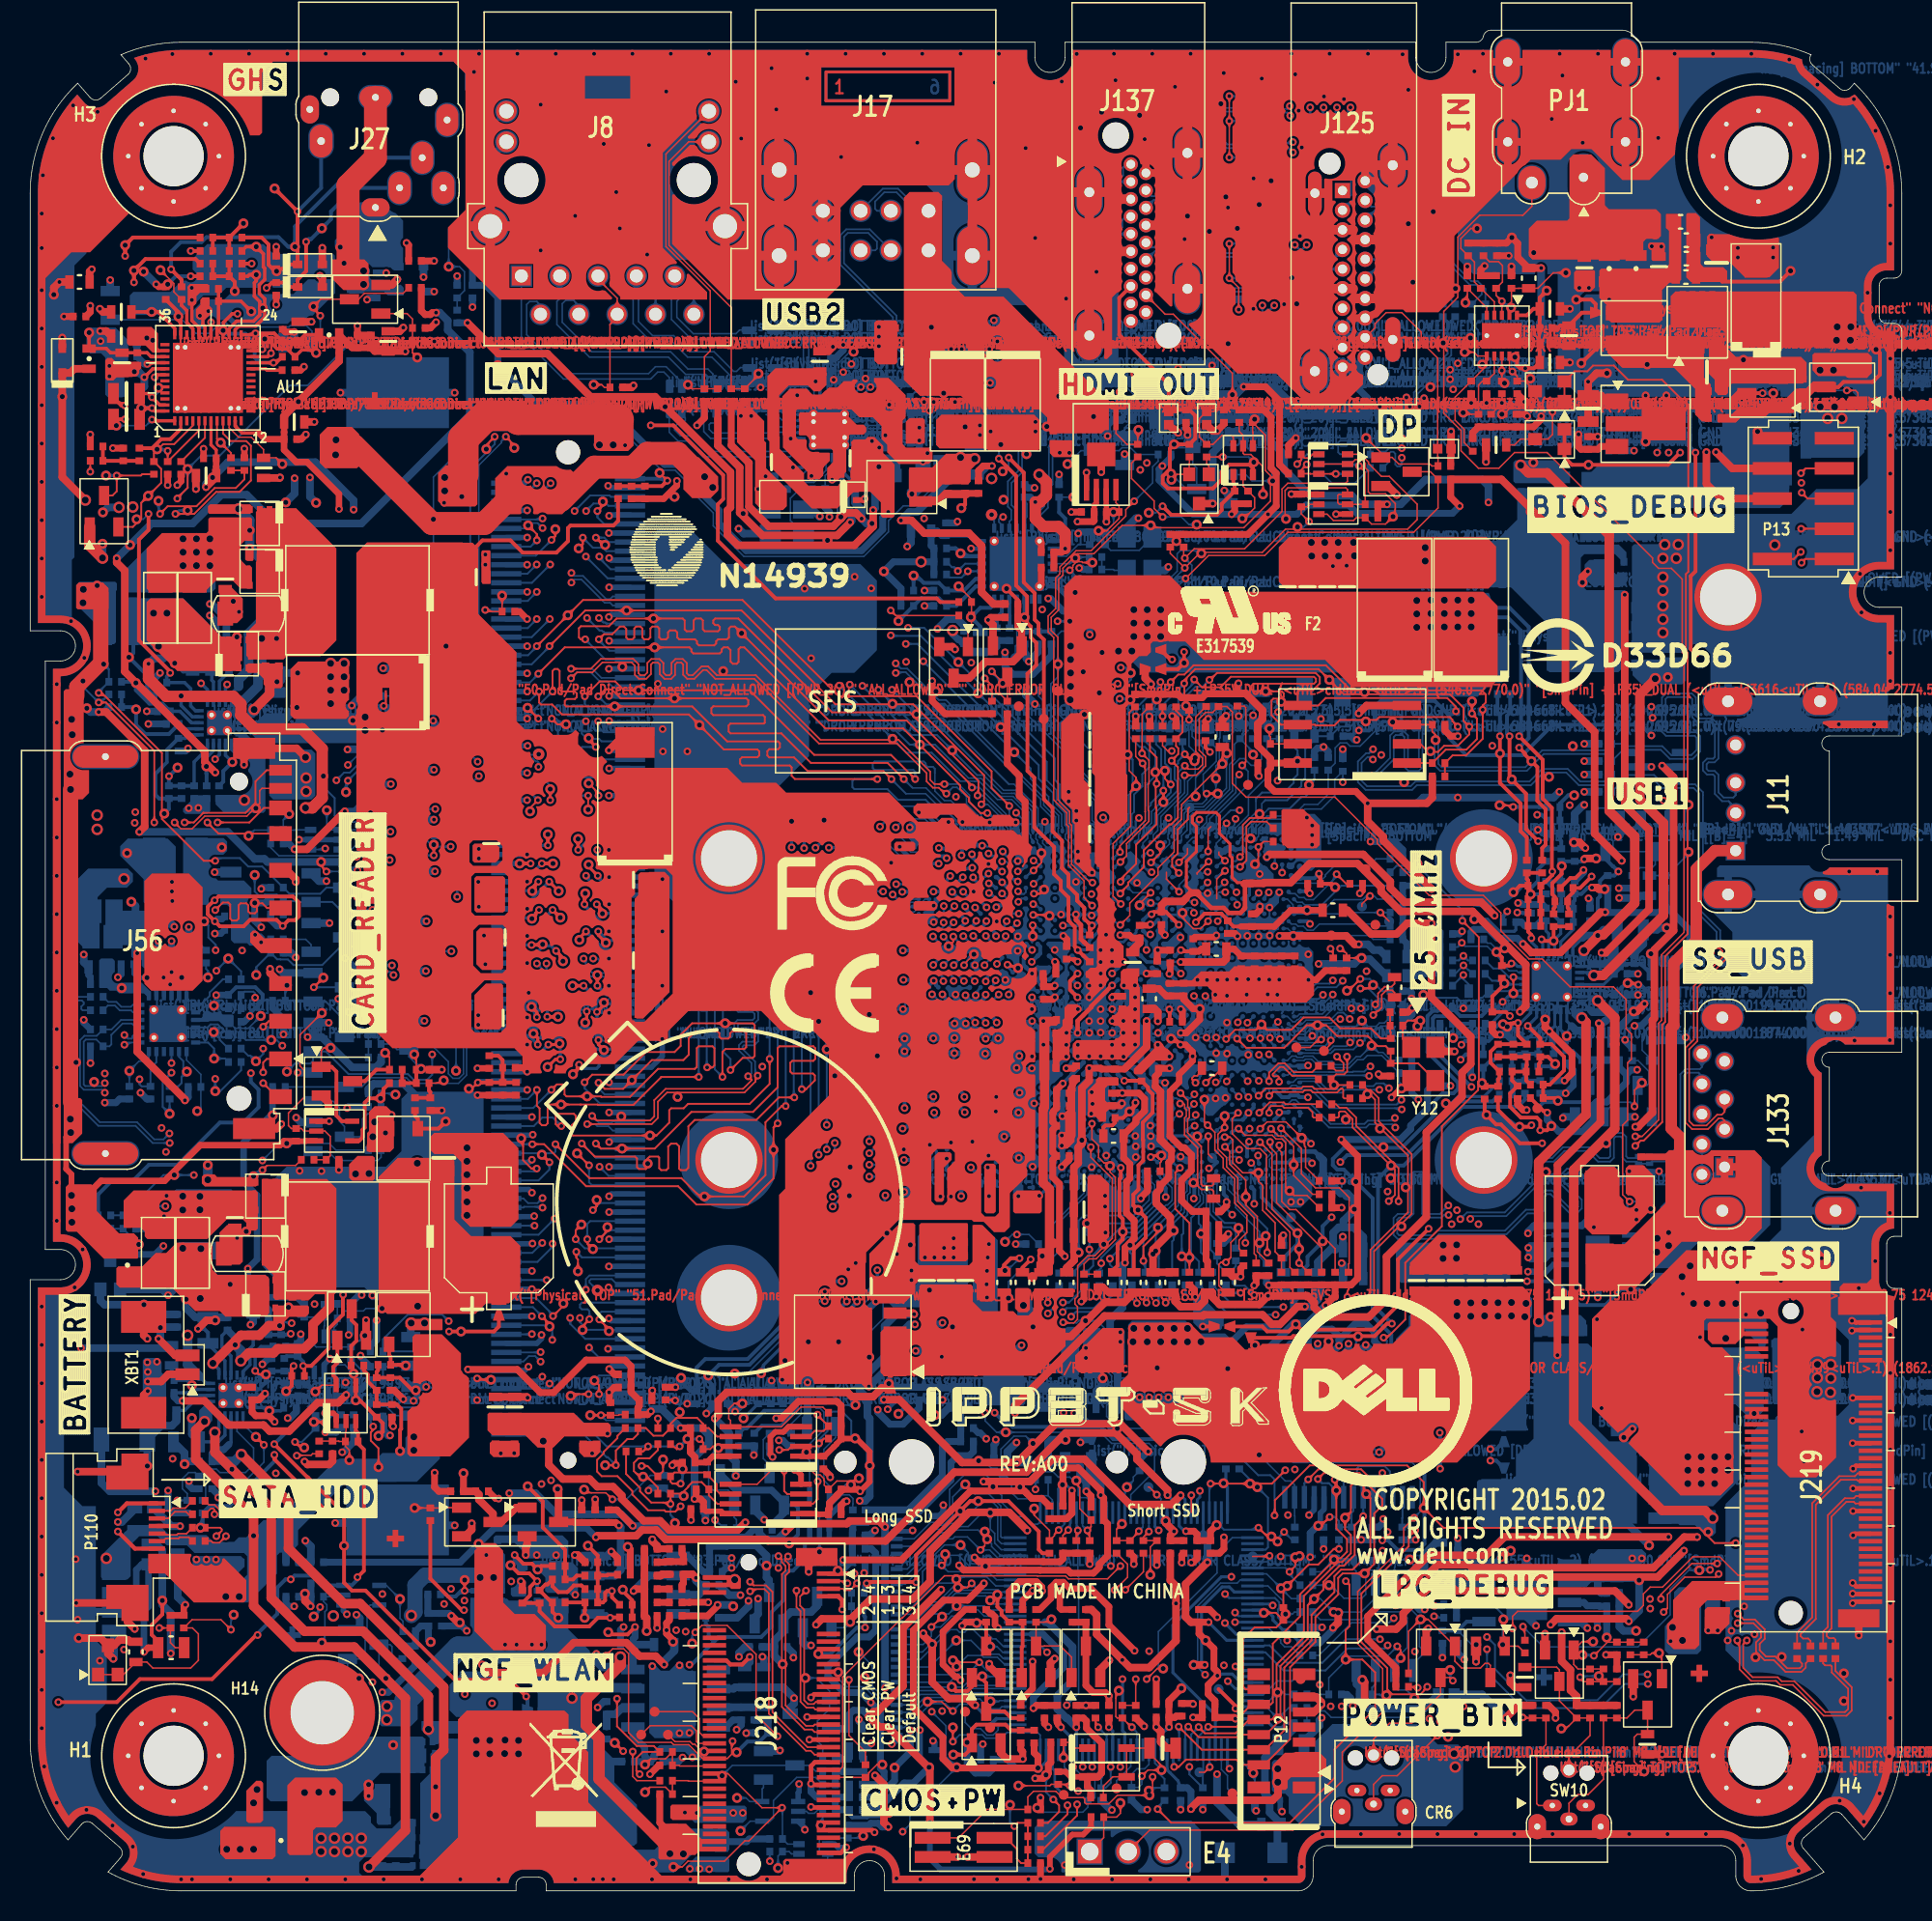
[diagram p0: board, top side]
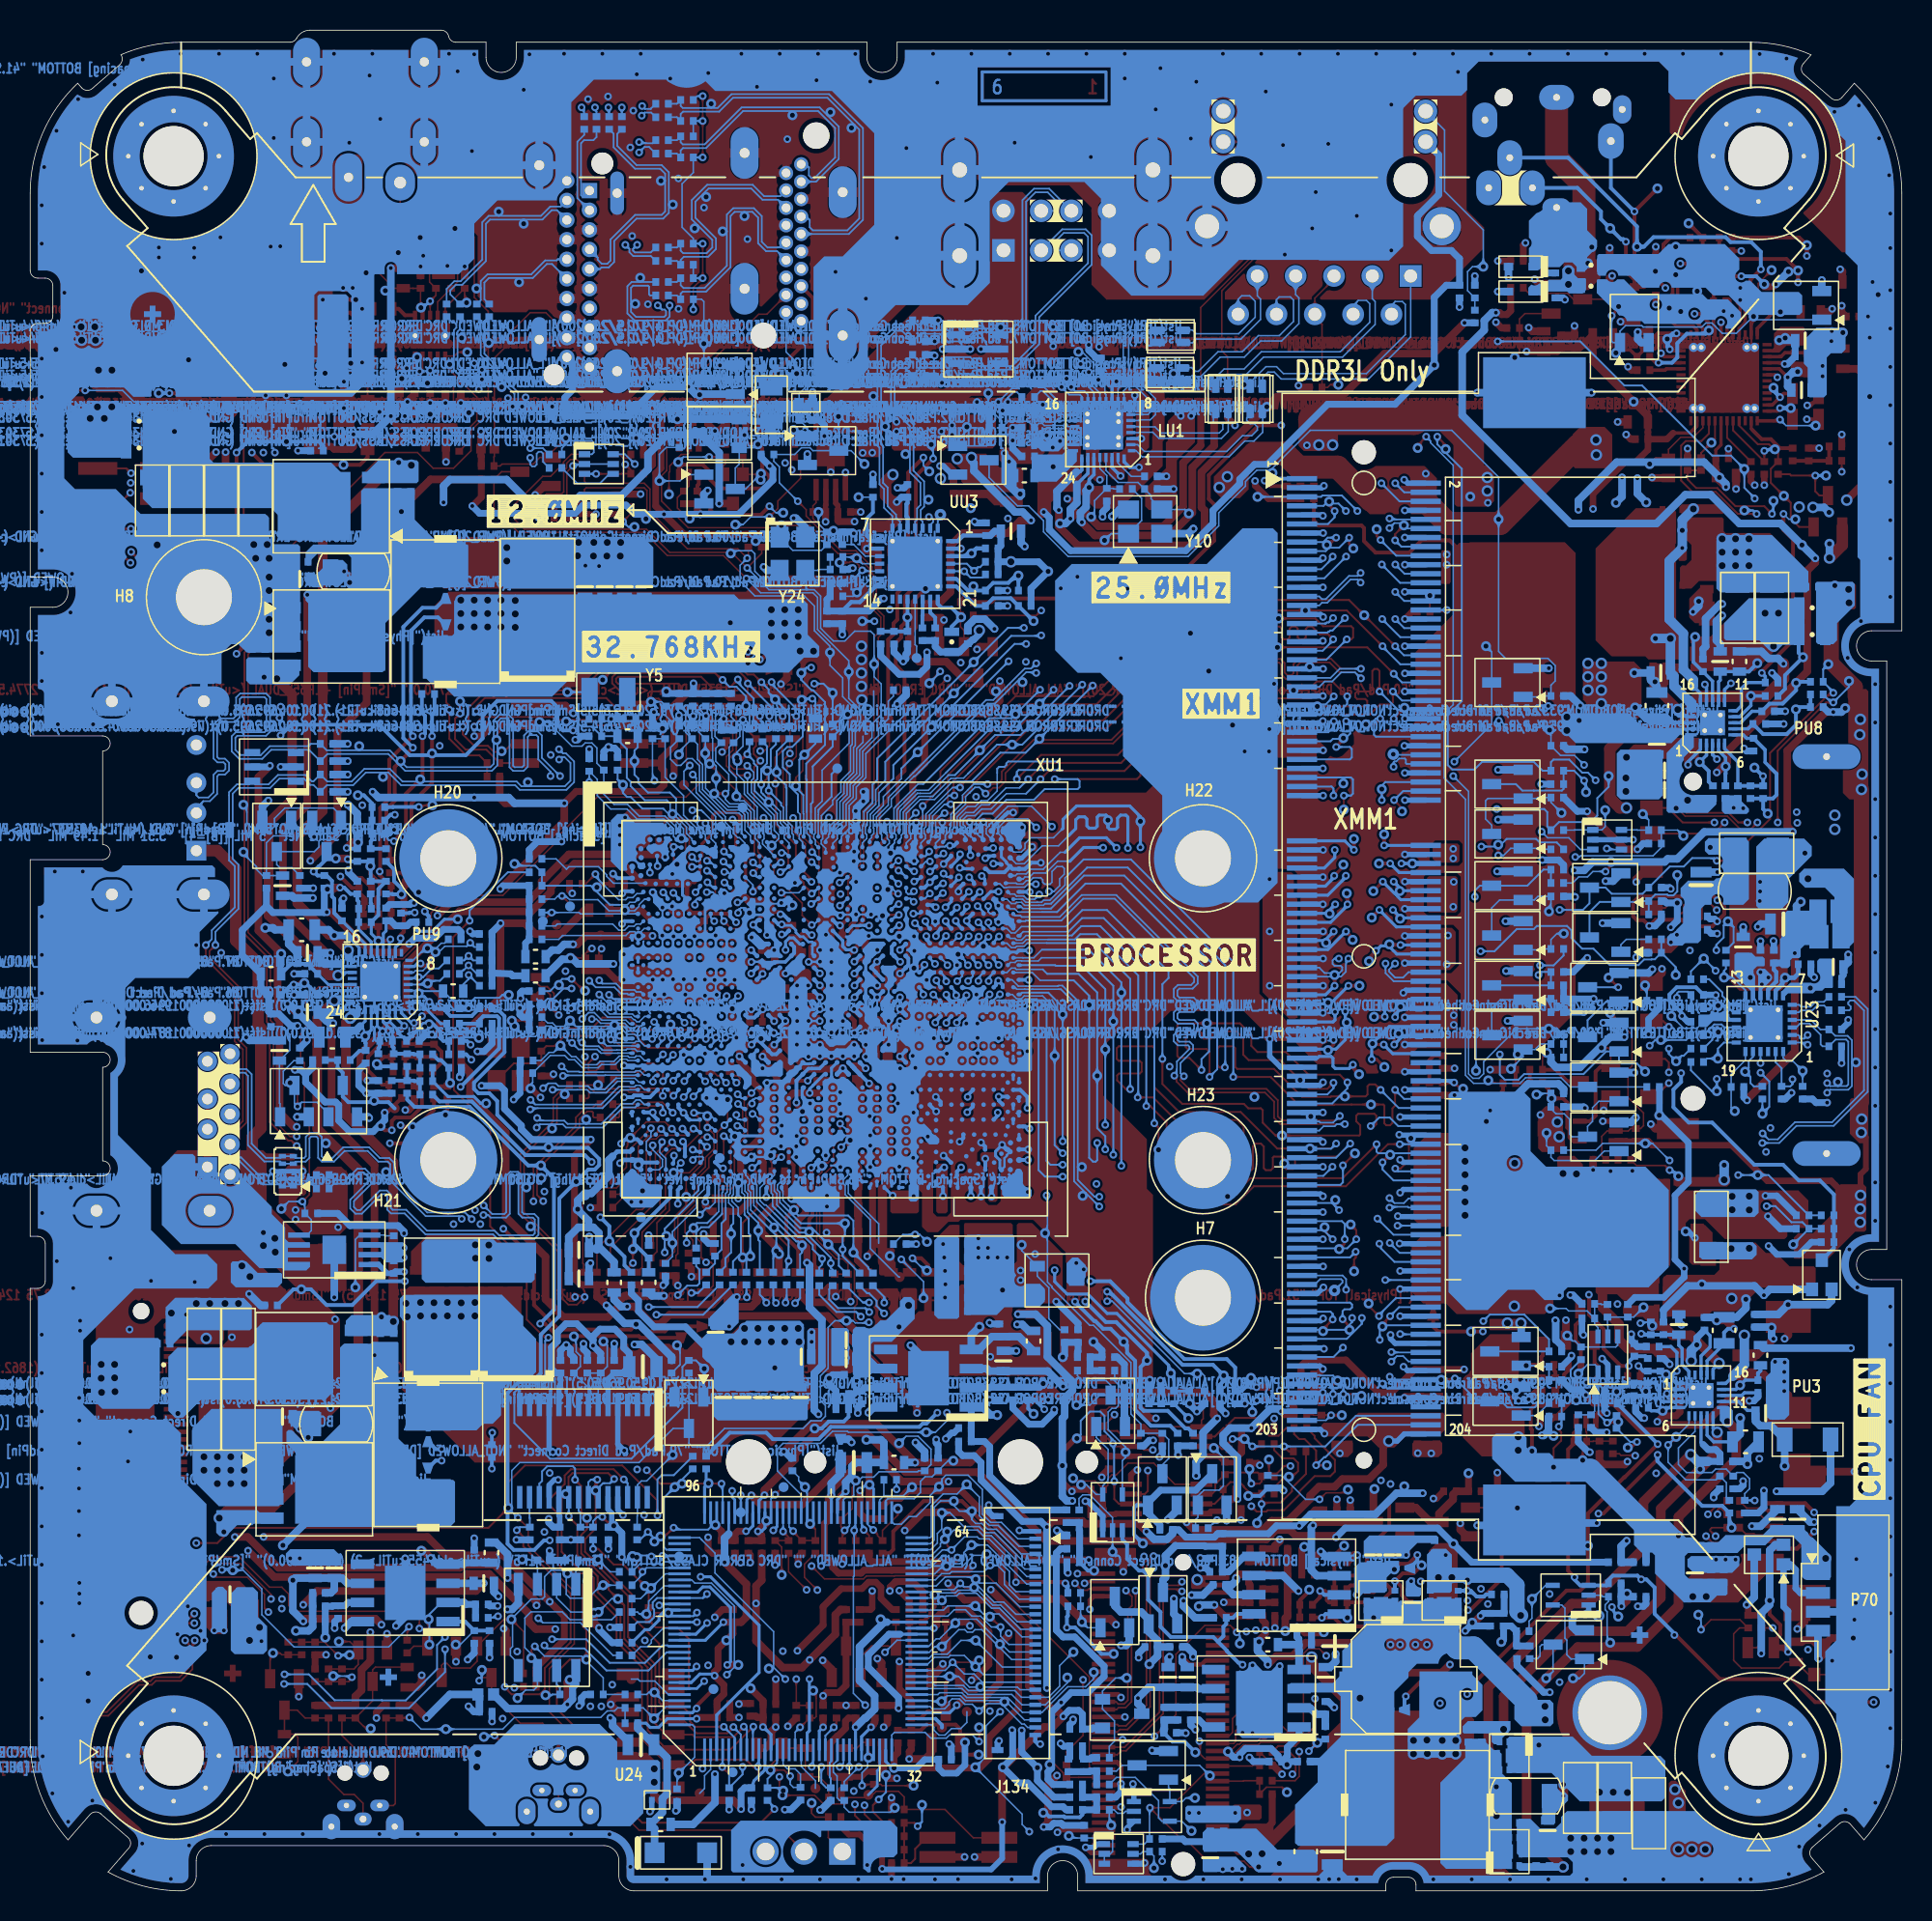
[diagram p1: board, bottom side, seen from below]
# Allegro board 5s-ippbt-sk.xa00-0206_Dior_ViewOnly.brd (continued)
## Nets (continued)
HDMI_POWER: J137.18 MCB1.1 VF1.1
HDMI_RT: MQ36.3 MR6.2 MR7.2 MR8.2 MR9.2 MR10.2 MR11.2 MR12.2 MR13.2
HDMI_TMDS_CLK_N: J137.12 M1C8.2 MR13.1
HDMI_TMDS_CLK_P: J137.10 M1C7.2 MR12.1
HDMI_TMDS_DATA0_N: J137.9 M1C2.2 MR7.1
HDMI_TMDS_DATA0_P: J137.7 M1C1.2 MR6.1
HDMI_TMDS_DATA1_N: J137.6 M1C4.2 MR9.1
HDMI_TMDS_DATA1_P: J137.4 M1C3.2 MR8.1
HDMI_TMDS_DATA2_N: J137.3 M1C6.2 MR11.1
HDMI_TMDS_DATA2_P: J137.1 M1C5.2 MR10.1
HDMI_TXN0: M1C2.1 XU1.AD2
HDMI_TXN1: M1C4.1 XU1.AF2
HDMI_TXN2: M1C6.1 XU1.AG1
HDMI_TXP0: M1C1.1 XU1.AD3
HDMI_TXP1: M1C3.1 XU1.AF3
HDMI_TXP2: M1C5.1 XU1.AG3
HOLD#: F3R3.2 F3U1.7
HPOUT1_JD: AR3.2 J27.4
HPOUT1_L: AU1.26 HR1.1
HPOUT1_R: AU1.27 HR2.1
HUB_RESET: DEC4.1 R18.1 R21.2 UU3.17
ICLK_DRAM_TERMN1: SR7.1 XU1.AF42
ICLK_DRAM_TERMN2: SR8.1 XU1.AH42
ICLK_ICOMP: SR32.2 XU1.AD14
ICLK_OSCIN: SC3.1 SR30.2 SR31.1 XU1.AH12
ICLK_OSCOUT: SC1.1 SR30.1 XU1.AH10 Y12.3
ICLK_RCOMP: SR33.2 XU1.AD13
ICLK_SATA_TERMN: SR79.2 XU1.BC10
ICLK_SATA_TERMP: SR80.2 XU1.BB10
ICLK_USB_TERMN1: SR96.1 XU1.D10
ICLK_USB_TERMN2: SR97.1 XU1.F10
ICLK_V1P35_S3: C62.1 C63.1 SL14.1 XU1.AG18 XU1.AJ19
ILIM: PR17.2 PR22.1 PU2.3
INTRUDER#: C149.1 E69.1 R250.1
INTRUDER#_S: R250.2 SR196.2 XU1.J24
JDREF: AR38.1 AU1.35
KSI0: J134.8 U24.58
KSI1: J134.7 U24.59
KSI2: J134.6 U24.60
KSI3: J134.5 U24.61
KSI4: J134.4 U24.62
KSI5: J134.3 U24.63
KSI6: J134.2 U24.64
KSI7: J134.1 U24.65
KSO0: J134.26 U24.36
KSO1: J134.25 U24.37
KSO2: J134.24 U24.38
KSO3: J134.23 U24.39
KSO4: J134.22 U24.40
KSO5: J134.21 U24.41
KSO6: J134.20 U24.42
KSO7: J134.19 U24.43
KSO8: J134.18 U24.44
KSO9: J134.17 U24.45
KSO10: J134.16 U24.46
KSO11: J134.15 U24.51
KSO12: J134.14 U24.52
KSO13: J134.13 U24.53
KSO14: J134.12 U24.54
KSO15: J134.11 U24.55
KSO16: J134.10 U24.56
KSO17: J134.9 U24.57
LAD0: P12.2 SR100.2 TPU1.26 U24.10
LAD1: P12.4 SR101.2 TPU1.23 U24.9
LAD2: P12.6 SR103.2 TPU1.20 U24.8
LAD3: P12.8 SR102.2 TPU1.17 U24.7
LAN_ACT#_R: J8.11 LANC1.1 LR62.1
LAN_ACTLED3#: LR62.2 LU1.25
LAN_CLKREQ: LU1.12 R93.1
LAN_HSON: C162.1 LU1.18
LAN_HSOP: C161.1 LU1.17
LAN_ISOLATEB: LU1.20 R95.1 R97.2
LAN_LED0_C: J8.13 LANC4.1 LR85.2
LAN_LED1_C: J8.14 LANC3.1 LR87.2
LAN_LINKLED0#: LR85.1 LU1.27
LAN_LINKLED1#: LR87.1 LU1.26
LAN_MDI0_N: LL10.4 LRN11.4 LU1.2
LAN_MDI0_N_C: J8.2 LL10.3 LRN11.3
LAN_MDI0_P: LL10.1 LRN11.2 LU1.1
LAN_MDI0_P_C: J8.1 LL10.2 LRN11.1
LAN_MDI1_N: LL11.4 LRN12.4 LU1.5
LAN_MDI1_N_C: J8.4 LL11.3 LRN12.3
LAN_MDI1_P: LL11.1 LRN12.2 LU1.4
LAN_MDI1_P_C: J8.3 LL11.2 LRN12.1
LAN_MDI2_N: LL12.4 LRN13.4 LU1.7
LAN_MDI2_N_C: J8.8 LL12.3 LRN13.3
LAN_MDI2_P: LL12.1 LRN13.2 LU1.6
LAN_MDI2_P_C: J8.7 LL12.2 LRN13.1
LAN_MDI3_N: LL13.4 LRN14.4 LU1.10
LAN_MDI3_N_C: J8.10 LL13.3 LRN14.3
LAN_MDI3_P: LL13.1 LRN14.2 LU1.9
LAN_MDI3_P_C: J8.9 LL13.2 LRN14.1
LAN_REGOUT: C160.1 LU1.24 R92.2
LAN_REGOUT_R: C155.1 C156.1 C157.1 C158.1 C159.1 LU1.3 LU1.8 LU1.22 LU1.30 R92.1
LAN_RXN3: C162.2 XU1.AP7
LAN_RXP3: C161.2 XU1.AP9
LAN_TXN3: C8.2 LU1.14
LAN_TXP3: C9.2 LU1.13
LANWAKE: LQ3.1 LU1.21 R96.1
LDO-CAP: AC60.1 AC61.1 AU1.40
LFRAME#: P12.10 SR104.2 TPU1.22 U24.6
LPC_AD0_R: SR100.1 XU1.BH16
LPC_AD1_R: SR101.1 XU1.BJ17
LPC_AD2_R: SR103.1 XU1.BJ13
LPC_AD3_R: SR102.1 XU1.BG14
LPC_CLK1: R30.1 SR188.2 TPR3.2
LPC_CLK_EC: SR659.1 U24.13
LPC_CLK_TPM: CB2.1 TPR3.1 TPU1.21
LPC_FRAME#_R: SR104.1 XU1.BG17
LPC_RCOMP: SR105.1 XU1.BF18
LPC_V1P8V3P3_S3: C70.1 SL4.2 XU1.AM27 XU1.AN24
LPCCLK0: SR106.2 SR659.2
LPCCLK0_R: SR106.1 XU1.BG15
LPCCLK1_R: SR188.1 XU1.BH14
M_CHA_BA0: XMM1.109 XU1.K47
M_CHA_BA1: XMM1.108 XU1.K44
M_CHA_BA2: XMM1.79 XU1.D52
M_CHA_CAS#: XMM1.115 XU1.M44
M_CHA_CKE0: XMM1.73 XU1.C47
M_CHA_CKE1: XMM1.74 XU1.F44
M_CHA_CLK0: XMM1.101 XU1.M50
M_CHA_CLK0#: XMM1.103 XU1.M48
M_CHA_CLK1: XMM1.102 XU1.P50
M_CHA_CLK1#: XMM1.104 XU1.P48
M_CHA_CS#0: XMM1.114 XU1.P44
M_CHA_CS#1: XMM1.121 XU1.P45
M_CHA_DM0: XMM1.11 XU1.G36
M_CHA_DM1: XMM1.28 XU1.B36
M_CHA_DM2: XMM1.63 XU1.F38
M_CHA_DM3: XMM1.46 XU1.B42
M_CHA_DM4: XMM1.136 XU1.P51
M_CHA_DM5: XMM1.153 XU1.V42
M_CHA_DM6: XMM1.170 XU1.Y50
M_CHA_DM7: XMM1.187 XU1.Y52
M_CHA_DQ0: XMM1.5 XU1.M36
M_CHA_DQ1: XMM1.7 XU1.J36
M_CHA_DQ2: XMM1.17 XU1.P40
M_CHA_DQ3: XMM1.15 XU1.M40
M_CHA_DQ4: XMM1.4 XU1.P36
M_CHA_DQ5: XMM1.6 XU1.N36
M_CHA_DQ6: XMM1.18 XU1.K40
M_CHA_DQ7: XMM1.16 XU1.K42
M_CHA_DQ8: XMM1.22 XU1.B32
M_CHA_DQ9: XMM1.24 XU1.C32
M_CHA_DQ10: XMM1.35 XU1.C36
M_CHA_DQ11: XMM1.34 XU1.A37
M_CHA_DQ12: XMM1.23 XU1.C33
M_CHA_DQ13: XMM1.21 XU1.A33
M_CHA_DQ14: XMM1.36 XU1.C37
M_CHA_DQ15: XMM1.33 XU1.B38
M_CHA_DQ16: XMM1.56 XU1.F36
M_CHA_DQ17: XMM1.57 XU1.G38
M_CHA_DQ18: XMM1.67 XU1.F42
M_CHA_DQ19: XMM1.70 XU1.J42
M_CHA_DQ20: XMM1.59 XU1.G40
M_CHA_DQ21: XMM1.58 XU1.C38
M_CHA_DQ22: XMM1.68 XU1.G44
M_CHA_DQ23: XMM1.69 XU1.D42
M_CHA_DQ24: XMM1.41 XU1.A41
M_CHA_DQ25: XMM1.42 XU1.C41
M_CHA_DQ26: XMM1.53 XU1.A45
M_CHA_DQ27: XMM1.51 XU1.B46
M_CHA_DQ28: XMM1.39 XU1.C40
M_CHA_DQ29: XMM1.40 XU1.B40
M_CHA_DQ30: XMM1.50 XU1.B48
M_CHA_DQ31: XMM1.52 XU1.B47
M_CHA_DQ32: XMM1.130 XU1.K52
M_CHA_DQ33: XMM1.132 XU1.K51
M_CHA_DQ34: XMM1.143 XU1.T52
M_CHA_DQ35: XMM1.141 XU1.T51
M_CHA_DQ36: XMM1.131 XU1.L51
M_CHA_DQ37: XMM1.129 XU1.L53
M_CHA_DQ38: XMM1.142 XU1.R51
M_CHA_DQ39: XMM1.140 XU1.R53
M_CHA_DQ40: XMM1.147 XU1.T47
M_CHA_DQ41: XMM1.149 XU1.T45
M_CHA_DQ42: XMM1.158 XU1.Y40
M_CHA_DQ43: XMM1.160 XU1.V41
M_CHA_DQ44: XMM1.146 XU1.T48
M_CHA_DQ45: XMM1.148 XU1.T50
M_CHA_DQ46: XMM1.159 XU1.Y42
M_CHA_DQ47: XMM1.157 XU1.AB40
M_CHA_DQ48: XMM1.164 XU1.V45
M_CHA_DQ49: XMM1.166 XU1.V47
M_CHA_DQ50: XMM1.175 XU1.AD48
M_CHA_DQ51: XMM1.177 XU1.AD50
M_CHA_DQ52: XMM1.163 XU1.V48
M_CHA_DQ53: XMM1.165 XU1.V50
M_CHA_DQ54: XMM1.176 XU1.AB44
M_CHA_DQ55: XMM1.174 XU1.Y45
M_CHA_DQ56: XMM1.182 XU1.V52
M_CHA_DQ57: XMM1.181 XU1.W51
M_CHA_DQ58: XMM1.192 XU1.AC53
M_CHA_DQ59: XMM1.194 XU1.AC51
M_CHA_DQ60: XMM1.183 XU1.W53
M_CHA_DQ61: XMM1.180 XU1.Y51
M_CHA_DQ62: XMM1.193 XU1.AD52
M_CHA_DQ63: XMM1.191 XU1.AD51
M_CHA_DQS0: XMM1.12 XU1.J38
M_CHA_DQS0#: XMM1.10 XU1.K38
M_CHA_DQS1: XMM1.29 XU1.C35
M_CHA_DQS1#: XMM1.27 XU1.B34
M_CHA_DQS2: XMM1.64 XU1.D40
M_CHA_DQS2#: XMM1.62 XU1.F40
M_CHA_DQS3: XMM1.47 XU1.B44
M_CHA_DQS3#: XMM1.45 XU1.C43
M_CHA_DQS4: XMM1.137 XU1.N53
M_CHA_DQS4#: XMM1.135 XU1.M52
M_CHA_DQS5: XMM1.154 XU1.T42
M_CHA_DQS5#: XMM1.152 XU1.T44
M_CHA_DQS6: XMM1.171 XU1.Y47
M_CHA_DQS6#: XMM1.169 XU1.Y48
M_CHA_DQS7: XMM1.188 XU1.AB52
M_CHA_DQS7#: XMM1.186 XU1.AA51
M_CHA_MAA0: XMM1.98 XU1.K45
M_CHA_MAA1: XMM1.97 XU1.H47
M_CHA_MAA2: XMM1.96 XU1.L41
M_CHA_MAA3: XMM1.95 XU1.H44
M_CHA_MAA4: XMM1.92 XU1.H50
M_CHA_MAA5: XMM1.91 XU1.G53
M_CHA_MAA6: XMM1.90 XU1.H49
M_CHA_MAA7: XMM1.86 XU1.D50
M_CHA_MAA8: XMM1.89 XU1.G52
M_CHA_MAA9: XMM1.85 XU1.E52
M_CHA_MAA10: XMM1.107 XU1.K48
M_CHA_MAA11: XMM1.84 XU1.E51
M_CHA_MAA12: XMM1.83 XU1.F47
M_CHA_MAA13: XMM1.119 XU1.J51
M_CHA_MAA14: XMM1.80 XU1.B49
M_CHA_MAA15: XMM1.78 XU1.B50
M_CHA_ODT0: XMM1.116 XU1.T41
M_CHA_ODT1: XMM1.120 XU1.P42
M_CHA_RAS#: XMM1.110 XU1.M45
M_CHA_WE#: XMM1.113 XU1.H51
ME_DISABLE#: Q7.1 R7.1 SR49.1
MIC2-L: AC1.1 AU1.47
MIC2-R: AC2.1 AU1.48
MIC2-VREFOL: AU1.1 HR4.2
MIC2-VREFOR: AU1.30 HR3.2
MIC-CAP: AC42.1 AU1.36
MMC1_RCOMP: SR627.1 XU1.AY18
MQ5_B: MQ5.1 SR662.2
MQ5_C: MQ5.3 Q9414.1 SR28.2
MQ7_B: MQ7.1 R60297.2
MQ9_B: MQ9.1 R60298.2
MQ9_G: MQ34.1 MR1.2
MQ10_G: MQ33.1 MQ34.3 MR2.2
MQ23_B: MQ23.1 R60304.2
MQ25_G: MQ25.1 Q9.3 R8.2
MQ31_G: MQ31.1 MQ32.3 SC65.1 SR670.2
MQ32_B: MQ32.1 R60306.2
NGFF_WIFI_RST#_R: J218.52 WC14.1 WR36.1
PCBEEP: AU1.2 C174.2
PCBEEP_C: AC63.2 C174.1 R109.2 SR134.2
PCH_WIFI_RF_KILL#: U24.97 WR35.2
PCIE_CLKREQ0: SR653.2 ST69.1 XU1.BG3
PCIE_CLKREQ2: SR655.2 ST70.1 XU1.BG5
PCIE_CLKREQ3: SR656.2 ST71.1 XU1.BE3
PCIE_RCOMP_N: SR84.2 XU1.AP13
PCIE_RCOMP_P: SR84.1 XU1.AP14
PCIE_RST#: C163.1 C302.2 LU1.19 SR35.2 U23.23
PCIE_TXN1_WLAN: C6.2 XU1.AV4
PCIE_TXN2_CR: SC9.2 XU1.AT6
PCIE_TXN3_LAN: C8.1 XU1.AP4
PCIE_TXP1_WLAN: C7.2 XU1.AV6
PCIE_TXP3_CR: SC10.2 XU1.AT7
PCIE_TXP3_LAN: C9.1 XU1.AP6
PCIE_V1P0_S3: C44.1 C66.1 SL9.1 SL15.2 XU1.AK18 XU1.AM18 XU1.AM21 XU1.AN18 XU1.AN19 XU1.AN21
PCIE_WAKE#: LQ3.3 Q9416.1 R60302.1
PCIE_WAKE#_WLAN: Q3.4 R60309.1 WR84.1
PCU_SMB_ALERT#: SR640.2 XU1.BG11
PCU_SMB_CLK: SR110.2 U3.3 U4.3 XU1.BH10
PCU_SMB_DATA: SR111.2 U3.2 U4.2 XU1.BG12
PDA_TEST1: ST72.1 XU1.BH30
PDA_TEST2: ST73.1 XU1.BG30
PLT_THERMAL_EC: O2R243.1 PRT4.1 U24.70
PLTRST#: CB3.1 Q9414.3 SC24.1 SR29.2 SR35.1 TPU1.16 U24.22 WR36.2
PM_CLKRUN#: SR108.2 U24.93
PM_PWRBTN#: Q2.1 U24.76
PM_PWRBTN#_1P8VSB: C941163.1 Q1.3 SR37.2 XU1.J26
PM_PWRBTN#_G: Q1.1 Q2.3 R4.1
PMC_ACPRESENT: SR641.2 XU1.D20
PMC_BAT_LOW#: SR642.2 XU1.K26
PMC_CORE_PWROK: SC23.1 SR41.1 SR152.2 XU1.B7
PMC_CORE_PWROK_EC: SR152.1 U24.124
PMC_PLTRST#_1P8V: SR662.1 XU1.F20
PMC_RSMRST#: C941162.1 R212.2 SR46.1 XU1.B10
PMC_RSMRST#_EC: R212.1 U24.112
PMC_SUS_STAT#: ST29.1 XU1.G18
PMC_SUSCLK: R2.1 SC27.1 XU1.G24
PMC_WAKE_PCIE#: Q3.3 Q9416.3 SR36.2 XU1.F26
PMU_SLP_S0IX#_1P8V: ST78.1 XU1.F18
PMU_SLP_S3: MQ6.1 MQ7.3 SC7.1 SR65.2
PMU_SLP_S3#_1P8V: R60297.1 SR665.2 XU1.D22
PMU_SLP_S4: MQ8.1 MQ9.3 SC8.1 SR71.2
PMU_SLP_S4#_1P8V: R60298.1 SR664.2 XU1.F22
PQ15_G: PQ17.1 PR91.2
PQ16_2: PQ18.2 PR95.2
PQ16_4: PQ18.4 PR93.1
PQ17_D: PQ19.3 PR94.2
PQ17_G: PQ18.5 PQ19.1
PQ28_G: PQ14.3 PR81.2
PQ31_G: PQ8.1 PR67.2
PQ32_2: PC67.1 PQ11.2 PR76.2 PR80.2
PQ32_4: PQ11.4 PR72.1
PQ33_D: PQ13.3 PR75.2
PQ33_G: PQ11.5 PQ13.1
PQ34_2: PC66.1 PQ10.2 PR74.2 PR77.2
PQ34_4: PQ10.4 PR71.1
PQ35_D: PQ12.3 PR73.2
PQ35_G: PQ10.5 PQ12.1
PQ36_G: PQ20.1 PR100.2
PQ37_2: PQ21.2 PR104.2
PQ37_4: PQ21.4 PR102.1
PQ38_D: PQ22.3 PR103.2
PQ38_G: PQ21.5 PQ22.1
PQ79_G: PQ9.1 PR69.2
PQ710_G: PC136.1 PQ41.1 PR186.2
PQ711_G: PQ32.1 PQ41.3 PR182.2
PQ9546_G: PQ28.1 PR139.2 PR141.2
PQ9550_G: PQ43.1 PQ44.3 PR196.2
PQ9551_G: PC141.1 PQ44.1 PR201.2
PQ9552_D: PQ16.3 PR84.2
PQ9552_G: PQ15.5 PQ16.1
PQ9553_2: PQ15.2 PR86.2
PQ9553_4: PQ15.4 PR83.1
PQ9557_G: PQ25.1 PR131.2
PROCHOT#: PD3.1 PD3.2 R214.2 R60299.1
PROCHOT#_EC: R214.1 U24.99
PROCHOT#_VR: PR192.2 PU9.6 R60226.1
PROCHOT_CPU#: MQ25.3 R9.2 R60226.2 XU1.C24
PROHOT_R#: PC13.1 PD3.3 PR15.2 PU2.9
PU12_ALERT#: PR200.2 PU9.4
PU12_ISEN2: PR233.1 PU9.8
PU12_SCLK: PR198.2 PU9.3
PU12_SDA: PR202.2 PU9.5
PWR_LED: R330.2 R368.2 R370.2 U24.25
PWR_LED#: R332.2 R357.2 R371.2 U24.24
PWR_LED+: CB10.1 Q30.3 R159.2 R160.2 SW10.L1
PWR_LED-: CB12.1 Q31.3 R169.2 R170.2 SW10.L2
PWR_SW#: R216.2 U24.125
PWRBTN#: O2C53.1 O2R132.2 R215.2 R216.1 SW10.1
Q7_E: Q7.2 SR81.2
Q9_B: Q9.1 R60299.2
Q32_B: Q32.1 Q33.3 R182.2
Q32_C: CR6.L2 Q32.3
Q33_B: Q33.1 R184.2
Q39G: Q39.1 R60208.2 R60209.2
Q41_B: Q41.1 SR663.2
Q41_C: Q41.3 Q9415.1 R252.2
R_HPOUT_L: AC3.1 AD1.1 AR6.2 J27.2
R_HPOUT_R: AC4.1 AD2.1 AR7.2 J27.3
REAR_USB_OC#: R244.1 U18.5
REGREF: AC46.1 AU1.10
RESET: PC14.1 PD2.3 PQ3.1 PR16.2 PR21.1
REVISION_ID_0: SR156.1 SR159.1 XU1.C17
REVISION_ID_1: SR157.1 SR158.1 XU1.C16
RING2: AQ2.3 AR36.2 AU1.31 L3.1
RING2_B: AC5.1 AD3.1 J27.6 L3.2
RREF: R200.2 U23.8
RSET: LR2.1 LU1.31
RST_KB#: ST25.1 U24.4
RTC_EXTPAD: SC4.1 XU1.B8
RTCRST#: C240.1 R188.2 SR674.2 XU1.C11
S4_DAUL_PWRGD: R213.1 U24.96
SATA_GP[0]: SR77.2 XU1.BA12
SATA_GP[1]: SR78.2 XU1.AY14
SATA_RCOMP_N: SR76.1 XU1.AT18
SATA_RCOMP_P: SR76.2 XU1.AU18
SATA_RXN0: T1C15.1 XU1.AV16
SATA_RXN0_C: J219.43 SSC22.2
SATA_RXN1: SSC22.1 XU1.BA16
SATA_RXN1_C: P110.5 T1C15.2
SATA_RXP0: T1C14.1 XU1.AU16
SATA_RXP0_C: J219.41 SSC21.2
SATA_RXP1: SSC21.1 XU1.AY16
SATA_RXP1_C: P110.6 T1C14.2
SATA_TXN0: T1C1.1 XU1.BG7
SATA_TXN0_C: J219.47 SSC19.2
SATA_TXN1: SSC19.1 XU1.BF10
SATA_TXN1_C: P110.3 T1C1.2
SATA_TXP0: T1C13.1 XU1.BF6
SATA_TXP0_C: J219.49 SSC20.2
SATA_TXP1: SSC20.1 XU1.BD10
SATA_TXP1_C: P110.2 T1C13.2
SCE#: R221.1 R227.2 U25.1
SCE#_EC: R221.2 U24.101
SCK: R222.1 U25.6
SCK_EC: R222.2 U24.105
SD3_RCOMP: SR626.1 XU1.BF26
SD_CD#: J56.CD U23.21
SDATA_IN_R: AR1.2 AU1.8
SENSE_B: AR3.1 AU1.33
SERIRQ: HC14.1 R60217.2 TPR4.1 U24.5
SERIRQ_A3: R60216.2 U1.3
SERIRQ_B3: R60217.1 U1.4
SERIRQ_PCH: R60216.1 SR107.2
SERIRQ_R: HC13.1 SR107.1 XU1.BG13
SERIRQ_TPM: TPR4.2 TPU1.27
SI: R224.1 U25.5
SI_EC: R224.2 U24.102
SIO_LED1_B: Q30.1 R330.1 R370.1
SIO_LED2_B: Q31.1 R332.1 R371.1
SLEEVE: AQ1.3 AR5.2 AU1.32 L4.1
SLEEVE_B: AC6.1 AD4.1 J27.1 L4.2
SLP_S0IX#: ST79.1 U24.100
SLP_S3#: HC11.1 MQ6.3 PR151.1 SR66.2 U24.107
SLP_S4#: HC12.1 MQ8.3 PR154.1 SR72.2 U24.21
SMB_CLK_M: SR112.2 SR116.1 SR118.1 U3.6 XMM1.202
SMB_CLK_WLAN: SR116.2 SR122.2
SMB_DATA_M: SR114.2 SR115.1 SR117.1 U3.7 XMM1.200
SMB_DATA_WLAN: SR115.2 SR121.2
SML0_CLK_EC: SR118.2 SR120.2 SR122.1 U4.6 U24.110
SML0_CLK_USB: R6.1 U24.115 UU3.25
SML0_DATA_EC: SR117.2 SR119.2 SR121.1 U4.7 U24.111
SML0_DATA_USB: R60310.1 U24.116 UU3.24
SO: R243.1 U25.2
SO_EC: R243.2 U24.103
SOC_RTCX1: SC6.1 SR63.1 SR64.1 XU1.C9
SOC_RTCX2: SC5.1 SR63.2 XU1.A9 Y5.1
SOC_THERMAL: O2R244.1 PRT5.1 U24.72
SP1: J56.P8 R199.1
SP1_L: R199.2 U23.12
SP2: J56.P7 SR151.1
SP2_L: SR151.2 U23.13
SP3: C248.1 J56.P5 SR150.1
SP3_L: SR150.2 U23.14
SP4: J56.P2 SR149.1
SP4_L: SR149.2 U23.16
SP5: J56.P1 SR147.1
SP5_L: SR147.2 U23.17
SP6: J56.P9 SR148.1
SP6_L: SR148.2 U23.18
SP7: J56.WP R197.1
SP7_L: R197.2 U23.20
SPI_CLK: F3U1.6 P13.7 SR54.2
SPI_CLK_R: SR54.1 XU1.C22
SPI_CS#: F3R1.2 P13.1 R153.1 SR48.2
SPI_CS#_HEADER: F3U1.1 P13.2 R153.2
SPI_CS#_R: SR48.1 XU1.C23
SPI_HOLD#: R230.2 U25.7
SPI_MISO: F3U1.2 P13.5 SR50.2
SPI_MISO_R: SR50.1 XU1.B22
SPI_MOSI: F3U1.5 P13.3 SR52.2
SPI_MOSI_R: SR52.1 XU1.A21
SPI_WP#: F3R2.2 F3U1.3
SPKR_C: R109.1 XU1.BH12
SRTCRST#: C1.1 R60214.2 SR673.2 XU1.C12
SUS_PWRGD: PC32.1 PR34.2 PR52.2 PR61.2 PU3.7 R207.2
SUS_PWRGD_EC_C: R207.1 U24.67
SUSB#_PWR: O2R249.2 PR80.1
SUSB_EC#: O2R249.1 R233.1 U24.83
SUSC#_PWR: O2R250.2 PR77.1
SUSC_EC#: O2R250.1 R234.1 U24.82
SUSCLK: J218.50 J219.68 R3.2 SR15.2
SUSPWRDNACK: MQ22.3 SC67.1 SR624.2 U24.95
SUSPWRDNACK_1P8V: R60304.1 SC33.1 SR34.2 XU1.D26
SUSPWRDNACK_MOS: MQ22.1 MQ23.3 SC36.1 SR625.2
SVID_V1P0_S3: C14.1 SL2.1 XU1.V32
U1_OE: SR67.2 SR68.2 U1.5
U1_VCCA: C2.1 R60307.2 U1.1
U1_VCCB: C3.1 R60308.2 SR67.1 U1.6
U2HUB_OVCUR3: R10.1 UU3.20
U2HUB_OVCUR4: R11.1 UU3.19
U2HUB_PSELF: R16.1 R19.2 UU3.22
U2HUB_RREF: R22.1 UU3.8
U3_EN: SR113.2 U3.5
U4_EN: SR109.2 U4.5
U14_EN: U14.4 UR3.2
U18_EN: U18.4 UR7.2
UNCORE_V1P0_S0IX: C37.1 C38.1 C39.1 C40.1 C41.1 SL7.1 XU1.AF21 XU1.AG21 XU1.AN29 XU1.AN30 XU1.V24 XU1.Y22 XU1.Y24
UNCORE_V1P0_S3: C42.1 C43.1 SL8.1 XU1.AF16 XU1.AF18 XU1.G1 XU1.Y18
UNCORE_V1P8_G3: C30.1 SL6.2 XU1.AA18 XU1.U24
USB3_REXT[0]: SR91.1 XU1.M12
USB3_RXN0: J133.5 UU1.5 UU1.6 XU1.E3
USB3_RXP0: J133.6 UU1.4 UU1.7 XU1.D4
USB3_SS_TXN0_C: J133.8 UC2.2 UU1.2 UU1.9
USB3_SS_TXP0_C: J133.9 UC1.2 UU1.1 UU1.10
USB3_TXN0: UC2.1 XU1.K7
USB3_TXP0: UC1.1 XU1.K6
USB_HSIC_RCOMP: SR172.1 XU1.A7
USB_HSIC_V1P2_G3: C941137.1 SL16.2 XU1.V18
USB_OC0#: R244.2 SR95.2 XU1.C20
USB_OC1#: SR94.2 U14.5 UR1.2 XU1.B20
USB_PLL_MON: SR193.1 XU1.M13
USB_RCOMP: SR98.1 XU1.C7 XU1.D6
USB_V1P0_S3: C45.1 C46.1 SL11.1 XU1.M14 XU1.U18 XU1.U19
USBN0: J133.2 UC13.1 UU2.1 XU1.K16
USBN1: J11.2 UC15.1 UU2.3 XU1.G14
USBN3_HUB: UU3.1 XU1.H10
USBN_HUB1: J17.2 U19.3 UC6.1 UU3.3
USBN_HUB2: J17.6 U19.6 UC9.1 UU3.6
USBP0: J133.3 UC12.1 UU2.6 XU1.M16
USBP1: J11.3 UC14.1 UU2.4 XU1.J14
USBP3_HUB: UU3.2 XU1.K10
USBP_HUB1: J17.3 U19.4 UC7.1 UU3.4
USBP_HUB2: J17.7 U19.1 UC8.1 UU3.7
VGA_V1P0_S3: C15.1 SL1.1 XU1.BJ6
VGA_V1P35_S3_F1: C64.1 C65.1 SL13.1 XU1.BD1
VNN_PWRGD: PQ32.3 PR183.2 PR184.1 ST4.1
VNN_PWRGDG: PR184.2 PR190.1 PU9.27
VR_SVID_ALERT#: PR194.2 PR200.1 SR43.2
VR_SVID_ALERT#_R: SR43.1 XU1.B24
VR_SVID_CLK: PR195.2 PR198.1 XU1.C25
VR_SVID_DATA: PR193.2 PR202.1 SR44.2
VR_SVID_DATA_RR: SR44.1 XU1.A25
VREF: AC59.1 AU1.41
VRM_PWRGD: O2R242.2 PQ43.3 PR139.1 PR187.2 PR189.1 PU9.15
VRM_PWRGD_R: O2R242.1 U24.69
VRM_VCCP: PC123.1 PR165.2 PU9.22
VRM_VDD: PC125.1 PR181.2 PU9.21
VRP: AC58.1 AU1.38
VSUS_ON#: PR44.1 U24.19
WIFI_RF_KILL#_R: J218.56 WR34.2 WR35.1
WLAN_PE1_RXN1: J218.43 XU1.AT9
WLAN_PE1_RXP1: J218.41 XU1.AT10
WLAN_PE1_TXN1: C6.1 J218.37
WLAN_PE1_TXP1: C7.1 J218.35
WLAN_WAKE#_R: J218.55 WR84.2
WWAN_WLAN_COEX1_R: J218.48 WT14.1
WWAN_WLAN_COEX2_R: J218.46 WT13.1
WWAN_WLAN_COEX3_R: J218.44 WT12.1
X1: C4.1 R26.1 UU3.10
X1_1: LR1.2 Y10.1
XMM1_SA0: SR123.1 XMM1.197
XMM1_SA1: SR124.1 SR163.1 XMM1.201
XTAL1: LC1.1 LR1.1 LU1.28
XTAL2: LC2.1 LU1.29 Y10.3
Y5_R: SR64.2 Y5.2
Y17_1: SR31.2 Y12.1
N17661737: PC1.2 Q27.1 R90.2 R91.1
N24358231: PC5.2 PQ1.4 PQ2.2 PR11.2 PR14.1
N24358368: PQ2.1 PQ3.3 PR9.2 PR14.2
N27493538: PR70.1 PR71.2 PR73.1 PR78.1
N27848589: R3008.2 U24.79
N31476480: PC6.2 PJP3.2 PR13.2
N31476482: PC6.1 PJP2.2 PR12.2
N31476922: PQ2.3 PR10.2
N31477919: PC17.2 PR23.2 PU2.4
N31477921: PR26.2 PU2.5
N31477928: PC12.2 PR18.2 PU2.2
N31477936: PR19.2 PR24.1 PU2.6
N31477938: PR20.2 PR25.1 PU2.7
N31477967: PR21.2 PU2.8
N31484130: PC78.1 PR110.2 PR247.2 PU6.2
N31491325: FD3.2 FD4.3 FR4.1 P70.4
N31515196: TPR5.1 TPU1.7
N31515268: TPR1.2 TPR2.1 TPU1.6
N31541018: J8.5 J8.6 LC16.1
N31550216: AC56.1 AC57.1 AU1.23 AU1.25 L2.2
N31550234: AC48.1 AC49.1 AU1.39 L1.2
N31550341: AR5.1 AR36.1 AU1.29
N31550370: AU1.4 D1.2 R5.2
N31552500: AR7.1 HR2.2 HR3.1 R15.2
N31552502: AC2.2 R15.1
N31552504: AR6.1 HR1.2 HR4.1 R14.2
N31552506: AC1.2 R14.1
N31552857: AQ1.1 AQ2.1 AQ3.3 AR8.2
N31596067: P12.12 R30.2
N31886144: Q3.1 R2.2
N31886219: Q3.6 R3.1
N31906684: HUBL1.2 UU3.21
N31906694: SM_TP1.1 UU3.18
N31906900: R13.1 UU3.26
N31906916: R17.1 R20.2 UU3.23
N31906975: C5.1 R25.2 Y24.3
N31906994: R26.2 Y24.1
N31907009: R25.1 UU3.11
N31907112: R24.1 UU3.12
N31907116: R23.1 UU3.13
N32036872: OP1R2.2 U23.19
N32037100: OP1R3.2 U23.24
N32037272: O2R251.1 U24.66
N32037461: O2R252.1 U24.73
N32381924: ST85.1 XU1.D14
N32381935: ST86.1 XU1.G12
N32381953: ST87.1 XU1.F14
N32381971: ST88.1 XU1.F12
N32381989: ST89.1 XU1.G16
N32517551: MQ37.5 MR16.2
N32517556: MQ37.2 MR17.2
N33528355: FD5.1 MR18.1
N33528358: FD5.2 MR19.1

Pads without a net: AU1 3 12 13 14 15 16 17 18 19 34 37 43 44 45 46; CR6 1 2; J137 13 14; J218 6 16 17 18 19 20 21 22 23 25 26 27 28 29 30 31 32 34 36 38 40 42 58 59 60 61 62 64 65 66 67 68 70 71 73; J219 5 6 7 8 9 10 11 20 22 23 24 25 26 28 29 30 31 32 34 35 36 37 38 40 42 44 46 48 50 52 53 54 55 56 58 59 60 61 62 63 64 65 66 67 69; NOREF#12 1; NOREF#17 1; NOREF#33 1; NOREF#39 1; NOREF#40 1; NOREF#44 1; P12 5 7 13 14 15 16; P13 9 10; PPID1 1; PU3 19; PU4 5; PU5 5; PU6 5; PU9 9 20; TPU1 1 2 3 8 9 12 13 14 15 28; U23 22; U24 15 29 77 78 81 94 98 117 118 120; UU3 15 16; XMM1 77 122 125 198; XU1 A13 AA22 AB2 AB3 AB7 AB9 AB12 AB13 AB14 AD4 AD6 AD9 AD10 AD12 AD40 AD41 AF4 AF6 AF13 AF14 AF30 AF40 AF41 AF48 AF50 AF51 AF52 AG51 AG53 AH13 AH14 AH40 AH44 AH52 AJ51 AK7 AK9 AK40 AK42 AK45 AK47 AK48 AK50 AK51 AK52 AL51 AL53 AM9 AM10 AM13 AM14 AM41 AM42 AM45 AM47 AM48 AM50 AM52 AP41 AP42 AP44 AP45 AP47 AP48 AP50 AP51 AP52 AR51 AR53 AT13 AT14 AT20 AT22 AT26 AT28 AT32 AT34 AT36 AT40 AT41 AT42 AT44 AT45 AT48 AT50 AT51 AU20 AU22 AU26 AU28 AU32 AU34 AU36 AU53 AV9 AV10 AV20 AV22 AV26 AV28 AV32 AV34 AV36 AV40 AV44 AV45 AV48 AV50 AV52 AW1 AW41 AW51 AW53 AY2 AY3 AY6 AY7 AY20 AY24 AY26 AY28 AY30 AY34 AY38 AY40 AY42 AY44 AY45 AY47 AY48 AY51 AY52 B4 B5 B30 BA1 BA3 BA18 BA20 BA24 BA26 BA28 BA34 BA36 BA38 BA42 BA51 BB3 BB4 BB44 BB47 BB49 BB50 BB51 BC16 BC18 BC24 BC36 BC38 BC40 BC44 BC52 BC53 BD2 BD5 BD12 BD14 BD16 BD18 BD20 BD22 BD26 BD28 BD32 BD34 BD36 BD38 BD40 BD42 BD44 BD47 BE46 BE51 BE52 BF2 BF14 BF22 BF27 BF28 BF32 BF34 BF40 BF42 BF48 BF50 BF52 BG9 BG18 BG21 BG23 BG24 BG25 BG26 BG27 BG28 BG29 BG32 BG33 BG35 BG36 BG37 BG38 BG40 BG41 BG43 BG47 BH4 BH5 BH6 BH7 BH8 BH18 BH22 BH24 BH26 BH28 BH32 BH34 BH36 BH38 BH40 BH42 BH44 BH46 BH47 BH48 BH49 BH50 BJ9 BJ25 BJ29 BJ33 BJ37 BJ41 BJ45 C13 C15 C19 C21 C30 D2 D18 D28 D32 D34 D48 E2 E46 F1 F16 F28 F32 F34 G2 H4 H5 H7 H8 J18 J20 J28 J30 J34 K18 K20 K24 K28 K34 L1 L3 M3 M4 M6 M7 M9 M10 M18 M20 M22 M24 M30 M32 N24 N30 N32 N34 P2 P6 P7 P10 P12 P14 P34 R1 R3 T2 T3 T4 T6 T7 T9 T10 T12 T13 T14 V2 V3 V4 V6 V9 V10 V13 V14 W1 W3 Y2 Y3 Y4 Y6 Y12 Y13

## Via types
v1: diameter 0.508, hole 0.254, TOP to BOTTOM, 2308 vias
v2: diameter 0.66, hole 0.33, TOP to BOTTOM, 761 vias
v3: diameter 0.762, hole 0.457, TOP to BOTTOM, 266 vias
v4: diameter 0.762, hole 0.305, TOP to BOTTOM, 3 vias

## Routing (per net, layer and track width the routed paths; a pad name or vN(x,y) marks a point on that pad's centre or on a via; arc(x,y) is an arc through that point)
3V_EC_GPIO_MOS: length 4.8
  BOTTOM w0.102: ST7.1 61.94,11.16 62.35,10.75 62.96,10.75 63.39,10.32 63.8,10.32 64.13,10.65 64.13,10.84 64.29,11.01 U24.33
5V3V_VIN_C: length 7.3
  BOTTOM w0.222: PU3.12 10.82,32.43 10.23,31.84 9.87,31.84 PC18.1
  BOTTOM w0.508: PC18.1 9.69,31.12 9.39,30.82 8.67,30.82 PR27.2 v2(7.76,28.15)
5V_DUAL_DRI1: length 3.1
  TOP w0.102: v2(27.4,53.7) 27.22,53.53 PR70.2
  TOP w0.254: PR69.1 PC65.1 26.51,52.94 26.42,53.03 PR70.2
5VSB_EN: length 33
  TOP w0.254: v1(20.1,25) 19.78,25 16.2,28.58 16.2,28.89 v1(16.18,28.89)
  IN2 w0.254: v1(17.26,36.92) 17.26,36.85 17.86,36.25 18.17,36.25 19.37,35.06 19.37,33.43 20.72,32.09 20.72,29.72 21.16,29.27 21.16,26.06 v1(20.1,25)
  BOTTOM w0.222: PC40.1 14.78,36.15 14.56,35.94 14.56,34.87 14.1,34.41 PU3.20
  BOTTOM w0.254: v1(16.18,28.89) 16.2,28.89 16.2,28.48 13.23,25.51 11.89,25.51 PR47.1 11.42,24.21 v2(11.28,24.06) ; v1(17.26,36.92) 17.2,36.85 PR44.2 PR41.2 PC40.1
+3V_WLAN: length 32.6
  TOP w0.457: WR34.1 41.71,4.52 42.05,4.17
  TOP w0.762: 43.2,3.23 41.88,3.23 37.69,7.43 37.69,10.14 36.85,10.98 36.85,12.73 39.1,14.99 v3(39.1,15.49)
  IN2 w0.762: v3(39.1,15.49) 39.73,16.13 44.12,16.13 46.31,18.32 46.31,20.25 v3(46.68,20.62)
  BOTTOM w0.457: WR59.1 47.64,3.44 47.46,3.26 46.25,3.26
  vias: v2(41.24,1.81) v3(42.38,2.46) v3(43.27,2.45)
+3VA: length 359.7
  TOP w0.457: AR8.1 25.91,104.71 26.17,104.45 26.51,104.45 26.64,104.58 v1(26.89,104.58) ; v1(15.56,32.95) 15.14,32.53 PC30.1 14.7,31.73 14.95,31.48 15.8,31.48 v1(16.2,31.09) ; R191.1 67.62,8.51 67.45,8.34 67.45,7.78 67.13,7.45 v1(66.58,7.45)
  TOP w0.508: v1(97.76,11.45) 98.6,12.29 O2R132.1 ; v1(56.56,32.55) 57.57,32.55 61.74,28.38 v1(65.37,28.38) 67.94,30.95 72.22,30.95 74.06,29.11 v1(74.07,29.11) ; v1(55.97,7.64) 56.56,7.05 56.56,4.53 v1(56.85,4.23) ; v1(5.73,88.3) 5.73,88.02 6.27,87.49 6.27,80.8 11.57,75.49 11.57,74.79 12.25,74.11 v1(12.26,74.11)
  IN1 w0.508: v1(78.63,7.73) 78.47,7.57 75.56,7.57 74.66,8.47 73.32,8.47 72.84,7.99 72.84,7.96 72.48,7.59 72.45,7.59 72.44,7.59 69.15,7.59 69.14,7.59 68.84,7.59 68.68,7.75 66.89,7.75 66.59,7.45 v1(66.58,7.45) ; v1(55.97,7.64) 53.55,7.64 52.37,6.46 40.05,6.46 35.63,10.88 30.45,10.88 28.8,12.53 v1(28.8,13.04) ; v1(85.44,13.66) 84.37,14.73 84.37,21.62 84.07,21.93 84.07,24.16 v1(83.33,24.9) ; v1(9.14,39.47) 9.14,33.94 8.65,33.46 8.65,28.36 9.19,27.82 11.96,27.82 12.11,27.67 v1(16.27,27.67) 25.82,27.67 26.48,28.33 27.17,28.33 28.16,27.35 33.48,27.35 v1(33.88,26.96)
  IN2 w0.508: v1(16.27,27.67) 16.8,28.2 16.8,30.48 v1(16.2,31.09) ; v1(12.26,74.11) 12.26,73.03 14.11,71.18 14.11,65.61 14.17,65.56 14.17,63.08 15.08,62.16 16.32,62.16 17.44,61.04 17.44,59.29 17.75,58.99 17.75,55.86 18.34,55.27 18.34,50.34 16.07,48.06 16.07,39.4 16.82,38.65 17.98,38.65 18.36,38.26 18.79,38.26 21.2,35.85 21.2,35.24 22.36,34.08 22.36,31.39 22.1,31.14 22.1,30.51 23.45,29.17 23.45,28.13 23.97,27.61 23.97,19.41 23.61,19.06 23.61,17.82 28.4,13.04 v1(28.8,13.04) ; v1(78.63,7.73) 78.77,7.87 78.77,8.46 79.04,8.72 80.17,8.72 81.97,10.53 85.1,13.66 v1(85.44,13.66) 90.78,13.66 91.66,12.79 94.4,12.79 v1(94.96,12.23) ; v1(55.97,7.64) 56.06,7.73 66.3,7.73 v1(66.58,7.45) ; v1(33.88,26.96) 33.88,28.32 35.18,29.63 38.49,29.63 39.73,30.87 39.73,31.27 40.99,32.52 41.46,32.52 42.03,33.09 42.03,33.53 42.99,34.49 55.58,34.49 56.56,33.51 v1(56.56,32.55) ; v1(83.33,24.9) 83.33,25.69 78.54,30.48 75.44,30.48 v1(74.07,29.11)
  BOTTOM w0.222: PU3.3 15.44,32.83 v1(15.56,32.95)
  BOTTOM w0.457: WR62.1 55.56,4.34 55.69,4.47 56.19,4.47 56.43,4.23 v1(56.85,4.23) ; PR41.1 15.79,38.49 ; R3008.1 73.59,28.67 74.03,29.11 v1(74.07,29.11) ; v1(94.96,12.23) 94.61,11.87 C272.1
  BOTTOM w0.508: v1(97.76,11.45) 96.19,13.01 R229.2 94.24,12.91 C272.1 ; v1(26.89,104.58) 27.14,104.58 27.67,104.05 27.67,103.43 29.13,101.96 29.13,97.79 21.95,90.61 16.25,90.61 14.34,92.52 12.67,92.52 10.76,90.61 8.04,90.61 v2(6.62,89.18) v1(5.73,88.3) ; 15.79,38.49 14.19,40.09 9.76,40.09 v1(9.14,39.47) 8.75,39.86 SD1.1 ; R209.1 v1(65.37,28.38) ; R205.1 80.08,4.4 78.63,5.85 v1(78.63,7.73)
+3VA_EC: length 72.4
  TOP w0.381: O2R1.1 68.59,7.9 68.93,7.55 D28.2
  TOP w0.457: v1(79.85,11.4) 79.76,11.49 C262.1 C261.1 78.49,12.59 78.05,13.04 78.05,13.65 v1(78.66,14.26) 78.66,14.51 78.43,14.74 78.43,16.05 v2(77.88,16.6) 77.44,17.04 C263.1 v1(78.07,17.8) ; D28.2 70.04,6.88 70.26,6.66 R192.1 ; v1(69.31,10.84) C264.1 69.78,11.45 69.98,11.25 69.98,10.77 70.51,10.25 70.54,10.25 70.99,9.8 70.99,7.81 70.73,7.55
  TOP w0.508: 70.73,7.55 D28.2 ; C263.1 76.9,17.8 76.55,18.16 76.55,20.33 78,21.78 v1(78,21.76)
  IN1 w0.508: v1(69.31,10.84) 69.58,11.11 70.14,11.11 70.7,11.67 75.45,11.67 76.79,13 77.3,13 78.84,11.46 79.79,11.46 v1(79.85,11.4)
  BOTTOM w0.178: U24.92 77.72,23.65
  BOTTOM w0.203: v1(79.85,11.4) U24.127 81.79,11.4 82.36,10.83 82.92,10.83 83.2,11.11 R215.1 ; v1(78.66,14.26) 78.76,14.37 79.64,14.37 80.2,13.8 U24.121 ; v1(78.07,17.8) 79.27,16.6 U24.114 ; U24.50 67.24,17.8 ; v1(69.31,10.84) 69.32,10.83 U24.26
  BOTTOM w0.508: 77.72,23.65 78,23.38 v1(78,21.76) ; v1(69.31,10.84) 68.7,11.45 68.64,11.45 68.05,12.04 68.05,12.93 69.05,13.93 69.05,16.17 67.42,17.8 67.24,17.8 ; R215.1 83.75,10.77 C260.1 81.81,8.82 81.81,6.44 82.12,6.12 D32.1 82.12,5.19 R205.2 82.63,4.13 D33.2
+3VA_SPI: length 22
  TOP w0.508: v2(88.26,13.98) 88.41,13.83 v1(88.41,12.35)
  IN1 w0.508: v1(89.59,22.54) 89.59,21.15 88.38,19.95 88.38,13.11 88.41,13.08 v1(88.41,12.35)
  BOTTOM w0.457: v1(89.59,22.54) R228.1 R227.1 ; 88.07,12.7 R230.1 88.07,13.47 87.85,13.69 U25.8
  BOTTOM w0.508: R229.1 92.36,12.07 88.69,12.07 v1(88.41,12.35) 88.07,12.7
+3VS_CR: length 16.6
  TOP w0.508: v1(7.09,62.14) 7.09,55.61 10.25,52.44 v1(10.25,52.38)
  BOTTOM w0.279: U23.9 8.86,59.71 8.32,60.25 8.32,60.89 8.48,61.05 C257.1
  BOTTOM w0.457: 7.96,61.49 C257.1 ; v1(10.25,52.38) 10.27,52.38 10.47,52.59 OP1R2.1
  BOTTOM w0.508: PCB1.1 6.98,65.26 v2(6.7,65.54)
+3VSB_VIN:
  vias: v2(24.05,9.66) v3(18.18,6.51) v3(19.12,6.54) v3(20.03,6.54)
+3VSUS: length 54.9
  BOTTOM w0.222: LU1.32 51.53,94.7 51.15,94.32 50.55,94.32 v1(50.54,94.33)
  BOTTOM w0.229: LU1.11 52.33,99.74 v1(52.04,100.02)
  BOTTOM w0.457: v1(56.85,91.37) 56.48,91 56.48,90.21 55.08,88.81 47.44,88.81 45.64,90.61 45.64,91.47 43.87,93.25 43.87,93.54 42.89,94.52 42.03,94.52 38.04,98.51 33.57,98.51 v2(30.98,101.1) 30.98,105.6 30.18,106.4 LC17.1 29.3,108.16 29.84,108.7 31.15,108.7 32.09,109.64 32.09,110.98 32,111.08 32,111.08 30.68,112.4 30.68,115.03 J8.12
  vias: v1(55.77,96.07) v1(56.25,95.64)
+5V: length 374.7
  TOP w0.254: PR216.1 100.26,51.67 100.41,51.67 v1(100.51,51.57)
  TOP w0.432: v1(61.64,13.95) 61.41,14.18 61.29,14.18 60.47,15 60.47,17.17 61.94,18.64 PR169.1
  TOP w0.457: MR24.1 MR25.1 v1(89.9,91.88) ; R176.1 R182.1 90.48,14.78 88.61,16.65 88.61,18.2 v1(89.58,19.16)
  TOP w0.508: v1(98.9,62.75) 99.46,62.19 101.39,62.19 104.05,64.85 v1(104.35,64.85) ; FD5.3 v1(78.35,91.93) ; v1(108.54,23.45) 97.68,23.45 96.46,22.23 92.65,22.23 v1(89.58,19.16) ; O2R246.1 75.53,20.58 75.91,20.2 v1(75.91,19.05) 75.91,16.57 74.13,14.79 72.86,14.79 v1(72.36,15.3) 70.66,17 70.66,18.3 70.31,18.64 PR168.1
  TOP w0.762: D1.1 3.94,89.17 v3(4.79,88.32)
  IN1 w0.508: v1(104.35,64.85) 104.23,64.97 104.23,69.91 105,70.67 105,90.59 103.57,92.01 v1(96.61,92.01) ; v1(55.69,12.48) 57.71,12.48 58.98,13.75 61.42,13.75 61.62,13.95 v1(61.64,13.95) 61.87,13.95 62.22,13.61 65.37,13.61 65.7,13.94 67.7,13.94 67.92,14.16 68.7,14.16 69.03,14.49 71.59,14.49 72.36,15.26 v1(72.36,15.3) ; v1(106.29,57.32) 106.29,57.31 106.47,57.13 v1(106.47,54.41)
  IN2 w0.508: v1(55.69,12.48) 55.16,13.01 53.29,13.01 52.87,13.43 47.76,13.43 46.44,12.11 38.62,12.11 38.22,12.51 38.22,13.09 37.89,13.42 37.37,13.42 37.23,13.56 36.48,14.31 29.53,14.31 26.04,17.8 26.04,28.57 v3(25.42,29.19) ; v1(75.91,19.05) 79.42,19.05 79.91,19.54 82.85,19.54 83.48,18.91 89.33,18.91 v1(89.58,19.16) ; v1(108.54,23.45) 107.92,24.08 107.92,33.82 104.48,37.26 104.48,39.93 102.98,41.42 102.98,48.82 100.51,51.28 v1(100.51,51.57)
  IN2 w0.762: v3(4.79,88.32) 4.79,80.73 6.11,79.41 6.11,77.68 7.66,76.13 7.66,74.66 7.51,74.51 6.42,73.42 5.18,73.42 2.8,71.03 2.8,53.32 6.02,50.1 6.92,50.1 7.65,49.37 7.65,48.35 6.43,47.13 6.43,43.47 6.45,43.45 6.45,39.66 5.05,38.25 v3(5.05,22.03)
  BOTTOM w0.457: v1(106.29,57.32) 106.74,57.32 107.52,58.11 PR186.1 108.21,58.28 PR165.1 108.71,59.87 PR181.1 109.95,62 109.95,63.66 108.35,65.26 ; 108.35,65.26 107.92,64.83 104.51,64.83 104.5,64.85 104.51,64.85 104.51,64.85 ; 108.35,65.26 PR201.1 ; 104.51,64.85 v1(104.35,64.85) ; 104.51,64.85 PR187.1 ; v1(98.9,62.75) 98.52,63.13 97.2,63.13 96.61,63.71 95.64,63.71 95.46,63.53 PR233.2 ; PR183.1 105.29,54.56 105.75,54.09 ; 82.54,95.72 81.77,96.49 MR1.1 80.46,96.49 80.37,96.58 MQ33.3 ; v1(106.47,54.41) 106.46,54.4 106.06,54.4 105.75,54.09 ; 105.75,54.09 105.75,53.57 104.45,52.27 103.76,52.27 103.56,52.07 103.56,51.04 102.83,50.31 101.27,50.31 100.51,51.08 v1(100.51,51.57) ; PR106.1 55.73,22.67 56.01,22.39 56.01,17.27 55.57,16.82 54.79,16.82 52.85,14.88 52.85,14.21 53.92,13.14 55.03,13.14 v1(55.69,12.48) 56.33,11.85 56.33,8.13 56.57,7.89 56.57,7.39 56.22,7.04 PR96.2
  BOTTOM w0.508: v1(96.61,92.01) 96.61,93.1 96.19,93.52 92.44,93.52 90.8,91.88 v1(89.9,91.88) 88.13,91.88 87.56,92.46 84.81,92.46 83.07,94.2 83.07,95.19 82.54,95.72 ; v2(4.79,89.26) v3(4.79,88.32) ; v1(78.35,91.93) 78.35,95.3 MQ33.3 ; PR87.2 16.95,22.63 16.98,22.67
  BOTTOM w1.524: 24.25,27.87 20.64,27.87 16.48,23.71 16.48,23.68
  vias: v3(12.96,19.5) v3(13.85,19.5) v3(25.42,30.08)
+5V_AUX: length 28.2
  TOP w0.457: PR23.1 PR17.1 PC15.1 97.8,109.19 v2(98.16,109.56) 98.56,109.17 98.56,108.25 99.27,107.54 PR18.1 ; PU1.3 104.06,95.71 103.87,95.53 PC9.1 102.75,95.53 102.58,95.69 v1(102.58,96.52) ; v1(100.11,97.72) 100.11,97.52 99.6,97.01 PC16.1 PR15.1 PR16.1 PR20.1 95.57,96.63 PR19.1
  TOP w0.508: v1(100.11,107.54) PR18.1
  BOTTOM w0.508: v1(100.11,107.54) v1(100.11,97.72) 101.31,96.52 v1(102.58,96.52)
+5V_DRI: length 7.5
  TOP w0.254: PR75.1 22.1,34.49 22.37,34.22 22.37,33.75 PR68.1 PR72.2 PR79.1 24.29,32.23 24.58,31.94 24.58,30.62 24.5,30.54 v2(24.5,29.14)
+5V_DRI1: length 3.8
  TOP w0.254: v2(25.54,33.17) 25.33,33.17 24.49,34.01 PC64.1 PR68.2 22.95,34.4 23.04,34.49 PR67.1
+5V_DUAL: length 184.6
  TOP w0.356: UR7.1 71.3,91.84 71.29,91.86 U18.3 ; U18.2 70.63,91.96 70.49,91.81 UC5.1
  TOP w0.457: v1(69.39,90.74) 70.43,90.74 70.49,90.8 UC5.1 ; v1(71.3,90.73) UR7.1
  TOP w0.508: R159.1 R160.1 R169.1 R170.1 102.46,12.89 102.05,13.29 102.05,14.64 101.47,15.22 v1(101.47,17.14)
  TOP w2.032: 38.98,97.49 32.34,97.49 32.09,97.75 30.2,97.75 28.69,96.24 28.69,93.86
  IN1 w0.508: v1(101.47,17.14) 103.27,18.94 103.27,23.07 107.09,26.9 107.09,37.33 103.85,40.57 103.85,41.72
  IN1 w1.27: 71.26,89.44 76.78,89.44 79.65,86.57 85.43,86.57 92.62,79.38 101.01,79.38 103.97,76.42 103.97,71.46 101.85,69.34 101.85,62.92 ; 103.38,55.86 103.83,55.42 103.83,46.03 101.92,44.13 101.92,42.71
  IN1 w2.032: 22.79,52.42 22.79,53.79 22.59,54 22.59,62.79 25.32,65.52 25.32,78.12 28.34,81.14 28.34,91.2
  IN2 w0.508: v1(64.58,82.08) 62.84,83.82 62.84,88.45 v1(62.34,88.95) 63.51,90.13 68.19,90.13 68.8,90.74 v1(69.39,90.74)
  BOTTOM w0.279: v1(62.34,88.95) 62.35,88.95 62.35,88.94 UU3.27
  BOTTOM w0.457: v1(64.58,82.08) 64.58,81.12 65.09,80.62 66.43,80.62 67.66,81.85 R18.2
  vias: v1(23.94,51.42) v1(27.42,91.98) v1(39.41,95.79) v1(99.26,42.6) v1(99.26,41.97) v2(28.59,92.39) v3(22.7,49.97) v3(22.82,50.95) v3(27.46,93.66) v3(27.46,92.77) v3(37.71,95.82) v3(38.63,95.82)
+5V_HDMI: length 7.7
  BOTTOM w0.457: MQ33.2 76.26,97.53 76.12,97.38 VF1.2 74.9,96.64 74.73,96.48 MR2.1
  BOTTOM w0.508: v2(81.12,97.52) 81.11,97.53 MQ33.2
+5V_PWRGD: length 4.1
  TOP w0.457: O2R248.1 O2R246.2 75.53,23.55 75.79,23.81 v1(75.79,23.82)
  TOP w0.508: v2(75.23,24.52) 75.23,24.38 v1(75.79,23.82)
  BOTTOM w0.203: U24.86 75.32,24.05 75.54,23.82 v1(75.79,23.82)
+5VA: length 66.8
  TOP w0.508: v1(20.93,32.86) 20.41,32.34 19.04,32.34 17.16,30.46 15.87,30.46 15.46,30.87 13.15,30.87 11.55,32.47 v1(10.1,32.47)
  IN1 w0.508: v1(25.39,32.47) 25.39,32.78 24.98,33.19 22.61,33.19 22.28,32.86 v1(20.93,32.86)
  IN2 w0.508: v1(25.39,32.47) 25.39,36.34 24.49,37.25 24.49,38.62 25.38,39.51 26.54,39.51 26.69,39.66 26.69,47.08 26.36,47.41 25.4,47.41 24.6,48.2 24.6,54.7 v1(21.07,58.23) 21.07,59.39 17.29,63.17 16.6,63.17 15.92,63.85 v1(15.31,63.85)
  BOTTOM w0.222: PU3.13 10.61,32.83 10.43,33 PC26.1
  BOTTOM w0.432: v1(20.93,32.86) 21.29,33.22 21.91,33.22 SR65.1
  BOTTOM w0.457: v1(10.1,32.47) 9.8,32.47 9.53,32.74 PC26.1 ; SR71.1 15.71,65.59 15.59,65.46 v2(14.88,65.46) 14.88,64.28 v1(15.31,63.85) ; SR625.1 v1(21.07,58.23)
+5VSB: length 437.5
  TOP w0.432: v1(66.41,15.2) 66.41,13.39 65.63,12.61 PR170.1 ; 70.27,20.02 68.89,20.02 68.46,20.46 67.97,20.46 67.63,20.11 67.63,19.39 66.88,18.64 PR172.1
  TOP w0.457: PR126.1 27.07,26.48 26.79,26.76 26.79,27.71 v1(26.8,27.71) ; v1(73.17,15.91) 71.47,17.61 71.47,18.82 70.27,20.02
  TOP w0.508: v1(106.34,50.63) 106.54,50.63 107.48,51.57 107.48,57.69 107.61,57.82 107.61,62.36 108.88,63.64 108.88,73.8 v1(108.12,74.56) ; v1(42,15) 41.45,15.55 40.38,15.55 40.05,15.88 40.05,15.89 39.49,16.44 36.01,16.44 34.03,14.46 30.47,14.46 v1(29.94,15) ; v1(110.44,23.44) 109.58,23.44 107.55,21.41 95.53,21.41 95.33,21.61 93.25,21.61 v1(92.37,20.74) 92.04,20.74 90.45,19.15 v1(90.45,18.92) ; v3(3.65,92.16) 2.13,93.68 v2(2.13,99.02) D4.2 2.65,100.59 2.93,100.86 L1.1
  TOP w0.762: v1(7.84,81.31) 7.84,80.32 9.01,79.16 13.45,79.16 13.96,78.65 13.96,77.92 13.96,77.91 14.88,77 18.03,77 19.35,75.68 19.35,72.42 18.69,71.76 v3(18.24,71.76)
  IN1 w0.508: v1(6.22,15.99) 6.22,17.53 6.73,18.04 11.68,18.04 13.99,15.73 18.5,15.73 19.18,15.05 20.7,15.05 20.7,15.05 29.89,15.05 v1(29.94,15) 31.4,13.53 36.21,13.53 36.86,12.89 37.85,12.89 38.62,12.11 39.3,12.11 39.33,12.14 44.86,12.14 45.04,12.32 48.06,12.32 48.23,12.15 53.57,12.15 55.49,14.07 58.43,14.07 58.73,14.36 61.17,14.36 61.38,14.58 62.16,14.58 62.52,14.22 65.11,14.22 65.45,14.55 65.77,14.55 v1(66.41,15.2) 67.13,15.2 67.56,14.77 68.45,14.77 69.61,15.92 73.17,15.92 v1(73.17,15.91) ; v3(3.65,92.16) 4.59,93.1 4.59,93.52 6.67,95.6 7.82,95.6 8.34,96.12 9.8,96.12 11.24,97.57 16.17,97.57 21.23,102.63 25.28,102.63 25.86,102.05 50.5,102.05 52.71,104.26 58.92,104.26 v1(61.02,102.17)
  IN2 w0.508: v1(66.41,15.2) 66.41,17.7 64.62,19.49 64.62,32.83 60.46,36.99 59.16,36.99 v1(58.62,37.53) ; v1(46.96,15.51) 45.42,13.97 43.03,13.97 v1(42,15) ; v1(110.44,23.44) 110.46,23.44 110.46,23.43 112.11,23.43 114.77,26.09 114.77,29.27 105.88,38.16 105.88,38.16 105.88,40.95 105.07,41.76 105.07,44.54 104.69,44.92 104.69,49.84 105.48,50.63 v1(106.34,50.63) ; v1(3.37,35.96) 3.76,35.57 3.76,20.14 6.22,17.69 v1(6.22,15.99) ; v1(73.17,15.91) 74.38,17.12 80.2,17.12 81.37,18.29 89.6,18.29 90.23,18.92 v1(90.45,18.92) ; v1(29.94,15) 26.65,18.28 26.65,27.56 v1(26.8,27.71) 26.88,27.79 26.88,37.94 26.07,38.74 v3(25.67,38.74)
  IN2 w0.762: v3(25.65,48.22) 25.65,48.48 25.37,48.76 25.37,56.24 19.42,62.18 19.42,63.03 17.98,64.47 17.98,65.41 16.65,66.73 16.65,70.18 v3(18.24,71.76) ; v1(7.84,81.31) 7.1,82.05 7.1,88.68 3.65,92.13 v3(3.65,92.16)
  BOTTOM w0.457: UU2.5 108.2,74.48 v1(108.12,74.56)
  BOTTOM w0.483: v1(61.02,102.17) U19.5
  BOTTOM w0.508: v1(46.96,15.51) 46.96,15.76 47.36,16.16 PR137.1 ; PR35.1 9.16,35.96 v1(3.37,35.96) ; PR60.1 93.14,23.08 92.37,22.31 v1(92.37,20.74) ; PR146.1 9.3,82.14 8.83,81.67 8.2,81.67 v1(7.84,81.31) ; PR111.1 57.84,37.1 58.27,37.53 v1(58.62,37.53) ; PR51.1 42.67,15.89 42,15.22 v1(42,15)
+5VSB_BST_C: length 5.4
  TOP w0.508: v2(12.26,37.8) 11.68,37.8 v1(11.12,37.25)
  BOTTOM w0.222: PU3.17 12.9,35.12 11.78,36.24
  BOTTOM w0.254: 11.78,36.24 PR28.1 11.78,36.99 11.52,37.25 v1(11.12,37.25)
+5VSB_BST_RC_C: length 3.6
  BOTTOM w0.508: PC24.2 12.63,37.99 12.62,38.01 PR28.2 10.94,38.01 10.33,38.62 v2(10.33,39.2)
+5VSB_FB_A: length 5.5
  TOP w0.254: v2(16.96,33.11) 17.33,33.47 PR37.2 17.33,34.66 v1(17.45,34.78)
  BOTTOM w0.222: 15.52,33.6 15.15,33.23 PU3.2
  BOTTOM w0.254: v1(17.45,34.78) 17.11,34.44 PC34.2 16,34.44 PR38.2 15.59,34.03 15.59,33.66 15.52,33.6
+5VSB_FBR_A: length 20.8
  TOP w0.254: v1(27.75,37.07) v2(28.54,37.07) 30.72,37.07 31.05,37.39 PJP4.2 ; PR37.1 18.17,34.7 v1(18.09,34.78) 18.61,34.78 19.75,35.92 19.75,37.22 20.72,38.19 20.72,39.3 20.73,39.31 v1(20.73,39.51)
  IN1 w0.254: v1(20.73,39.51) 21.93,38.31 23.39,38.31 24.69,37 27.69,37 v1(27.75,37.07)
  BOTTOM w0.254: v1(18.09,34.78) 18.09,35.07 PC35.1 16.98,35.43 PC34.1
+5VSB_HG_D: length 6.4
  TOP w0.635: v3(12.11,34.96) 13.96,36.81 15.18,36.81 15.82,37.45 v2(16.53,37.45)
  BOTTOM w0.222: v3(12.11,34.96) 12.5,34.57 PU3.16
+5VSB_LG_D: length 16.3
  IN1 w0.635: v3(11.77,47.12) 12.34,46.55 12.34,41.92 10.43,40.01 v3(10.43,36.81)
  BOTTOM w0.222: 11.19,34.1 11.66,33.63 PU3.15
  BOTTOM w0.635: 11.19,34.1 10.43,34.86 v3(10.43,36.81) ; v2(11.77,48.09) v3(11.77,47.12)
+5VSB_PHASE_D: length 14.9
  TOP w0.635: 19.83,39.86 19.83,38.64 18.74,37.55 18.74,36.51 18.15,35.92 16.4,35.92 16.12,35.65 14.48,35.65 v3(13.95,35.12)
  BOTTOM w0.222: PC24.1 12.7,36.79 12.7,36.04 13.3,35.44 PU3.18
  BOTTOM w0.457: PC24.1 13.58,36.65 v2(13.58,36.18)
  BOTTOM w0.635: v2(13.58,36.18) 13.95,35.81 v3(13.95,35.12)
+5VSB_SN_D: length 0.8
  BOTTOM w0.381: v1(13.71,43.27) 14.14,43.7 v2(14.32,43.7)
+5VSB_VIN: length 21.2
  IN2 w0.508: v3(11.27,39.25) 10.43,39.25 9.14,37.96 9.14,33.89 8.45,33.21 8.45,26.63 v1(8.3,26.48)
  BOTTOM w0.508: PR27.1 4.72,27.03 5.28,26.48 v1(8.3,26.48)
  vias: v2(13.25,40.19) v3(10.11,42.58) v3(11.31,42.55)
+5VSB_VO1_A: length 3.7
  BOTTOM w0.222: PU3.14 10.99,33.23 v2(10.71,33.5) 10.38,33.84 PC33.1
  BOTTOM w0.254: PC33.1 9.53,34.3 9.36,34.46 PR35.2
+19V_DCIN:
  vias: v2(99.61,108.56)
+19VA:
  vias: v2(107.13,101.15)
+19VA_IN: length 4.5
  TOP w0.508: PU1.1 104.46,98.72 104.08,99.09 PC8.1 v1(103.22,100.01) 103.78,100.57 v2(104.46,100.57)
  vias: v1(104.61,105.44)
+19VA_SN_A: length 5.4
  TOP w0.254: v2(116.63,107.35) 115.92,106.64 112.11,106.64 PC7.1
+19VSB: length 652.6
  TOP w0.254: PQ11.3 21.57,30.49 21.72,30.34 PR76.1 21.72,29.64 22.11,29.25 22.11,21.21 v1(21.68,20.79) ; v1(15.07,16.95) 14.97,16.95 12.05,14.03 7.26,14.03 5.74,12.51 v1(1.86,12.51)
  TOP w0.381: v3(2.74,46.08) 2.74,47.48 2.38,47.84 2.38,49.95 v3(2.68,50.25) ; PR74.1 18.23,49.68 18.25,49.7 PQ10.3
  TOP w0.432: 3.85,46.21 4.69,47.05 8.91,47.05 11.27,49.41 16.54,49.41 16.81,49.68 PR74.1
  TOP w1.016: 3.09,79.18 3.09,79.79 4.67,81.37 4.67,85.96 ; 2.67,52.27 v3(2.67,72.98)
  IN1 w0.127: 74.01,1.46 73.78,1.23 69.03,1.23 68.93,1.33
  IN1 w0.254: v1(15.07,16.95) 19.12,16.95 19.79,16.27 29.82,16.27 31.01,17.46 36.95,17.46 37.9,16.51 40.34,16.51 40.96,15.88 42.78,15.88 43.68,14.98 v1(43.68,14.98)
  IN1 w1.397: 118.97,36.51 118.97,39.43 116.55,41.84 111.8,41.84 108.98,44.66 108.98,55.75 108.62,56.12 108.62,57 108.98,57.36 108.98,57.39 109.95,58.35 109.95,79.59 111.09,80.72 116.45,80.72 119.47,83.75 119.47,87.36 121.61,89.5 121.61,95.27 121.06,95.82 ; 13.38,3.31 8.17,3.31 1.87,9.61 1.87,9.94 1.86,10.04 v1(1.86,12.51) 1.86,37.31 4.86,40.31 4.86,42.79 3.19,44.46 ; 15.89,3.31 17.09,3.31 18.53,4.76 22.83,4.76 24.81,2.78 40.28,2.78 41.55,4.05 v1(51.33,4.05) 52.34,4.05 54.22,5.93 56.51,5.93 56.76,6.18 56.76,6.21 56.82,6.27 65.28,6.27 66.92,4.63 66.92,2.93 ; 78.68,2.22 81.98,2.22 85.36,5.6 85.36,6.54 86.02,7.2 86.02,9.45 87.09,10.52 87.1,10.52 87.44,10.85 90.57,10.85 90.91,10.52 90.91,10.52 91.91,9.51 91.91,9.51 91.99,9.43 91.99,7.65 93.08,6.56 93.84,6.56 93.85,6.55 95.89,6.55 95.91,6.56 96.51,6.56 99.87,9.92 106.49,9.92 110.46,13.88 115.69,13.88 118.97,17.15 118.97,31.56 ; 120.7,101.73 121.85,100.58 121.85,97.56
  IN2 w0.127: 73.75,1.46 73.53,1.23 69.03,1.23 68.8,1.46
  IN2 w1.397: 121.61,95.22 121.61,89.49 119.47,87.35 119.47,83.75 116.43,80.7 111.12,80.7 109.95,79.54 109.95,58.35 108.98,57.39 108.98,57.36 108.62,57 108.62,56.12 108.98,55.75 108.98,44.66 111.8,41.84 116.55,41.84 118.97,39.43 118.97,36.51 ; 3.22,44.43 4.86,42.79 4.86,40.31 1.86,37.31 v1(1.86,12.51) 1.86,10.04 1.87,9.94 1.87,9.61 8.17,3.31 13.89,3.31 ; 118.97,31.38 118.97,17.15 115.69,13.88 110.46,13.88 106.47,9.89 99.84,9.89 96.51,6.56 93.08,6.56 91.99,7.65 91.99,9.43 90.57,10.85 87.43,10.85 86.02,9.45 86.02,7.2 85.36,6.54 85.36,5.6 81.98,2.22 77.79,2.22 ; 121.14,101.3 121.85,100.59 121.85,97.56 ; 15.89,3.31 17.09,3.31 18.53,4.76 22.83,4.76 24.81,2.78 40.28,2.78 41.55,4.05 v1(51.33,4.05) 52.34,4.05 54.22,5.93 56.48,5.93 56.82,6.27 65.28,6.27 66.82,4.73 66.82,3.03
  BOTTOM w0.254: 45.31,16.51 44.72,15.92 44.72,15.89 43.94,15.11 43.81,15.11 v1(43.68,14.98) ; 45.31,16.51 44.95,16.88 44.95,17.5 44.76,17.69 PC93.1 44.32,18.09 44.06,18.35 PU7.8 ; 45.31,16.51 45.62,16.82 48.44,16.82 49.12,17.5 49.12,18.47 49.94,19.29 49.94,20.89 50.26,21.22 50.54,21.22 51.33,22.01 51.33,22.97 51.64,23.29 PQ21.3 ; v1(15.07,16.95) 14.97,16.95 16.38,18.36 16.38,20.1 16.92,20.64 v1(17.26,20.64) 17.51,20.89 19.14,20.89 19.44,20.6 PR85.1 19.57,20.24 PQ15.3 21.3,20.24 21.68,20.62 v1(21.68,20.79)
  BOTTOM w0.356: PQ18.3 51.33,4.17 v1(51.33,4.05)
  vias: v1(68.55,1.71) v1(76.8,1.71) v2(4.44,86.5) v3(2.63,74) v3(2.75,77.63) v3(2.66,51.14) v3(2.79,76.62) v3(2.76,45.2) v3(2.76,44.31) v3(3.52,86.24) v3(3.5,85.35) v3(13.02,2.75) v3(13.91,2.75) v3(14.8,2.75) v3(118.41,34.88) v3(118.41,33.99) v3(118.38,33.08) v3(118.6,98.34) v3(119.09,97.57) v3(119.3,34.88) v3(119.3,33.97) v3(119.27,33.03) v3(119.55,98.33) v3(119.72,103.64) v3(119.67,102.75) v3(120.03,97.57) v3(120.62,103.64) v3(120.59,102.75)
+AV12:
  vias: v2(6.06,59.83)
+AVDD: length 61.5
  TOP w0.457: DEC6.1 DEC7.1 68.33,88.71 v1(68.57,88.94)
  TOP w0.762: v1(68.57,88.94) 68.57,89.98 68.14,90.41 67.12,90.41 66.59,90.94 v1(66.59,92.03) 66.9,92.03 67.33,92.47 67.33,93.37 v3(66.85,93.85)
  IN1 w0.762: v3(66.85,93.85) 66.2,93.85 65.94,93.6 v3(63.7,93.6)
  IN2 w0.508: v1(68.57,88.94) 68,88.37 68,86.19 v1(67.45,85.64)
  IN2 w0.762: v3(63.7,93.6) 63.23,93.6 60.55,90.91 60.55,90.13 60.27,89.85 60.27,89.32 v3(59.02,88.07) 58.25,87.3 58.25,85.09 58.94,84.4 60.4,84.4 60.94,83.86 60.94,83.7 v3(61.12,83.52)
  BOTTOM w0.279: UU3.28 62.55,89.44 62.18,89.81 DEC1.1 ; v1(68.57,88.94) UU3.9 ; DEC5.1 65.87,92.34 65.87,91.97 65.95,91.89 65.95,91.08 65.87,91.01 UU3.5 ; UU3.14 67.99,86.44 69.03,85.4 69.6,85.4 DEC8.1
  BOTTOM w0.457: R60310.2 R6.2 ; R6.2 R13.2 59.69,89.14 DEC2.1 60.1,90.1 60.39,89.81 DEC1.1 ; R6.2 v3(59.02,88.07) 57.19,88.07 v2(56.56,87.44) 57.69,86.31 R17.2 R16.2 ; R24.2 R23.2 71.21,85.57 DEC9.1 DEC8.1 68.43,84.81 67.6,85.64 v1(67.45,85.64) ; DEC5.1 66.27,92.35 v1(66.59,92.03) ; R11.2 R10.2 64.04,82.44 63.69,82.09 HUBL1.1 62.44,82.09 DEC3.1 61.78,82.69 61.78,82.7 61.56,82.91 61.48,82.91 61.12,83.28 v3(61.12,83.52)
+VCC_USB3: length 30.3
  TOP w0.457: UC11.1 108.46,48.64 108.48,48.62
  TOP w0.508: 112.26,47.13 J133.1 ; J133.1 112.26,48.81 ; J133.1 113.1,47.97
  TOP w0.762: J11.1 111.61,68.93 110.38,67.7 110.38,62.98 108.89,61.49 108.89,57.35 108.72,57.18 108.72,50.52 109.29,49.95 109.29,47.61
  BOTTOM w0.508: 113.19,47.97 J133.1 112.26,47.04
  vias: v2(108.55,43.62) v3(107.79,43.24) v3(107.76,42.33) v3(108.55,42.76)
+VCC_USB12:
  vias: v2(59.71,103.62)
AGND: length 22.7
  TOP w0.229: AU1.22 15.73,101.66 v1(15.95,101.89) ; v1(8.25,100.3) 8.41,100.46 AU1.42 ; AU1.28 12.78,103.59 12.81,103.61 12.81,103.93 13.38,104.51 v1(13.73,104.51)
  TOP w0.432: v1(8.35,106.46) 8.51,106.3 AR38.2 ; AC3.2 v1(16.3,108.95) ; AC4.2 v1(16.3,105.11)
  TOP w0.457: AC52.2 25.07,109.06 v1(24.94,109.2) ; v1(17.49,103.3) 16.91,103.3 AC57.2 ; v1(18.14,101) 17.91,100.77 AC62.2 ; v1(3.98,105.04) 3.98,104.62 AC50.2
  TOP w0.508: v1(4.08,107.45) 3.94,107.31 AR37.2 ; AQ3.2 23.95,106.42 v1(24.33,106.79) ; v1(4.62,104.83) 4.82,104.63 AC42.2 ; v1(4.64,103.36) 5.04,103.36 AC58.2 ; v1(18.64,103.98) AC56.2
  IN2 w0.508: 27.37,111.5 J27.5 ; J27.5 27.37,114.2 ; J27.5 26.36,112.85
  BOTTOM w0.457: AC6.2 v1(23.59,107.21) ; v1(22.32,105.44) 22.43,105.56 AC5.2
  BOTTOM w0.508: AQ1.2 v1(5.3,106.74) ; v1(17.49,103.3) 17.49,102.83 17.26,102.6 AQ2.2 ; v1(8.35,106.46) v2(7.51,107.3)
  vias: v1(4.67,102.69) v1(5.25,101.05) v1(5.25,100.36)
DV12_S:
  vias: v2(10.04,60.52)
DV33_18: length 2.7
  BOTTOM w0.102: v2(15.27,57.98) 14.46,57.16 13.57,57.16 C254.1
GND: length 1035.6
  TOP w0.254: PJP12.2 v1(77.69,37.4) ; PC173.2 102.04,67.12 102.38,67.12 v1(102.91,67.65) ; v1(16.73,63.94) 16.32,64.35 14.57,64.35 14.14,63.92 12.57,63.92 v1(12.24,64.25) 11.77,64.72 11.77,65.21 12.2,65.64 v1(12.22,65.64) 12.47,65.89 17.41,65.89 17.8,65.5 17.8,64.58 17.54,64.32 17.11,64.32 v1(16.73,63.94)
  TOP w0.279: v1(9.93,24.16) 9.92,24.18 P110.4 ; v1(5.81,23.81) 6.94,22.68 P110.7 ; v1(5.81,25.08) 6.41,25.68 P110.1 ; v1(47.67,15.5) 47.17,15 46.39,15 46.12,15.27 J218.24
  TOP w0.305: J218.75 53.71,2.52 v1(54.07,2.88) ; PR3.2 69.86,62.85 69.83,62.85 69.61,63.07 69.61,64.01 69.29,64.34 v1(69.29,64.71) ; J219.57 120.88,23.66 v1(120.77,23.55) ; J219.39 120.96,28.17 v1(120.77,27.97) ; v1(120.74,20.41) 120.98,20.17 J219.71 ; J218.33 51.94,13.02 v1(51.73,12.81) ; v1(55.94,3.88) 55.95,3.88 55.81,4.02 J218.69 ; v1(120.74,19.69) 120.77,19.66 J219.73 ; J219.1 120.93,37.66 120.82,37.78 v1(120.69,37.78) ; J218.51 51.99,8.52 51.73,8.26 v1(51.73,7.1) 51.81,7.02 J218.57 ; J218.45 v1(51.63,10.02) ; J219.75 120.85,19.17 v1(120.74,19.06) ; J219.27 v1(120.74,31.17) ; v1(53.79,18.65) 53.79,19.26 53.53,19.52 J218.7 ; v1(51.73,5.56) 51.77,5.52 J218.63 ; J219.21 v1(120.75,32.66) ; J218.39 v1(51.47,11.52) ; J218.1 54.22,21.02 54.22,21.02 v1(54.62,21.02) ; J219.51 v1(120.77,25.17) ; J219.3 120.74,37.17 v1(120.69,37.12) ; v1(120.77,26.66) J219.45 ; J219.33 v1(120.74,29.66)
  TOP w0.356: MQ41.4 v1(86.51,91.23) ; PQ11.1 20.27,31.47 20.08,31.66 v1(19.54,31.66) ; v1(19.81,51) PQ10.1 ; U18.1 v1(69.98,93.99)
  TOP w0.381: Y12.2 90.84,53.04 90.67,53.04 90.21,52.59 90.21,52.59 v1(90.19,52.58) ; v1(55.29,92.25) 55.2,92.17 D3.2 ; v1(49.19,28.75) 49.19,28.77 49.04,28.91 49.04,30.08 49.37,30.41 49.9,30.41 50.24,30.75 U3.4 ; U4.4 51.07,27.57 50.75,27.89 v1(50.65,27.89)
  TOP w0.406: MR26.1 84.75,92.55 84.78,92.53 MQ41.1
  TOP w0.432: C28.2 73.02,63.14 72.82,63.34 v1(72.22,63.34) ; C941137.2 77.17,63.2 78.48,63.2 v1(78.59,63.31) ; C89.2 v1(29.63,54.5) ; D3C1.2 32.43,84.77 v1(32.92,84.28) ; v1(31.03,25.99) 30.84,25.99 PC92.2 ; v1(64.13,17.4) 63.92,17.61 63.92,18.17 63.73,18.36 63.62,18.36 PR177.2 ; AC41.2 v1(11.49,95.56) ; v1(9.75,93.15) 10,93.4 AC44.2 ; PR178.2 68.32,18.64 68.22,18.74 v1(68.22,19.87) ; v1(42.85,93.43) 42.84,93.42 42.84,93.13 41.97,92.25 D3R3.2 D3CB2.1 ; PC128.2 65.75,19.24 v1(66.41,19.9) ; v1(29.63,52.73) D3R4.2 D3CB5.2 D3CB1.2 ; v1(88.09,66.1) 88.27,66.28 SR182.2 ; AC43.2 v1(14.19,95.58) ; v1(75.18,63.34) 74.95,63.57 C68.2 ; AC45.2 v1(9.11,93.15) ; v1(84.78,66.1) 84.64,66.24 C43.2
  TOP w0.457: HC12.2 v1(69.94,12.29) C264.2 ; v1(68.34,47.96) 68.84,48.46 C74.2 ; PC64.2 24.12,33.17 v1(24.72,32.57) ; PC88.2 v1(37.43,25.94) ; v1(79.27,45.65) 79.27,45.4 78.88,45.02 C941134.2 ; M1C10.2 76.57,96.92 76.68,96.81 v1(76.68,96.47) ; v1(79.38,43.53) 79.09,43.24 C941135.2 ; v1(74.14,77.83) 74.19,77.79 SC27.2 ; v1(67.89,59.22) 67.75,59.08 C27.2 ; SR83.1 v1(86.91,47.05) ; UU3.33 66.98,89.33 DEC7.2 ; v1(84.69,60.37) 85.19,60.37 85.81,60.98 SR193.2 SR91.2 ; v1(44.18,97.11) 44.67,97.6 LANC4.2 ; SR626.2 71.44,39.65 71.06,40.03 R60221.1 70.71,39.46 v1(70.63,39.38) ; AC7.2 26.51,103.56 v1(26.89,103.95) ; v1(76.93,21.75) 77.03,21.75 77.31,22.03 O2C59.2 ; C46.2 81.21,64.74 81.48,65.01 v1(81.48,65.24) ; v1(73.12,21.65) 73.12,22.12 R234.2 ; C14.2 68.67,63.05 v1(68.45,63.28) ; v1(38.5,22.49) 38.92,22.07 PC91.2 ; v1(63.72,94.42) 63.14,94.42 62.83,94.11 R91.2 ; v1(78.63,96.74) 79.09,97.2 M1C9.2 ; PU3.24 13.85,33.37 PC30.2 ; v1(38.36,34.58) 38.71,34.22 D3CB7.2 ; v1(101.06,11.45) 101.06,11.84 100.61,12.29 O2C53.2 ; C76.2 71.75,59.28 v1(71.68,59.21) ; v1(73.58,45.88) 73.58,45.88 73.58,45.93 74.02,46.38 C66.2 SR90.2 ; SR79.1 SR77.1 81.22,40.24 v1(81.09,40.11) ; v1(79.99,63.26) 79.8,63.45 C45.2 ; PC65.2 v1(27.27,51.71) ; C30.2 74.72,62.33 v1(74.71,62.34) 74.67,62.3 C38.2 ; PC9.2 v1(103.85,96.36) ; v1(77.18,39.35) 77.13,39.4 77.13,39.82 SR105.2 ; D3CB8.2 41.19,33.13 v1(41.22,33.16) ; v1(86.89,45.27) SR80.1 SR82.1 ; PR79.2 23.97,30.86 v1(24.05,30.78) ; v1(89.33,54.12) 89.45,54 SC1.2 ; PC16.2 99.05,97.85 v1(99.18,97.72) ; v1(63.46,84.22) 63.63,84.39 HC9.2 ; v1(74.6,10.85) R226.2 ; v1(73.8,10.91) 73.79,10.91 SC26.2 ; v1(66.94,6.18) 66.93,6.18 C149.2 ; O2R248.2 76.29,22.25 v1(76.29,21.75) ; v1(81.41,73.87) 81.34,73.94 FC1.2 ; v1(83.86,96.28) 83.37,95.79 M1R2.2 ; v1(54.09,25.82) 54.09,25.82 53.99,25.82 53.73,25.55 SC13.2 ; MD5.2 94.14,95.08 94.11,95.06 SR13.2 ; PC103.2 43.68,19.11 43.69,19.12 44.92,19.12 44.92,19.12 v1(44.92,19.12) ; v1(74.6,14.03) C268.2 ; v1(3.98,96.5) SR134.1 ; v1(78.05,77.67) 77.87,77.49 C67.2 ; v1(83.02,43.44) 82.9,43.32 R60219.1 ; v1(74.64,21.59) R233.2 ; PR22.2 PC17.1 96.11,107.43 v1(96.36,107.68) ; PR121.2 32.61,20.42 v1(32.5,20.52) ; PC13.2 98.82,98.9 98.82,98.85 v1(99,98.68) ; v1(77.04,12.38) 77.01,12.42 C269.2 ; SR627.2 79.66,40.7 v1(80.19,40.7) 80.19,41.23 SR78.1 ; PC15.2 v1(97.96,108.35) ; AC52.1 v1(26.76,108.01) ; v1(53,27.4) 53,27.5 SC11.2 ; v1(42.54,28.2) 42.66,28.33 43.16,28.33 SC12.2 ; v1(77.04,11.49) C262.2 C261.2 ; C941136.2 67.95,61.51 v1(67.9,61.57) ; C20.2 C941135.2 ; C941135.2 C21.2 ; PR144.2 v1(41.53,17.42) ; v1(83.56,92.56) 83.83,92.56 83.83,92.55 MR26.1 ; SC3.2 91.28,58.23 91.56,58.51 v1(91.56,58.5) ; AC55.2 AC53.2 v1(21.68,103.7) ; D3CB6.2 38.69,33.36 v1(38.36,33.03) 38.37,33.01 38.37,32.43 SR124.2 ; LANC3.2 47.08,98.45 v1(47.08,97.74) ; PC126.2 65.63,9.36 65.76,9.22 v1(65.76,8.74) ; C150.2 v1(66.93,0.79) ; AC39.2 17.96,96.2 v1(18.26,96.5) ; O2C56.2 68.04,11.16 68.12,11.08 68.12,11.02 v1(68.29,10.84) ; v1(59.76,80.17) 59.76,78.85 60.61,78 HC1.2 ; UU3.31 66.98,86.56 DEC6.2 ; C941163.2 75.91,77.64 75.7,77.85 v1(75.66,77.85) ; v1(99.15,51.74) 98.91,51.74 98.54,52.1 PC150.2 ; v1(76.23,58.43) 76.33,58.32 C42.2 ; WC14.2 41.65,8.31 v1(41.06,7.73) ; SC14.2 43.77,24.58 v1(43.78,24.57) ; SR123.2 v1(42.75,33.37) ; v1(68.98,91.37) UC5.2 ; v1(78.65,18.13) 78.13,18.64 C263.2 ; v1(97.39,56.73) 97.12,56.73 96.87,56.98 PR244.2 ; AC63.1 v1(5.48,95.6) ; PR122.1 v1(36.54,25.89) ; SC33.2 v1(73.25,77.83) ; AC50.1 v1(2.24,104.33)
  TOP w0.508: v1(65.76,8.74) 64.71,8.74 64.29,9.15 PQ36.2 ; 86.94,100.26 J125.19 87.66,100.97 ; v1(108.4,99.09) 108.4,97.85 107.76,97.21 PU1.2 v1(107.03,99.09) ; DCB21.2 DCB1.2 32.9,32.73 v1(32.96,32.68) ; SR62.2 78.99,77.62 v1(79.23,77.86) ; v1(88.02,78.03) 88.54,78.55 F3U1.4 ; PQ35.2 70.89,14.68 v1(71.49,15.27) ; PC8.2 v1(103.22,98.26) ; LC16.2 39.84,99.63 v1(39.97,99.75) ; AD1.2 v1(19.35,108.87) ; E69.4 v1(62.1,2.24) ; PC11.2 v1(102.01,101.28) ; XBT1.4 7.52,36.83 v1(7.76,36.59) ; v1(24.72,103.59) 24.47,103.35 AC54.2 ; v1(19.19,107.02) 19.35,106.86 AD2.2 ; XBT1.3 7.52,32.85 v1(7.79,33.12) ; v1(94.37,55.62) 93.68,55.62 93.41,55.9 Y12.4 ; v1(38.34,75.58) 38.86,76.1 PCE1.2 ; PJ1.2_1 106.78,115.9 ; PJ1.2_1 104.6,115.9 ; PJ1.2_1 105.69,114.11 ; PJ1.2_1 105.69,117.69 ; v1(63.54,15.04) 63.54,15.04 63.54,14.88 PQ33.2 ; v1(98.06,14.28) 98.06,13.8 98.38,13.49 CB12.2 ; v1(111.69,95.34) 112.77,94.26 P13.8 ; PC67.2 20.03,28.48 19.8,28.25 18.37,28.25 v1(18.18,28.44) ; MQ3.2 89.96,93.09 v1(90.54,92.5) ; PC10.2 v1(102.01,104.83) ; PC2.2 75.3,9.46 74.9,9.86 74.9,10.56 v1(74.6,10.85) ; 89.16,104.53 J125.16 87.73,104.22 ; Q30.2 v1(106.21,12.87) ; CB10.2 v1(108.13,9.04) ; D4.1 v1(2.13,102.92) ; v1(67.87,15.39) 67.59,15.11 PQ38.2 ; v1(17.59,66.86) 17.59,67.04 17,67.63 J56.P6 ; v1(19.75,51.72) 19.75,52.23 PQ12.2 ; AC38.2 v1(18.82,97.34) ; v1(74.26,79.97) 73.87,80.36 PJP16.2 ; v1(15.89,61.1) 15.89,60.82 J56.P3 ; v1(53.18,102.32) 52.88,102.03 C153.2 ; 97.89,119.41 PJ1.2_4 ; PJ1.2_4 96.8,121.2 ; PJ1.2_4 98.98,121.2 ; J219.77 v1(121.15,16.92) ; J56.11 16.33,50.51 v1(16.63,50.81) ; C59.2 73.04,62.37 73.5,62.82 C28.2 ; PC12.1 v1(98.14,107.64) ; PR24.2 v1(95.47,98.6) ; U18.9 v1(70.96,94.01) ; AR37.1 v1(1.94,106.61) 1.57,106.24 v2(1.57,105.77) ; Q32.2 92.49,17.25 v1(92.63,17.38) ; AC40.2 10.98,92.9 v1(10.98,92.9) ; PQ24.2 32.92,22.88 32.84,22.79 v1(32.84,22.25) ; J218.76 51.58,21.59 v1(51.58,21.14) ; v1(61.27,82.27) 61.1,82.44 Q39.2 ; 73.92,114.51 J137.2 74.59,113.84 ; v1(94.14,96.71) MD5.2 ; 105.69,119.41 PJ1.2_3 ; PJ1.2_3 106.78,121.2 ; PJ1.2_3 104.6,121.2 ; v1(6.93,17.36) 6.44,17.84 P110.12 v1(3.05,19.08) ; 97.89,114.24 PJ1.2_2 ; PJ1.2_2 96.92,115.9 ; PJ1.2_2 97.89,117.56 ; PJ1.2_2 98.86,115.9 ; E69.3 v1(61.43,2.24) ; v1(36.09,22.25) 36.29,22.25 PR127.2 ; v1(14.17,74.62) 14.17,75.04 J56.12 17.65,75.71 v3(18.24,75.12) ; AC46.2 16.52,93.62 v1(16.55,93.66) ; MD2.2 78.35,96.74 v1(78.63,96.74) ; v1(29.25,24.35) 29.25,23.94 28.81,23.49 PQ25.2 ; v1(95.79,15.19) Q33.2 ; v1(22.25,37.82) PQ13.2 ; P12.9 85.06,11.85 85.54,12.33 v1(85.54,12.35) 85.54,12.51 85.19,12.85 P12.11 ; v1(41.89,67.04) 41.84,66.99 DCB7.2 ; PR25.2 v1(96.49,98.6) ; PC14.2 v1(96.45,94.69) ; PC66.2 v1(20.45,47.77) ; v1(7.79,33.75) 8.68,33.75 9.16,34.23 XBT1.1 ; 89.16,113.32 J125.2 88.44,114.03 ; v1(76.06,96.61) 75.82,96.85 75.73,96.85 MD3.2 ; v1(63.46,84.22) 63.79,83.89 Q38.2 ; Q31.2 v1(100.36,17.04) ; PR78.2 v1(27.27,54.42) ; v1(95.22,107.64) PR26.1 ; P110.11 v1(3.14,27.78)
  TOP w0.635: J17.10 50.9,108.36 ; J17.10 49.62,110.6 ; J17.10 48.34,108.36 ; J17.10 49.62,106.12 ; 89.16,109.42 J125.8 87.73,109.42 ; J17.11 62.42,116.28 ; J17.11 63.7,114.04 ; J17.11 61.14,114.04 ; J17.11 62.42,111.8 ; 87.66,110.07 J125.5 86.23,110.07 ; J137.8 74.59,110.37 ; 62.42,110.6 J17.9 63.7,108.36 ; 85.11,99.12 J125.24 ; J125.24 84.07,100.7 ; J125.24 85.11,102.28 ; J137.24 70.17,114.39 ; J137.24 71.21,112.56 ; J137.24 70.17,110.74 ; J137.24 69.13,112.56 ; 75.63,106.16 J137.23 ; J137.23 76.67,107.99 ; J137.23 77.71,106.16 ; 85.11,110.79 J125.23 ; J125.23 84.38,112.5 ; J125.23 85.85,112.5 ; J8.16 30.48,111.7 ; J8.16 31.86,110.31 ; J8.16 29.1,110.31 ; J8.16 30.48,108.93 ; J137.22 77.71,115.16 ; J137.22 76.67,113.34 ; J137.22 76.67,116.99 ; J137.22 75.63,115.16 ; 86.23,106.17 J125.11 87.66,106.17 ; J125.25 90.27,112.77 ; J125.25 91.32,114.35 ; J125.25 89.23,114.35 ; J125.25 90.27,115.93 ; J8.15 47.41,110.31 ; J8.15 44.65,110.31 ; J8.15 46.03,111.7 ; J8.15 46.03,108.93 ; J17.12 48.34,114.04 ; J17.12 49.62,111.8 ; J17.12 49.62,116.28 ; J17.12 50.9,114.04 ; J17.4 53.38,108.71 ; J17.4 51.66,108.71 ; J17.4 52.52,107.85 ; J17.4 52.52,109.57 ; 51.66,111.33 J17.8 ; J17.8 52.52,112.19 ; J17.8 53.38,111.33 ; J17.8 52.52,110.47 ; J137.25 71.21,103.06 ; J137.25 70.17,104.89 ; J137.25 69.13,103.06 ; 89.16,105.52 J125.14 87.73,105.52 ; 72.25,108.64 J137.11 ; 72.25,112.1 J137.5
  IN2 w0.254: 13.4,65.64 13.68,65.36 13.68,62.67 v1(14.04,62.32) 14.06,62.32 14.78,61.6 15.69,61.6 15.89,61.4 v1(15.89,61.1) 15.89,58.43 15.44,57.97 v1(14.56,57.97) 13.28,57.97 12.84,58.4 12.84,62.49 12.24,63.1 v1(12.24,63.43) v1(12.24,64.25) 11.77,64.72 11.77,65.46 11.94,65.64 v1(12.22,65.64) 13.4,65.64
  BOTTOM w0.102: 67.33,69.16 67.08,69.41 67.08,69.6 67.22,69.73 67.22,69.96 67.41,70.16 XU1.A35
  BOTTOM w0.114: XU1.A43 63.71,70.05 63.71,69.98 63.71,69.73 64.01,69.43 XU1.C42
  BOTTOM w0.127: 60.5,56.14 60.5,55.84 ; v1(63.07,69.26) 63.33,69.26 63.4,69.19 63.75,69.19 63.79,69.16 XU1.C42 ; 69.03,52.87 69,52.89 68.7,52.89 ; 82.11,64.6 v1(82.11,65.16) ; 69.72,50.05 69.97,50.05 ; 78.58,59.75 78.58,60.03 ; 68.75,64.7 68.98,64.7 ; v1(66.51,52.18) 66.54,52.16 67.07,52.16 ; 82.11,62.65 82.11,62.92 ; 77.84,58.1 77.84,57.79 ; 82.09,61.63 82.11,61.65 82.11,62.01 ; v1(81.48,65.24) 81.4,65.16 81.4,64.6 ; 68.72,52.16 69.03,52.16 ; 64.03,55.18 64.03,54.87 ; 79.95,55.15 79.95,54.9 79.98,54.87 ; 74.9,65.41 74.29,65.41 v1(74.24,65.46) ; 61.89,56.12 61.89,55.86 ; 66.08,50.73 65.83,50.73 ; 66.08,50.02 65.83,50.02 ; 67.76,66.1 68.04,66.1 ; 81.4,63.61 81.4,63.89 ; 66.77,52.89 66.79,52.87 67.1,52.87 ; 61.18,55.15 61.18,54.9 ; 80.69,64.53 80.69,64.91 ; 67.05,49.31 66.82,49.31 ; 61.18,56.12 61.18,55.84 ; 60.5,55.18 60.5,54.85 ; 61.89,55.18 61.89,54.87 ; 66.11,49.31 65.83,49.31 ; 68.72,68.23 69.03,68.23 ; 67.07,50.02 66.79,50.02 ; 64.74,57.84 64.74,58.1
  BOTTOM w0.152: v1(73.46,71.1) 73.24,70.88 XU1.A23 ; 75.24,48.63 76.14,48.63
  BOTTOM w0.178: 68.12,52.87 67.69,52.87 ; 67.69,50.75 68.33,50.75 ; U24.91 77.32,25.92 77.5,26.09 v1(77.5,26.51) ; v1(79.34,13.9) 79.84,13.4 U24.122 ; 71.55,51.45 72.12,51.45 ; 78.57,63.04 78.57,62.6 ; 72.5,50.03 72.97,50.03 ; 77.85,62.6 77.85,63.04 ; 70.44,51.45 71.08,51.45 ; 77.85,61.6 77.85,62.07 ; 72.47,50.75 72.97,50.75 ; 78.55,61.22 78.55,60.68 ; 67.67,52.17 68.06,52.17 ; 67.67,51.45 68.1,51.45 ; XU1.AY10 79.66,51.07 80.31,51.07 XU1.AY9 ; 79.27,62.98 79.27,62.59 ; 75.48,65.39 76.09,65.39 ; 79.97,59.3 79.97,58.73 ; 75.48,64.68 76.14,64.68 ; 74.46,52.17 74.93,52.17 ; 79.99,63.05 79.99,62.59 ; 71.51,50.73 72.09,50.73 ; 74.96,51.45 74.46,51.45 ; 79.29,63.62 79.29,65.37 ; 81.41,63.11 81.41,62.6 ; 80.69,63.11 80.69,62.57 ; 80.71,59.73 80.71,60.02 ; 79.97,62.03 79.97,61.6 ; 71.41,52.17 72.02,52.17 ; 70.68,52.86 70.97,52.86 ; 74.58,50.75 74.94,50.75 ; 74.57,52.89 74.85,52.89 ; 79.27,59.03 79.27,58.74 ; 70.4,52.17 71.05,52.17
  BOTTOM w0.203: U24.27 68.92,10.22 v1(68.29,10.84) ; XU1.BJ35 67.41,46.61 66.87,46.07 66.87,46.07 v1(66.86,46.07) ; U24.1 79.32,8.23 v1(79.46,8.1) ; 75.52,49.32 76.78,49.32 ; XU1.A11 79.07,70.56 v1(79.26,70.74) ; 70.9,53.82 70.9,53.95 70.91,53.96 70.91,54.53 XU1.AM29 ; 78.56,58.78 78.56,59.35 ; 80.78,66.88 80.78,66.88 80.78,66 80.62,65.84 ; v1(64.13,17.4) U24.49 ; XU1.AM25 72.14,54.81 72.35,54.81 72.35,54.81 72.63,54.81 72.64,54.81 72.73,54.81 XU1.AM24 ; 75.51,50.03 76.78,50.03 ; U24.113 79.9,17.01 v1(79.16,17.75) ; 77.85,55.16 77.85,54.87
  BOTTOM w0.222: v1(13.05,79.94) 12.94,79.83 PU8.14 ; PU8.1 13.34,75.64 14.17,74.81 v1(14.17,74.62) ; v1(11.32,80.02) 11.74,79.6 PU8.11
  BOTTOM w0.229: PU8.3 12.54,75.29 12.25,75.01 v1(12.25,74.99)
  BOTTOM w0.254: XU1.P24 72.62,63.62 72.34,63.34 v1(72.22,63.34) ; XU1.AJ21 74.33,56.44 v1(74.71,56.07) ; v1(63.52,46.03) 63.52,46.61 XU1.BJ43 ; XU1.AA32 69.28,60.13 69.28,60.1 v1(69.39,59.99) ; XU1.BJ15 77.12,46.61 77.12,45.91 v1(77.09,45.87) ; v1(57.8,50.51) 57.93,50.51 58.07,50.65 58.23,50.65 58.23,50.65 XU1.BA53 ; C248.2 13.64,59.88 14.91,59.88 15.4,59.39 15.4,58.98 14.56,58.15 v1(14.56,57.97) ; v1(63.57,70.8) 63.57,70.28 XU1.A43 ; XU1.AG25 71.93,57.12 71.93,57.1 v1(71.68,56.85) ; v1(57.93,56.48) XU1.AJ53 ; v1(66.38,57.64) 66.75,57.27 XU1.AG36 ; XU1.A15 77.13,70.65 v1(77.47,70.99) ; v1(67.89,59.22) 68.27,58.84 XU1.AD33 ; v1(67.89,59.22) 68.27,59.6 XU1.AC33 ; v1(67.89,59.22) 67.51,59.59 XU1.AC35 ; XU1.A27 71.3,70.25 71.3,70.59 71.3,70.6 71.3,70.92 v1(71.09,71.13) ; v1(71.68,56.85) 71.68,56.84 XU1.AJ25 ; v1(71.68,56.85) 71.68,56.87 ; v1(84.94,56.65) 84.77,56.48 XU1.AJ1 ; v1(57.85,60.37) XU1.AA53 ; v1(60.2,69.11) 60.24,69.07 XU1.C49 ; XU1.AH7 81.05,56.74 v1(80.81,56.5) 80.34,56.97 XU1.AH9 ; XU1.AV7 81.05,51.9 v1(80.71,51.56) 80.52,51.36 80.52,51.29 XU1.AY9 ; v1(57.89,48.43) XU1.BE53 ; XU1.BA40 64.97,50.38 64.57,49.98 v1(64.53,49.98) 64.29,49.98 XU1.BC42 ; XU1.AT47 61.55,53.06 61.89,52.71 v1(61.89,52.61) ; XU1.AE53 v1(57.83,58.43) ; XU1.AW3 83.33,51.58 v1(82.75,51.58) 82.75,51.42 XU1.AY4 ; v1(57.93,51.88) 57.93,52.6 58.41,53.08 XU1.AT52 ; XU1.AU51 59.27,52.63 v1(59.83,52.63) 59.83,52.37 XU1.AV51 ; v1(67.23,70.85) 67.41,70.67 67.41,70.24 XU1.A35 ; XU1.BF12 78.2,47.88 v1(78.1,47.88) ; v1(80.76,49.65) 80.62,49.52 XU1.BE8 ; v1(84.79,64.08) 84.61,64.26 XU1.N1 ; v1(75.41,71.1) 75.19,70.88 XU1.A19 ; v1(71.68,59.21) 71.68,59.22 XU1.AC25 ; XU1.BJ19 75.23,46.57 v1(75.23,45.97) ; v1(59.89,51.57) 59.89,51.38 XU1.AY50 ; XU1.J1 84.64,66.24 v1(84.78,66.1) ; XU1.BG45 62.6,47.66 v1(62.32,47.94) ; XU1.P47 61.95,64.17 v1(61.95,64.28) 61.95,64.35 XU1.M47 ; v1(82.66,57.58) 82.44,57.36 XU1.AH4 82.43,56.99 82.36,56.99 82.33,57.02 81.91,57.02 81.87,56.99 81.77,56.99 XU1.AH6 ; XU1.A49 60.17,70.37 60.17,70.53 59.39,71.31 59.37,71.31 59.23,71.46 v1(58.87,71.46) ; XU1.AB51 59.57,60.03 v1(59.86,60.32) 60.01,60.16 60.01,60.02 XU1.AB50 ; 77.21,49.96 77.21,49.97 XU1.BA14 ; XU1.BJ7 81.09,46.44 v1(81.09,45.53) ; XU1.AJ3 82.83,56.48 v1(82.8,56.45) ; v1(57.78,66.2) XU1.J53 ; v1(61.92,51.6) 61.55,51.97 XU1.AV47 ; v1(84.85,49.51) 84.56,49.81 XU1.BC1 83.78,49.81 XU1.BC2 ; v1(60.72,48.52) XU1.BG49 ; XU1.BG39 XU1.BJ39 v1(65.47,46.03) ; v1(84.65,52.58) 84.64,52.59 XU1.AU1 84,52.71 83.48,52.71 XU1.AU3 82.93,52.59 XU1.AT4 ; XU1.BE2 83.4,48.26 XU1.BF4 ; XU1.BG42 63.82,47.7 63.57,47.94 v1(63.44,47.94) ; XU1.BJ11 79.07,46.17 79.27,45.97 v1(79.27,45.65) ; XU1.C45 62.8,69.26 v1(63.07,69.26) ; XU1.G42 64.05,67.18 v1(64.39,66.83) 64.76,66.47 XU1.J40 ; XU1.Y25 v1(71.68,60.79) ; XU1.V35 v1(67.9,61.57) 68.27,61.2 XU1.Y33 67.96,60.87 67.96,60.84 XU1.AA35 ; XU1.AF25 71.68,58.41 v1(71.68,58.43) 71.68,58.44 71.91,58.67 XU1.AD25 ; XU1.A47 61.68,70.74 v1(61.76,70.83) ; v1(57.82,62.31) XU1.U53
  BOTTOM w0.279: J134.28 57.41,9.93 57.21,9.72 v1(57.08,9.72)
  BOTTOM w0.305: XU1.BJ49 v1(60.31,46.01) ; XU1.BE2 83.57,48.43 XU1.BE1 84.71,48.43 v1(84.92,48.22) ; XU1.AF32 69.17,58.18 69.42,58.42 v1(69.42,58.43) XU1.AD32 ; v1(66.38,57.64) XU1.AG38 ; J134.27 58.41,23.83 v1(58.46,23.89) ; XU1.AM19 v1(75.48,55.29) ; v1(105.94,47.68) UU1.3 UU1.8 v1(107.92,47.68) ; v1(57.61,69.19) 57.61,69.13 58.32,68.42 XU1.E53 ; XU1.BJ47 v1(61.68,46.03)
  BOTTOM w0.356: v1(89.37,29.07) 89.62,29.31 TPU1.11 ; XMM1.134 v1(33.24,51.28) ; XMM1.161 v1(38.36,43.18) ; XMM1.189 38.56,34.78 v1(38.36,34.58) ; XMM1.168 v1(33.24,41.08) ; v1(38.28,35.92) 38.34,35.98 XMM1.185 ; v1(32.97,93.51) 32.74,93.28 XMM1.2 ; XMM1.172 v1(33.24,39.88) ; v1(38.32,39.99) 38.73,39.58 XMM1.173 ; XMM1.150 33.02,46.48 v1(33.24,46.26) ; XMM1.32 v1(32.92,84.28) ; XMM1.25 v1(38.36,86.38) ; TPU1.25 85.07,25.24 v1(84.73,24.9) ; XMM1.13 v1(38.34,89.98) ; v1(33.24,48.45) 33.22,48.45 33.05,48.28 XMM1.144 ; XMM1.60 v1(32.96,75.88) ; U14.1 100.92,41.5 100.34,40.92 CB6.2 ; v1(89.02,27.24) 89.27,27.24 89.62,26.89 TPU1.18 ; XMM1.43 v1(38.34,80.98) ; XMM1.128 v1(32.93,53.08) ; TPU1.4 85.07,29.61 v1(84.64,29.18) ; XMM1.151 38.51,46.18 v1(38.35,46.03) ; XMM1.190 32.76,34.48 v1(33.01,34.73) ; XMM1.8 v1(32.93,91.48) ; XMM1.179 38.49,37.78 v1(38.34,37.93) ; XMM1.72 v1(32.92,72.28) ; XMM1.14 v1(32.93,89.68) ; v1(38.35,53.58) 38.55,53.38 XMM1.127 ; v1(38.36,82.84) 38.41,82.78 XMM1.37 ; v1(50.94,7.08) 50.94,6.56 50.88,6.49 PQ18.1 ; XMM1.49 v1(38.36,79.18) ; v1(38.29,93.11) 38.42,92.98 XMM1.3 ; XMM1.55 38.5,77.38 v1(38.36,77.52) ; XMM1.20 v1(32.92,87.88) ; XMM1.167 v1(38.34,41.38) ; XMM1.38 v1(32.93,82.48) ; XMM1.9 38.46,91.18 38.4,91.12 v1(38.36,91.12) ; XMM1.54 v1(32.92,77.68) ; XMM1.195 38.41,32.98 v1(38.36,33.03) ; v1(54.07,2.88) 53.51,2.88 53.29,3.1 WQ6.1 ; XMM1.61 v1(38.34,75.58) ; v1(38.36,49.62) 38.51,49.78 XMM1.139 ; XMM1.48 v1(32.93,79.48) ; XMM1.155 v1(38.36,44.98) ; v1(19.86,35.26) 19.47,34.88 U1.2 ; v1(20.98,18.33) 20.75,18.56 PQ15.1 ; v1(33.88,36.84) 33.88,36.59 33.57,36.28 XMM1.184 ; XMM1.66 v1(32.93,74.08) ; XMM1.133 v1(38.36,51.58) ; XMM1.44 v1(32.92,80.68) ; XMM1.196 v1(32.96,32.68) ; v1(33.28,42.89) 33.29,42.89 33.29,42.88 XMM1.162 ; XMM1.31 38.5,84.58 v1(38.34,84.41) ; v1(82.94,5.25) 82.82,5.38 D32.2 ; XMM1.145 v1(38.36,47.98) ; v1(33.3,50.11) 33.29,50.1 33.29,50.08 XMM1.138 ; v1(38.36,88.32) 38.5,88.18 XMM1.19 ; XMM1.156 33.36,44.68 v1(33.39,44.71) ; XMM1.178 v1(33.24,38.08) ; XMM1.65 v1(38.36,74.38) ; XMM1.71 v1(38.34,72.58) ; XMM1.26 v1(32.93,86.08)
  BOTTOM w0.381: v1(63.72,94.42) 63.49,94.42 62.92,93.85 LQ3.2 ; v1(54.09,25.82) 53.92,25.82 52.94,24.84 PQ21.1
  BOTTOM w0.406: v1(50.17,1.85) 50.23,1.8 WQ6.4 ; v1(60.5,25.56) 60.5,25.1 60.22,24.83 J134.29 ; J134.30 59.91,9.84 59.81,9.94 v1(59.81,9.94)
  BOTTOM w0.432: v1(21.1,36.84) 21.19,36.93 C3.2 ; v1(20.41,59.11) SC36.2 SC67.2 ; PR190.2 102.24,54.38 102.24,53.36 v1(101.73,52.85) ; C254.2 14.18,57.59 v1(14.56,57.97) ; C253.2 3.99,60.56 3.87,60.69 C252.2 ; v1(8.83,42.73) 8.27,42.17 6.8,42.17 5.99,42.99 SC2.2 ; C249.2 12.63,63.43 v1(12.24,63.43) ; SR24.1 91.55,52.86 v1(91.97,52.43) ; v1(99.23,41.03) 99.8,41.03 CB6.2 ; v1(9.36,62.94) 9.38,62.94 9.36,62.92 C256.2 ; C245.2 12.71,64.4 12.39,64.4 v1(12.24,64.25) ; C251.2 3.55,57.53 3.55,57.72 v1(3.55,57.72) ; v1(21.89,35.47) 21.89,35.38 SC7.2 ; v1(12.32,59.36) 12.34,59.37 C248.2 ; SR32.1 SR26.1 ; PC79.2 62.81,30.35 62.95,30.35 v1(63.34,29.96) ; C257.2 8.48,62.92 v1(8.5,62.95) ; C250.2 v1(3.99,54.85) ; C240.2 8.29,46.06 v1(9.03,46.06) ; v1(46.8,10.68) 47.08,10.96
  BOTTOM w0.457: v1(7.83,77.33) PC112.1 ; DEC5.2 66.1,92.97 v1(66.54,92.97) ; v1(70.2,83.24) DEC8.2 DEC9.2 ; R19.1 v1(59.25,85.15) ; HC11.2 v1(85.59,17.46) ; PC163.2 100.23,70.32 v1(99.89,70.32) ; PC78.2 v1(60.44,32.53) ; v1(15.38,34.89) 15.76,35.27 PR38.1 ; PR133.1 46.11,21.4 v1(46.47,21.4) ; OP1R3.1 5.92,52.47 5.68,52.23 v1(4.95,52.23) ; SR61.2 SR59.2 78.21,77.5 v1(78.05,77.67) ; v1(87.89,76.28) 87.73,76.28 87.5,76.51 SC6.2 ; v1(39.31,17.49) 39.11,17.28 PC53.2 ; SR21.1 91.52,54.75 91.55,54.72 SR24.1 ; v1(12.46,26.06) 12.46,26.24 PC45.2 ; PR160.2 13.17,82.28 ; R21.1 66.77,82.08 v1(66.16,81.47) 65.98,81.64 65.98,81.95 65.88,82.05 DEC4.2 ; v1(82.67,78.11) 82.77,78.02 C941162.2 SR46.2 ; LANC1.2 v1(28.29,107.01) ; v1(94.95,58.48) PC145.2 ; v1(80.07,77.85) 80.03,77.85 80.03,77.83 80.14,77.72 80.14,77.46 80.15,77.45 SR60.2 ; v1(95.02,15.33) 94.58,15.76 PC56.2 ; UC7.2 64.13,101.79 v1(64.08,101.74) ; PC75.2 54.58,37.6 v1(56.02,39.05) ; CB2.2 v1(88.18,23.26) TPC1.2 ; v1(7.31,52.89) 7.31,52.89 7.73,52.47 C302.1 ; v1(94.37,55.62) 93.93,55.62 93.4,56.16 PR224.1 ; PR115.2 69.17,32.04 v1(69.17,31.66) ; SR11.1 SR10.1 47.97,28.91 v1(47.94,28.88) ; v1(63.59,99.93) 64.05,100.39 UC6.2 ; R200.1 6.02,60.75 v1(5.81,60.54) ; v1(94.86,63.59) 94.7,63.42 94.25,63.42 PC137.2 ; v1(55.73,9.77) 55.55,9.58 PC72.2 55.12,8.82 PR97.2 ; SR172.2 86,75.5 v1(85.69,75.8) 85.59,75.8 85.51,75.73 85.29,75.73 85.08,75.52 SC4.2 ; M1C14.2 v1(89.41,98.36) ; SR184.2 90.94,68.98 90.39,69.53 v1(88.8,69.53) ; SR4.2 71.72,97.47 71.38,97.13 v1(71.38,96.4) ; v1(79.38,43.53) 79.38,43.23 79.05,42.9 HC13.2 ; PU4.8 46.09,10.85 46.56,11.32 PR56.2 47.11,10.98 47.08,10.96 ; TPC3.2 85.31,36.25 v1(85.3,36.26) ; PC146.2 95.43,54.12 95.55,54.01 v1(95.55,53.91) ; v1(69.44,89.95) 69.44,89.98 69.51,90.05 C4.2 ; v1(52.95,91.05) 52.95,91.37 52.67,91.65 LC1.2 ; TPC2.2 88.87,35.8 v1(88.49,36.18) 88.49,36.17 88.21,35.9 88.21,35.57 87.98,35.34 TPR5.2 ; HC2.2 47.21,32.27 v1(46.7,31.76) 46.19,32.27 SR7.2 ; PR189.2 103.34,65.67 v1(103.24,65.77) ; C5.2 69.76,87.56 69.66,87.66 v1(69.5,87.66) ; PC125.2 v1(106.52,60.77) ; LR2.2 v1(48.72,93.74) ; v1(91.56,58.5) 91.56,58.07 91.38,57.9 SR26.1 SR22.1 ; LC2.2 v1(48.24,92.9) ; SR33.1 91.41,59.62 91.52,59.51 v1(91.52,59.14) ; SR159.2 79.27,77.56 79.23,77.59 v1(79.23,77.86) ; PC169.2 100.18,65.36 98.84,65.36 98.74,65.46 v1(98.57,65.46) ; PC51.2 38,12.54 37.61,12.15 v1(37.6,12.15) ; v1(49.19,28.75) 49.19,28.77 48.99,28.97 HC10.2 ; SR8.2 45.18,32.01 v1(44.8,31.63) ; v1(97.39,56.73) 97.82,56.73 PC153.2 ; PC114.2 v1(7.73,78.16) ; C272.2 v1(93.4,11.22) ; v1(81.02,77.9) 81.02,77.66 80.99,77.63 SR158.2 ; v1(103.83,17.41) 103.83,17.83 PR65.2 ; v1(8.87,44.7) 8.04,43.87 C1.2 ; C160.2 58.38,95.06 58.91,95.59 v1(58.91,96.11) ; PC69.2 28.61,17.55 v1(28.92,17.23) ; UC8.2 v1(63.85,104.07) ; v1(10.52,27.15) 10.51,27.15 10.51,26.88 10.75,26.64 PC32.2 ; MCB1.2 v1(76.05,100.9) ; PC58.2 v1(94.58,23.36) ; LC17.2 v1(29.3,104.95) ; C267.2 v1(76.22,5.38) ; PC59.2 93.55,18.88 v1(93.03,18.88) ; v1(46.47,22.06) 46.45,22.03 PC94.2 ; PR50.1 PC47.2 19.69,31.81 v1(19.54,31.66) ; v1(91.79,23.26) CB3.2 ; v1(101.73,52.85) PR209.2 PC147.2 ; v1(60.44,37.65) 60.36,37.56 PC81.2 ; TPC4.2 v1(85.69,22.65) ; PRT2.1 v1(106.26,95.44) ; 41.92,8.57 42.96,8.57 v1(43.22,8.84) ; HC14.2 v1(77.69,5.38) ; O2R251.2 63.85,29.55 63.97,29.68 v1(63.97,29.9) ; v1(54.91,11.36) 54.91,11.24 55.12,11.02 PC71.2 ; C2.2 20.27,30.38 v1(19.55,30.38) ; PR39.2 17.63,31.75 17.21,31.33 v1(17.06,31.33) ; TPR2.2 87.09,35.65 87.34,35.9 v1(87.34,36.25) ; v1(85.51,77.66) SC5.2 ; PR88.2 25.49,14.92 23.73,13.16 v1(23.32,13.16) ; C163.2 59.46,97.98 v1(59.58,98.09) ; PR36.2 17.52,36.07 PC35.2 17.92,36.47 v1(17.92,36.89) ; v1(87.63,12.26) 87.48,12.4 87.48,12.77 87.24,13.01 SC23.2 ; v1(51.5,33.69) 51.5,34.9 51.97,35.37 PR105.2 ; DEC1.2 61.35,90.65 v1(61.43,90.74) ; PC73.2 52.09,6.21 51.73,6.56 v1(51.73,7.1) ; PC70.2 16.95,19.02 17.11,18.86 v1(17.49,18.86) ; v1(50.56,15.45) 50.56,15.74 PC99.2 ; v1(102.91,67.65) 102.91,67.48 PR226.2 ; R20.1 v1(59.25,86.17) ; v1(10.46,75.7) 10.29,75.54 PR159.2 ; SR9.1 v1(43.53,32.28) ; SC8.2 15.93,64.36 16.35,63.94 v1(16.73,63.94) ; UC9.2 v1(64.08,102.68) ; R22.2 v1(68.17,93.86) ; SR6.2 49.06,33.76 v1(49.12,33.82) ; v1(74.01,5.38) 73.6,5.38 SC25.2 ; R97.1 v1(58.91,96.96) ; PC123.2 v1(106.52,59.37) ; C15.2 v1(83.02,43.44)
  BOTTOM w0.483: v1(63.55,102.17) U19.2 v1(61.72,102.17) ; v1(107.41,74.48) UU2.2
  BOTTOM w0.508: J133.12 121.34,45.07 ; J133.12 117.88,45.07 ; J133.12 119.61,43.8 ; v1(79.11,92.8) 79.37,92.54 MQ34.2 ; PQ43.2 105.31,69.96 v1(105.19,69.84) ; PJ1.2_1 106.87,115.9 ; PJ1.2_1 105.69,117.78 ; PJ1.2_1 105.69,114.02 ; PJ1.2_1 104.51,115.9 ; v1(37.51,15.7) 37.51,15.2 37.88,14.83 PC52.2 ; 96.84,115.9 PJ1.2_2 ; PJ1.2_2 98.94,115.9 ; PJ1.2_2 97.89,114.15 ; PJ1.2_2 97.89,117.65 ; v1(16.53,61.07) 16.77,60.83 Q1.2 ; MQ8.2 19.13,66.91 v1(19.63,66.91) ; v1(86.89,41.59) 86.98,41.5 C65.2 ; v1(47.59,19.22) 47.59,19.22 47.59,18.86 46.82,18.09 PC93.2 ; MQ22.2 v1(26.22,60.95) ; C64.2 86.98,43.33 86.96,43.34 v1(86.96,43.35) ; SC24.2 71.59,5.36 v1(71.67,5.36) ; PC136.2 109.49,56.36 v1(109.69,56.56) ; 117.88,57.87 J133.13 ; J133.13 121.34,57.87 ; J133.13 119.61,59.14 ; v1(65.35,29.71) 64.74,29.1 O2R252.2 ; 117.06,78.83 J11.6 ; J11.6 120.11,78.83 ; J11.6 118.59,80.1 ; v1(60.11,83.63) 60.76,84.27 61.43,84.27 61.88,83.82 DEC3.2 ; D33.1 79.15,0.91 v1(79.3,0.76) ; v1(11.9,85.28) 12.03,85.28 13,84.31 13,82.46 13.17,82.28 ; MQ6.2 25.22,37.6 v3(25.24,37.63) ; v1(51.73,16.27) 51.39,16.27 51.19,16.47 PQ28.2 ; UC12.2 v1(102.96,73.97) ; PJ1.2_4 99.07,121.2 ; PJ1.2_4 97.89,119.32 ; PJ1.2_4 96.71,121.2 ; PQ32.2 101.62,51.29 v1(101.54,51.22) ; v1(48.63,24.6) 48.04,25.19 Q9415.2 ; 104.51,121.2 PJ1.2_3 ; PJ1.2_3 106.87,121.2 ; PJ1.2_3 105.69,119.32 ; v1(108.22,72.25) 108.61,71.86 PQ44.2 ; v1(58.11,89.09) 58.35,89.33 DEC2.2 ; UC14.2 v1(102.96,76.01) ; v1(69.58,29.72) 69.78,29.92 JP4.1 ; v1(99.76,17.56) 99.15,18.17 PU5.9 v1(99.15,22.03) ; 117.06,66.03 J11.5 ; J11.5 120.11,66.03 ; J11.5 118.59,64.76 ; Y24.2 75.18,87.5 v1(75.4,87.73) ; v1(51.5,33.69) 51.5,31.45 51.47,31.42 PQ22.2 ; v1(85.56,11.46) 85.41,11.31 85.41,10.93 84.4,9.91 C260.2 ; J125.25 90.27,116.09 ; J125.25 90.27,112.61 ; J125.25 89.07,114.35 ; J125.25 91.48,114.35 ; R225.2 81.15,5.38 v1(81.22,5.31) ; PC161.2 102.33,71.38 102.91,71.96 v1(102.96,71.96) ; MQ32.2 17.94,50.92 v1(17.62,51.24) ; v1(28.12,99.28) XMM1.207 v1(20.56,99.28) ; PU7.4 38.16,22.15 v1(38.5,22.49) ; v1(47.67,15.5) 47.67,15.16 PC49.2 ; AD3.2 v1(26.76,105.98) ; MQ7.2 v1(26.23,33.39) ; v1(105.28,65.8) 106.52,65.8 106.66,65.94 PC141.2 ; 112.49,64.76 J11.7 ; J11.7 112.49,67.3 ; J11.7 114.47,66.03 ; PQ27.2 48,18.12 48.23,18.35 v1(48.23,19.36) ; 112.49,80.1 J11.8 114.47,78.83 ; v1(3.55,62.05) 3.55,61.54 C252.2 ; FC2.2 6.08,24.44 v1(5.81,24.44) ; Y24.4 72.65,90.34 73.27,90.96 v1(73.42,90.96) ; PC48.2 48.61,15.42 v1(48.51,15.51) ; v1(55.97,23.89) 55.64,23.55 PC76.2 ; MQ5.2 v1(26.75,70.99) ; v1(4.62,15.25) 3.21,15.25 P70.5 ; MQ1.2 v1(72.51,95.21) ; P70.3 3.66,18.49 v1(3.14,17.97) ; Y10.4 51.82,91.54 52.29,91.07 52.31,91.07 52.31,91.07 52.31,91.08 52.32,91.08 52.32,91.08 v1(52.32,91.08) ; Q9.2 v1(26.26,64.26) ; v1(44.74,24.54) 44.74,24.54 Q41.2 ; MQ36.2 v1(78.3,101.09) ; FC3.2 9.36,24.16 v1(9.93,24.16) ; v1(65.68,36.15) 64.48,34.96 PU6.9 ; C255.2 v1(10.51,63.87) ; PC80.2 v1(58.67,35.78) ; U14.9 v1(103.85,39.33) ; PR138.2 46.31,19.6 v1(47.06,19.6) ; PQ16.2 21.59,17.27 21.83,17.51 21.83,18.07 21.61,18.3 v1(21.61,18.3) ; v1(28.12,24.22) 26.61,24.22 26.25,24.58 XMM1.208 24.14,24.37 v1(20.21,24.37) ; v1(11.9,84.51) 12.29,84.13 12.29,82.86 12.03,82.61 PC104.1 ; v1(103.17,17.41) 102.74,17.84 PU5.8 ; PU6.8 68.09,32.06 v1(68.47,31.69) ; PRT1.2 108.73,38.79 v1(109.49,39.56) ; CB1.2 82.51,35.23 83.48,36.2 v1(83.96,36.2) ; UC13.2 v1(102.96,72.83) ; Q9416.2 v1(23.39,81.02) ; v1(14.6,37.52) 14.78,37.69 PC40.2 ; Y10.2 47.27,89.94 46.94,90.27 46.94,90.26 v1(46.93,90.26) ; MQ25.2 v1(26.81,67.56) ; v1(66.57,78.65) 65.97,79.24 R60290.1 ; PCB1.2 9.36,64.07 v1(9.54,63.89) ; SR41.2 v1(86.96,75.65) ; SC65.2 22.41,53.13 22.75,53.48 24.76,53.48 25.62,52.61 ; AD4.2 v1(26.06,106.94) ; MQ23.2 v1(26.12,57.65) ; Q2.2 v1(19.78,57.52) ; C246.2 v1(12.22,67.51) ; v1(49.67,9.31) 49.63,9.26 PQ19.2 ; PQ41.2 v1(106.32,51.29) ; MQ31.2 v1(17.72,54.22) ; MD1.2 v1(72.17,99.32) ; MQ9.2 v1(19.83,64.13) ; v1(92.39,18.65) 92.07,18.65 91.66,19.06 U25.4 ; UC15.2 v1(102.96,74.86) ; Q9414.2 v1(26.75,74.29) ; PC57.2 93.28,19.81 v1(92.98,19.52)
  BOTTOM w0.635: J17.12 48.25,114.04 ; J17.12 49.62,116.36 ; J17.12 50.99,114.04 ; J17.12 49.62,111.72 ; J17.11 61.05,114.04 ; J17.11 63.79,114.04 ; J17.11 62.42,111.72 ; J17.11 62.42,116.36 ; J8.15 46.03,111.86 ; J8.15 46.03,108.76 ; J8.15 47.58,110.31 ; J8.15 44.48,110.31 ; 48.25,108.36 J17.10 ; J17.10 49.62,110.68 ; J17.10 49.62,106.04 ; J17.10 50.99,108.36 ; 70.17,101.07 J137.25 ; J137.25 71.38,103.06 ; J137.25 70.17,105.06 ; J137.25 68.96,103.06 ; 62.42,106.04 J17.9 ; J17.9 62.42,110.68 ; J17.9 63.79,108.36 ; J17.9 61.05,108.36
  vias: v1(0.84,113.69) v1(0.76,111.15) v1(0.76,108.86) v1(0.76,106.07) v1(0.76,103.53) v1(0.76,100.99) v1(0.76,98.45) v1(0.76,95.91) v1(0.76,93.37) v1(0.76,90.83) v1(0.76,88.29) v1(0.76,85.75) v1(0.76,38.72) v1(0.76,36.18) v1(0.76,33.64) v1(0.76,31.1) v1(0.76,28.56) v1(0.76,26.02) v1(0.76,23.48) v1(0.76,20.94) v1(0.76,18.4) v1(0.76,15.86) v1(0.76,13.32) v1(0.76,10.78) v1(0.93,8.24) v1(1.51,116.14) v1(1.76,79.96) v1(1.76,77.42) v1(1.76,72.34) v1(1.76,69.8) v1(1.76,67.26) v1(1.76,64.72) v1(1.76,62.18) v1(1.76,59.64) v1(1.76,57.1) v1(1.76,54.56) v1(1.76,52.02) v1(1.76,46.94) v1(1.76,44.4) v1(1.75,5.84) v1(2.71,84.14) v1(2.84,118.31) v1(2.95,39.99) v1(3.01,21.98) v1(3.47,42.5) v1(3.59,81.7) v1(3.73,5.37) v1(4.46,117.89) v1(4.95,54.16) v1(5.45,4.33) v1(6.8,2.93) v1(7.48,1.11) v1(7.64,121.42) v1(7.76,35.02) v1(7.79,34.39) v1(8.4,35.06) v1(8.7,50.56) v1(9,48.97) v1(9.42,121.72) v1(10,0.76) v1(10.51,71.74) v1(10.72,0.76) v1(11.02,21.95) v1(11.14,71.77) v1(11.68,21.95) v1(11.96,121.74) v1(12.31,21.95) v1(13.26,0.76) v1(14.5,121.74) v1(15.8,0.76) v1(17.04,121.74) v1(17.85,47.71) v1(18.34,0.76) v1(19.3,47.69) v1(19.58,121.74) v1(20.88,0.76) v1(22.12,121.74) v1(22.67,39.46) v1(23.42,0.76) v1(24.66,121.74) v1(25.96,0.76) v1(26.7,77.54) v1(27.2,121.74) v1(28.5,0.76) v1(29.4,120.54) v1(29.74,121.74) v1(29.72,69.05) v1(29.72,68.41) v1(29.68,66.86) v1(29.72,65.21) v1(29.68,58.02) v1(29.68,57.39) v1(30.07,63.31) v1(30.16,88.55) v1(30.16,87.88) v1(30.16,61.4) v1(31.04,0.76) v1(31.18,28.99) v1(32.07,29) v1(32.28,121.74) v1(33.56,22.25) v1(33.82,118.37) v1(33.82,108.71) v1(34.82,121.74) v1(34.84,22.25) v1(36.11,110.99) v1(36.12,0.76) v1(37.23,28.99) v1(37.3,0.77) v1(37.36,121.74) v1(37.94,0.77) v1(38,115.76) v1(38.66,0.76) v1(38.83,112.57) v1(39.06,110.17) v1(39.9,121.74) v1(40.88,108.43) v1(41,115.69) v1(41.22,14.89) v1(41.2,0.76) v1(41.59,79.99) v1(41.9,76.99) v1(41.92,75.51) v1(41.88,63.58) v1(41.88,59.98) v1(42.14,119.23) v1(42.44,121.74) v1(43.02,14.94) v1(43.02,10.45) v1(43.38,5.19) v1(43.54,75.51) v1(43.68,10.47) v1(43.71,1.46) v1(43.74,0.76) v1(44.16,5.17) v1(44.35,1.46) v1(44.98,121.74) v1(44.99,1.43) v1(46.28,0.76) v1(46.58,5.17) v1(46.74,119.88) v1(47.11,116.12) v1(47.21,5.17) v1(47.77,97.74) v1(48.51,54.62) v1(48.82,0.76) v1(49.12,120.78) v1(49.43,118.05) v1(49.57,21.4) v1(51.31,86.29) v1(51.48,121.74) v1(51.48,120.1) v1(51.74,81.68) v1(53.13,93.51) v1(53.36,46.85) v1(53.73,114.9) v1(54.02,121.74) v1(54.41,101.18) v1(54.62,87.08) v1(55.34,100.21) v1(55.72,86.31) v1(55.9,2.75) v1(56.23,103.64) v1(56.23,102.99) v1(56.23,102.36) v1(56.56,121.74) v1(57.42,42.2) v1(57.4,0.82) v1(57.93,55.64) v1(57.9,46.31) v1(58.03,81.44) v1(58.28,70.47) v1(58.39,41.11) v1(58.39,40.47) v1(58.78,115.84) v1(58.98,0.76) v1(59.1,121.74) v1(59.83,56.5) v1(59.86,65.29) v1(59.86,64.19) v1(61.24,57.48) v1(61.23,56.52) v1(61.23,55.51) v1(61.33,72.5) v1(61.31,59.39) v1(61.64,121.74) v1(61.98,57.48) v1(62.53,0.77) v1(62.59,61.34) v1(62.92,97.11) v1(62.92,96.48) v1(63.27,55.48) v1(63.44,41.97) v1(63.39,41.08) v1(63.37,40.19) v1(63.39,39.32) v1(63.52,42.86) v1(63.63,96.71) v1(63.9,119.83) v1(64.13,56.5) v1(64.06,0.76) v1(64.18,121.74) v1(64.61,60.36) v1(65.29,70.81) v1(65.43,68.24) v1(65.44,63.25) v1(65.42,62.29) v1(65.35,54.54) v1(65.53,55.33) v1(65.55,52.89) v1(65.47,51.57) v1(65.5,48.57) v1(65.95,115.49) v1(66.13,0.77) v1(66.36,54.5) v1(66.41,47.99) v1(66.58,109.53) v1(66.6,97.34) v1(66.6,96.71) v1(68.21,95.3) v1(68.34,119.9) v1(68.29,64.7) v1(68.35,50.06) v1(68.34,49.39) v1(68.38,51.33) v1(68.63,105.51) v1(68.65,56.06) v1(68.65,55.28) v1(68.66,56.86) v1(68.84,95.29) v1(68.8,72.83) v1(68.8,72.2) v1(69.14,0.76) v1(69.33,121.73) v1(69.31,71.56) v1(69.31,70.93) v1(69.28,66.86) v1(69.41,68.87) v1(69.44,68.23) v1(69.94,35.98) v1(69.94,35.32) v1(70.17,56.86) v1(70.32,64.64) v1(70.33,52.92) v1(70.3,51.5) v1(70.32,47.96) v1(70.35,67.47) v1(70.38,52.15) v1(70.64,107.29) v1(71.21,46.06) v1(71.21,45.35) v1(71.24,43.62) v1(71.29,48.73) v1(71.68,0.76) v1(71.8,121.74) v1(71.91,119.98) v1(72.23,37.02) v1(72.23,36.38) v1(72.33,52.18) v1(73.22,50.02) v1(73.25,49.34) v1(73.25,48.62) v1(73.33,66.79) v1(73.5,32.7) v1(73.84,116.08) v1(74.13,32.7) v1(74.21,50.71) v1(74.23,50.01) v1(74.22,0.76) v1(74.34,121.74) v1(74.26,49.34) v1(74.77,32.7) v1(75.19,53.55) v1(75.4,32.7) v1(75.85,119.55) v1(76.04,32.7) v1(76.22,48.65) v1(76.48,109.45) v1(76.76,0.76) v1(76.88,121.74) v1(77.21,56.54) v1(77.33,60.37) v1(78.01,66.11) v1(77.97,60.36) v1(78.52,59.38) v1(78.54,52.51) v1(78.58,55.51) v1(78.66,60.36) v1(79.08,120.46) v1(79.19,52.54) v1(79.3,60.38) v1(79.29,59.32) v1(79.29,57.54) v1(79.29,55.48) v1(79.36,111.54) v1(79.94,60.41) v1(80.64,63.28) v1(80.6,59.39) v1(80.7,60.41) v1(80.7,55.4) v1(81.04,104.83) v1(81.05,113.48) v1(81.38,63.25) v1(81.41,60.41) v1(81.46,67.38) v1(81.59,120.09) v1(81.84,0.76) v1(81.99,59.4) v1(82.12,63.3) v1(82.09,60.38) v1(82.63,59.38) v1(82.75,66.17) v1(82.75,60.38) v1(83.08,105.14) v1(83.53,45.65) v1(83.55,121.74) v1(83.81,120.38) v1(83.79,27.92) v1(84.04,117.97) v1(84.12,109.66) v1(84.24,115.53) v1(84.17,45.65) v1(84.24,1.59) v1(84.59,71.13) v1(84.68,62.06) v1(84.66,54.69) v1(84.94,70.6) v1(84.93,69.96) v1(84.93,69.33) v1(85.62,3.75) v1(85.72,118.91) v1(86.09,121.74) v1(86.31,87.79) v1(87.04,118.73) v1(87.22,87.82) v1(88.16,3.76) v1(88.54,60.94) v1(88.63,121.74) v1(89.51,75.27) v1(89.93,46.34) v1(90.7,3.76) v1(90.92,121.7) v1(90.9,96.25) v1(91.18,98.97) v1(91.3,119.35) v1(92.35,98.92) v1(93.24,3.76) v1(94.18,44.18) v1(94.28,99.5) v1(94.53,45.11) v1(94.58,121.7) v1(94.58,101.23) v1(94.73,115.29) v1(95.68,120.57) v1(95.78,3.76) v1(95.95,44.18) v1(96.25,121.74) v1(98.32,3.76) v1(100.81,117.42) v1(100.86,3.76) v1(101.33,121.74) v1(101.52,120.3) v1(102.63,106.22) v1(102.86,115.84) v1(103.27,106.22) v1(103.6,43.98) v1(103.8,37.87) v1(103.87,121.74) v1(104.11,31.99) v1(105.94,3.76) v1(106.14,22.03) v1(106.42,45.12) v1(106.42,44.48) v1(106.77,22.03) v1(107.33,18.7) v1(107.43,108.98) v1(107.86,120.1) v1(107.86,116.16) v1(108.07,108.96) v1(108.48,3.76) v1(108.95,121.74) v1(110.63,36.69) v1(111.02,3.76) v1(111.17,17.26) v1(111.35,62.16) v1(111.4,109.57) v1(111.49,121.74) v1(111.8,17.26) v1(112.46,16.6) v1(112.72,17.23) v1(113,62.67) v1(113.14,108.87) v1(113.14,108.24) v1(113.1,40.34) v1(113.47,3.01) v1(113.56,18.86) v1(113.67,38.19) v1(114.03,121.74) v1(114.24,17) v1(114.68,0.79) v1(115.47,108.9) v1(115.47,108.24) v1(115.99,40.42) v1(116.55,121.35) v1(116.58,3.13) v1(117.16,1.32) v1(117.35,93.3) v1(117.42,37.19) v1(117.37,30.44) v1(117.52,28.46) v1(118.41,119.69) v1(118.69,41.92) v1(119.83,77.3) v1(119.88,5.98) v1(120.52,67.55) v1(120.82,118.73) v1(120.87,56.35) v1(121.15,39.94) v1(121.23,87.28) v1(121.33,84.71) v1(121.3,46.59) v1(121.48,4.58) v1(121.73,105.9) v1(122.17,77.3) v1(122.24,41.73) v1(122.26,116.63) v1(122.37,67.55) v1(122.53,6.46) v1(123.07,114.23) v1(123.24,111.69) v1(123.24,109.15) v1(123.24,101.53) v1(123.24,98.99) v1(123.24,96.45) v1(123.24,93.91) v1(123.24,91.37) v1(123.24,88.83) v1(123.23,82.04) v1(123.23,80.17) v1(123.23,64.56) v1(123.23,62.02) v1(123.23,59.48) v1(123.21,56.37) v1(123.21,44.92) v1(123.24,36.85) v1(123.24,34.31) v1(123.24,31.77) v1(123.24,29.23) v1(123.24,26.69) v1(123.24,24.15) v1(123.24,21.61) v1(123.24,19.07) v1(123.24,16.53) v1(123.24,13.99) v1(123.24,11.45) v1(123.17,8.91) v3(10.13,89.59) v3(10.13,88.71) v3(10.13,87.82) v3(10.11,46.03) v3(10.11,45.12) v3(11.02,89.59) v3(11.02,88.71) v3(11.02,87.82) v3(11.24,46.02) v3(11.24,45.13) v3(11.9,89.59) v3(11.9,88.71) v3(11.9,87.82) v3(14.8,5.83) v3(15.03,6.71) v3(18.28,73.75) v3(18.28,72.86) v3(19.27,3.49) v3(19.27,2.6) v3(19.91,81.34) v3(19.91,80.45) v3(19.91,79.56) v3(19.91,78.67) v3(20.16,3.49) v3(20.16,2.6) v3(20.79,81.34) v3(20.79,80.45) v3(20.79,79.56) v3(21.05,3.49) v3(21.05,2.6) v3(21.56,47.51) v3(21.94,3.49) v3(21.94,2.6) v3(22.45,47.53) v3(26.13,37.63) v3(28.94,49.23) v3(28.94,48.35) v3(28.94,47.46) v3(28.94,46.57) v3(28.94,45.65) v3(28.94,44.76) v3(29.56,9.97) v3(29.56,9.08) v3(30.45,9.97) v3(30.45,9.08) v3(31.44,9.1) v3(31.46,9.99) v3(32.35,9.97) v3(32.35,9.08) v3(84.88,89.35) v3(84.9,88.45) v3(85.77,89.35) v3(85.79,88.45) v3(86.66,89.35) v3(86.68,88.45) v3(87.67,89.35) v3(87.74,88.47) v3(92.42,89.01) v3(92.42,88.12) v3(93.62,42.79) v3(93.6,41.9) v3(94.51,42.81) v3(94.49,41.92) v3(108.17,88.3) v3(108.17,87.05) v3(108.17,86.17) v3(108.17,85.15) v3(108.17,84.26) v3(108.17,83.37) v3(108.3,89.21) v3(109.06,88.3) v3(109.19,89.21) v3(109.44,40.7) v3(109.82,28.76) v3(109.82,27.87) v3(109.82,26.98) v3(109.97,41.41) v3(110.2,38.92) v3(110.71,28.76) v3(110.71,27.87) v3(110.71,26.98) v3(111.09,38.92) v3(111.6,28.76) v3(111.6,27.87) v3(111.6,26.98) v3(112.11,38.92) v3(112.49,28.76) v3(112.49,27.87) v3(113,38.92) v3(114.65,38.29) v3(115.59,89.19) v3(118.58,100.77) v3(119.47,100.77)
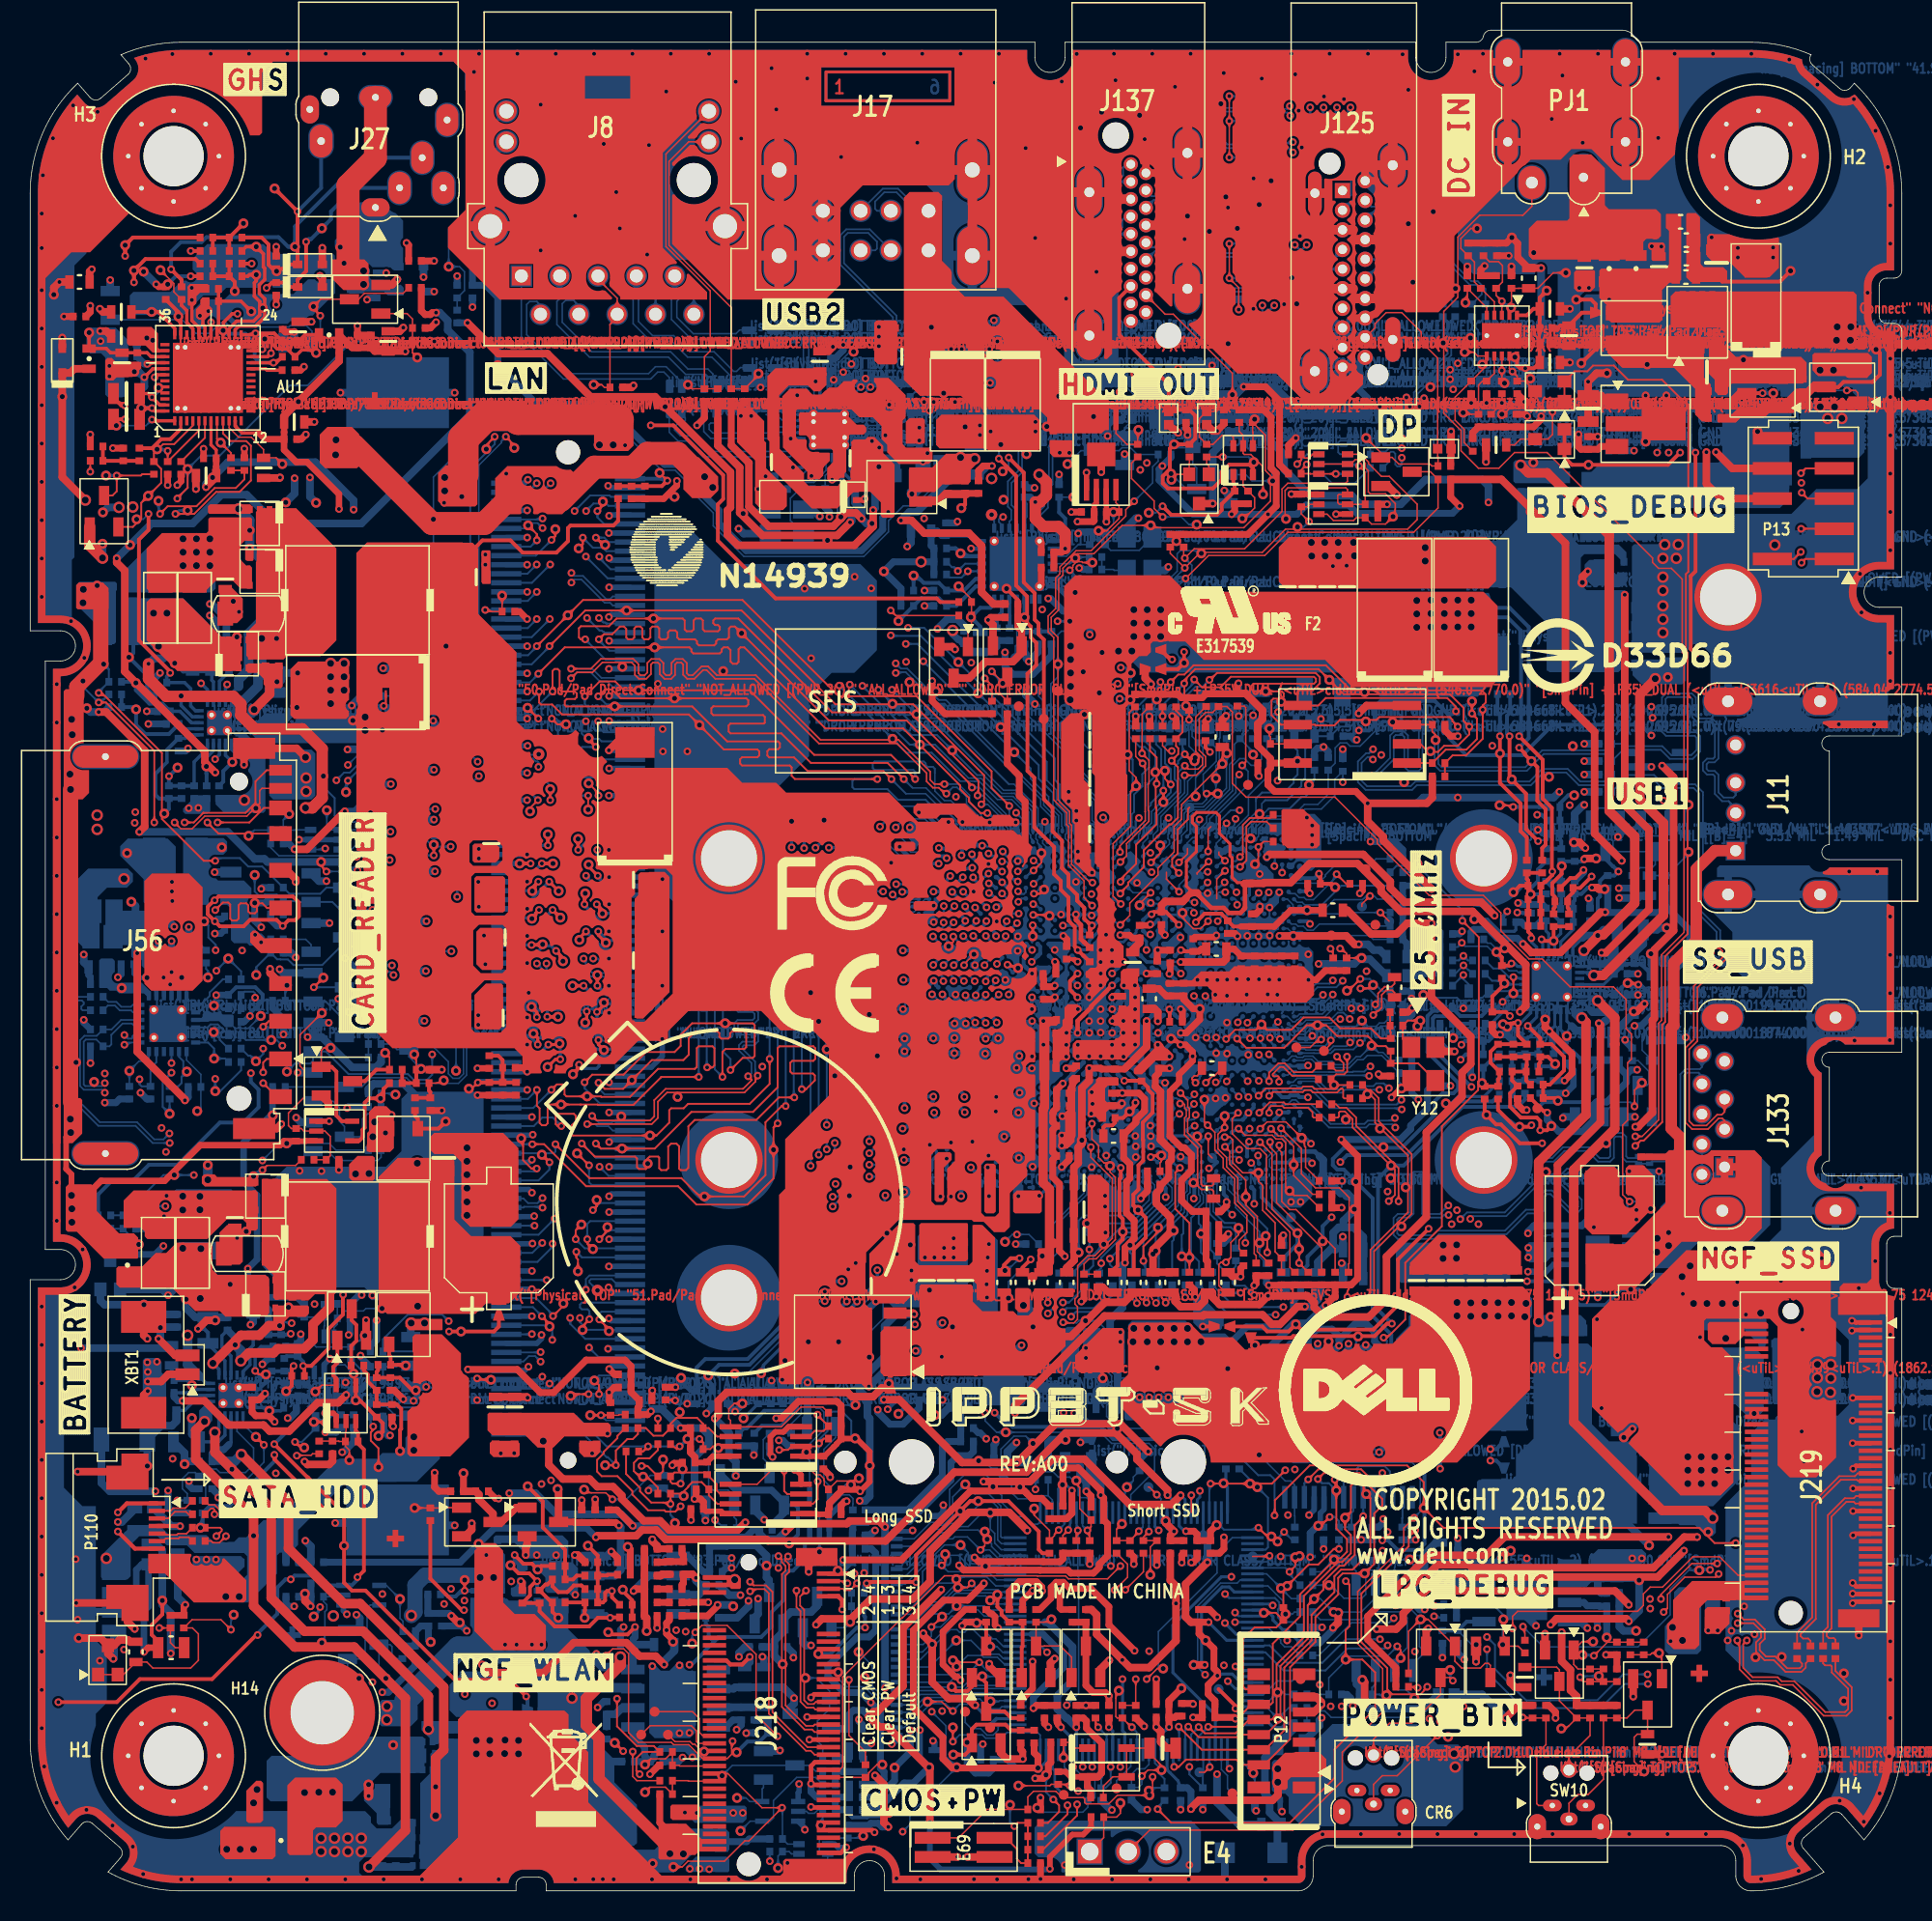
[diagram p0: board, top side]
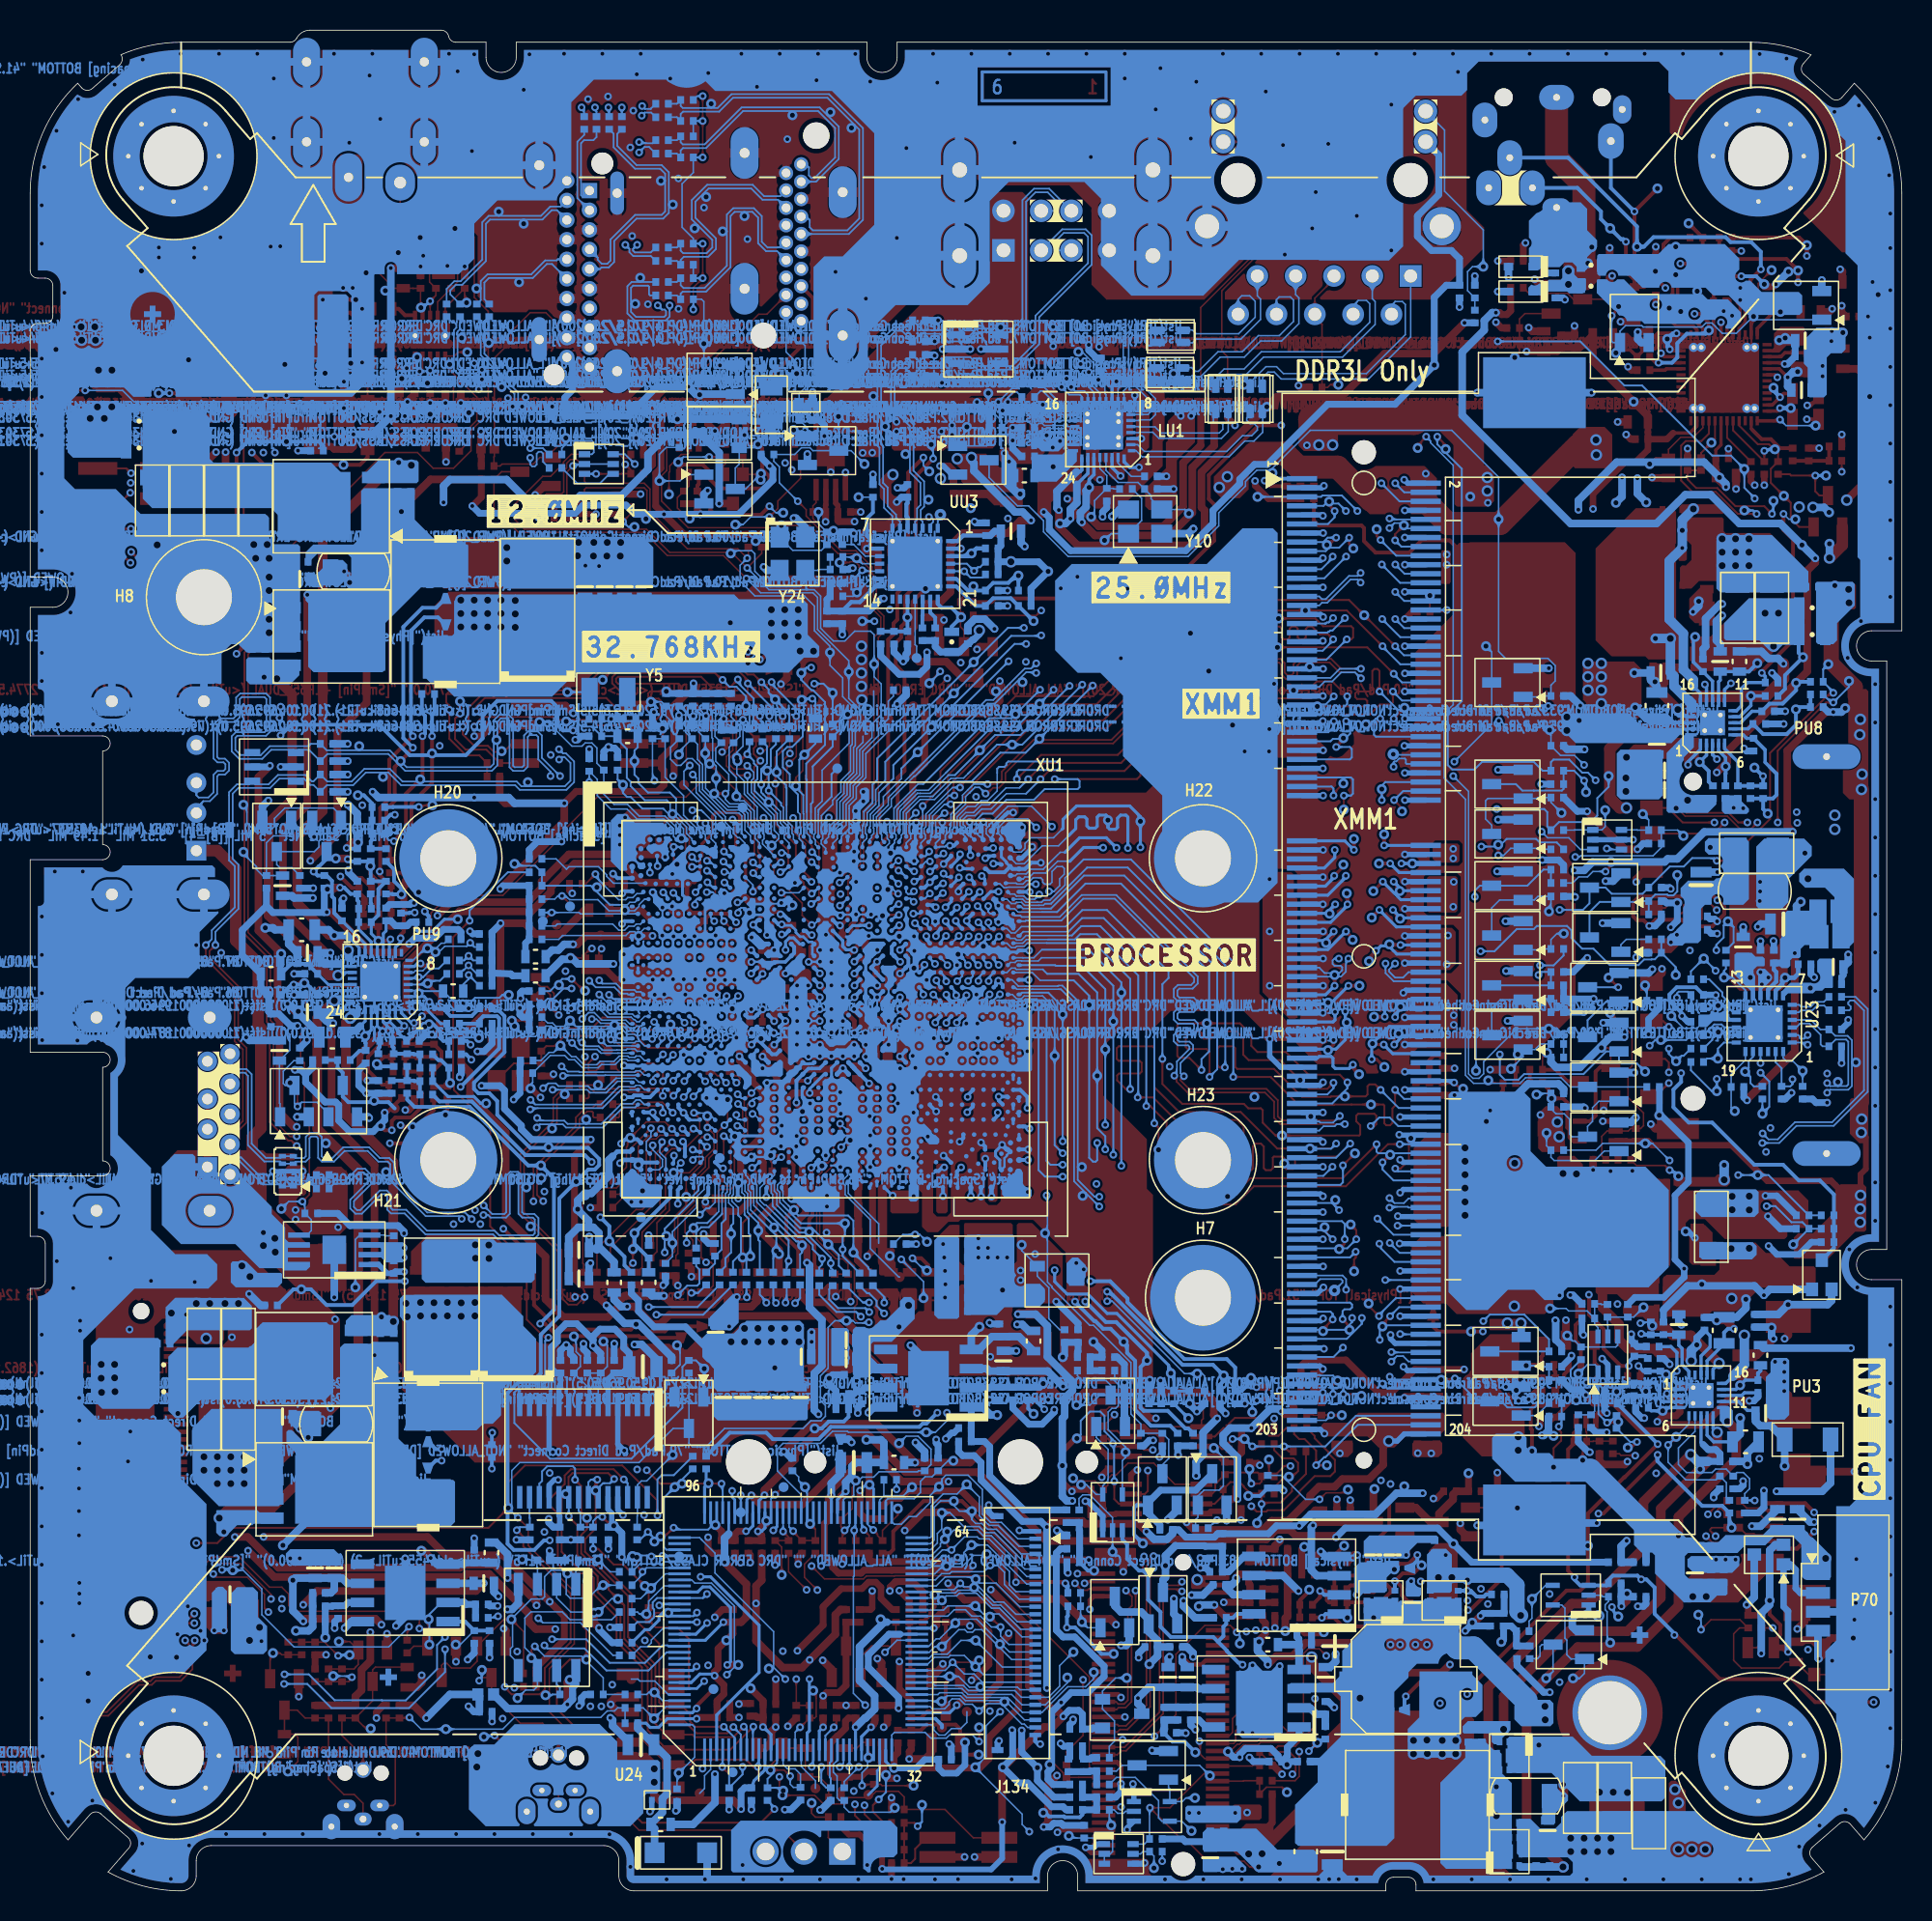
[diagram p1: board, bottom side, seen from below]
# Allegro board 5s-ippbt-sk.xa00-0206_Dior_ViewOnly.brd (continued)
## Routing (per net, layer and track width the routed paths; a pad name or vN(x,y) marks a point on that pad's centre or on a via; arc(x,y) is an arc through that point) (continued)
V1P0SX_PG: length 2.9
  BOTTOM w0.102: U24.17 72.92,8.24 71.98,7.3 ST77.1
VCCGT_SENSE: length 28.7
  IN2 w0.254: v1(86.23,44.64) 86.23,47.06 86.8,47.64 v1(86.8,48.29) 84.06,51.03 81.31,51.03 80.79,50.51 v1(80.79,50.51)
  BOTTOM w0.254: v1(86.23,44.64) 85.63,44.04 v2(85.63,43.05) 85.63,43.02 84.63,42.02 84.63,41.45 PR1.2 ; v1(86.8,48.29) 87.26,48.75 91.18,48.75 94.74,52.31 96.88,52.31 PR215.1 ; XU1.BB8 80.42,50.14 v1(80.79,50.51)
VCCGT_SENSE1: length 32
  TOP w0.254: PJP11.2 83.56,36.65 83.68,36.76 89.07,36.76 89.89,37.59 v1(90.22,37.59)
  BOTTOM w0.254: v1(90.22,37.59) 89.3,38.5 89.3,47.2 v2(90.16,48.07) 91,48.07 94.89,51.95 98.54,51.95 99.03,52.43 PR217.1
VCCSENSE: length 116.4
  TOP w0.254: PR2.2 69.79,61.97 69.77,61.97 v1(69.4,62.34) 69.4,62.37 69.21,62.57 69.21,63.88 68.79,64.3 68.79,65.83 68.28,66.34 68.28,66.93 67.84,67.37 67.84,69.17 66.53,70.48 66.53,73.76 66.07,74.22 66.07,80.65 66.65,81.24 66.65,82.7 66.3,83.06 66.3,83.78 66.05,84.03 66.05,85.78 65.32,86.5 65.32,93.76 v1(64.18,94.9)
  IN1 w0.254: v1(64.18,94.9) 64.18,94.91 64.62,94.47 65.45,94.47 65.91,94.93 67.14,94.93 68.13,95.92 70.11,95.92 70.63,95.4 71.8,95.4 72.11,95.71 74.42,95.71 76.37,93.76 83.26,93.76 84.13,92.89 89.53,92.89 89.78,93.15 91.15,93.15 93.25,95.25 104.42,95.25 105.24,94.43 107.68,94.43 v1(108.55,95.31)
  IN2 w0.254: v1(108.55,95.31) 106.65,93.4 106.65,82.2 99.66,75.21 99.66,71.49 v1(99.84,71.31)
  BOTTOM w0.102: v2(64.31,95.84) 64.18,95.72 v1(64.18,94.9)
  BOTTOM w0.218: v1(69.4,62.34) 69.42,62.36 69.94,62.36 70.17,62.59 70.17,62.96 XU1.P28
  BOTTOM w0.254: PR234.1 100.13,71.31 v1(99.84,71.31)
VCCSENSE1: length 31.5
  TOP w0.102: v1(98.25,71.83) 98.14,71.94 v2(97.35,71.94)
  TOP w0.254: v1(75.66,81.59) 75.54,81.59 PJP15.2
  IN1 w0.254: v1(98.25,71.83) 95.23,74.85 93.41,74.85 85.92,82.34 77.55,82.34 76.8,81.59 v1(75.66,81.59)
  BOTTOM w0.254: v1(98.25,71.83) 99.95,71.83 99.97,71.81 PR235.1
VSS_AH2: length 7.1
  BOTTOM w0.102: XU1.AH2 84.36,56.97 84.36,56.97 84.38,56.97 84.7,57.29 85.59,57.29 85.6,57.29 87.85,57.29 v2(88.23,57.67) 88.61,57.29 89.17,57.29 89.39,57.51 89.71,57.51 SR26.2
VSS_AH3: length 9.8
  BOTTOM w0.102: v2(91.91,57.29) 91.23,56.61 90.52,56.61 SR22.2 89.83,57.31 89.48,57.31 89.26,57.09 85.43,57.09 84.78,57.09 84.46,56.77 84.45,56.77 84.44,56.76 84.41,56.76 83.94,56.76 83.85,56.68 83.61,56.68 83.32,56.97 XU1.AH3
VSS_AM2: length 9.1
  BOTTOM w0.102: XU1.AM2 84.4,55.02 84.49,55.11 84.89,55.11 84.89,55.1 85.24,54.76 86.15,54.76 86.37,54.54 87.4,54.54 87.94,55.08 88.31,55.08 88.59,55.36 89.54,55.36 SR24.2 90.71,53.58 90.85,53.44 v2(90.85,53.17)
VSS_AM3: length 9
  BOTTOM w0.102: SR21.2 90.16,55.03 89.62,55.56 89.32,55.56 v2(88.87,56.02) 88.13,55.28 87.85,55.28 87.32,54.75 86.47,54.75 86.25,54.96 85.32,54.96 85.04,55.25 84.97,55.31 84.4,55.31 84.32,55.23 83.94,55.23 83.86,55.32 83.59,55.32 83.3,55.02 XU1.AM3
VSS_BB5: length 6.7
  TOP w0.102: v1(82.2,50.5) 82.22,50.5 82.69,50.03 83.01,50.03 83.71,49.33 v2(83.71,48.12) 83.71,47.41 84.96,46.16 SR82.2
  BOTTOM w0.102: XU1.BB5 82.2,50.47 v1(82.2,50.5)
VSS_BB7: length 7.2
  TOP w0.102: SR83.2 84.5,47.95 84.5,49.28 84.43,49.34 84.43,49.7 v2(84.24,49.89) 83.19,50.95 81.94,50.95 v1(81.49,50.5)
  BOTTOM w0.102: XU1.BB7 81.13,50.14 v1(81.49,50.5)
VSS_SENSE: length 128.4
  TOP w0.254: PR3.1 70.2,63.82 v1(70.35,63.97) 70.3,63.97 70.13,64.14 70.12,64.14 69.83,64.43 69.83,65.15 69.36,65.62 69.36,66 68.79,66.57 68.79,67.35 68.36,67.78 68.36,69.59 67.73,70.21 67.73,71.76 67.16,72.33 67.16,82.91 66.8,83.27 66.8,83.99 66.55,84.24 66.55,85.99 65.83,86.71 65.83,93.98 v1(64.83,94.98)
  IN1 w0.254: v1(64.83,94.98) 65.24,94.98 65.69,95.44 66.93,95.44 67.92,96.43 70.32,96.43 70.84,95.91 71.59,95.91 71.89,96.21 74.64,96.21 76.58,94.27 83.47,94.27 84.34,93.4 89.31,93.4 89.57,93.66 90.9,93.66 93.01,95.77 104.67,95.77 105.49,94.94 107.42,94.94 v1(107.79,95.31)
  IN2 w0.254: v1(107.79,95.31) 106.14,93.66 106.14,82.41 99.13,75.4 99.13,67.03 97.86,65.75 97.86,65.65 97.86,65.65 97.86,65.24 97.86,65.23 v1(97.86,64.91) 97.86,63.64 96.08,61.86 96.08,57.32 v1(94.82,56.07)
  BOTTOM w0.102: v2(64.43,94.07) 64.83,94.46 v1(64.83,94.98)
  BOTTOM w0.254: PR221.2 95.08,56.32 v1(94.82,56.07) ; PR241.1 97.59,64.59 97.86,64.86 v1(97.86,64.91) ; v1(70.35,63.97) 70.46,63.97 XU1.N28
1P0VSB_PG_EC: length 2.3
  TOP w0.102: ST49.1 v1(76.93,26.22)
  BOTTOM w0.102: U24.90 76.92,26.21 v1(76.93,26.22)
1P05V_ENQ: length 7.6
  TOP w0.254: PR170.2 64.99,11.45 64.55,11.9 PQ36.3 63.34,13.78 62.98,14.13 PQ33.1 62.39,13.54 62.1,13.24 61.33,13.24 v2(61.05,13.52)
1P05V_ENR: length 7.1
  TOP w0.254: v2(61.16,9.03) 61.94,9.03 62.39,9.47 PQ36.1 62.39,10.72 62.69,11.01 64.62,11.01 64.99,10.64 PC126.1 PR173.1
1P8V_ENQ: length 6.7
  TOP w0.102: v2(67.66,17.99) 67.47,17.8 PR172.2 PQ38.3 67.18,16.21 67.19,16.23 68.25,16.23 68.99,15.49 PQ35.1
1P8V_ENR: length 6.7
  TOP w0.254: v2(64.08,19.62) 64.08,18.83 64.36,18.55 64.36,18.31 PR175.1 PC128.1 65.75,16.2 65.69,16.14 PQ38.1
3PVO_EN: length 10.3
  TOP w0.102: v2(14.95,30.08) v1(15.49,29.55)
  BOTTOM w0.102: PU3.6 14.1,30.93 v1(15.49,29.55) 15.49,28.41 14.32,27.24 12.3,27.24 PC45.1 11.63,27.05 11.63,26.08 PR47.2
+1P0V: length 183.4
  TOP w0.457: PR173.2 66.51,9.15 66.77,8.9 v2(66.77,8.14) 61.09,8.14 60.47,8.76 60.47,10.17 58.51,12.12 58.51,17.26 60.51,19.26 62.1,19.26 63.19,20.35 v1(63.19,20.38)
  TOP w0.508: 64.61,36.89 64.61,38.24 64.52,38.33 SL2.2 ; 68.19,36.74 68.95,36.74 71.22,39 72.49,39 73.12,39.63 SL10.2 SL15.1 SL9.2 75.86,39.45 75.85,39.43 75.85,39.07 76.21,38.71 77.42,38.71 77.81,39.1 77.81,39.45 SL3.2 78.8,38.86 81.44,38.86 v1(82.01,39.43) 84.62,39.43 85.07,38.98 85.07,38.66 85.71,38.03 88.68,38.03 89.86,39.2 89.86,42.02 92.5,44.66 92.5,50.27 94.86,52.64 94.86,54.22 95.45,54.8 95.45,56.6 92.84,59.21 v1(92.84,64.12) 91.23,64.12 90.52,63.41 88.84,63.41 87.27,64.98 SL11.2
  IN2 w0.508: v1(23.82,68.31) 23.94,68.31 29.41,62.85 29.41,61.23 31.44,59.19 31.44,52.48 32,51.92 32,32.75 32.7,32.06 37.04,32.06 37.13,32.14 38.44,32.14 42.01,35.71 56.25,35.71 56.8,35.16 58.92,35.16 59.16,35.39 v1(60.39,35.39) 62.07,33.71 62.07,29.89 63.96,27.99 63.96,21.15 v1(63.19,20.38)
  BOTTOM w0.457: SL8.2 92.04,60.64 92.17,60.77 PR194.1 ; PR195.1 PR194.1 ; PR194.1 PR193.1 PR192.1 PC137.1 93.4,63.52 92.84,64.09 v1(92.84,64.12) ; v1(23.82,68.31) 22.74,68.31 22.41,67.98 R9.1
  BOTTOM w0.508: v1(82.01,39.43) 82.81,39.43 SL1.2
+1P0V_EN_EC: length 34.8
  IN1 w0.254: v1(55.31,17.45) 55.59,17.73 57.82,17.73 58.63,18.53 59.49,18.53 59.71,18.75 60.8,18.75 61.22,19.17 73.03,19.17 73.4,19.54 78.28,19.54 78.69,19.13 82.11,19.13 v1(82.32,18.92)
  BOTTOM w0.178: v1(82.32,18.92) 82.15,18.92 82.06,19.01 U24.108
  BOTTOM w0.254: v2(52.21,15.71) 53.03,15.71 54.77,17.45 v1(55.31,17.45) 55.31,18.16 55.25,18.22 PR141.1
+1P0V_FB: length 9.7
  TOP w0.508: PR134.1 PR145.1 PR144.1 40.85,18.07 v2(40.85,17.22) ; PR134.1 PC97.2 PC98.2 PR142.1 ; PR134.1 40.1,20 v1(39.97,19.87)
  BOTTOM w0.508: PU7.6 40.99,20.89 v1(39.97,19.87)
+1P0V_FB_1: length 0.8
  TOP w0.457: PC95.2 PR134.2
+1P0V_FB_2: length 0.9
  TOP w0.508: PC97.1 41.78,20.89 41.86,20.98 PR135.1
+1P0V_FB_3: length 2.6
  TOP w0.457: PC98.1 42.03,21.78 42.07,21.82 PR135.2 PR136.1 43.27,22.26 43.19,22.35 PR140.2
+1P0V_FB_4: length 9.9
  TOP w0.457: PR142.2 PR140.1 ; v2(42.58,16.51) 42.58,16.62 42.16,17.05 v1(42.16,17.27) 42.16,17.74 42.35,17.93 PR143.1
  TOP w0.508: PR142.2 41.53,22.86 41.22,23.17 v1(41.22,23.29)
  IN2 w0.508: v1(42.16,17.27) 42.16,17.73 41.22,18.68 v1(41.22,23.29)
+1P0V_FB_5: length 0.8
  TOP w0.457: PC103.1 PR145.2
+1P0V_FB_6: length 32.8
  TOP w0.457: v1(45.54,18.95) 45.55,18.95 45.56,18.95 45.53,18.93 45.53,18.88 44.88,18.22 PR143.2
  TOP w0.508: v1(45.36,31.3) 45.59,31.53 45.59,32.47 46.14,33.02 54.16,33.02 54.43,32.75 55.85,32.75 56.42,33.32 PJP7.1
  IN2 w0.508: v1(46.75,27.5) 45.99,26.74 45.99,24.31 43.49,21.81 43.49,20.48 44.22,19.74 45.18,19.74 45.55,19.38 45.55,18.95 v1(45.54,18.95)
  BOTTOM w0.508: v1(45.36,31.3) 46.3,30.36 46.3,28.89 46.75,28.43 46.75,27.55 46.71,27.5 v1(46.75,27.5) ; v1(45.54,18.95) 46.48,18.95 v2(46.58,18.86)
+1P0V_GATE: length 35.5
  TOP w0.457: PC95.1 43.19,20.29 43.27,20.38 PR136.2
  TOP w0.508: PQ26.4 58.49,38.29 v1(58.56,38.21) ; PR136.2 43.87,20.98 v1(44.11,20.74)
  IN2 w0.508: v1(44.11,20.74) 44.11,21.45 46.73,24.06 46.73,24.64 47.3,25.22 51.73,25.22 51.75,25.2 54.35,25.2 54.96,25.81 v1(54.96,25.84)
  BOTTOM w0.508: v1(44.11,20.74) 44.11,20.56 44.39,20.28 PR138.1 44.79,20.12 44.29,19.62 PU7.7 ; v1(54.96,25.84) 55.31,25.84 55.62,26.15 v2(55.62,28.18) 55.62,31.3 55.47,31.45 55.47,32.64 54.95,33.16 54.95,33.73 56.61,35.39 56.61,37.43 57.39,38.21 v1(58.56,38.21)
+1P0V_PG: length 4.2
  BOTTOM w0.203: R60212.1 83.27,17.31 82.97,17.31 82.34,17.94 82.34,18.17 81.9,18.6 U24.109
+1P0V_REF: length 10.8
  BOTTOM w0.457: 48.12,22.87 46.2,22.87 46.16,22.83 PR132.1 PC94.1 PR133.2 44.59,21.14 43.57,22.16 PU7.5
  BOTTOM w0.508: PQ27.3 48.95,20.6 48.79,20.76 v2(48.79,21.55) 48.79,22.21 48.12,22.87
+1P0V_REF_GATE: length 7.5
  BOTTOM w0.508: v2(49.85,15.02) 49.31,15.57 PC99.1 ; PQ28.3 52.14,18.88 51.73,18.47 50.39,18.47 49.9,17.99 PQ27.1 49.9,17.18 49.31,16.58 PC99.1 ; PC99.1 PR137.2
+1P0V_SX_EN_EC: length 3
  TOP w0.254: v1(79.85,12.08) 79.85,12.25 ST61.1
  BOTTOM w0.203: v1(79.85,12.08) 80.13,11.8 U24.126
+1P0VSB: length 106.1
  TOP w0.432: SL16.1 79.76,62.42 C26.1 C25.1 C22.1 C23.1 C24.1
  TOP w0.508: v1(76.22,61.55) 79.04,61.55 79.25,61.77 SL16.1 ; v1(97.02,64.63) 96.13,65.52 91.05,65.52 90.11,66.46 90.11,66.89 88.32,68.68 82.1,68.68 v1(81.93,68.51) ; v1(100.73,17.64) 101.12,18.03 105.75,18.03 v1(105.91,17.87)
  IN1 w0.508: v1(97.02,64.63) 97.02,61.47 96.93,61.38 96.93,58.07 98.01,56.99 98.01,55.65 102.16,51.5 102.16,47.6 98.54,43.98 98.54,40.15 98.98,39.71 99.38,39.71 101.81,37.28 101.81,18.72 v1(100.73,17.64)
  IN2 w0.508: v1(81.93,68.51) 81.63,68.51 80.74,67.62 80.74,64.96 79.32,63.53 79.32,63.16 77.71,61.55 v1(76.22,61.55)
  BOTTOM w0.229: XU1.V22 73.97,61.56 74.7,61.56 XU1.Y19
  BOTTOM w0.254: XU1.V22 73.39,62.14 73.39,62.55 XU1.U22
  BOTTOM w0.508: PR63.1 104.08,19.74 103.85,19.97 PC60.1 ; PC60.1 103.34,20.73 102.99,20.38 PU5.6 ; PC60.1 PC61.1 106.45,20.73 v2(106.6,20.58) 106.6,18.56 105.91,17.87 v1(105.91,17.87)
+1P0VSB_EN: length 6.3
  BOTTOM w0.127: v2(97.55,16.32) 97.55,18.32 96.77,19.11 PU5.2
  BOTTOM w0.457: PR61.1 PC59.1 95.14,18.98
  BOTTOM w0.508: PU5.2 95.27,19.11 95.14,18.98
+1P0VSB_FB: length 4.6
  BOTTOM w0.457: PU5.7 102.94,19.11 103.15,18.89 PR65.1 103.94,18.89 103.98,18.86 PR62.2 PC55.2 v2(104.45,16.79)
+1P0VSB_FB_R: length 3.5
  BOTTOM w0.508: PR63.2 PR62.1 PC55.1 105.29,17.5 105.55,17.23 v2(106.39,17.23)
+1P0VSB_PG: length 4.6
  BOTTOM w0.102: v2(95.8,16.32) 95.51,16.32 PC56.1
  BOTTOM w0.254: PR59.2 PC56.1 95.18,17.84 PU5.1
+1P0VSB_VDD: length 5.1
  TOP w0.508: v1(97.47,22.06) 97.95,22.54 v2(98.09,22.54)
  BOTTOM w0.457: 93.96,21.74 PC58.1 95.23,21.74
  BOTTOM w0.508: v1(97.47,22.06) 97.06,21.65 PU5.4 95.32,21.65 95.23,21.74 ; PR60.2 93.96,21.74 93.96,21.74
+1P05V: length 27.4
  TOP w0.457: C941136.1 67.11,60.44 67.15,60.4 C27.1 67.8,59.92 v1(67.88,59.99)
  IN1 w0.762: v3(65.8,38.79) 64.55,40.05 64.55,48.72 63.23,50.04 63.23,54.08 65.62,56.48 65.62,59.52 66.06,59.96 66.5,59.96 66.54,60 66.92,60 66.97,60.05
  BOTTOM w0.203: 68.64,61.47 68.64,60.93
  BOTTOM w0.216: 68.65,59.45 68.65,59.76 ; 68.64,59.07 68.64,58.53
  vias: v1(67.88,62.35) v2(66.44,37.37)
+1P5V: length 176.6
  TOP w0.216: AC41.1 12.32,95.48 11.98,95.82 AU1.7
  TOP w0.432: AC41.1 12.32,94.37 12.32,94.37 AC40.1 12.32,93.69
  TOP w0.457: C75.1 69.13,54.51 v1(68.65,54.51)
  TOP w0.508: 12.32,93.69 v1(11.65,93.02) ; v1(52.06,17.64) 52.45,18.03 54.38,18.03 55.69,19.34 58.46,19.34 59.62,20.5 59.62,22.5 62.21,25.08 64.86,25.08 v1(66.06,23.88)
  IN1 w0.508: v1(36.11,19.62) 36.15,19.62 36.52,19.25 40.23,19.25 40.24,19.26 43.88,19.26 45.31,17.84 49.3,17.84 49.33,17.87 51.83,17.87 v1(52.06,17.64)
  IN2 w0.508: v1(66.06,23.88) 67.23,25.05 67.23,30.11 65.91,31.43 65.91,33.27 64.1,35.08 64.1,42.55 64.3,42.75 64.3,48.87 65.16,49.72 65.16,50.52 64.85,50.82 64.85,53.07 65.29,53.51 67.55,53.51 68.54,54.51 v1(68.65,54.51) ; v1(21.43,91.53) 22.37,90.59 26.21,90.59 27.3,89.49 27.3,80.22 25.24,78.16 25.24,73.02 20.86,68.64 20.86,65.77 22.68,63.94 24.11,63.94 29.01,59.04 29.01,51.77 30.3,50.48 30.3,31.65 32.76,29.19 32.76,26.17 34.18,24.75 34.18,20.86 35.42,19.62 v1(36.11,19.62)
  BOTTOM w0.254: XU1.AM32 69.03,54.88 v1(68.65,54.51)
  BOTTOM w0.508: v1(11.65,93.02) 11.65,93.23 v2(12.08,93.66) 13.1,94.67 18.89,94.67 21.43,92.13 v1(21.43,91.53)
+1P05V_EN: length 33.8
  TOP w0.254: PQ33.3 PR177.1 PR169.2
  TOP w0.432: PR169.2 61.98,17.8 v1(61.74,17.56)
  TOP w0.508: v1(86.31,17.43) 86.66,17.78 v2(86.66,18.42)
  IN2 w0.508: v1(86.31,17.43) 86.31,17.3 85.85,16.84 85.15,16.84 84.6,17.38 81.68,17.38 80.61,16.31 75.53,16.31 73.87,14.65 69.81,14.65 69.73,14.58 66.16,14.58 65.79,14.94 65.79,15.03 64.04,16.78 62.52,16.78 61.77,17.54 61.77,17.56 v1(61.74,17.56)
  BOTTOM w0.457: R60212.2 85.44,16.44 86.31,17.32 v1(86.31,17.43)
+1P5V_EN_EC: length 70.6
  TOP w0.254: v1(28.75,18.6) 28.59,18.6 26.51,20.68 PR131.1
  TOP w0.508: v2(77.09,14.97) v1(77.82,14.97)
  IN1 w0.254: v1(77.82,14.97) 77.77,14.97 77.77,14.97 77.26,14.97 74.72,12.43 70.5,12.43 70.15,12.79 69.74,12.79 69.45,12.5 69.45,12.38 68.87,11.79 67.42,11.79 66.82,11.2 61.68,11.2 61.63,11.25 61.08,11.25 v1(60.42,11.91)
  IN2 w0.254: v1(28.75,18.6) 33.27,18.6 36.12,15.74 36.12,15.74 37.3,14.56 37.69,14.18 40.25,14.18 41.63,12.8 46.42,12.8 47.54,13.92 53.07,13.92 53.49,13.49 55.48,13.49 56.29,12.68 59.65,12.68 v1(60.42,11.91)
  BOTTOM w0.203: U24.106 79.77,19.8 79.44,20.14 78.97,20.14 77.6,18.77 77.6,15.19 v1(77.82,14.97)
+1P05V_EN_EC: length 38.9
  IN2 w0.254: v1(72.37,14.03) 72.17,14.03 72.17,14.04 66.01,14.04 65.31,14.74 65.31,14.83 63.84,16.3 62.3,16.3 61.22,17.38 61.22,20.01 63.45,22.25 63.45,26.03 61.97,27.52 61.97,28.44 58.5,31.91 v1(56.81,31.91)
  BOTTOM w0.203: v1(72.37,14.03) 72.38,14.02 72.38,10.61 72.52,10.46 U24.18
  BOTTOM w0.254: v2(57.52,31.61) 57.88,31.96 PR247.1 57.43,32.53 v1(56.81,31.91)
+1P05V_FB: length 6.7
  BOTTOM w0.254: PC77.2 69.78,31.42 70.1,31.1 71.1,31.1 71.55,30.64 v2(72.03,30.64)
  BOTTOM w0.457: PU6.7 68.71,33.33 PR115.1 69.25,33.12 69.44,32.93 PR112.1 PC77.2
+1P5V_FB: length 9.5
  TOP w0.254: PR124.1 37.89,20.9 38.22,20.9 38.27,20.95 PR129.1 ; PR124.1 PC87.2 PC86.2 37.95,19.11 38.09,19.26 38.09,19.74 38.22,19.87 v1(38.54,19.87) 38.54,19.46 PR117.1 ; PR124.1 PR127.1 37.6,22.22 v2(36.95,22.87)
  BOTTOM w0.254: PU7.2 38.26,19.61 38.54,19.9 v1(38.54,19.87)
+1P5V_FB_1: length 2.1
  TOP w0.254: v2(39.26,19.96) 39.26,19.87 39.88,19.25 PR117.2 PC84.2
+1P5V_FB_2: length 2.3
  TOP w0.254: v2(36.73,18.09) 36.73,18.58 36.76,18.6 PC86.1 PR118.1
+1P5V_FB_3: length 6.6
  TOP w0.254: PC87.1 36.52,20.24 36.02,20.24 35.58,19.8 34.99,19.8 34.6,20.19 PR123.2 34.27,20.3 34.14,20.3 PR119.1 34.55,19.11 PR118.2 34.6,18.49 v2(34.99,18.09)
+1P5V_FB_4: length 8.6
  TOP w0.254: v2(32.96,26.81) 33.96,25.81 33.96,24.08 35.44,22.6 PR125.1 PR123.1 35.96,20.63 36.21,20.89 PR124.2
+1P5V_FB_5: length 1.9
  TOP w0.457: v2(39.59,22.79) 39.76,22.63 PC91.1 PR129.2
+1P5V_FB_6: length 4.1
  TOP w0.254: v1(32.1,22.25) 32.68,21.68 33.24,21.68 v2(33.62,21.29) 33.85,21.52 PR125.2
  BOTTOM w0.254: PJP6.1 32.1,21.89 v1(32.1,22.25)
+1P05V_FB_R: length 3.3
  BOTTOM w0.457: PC77.1 PR112.2 70.62,33.14 71.06,33.59 v2(71.06,33.97) 70.83,34.2 PR113.2
+1P5V_GATE_C: length 13.6
  TOP w0.254: PC84.1 38.45,18.12 v1(38.42,18.09) 37.61,18.09 37.04,17.52 34.75,17.52 33.75,18.53 PR119.2 PR121.1 33.11,19.58 33.11,20.13 33.51,20.52 v1(33.59,20.52) 33.07,21.04 32.35,21.04 v2(31.82,21.57)
  BOTTOM w0.254: PQ23.3 v1(33.59,20.52) ; PU7.1 38.18,18.34 v1(38.42,18.09)
+1P05V_PG: length 13.5
  BOTTOM w0.457: PR107.1 58.17,25.24 60.43,27.5 60.43,29.43 60.77,29.78 PR109.2 PC79.1 61.65,31.33 PU6.1
  BOTTOM w0.508: PU6.1 60.9,32.06 60.37,31.53 v2(59.94,31.53)
+1P05V_PG_1: length 4.7
  BOTTOM w0.254: PR108.2 53.92,21.22 v2(53.51,21.22)
  BOTTOM w0.457: PR107.2 PR104.1 54.5,23.91 54.48,23.89 PC76.1 PR106.2 PR108.2
+1P5V_REF: length 11.3
  TOP w0.457: v1(39.01,24.22) 38.93,24.29 38.91,24.29 38.79,24.41 PR120.1 PC88.1 PR122.2 36.1,24.41 36.06,24.44 PQ24.3
  TOP w0.508: PQ24.3 35.01,26.57 v2(34.94,26.63)
  BOTTOM w0.508: PU7.3 38.75,20.88 39.12,21.26 39.12,24.1 v1(39.01,24.22)
+1P5V_REF_GATE: length 7.2
  TOP w0.457: v2(28.71,27.67) PR126.2
  TOP w0.508: PR126.2 PC92.1 29.73,26.27 29.73,25.92 30.66,24.99 PQ25.3 31.23,24.44 32.18,25.39 PQ24.1
+1P05V_VDD: length 6.6
  BOTTOM w0.508: PR111.2 58.49,36.73 59.17,36.73 59.18,36.72 PC81.1 60.28,36.72 61.13,35.87 PU6.4 61.65,36.83 v2(61.1,37.37)
+1P8V: length 470.5
  TOP w0.381: SC13.1 52.11,24.95 52.07,24.99 U4.1 ; U3.1 52.54,28.8 ; 52.54,28.8 52.62,28.8 53.23,29.41 53.24,29.41 53.42,29.59 53.42,29.61 53.73,29.92 SR111.1 54.75,29.97 55.62,29.1 55.62,27.11 v1(54.98,26.48) ; 52.54,28.8 SC11.1 ; R89.1 70.29,4.25 69.77,3.73 69.05,3.73 67.56,2.24 v1(67.56,1.46)
  TOP w0.457: MR16.1 MR14.1 81.72,98.14 82.21,97.65 82.21,94.28 82.56,93.94 82.56,91.77 v1(82.01,91.22) 80.68,89.89 SR14.1 SR16.1 ; SR111.1 SR110.1 SR113.1 53.73,32.15 53.44,32.44 50.91,32.44 49.78,31.31 v1(49.42,31.31) ; SR653.1 86.45,39.43 v1(85.82,38.79) ; SR653.1 SR656.1 87.51,40.15 87.94,40.58 87.94,48.69 86.86,49.77 v1(86.86,49.79) ; SR653.1 SR655.1 SR654.1 SR74.2 R60218.2 82.87,40.13 v1(82.06,40.13) ; SC13.1 52.89,25.28 52.95,25.35 52.95,25.7 53.46,26.21 53.46,26.22 53.73,26.49 SR109.1 54.86,26.6 v1(54.98,26.48) ; MR17.1 MR15.1 79.8,91.43 v1(79.6,91.22) ; v1(94.71,91.77) 94.71,91.75 94.11,92.35 SR12.1 ; v1(68.42,53.5) 68,53.09 C71.1 C72.1 68,51.87 67.79,51.65 67.79,51.58 67.75,51.54 67.75,50.95 C73.1 67.75,50.44 67.75,48.95 C74.1 67.75,48.45 67.75,47.29 68.19,46.85 68.19,42.4 v1(68.55,42.05) ; R60220.2 69.82,39.23 v1(69.64,39.05)
  TOP w0.508: v1(89.21,17.34) 90.5,17.34 90.96,17.81 90.96,18.38 93.59,21 95.08,21 95.28,20.8 107.83,20.8 v1(109.57,22.54) ; SR12.1 97.48,93.53 101.71,89.3 101.71,78.73 103.65,76.79 103.65,70.06 105.44,68.27 v1(105.44,68.26) ; v1(59.61,4.56) 59.61,8.08 56.83,10.86 56.26,10.86 v1(55.56,11.56) 55.86,11.86 56.12,11.86 57.83,13.57 57.83,17.43 v1(60.36,19.96)
  IN1 w0.254: v1(66.38,62.35) 66.38,62.89 67.2,63.71 67.2,66.9 67.38,67.08 67.38,69.66 66.55,70.48 66.55,74.32 64.2,76.67 64.2,81.02 63.83,81.39 v1(62.35,81.39)
  IN1 w0.508: v1(49.42,31.31) 49.48,31.38 50.28,31.38 54.21,35.31 57.32,35.31 58.41,36.4 58.92,36.4 59.31,36.01 60.65,36.01 61.13,35.53 67.62,35.53 69.64,37.55 v1(69.64,39.05) 68.55,40.14 v1(68.55,42.05) ; v1(34.51,27.2) 34.51,27.21 33.74,27.97 28.4,27.97 27.43,28.94 26.23,28.94 25.73,28.44 21.29,28.44 v1(20.67,29.07)
  IN2 w0.254: v1(62.35,81.39) 60.06,81.39 58.25,83.2 57.96,83.2 57.64,83.52 57.64,87.75 59.66,89.76 59.66,90.1 59.86,90.3 59.86,91.09 63.21,94.44 63.21,95.39 63.62,95.79 73.64,95.79 v1(75.01,94.42)
  IN2 w0.508: v1(14.42,41.23) 14.42,38.88 17.63,35.67 18.08,35.67 18.89,34.86 18.89,33.23 20.22,31.9 20.22,29.51 v1(20.67,29.07) ; v1(34.51,27.2) 38.87,27.2 40.16,25.9 41.22,25.9 41.92,26.6 41.92,28.46 42.28,28.83 43.27,28.83 43.97,28.12 47.01,28.12 49.18,25.95 53.32,25.95 53.89,26.53 54.93,26.53 ; v1(89.21,17.34) 87.51,17.34 86.38,16.21 84.07,16.21 81.13,13.27 77.53,13.27 77.45,13.36 72.16,13.36 71.97,13.55 65.81,13.55 64.83,14.54 64.83,14.63 63.64,15.82 62.1,15.82 60.74,17.18 60.74,19.55 60.36,19.94 ; v1(105.44,68.26) 106.8,66.9 106.8,61.93 104.69,59.83 104.69,55.33 103.89,54.53 ; 103.89,54.53 103.89,44.6 104.28,44.21 104.28,41.2 105.08,40.4 105.08,37.69 108.81,33.97 108.81,26.6 109.57,25.84 v1(109.57,22.54) ; 103.89,54.53 95.28,54.53 v1(94.1,53.35) ; v1(60.36,19.96) 60.36,19.94 ; 60.36,19.94 57.5,22.79 57.5,24.63 55.6,26.53 54.93,26.53 ; 54.93,26.53 v1(54.98,26.48)
  BOTTOM w0.254: v1(68.42,53.5) XU1.AN32 ; v1(66.38,62.35) 66.38,62.36 66.21,62.52 XU1.U38
  BOTTOM w0.305: XU1.AM30 69.53,54.65 69.42,54.53 69.42,54.5 XU1.AN32
  BOTTOM w0.381: v1(59.61,4.56) 59.61,2.14 60.33,1.42 67.52,1.42 v1(67.56,1.46)
  BOTTOM w0.432: SR68.1 17.68,39.33 15.76,39.33 14.43,40.66 14.42,40.66 v1(14.42,41.23) 15.03,41.84 15.03,46.08 14.14,46.97 14.14,49.59 16.07,51.52 v2(16.07,51.39) 16.06,51.38 SR671.1
  BOTTOM w0.457: v1(55.56,11.56) 55.53,11.58 55.53,11.59 55.17,11.96 54.54,11.96 54.28,11.71 PC71.1 53.65,10.73 53.59,10.79 PQ17.2 ; v1(82.06,40.13) 81.91,40.28 SR640.1 ; R60307.1 21.43,29.74 20.76,29.07 v1(20.67,29.07) ; SR3.1 75.57,94.98 v1(75.01,94.42) 74.8,94.21 74.8,93.49 77.06,91.22 v1(79.6,91.22) 79.6,91.22 v1(82.01,91.22) 83.92,91.22 84.53,91.83 87.36,91.83 87.9,91.28 94.23,91.28 v1(94.71,91.77) ; v1(94.1,53.35) 92.88,53.35 92.58,53.04 92.58,51.83 91.46,50.71 91.46,50.47 90.77,49.79 v1(86.86,49.79)
  BOTTOM w0.508: v1(85.82,38.79) 84.63,37.6 83.72,37.6 81.5,35.38 SR81.1
+1P8V_DRI: length 2.8
  BOTTOM w0.457: PR93.2 PR94.1 53.79,7.93 53.83,7.9 PR92.2 PR97.1
+1P8V_DRI1: length 1.8
  BOTTOM w0.457: PC72.1 54.28,8.82 PR92.1 53.76,8.73 53.68,8.82 PR91.1
+1P8V_EN: length 29.4
  TOP w0.457: 71.47,12.9 R60215.2 ; 71.47,12.9 71.23,13.14 70.42,13.14 69.94,13.62 PQ35.3 PR168.2 PR178.1 ; 71.47,12.9 v1(71.47,12.93)
  IN1 w0.508: v1(71.47,12.93) 70.69,12.93 70.35,13.27 69.54,13.27 69.2,12.93 68.42,12.93 68.21,12.72 66.21,12.72 65.17,11.68 62.24,11.68 61.75,12.16 61.75,12.17 61.39,12.53 59.52,12.53 58.31,11.33 v1(58.31,10.63)
  BOTTOM w0.457: v1(58.31,10.63) 58.31,9.2 v2(57.27,8.16) 57.27,7.3 56.17,6.21 PR98.1
+1P8V_EN_2: length 6.7
  BOTTOM w0.254: v2(56.88,5.17) 56.74,5.17 56.5,4.93 55.51,4.93 55.45,4.87 54.46,4.87 54.28,5.05 PR99.2
  BOTTOM w0.457: PR99.2 PR95.1 PC73.1 PR98.2 PR96.1
+1P8V_EN_EC: length 35.7
  IN1 w0.508: v1(79.85,14.87) 80.47,14.25 80.47,11.15 79.54,10.22 63.5,10.22 63.37,10.35 61.56,10.35 61.35,10.56 59.04,10.56 v1(58.95,10.65)
  BOTTOM w0.203: U24.119 80.11,14.61 v1(79.85,14.87)
  BOTTOM w0.457: v1(58.95,10.65) 58.91,10.61 58.91,8.84 v2(59.56,8.19) 58.51,7.15 57.9,7.15 56.33,5.57 55.57,5.57 55.36,5.37 PR99.1
+1P8VSB: length 393.6
  TOP w0.432: C28.1 74.15,63.98 v1(74.21,64.04)
  TOP w0.457: F3R3.1 81.34,75.88 82.17,75.04 FC1.1 ; FC1.1 82.17,74.4 82,74.23 82,74.12 82,73.62 82,73.62 82,73.3 82.44,72.86 87.83,72.86 v1(88.61,72.07) ; FC1.1 F3U1.8 ; SR642.1 SR36.1 SR196.1 SR37.1 76.04,79.3 76.27,79.07 SR641.1 77.65,79.07 SR95.1 SR94.1 79.95,79.32 SR185.2 79.98,79.9 80.05,79.98 v1(80.05,80.02) ; v1(94.58,76.51) 94.11,76.51 93.73,76.89 F3R2.1
  TOP w0.508: v1(92.85,66.39) 89.65,69.59 89.65,69.84 88.61,70.88 v1(88.61,72.07) 92.52,72.07 92.89,72.44 F3R1.1 ; P13.6 112.03,92.26 111.05,93.24 v1(111.05,95.34) ; F3R3.1 81.34,77.34 81.64,77.64 81.64,78.23 80.52,79.35 SR185.2
  IN1 w0.356: v1(17.81,69.66) 18.43,69.04 18.43,62.69 v1(17.6,61.86)
  IN1 w0.381: v1(74.21,64.04) 74.41,64.04 74.52,64.16 74.9,64.53 74.9,66.86 75.53,67.5 75.53,70.04 76.18,70.68 76.18,72.79 77.06,73.67 77.06,76.49 77.49,76.92 77.49,77.9 77.81,78.23 78.41,78.23 80.05,79.87 v1(80.05,80.02)
  IN1 w0.457: 98.86,59.03 98.86,61.74 98.3,62.3 98.3,63.34 99.53,64.57 99.53,65.99 99.24,66.28 99.24,72.03 99.6,72.39
  IN1 w0.508: 98.86,59.03 99.89,58 99.89,56.34 102.77,53.45 102.77,47.11 v1(99.23,43.57) ; v1(94.58,76.51) 94.57,76.53 94.07,76.53 85.02,85.58 76.61,85.58 75.7,86.5 68.98,86.5 67.55,87.93 64.24,87.93 62.59,89.57 60.59,89.57 v1(59.23,90.94) ; v1(17.52,93.61) 15.74,91.83 15.74,84.82 14.46,83.54 14.46,82.57 17.49,79.54 17.49,69.98 v1(17.81,69.66) ; 99.6,72.39 100.04,72.83 v1(101.31,72.83)
  IN2 w0.508: v1(111.05,95.34) 111.05,88.7 109.19,86.84 109.19,83.12 101.31,75.24 v1(101.31,72.83) ; v1(50.61,12.77) 49.56,12.77 48.56,11.77 48.56,10.96 48.05,10.45 v1(47.44,10.45) 47.44,11.06 47,11.5 37.36,11.5 36.97,11.89 36.97,12.75 36.15,13.57 29.28,13.57 27.31,15.54 26.77,15.54 24.4,17.92 24.4,18.91 24.63,19.14 24.63,27.81 24.06,28.38 24.06,29.96 23.84,30.18 v1(23.84,30.18) 23.67,30.18 23.41,30.44 23.41,35.77 19.67,39.51 16.83,39.51 16.68,39.66 16.68,47.76 18.95,50.03 18.95,56 v1(18.38,56.57) 18.38,59.39 18.15,59.62 18.15,59.65 18.13,59.67 18.13,61.33 v1(17.6,61.86) ; v1(17.52,93.61) 18.09,93.04 22.08,93.04 24.17,95.13 32.45,95.13 35.05,97.74 41.37,97.74 43.93,95.17 43.93,93.21 45.34,91.8 46.33,91.8 48.07,90.06 58.35,90.06 v1(59.23,90.94) ; v1(94.58,76.51) v1(94.58,72.45)
  BOTTOM w0.178: v1(74.21,64.04) 74.15,63.98 73.59,63.98 73.27,63.66 73.27,63.51 72.99,63.23 72.79,63.23 72.43,62.88 72.2,62.88 XU1.U25 72.18,62.62 72.18,62.08 XU1.V25
  BOTTOM w0.254: v1(74.21,64.04) 74.42,64.04 XU1.N20
  BOTTOM w0.356: v1(17.81,69.66) Q3.5 Q3.2
  BOTTOM w0.432: v1(92.85,66.39) 92.85,66.43 92.68,66.61 SR47.2 SR167.2 SR170.2 SR171.2 SR183.2 91.19,62.8 SL6.1
  BOTTOM w0.457: SR157.2 SR57.2 SR156.2 ; v1(80.05,80.02) 80.05,79.51 80.1,79.46 SR156.2 ; v1(47.44,10.45) 47.46,10.47 PR54.1 ; SR56.2 SR58.2 SR55.1 SR156.2 ; v1(99.23,43.57) 99.23,43.69 99.62,44.08 102.81,44.08 103.62,44.89 UR1.1
  BOTTOM w0.508: SR665.1 23.41,31.39 23.41,30.49 23.72,30.18 v1(23.84,30.18) ; v1(17.6,61.86) 17.29,62.16 SR664.1 ; PU4.6 46.61,13.39 46.7,13.49 PC49.1 PC48.1 49.89,13.49 v1(50.61,12.77) 50.61,12.4 50.35,12.15 PQ17.3 ; v1(88.61,72.07) 91.91,72.07 92.3,72.45 v1(94.58,72.45) 100.93,72.45 v1(101.31,72.83) ; v1(18.38,56.57) 19.32,56.57 21.33,54.57 22.9,54.57 23.25,54.91 SR34.1 ; v1(17.52,93.61) 17.52,92.59 v2(16.93,92.01)
+1P8VSB_EN: length 2.7
  BOTTOM w0.508: PU4.2 39.21,12.12 38.79,11.71 PC51.1 PR52.1
+1P8VSB_EN_EC: length 3.3
  BOTTOM w0.178: U24.30 67.72,8.12 67.88,7.96 67.88,6.95 ST50.1
+1P8VSB_FB: length 3.3
  BOTTOM w0.508: PC50.2 PR53.2 PR56.1 46.44,12.16 46.4,12.12 PU4.7
+1P8VSB_FB_R: length 4.4
  BOTTOM w0.254: PR54.2 48.32,9.89 47.52,9.89 v2(46.8,9.18)
  BOTTOM w0.508: PR54.2 48.9,10.68 48.86,10.72 PC50.1 PR53.1
+1P8VSB_PG: length 29.3
  IN1 w0.508: v1(63.11,9.72) 62.44,9.05 52.6,9.05 52.02,8.48 48.72,8.48 48.39,8.81 43.91,8.81 v1(43.87,8.85)
  BOTTOM w0.457: 39.93,10.85 39.93,10.28 40.71,9.51 40.71,8.94 PC54.1 ; v1(63.11,9.72) 62.97,9.58 R60291.2 ; PR57.2 PC54.1 ; PC54.1 41.32,8.81 41.32,8.95 41.8,9.43 43.47,9.43 43.87,9.03 v1(43.87,8.85) 44.27,8.85 v2(44.65,9.23)
+1P8VSB_PG_EC: length 8.9
  BOTTOM w0.191: 66.57,8.14 66.59,8.16 66.91,8.16 67.31,8.57 67.31,8.58 67.32,8.59 U24.31
  BOTTOM w0.432: v2(62.07,9.84) 62.07,8.34 62.62,7.79 63.5,7.79 63.81,8.1 R60291.1 64.74,8.7 65.3,8.14 66.57,8.14
+1P8VSB_VDD: length 6.3
  TOP w0.254: v1(40.07,17.48) 39.58,16.99 38.45,16.99 v2(38.3,17.14)
  BOTTOM w0.457: PC53.1 39.95,16.7 40.07,16.82 v1(40.07,17.48)
  BOTTOM w0.508: PU4.4 39.93,15.9 39.95,15.92 PC53.1 PR51.2
+1P35V: length 70.9
  TOP w0.305: v1(71.68,60) 70.31,58.63 70.31,58.56 69.39,57.65 v1(69.39,56.85)
  TOP w0.457: PR175.2 64.86,19.82 65.54,20.49 66.57,20.49 66.59,20.48 66.67,20.48 67.02,20.13 67.02,19.9 v1(67.05,19.87)
  TOP w0.508: v1(84.45,38.72) 83.96,38.72 82.8,37.56 82.26,37.56 81.64,38.17 77.77,38.17 77.69,38.1 71.17,38.1 65.24,32.17 v1(65.24,31.67) ; v1(74.71,57.63) 74.71,58.23 74.5,58.44 SL14.2
  IN1 w0.305: v1(71.68,60) 72.99,61.31 74.17,61.31 74.48,61.01 74.48,60.57 74.47,60.57 74.47,58.17 74.67,57.97 74.67,57.67 v1(74.71,57.63) 74.71,56.88 v1(74.73,56.86)
  IN2 w0.508: 61.18,41.72 61.18,37.14 65.24,33.07 v1(65.24,31.67) 65.24,31.17 65.99,30.43 65.99,26.87 65.23,26.11 65.23,21.99 67.05,20.18 v1(67.05,19.87)
  BOTTOM w0.254: XU1.U36 66.92,62.57 66.92,62.12 ; v1(71.68,60) 72.06,60.38 XU1.AA25 ; 66.92,62.12 XU1.V36 ; 66.92,62.12 v1(66.36,61.56) ; v1(66.37,59.21) 66.75,58.83 XU1.AD36 ; v1(69.39,56.85) 69.39,56.88 XU1.AG32 ; XU1.AG19 74.94,57.09 74.73,56.89 v1(74.73,56.86) ; v1(74.71,57.63) 74.71,57.65 XU1.AF19
  BOTTOM w0.508: v1(84.45,38.72) 84.85,38.72 85.31,39.18 SL13.2
  vias: v1(59.28,41.97) v1(59.91,41.97) v1(60.55,42.6) v1(60.55,41.97) v1(61.18,43.24) v1(61.18,42.6) v1(61.18,41.97) v2(59.58,39.81)
+1P35V_DAUL_PG_G: length 9.9
  TOP w0.254: v2(64.69,86.29) 65.44,85.54 R251.1
  TOP w0.457: R251.1 HC9.1 65.44,83.75 65.64,83.55 65.66,83.55 65.69,83.52 Q38.1
  TOP w0.508: Q38.1 65.69,82.04 65.11,81.45 63.3,81.45 62.21,80.36 Q39.3
+1P35V_DRI: length 3.7
  BOTTOM w0.457: PR102.2 PR103.1 PR101.1 PR105.1 52.99,35.81 v2(53.56,36.38)
+1P35V_DRI1: length 2.9
  BOTTOM w0.457: PR101.2 54.62,35.71 54.58,35.75 PC75.1 PR100.1 55.47,35.49 v2(55.59,35.37)
+1P35V_DUAL: length 83.7
  TOP w0.254: 29.05,88.58 29.96,89.49 31.82,89.49 32.63,88.68 34.87,88.68 35.63,89.44 35.63,90.31 35.8,90.47 38.64,90.47 38.95,90.78 D3R1.1
  TOP w0.457: SR2.1 64.74,74.69 65.53,73.9 65.53,72.56 65.92,72.17 65.92,69.16 65.73,68.97 ; D3R2.1 32.73,54.54
  IN2 w0.508: v1(49.83,33.87) 50.04,33.65 50.04,30.3 v1(49.6,29.85)
  BOTTOM w0.152: XU1.BD52 59.3,48.76 59.3,48.7 59.45,48.55 59.45,47.98 XU1.BG51
  BOTTOM w0.191: XU1.F52 59.32,68.11 59.32,68.18 59.66,68.51 XU1.C51
  BOTTOM w0.203: XU1.BG51 59.76,47.88 59.76,48.42 60.04,48.7 60.04,49.01 v1(59.61,49.44)
  BOTTOM w0.254: v1(61,49.59) 60.73,49.32 XU1.BD49 ; XU1.BF44 63.35,48.62 63.39,48.62 v1(63.49,48.72) ; v1(64,52.61) 63.68,52.29 XU1.AV42 ; v1(63.97,51.65) 64.39,52.06 XU1.AV41 ; XU1.BJ48 61.01,46.01 v1(61,46.01) ; v1(63.49,68.05) 62.99,68.54 XU1.D44 ; XU1.BD53 v1(57.88,49.13) ; XU1.AM38 65.99,54.91 v1(66.38,55.29) 65.99,55.68 XU1.AK38 ; v1(57.04,68.13) 57.67,68.13 58.09,67.72 XU1.F53 58.93,67.72 XU1.F52 59.45,67.5 60.44,67.5 60.67,67.73 XU1.F49 ; XU1.H46 62.51,66.4 v1(62.51,66.22) ; XU1.V38 65.82,61.78 65.82,61.34 ; v1(62.42,49.65) 62.18,49.89 XU1.BB46 ; 65.82,61.34 v1(66.37,60.79) ; 65.82,61.34 XU1.Y38
  BOTTOM w0.305: XU1.BD52 59.23,49.13 59.3,49.13 v1(59.61,49.44) ; XU1.AD38 66.37,58.44 v1(66.37,58.43) 66.37,58.41 XU1.AF38 ; v1(60.84,70.83) 61.01,70.66 XU1.A48
  BOTTOM w0.356: XMM1.118 v1(32.93,56.08) ; XMM1.99 v1(38.34,61.78) ; XMM1.123 41.15,54.58 41.88,55.3 v1(41.88,56.45) ; XMM1.81 v1(38.36,67.18) ; XMM1.112 v1(32.93,57.88) ; XMM1.82 v1(32.92,66.88) ; XMM1.111 v1(38.36,58.18) ; XMM1.100 v1(32.93,61.48) ; v1(38.36,65.37) 38.36,65.38 XMM1.87 ; XMM1.76 v1(32.92,68.68) ; XMM1.106 32.86,59.68 v1(33.03,59.51) ; XMM1.88 v1(32.93,65.08) ; v1(38.36,56.38) 38.36,56.38 XMM1.117 ; XMM1.93 v1(38.34,63.58) ; XMM1.105 v1(38.34,59.98) ; XMM1.75 v1(38.34,68.98) ; XMM1.124 v1(32.93,54.28) ; XMM1.94 v1(32.93,63.28)
  BOTTOM w0.457: v1(49.6,29.85) 49.86,29.85 50.22,29.49 SR1.1
  BOTTOM w0.508: SR5.1 49.88,33.82 v1(49.83,33.87) ; PU6.3 60.62,34.6 60.46,34.44 PC80.1 56.59,34.44 v1(55.57,33.42)
  vias: v1(54.2,41.18) v1(54.69,41.6) v1(64.04,64.24) v2(21.38,77.56) v3(22.19,77.78) v3(22.19,76.89)
+1P35V_DUAL_BOOT_C: length 1.8
  BOTTOM w0.508: v2(17.67,78.42) 16.93,77.68 PR147.1
+1P35V_DUAL_BST_C: length 2.6
  BOTTOM w0.508: PR147.2 16.22,79.82 16.64,80.23 PC110.2 v2(17.72,80.7)
+1P35V_DUAL_CS_A: length 4.9
  BOTTOM w0.222: PU8.13 12.54,80.16 PR160.1
  BOTTOM w0.229: v2(13.7,83.09) 13.81,82.98 13.81,81.43 PR160.1
+1P35V_DUAL_FB1_A: length 8.8
  BOTTOM w0.222: PU8.6 10.51,76.6 10.28,76.37 PR159.1
  BOTTOM w0.229: 8.76,74.48 9.06,74.79 9.06,75.61
  BOTTOM w0.254: PC117.2 8.54,72.39 8.3,72.63 8.3,74.02 8.76,74.48 ; PC117.2 PR158.1 ; PC117.2 9.19,71.69 v2(8.88,71.38) ; 9.06,75.61 PR159.1
+1P35V_DUAL_FB_A: length 24.1
  TOP w0.152: v1(23.42,78.52) 23.56,78.66 PJP8.2
  IN2 w0.254: v1(23.42,78.52) 23.42,77.25 22.31,76.13 11.62,76.13 9.35,73.87 v1(9.2,73.87)
  BOTTOM w0.222: PC118.1 10.86,74.81 11.74,75.69 PU8.5
  BOTTOM w0.254: v2(9.76,74.43) v1(9.2,73.87) 9.19,73.87 PC117.1 PR158.2 PC118.1
+1P35V_DUAL_HG_D: length 2.2
  TOP w0.635: 15.87,80.07 15.87,79.31 v3(14.84,78.28)
  vias: v2(16.35,80.12)
+1P35V_DUAL_LG_D: length 14.3
  BOTTOM w0.222: 13.81,79.82 13.34,79.35 PU8.15
  BOTTOM w0.635: 13.81,79.82 13.81,80.26 14.47,80.92 14.47,83.32 15.41,84.26 15.41,88.12 v1(14.55,88.99) v2(14.55,90.15) 14.55,90.84 v3(13.81,91.58)
+1P35V_DUAL_PG: length 195.9
  TOP w0.254: v1(41.11,97.11) 42.61,97.11 45.92,93.81 45.92,92.24 45.56,91.88 45.56,89.47 49.38,85.65 60.06,85.65 60.3,85.4 R60208.1 ; v1(9.28,80.7) 9.28,80.79 7.21,82.86 7.21,89.54 7.84,90.18 v1(7.84,91.25)
  IN2 w0.254: v1(7.84,91.25) 8.35,91.75 11.65,91.75 12.29,92.39 22.19,92.39 24.35,94.55 28.43,94.55 29.41,93.58 ; 29.41,93.58 29.41,83.14 30.22,82.33 30.22,64.53 31.93,62.82 31.93,52.68 32.48,52.12 32.48,34.56 33.92,33.12 35.95,33.12 36.4,33.58 38.92,33.58 41.62,36.28 60.21,36.28 62.55,33.93 62.55,31.69 63.06,31.19 63.47,31.19 63.9,31.62 v1(63.9,31.68) ; 29.41,93.58 30.38,94.55 32.55,94.55 35.11,97.11 v1(41.11,97.11)
  BOTTOM w0.102: v2(7.05,90.89) 7.49,90.89 v1(7.84,91.25)
  BOTTOM w0.222: PR157.2 10.23,80.07 10.63,79.66 10.63,78.52 10.95,78.2 PU8.10
  BOTTOM w0.229: v1(9.28,80.7) 9.05,80.48 PR157.2
  BOTTOM w0.254: R213.2 77.65,30.36 75.23,30.36 74.8,29.93 71.76,29.93 70.95,30.74 65.09,30.74 64.87,30.96 64.62,30.96 v1(63.9,31.68)
+1P35V_DUAL_PHASE_D: length 5.9
  BOTTOM w0.635: 13.94,78.67 15.09,79.83 15.09,80.5 PC110.1 15.33,80.74 v3(15.33,82.99) v2(16.32,82.99)
+1P35V_DUAL_S3_A: length 7.7
  BOTTOM w0.222: PC112.2 10.18,77 PU8.7
  BOTTOM w0.254: PR151.2 PR149.2 6.86,78.44 v2(7.02,78.29) 7.02,77.26 7.62,76.65 9.19,76.65 PC112.2
+1P35V_DUAL_S5_A: length 6.5
  BOTTOM w0.222: PC114.1 9.92,78.16 10.61,77.48 10.61,77.48 10.69,77.4 PU8.8
  BOTTOM w0.254: PC114.1 8.77,78.67 7.89,78.67 7,79.56 v2(7,80.04) 6.93,80.12 PR154.2
+1P35V_DUAL_SN_C: length 0.9
  BOTTOM w0.508: v2(13.45,85.45) 13.45,85.14 v1(13.84,84.76)
+1P35V_DUAL_TON_A: length 3.1
  BOTTOM w0.222: PU8.9 10.74,77.8 10,78.55 10,79.14
  BOTTOM w0.229: PR148.2 v2(10,79.18) 10,79.14
+1P35V_DUAL_VDD: length 4.8
  BOTTOM w0.222: PU8.12 12.14,80.12 12.03,80.23 PC104.2 PR146.2
  BOTTOM w0.254: PR146.2 10.13,80.8 v2(9.57,81.35)
+1P35V_DUAL_VIN: length 4.9
  BOTTOM w0.254: PR148.1 7.74,79.65 7.74,80.55 v2(6.55,81.75) 6.84,82.04 6.84,83.24
  vias: v3(8.17,84.67) v3(8.5,82.47) v3(9.06,84.67)
+1P35V_EN_EC: length 16.4
  TOP w0.508: v1(62.62,12.3) 62.55,12.3 62.12,12.73 60.85,12.73 59.76,13.83 v2(59.76,16.34) 59.17,16.93 v1(59.17,17.07)
  IN2 w0.508: v1(55.25,21.07) 55.61,21.07 56.04,20.64 56.04,20.21 v1(59.17,17.07)
  BOTTOM w0.203: U24.35 63.08,11.8 62.62,12.26 v1(62.62,12.3)
  BOTTOM w0.457: v1(55.25,21.07) 55.31,21.13 PR108.1
+1P35V_PG: length 2.2
  TOP w0.457: R60215.1 v1(71.47,10.84)
  BOTTOM w0.203: U24.20 71.72,10.59 v1(71.47,10.84)
+3P3V: length 602.8
  TOP w0.229: 15.16,96.61 14.05,96.61 13.64,97.01 13.64,97.02 13.58,97.07 13.58,97.41 AU1.11
  TOP w0.356: SC14.1 44.76,25.16 45.78,25.16 45.94,24.99 U4.8
  TOP w0.381: SC12.1 44.81,28.38 SR120.1 45.23,28.8 U3.8
  TOP w0.432: AC39.1 16.82,95.49 17.63,94.68 18.34,94.68 20.46,92.56 v1(20.46,91.57) ; AC39.1 16.82,96.66 16.82,96.66 AC38.1 ; AC39.1 15.56,96.2 15.16,96.61 ; v1(10.28,18.96) 10.18,18.86 FR5.1 FR1.1
  TOP w0.457: O2R247.1 78.8,22.37 79.09,22.66 v1(79.09,23.43) ; v1(41.12,31.78) 40.9,31.56 SR163.2 40.26,32.03 40.35,32.11 D3CB8.1 39.81,33.05 D3CB6.1 D3CB7.1 39.81,34.77 39.4,35.18 36.84,35.18 34.68,33.02 33.8,33.02 32.26,34.55 v1(29,34.55) ; M1R1.1 82.77,94.51 82.77,98.74 81.84,99.67 v1(80.4,99.67) ; L2.1 21.33,102.26 AC53.1 AC55.1 22.82,102.01 AC54.1 24.86,102.01 v1(24.86,102.01) ; SR119.1 44.12,26.08 v1(44.01,25.97) 44.4,25.97 44.61,25.76 SC14.1 ; SC12.1 44.05,28.74 43.74,29.04 SR114.1 SR112.1 v1(43.1,30.67) ; v1(72.53,41.62) 72.53,42.63 73.14,43.24 73.14,44.41 72.63,44.92 72.63,46.99 72.85,47.21 72.85,48.16 72.44,48.57 SL4.1 72.44,50.11 73.26,50.92 73.26,51.11 73.83,51.69 73.83,52.48 73.44,52.87 v1(72.36,52.87) 72.06,52.87 72.05,52.85 C69.1 ; v1(70.2,21.65) O2R244.2 O2R241.2 O2R243.2 68.42,22.01 68.22,21.8 67.13,21.8 67.12,21.82 62.84,21.82 v1(62.57,22.09)
  TOP w0.508: L2.1 20.47,101.91 20.47,101.36 20.45,101.36 v2(17.77,98.68) 16.82,97.74 AC38.1 ; v1(76.9,5.42) 76.9,5.47 77.43,6 82.31,6 82.67,6.36 82.67,7.18 v3(82.66,7.2) 82.64,7.2
  IN1 w0.508: v1(84.8,22.11) 84.8,23.71 85.48,24.38 85.48,25.42 87.05,26.99 87.05,27.27 87.64,27.86 89.41,27.86 v1(89.58,27.69) ; v1(82.85,22.16) 82.81,22.12 82.81,19.31 82.94,19.17 82.94,18.14 82.02,17.22 82.02,15.03 ; v1(24.86,102.01) 25.64,101.23 50.65,101.23 51,101.57 53.34,101.57 53.87,102.1 v1(53.87,102.45) 54.78,102.45 55.66,101.57 58.37,101.57 v1(61.27,98.66) 79.39,98.66 v1(80.4,99.67) ; v3(20.08,18.22) 19.98,18.12 13.28,18.12 12.44,18.96 v1(10.28,18.96)
  IN1 w0.762: v3(112.34,36.61) 115.66,33.28 115.66,23.05 110.08,17.46
  IN1 w1.016: v3(25.25,18.25) 24.42,17.42 20.49,17.42 20.15,17.76 20.15,18.06 20.08,18.12 v3(20.08,18.22)
  IN1 w1.524: 82.34,9.28 82.02,9.6 82.02,15.03 80.74,16.32 76.67,16.32 75.95,17.04 66.24,17.04 65.47,16.27 61.21,16.27 60.62,15.68 57.01,15.68 56.71,15.39 54.05,15.39 52.97,14.31 45.16,14.31 44.31,13.46 40.31,13.46 39.56,14.21 37.41,14.21 36.62,15 32.15,15 32.1,15.05
  IN1 w1.905: 107.28,16.34 103.75,12.81 97.25,12.81 96.23,11.8 96.23,10.3 95.32,9.38
  IN2 w0.457: v1(70.2,21.65) 70.83,21.65 72.36,23.17 77.69,23.17 77.95,23.43 v1(79.09,23.43)
  IN2 w0.508: v1(70.2,21.65) 70.2,22.82 73.31,25.93 73.31,30.02 71.77,31.56 v1(71.77,31.58) ; v1(62.57,22.09) 62.57,22.1 61.47,23.2 61.47,28.26 58.6,31.12 56.72,31.12 56.19,31.65 56.19,31.82 56.13,31.89 ; v1(86.71,36.13) 86.71,34.85 88.33,33.23 88.33,28.94 v1(89.58,27.69) 89.64,27.63 v1(89.64,24.65) ; v1(43.1,30.67) 47.03,30.67 48.56,29.13 48.56,28.29 49.7,27.16 50.83,27.16 54.47,30.79 55.03,30.79 56.13,31.89 ; v1(21.96,39.48) 21.96,38.92 22.4,38.49 23.15,38.49 23.64,38 23.64,36.92 24.1,36.46 24.1,32.06 24.67,31.49 24.67,28.63 25.25,28.05 v3(25.25,18.25) ; v1(79.09,23.43) 79.65,22.87 82.44,22.87 82.85,22.46 v1(82.85,22.16) 84.76,22.16 v1(84.8,22.11) ; 56.13,31.89 v1(56.15,31.89) ; v1(30.22,22.25) 30.22,27.72 28.99,28.95 28.99,34.54 v1(29,34.55) 29,35.09 29.69,35.77 29.69,50.23 28.4,51.51 28.4,57.74 25.6,60.54 25.6,60.86 23.93,62.53 23.23,62.53 20.25,65.51 20.25,68.89 23.89,72.54 v1(23.89,73.34) 24.48,73.93 24.48,78.29 26.69,80.5 26.69,89.24 25.96,89.98 22.05,89.98 v1(20.46,91.57)
  IN2 w1.016: v3(20.08,18.22) 20.08,23.15 19.06,24.18 19.06,28.81 18.43,29.43 18.43,31.2 16.43,33.21 16.43,35.09 14.88,36.64 14.24,36.64 13.47,37.41 13.47,41.98 12.83,42.62 12.83,47.56 11.94,48.45 11.94,51.93 10.54,53.34 9,53.34 8.48,53.85 8.48,54.51 7.13,55.86 7.13,60.56 6.22,61.48 v3(6.22,67.07)
  BOTTOM w0.203: C267.1 76.04,7.3 75.52,7.82 75.32,8.02 75.32,8.09 75.32,8.09 U24.11 ; v1(72.36,52.87) 72.36,53.15 72.13,53.37 72.13,53.38 71.4,54.11 XU1.AN27
  BOTTOM w0.356: TPU1.24 85.72,25.27 85.48,25.03 85.48,24.32 TPC4.1 ; TPU1.19 88.97,24.87 88.92,24.82 TPC1.1 ; TPC2.1 88.87,33.49 88.97,33.38 TPU1.10 ; v1(41.12,31.78) XMM1.199 ; TPC3.1 85.65,33.97 85.65,33.96 85.72,33.9 TPU1.5
  BOTTOM w0.457: v1(53.87,102.45) 53.87,102.09 53.35,101.57 R93.2 ; TPC2.1 89.18,34.31 89.46,34.59 89.46,36.02 89.07,36.41 89.07,37.02 88.51,37.58 87.78,37.58 86.71,36.51 ; 86.71,36.51 v1(86.71,36.13) 86.2,35.62 TPR1.1 ; 86.71,36.51 86.71,36.76 86.25,37.22 85.26,37.22 84.68,36.64 84.68,35.99 84.31,35.62 CB1.1 84.73,34.31 TPC3.1 ; PR110.1 58.89,31.99 57.83,30.92 56.96,30.92 56.15,31.73 v1(56.15,31.89) ; TPC1.1 89.34,24.1 89.64,24.41 v1(89.64,24.65) ; v1(76.9,5.42) 76.9,6.59 76.66,6.83 C267.1 ; v1(84.8,22.11) 84.8,23.71 85.2,24.1 TPC4.1 ; J125.20 88.07,101.24 88.07,99.46 88.57,98.95 M1C14.1 84.42,97.72 82.47,99.67 v1(80.4,99.67) ; R60308.1 21.2,38.9 21.79,39.48 v1(21.96,39.48) ; SR29.1 23.89,73.34 v1(23.89,73.34) ; R95.2 60.46,97.85 v1(61.27,98.66)
  BOTTOM w0.508: v1(72.53,41.62) 72.37,41.46 72.37,38.66 71.55,37.83 71.55,34.79 72.05,34.29 72.05,33.95 72.05,33.95 72.05,31.86 v1(71.77,31.58) ; v1(10.28,18.96) 9.78,19.46 FD3.3 ; v1(41.12,31.78) 41.28,31.94 41.83,31.94 43.1,30.67 v1(43.1,30.67) 44.5,30.67 44.96,30.2 44.96,29.66 44.01,28.71 v1(44.01,25.97) ; v1(80.4,99.67) 79.92,99.19 MQ36.1
  BOTTOM w1.016: 29.86,20.91 26.15,20.91 25.49,20.25 25.49,18.49 v3(25.25,18.25)
  vias: v1(31.46,16.32) v1(32.22,16.32) v1(33.24,16.32) v1(33.88,16.32) v1(108.68,16.54) v3(29.81,20.76) v3(30.7,20.76) v3(82.66,8.09) v3(94.34,9.09) v3(94.41,8.21) v3(108.81,17.46) v3(109.47,16.6)
+3P3V_DRI: length 3.9
  BOTTOM w0.457: v2(26.54,16.49) 26.38,16.65 PR82.2 25.87,17.55 PR83.2 25.53,16.27 PR88.1 PR84.1
+3P3V_DRI1: length 3.6
  TOP w0.508: v2(28.46,17.77) 28.35,17.77 v1(27.91,18.22)
  BOTTOM w0.457: v1(27.91,18.22) 27.74,18.39 PC69.1 PR82.1 26.34,18.42 PR81.1
+3P3V_EN_1: length 10.2
  TOP w0.508: v1(18.57,18.86) 18.2,19.23 v2(18.2,19.69)
  IN2 w0.508: v1(18.23,23.2) 18.57,22.85 v1(18.57,18.86)
  BOTTOM w0.457: v1(18.57,18.86) 18.6,18.88 PR86.1 ; PR85.2 PR86.1 ; PR86.1 PC70.1
  BOTTOM w0.508: v1(18.23,23.2) 18.6,22.83 PR90.2 PR87.1
+3P3V_EN_EC: length 64
  TOP w0.508: v1(37.48,23.43) 37.58,23.53 40.15,23.53 40.53,23.91 41.47,23.91 42.1,23.29 48.77,23.29 48.87,23.19 56.67,23.19 61.23,27.75 66,27.75 68.6,30.34 71.93,30.34 73.32,28.95 73.32,28.59 75.35,26.56 v1(75.35,26.22)
  BOTTOM w0.203: U24.87 75.72,25.86 v1(75.35,26.22)
  BOTTOM w0.457: v1(37.48,23.43) 36.87,24.04 30.75,24.04 v2(29.71,23) 28.49,21.78 PR90.1
+3P3V_PG: length 4.8
  TOP w0.457: v1(76.57,23.83) 77.11,23.83 77.31,23.63 O2C59.1 O2R247.2 78.2,23.83 v2(78.61,24.24)
  BOTTOM w0.203: v1(76.57,23.83) 76.47,23.83 76.12,24.19 U24.88
+3P3VSB: length 655.5
  TOP w0.203: 80.79,66.81 79.98,66.81 79.63,67.15 79.63,68.45 79.49,68.6 79.49,69.38 78.79,70.08 78.79,71.23 78.56,71.46 77.27,71.46 77,71.19 77,70.8 77.26,70.54 77.26,68.87 76.6,68.21 76.6,66.58 76.95,66.23
  TOP w0.254: C67.1 77.87,75.77 78.15,75.49 78.15,75.47 78.16,75.47 78.16,75.47 v1(78.16,75.47) ; v1(74.29,64.71) 74.45,64.87 C68.1 75.25,64.87 v1(76.1,64.02)
  TOP w0.305: 77.35,66.02 78.24,65.13 79.07,65.13 79.4,64.8 80.18,64.8 80.42,65.05 80.42,65.06 80.43,65.07 80.43,65.08 80.48,65.14 80.48,65.17 80.48,65.17 80.48,66.51
  TOP w0.457: v1(39.92,24.19) 38.87,25.24 PR120.2 ; O2R245.1 67.2,11.1 v1(67.45,10.84) ; C68.1 74.95,65.31 ; v1(104.4,15.64) R368.1 R357.1
  TOP w0.508: v1(17.52,69.02) 18.33,69.02 v1(20.85,71.54) ; v1(105.91,18.96) 105,19.87 94.46,19.87 v1(93.96,20.38) ; v1(50.04,23.81) 50.57,24.33 54.11,24.33 54.29,24.51 56.24,24.51 v1(56.64,24.11) ; 76.57,65.77 76.37,65.57 75.2,65.57 74.95,65.31 ; v1(57.69,90.81) 58.39,90.81 59.23,89.97 62.19,89.97 63.04,89.13 63.04,86.06 63.82,85.28 R251.2 ; v1(98.7,58.25) 99.09,58.65 99.09,61.38 95.56,64.91 90.8,64.91 89.5,66.2 89.5,66.51 87.94,68.07 84.77,68.07 83.51,66.81 81.75,66.81 81.7,66.76 80.84,66.76
  TOP w1.524: 21.43,95.79 26.61,90.61 30.09,90.61 31.82,92.34 ; 44.44,93.71 42.89,95.26 40.89,95.26 39.97,94.34 37.38,94.34 35.18,92.15
  IN1 w0.254: v1(76.1,64.02) 76.1,65.47 76.64,66.01 76.64,66.78 76.96,67.11 76.96,68.5 76.55,68.92 76.55,69.78 76.96,70.2 76.96,72.43 77.83,73.3 77.83,75.14 v1(78.16,75.47)
  IN1 w0.508: v1(104.4,15.64) 104.84,16.09 104.84,17.89 v1(105.91,18.96) 107.52,20.57 108.98,20.57 113.59,25.18 113.59,31.17 108.09,36.66 108.09,38.88 105.24,41.74 105.24,55.96 v1(105.67,56.39) 105.67,59.15 105.9,59.38 105.9,66.05 105.53,66.42 105.28,66.42 v1(105.25,66.44) ; v1(93.96,20.38) 93.96,17.32 93.57,16.93 v1(93.57,15.45) ; v1(29.61,32.52) 28.38,33.75 28.38,34.38 26.93,35.84 24.92,35.84 v1(22.95,37.8) ; v1(56.64,13.45) 55.73,13.45 53.8,11.52 52.55,11.52 51.94,10.9 50.31,10.9 49.94,11.27 49.43,11.27 48.19,11.27 47.76,11.71 45.29,11.71 45.11,11.53 39.58,11.53 39.53,11.48 37.21,11.48 35.92,12.77 v3(35.9,12.77) ; v1(21,51.88) 21,57.29 19.79,58.49 19.79,59.61 20.84,60.66 v1(20.84,61.82) 20.84,65.05 v1(21.65,65.86) 22.31,66.52 22.31,69.87 20.85,71.33 v1(20.85,71.54) 21.67,72.36 21.67,74.99 v1(21.02,75.64) 21.05,75.66 21.05,78.29 v1(21.3,78.55) 22.79,80.03 24.9,80.03 26.87,82 26.87,89.49 26.61,89.75 26.61,93.93 27.2,94.52 30.93,94.52 v1(31.54,93.91) ; v1(16.78,56.75) 16.78,58.91 15.27,60.42 15.27,61.44 16.43,62.59 16.43,63.19 15.93,63.69 15.93,65.78 v1(15.31,66.4) 15.31,67.01 17.32,69.02 v1(17.52,69.02) ; v1(57.69,90.81) 58.41,90.81 60.9,88.32 62.84,88.32 63.85,87.32 67.29,87.32 68.73,85.89 75.45,85.89 76.79,84.54 85.2,84.54 93.85,75.89 95.59,75.89 96.83,77.14 98.9,77.14 102,74.04 v1(102,71.94) ; v1(9.14,26.53) 11.6,26.53 11.82,26.74 31.35,26.74 v1(31.74,26.35)
  IN1 w1.524: 6.95,89.82 6.95,85.61 6.71,85.37 6.71,80.84 8.96,78.6 8.96,75.37 5.1,71.51 5.1,69.99
  IN2 w0.508: v1(93.57,15.45) 93.34,15.22 84.55,15.22 80.47,11.15 79.54,10.22 72.73,10.22 72.1,10.85 72.1,11.09 71.73,11.46 68.04,11.46 67.67,11.1 67.67,11.06 v1(67.45,10.84) 66.82,11.48 65.18,11.48 64.36,12.3 63.75,12.3 62.88,13.17 61.26,13.17 60.97,13.46 56.72,13.46 56.71,13.45 v1(56.64,13.45) ; v1(29.61,32.52) 29.61,29.37 31.74,27.24 v1(31.74,26.35) ; v1(8.6,80.7) 8.6,80.45 10.13,78.93 13.01,78.93 14.79,77.15 19.91,77.15 v1(21.3,78.55) ; v1(102,71.94) 104.56,69.38 104.56,67.13 v1(105.25,66.44) 105.67,66.44 105.9,66.21 105.9,61.9 103.9,59.9 99.5,59.9 98.82,59.23 98.82,58.38 v1(98.7,58.25)
  IN2 w1.524: 61.49,94.29 60.62,93.43 54.78,93.43 ; 20.91,95.37 16.13,95.37 15.04,94.28 8.44,94.28 7.14,92.99 ; 5.06,69.58 4.68,69.2 4.68,56.03 6.09,54.62 6.09,52.51 6.84,51.76 9.26,51.76 10.38,50.64 10.38,48.75 9.41,47.79 9.16,47.79 7.7,46.32 7.7,38.98 6.63,37.91 6.63,25.86 7.13,25.36 7.13,20.44 15.18,12.39 15.18,11.23 17.97,8.44 21.2,8.44 23.59,10.83
  BOTTOM w0.254: v1(74.29,64.71) 74.12,64.71 XU1.N22 ; XU1.P18 75.7,63.62 v1(76.1,64.02) 75.78,64.33 XU1.N18
  BOTTOM w0.432: v1(16.78,56.75) 16.78,57.77 16.06,58.49 R4.2
  BOTTOM w0.457: v1(105.67,56.39) 105.67,56.32 PR182.1 ; 22.93,36.51 22.53,36.12 SR66.1 ; R252.1 48.3,23.94 48.14,23.94 48.13,23.92 47.91,23.92 47.43,23.44 45.55,23.44 45.36,23.63 45.32,23.67 PR132.2 41.95,23.67 41.43,24.19 v1(39.92,24.19) ; 56.64,24.08 57.04,24.48 58.26,24.48 61,27.23 61,28.38 61.46,28.84 62.22,28.84 62.49,29.1 PR109.1 ; v1(105.25,66.44) PR196.1 ; PR34.1 9.5,25.04 9.14,25.41 v1(9.14,26.53) ; PR157.1 8.21,80.31 v1(8.6,80.7) ; R8.1 21.68,65.9 v1(21.65,65.86) ; v1(20.85,71.54) 21.49,71.54 SR28.1 ; PR59.1 v1(93.57,15.45) ; v1(21,51.88) 21.07,51.95 SR670.1 ; v1(17.52,69.02) 17.14,69.4 SR15.1 ; SR624.1 21.77,60.89 v1(20.84,61.82) ; v1(15.31,66.4) 15.39,66.48 SR72.1
  BOTTOM w0.508: PR57.1 38.27,8.57 ; v1(31.74,26.35) 33.48,26.35 34.88,24.95 39.16,24.95 v1(39.92,24.19) ; R60309.2 22.18,75.65 21.03,75.65 v1(21.02,75.64) ; v1(93.96,20.38) PC57.1 PU5.3 ; v3(61.64,94.98) 61.64,94.78 61.47,94.61 61.47,94.09 58.75,91.37 58.25,91.37 v1(57.69,90.81) ; v1(21.3,78.55) 21.94,79.18 R60302.2 ; v1(22.95,37.8) 22.93,37.78 22.93,36.51 ; v2(4.82,91.35) 5.15,91.68 v3(5.89,91.68) ; v1(56.64,24.11) v1(56.64,13.45) ; R252.1 48.32,23.67 48.68,23.3 49.54,23.3 v1(50.04,23.81)
  BOTTOM w1.524: 30.12,16.77 29.44,16.1 28.38,16.1 24.88,12.61
  vias: v3(4.44,71.28) v3(4.44,70.34) v3(6.8,91.7) v3(20.24,95.16) v3(20.26,96.15) v3(23.64,12.22) v3(23.63,11.34) v3(44.68,93.71) v3(45.22,93) v3(62.58,94.9)
+3P3VSB_BST_C: length 4.9
  BOTTOM w0.222: PR40.1 12.46,29.75 12.9,30.2 PU3.9
  BOTTOM w0.508: v2(10.71,31.33) 10.71,30.26 PR40.1
+3P3VSB_BST_RC_C: length 2.8
  BOTTOM w0.508: PC38.1 10.41,28.46 v2(10.23,28.28) 10.23,29.02 PR40.2
+3P3VSB_EN_EC: length 2
  BOTTOM w0.203: 64.02,11.4 U24.34
  BOTTOM w0.254: 64.02,11.4 63.59,10.98 ST52.1
+3P3VSB_FB_A: length 5.4
  BOTTOM w0.222: PU3.4 15.87,32.43 16.1,32.65 16.1,33.46 16.29,33.65 PC46.2
  BOTTOM w0.254: PR50.2 18.33,33.65 PR49.2 PC46.2
+3P3VSB_FBR: length 33.3
  TOP w0.254: v1(32.86,12.89) 31.77,13.98 28.14,13.98 22.22,19.9 21.32,19.9 20.79,20.42 v2(20.79,22.87) 20.79,25.01 18.4,27.4 18.37,27.4 v1(16.17,29.6)
  BOTTOM w0.254: PC46.1 PR49.1 18.33,32.81 PC47.1 16.16,29.6 v1(16.17,29.6) ; PJP5.2 32.95,12.8 v1(32.86,12.89)
+3P3VSB_HG_D: length 29
  TOP w0.635: v3(26.38,10.7) 26.38,12.89 22.06,17.2 18.17,17.2 15.97,19.41 15.97,25.33 v2(13.36,27.94) 12.24,29.07 v3(12.24,30.39)
  BOTTOM w0.222: v3(12.24,30.39) 12.5,30.65 PU3.10
+3P3VSB_LG_D: length 38.8
  TOP w0.635: v3(22.45,1.58) 24.86,4 24.86,12.76 21.46,16.16 17.52,16.16 14.8,18.88 v2(14.8,23.53) 14.8,24.78 10.97,28.61 10.97,30.51 v3(11.55,31.1)
+3P3VSB_PG: length 9.8
  TOP w0.457: O2C56.1 O2R245.2 66.67,12.29 66.48,12.1 v1(66.47,12.1)
  BOTTOM w0.203: U24.48 66.36,17.01
  BOTTOM w0.457: 66.36,17.01 67.1,17.01 68.47,15.64 68.47,14.82 66.47,12.81 v1(66.47,12.1)
+3P3VSB_PHASE_D: length 36.3
  TOP w0.635: v3(26.86,4.97) v2(26.86,6.89) 26.86,8.8 27.4,9.33 27.4,13.5 21.86,19.03 20.77,19.03 17.11,22.69 17.11,25.79 v3(13.99,28.91)
  BOTTOM w0.222: 13.17,29.58 13.3,29.71 PU3.8
  BOTTOM w0.457: 13.17,29.58 12.83,29.24 12.32,29.24 12.04,28.97 PC38.2 12.84,28.46
  BOTTOM w0.635: 12.84,28.46 13.53,28.46 v3(13.99,28.91)
+3P3VSB_SN_D: length 0.8
  TOP w0.635: v2(22.42,7.04) v1(22.42,6.28)
+BATT: length 347.3
  IN1 w0.254: v1(48.39,99.63) 51.68,99.63 51.83,99.48 53.61,99.48 54.86,100.72 55.95,100.72 56.33,100.34 56.33,98.37 57.05,97.65 58.92,97.65 59.61,96.96 61.84,96.96 62.93,98.05 70.55,98.05 71.21,97.39 74.57,97.39 76.27,95.69 88.18,95.69 89.91,97.42 95.75,97.42 96.06,97.11 101.97,97.11 102.35,97.49 107.94,97.49 109.82,95.61 109.82,83.04 108.29,81.51 108.29,77.44 v1(107.41,76.56) 107.41,75.29 106.91,74.8 106.91,73.56 107.48,72.99 107.48,57.74 107.29,57.55 107.29,53.86 105.73,52.31 105.73,48.87 107.14,47.46 107.14,44.3 106.89,44.05 106.89,41.3 108.58,39.61 108.58,36.86 114.52,30.92 114.52,25.33 109.09,19.9 107.88,19.9 v1(107.32,19.34) ; v1(88.03,76.89) 87.55,76.89 87.45,76.99 78.57,76.99 77.48,75.89 77.48,73.5 76.61,72.63 76.61,70.48 76.04,69.91 76.04,68.92 76.61,68.36 76.61,67.25 76.31,66.96 75.58,66.96 75.32,66.69 75.32,64.35 74.82,63.86 74.74,63.78 74.34,63.38 v1(74.21,63.38) ; v1(18.53,93.66) 17.9,93.02 17.78,93.02 16.34,91.58 16.34,81.65 18.04,79.95 18.04,76.49 19,75.52 19,61.08 17.54,59.62 17.54,55.1 17.19,54.75 15.18,54.75 v1(14.62,54.19)
  IN2 w0.254: v1(48.39,99.63) 47,98.23 34.87,98.23 32.25,95.61 23.97,95.61 22.02,93.66 v1(18.53,93.66) ; v1(107.32,19.34) 107.17,19.49 93.9,19.49 93.22,20.17 89.75,20.17 88.97,19.39 83.99,19.39 82.57,20.81 v1(79.58,20.81)
  BOTTOM w0.203: U24.3 78.52,11.65 75.71,14.46 75.71,17.6 78.92,20.81 v1(79.58,20.81)
  BOTTOM w0.254: v1(107.41,76.56) 106.7,77.28 100.88,77.28 98.86,75.26 95.14,75.26 94.02,76.37 94.02,77.89 93.06,78.85 89.48,78.85 89.07,78.44 89.07,77.27 88.7,76.89 v1(88.03,76.89) ; SD1.3 4.5,42.6 SC2.1 R60214.1 R188.1 4.5,46.15 5.43,47.08 6.82,47.08 7.87,48.12 9.77,48.12 12.57,50.91 14.11,50.91 15.13,51.93 15.13,53.1 14.62,53.6 v1(14.62,54.19) ; XU1.P22 73.74,63.62 73.99,63.38 v1(74.21,63.38)
  BOTTOM w0.508: v2(18.94,91.98) 18.53,92.39 v1(18.53,93.66)
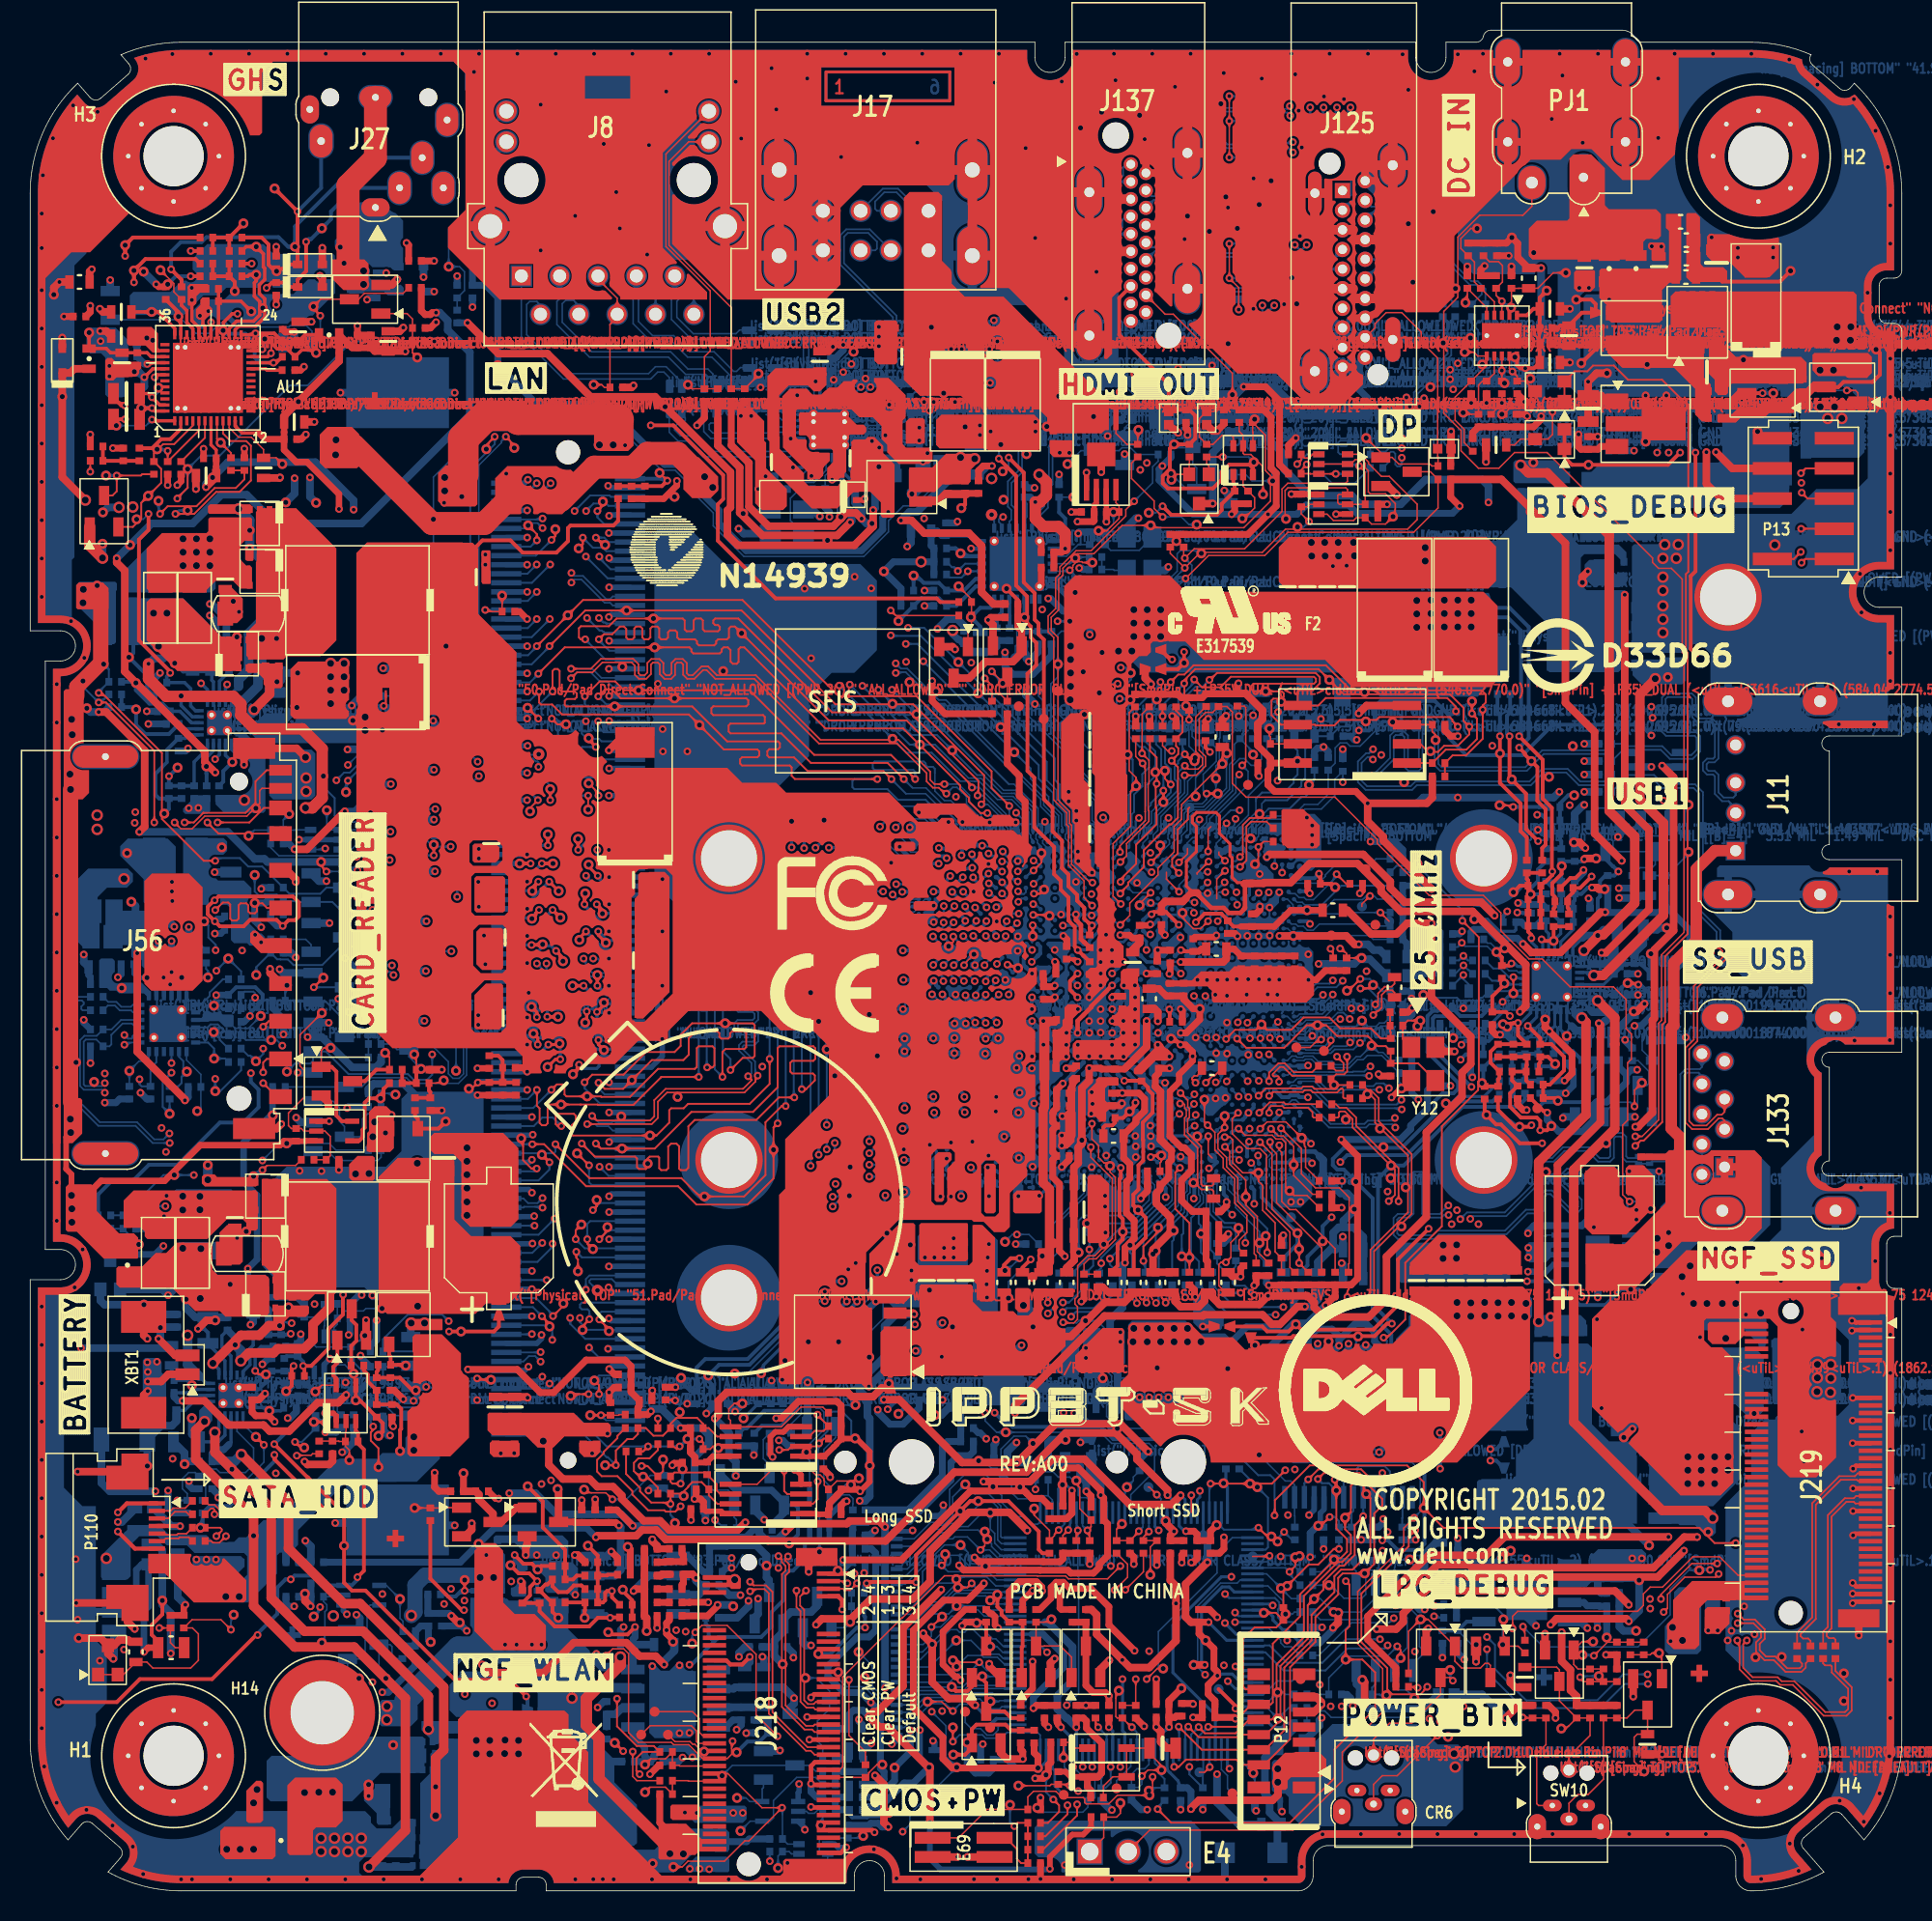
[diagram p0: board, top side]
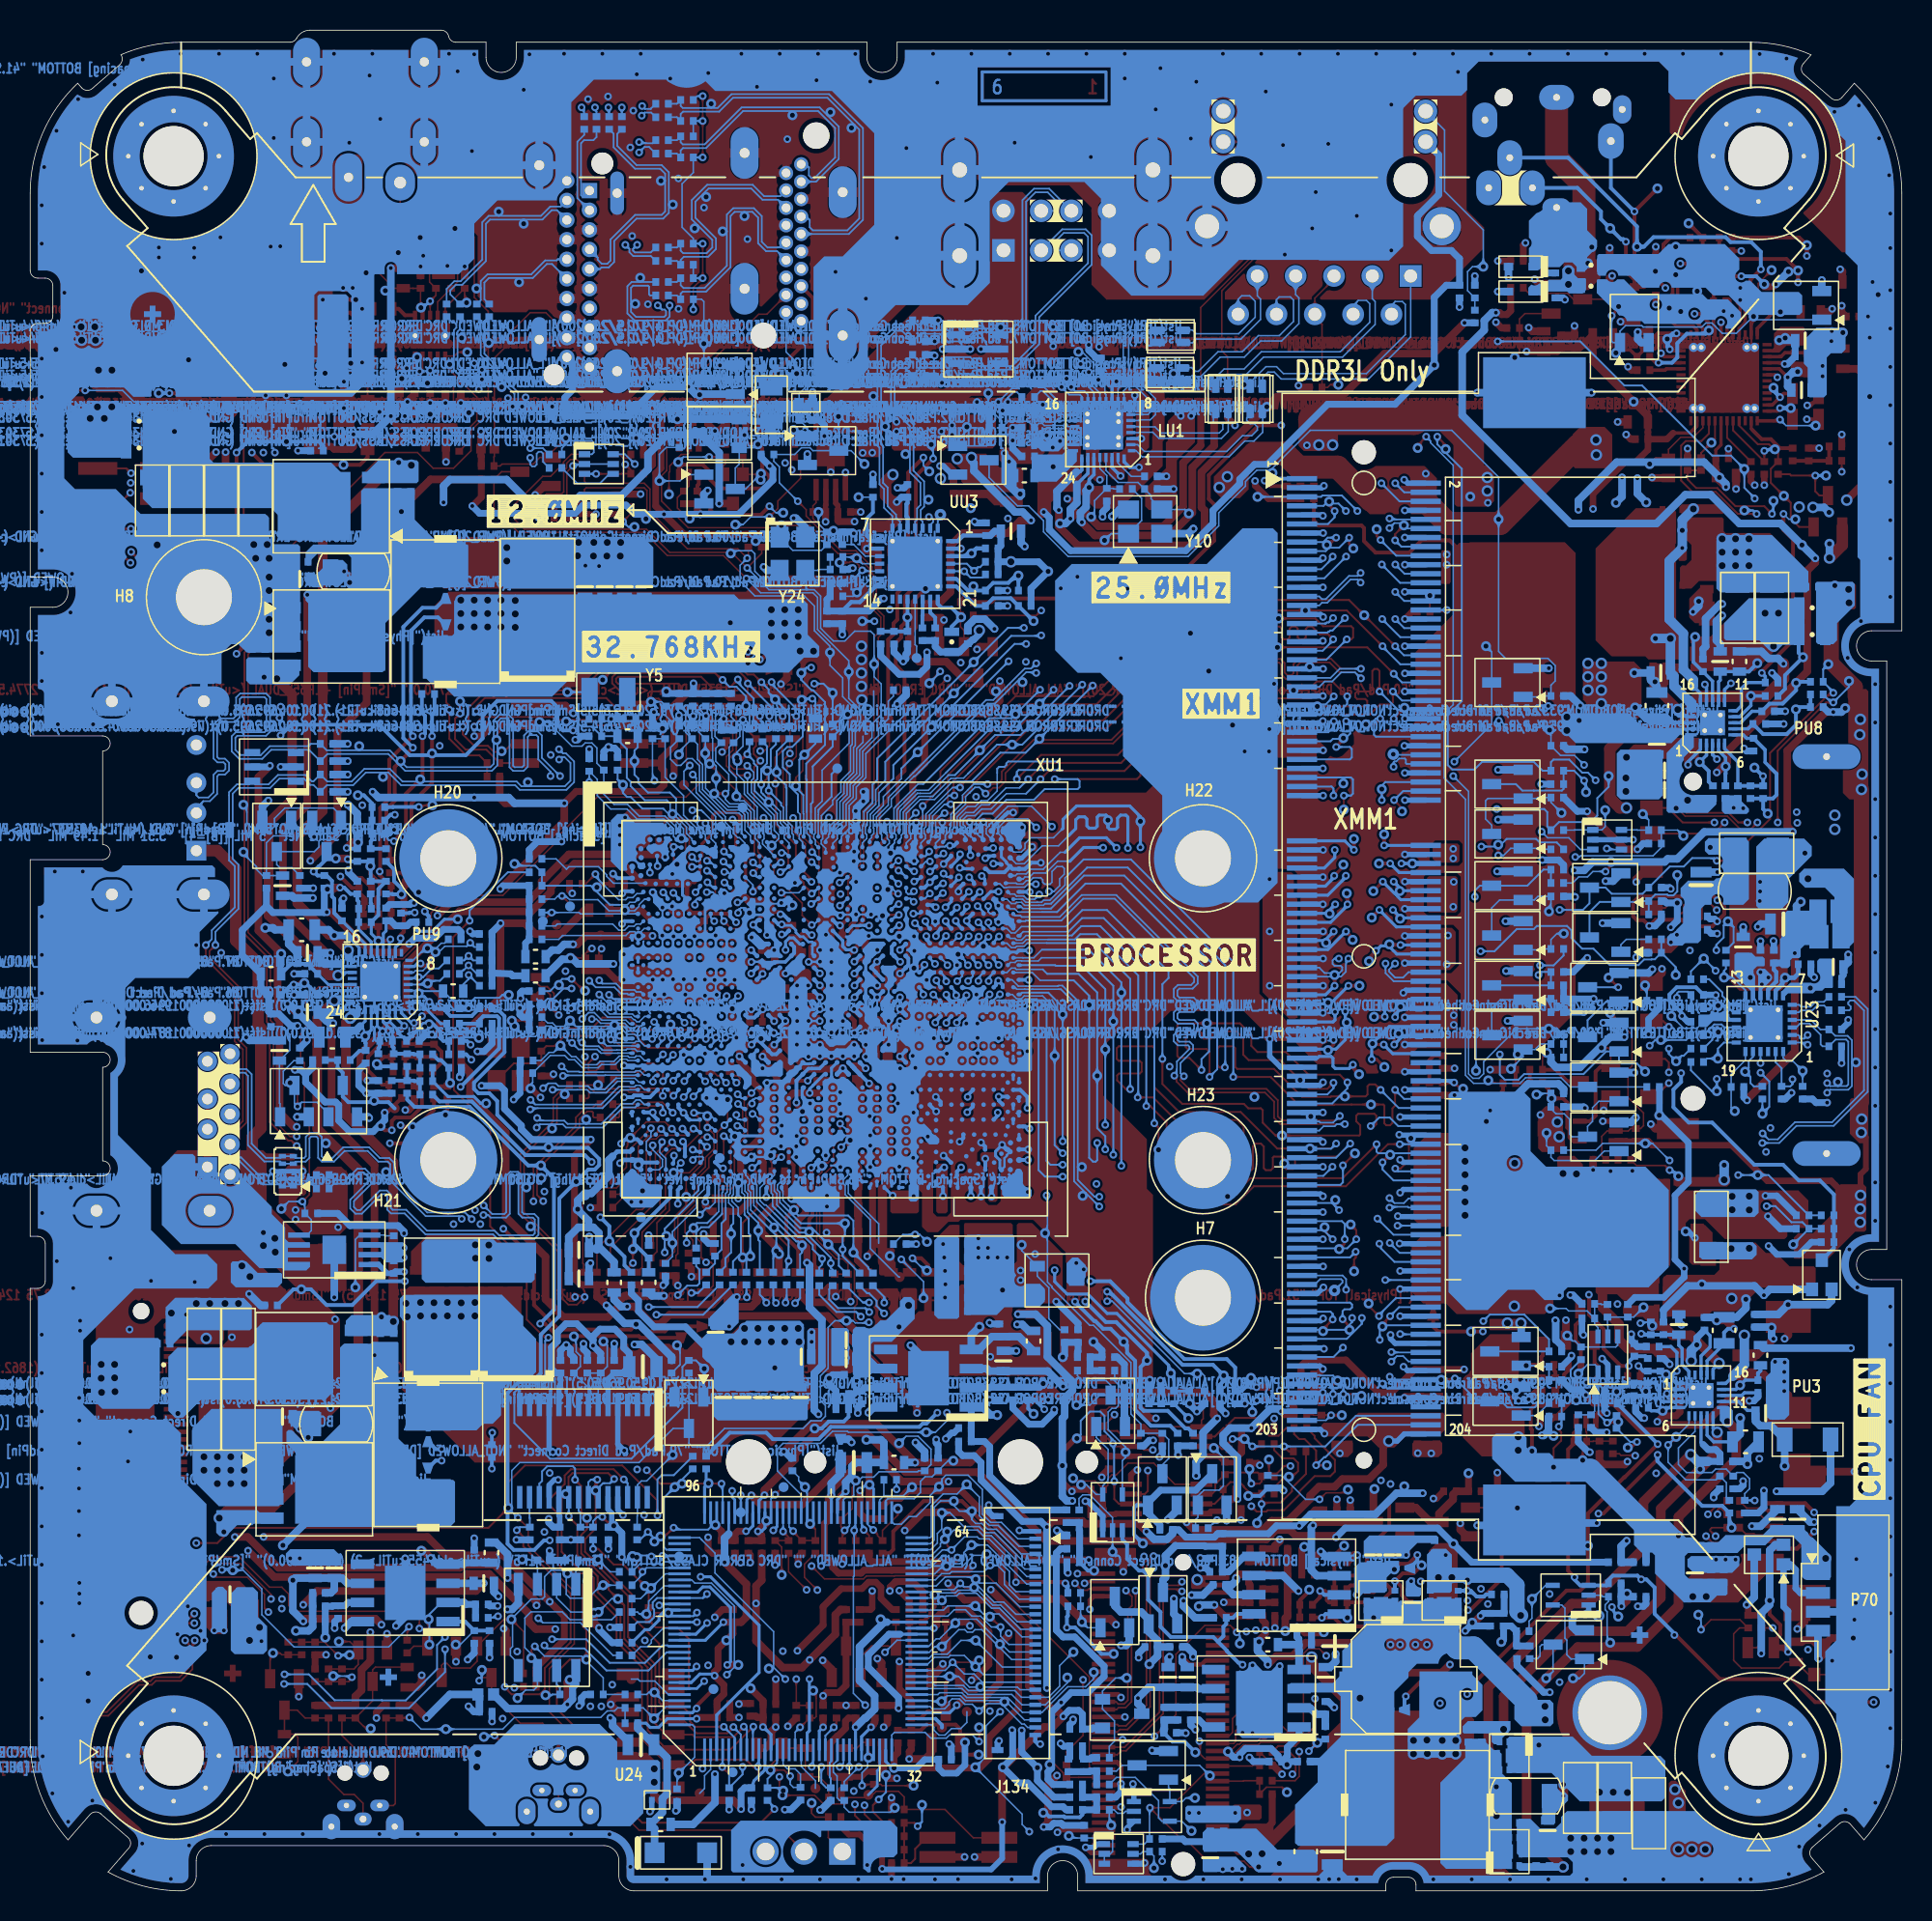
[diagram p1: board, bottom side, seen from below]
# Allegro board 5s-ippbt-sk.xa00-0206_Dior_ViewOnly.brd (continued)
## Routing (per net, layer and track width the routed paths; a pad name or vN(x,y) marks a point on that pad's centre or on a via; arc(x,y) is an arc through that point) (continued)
+RTCBAT: length 4.3
  TOP w0.508: v1(8.5,36.59) 9.6,35.48 XBT1.2
  BOTTOM w0.508: v1(8.5,36.59) 8.63,36.71 v2(8.63,37.32) 8.67,37.36 SR154.1
+RTCBAT_R: length 6.2
  BOTTOM w0.508: SR154.2 8.18,38.2 v2(7.54,38.85) 4.92,38.85 4.65,39.11 SD1.2
+V_AXG_BOOT: length 2.5
  BOTTOM w0.197: PU9.26 101.8,57.63 102.13,57.31
  BOTTOM w0.508: PR166.1 102.68,57.01 102.43,57.01 102.13,57.31
+V_AXG_BOOT1: length 4.1
  TOP w0.508: v1(106.95,58.78) 106.44,58.28 v2(106.24,58.28)
  BOTTOM w0.508: v1(106.95,58.78) 106.77,58.61 106.67,58.61 106.3,58.24 PC124.1 104.84,56.77 PR166.2
+V_AXG_COMP: length 8.9
  TOP w0.457: v1(101.66,53.69) 102.15,54.19 102.15,55.46 v1(100.65,56.96)
  TOP w0.508: v1(100.65,56.96) 100.37,57.24 v2(100.37,57.74)
  BOTTOM w0.197: v1(100.65,56.96) 101,57.31 PU9.28
  BOTTOM w0.254: v1(100.65,56.96) 100.84,56.77 PC149.1 100.84,55.93 100.93,55.84 PC152.1
  BOTTOM w0.457: PR209.1 v1(101.66,53.69)
+V_AXG_COMP1: length 1
  BOTTOM w0.254: PC152.2 PR214.1
+V_AXG_FB: length 5.9
  BOTTOM w0.197: PU9.29 100.61,57.57 100,56.97 PC149.2
  BOTTOM w0.254: PC149.2 100,55.95 99.92,55.86 PR214.2 PR213.2 98.61,55.47 98.57,55.43 PR208.1 PR211.2
+V_AXG_FB1: length 5
  BOTTOM w0.203: PC148.2 96.32,52.64 94.6,52.64 94.15,52.18 v2(93.79,52.18)
  BOTTOM w0.254: PR211.1 PC148.2
+V_AXG_FB2: length 2.5
  BOTTOM w0.254: v2(96.18,53.53) 96.27,53.62 PC146.1 96.78,55.05 96.96,55.05 PR208.2
+V_AXG_FB3: length 3.7
  BOTTOM w0.254: PC147.1 PR217.2 ; PR217.2 98.57,53.69 98.53,53.65 PC148.1 PR215.2 ; PR217.2 PR213.1
+V_AXG_HG_D: length 21.5
  TOP w0.635: v3(102.8,57.84) 103.08,57.57 103.08,51.43 99.94,48.29 v3(99.94,37.73)
  vias: v2(100.73,38.03)
+V_AXG_ISUMN: length 9.4
  TOP w0.254: v1(99.22,57.32) 99.23,57.32 100.04,56.5 PC151.2 100.79,56.11 101.62,55.28 101.62,54.37 100.68,53.43 PR210.2 PR216.2 101.03,52.54 v2(101.21,52.36)
  BOTTOM w0.203: PU9.31 99.8,57.9 v1(99.22,57.32)
+V_AXG_ISUMN1: length 2.2
  TOP w0.254: PR212.2 99.95,54.8 100.04,54.89 PC151.1 100.56,55.27 v2(101.03,54.8)
+V_AXG_ISUMN2: length 66.9
  TOP w0.254: PR212.1 99.12,53.7 PR210.1 ; PR212.1 99.12,54.68 99.15,54.72 PC143.2 PC142.2 PR205.2 ; PR212.1 PC144.2 98.18,53.7 PC150.1 98.05,52.84 98.05,51.95 98.76,51.24 99.81,51.24 100.04,51.01 v1(100.04,50.4) 100.5,50.4 v2(100.78,50.68)
  IN2 w0.254: v1(96.74,29.27) 96.87,29.14 98.9,29.14 101.68,31.92 101.68,47.29 99.67,49.3 99.67,50.08 99.81,50.22 99.87,50.22 v1(100.04,50.4) 100.04,50.86 99.67,51.23 99.26,51.23 98.96,50.94 98.96,48.41 100.56,46.81 100.56,37.47 99.32,36.23 96.23,36.23 96.22,36.23 95.93,36.23 93.54,33.84 93.54,30.52 v1(93.39,30.36)
  BOTTOM w0.254: PR206.2 93.41,30.34 v1(93.39,30.36) ; PJP10.2 97.13,29.27 v1(96.74,29.27)
+V_AXG_ISUMP: length 9.8
  TOP w0.254: v2(97.86,57.26) 97.86,57.27 98.07,57.48 98.24,57.48 98.28,57.52 v1(98.57,57.52) 98.57,56.69 PC143.1 PC142.1 PR205.1 96.75,55.61 96.75,54.87 PC144.1 97.34,53.86 97.25,53.77 PR207.1 PR203.2
  BOTTOM w0.203: PU9.32 99.4,58.17 98.75,57.52 v1(98.57,57.52)
+V_AXG_ISUMP1: length 31.9
  TOP w0.254: PR203.1 96.36,51.55 v2(96.49,51.42) 97.12,50.79 97.44,50.79 98.69,49.54 v1(100.17,49.54)
  IN2 w0.254: v1(96.74,28.51) 96.87,28.63 99.03,28.63 102.04,31.64 102.04,47.67 v1(100.17,49.54)
  BOTTOM w0.254: v1(96.74,28.51) 97.13,28.51 PJP9.2
+V_AXG_LGATE_D: length 41.4
  TOP w0.635: v3(111.47,24.7) 110.96,25.21 108.12,25.21 102.27,31.06 102.27,47.78 104.98,50.5 104.98,56.11 104.98,56.11 104.98,56.68 104.98,56.68 104.98,57.86 v3(103.85,58.99)
  vias: v2(111.17,23.78)
+V_AXG_NTC: length 5.8
  BOTTOM w0.197: PR222.1 96.79,57.46 98.19,58.86 PU9.1
  BOTTOM w0.254: v2(94.27,56.52) 94.66,56.91 96.21,56.91 96.4,57.1 PR222.1
+V_AXG_NTC1: length 34.5
  IN2 w0.254: v1(95.49,53.28) 95.49,52.37 93.69,50.58 93.69,47.54 93.82,47.41 93.82,47.4 95.27,45.95 95.28,45.95 96.54,44.69 96.54,43.04 98.73,40.84 98.73,40.82 99.02,40.53 99.04,40.53 99.17,40.4 v1(99.17,40.4)
  BOTTOM w0.254: PR222.2 PR224.2 94.24,57.71 93.99,57.96 93.07,57.96 92.93,57.82 92.93,55.82 95.48,53.28 v1(95.49,53.28) ; v1(99.17,40.4) 101.08,40.4 102.66,38.82 104.36,38.82 105.4,39.86 v2(106.04,39.86) 106.56,39.86 PRT1.1
+V_AXG_PHASE: length 29.4
  TOP w0.508: v1(103.93,57.49) 104.03,57.39 104.03,50.94 101.19,48.09 v1(101.19,35.49)
  BOTTOM w0.197: PU9.24 102.88,58.86 103.39,58.35
  BOTTOM w0.508: 103.39,58.35 103.51,58.23 PC124.2 104.38,57.64 104.32,57.64 104.17,57.49 v1(103.93,57.49) ; 105.63,24.52 v2(107.26,22.89)
+V_AXG_RTC: length 7.4
  BOTTOM w0.197: PC153.1 99.53,56.79 99.53,56.94 100.21,57.61 PU9.30
  BOTTOM w0.254: PC153.1 97.96,57.43 v2(97.58,57.43) 97.3,57.43 96.82,56.95 96.82,56.51 96.63,56.32 PR221.1 PR219.1
+V_AXG_RTC_R: length 31.7
  TOP w0.254: v1(92.65,43.87) 90.62,41.84 90.62,38.82 88.99,37.19 84.21,37.19 v2(83.85,37.55) 83.38,37.07 81.95,37.07 81.63,37.4 PJP12.1
  IN2 w0.254: v1(92.65,43.87) 92.65,50.71 93.29,51.34 93.29,54.67 93.69,55.08 v1(94.77,55.08)
  BOTTOM w0.254: PR219.2 95.12,55.43 94.77,55.09 v1(94.77,55.08)
+V_AXG_SN: length 0.8
  TOP w0.508: v2(105.58,30.04) v1(106.15,30.62)
+VAXG_ISUMP2: length 32.8
  TOP w0.254: PR207.2 97.25,51.75 98.37,50.63 v2(98.67,50.63) 99.36,50.63 v1(99.46,50.74)
  IN2 w0.254: v1(99.46,50.74) 99.32,50.59 99.32,48.56 100.92,46.96 100.92,37.32 99.47,35.87 96.08,35.87 93.9,33.69 93.9,28.46 v1(93.41,27.97)
  BOTTOM w0.254: PR206.1 v1(93.41,27.97)
+VCORE:
  vias: v1(70.17,59.98) v1(70.16,59.21) v1(70.16,57.64) v1(70.31,66.05) v1(70.92,62.34) v1(70.92,61.55) v1(70.92,60.79) v1(70.92,60) v1(70.92,58.43) v1(70.92,57.64) v1(70.92,56.87) v1(71.28,63.36) v1(71.67,62.34) v1(71.67,61.57) v1(72.42,61.56) v2(77.61,84.03) v3(68.93,82.48) v3(68.93,81.59) v3(68.93,80.7) v3(68.93,79.82) v3(68.9,78.93) v3(72.1,82.15) v3(72.99,82.16) v3(73.12,84.9) v3(73.12,84.01) v3(73.12,83.12) v3(74.01,84.9) v3(74.01,84.01) v3(74.01,83.12) v3(74.9,84.9) v3(74.9,84.01) v3(74.9,83.12) v3(91.86,85.51) v3(91.86,84.62) v3(91.86,83.73) v3(92.8,85.53) v3(92.8,84.64) v3(92.8,83.75) v3(93.69,85.53) v3(93.69,84.64) v3(93.69,83.75) v3(94.58,85.53) v3(94.58,84.64) v3(94.58,83.75) v3(95.47,85.53) v3(95.47,84.64) v3(95.47,83.75)
+VCORE&+V_AXG_VR_ON: length 56.9
  TOP w0.254: v1(109.31,95.31) 108.5,94.5 v2(103.24,94.5) 102.15,94.5 101.65,95 PD2.1 PD2.2
  IN2 w0.254: v1(109.31,95.31) 107.15,93.15 107.15,81.97 100.51,75.33 100.51,68.35 100.25,68.08 100.25,65.13 97.55,62.43 v1(97.55,58.91)
  BOTTOM w0.197: PC145.1 97.12,58.48 v1(97.55,58.91) 97.9,59.26 PU9.2
  BOTTOM w0.254: PR204.2 94.75,57.97 96.16,57.97 96.4,58.21 PC145.1
+VCORE_+19V:
  vias: v2(114.44,96.71)
+VCORE_BOOT: length 3.8
  BOTTOM w0.197: PU9.16 102.21,62.5 102.86,63.15
  BOTTOM w0.508: PR218.1 104.23,63.69 v2(103.85,63.31) 103.01,63.31 102.86,63.15
+VCORE_BOOT1: length 3.4
  BOTTOM w0.508: v2(108.42,63.81) 107.92,63.81 107.79,63.69 PR218.2 106.88,62.74 PC155.1
+VCORE_COMP: length 6.5
  TOP w0.508: v1(103.47,66.48) 103.83,66.48 103.93,66.38 v2(104.31,66.38)
  BOTTOM w0.203: PU9.14 101.4,62.89 102.24,63.73 PC165.1
  BOTTOM w0.254: PC165.1 PC167.1 102.24,65.55 102.33,65.64 PR226.1 102.77,66.06 103.19,66.48 v1(103.47,66.48)
+VCORE_COMP1: length 1
  BOTTOM w0.254: PC167.2 101.4,65.41 101.44,65.45 PR232.1
+VCORE_FB: length 10.1
  TOP w0.508: v2(103.75,68.41) 103.01,68.41 v1(102.96,68.36)
  BOTTOM w0.203: PU9.13 101,63.04 101.4,63.43 PC165.2
  BOTTOM w0.254: PC165.2 100.93,64.66 100.93,66.39 PR229.2 PR232.2 PR231.2 PR225.1 102.82,68.22 v1(102.96,68.36)
+VCORE_FB1: length 3.6
  BOTTOM w0.254: PC164.2 99.89,67.69 99.89,66.92 99.41,66.43 v2(99.41,66.04) 99.97,66.04 99.99,66.06 PR229.1
+VCORE_FB2: length 2.6
  TOP w0.508: v2(102.28,69.48) 102.66,69.48 v1(103.03,69.11)
  BOTTOM w0.254: PC161.1 PR225.2 102.99,69.06 v1(103.03,69.11)
+VCORE_FB3: length 5.2
  BOTTOM w0.254: PC164.1 PR231.1 101.44,69.55 101.35,69.64 PC163.1 PR234.2 PR235.2 101.35,72.06 101.89,72.6 v2(102.29,72.6)
+VCORE_HG_D: length 37.5
  TOP w0.635: v3(102.94,62.32) 103.98,63.36 104.22,63.36 106.3,65.44 106.3,69.87 104.61,71.56 104.61,89.85 100.5,93.96 99.26,93.96 v3(98.75,94.47)
  vias: v2(99.59,94.65)
+VCORE_ISUMN: length 3.8
  TOP w0.254: v1(100.14,63.05) 100.24,62.95 v2(100.93,62.95) PC174.2 PR243.2
  BOTTOM w0.203: PU9.11 100.21,62.98 v1(100.14,63.05)
+VCORE_ISUMN1: length 3.5
  TOP w0.254: v2(101.47,67.9) 101.47,67.4 100.84,66.77 100.84,66.04 101.02,65.86 PR245.2 101.02,65.19 100.93,65.1 PC174.1
+VCORE_ISUMN2: length 43.1
  TOP w0.254: v1(98.65,76.51) 100.21,74.95 100.21,72.37 100.82,71.76 100.82,67.57 v1(100.84,67.55) 100.84,67.31 100.4,66.86 100.34,66.86 PC170.2 PC171.2 PR238.2 PC172.2 ; PR243.1 101.95,65.06 101.86,65.15 PR245.1 101.86,65.81 102.21,66.16 PC173.1 102.69,66.46 v1(103.45,67.22) ; v1(98.01,76.51) 98.01,73.8 v2(98.16,73.65) 99.1,72.7 99.1,70.36 v1(99.9,69.56)
  IN1 w0.254: v1(99.9,69.56) 99.9,68.49 v1(100.84,67.55)
  IN2 w0.254: v1(103.45,67.22) 103.45,67.22 103.38,67.15 102.54,67.15 102.15,67.55 v1(100.84,67.55)
  BOTTOM w0.254: v1(98.65,76.51) 98.77,76.64 98.77,83.5 97.88,84.39 96.98,84.39 PJP14.2 ; v1(98.01,76.51) 97.84,76.68 97.84,77.87 98.05,78.08 PR239.2
+VCORE_ISUMP: length 7.8
  TOP w0.254: v1(99.46,63.13) 99.46,63.34 99.24,63.56 PC172.1 PR238.1 PC171.1 PC170.1 ; PC170.1 99.24,66.98 99.15,67.07 PR240.1 PR236.2 ; PC170.1 98.7,66.61 v2(98.26,66.18)
  BOTTOM w0.203: PU9.10 99.8,62.53 99.46,62.87 v1(99.46,63.13)
+VCORE_ISUMP1: length 20.1
  TOP w0.254: PR236.1 100.17,69.1 100.4,69.33 100.4,71.68 99.85,72.23 99.85,74.47 v2(99.46,74.86) 99.03,75.29 99.03,75.37 v1(98.65,75.75)
  BOTTOM w0.254: PJP13.2 97.11,85.02 98.01,85.02 99.28,83.75 99.28,76.39 v1(98.65,75.75)
+VCORE_ISUMP2: length 11.8
  TOP w0.254: PR240.2 99.15,69.81 98.75,70.21 98.75,72.04 97.38,73.42 v2(97.38,75.37) v1(97.38,76.51)
  BOTTOM w0.254: PR239.1 97.21,78.13 97.38,77.96 v1(97.38,76.51)
+VCORE_LGATE_D: length 23
  TOP w0.635: v3(107.66,80.32) 107.66,80.3 106.65,79.28 106.65,72.32 108.21,70.76 108.21,64.64 104.23,60.66 v3(103.6,60.66)
  vias: v2(108.5,80.43)
+VCORE_NTC: length 2.6
  TOP w0.254: v1(98.14,61.45) 98,61.31 PR242.2 97.5,61.86 v2(97.15,62.21)
  BOTTOM w0.203: v1(98.14,61.45) 98.35,61.45 98.54,61.26 PU9.7
+VCORE_NTC1: length 56.2
  TOP w0.254: PR242.1 97.5,59.9 96.87,59.27 PR244.1 97.77,58.24 v1(98.04,57.97) ; v1(110.33,81.97) 110.01,82.29 110.01,87.12 110.33,87.44 v1(110.33,95.31)
  IN2 w0.254: v1(110.33,81.97) 107.56,79.21 106.95,79.21 103.22,75.47 102.87,75.47 101.86,74.46 101.86,72.59 101.39,72.12 101.39,71.74 104.08,69.05 104.08,65.53 100.87,62.32 100.03,62.32 99.18,61.46 99.18,60.27 98.11,59.2 98.11,58.05 v1(98.04,57.97)
  BOTTOM w0.254: v1(110.33,95.31) 109.61,96.03 v2(107.02,96.03) 104.86,96.03 104.58,95.75 PRT2.2
+VCORE_PHASE: length 29.6
  TOP w0.508: v1(104.11,62.16) 104.37,62.16 107.26,65.05 107.26,70.32 105.64,71.93 v1(105.64,85.89)
  BOTTOM w0.197: PU9.18 103.33,61.26 103.49,61.41
  BOTTOM w0.508: 103.49,61.41 104.5,61.41 104.96,61.87 PC155.2 v1(104.11,62.16)
  vias: v2(99.41,91.4)
+VCORE_RTN: length 8.1
  BOTTOM w0.203: PC169.1 100.42,63.61 100.61,63.43 PU9.12 ; PR241.2 98.43,63.69 98.33,63.59 97.35,63.59 96.55,64.39 v2(95.67,64.39)
  BOTTOM w0.457: PC169.1 100.12,64.28 99.79,63.95 PR237.1 99.03,63.95 98.79,64.19 PR241.2
+VCORE_RTN_R: length 38
  TOP w0.254: PJP16.1 76.04,80.96 v2(76.45,81.37) v1(76.45,82.1)
  IN1 w0.254: v1(98.53,64.83) 98.64,64.83 99.07,65.26 99.07,65.8 98.78,66.1 98.78,72 95.57,75.21 93.56,75.21 86.07,82.7 77.05,82.7 v1(76.45,82.1)
  BOTTOM w0.254: v1(98.53,64.83) 98.85,64.83 98.89,64.79 PR237.2
+VCORE_SN: length 0.9
  TOP w0.508: v2(102.84,86.7) 102.84,87.07 v1(103.2,87.44)
+VNN: length 7.2
  BOTTOM w0.457: PR1.1 84.17,39.58 83.7,39.11 83.7,38.41 82.66,37.37 80.59,37.37 79.34,36.13
  vias: v1(69.41,56.07) v1(69.41,55.3) v1(70.16,55.3) v1(70.92,55.3) v1(71.69,57.64) v1(71.67,56.07) v1(71.68,55.3) v1(72.43,57.65) v1(72.43,56.86) v1(72.43,56.07) v1(72.44,55.28) v1(72.45,59.99) v1(73.19,60) v1(73.2,59.21) v1(73.2,58.43) v1(73.19,57.64) v1(73.18,56.86) v1(73.2,56.08) v2(74.67,34.65) v3(73.12,37.27) v3(73.06,36.38) v3(74.01,37.27) v3(74.01,36.38) v3(74.9,37.27) v3(74.9,36.38) v3(75.79,37.27) v3(75.79,36.38) v3(76.67,37.27) v3(76.67,36.38) v3(77.56,36.38) v3(94.53,38.99) v3(94.53,38.1) v3(95.45,38.96) v3(95.45,38.07) v3(96.36,38.99) v3(96.36,38.1) v3(97.25,38.97) v3(97.25,38.08) v3(98.14,38.99) v3(98.14,38.1) v3(99.03,38.04) v3(99.1,38.93)
+VNN_+19V:
  vias: v2(114.22,31.63)
+VTT_DDR: length 107.9
  TOP w0.457: v1(53.87,21.93) 57.73,21.93 62.3,26.5 65.87,26.5 66.01,26.36 66.01,26.36 66.36,26.01 67.02,26.01 O2R240.1
  TOP w0.508: v3(33.99,29.8) 34.36,29.44 34.36,28.23 35.3,27.29 37.07,27.29 37.57,26.78 38.62,26.78 39.2,26.2 39.2,25.97 40.65,24.52 41.73,24.52 42.33,23.92 46.88,23.92 v1(47.38,24.42)
  IN1 w0.762: v3(14.19,72.27) 14.19,71.46 11.47,68.74 11.47,56.52 10.13,55.18 10.13,53.88 9.5,53.26 9.5,52.07 13.56,48.02 13.56,46.89 14.46,45.99 14.46,42.76 13.51,41.8 13.51,37.55 14.34,36.71 15.28,36.71 16.65,35.34 16.65,34.52 18.47,32.7 19.86,32.7 21.02,31.53 26.51,31.53 28.24,29.8 v3(33.99,29.8)
  IN2 w0.508: v1(53.87,21.93) 52.61,23.19 48.61,23.19 v1(47.38,24.42)
  BOTTOM w0.356: XMM1.204 32.96,30.28 33.44,29.8 v3(33.99,29.8) ; XMM1.203 38.53,30.58 v1(38.25,30.3)
  vias: v2(14.95,71.74)
+VTT_DDR_VTTSNS_A: length 3.4
  BOTTOM w0.222: v2(13.39,74.8) 12.94,75.25 PU8.2
  BOTTOM w0.254: PR164.2 12.79,73.5 12.79,74.2 v2(13.39,74.8)
+VTT_EN_EC: length 121.7
  TOP w0.508: v1(63.16,27.12) 63.16,27.14 63.19,27.14 63.2,27.12 66.24,27.12 67.73,28.61 69.84,28.61 72.85,25.6 75.61,25.6 76.22,26.21 v1(76.22,26.21) ; v1(4.54,78.11) 5.03,78.11 7.59,75.56 7.59,70.53 v1(7.23,70.18)
  IN2 w0.508: v1(63.16,27.12) 63.16,27.93 55.99,35.1 42.27,35.1 38.07,30.9 33,30.9 31.39,32.5 31.39,51.54 30.83,52.1 30.83,58.94 28.8,60.98 28.8,62.6 23.77,67.62 v1(21.68,67.62)
  BOTTOM w0.178: v1(76.22,26.21) 76.22,26.22 76.52,25.92 U24.89
  BOTTOM w0.457: PR149.1 4.88,78.11 v1(4.54,78.11)
  BOTTOM w0.508: v1(4.54,78.11) 4.01,78.11 v2(3.75,78.37) ; v1(7.23,70.18) 13.09,70.18 14.88,68.39 15.51,68.39 15.71,68.18 20.49,68.18 21.05,67.62 v1(21.68,67.62)
+VTT_PG: length 5.9
  TOP w0.457: O2R240.2 O2C54.1 68.66,24.66 69.02,25.02 v1(69.02,26.53)
  BOTTOM w0.178: v1(69.02,26.53) 68.64,26.91 v2(68.39,26.91) 68.12,26.63 U24.68
+VTTREF_A: length 3
  BOTTOM w0.222: PU8.4 12.14,75.56 11.68,75.09 11.68,74.51
  BOTTOM w0.254: PC122.1 11.69,74.02 11.67,74.04 v2(11.67,74.51) 11.68,74.51
AD_CSN: length 4.4
  TOP w0.254: PU2.10 98.5,101.1 98.71,100.9 v1(99.05,100.9) 99.63,100.9 PC11.1 100.01,101.94 100,101.94 PR13.1
  BOTTOM w0.102: v2(99.38,100.21) 99.38,100.57 v1(99.05,100.9)
AD_CSP: length 4.4
  TOP w0.254: PU2.1 99.16,104.41 99.59,104.83 PC10.1 ; v2(100.47,106.04) 100.01,105.57 PC10.1 ; PC10.1 100.01,104.18 100,104.17 PR12.1
ADATPTER_ID: length 172.1
  TOP w0.102: PJ1.3 99.49,111.63 98.89,111.04 96.03,111.04 94.58,109.58 94.58,105.6 93.65,104.67 93.65,97.91 94.8,96.77 94.8,95.42 95.95,94.27 97.3,94.27 98.34,95.31 100.5,95.31 107.49,88.32 107.49,88.03 107.88,87.64 108.73,87.64 109.45,86.92 109.45,82.06 109.57,81.95 109.57,63.51 108.08,62.02 108.08,57.69 107.89,57.49 107.89,51.08 106.8,50 v1(106.34,50) ; v1(108.22,18.47) 108.48,18.73 108.48,19.64 109.62,20.79 111.66,20.79 v1(111.87,21) ; v2(65.47,6.97) 67.56,6.97 67.65,7.06 O2R1.2 68.8,7.06 v1(68.89,6.97)
  IN2 w0.102: v1(111.87,21) 115.28,24.41 115.28,29.7 106.65,38.34 106.65,41 105.71,41.94 105.71,44.89 105.35,45.25 105.35,49.67 105.68,50 v1(106.34,50) ; v1(108.22,18.47) 102.68,12.94 96.88,12.94 95.54,11.6 93.91,11.6 93.34,12.18 91.34,12.18 90.54,12.98 85.28,12.98 82.58,10.27 79.42,7.11 72.8,7.11 72.61,7.3 69.22,7.3 v1(68.89,6.97)
  BOTTOM w0.102: U24.28 68.52,8.2 68.89,7.83 v1(68.89,6.97)
AZ_BITCLK: length 131.3
  TOP w0.127: v1(9.11,95.42) AC45.1 11.18,96.78 AU1.5
  IN1 w0.127: v1(9.11,95.42) 8.63,95.42 8.52,95.31 8.52,94.78 8.9,94.4 10,94.4 10.38,94.01 10.38,92.52 10.63,92.26 10.63,90.93 9.49,89.79 9.49,87.12 11.02,85.59 11.02,84.79 16.79,79.01 16.79,71.37 14.47,69.05 14.47,59.93 14.04,59.5 14.04,54.87 12.31,53.14 12.31,52.23 16.35,48.19 16.35,39.54 16.89,39 17.98,39 19.63,37.35 21.79,37.35 24,35.14 26.64,35.14 27.68,34.1 27.68,34.01 27.68,33.37 29.4,31.64 36.98,31.64 37.54,31.09 39.45,31.09 40.81,32.44 41.75,32.44 42.13,32.83 42.13,33.59 43.07,34.53 48.28,34.53 50.98,37.23 55.82,37.23 57.99,39.4 62.69,39.4 64.15,37.94 66.27,37.94 67.3,38.97 v1(67.42,38.97)
  BOTTOM w0.127: v1(67.42,38.97) 67.42,39.35 SR87.1 ; v2(8.41,95.53) 9.01,95.53 v1(9.11,95.42)
AZ_BITCLK_S: length 10.1
  BOTTOM w0.102: XU1.BJ21 74.21,46.46 74.13,46.37 74.13,45.77 73.75,45.4
  BOTTOM w0.127: 73.75,45.4 73.11,44.75 69.8,44.75 69.46,44.41 v2(69.46,42.3) 68.47,41.31 68.47,41.25 SR87.2
AZ_RST#: length 152.5
  TOP w0.127: v1(9.75,92.26) 9.75,92.29 10.43,92.98 10.43,94.28 AC44.1 11.58,96.29 AU1.6 ; AR10.1 v1(26.78,102.68)
  IN1 w0.127: v1(9.75,92.26) 10.13,91.88 10.13,91.14 8.98,90 8.98,86.91 10.51,85.38 10.51,84.58 16.29,78.8 16.29,71.64 13.53,68.88 13.53,56.02 11.57,54.06 11.57,52.25 14.89,48.93 14.89,47.49 15.84,46.54 15.84,39.3 16.65,38.49 17.77,38.49 19.52,36.74 20.59,36.74 20.92,36.41 22.02,36.41 23.83,34.6 26.36,34.6 27.17,33.79 27.17,33.16 29.19,31.14 36.77,31.14 38.07,29.84 38.92,29.84 39.75,30.67 42.49,30.67 42.92,31.1 43.28,31.1 46.15,33.97 48.66,33.97 51.41,36.72 56.03,36.72 58.21,38.9 62.48,38.9 63.94,37.44 66.59,37.44 67.42,38.26 v1(67.42,38.26)
  BOTTOM w0.127: v1(26.78,102.68) 21.3,102.68 18.38,99.75 17.21,99.75 12.56,95.11 11.32,95.11 v2(10.43,94.22) 10.43,92.98 9.75,92.29 v1(9.75,92.26) ; SR86.1 68.56,39.61 68.43,39.61 67.92,39.1 67.92,38.76 v1(67.42,38.26)
AZ_RST#_S: length 11.2
  BOTTOM w0.102: 74.1,45.4 74.33,45.63 74.33,46.29 74.49,46.45 74.49,46.77 74.33,46.94 74.22,46.94 73.73,47.43 XU1.BG22
  BOTTOM w0.127: SR86.2 70.17,42.06 v1(70.17,42.5) 70.17,43.32 70.02,43.47 v2(70.02,44.23) 72.93,44.23 74.1,45.4
AZ_SDATA_IN0: length 135.5
  TOP w0.127: AR1.1 AC43.1 14.19,93.53 13.62,92.96 12.22,92.96 11.02,91.75 9.11,91.75 v1(8.6,91.25)
  IN1 w0.127: v1(68.97,38.05) 68.97,37.51 68.13,36.67 59.28,36.67 59.11,36.85 57.91,36.85 57.03,35.96 52.77,35.96 51.07,34.27 51.07,33.68 47.3,29.9 45.79,29.9 44.77,28.89 37.94,28.89 36.46,30.37 28.47,30.37 25.02,33.83 22.14,33.83 21.14,34.83 19.22,34.83 18.25,35.8 17.01,35.8 15.03,37.78 15.03,46.23 14.13,47.13 14.13,48.57 10.7,52 10.7,54.71 12.77,56.78 12.77,69.2 15.52,71.95 15.52,78.49 9.75,84.27 9.75,85.02 8.22,86.55 8.22,90.86 v1(8.6,91.25)
  BOTTOM w0.127: v1(8.6,91.25) 8.5,91.35 v2(8.5,92.11) ; v1(68.97,38.05) 69.28,38.36 70.58,38.36 71.72,39.5 SR88.1
AZ_SDATA_IN0_S: length 8.7
  BOTTOM w0.102: 74.69,44.89 75.25,45.45 75.35,45.45 75.65,45.75 75.65,46.59 75.38,46.86 75.38,47.16 XU1.BG19
  BOTTOM w0.127: 74.69,44.89 73.12,43.32 72.68,43.32 72.15,42.79 72.15,42.52 v1(71.53,41.89) 71.53,41.5 71.72,41.31 SR88.2
AZ_SDATA_OUT: length 136.2
  TOP w0.127: R5.1 7.42,93.87 7.33,93.79 v1(5.73,93.79) 5.73,92.74 5.45,92.46 D1.3
  IN1 w0.127: v1(5.73,93.79) 7.66,93.79 9.11,92.34 9.11,91.14 8.48,90.51 8.48,86.65 10,85.13 10,84.37 15.78,78.59 15.78,71.85 13.02,69.09 13.02,56.57 10.99,54.54 10.99,52.07 14.38,48.68 14.38,47.24 15.28,46.33 15.28,37.9 17.06,36.13 20.2,36.13 22.24,34.09 26.15,34.09 26.66,33.57 26.66,32.8 28.83,30.63 36.56,30.63 38.05,29.14 40.02,29.14 40.76,29.88 43.53,29.88 44.19,30.54 47.57,30.54 50.82,33.79 50.82,34.37 52.66,36.21 56.87,36.21 57.76,37.1 59.21,37.1 59.39,36.93 67.06,36.93 68.11,37.98 68.11,38.05 v1(68.41,38.35)
  BOTTOM w0.127: SR89.1 71.06,39.87 71.06,39.2 70.48,38.62 68.67,38.62 v1(68.41,38.35) ; v2(5.02,93.79) v1(5.73,93.79)
AZ_SDATA_OUT_S: length 8.9
  BOTTOM w0.102: XU1.BG20 74.7,47.43 74.99,47.14 74.99,46.88 74.9,46.79 74.9,46.24 74.81,46.15 74.81,45.47
  BOTTOM w0.127: SR89.2 70.83,41.16 70.96,41.28 v1(70.96,41.59) 70.96,41.96 72.62,43.62 73.05,43.62 74.81,45.38 74.81,45.47
AZ_SYNC: length 137.1
  TOP w0.127: AU1.9 12.78,96.57 13.28,96.07 14.32,96.07 14.62,95.77 14.62,93.46 13.87,92.71 12.33,92.71 10.87,91.25 v1(9.62,91.25)
  IN1 w0.127: v1(9.62,91.25) 8.73,90.36 8.73,86.8 10.25,85.28 10.25,84.48 16.03,78.7 16.03,71.74 13.28,68.99 13.28,56.19 11.3,54.21 11.3,52.15 14.64,48.81 14.64,47.39 15.54,46.49 15.54,38.01 17.16,36.38 20.31,36.38 22.35,34.34 26.26,34.34 26.92,33.68 26.92,32.91 28.94,30.88 36.67,30.88 38.15,29.4 39.91,29.4 40.65,30.14 43.4,30.14 44.06,30.79 47.47,30.79 50.56,33.89 50.56,34.48 52.55,36.47 56.14,36.47 58.31,38.64 60.12,38.64 60.68,38.08 62.94,38.08 63.84,37.18 66.96,37.18 67.85,38.08 67.85,38.42 v1(68.42,38.99)
  BOTTOM w0.127: v1(68.42,38.99) 68.83,38.99 SR85.1 ; v2(10.43,91.47) 9.85,91.47 v1(9.62,91.25)
AZ_SYNC_S: length 8.5
  BOTTOM w0.102: XU1.BH20 74.7,46.37 74.53,46.2 74.53,45.46 73.96,44.89
  BOTTOM w0.127: 73.96,44.89 73,43.93 72.21,43.93 v2(71.13,42.84) 70.43,42.14 70.43,41.42 SR85.2
BOARD_ID_0: length 10.2
  BOTTOM w0.102: SR56.1 77.56,77.8 76.98,77.22 76.98,76.5 SR61.1 77.69,75.79 77.69,74.25 77.21,73.77 v2(77.21,72.53) 77.21,72.45 76.99,72.23 76.71,72.23 76.04,71.57 76.04,70.85 75.67,70.48 XU1.B18
BOARD_ID_1: length 12.4
  BOTTOM w0.102: XU1.B16 76.85,70.06 76.85,71.23 77.04,71.42 77.9,71.42 79.46,72.98 79.46,74.64 79.79,74.97 79.79,75.98 SR60.1 ; SR57.1 80.57,78.08 80.57,78.08 80.57,76.77 SR60.1 ; SR60.1 81.02,75.49 v2(81.02,75.29)
BOARD_ID_2: length 12.5
  TOP w0.102: v2(78.68,72.71) v1(77.94,72.71)
  BOTTOM w0.102: SR58.1 78.4,78.04 78.61,77.83 78.61,77.41 78.63,77.38 78.63,76.5 SR59.1 78.58,75.71 78.58,74.86 77.72,73.99 77.72,72.93 v1(77.94,72.71) 77.94,72.32 77.65,72.03 76.79,72.03 76.24,71.48 76.24,70.76 75.88,70.4 75.88,70.08 75.89,70.07 75.96,69.99 75.96,69.73 75.68,69.45 75.68,69.29 75.67,69.28 XU1.C18
BT_ON/OFF#: length 49.4
  IN1 w0.102: v1(77.84,14.32) 77.01,14.32 74.84,12.15 70.61,12.15 69.97,11.52 67.53,11.52 66.93,10.92 61.57,10.92 61.51,10.97 60.63,10.97 v1(59.73,11.87) ; v1(49,1.96) 49.31,2.27 52.87,2.27 53.9,3.3 57.18,3.3 v1(57.8,3.92)
  BOTTOM w0.102: v1(57.8,3.92) 58.28,4.4 58.28,5.08 v2(61.38,8.19) 60.67,8.9 60.67,10.93 v1(59.73,11.87) ; WR64.1 v1(49,1.96) ; v1(77.84,14.32) 77.35,14.82 77.35,18.88 78.86,20.39 79.97,20.39 80.18,20.6 U24.104
BT_ON/OFF#_G: length 5
  BOTTOM w0.102: v2(55.19,3.64) 55.05,3.5 WR62.2 52.42,3.5 52.29,3.37 52.29,2.6 52.44,2.45 WQ6.2 WQ6.3
BT_ON/OFF#_Q: length 17.6
  TOP w0.102: v2(42.61,1.58) 43.2,1.58 43.58,1.96 45.99,1.96 47.34,3.31 47.62,3.31 v1(49.81,5.51) 48.48,5.51 46.22,7.77 J218.54
  BOTTOM w0.102: v1(49.81,5.51) 49.84,5.48 WR59.2 50.18,3.1 WQ6.6
BT_ON/OFF#_R: length 2.4
  BOTTOM w0.102: v2(49.55,1.51) 49.55,2.31 WR64.2 50.28,2.6 50.44,2.45 WQ6.5
BT_USBN2: length 88.8
  TOP w0.114: v1(54.78,20.38) 54.32,19.92 53.94,19.92 53.84,20.02 J218.5
  IN1 w0.114: v1(79.13,66.83) 78.44,66.14 78.44,65.38 80.07,63.75 83.53,63.75 83.94,63.34 86.71,63.34 87.33,62.72 87.33,62.47 87.75,62.05 88.48,62.05 89.65,60.88 89.65,54.42 91.29,52.78 91.29,51.96 91.3,51.96 91.3,51.61 91.29,51.6 91.29,50.78 90.84,50.33 90.84,47.1 91.17,46.77 91.17,41.64 91.51,41.3 91.51,35.04 83.96,27.5 83.76,27.5 78.71,22.45 65.57,22.45 64.52,23.5 62.88,23.5 61.61,22.23 59.89,22.23 59.33,21.68 58.62,21.68 56.9,19.95 55.91,19.95 55.21,19.95 v1(54.78,20.38)
  BOTTOM w0.114: XU1.J12 78.77,66.47 v1(79.13,66.83)
BT_USBP2: length 88.8
  TOP w0.114: v1(54.15,20.38) 54,20.52 J218.3
  IN1 w0.114: v1(54.15,20.38) 54.63,19.9 54.92,19.9 55.11,19.71 55.14,19.71 55.81,19.71 55.81,19.71 57,19.71 58.72,21.43 59.43,21.43 59.99,21.99 61.71,21.99 62.98,23.26 64.42,23.26 65.47,22.21 78.81,22.21 83.86,27.26 84.06,27.26 91.75,34.94 91.75,41.4 91.41,41.74 91.41,46.87 91.08,47.2 91.08,50.22 91.53,50.68 91.53,51.5 91.54,51.51 91.54,52.06 91.53,52.06 91.53,52.88 89.89,54.52 89.89,60.98 88.58,62.29 87.85,62.29 87.57,62.57 87.57,62.82 86.81,63.59 84.04,63.59 83.63,63.99 80.17,63.99 78.68,65.48 78.68,66.04 78.82,66.18 v1(79.18,66.18)
  BOTTOM w0.114: v1(79.18,66.18) 78.79,66.18 78.62,66.01 XU1.K12
CA_DET: length 14.9
  TOP w0.102: v1(88.04,94.43) 88.45,94.02 MR25.2 MQ41.5 86.73,91.88 86.63,91.98 86.63,92.47 86.7,92.53 MQ41.6 87.28,92.86 87.16,92.98 83.32,92.98 83.14,92.8 83.14,90.98 v2(83.2,90.92)
  BOTTOM w0.102: MQ42.5 MQ42.2 87.92,94.55 v1(88.04,94.43)
CAD_PIN13: length 19
  TOP w0.102: v1(84.73,90.74) 84.21,91.26 MR26.2 84.6,91.72 84.76,91.88 MQ41.2
  IN2 w0.102: v1(84.73,90.74) 85.89,91.9 85.89,96.98 87.62,98.71 87.62,104.2 J125.13
  BOTTOM w0.102: v2(83.96,90.38) 84.37,90.38 v1(84.73,90.74)
CARD_3V3:
  vias: v1(8.84,60.52) v1(9.28,60.06) v1(9.39,66.86) v1(9.39,66.23) v1(9.42,65.59) v1(9.36,60.88) v2(6.42,68.77)
CARD_3V3_F:
  vias: v1(14.9,63.36) v1(15.3,62.86) v2(12.69,69.15)
CBN: length 7
  TOP w0.229: AU1.21 v1(16.12,101.26) 16.31,101.26 AC51.2
  BOTTOM w0.254: v1(16.12,101.26) 15.22,101.26 14.88,101.61 14.88,102.55 14.24,103.18 13,103.18 v2(12.78,103.4)
CBP: length 5.2
  TOP w0.229: AU1.24 14.99,102.46 15.31,102.78 15.77,102.78 16.36,102.18 17.02,102.18 AC51.1 18,102.12 18.74,102.12 v2(18.94,101.91)
CK_100M_CR: length 152.2
  IN1 w0.114: v1(81.41,55.4) 81.8,55.01 82.16,55.01 84.14,53.02 85.64,53.02 87.39,51.27 87.39,41.21 86.4,40.22 86.4,38.39 84.4,36.39 84.4,35.98 79.82,31.4 74.87,31.4 74.16,31.4 72.57,29.82 70.99,29.82 70.45,29.28 61.96,29.28 59.23,26.55 56.34,26.55 55.18,25.38 48.4,25.38 48.1,25.09 46.79,25.09 45.67,23.97 40.67,23.97 39.93,23.24 37.94,23.24 37.62,22.92 22.31,22.92 21.1,21.71 15.08,21.71 14.52,21.15 11.04,21.15 4.96,27.24 4.96,36.95 7.32,39.31 7.32,46.54 8.56,47.79 8.56,49.94 6.74,51.77 6.74,52.38 5.81,53.31 5.16,53.31 v1(4.95,53.53)
  BOTTOM w0.114: 4.23,53.33 3.65,53.33 3.55,53.43 3.55,56.27 3.69,56.42 4.38,56.42 C250.1 5.25,55.97 5.38,56.09 5.38,56.73 6.12,57.47 6.74,57.47 7,57.21 U23.3 ; 4.23,53.33 v2(4.23,53.6) ; 4.23,53.33 4.75,53.33 v1(4.95,53.53) ; v1(81.41,55.4) 81.41,55.37 XU1.AM6
CK_100M_CR#: length 152.2
  IN1 w0.114: v1(4.95,52.89) 5.12,53.07 5.71,53.07 6.49,52.28 6.49,51.67 8.32,49.84 8.32,47.89 7.08,46.64 7.08,39.41 4.72,37.05 4.72,27.14 10.94,20.91 14.62,20.91 15.18,21.47 21.2,21.47 22.41,22.68 37.72,22.68 38.04,23 40.03,23 40.77,23.73 45.77,23.73 46.89,24.84 48.2,24.84 48.5,25.14 55.28,25.14 56.44,26.31 59.33,26.31 62.06,29.04 70.55,29.04 71.09,29.57 72.67,29.57 73.89,30.8 74.26,31.16 79.92,31.16 84.64,35.88 84.64,36.29 86.64,38.29 86.64,40.12 87.63,41.11 87.63,51.37 85.74,53.26 84.24,53.26 v1(82.07,55.43)
  BOTTOM w0.114: v1(82.07,55.43) 82.44,55.07 XU1.AM4 ; v2(3.04,54.9) 3.31,54.9 ; 3.31,54.9 3.31,53.33 3.55,53.09 4.75,53.09 v1(4.95,52.89) ; 3.31,54.9 3.31,56.37 3.59,56.66 4.41,56.66 C251.1 5.39,57.08 6.02,57.71 U23.4
CLK_PCIE_LAN: length 69.4
  IN2 w0.114: v1(55.03,99.65) 55.03,98.78 56.41,97.41 61.65,97.41 62.5,98.26 70.88,98.26 71.45,97.69 73.57,97.69 77.45,93.81 77.45,90.62 79.04,89.04 79.04,86.41 81.96,83.48 81.96,74.88 83.37,73.47 83.37,57.69 82.8,57.12 82.38,57.12 82.29,57.03 82.03,57.03 81.5,56.5 v1(81.5,56.5)
  BOTTOM w0.114: XU1.AK6 81.5,56.25 v1(81.5,56.5) ; v1(55.03,99.65) 54.77,99.39 54.16,99.39 53.93,99.15 LU1.15
CLK_PCIE_LAN#: length 69.4
  IN2 w0.114: v1(55.67,99.65) 55.28,99.26 55.28,98.88 56.51,97.65 61.55,97.65 62.4,98.5 70.98,98.5 71.55,97.93 73.67,97.93 77.69,93.91 77.69,90.72 79.28,89.14 79.28,86.51 82.2,83.59 82.2,74.98 83.61,73.57 83.61,57.59 82.9,56.88 82.49,56.88 v1(82.14,56.52)
  BOTTOM w0.114: LU1.16 54.33,99.02 54.45,99.15 55.16,99.15 v1(55.67,99.65) ; v1(82.14,56.52) 82.14,56.29 XU1.AK4
CLK_PCIE_WLAN: length 91.9
  TOP w0.114: v1(47.69,19.85) 47.85,20 48.65,20 48.94,19.71 48.94,11.74 51.4,9.28 51.71,9.28 51.97,9.02 J218.49
  IN1 w0.114: v1(47.69,19.85) 49.17,19.85 51.68,22.35 57.17,22.35 57.98,23.16 58.72,23.16 59.27,23.72 60.99,23.72 62.59,25.32 65.13,25.32 66.08,24.37 73.38,24.37 76.42,24.37 76.72,24.37 77.8,24.37 89.16,35.73 89.16,37.06 89.81,37.7 89.81,40.57 89.45,40.93 89.45,52.4 87.01,54.84 86.06,54.84 83.75,57.15 82.45,57.15 82.28,57.32 80.85,57.32 v1(80.65,57.53)
  BOTTOM w0.114: v1(80.65,57.53) 81.05,57.93 XU1.AF7
CLK_PCIE_WLAN#: length 91.9
  TOP w0.114: v1(47.69,20.48) 47.93,20.24 48.75,20.24 49.18,19.81 49.18,11.84 51.5,9.52 J218.47
  IN1 w0.114: v1(80.01,57.55) 80.47,57.08 82.18,57.08 82.35,56.91 83.65,56.91 85.96,54.59 86.91,54.59 89.21,52.3 89.21,40.83 89.57,40.47 89.57,37.8 88.92,37.16 88.92,35.83 77.7,24.61 76.62,24.61 76.62,24.61 76.52,24.61 76.52,24.61 73.48,24.61 66.18,24.61 65.23,25.56 62.49,25.56 60.89,23.96 59.17,23.96 58.62,23.4 57.88,23.4 57.07,22.6 51.57,22.6 49.07,20.09 48.09,20.09 v1(47.69,20.48)
  BOTTOM w0.114: v1(80.01,57.55) 80.01,57.62 XU1.AF9
CLK_REQ1_WLAN#: length 81.8
  TOP w0.102: J218.53 53.62,8.02 53.83,8.22 53.83,14.16 57.76,18.09 57.79,18.09 60.57,20.88 66.73,20.88 66.75,20.86 68.6,20.86 68.79,20.67 71.38,20.67 v1(72.23,21.52) ; SR654.2 v1(84.07,41.6) v2(84.07,42.53) 84.07,43.39 82.27,45.19 82.27,48.82 v1(81.48,49.62)
  IN2 w0.102: v1(84.07,41.6) 90.39,35.28 90.39,21.24 88.82,19.67 84.16,19.67 82.61,21.23 78.87,21.23 78.81,21.17 72.59,21.17 v1(72.23,21.52)
  BOTTOM w0.102: v1(81.48,49.62) 81.01,49.15 XU1.BD7
CLKRUN#_R: length 7.7
  BOTTOM w0.102: 76.04,44.89 76.26,45.12 76.26,46.28 76.44,46.45 76.44,46.77 76.35,46.86 76.35,47.14 76.45,47.23 76.45,47.28 76.6,47.42 76.6,47.65 XU1.BG16
  BOTTOM w0.127: SR108.1 74.77,42.2 v2(74.57,42.4) 74.57,43.42 76.04,44.89
CLR_CMOS: length 8.5
  TOP w0.127: v1(65.2,4.29) 65.42,4.5 SR672.1 SR673.1 SR674.1 C150.1 65.65,1.84 65.37,2.12 65.37,2.78 64.64,3.51 E69.2
  BOTTOM w0.127: v1(65.2,4.29) 64.91,4.57 v2(64.91,5.7)
CLRCMOS_GPIO: length 102.9
  TOP w0.127: SR672.2 67.43,4.5 68.17,5.24 68.17,5.67 v1(67.78,6.05) ; SR182.1 87.19,66.73 v1(86.55,67.37)
  IN1 w0.127: v1(67.78,6.05) 67.78,5.98 68.52,5.24 70.12,5.24 71.06,6.18 83.09,6.18 83.88,6.96 83.88,12.07 84.76,12.96 85.73,12.96 86.2,13.44 86.2,15.47 85.13,16.53 85.13,20.25 87.24,22.36 87.24,25.59 88.31,26.65 90.93,26.65 91.43,27.16 91.43,33.6 92.25,34.42 92.25,39.9 93.69,41.34 94.71,41.34 96.42,43.06 96.42,45.01 98.71,47.3 98.71,49.44 97.52,50.63 97.52,52.54 95.26,54.81 95.26,56.25 94.95,56.55 94.83,56.55 93.49,57.89 93.49,58.84 92.12,60.22 92.12,61.91 89.88,64.14 89.88,65.42 87.93,67.37 v1(86.55,67.37)
  BOTTOM w0.102: 85.95,66.61 85.02,65.68 84.55,65.68 84.41,65.82 84.07,65.82 83.81,66.08 83.49,66.08 XU1.J3
  BOTTOM w0.127: v1(67.78,6.05) 67.3,6.54 v2(67.3,7.68) ; 85.95,66.61 86.55,67.22 v1(86.55,67.37)
CORE_V1P0_S3: length 28.2
  TOP w0.254: SL12.1 65.74,41.3 v1(66.29,41.84) ; v1(69.39,59.21) 68.89,59.71 68.89,60.28 v1(69.4,60.79)
  IN1 w0.254: v1(69.39,59.21) 68.09,57.91 68.09,55.03 66.69,53.63 65.59,53.63 64.98,53.02 64.98,51.02 65.61,50.38 65.61,49.7 66.91,48.41 66.91,47.72 66.34,47.15 66.34,41.89 v1(66.29,41.84)
  BOTTOM w0.102: v1(66.29,41.84) 64.81,40.37 v2(64.81,39.28)
  BOTTOM w0.254: XU1.AC32 69.39,59.24 v1(69.39,59.21)
  BOTTOM w0.305: XU1.Y32 69.4,60.8 v1(69.4,60.79)
CPU_BKLTEN: length 11.3
  BOTTOM w0.102: ST19.1 68.12,78 69.33,76.78 69.33,75.89 69.45,75.77 69.45,74.11 70.08,73.48 70.08,72.72 70.55,72.25 70.55,71.03 71.02,70.57 71.02,70.08 71.02,70.08 71.11,69.99 71.11,69.83 71.3,69.64 XU1.C27
CPU_PWM_18: length 5
  BOTTOM w0.102: 71.78,71.48 71.78,71.32 71.79,71.31 XU1.B26
  BOTTOM w0.127: 71.78,71.48 71.78,71.63 70.91,72.5 70.91,74 ST3.1
CPU_VDDEN: length 7.5
  BOTTOM w0.102: ST18.1 68.83,76.11 69.25,75.69 69.25,74.03 69.88,73.4 69.88,72.63 70.35,72.16 70.35,70.94 70.81,70.48 70.81,69.86 XU1.B28
CPU_VRON: length 70
  IN2 w0.254: v1(74.77,23.89) 74.85,23.89 75.29,24.33 79.97,24.33 80.79,23.5 82.57,23.5 83.33,22.74 84.87,22.74 85.56,22.05 85.56,21.32 86.93,19.95 87.4,19.95 88.69,21.24 88.69,22.34 89.53,23.17 89.53,23.17 v1(89.58,23.22)
  BOTTOM w0.178: v1(74.77,23.89) 74.52,24.14 U24.84
  BOTTOM w0.254: v1(89.58,23.22) 89.96,23.22 90.59,22.59 91.97,22.59 92.37,23 92.37,32.99 91.61,33.75 90.72,33.75 90.18,34.3 90.18,36.85 88.94,38.09 88.94,45.88 v2(87.83,47) 87.03,47.8 86.59,47.8 86.3,48.09 86.3,48.5 87.04,49.23 90.86,49.23 93.06,51.43 93.06,52.33 93.58,52.85 94.3,52.85 94.59,53.14 94.59,53.55 92.58,55.57 92.58,57.97 92.92,58.31 93.24,58.31 PR204.1
CPUFAN_PWM: length 68.4
  TOP w0.102: v1(8.55,17.42) 8.55,17.42 8.55,17.42 FR1.2 9.29,16.44 9.62,16.11 FR3.1 ; v2(61.13,10.83) v1(61.13,9.89)
  IN1 w0.102: v1(61.13,9.89) 60.76,9.52 58.02,9.52 57.35,10.19 53.1,10.19 51.8,8.89 48.89,8.89 48.51,9.27 43.06,9.27 42.6,8.81 39.08,8.81 35.42,12.47 31.52,12.47 29.35,14.64 20.53,14.64 20.53,14.65 19.01,14.65 18.33,15.33 13.66,15.33 11.56,17.42 v1(8.55,17.42)
  BOTTOM w0.102: v1(61.13,9.89) 61.57,10.33 63.09,10.33 63.3,10.12 64.33,10.12 64.71,10.5 66.74,10.5 66.92,10.32 U24.32
CPUFAN_TACH: length 75.1
  TOP w0.102: v1(13.3,17.31) 12.64,17.97 10.72,17.97 FR5.2 10.75,17.42 11.14,17.03 11.14,15.27 10.63,14.77 8.12,14.77 7.72,15.16 FR4.2 6.17,14.33 FD4.2 FD4.1
  IN1 w0.102: v1(13.3,17.31) 13.48,17.31 14.16,16.63 14.16,16.61 14.63,16.14 18.92,16.14 19.46,15.59 30.03,15.59 31.64,13.98 36.34,13.98 36.38,13.94 37.03,13.29 39.18,13.29 39.93,12.54 44.69,12.54 45.54,13.39 54.24,13.39 55.32,14.47 58.27,14.47 58.56,14.77 61,14.77 61.21,14.98 62.33,14.98 62.69,14.62 64.95,14.62 65.68,15.36 65.98,15.36 66.43,15.81 v1(67.37,15.81)
  BOTTOM w0.102: v2(13.48,18.3) 13.3,18.12 v1(13.3,17.31) ; v1(67.37,15.81) 66.57,16.6 U24.47
CPVEE: length 2.1
  TOP w0.229: AC62.1 15.69,100.77 15.6,100.86 AU1.20
CR6_R: length 12.4
  TOP w0.102: v1(91.93,13.46) 91.86,13.52 R176.2 ; v1(93.24,10.3) 90.57,7.63 89.58,7.63 89,7.05 CR6.L1
  IN1 w0.102: v1(93.24,10.3) 93.82,10.88 93.82,11.4 91.93,13.29 v1(91.93,13.46)
  BOTTOM w0.102: v2(93.94,10.2) 93.85,10.3 v1(93.24,10.3)
CR_PE1_RXN2: length 152.2
  IN1 w0.102: v1(79.28,53.64) 78.99,53.35 78.99,53.14 78.79,52.94 78.36,52.94 78.12,52.7 78.12,52.34 78.36,52.09 79.35,52.09 79.44,52.18 81.27,52.18 81.3,52.2 83.37,52.2 84.04,51.53
  IN1 w0.114: 84.04,51.53 85.78,49.79 85.78,39.95 85.2,39.36 85.2,38.08 79.14,32.03 73.9,32.03 72.68,30.81 58.03,30.81 55.74,28.52 55.74,28.13 53.86,26.25 47.67,26.25 47.23,25.81 45.71,25.81 44.99,25.09 43.65,25.09 43.23,24.67 38.68,24.67 38.07,24.06 37.08,24.06 36.56,23.54 21.7,23.54 20.55,22.4 14.5,22.4 14.27,22.63 10.53,22.63 5.58,27.58 5.58,36.69 8.02,39.13 8.02,46.07 9.93,47.98 9.93,49.38 9.75,49.56 v1(9.25,49.56)
  BOTTOM w0.114: v1(9.25,49.56) 8.12,49.56 6.98,50.7 4.51,50.7 2.26,52.95 2.26,58.44 3.07,59.24 SC22.2 ; XU1.AP10 79.63,53.99 v1(79.28,53.64)
CR_PE1_RXN2_C: length 2.8
  BOTTOM w0.114: U23.6 6.8,58.71 6.68,58.58 6.03,58.58 5.71,58.91 5.17,58.91 SC22.1
CR_PE1_RXP2: length 152.1
  IN1 w0.102: v1(78.55,53.58) 78.78,53.35 78.78,53.22 78.71,53.15 78.28,53.15 77.91,52.78 77.91,52.25 78.28,51.89 79.43,51.89 79.52,51.98 81.36,51.98 81.38,52 83.23,52 84.04,51.19
  IN1 w0.114: 84.04,51.19 85.54,49.69 85.54,40.05 84.96,39.46 84.96,38.18 79.04,32.27 73.8,32.27 72.58,31.05 57.93,31.05 55.5,28.62 55.5,28.23 53.76,26.49 47.57,26.49 47.13,26.05 45.61,26.05 44.89,25.33 43.55,25.33 43.13,24.91 38.58,24.91 37.97,24.3 36.98,24.3 36.46,23.78 21.6,23.78 20.45,22.64 14.6,22.64 14.37,22.87 10.63,22.87 5.82,27.68 5.82,36.59 8.26,39.03 8.26,45.97 10.17,47.88 10.17,49.48 9.85,49.8 9.62,49.8 v1(9.23,50.19)
  BOTTOM w0.114: v1(78.55,53.58) 78.76,53.58 78.85,53.67 78.85,53.82 78.92,53.88 XU1.AP12 ; SC21.2 3.47,58.35 3.39,58.44 3.39,58.6 3.55,58.76 3.55,58.87 3.42,59 3.17,59 2.5,58.34 2.5,53.05 4.61,50.94 7.08,50.94 8.22,49.8 8.83,49.8 v1(9.23,50.19)
CR_PE1_RXP2_C: length 2.7
  BOTTOM w0.114: U23.5 6.82,58.21 6.69,58.34 5.93,58.34 5.61,58.66 5.14,58.66 SC21.1
CR_PE1_TXN2: length 152.1
  TOP w0.114: v1(87.9,39.35) 87.9,39.19 88.01,39.09 88.24,39.09 88.8,39.64 88.8,42.48 91.28,44.97 91.28,48.73 89.1,50.9 89.1,52.43 88.7,52.83 88.59,52.83 SC9.1
  IN1 w0.114: v1(6.24,56.71) 6.03,56.5 5.15,56.5 4.68,56.03 4.68,54.92 4.07,54.31 4.07,51.9 4.91,51.06 5.87,51.06 7.45,49.49 7.45,48.27 6.2,47.02 6.2,39.84 3.83,37.46 3.83,24.71 5.91,22.63 8,22.63 10.54,20.09 10.63,20.05 11.3,20.05 15.89,20.05 16.37,19.57 22.29,19.57 24.29,21.58 42.12,21.58 43.27,22.73 48.02,22.73 49.57,24.28 55.63,24.28 56.8,25.45 58.97,25.45 59.68,25.45 61.83,27.59 69.97,27.59 70.73,26.83 72.76,26.83 73.37,27.44 73.37,29.06 74.62,30.3 80.28,30.3 86.73,36.75 86.73,37.16 87.51,37.93 87.51,38.44 87.72,38.66 87.72,39.18 v1(87.9,39.35)
  BOTTOM w0.114: U23.2 6.86,56.71 6.77,56.63 6.77,56.52 6.72,56.47 6.48,56.47 v1(6.24,56.71)
CR_PE1_TXP2: length 152.2
  TOP w0.114: v1(87.27,39.35) 87.77,38.85 88.34,38.85 89.04,39.54 89.04,42.38 91.52,44.87 91.52,48.83 89.34,51 89.34,52.53 88.8,53.07 88.6,53.07 SC10.1
  IN1 w0.114: v1(87.27,39.35) 87.48,39.14 87.48,38.76 87.27,38.54 87.27,38.03 86.49,37.26 86.49,36.85 80.18,30.54 74.52,30.54 73.13,29.16 73.13,27.54 72.66,27.07 70.83,27.07 70.07,27.83 61.73,27.83 59.58,25.69 59.07,25.69 56.7,25.69 55.53,24.52 49.47,24.52 47.92,22.97 43.17,22.97 42.02,21.82 24.19,21.82 22.19,19.81 16.47,19.81 15.99,20.29 11.2,20.29 11.2,20.29 10.68,20.29 10.68,20.29 8.1,22.87 6.01,22.87 4.07,24.81 4.07,37.36 6.44,39.74 6.44,46.92 7.69,48.17 7.69,49.39 7.69,49.59 5.97,51.3 5.01,51.3 4.31,52 4.31,54.21 4.92,54.82 4.92,55.93 5.25,56.26 6.05,56.26 v1(6.24,56.07)
  BOTTOM w0.114: U23.1 6.39,56.21 v1(6.24,56.07)
DDI0_RCOMP_N: length 16.1
  TOP w0.114: SR18.1 90.39,60.11 90.19,59.92 89.74,59.92 89.6,59.77 89.6,59.77 89.3,59.47 89.3,58.92 v1(89.11,58.74)
  IN1 w0.114: v1(77.94,56.53) 78.33,56.93 78.33,57.58 79.02,58.26 79.68,58.26 79.7,58.29 80.31,58.29 80.34,58.26 80.34,58.27 80.95,58.27 80.96,58.26 86.16,58.26 87.04,59.15 88.44,59.15 88.85,58.74 v1(89.11,58.74)
  BOTTOM w0.114: XU1.AK13 78.21,56.26 v1(77.94,56.53)
DDI0_RCOMP_P: length 16.1
  TOP w0.114: SR18.2 90.39,59.52 90.24,59.67 89.84,59.67 89.84,59.67 89.54,59.37 89.54,58.91 89.54,58.52 89.33,58.31 89.26,58.31 v1(88.98,58.03)
  IN1 w0.114: v1(88.98,58.03) 88.98,58.04 88.69,58.33 88.69,58.56 88.34,58.9 87.14,58.9 86.26,58.02 80.86,58.02 80.85,58.02 80.44,58.02 80.44,58.02 80.24,58.02 80.21,58.05 79.8,58.05 79.78,58.02 79.12,58.02 78.58,57.48 v1(78.58,56.55)
  BOTTOM w0.114: XU1.AK12 78.58,56.33 v1(78.58,56.55)
DDI1_AUXN: length 3.5
  TOP w0.102: v1(86.17,56.36) 86.17,56.11 ST2.1
  BOTTOM w0.102: XU1.AK2 85.8,56 v1(86.17,56.36)
DDI1_AUXP: length 4.6
  TOP w0.102: ST1.1 84.8,55.89 85.33,56.42 v1(85.53,56.42)
  BOTTOM w0.102: XU1.AK3 83.3,56 83.59,56.29 83.87,56.29 83.95,56.2 85.32,56.2 v1(85.53,56.42)
DDI_V1P0_S0IX: length 22.4
  TOP w0.254: v2(75.58,56.47) 75.81,56.47 v1(76.21,56.07)
  TOP w0.419: 75.51,52.34 75.51,52.98 76.12,53.59 76.12,54.1 77.01,55 v1(77.01,55.3) 77.01,55.6 76.54,56.07 v1(76.21,56.07)
  TOP w0.457: 75.51,52.34 75.51,50.02 76.28,49.25 76.47,49.25 76.93,48.78 76.93,47.74 76.28,47.09 76.28,45.74 77.01,45.02 C941134.1 C20.1 C941135.1 C21.1 77.91,41.8 78.01,41.7 SL3.1
  BOTTOM w0.254: XU1.AM16 77.01,55.3 v1(77.01,55.3) ; XU1.AK21 74.57,55.44 74.85,55.44 XU1.AK19 75.09,55.71 XU1.AJ18 75.85,56.43 v1(76.21,56.07)
DDR3_DRAMRST0#: length 74.9
  TOP w0.102: HC1.1 63.72,79.87 v1(63.24,80.35) ; v1(30.14,84.88) 30.25,84.77 D3C1.1 v2(31.27,85.84)
  IN1 w0.102: v1(64.69,64.26) 64.96,63.99 64.96,63.95 65.21,63.71 65.56,63.71 65.98,64.13 65.98,66.83 66.33,67.18 66.63,67.18 66.89,67.44 66.89,69.15 66.05,69.99 66.05,74.15 63.47,76.73 63.47,80.13 v1(63.24,80.35)
  IN2 w0.102: v1(63.24,80.35) 62.82,80.77 59.29,80.77 58.69,81.37 58.69,81.37 58.17,81.9 54.21,81.9 43.32,92.79 43.32,93.55 40.39,96.48 35.16,96.48 30.68,91.99 30.68,85.41 v1(30.14,84.88)
  BOTTOM w0.102: XMM1.30 v1(30.14,84.88) ; v1(64.69,64.26) 64.69,64.06 XU1.P41
DDR_THERMAL_EC: length 64.7
  TOP w0.102: v2(36.7,26.59) 36.91,26.37 38.14,26.37 v1(38.57,25.94) ; O2R241.1 69.31,23.78 v1(69.41,23.89)
  IN2 w0.102: v1(68.67,12.3) 68.27,12.71 63.91,12.71 61.95,14.68 47.23,14.68 46.11,13.56 41.95,13.56 40.57,14.94 38.87,14.94 38.55,15.26 38.55,17.63 40.39,19.47 40.39,24.31 38.76,25.94 v1(38.57,25.94)
  BOTTOM w0.102: v1(38.57,25.94) 39.5,25.94 41.09,27.53 PRT3.1 ; v1(68.67,12.3) 69.46,13.09 69.46,20.81 69.41,20.86 v1(69.41,23.89) 69.32,23.98 U24.71
DDRTEMP_HOT_EC_R: length 3.6
  BOTTOM w0.102: U24.123 81.72,13.01 82.62,13.9 83.61,13.9 83.74,14.03 ST82.1
DEPOP#: length 4.9
  TOP w0.102: v2(25.65,101.61) 25.33,101.93 AR10.2 AC7.1 25.33,104.16 24.97,104.52 AQ3.1
DIMM_CA_VREF_A: length 7.7
  TOP w0.102: v2(29.07,53.15) 29.13,53.22 29.32,53.22 v1(29.66,53.57)
  TOP w0.254: D3CB5.1 31.3,54.54 D3R2.2 31.3,55.05 31.01,55.34 C89.1 ; D3CB5.1 D3CB1.1 ; D3CB5.1 D3R4.1 v1(29.66,53.57)
  BOTTOM w0.254: XMM1.126 29.77,53.68 v1(29.66,53.57)
DIMM_VREF_A: length 6.7
  TOP w0.102: v2(41.7,93.96) 41.7,93.96 v1(42.21,93.45)
  TOP w0.254: v1(42.21,93.45) 42.21,93.45 41.85,93.09 D3R3.1 D3CB2.2 D3R1.2
  BOTTOM w0.254: v1(42.21,93.45) 42.08,93.58 XMM1.1
DP_AUXN: length 50.8
  IN2 w0.114: v1(88.1,56.19) 88.33,55.97 88.61,55.97 90.7,58.06 90.7,77.6 88.08,80.22 88.08,87.69 88.63,88.24 88.63,91.55 91.24,94.16 91.24,94.9 91.17,94.97 v1(90.87,94.97)
  BOTTOM w0.102: XU1.AL1 84.31,55.51 84.32,55.52 85.05,55.52 85.06,55.51 86.18,55.51 86.24,55.58 86.29,55.62 86.3,55.62 86.31,55.64
  BOTTOM w0.114: v1(90.87,94.97) 90.87,94.52 90.75,94.4 90.57,94.4 90.44,94.52 90.44,95.24 90.32,95.36 90.14,95.36 90.02,95.24 90.02,94.69 M1C21.1 ; 86.31,55.64 86.43,55.76 87.67,55.76 v1(88.1,56.19)
DP_AUXN_C: length 4.1
  BOTTOM w0.114: MQ42.4 85.62,93.9 86.25,93.28 87.76,93.28 M1C21.2
DP_AUXN_LS: length 14.3
  TOP w0.114: v1(86.5,93.9) MQ40.3 84.82,93.9 84.8,93.91 M1R1.2 84.21,94.15 v1(84.57,94.52)
  IN2 w0.114: J125.17 84.72,102.27 84.1,101.66 84.1,99.12 84.57,98.65 v1(84.57,94.52)
  BOTTOM w0.114: MQ42.3 v1(86.5,93.9)
DP_AUXP: length 50.8
  IN2 w0.114: v1(87.44,56.22) 87.94,55.72 88.71,55.72 90.94,57.96 90.94,77.7 88.32,80.32 88.32,87.59 88.87,88.14 88.87,91.45 91.48,94.06 91.48,95 v1(90.87,95.6)
  BOTTOM w0.102: XU1.AL3 83.5,55.64 83.79,55.64 83.94,55.79 84.45,55.79 84.52,55.72 85.13,55.72 85.14,55.71 86.09,55.71 86.14,55.77 86.14,55.77 86.16,55.79
  BOTTOM w0.114: 86.16,55.79 86.34,55.97 87.2,55.97 v1(87.44,56.22) ; v1(90.87,95.6) 90.04,95.6 M1C20.1
DP_AUXP_C: length 4.1
  BOTTOM w0.114: MQ42.1 86.78,95.2 86.66,95.32 86.66,95.97 86.78,96.1 88.28,96.1 88.78,95.6 M1C20.2
DP_AUXP_LS: length 16
  TOP w0.114: MQ40.1 84.97,95.2 84.72,94.95 84.44,94.95 M1R2.1 84.21,94.81 v1(83.94,94.55)
  IN2 w0.114: J125.15 86.26,103.57 86.12,103.44 86.12,103.08 86.3,102.9 86.3,102.58 86.23,102.51 84.62,102.51 83.86,101.76 83.86,99.02 84.33,98.55 84.33,94.94 v1(83.94,94.55)
  BOTTOM w0.114: MQ40.1 84.59,95.2 v1(83.94,94.55)
DP_DDPC_CTRL: length 13.9
  TOP w0.102: MQ41.3 85.92,91.23 86.34,90.81 87.68,90.81 87.86,90.99 MR24.2 88.87,90.57 89.79,90.57 v2(90.29,91.07) 90.44,91.22 90.44,91.93 89.79,92.58 88.77,92.58 88.65,92.7 88.65,94.1 88.46,94.3 88.46,94.6 88.21,94.85 87.79,94.85 87.5,94.55 MQ40.5 MQ40.2
DP_HPD#: length 47.1
  TOP w0.102: MQ3.3 92.77,94.04 SR12.2 93.27,91.64 91.66,90.03 83.33,90.03 81.79,88.49 78.07,88.49 v1(76.55,86.97)
  BOTTOM w0.102: XU1.D27 71.3,69.08 71.59,69.38 71.59,69.62 71.49,69.72 71.49,69.99 71.58,70.08 71.58,71.25 70.83,71.99 70.83,72.27 70.29,72.82 70.29,73.56 69.65,74.2 69.65,75.86 69.54,75.97 69.54,76.87 68.99,77.41 68.99,78.24 69.77,79.02 v2(69.77,80.78) 69.77,81.52 71.84,83.59 71.84,85.71 72.14,86.01 75.6,86.01 v1(76.55,86.97)
DP_HPDET: length 20.1
  TOP w0.102: v2(88.51,96.28) 89.48,95.31 MQ3.1 90.23,94.99 90.67,94.55 92.74,94.55 92.86,94.42 SR13.1 93.27,95.03 93.25,95.06 MD5.1 93.25,101.57 92.16,102.66 92.16,103.3 90.87,104.58 89.83,104.58 89.1,103.84 89.1,103.57 J125.18
DP_TMDS_DATA0_N: length 5.9
  BOTTOM w0.114: M1C13.2 87.29,116.36 87.75,115.91 87.75,112.18 J125.3
DP_TMDS_DATA0_P: length 5.9
  BOTTOM w0.114: J125.1 87.34,112.28 87.42,112.28 87.51,112.37 87.51,115.81 87.3,116.01 86.68,116.01 86.48,116.21 M1C11.2
DP_TMDS_DATA1_N: length 13.1
  BOTTOM w0.114: 91.31,110.75 90.06,110.75 89.44,111.37 89.09,111.37 J125.6 ; 91.31,110.75 v2(91.31,110.47) ; 91.31,110.75 93.53,110.75 93.81,110.47 93.81,108 95.38,106.42 95.8,106.42 96.17,106.06 96.17,105.8 M1C15.2
DP_TMDS_DATA1_P: length 13.1
  BOTTOM w0.114: 92.96,110.99 93.63,110.99 94.05,110.57 94.05,108.1 95.48,106.66 95.9,106.66 96.41,106.16 M1C12.2 ; 92.96,110.99 v2(92.96,111.27) ; 92.96,110.99 90.16,110.99 89.54,111.61 88.85,111.61 J125.4
DP_TMDS_DATA2_N: length 15.9
  BOTTOM w0.114: v2(81.42,111.74) 81.69,111.74 ; 81.69,111.74 81.69,113.89 82.16,114.36 83.83,114.36 85.11,115.64 85.11,116.43 M1C17.2 ; 81.69,111.74 81.69,111.19 82.06,110.82 83.83,110.82 85.31,109.33 85.31,107.93 85.67,107.58 86.15,107.58 86.26,107.47 J125.9
DP_TMDS_DATA2_P: length 16
  BOTTOM w0.114: 81.93,113.32 81.93,113.79 82.26,114.12 83.93,114.12 85.35,115.54 85.35,116.44 M1C16.2 ; 81.93,113.32 81.93,111.29 82.16,111.06 83.93,111.06 85.55,109.43 85.55,108.03 85.77,107.82 86.13,107.82 86.4,108.09 86.4,108.23 J125.7 ; 81.93,113.32 v2(82.21,113.32)
DP_TMDS_DATA3_N: length 8.2
  BOTTOM w0.114: v2(91.61,106.6) 91.61,106.88 ; 91.61,106.88 90.7,106.88 89.77,107.8 89.43,107.8 J125.12 ; 91.61,106.88 93.6,106.88 93.91,106.57 93.91,105.47 M1C19.2
DP_TMDS_DATA3_P: length 8.2
  BOTTOM w0.114: 94.15,106.18 94.15,106.67 93.7,107.12 90.8,107.12 89.87,108.04 89.12,108.04 89.04,108.12 J125.10 ; 94.15,106.18 94.15,105.41 M1C18.2 ; 94.15,106.18 v2(94.43,106.18)
DP_TXN0: length 88.2
  IN2 w0.114: v1(87.47,118.18) 86.82,117.53 86.82,117.2 86.92,117.1 91.55,117.1 95.92,112.73 95.92,99.72 95.05,98.85 95.05,92.77 91.85,89.57 91.85,86.7 91.27,86.12 91.27,81.54 93.88,78.93 93.88,67.38 94.36,66.91 94.36,62.05 94.45,61.96 94.45,57.15 92.66,55.36 92.66,52 91.63,50.97 90.84,50.97 v1(90.44,50.58)
  BOTTOM w0.114: v1(87.47,118.18) 87.29,118.01 M1C13.1 ; v2(89.43,50.52) 89.43,50.8 ; 89.43,50.8 88.71,50.8 88.5,50.58 86.06,50.58 84.72,51.92 83.92,51.92 XU1.AV2 ; 89.43,50.8 90.23,50.8 v1(90.44,50.58)
DP_TXN1: length 66.4
  IN2 w0.114: v1(90.85,52.42) 91.13,52.69 91.13,55.2 93.48,57.55 93.48,61.55 93.38,61.65 93.38,66.5 92.91,66.98 92.91,78.52 90.29,81.14 90.29,86.57 90.86,87.14 90.86,90.01 93.45,92.6 93.45,97.07 93.58,97.21 93.58,100.3 v1(94.07,100.8)
  BOTTOM w0.102: XU1.AT3 83.3,53.08 83.59,53.37 83.87,53.37 83.96,53.28 85.01,53.28 85.37,52.92
  BOTTOM w0.114: v1(94.07,100.8) 95.6,100.8 95.69,100.89 95.69,102.9 ; M1C15.1 95.52,103.49 95.69,103.32 95.69,102.9 ; 95.69,102.9 v2(95.42,102.9) ; 85.37,52.92 86.18,52.11 90.54,52.11 v1(90.85,52.42)
DP_TXN2: length 83
  IN2 w0.114: v1(89.39,53.09) 89.39,53.16 90.31,54.08 90.31,55.43 92.74,57.86 92.74,61.25 92.17,61.82 92.17,78.21 89.55,80.83 89.55,86.9 90.12,87.47 90.12,90.32 92.71,92.9 92.71,98.15 92.8,98.24 92.8,105.67 92.1,106.38 92.1,114.83 90.94,115.99 86.39,115.99 85.45,116.93 85.45,117.39 85.27,117.58 85.27,118.6 85.14,118.73 84.93,118.73 84.8,118.6 v1(84.8,118.18)
  BOTTOM w0.102: 86.94,52.92 87.1,53.09 87.75,53.09 ; 85.39,53.34 85.08,53.65 84.19,53.65 XU1.AR1
  BOTTOM w0.114: v2(88.59,52.79) 88.59,53.09 ; 88.59,53.09 v1(89.39,53.09) ; 88.59,53.09 87.75,53.09 ; v1(84.8,118.18) M1C17.1 ; 85.39,53.34 85.84,52.89 86.91,52.89 86.94,52.92
DP_TXN3: length 61.3
  IN2 w0.114: v1(88.71,54) 88.37,54.34 88.37,54.81 88.66,55.1 88.79,55.1 91.99,58.3 91.99,60.06 91.43,60.62 91.43,77.91 88.82,80.53 88.82,87.28 89.37,87.84 89.37,90.61 91.97,93.21 91.97,96.77 91.67,97.06 91.67,98.09 v1(91.41,98.36)
  BOTTOM w0.102: XU1.AP2 85.91,54.05 85.92,54.04
  BOTTOM w0.114: M1C19.1 93.91,104 93.91,102.57 ; 85.92,54.04 88.67,54.04 v1(88.71,54) ; 93.91,102.57 v2(93.62,102.57) ; 93.91,102.57 93.91,101.86 93.07,101.02 93.07,100.69 91.67,99.3 91.67,98.62 v1(91.41,98.36)
DP_TXP0: length 88.2
  IN2 w0.114: v1(90.42,51.22) 91.53,51.22 92.42,52.1 92.42,55.46 94.21,57.25 94.21,61.86 94.12,61.95 94.12,66.81 93.64,67.28 93.64,78.83 91.03,81.44 91.03,86.22 91.61,86.8 91.61,89.67 94.8,92.87 94.8,98.95 95.67,99.82 95.67,112.63 91.45,116.86 86.82,116.86 86.58,117.1 v1(86.58,118.18)
  BOTTOM w0.114: XU1.AV3 83.31,52.11 83.6,52.41 83.85,52.41 84.1,52.16 84.82,52.16 86.16,50.82 87.17,50.82 ; 87.17,50.82 88.4,50.82 88.61,51.04 90.24,51.04 v1(90.42,51.22) ; 87.17,50.82 v2(87.17,51.11) ; v1(86.58,118.18) 86.58,117.99 86.48,117.89 M1C11.1
DP_TXP1: length 66.4
  IN2 w0.114: v1(90.87,51.78) 90.87,51.84 91.37,52.33 91.37,55.1 93.72,57.45 93.72,61.65 93.62,61.75 93.62,66.6 93.15,67.08 93.15,78.62 90.53,81.24 90.53,86.47 91.1,87.04 91.1,89.91 93.69,92.5 93.69,96.97 93.82,97.11 93.82,99.91 v1(94.07,100.16)
  BOTTOM w0.102: XU1.AT2 84.87,53.08 85.03,52.92
  BOTTOM w0.114: v1(94.07,100.16) 94.47,100.56 95.7,100.56 95.93,100.79 95.93,101.15 ; 95.93,101.15 v2(96.21,101.15) ; 95.93,101.15 95.93,103.42 95.76,103.59 95.76,103.79 95.89,103.92 96.02,103.92 M1C12.1 ; 85.03,52.92 86.08,51.87 90.78,51.87 90.86,51.78 v1(90.87,51.78)
DP_TXP2: length 82.9
  IN2 w0.114: v1(85.69,118.18) 85.69,117.03 86.49,116.23 91.04,116.23 92.34,114.93 92.34,106.48 93.05,105.77 93.05,98.14 92.95,98.05 92.95,92.8 90.37,90.22 90.37,87.37 89.79,86.8 89.79,80.93 92.41,78.31 92.41,61.92 92.98,61.35 92.98,57.76 90.56,55.33 90.56,53.98 90.09,53.52 90.12,53.49 90.12,53.29 v1(90.02,53.19)
  BOTTOM w0.102: XU1.AR3 83.5,53.57 83.52,53.59 83.68,53.59 83.94,53.85 85.19,53.85 85.31,53.73 ; v2(86.38,53.4) 86.38,53.11
  BOTTOM w0.114: v1(85.69,118.18) 85.69,117.99 85.64,117.94 M1C16.1 ; 85.31,53.73 85.93,53.11 86.82,53.11 87.04,53.33 89,53.33 89.18,53.51 89.67,53.51 89.99,53.19 v1(90.02,53.19)
DP_TXP3: length 61.3
  IN2 w0.114: v1(92.04,98.36) 91.91,98.23 91.91,97.16 92.21,96.87 92.21,93.11 89.62,90.51 89.62,87.74 89.06,87.18 89.06,80.63 91.67,78.01 91.67,60.72 92.23,60.16 92.23,58.2 88.79,54.77 v1(88.79,54.63)
  BOTTOM w0.102: 86.06,54.26 83.95,54.26 83.86,54.34 83.6,54.34 83.31,54.05 XU1.AP3
  BOTTOM w0.114: M1C18.1 94.15,104.06 94.15,101.76 93.31,100.92 93.31,100.59 92.58,99.86 ; v1(88.79,54.63) 88.6,54.44 88.54,54.44 88.38,54.29 87.65,54.29 87.61,54.26 86.06,54.26 ; v1(92.04,98.36) 91.91,98.48 91.91,99.2 92.58,99.86 ; v2(92.77,99.65) 92.58,99.86
DPPP_DDC_CLK: length 53.3
  TOP w0.102: MQ40.6 88.15,95.2 88.66,94.68 88.66,94.59 89.52,93.74 90.04,93.74 91.89,91.89 91.89,90.86 91.25,90.23 83.16,90.23 81.63,88.69 77.53,88.69 v1(76.5,87.66) 75.53,88.63 SR16.2
  BOTTOM w0.102: v1(76.5,87.66) 75.05,86.22 72.06,86.22 71.63,85.8 71.63,83.67 70.79,82.83 70.02,82.83 69.38,83.47 68.32,83.47 68.09,83.24 v2(68.09,81.29) 68.09,80.45 67.62,79.98 67.62,77.94 68.23,77.33 68.23,76.41 69.04,75.6 69.04,73.95 69.68,73.31 69.68,72.55 70.15,72.08 70.15,70.86 70.61,70.4 70.61,70.06 70.52,69.98 70.52,69.72 70.82,69.42 XU1.C28
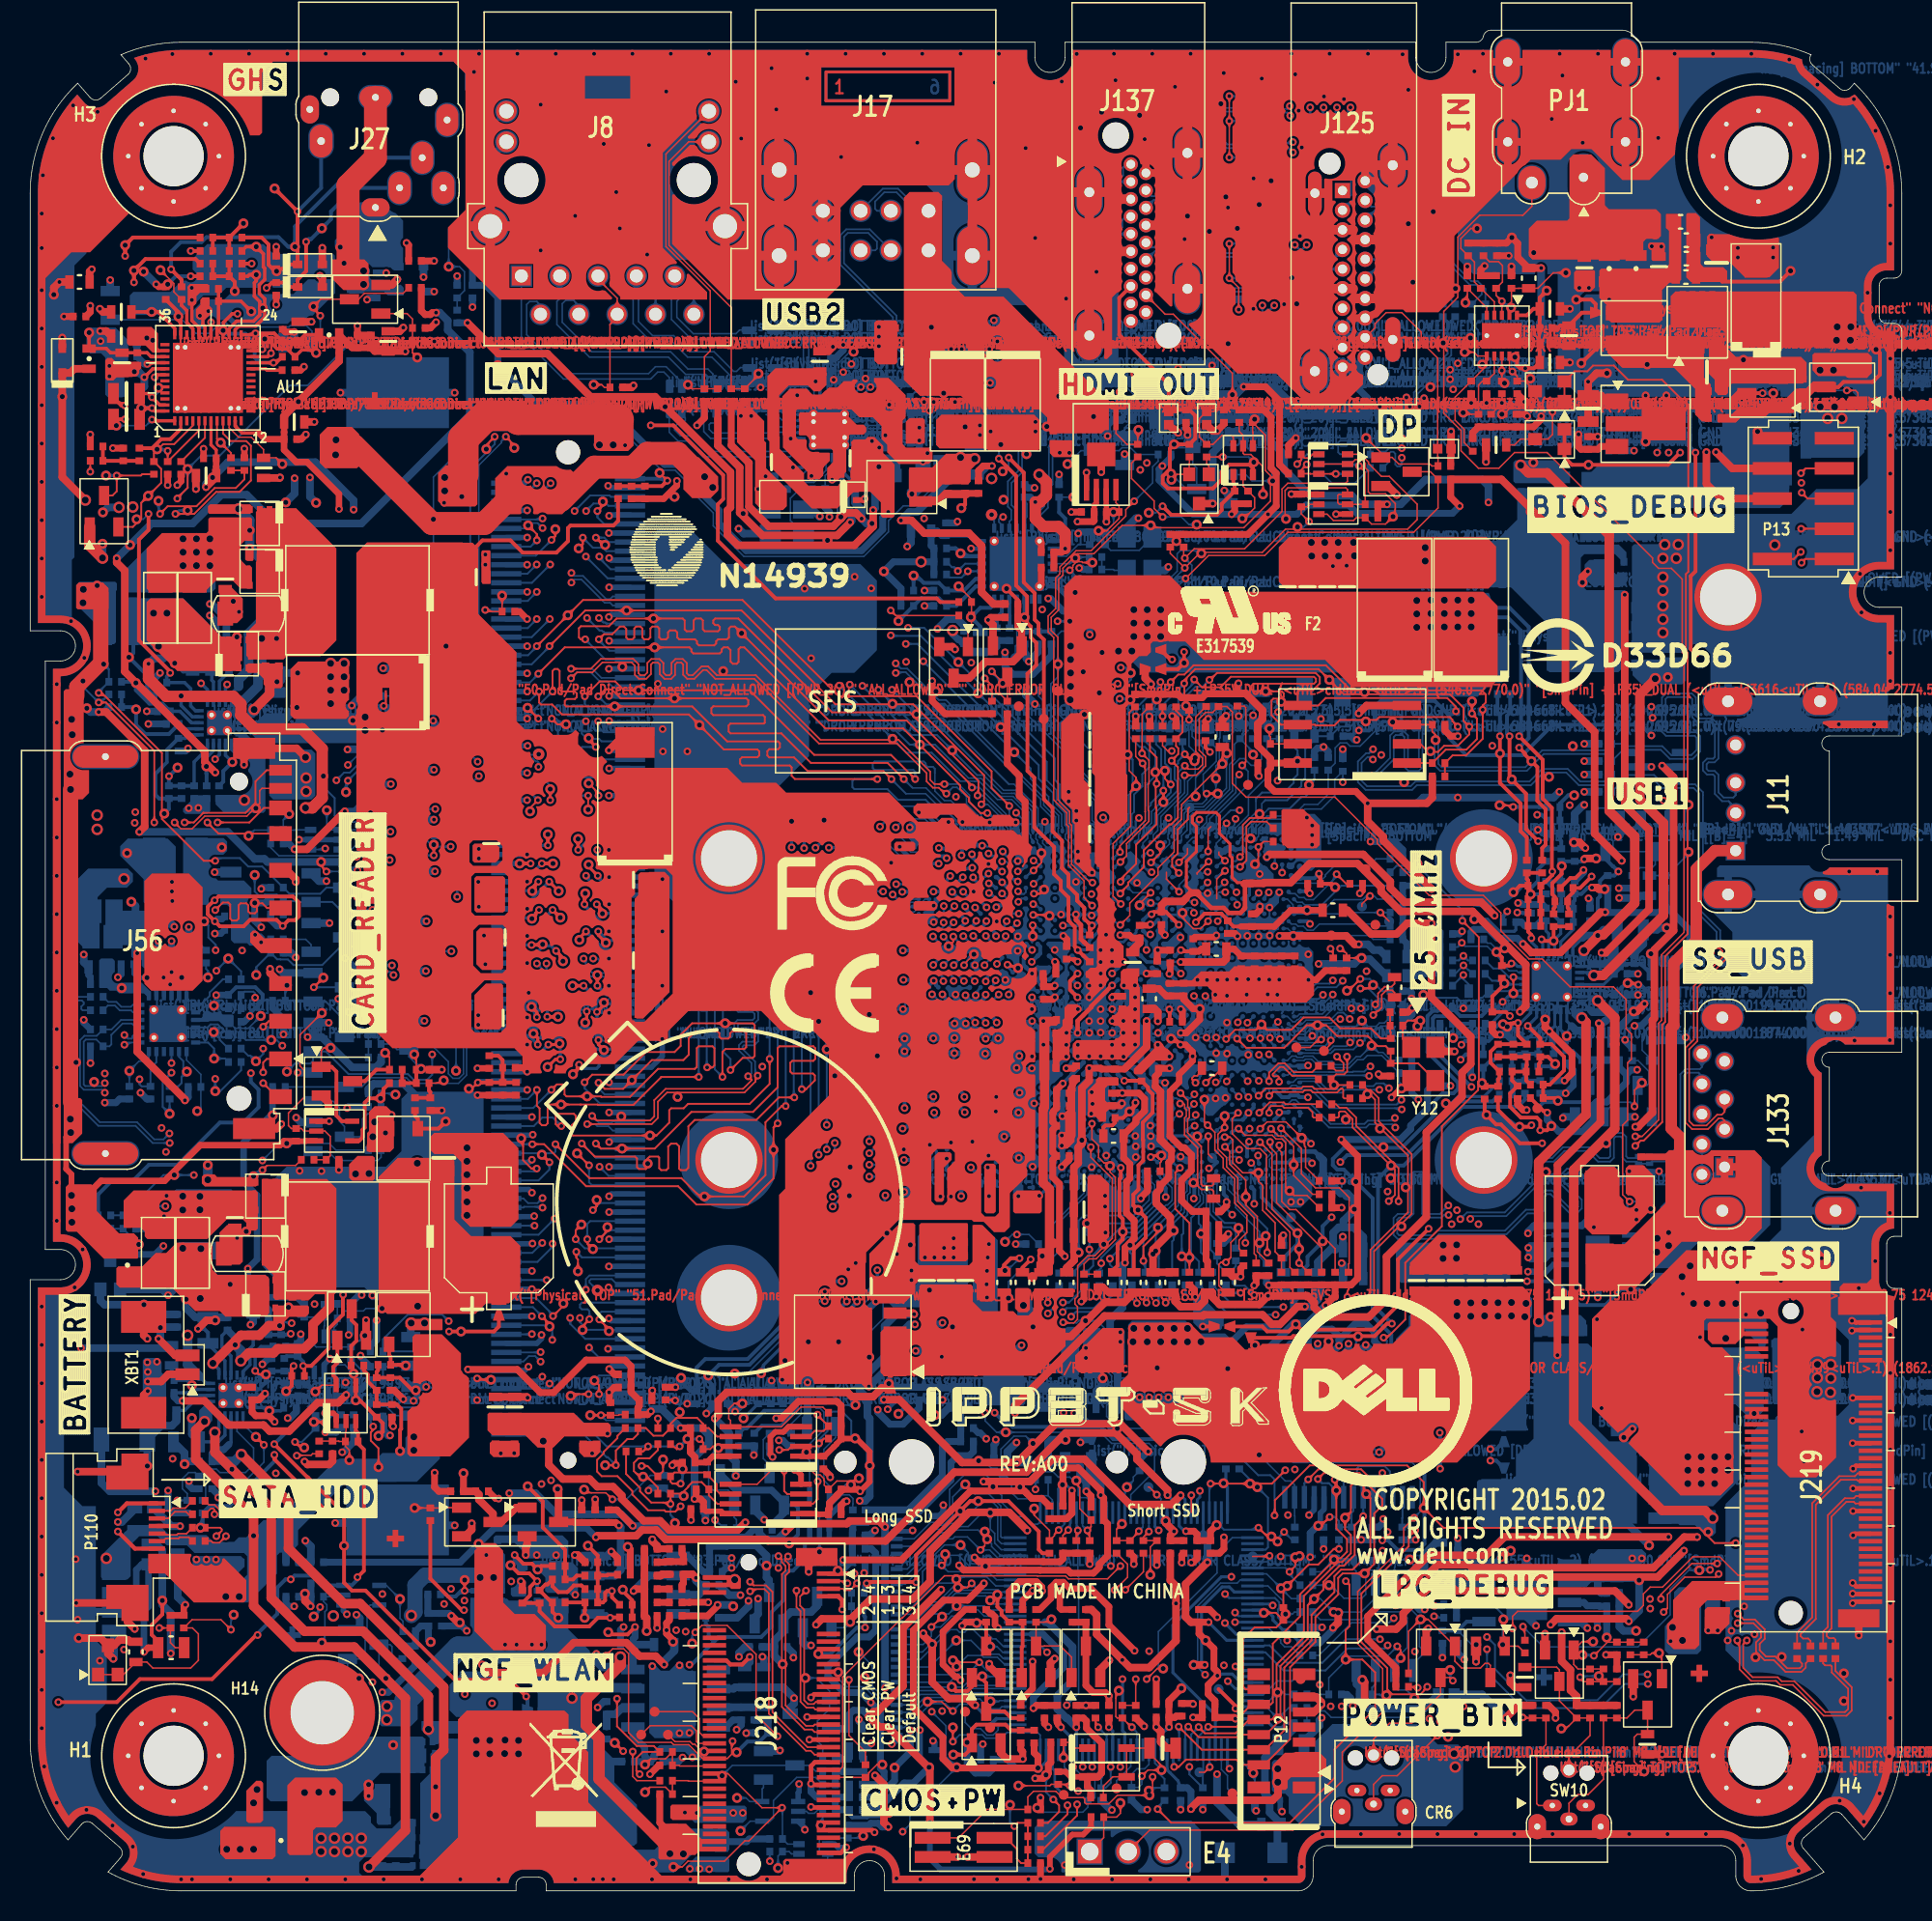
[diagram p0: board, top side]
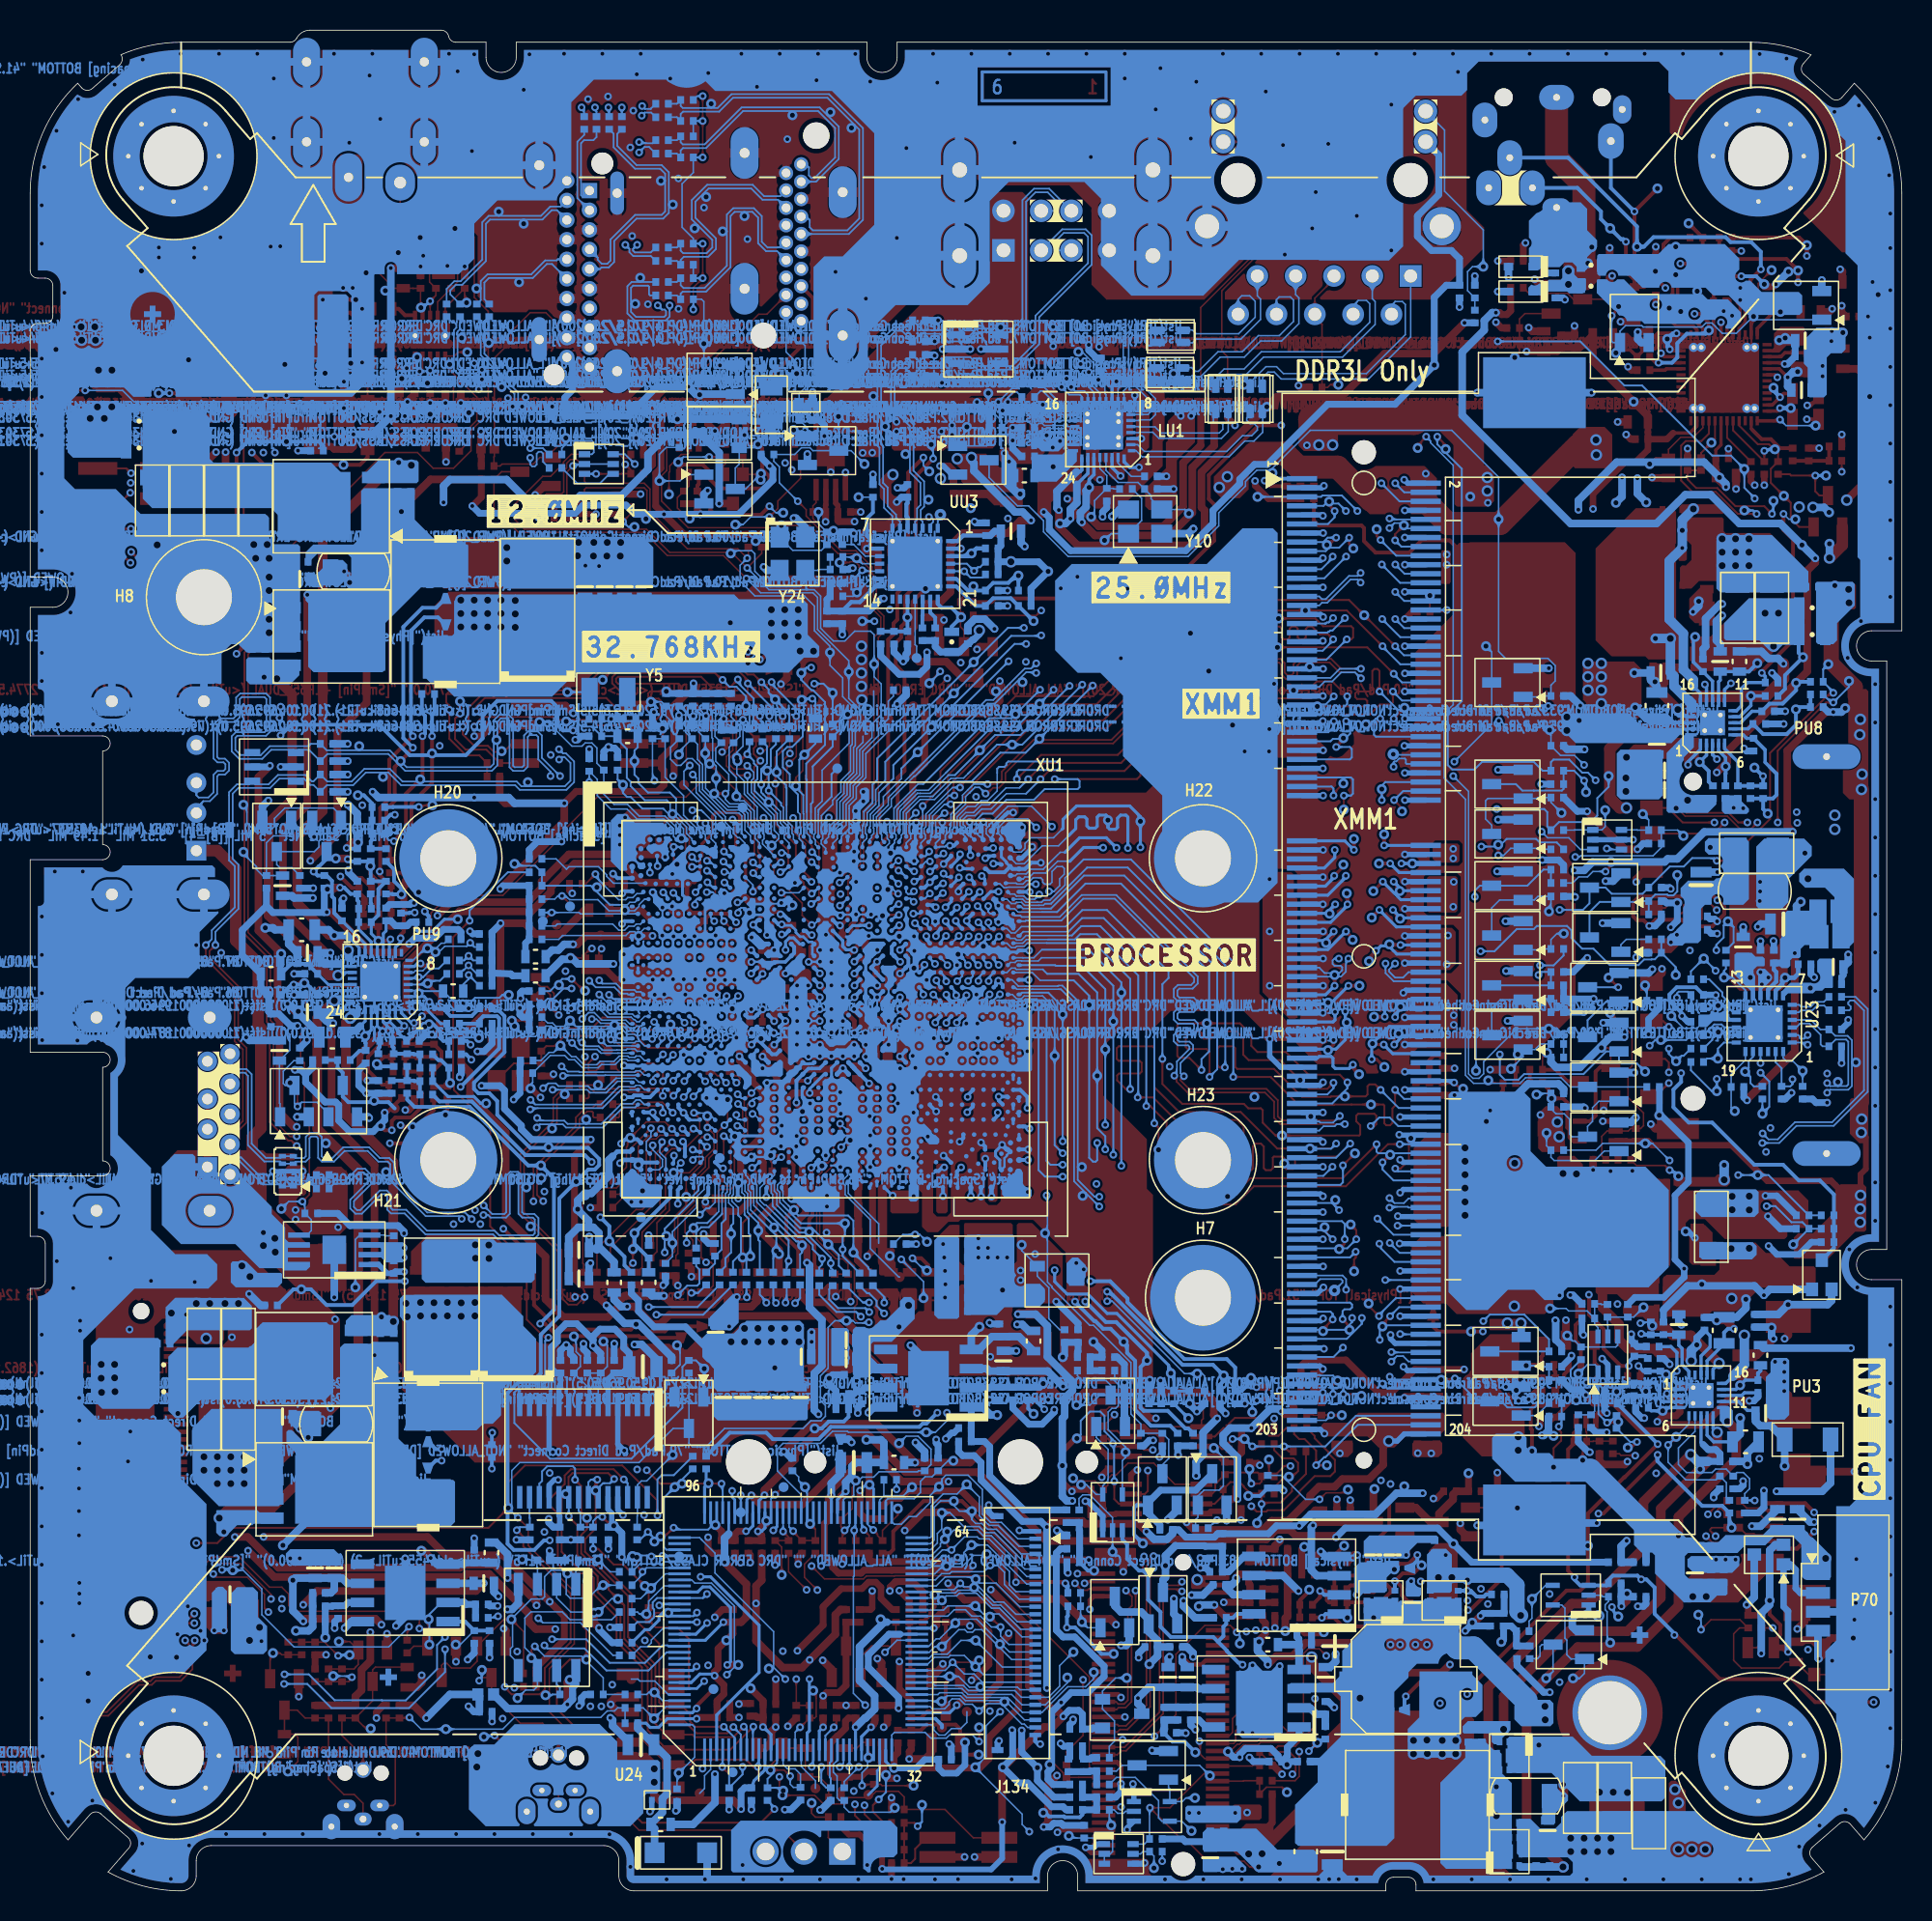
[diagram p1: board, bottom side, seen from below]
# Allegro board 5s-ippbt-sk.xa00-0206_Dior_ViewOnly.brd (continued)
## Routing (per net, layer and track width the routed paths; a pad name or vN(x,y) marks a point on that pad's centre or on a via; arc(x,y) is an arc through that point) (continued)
DPPP_DDC_DATA: length 40.8
  TOP w0.102: MQ40.4 87.28,93.4 87.15,93.28 83.32,93.28 82.94,92.9 82.94,91.41 80.46,88.93 77.12,88.93 v1(76.5,88.31) 76.42,88.39 SR14.2
  BOTTOM w0.102: XU1.C26 71.98,69.34 71.98,69.64 72.08,69.73 72.08,69.99 71.99,70.08 71.99,71.75 71.53,72.21 71.53,74.26 69.86,75.93 69.86,75.94 69.74,76.06 69.74,76.95 69.19,77.5 69.19,78.16 70.17,79.14 70.17,80.37 71.01,81.21 v2(71.01,82.06) 71.01,82.48 72.04,83.5 72.04,85.14 72.71,85.81 75.99,85.81 76.97,86.79 76.97,87.84 v1(76.5,88.31)
DRAM_CORE_PWORK_EC: length 51
  TOP w0.102: v1(73.25,14.03) SC26.1 SR153.2 ; v1(44.06,17.13) 44.06,17.16 44.49,17.59 46.18,17.59 48.09,15.67 48.09,11.66 v1(49.51,10.25)
  IN1 w0.102: v1(73.25,14.03) 72.93,13.71 72.93,13.71 72.63,13.41 70.78,13.41 70.52,13.67 69.37,13.67 69.04,13.34 68.25,13.34 68.04,13.13 66.04,13.13 65,12.09 64.88,12.09 64.17,12.79 61.7,12.79 61.56,12.94 59.32,12.94 56.8,10.42 53.05,10.42 52.03,9.4 50.36,9.4 v1(49.51,10.25)
  IN2 w0.102: v1(45.37,24.57) 43.08,22.28 43.08,18.86 44.06,17.88 v1(44.06,17.13)
  BOTTOM w0.102: v1(45.37,24.57) 45.42,24.52 45.45,24.52 45.67,24.3 45.69,24.3 SR663.1 ; v1(44.06,17.13) 43.86,16.93 v2(43.86,16.39)
DRAM_CORE_PWORK_EC_C: length 4.8
  TOP w0.102: v1(72.99,10.84) 72.97,10.84 SR153.1 72.03,11.45 71.93,11.55 71.93,13.06 v2(72.13,13.27)
  BOTTOM w0.102: U24.16 73.32,10.52 v1(72.99,10.84)
DRAM_CORE_PWROK: length 42.7
  IN2 w0.102: v1(56.66,46.08) 56.66,50.01 58.35,51.7 58.35,52.03 61.66,55.35 61.66,55.9 61.66,56.55 62.17,57.06 64.15,57.06 64.45,57.36 64.45,57.85 63.75,58.56 63.75,59.9 63.96,60.12 v1(63.96,60.33)
  BOTTOM w0.102: v1(63.96,60.33) 63.96,60.16 XU1.AB42 ; Q9415.3 48.99,28.23 48.57,28.65 48.57,29.9 HC10.1 SR1.2 50.41,30.94 51.07,31.6 51.07,35 53.55,37.48 53.8,37.48 56.3,39.98 56.3,40.05 56.6,40.35 56.6,43.42 v2(56.76,43.58) 56.6,43.74 56.6,46.03 v1(56.66,46.08)
DRAM_RCOMP0: length 41
  IN1 w0.254: v1(53.76,40.4) 54.59,40.4 55.19,41 55.19,41.94 58.4,45.15 58.4,47.23 57.3,48.32 57.3,52.52 58.87,54.09 58.87,56.23 60.84,58.2 62.2,58.2 63.31,59.3 v1(63.31,59.39)
  BOTTOM w0.254: v1(53.76,40.4) 52.45,40.4 51.3,39.25 51.3,39.01 47.53,35.24 44.72,35.24 44.16,34.68 SR9.2 43.74,33.12 43.12,33.74 v2(43.12,33.99) ; XU1.AD44 63.31,59.24 v1(63.31,59.39)
DRAM_RCOMP1: length 35.3
  IN1 w0.254: v1(54.78,39.05) 55.54,39.81 55.54,41.69 58.76,44.9 58.76,45.01 58.76,49.01 58.7,49.06 58.7,52.78 60.51,54.58 61.01,54.58 61.77,55.34 61.77,56.27 62.61,57.12 v1(62.61,57.54)
  BOTTOM w0.254: v1(62.61,57.54) 62.61,57.6 XU1.AF45 ; v1(54.78,39.05) 54.7,38.97 54.7,38.95 53.5,37.76 53.43,37.76 52.92,37.25 52.42,37.25 v2(51.55,36.38) 51.33,36.15 51.33,35.65 50.79,35.12 50.79,31.87 49.74,30.82 48.47,30.82 SR10.2
DRAM_RCOMP2: length 38.8
  IN1 w0.254: v1(61.97,59.35) 61.52,58.9 60.94,58.9 58.49,56.45 58.49,54.21 56.95,52.67 56.95,47.27 57.16,47.06 57.16,44.84 54,41.68 53.99,41.68 53.7,41.39 53.7,41.38 53.27,40.95 53.27,39.89 v1(54.1,39.05)
  BOTTOM w0.254: XU1.AD45 62.26,59 61.97,59.29 61.97,59.35 v1(61.97,59.35) ; SR11.2 47.27,30.64 47.47,30.64 48.63,31.81 50.23,31.81 50.44,32.01 50.44,34.71 v2(50,35.14) 50,35.65 52.05,37.69 52.74,37.69 v1(54.1,39.05)
DRAM_S4_PWROK_EC: length 148.4
  TOP w0.102: v1(57.02,84.85) 57.35,84.51 R60209.1
  IN2 w0.102: v1(63.26,31.68) 63.26,33.62 60.32,36.56 41.11,36.56 38.71,34.16 36.15,34.16 34.05,36.25 33.29,36.25 32.82,36.72 32.82,52.18 32.21,52.8 32.21,62.93 30.83,64.31 30.83,82.74 29.72,83.84 29.72,91.33 35.08,96.68 40.48,96.68 43.53,93.63 43.53,93.04 51.73,84.85 v1(57.02,84.85)
  BOTTOM w0.102: U24.80 72.92,26.25 74.49,27.82 74.49,29.28 74.13,29.65 71.65,29.65 70.85,30.45 69.85,30.45 69.79,30.39 v2(64.64,30.39) 64.03,30.39 63.26,31.15 v1(63.26,31.68)
DRAM_V1P0_S0IX: length 13.1
  TOP w0.61: 67.2,53.84 67.2,53.83 67.2,51.97 67.15,51.92 67.15,51.84 67.11,51.8 67.11,46.92 67.53,46.5 67.53,41.66
  BOTTOM w0.216: 67.13,57.64 67.13,56.95
  vias: v1(67.12,57.64) v1(67.13,56.07) v2(67.05,42.07)
DRAM_VDD_S4_PWROK: length 30.3
  TOP w0.102: Q38.3 SR2.2 64.2,79.37 64.2,80.32 v1(63.71,80.81)
  IN1 w0.102: v1(63.71,80.81) 63.71,76.77 66.27,74.21 66.27,70.2 66.81,69.66 67.1,69.37 67.1,67.19 66.92,67.02 66.92,63.89 65.8,62.77 65.31,62.77 65,62.46 65,61.78 65.17,61.62 65.17,60.33 64.72,59.88 64.65,59.88 v1(64.17,59.39)
  BOTTOM w0.102: XU1.AD42 63.68,58.91 v1(64.17,59.39) ; v1(63.71,80.81) 63.71,80.74 v2(64.43,80.02)
DRAM_VREF_CPU: length 33.7
  IN1 w0.203: v1(56.13,41.13) 56.13,41.57 59.19,44.63 59.19,44.83 59.19,45.48 59.19,45.48 59.19,49.19 59.14,49.24 59.14,52.6 59.86,53.32 60.36,53.32 62.3,55.26 62.3,56.13 63.3,57.13 v1(63.3,57.51)
  BOTTOM w0.203: HC2.1 R1.2 48.23,34.1 v2(48.43,34.3) 48.58,34.45 48.58,34.84 52.01,38.26 52.65,38.26 53.93,39.54 55.3,39.54 56.13,40.37 v1(56.13,41.13) ; XU1.AF44 63.3,57.62 v1(63.3,57.51)
DRAM_VREF_CPU_R: length 3
  BOTTOM w0.203: v2(47.26,31.31) 47.26,31.31 R1.1 SR6.1 SR5.2
EC_AGND: length 74.2
  TOP w0.457: v1(61.54,21.57) 61.85,21.26 66.89,21.26 66.9,21.24 68.76,21.24 68.95,21.05 70.45,21.05 70.83,21.44 70.83,21.65 71.38,22.2 71.38,24.32 PRT5.2 C266.2 71.13,26.02 v1(70.93,26.22) 70.93,26.53 69.44,28.03 68.65,28.03 68.42,27.8 O2C54.2
  IN2 w0.457: v1(65.3,42.86) 64.69,42.25 64.69,35.32 66.49,33.52 66.49,31.68 70.93,27.24 v1(70.93,26.22) ; v1(61.54,21.57) 60.9,22.2 60.9,22.29 56.08,27.11 53.56,27.11 52.98,26.54 49.43,26.54 46.65,29.31 44.02,29.31 43.28,30.05 42.68,30.05 41.33,28.7 41.33,26.9 v1(40.96,26.53)
  BOTTOM w0.203: U24.75 70.92,26.18 70.93,26.19 v1(70.93,26.22)
  BOTTOM w0.254: v2(43.3,26.17) 42.53,26.17 PRT3.2
  BOTTOM w0.457: v1(40.96,26.53) 41.13,26.69 PRT3.2 ; PRT4.2 v1(65.3,42.86)
  BOTTOM w0.508: C265.2 70.3,27.63 70.93,27 v1(70.93,26.22)
EC_AVCC: length 9.4
  TOP w0.457: C266.1 70.29,26.16 v1(69.97,26.48)
  BOTTOM w0.203: U24.74 70.52,25.93 v1(69.97,26.48)
  BOTTOM w0.508: v2(68.6,29.89) 67.63,29.89 67.44,29.7 R209.2 C265.1 69.31,28.38 69.56,28.13 69.56,27.49 69.97,27.09 v1(69.97,26.48)
EC_GPF0: length 2.1
  TOP w0.102: ST83.1 74.14,26.76 v1(74.64,26.25)
  BOTTOM w0.102: U24.85 74.92,25.97 v1(74.64,26.25)
EC_RST#: length 13.8
  TOP w0.102: v1(73.65,7.6) 74.05,8 v2(74.95,8) 74.95,8.31 74.16,9.1 PC2.1 D29.1 D28.1 71.72,7.55 71.1,6.93 R192.2
  BOTTOM w0.102: v1(73.65,7.6) 73.65,7.07 73.44,6.85 SC25.1 72.97,7.73 73.32,8.09 73.83,8.09 74.12,8.38 U24.14
EC_RST#_D: length 2.8
  TOP w0.102: D29.2 69.23,9.46 68.85,9.84 R191.2 v2(68.46,8.82)
EC_SPI_WP#: length 2.6
  BOTTOM w0.102: v2(91.41,21.95) 90.9,21.95 90.85,21.9 R228.2 90.43,21.47 90.39,21.43 U25.3
EC_VCORE: length 5.6
  TOP w0.457: R226.1 75.84,11.49 75.93,11.58 C269.1 ; R226.1 75.44,10.87 v1(75.46,10.85) ; R226.1 C268.1 75.44,12.59 v2(76.27,13.42)
  BOTTOM w0.203: v1(75.46,10.85) 75.42,10.85 74.92,10.36 U24.12
EC_XIN: length 5.6
  BOTTOM w0.102: U24.128 80.13,11.01 79.98,10.85 79.98,8.86 v2(81.03,7.81) 81.15,7.69 R225.1
EC_XOUT: length 3.2
  BOTTOM w0.102: ST84.1 79.32,6.78 79.32,7.64 78.92,8.04 U24.2
ENTRIP1: length 4.7
  TOP w0.102: v2(15.62,34.22) 15.14,34.22 v1(14.91,34.46)
  BOTTOM w0.222: PU3.1 14.94,33.63 15.18,33.87 15.18,34.18 v1(14.91,34.46) 14.9,34.46 14.9,35.67 15.3,36.07 PR36.1
ENTRIP2: length 2.3
  BOTTOM w0.222: PU3.5 15.63,32.03 v2(15.84,31.81) 16.59,31.81 PR39.1
EXT_SCI#: length 96.7
  IN2 w0.102: v1(69.1,8.21) 67.7,9.61 67.43,9.61 66.45,10.59 64.74,10.59 64.1,11.22 59.33,11.22 59.22,11.33 56.02,11.33 55.64,10.95 55.3,10.95 55.3,10.94 49.57,10.94 48.13,9.51 46.72,9.51 46.71,9.5 46.36,9.5 44.77,11.1 36.44,11.1 35.18,12.35 32.63,12.35 31.82,13.17 30.04,13.17 29.43,12.56 28.3,12.56 23.13,17.73 23.13,19.21 22.83,19.52 22.83,28.74 21.49,30.07 21.49,31.59 21.75,31.85 21.75,33.83 20.59,34.98 20.59,35.6 18.54,37.65 18.11,37.65 17.72,38.04 16.57,38.04 14.97,39.64 14.97,47.98 v1(15.38,48.4)
  BOTTOM w0.102: R60293.1 70.07,7.24 v1(69.1,8.21) ; R60306.1 20.26,49.08 19.81,49.53 v2(17,49.53) 16.52,49.53 v1(15.38,48.4)
EXT_SCI#_1P8V: length 135.6
  TOP w0.102: v2(32.07,95.61) 32.07,95.81 v1(31.51,96.36)
  IN2 w0.102: v1(80.1,73.97) 80.28,73.97 81.44,75.13 81.44,83.31 78.55,86.2 78.55,88.61 76.96,90.2 76.96,93.61 73.43,97.14 71.11,97.14 70.49,97.76 62.98,97.76 61.76,96.54 58.32,96.54 57.96,96.91 55.57,96.91 53.68,98.8 51.74,98.8 50.37,100.17 35.32,100.17 v1(31.51,96.36)
  BOTTOM w0.102: v1(31.51,96.36) 31.22,96.07 31.22,95.97 29.72,94.47 29.72,78.6 30.32,78 30.32,73.75 28.91,72.34 28.91,54.05 28.37,53.51 25.3,53.51 24.93,53.88 22.57,53.88 21.96,53.27 MQ31.3 SR671.2 ; v1(80.1,73.97) 79.88,73.75 79.88,72.78 78.15,71.05 78.15,70.72 77.62,70.2 77.62,69.86 XU1.B14
EXT_SCI#_D: length 8
  BOTTOM w0.102: v2(66.72,5.5) 67.01,5.21 69.74,5.21 70.07,5.55 R60293.2 70.36,5.99 70.54,6.17 70.54,7.61 70.79,7.86 70.79,8.38 70.61,8.55 70.6,8.55 70.52,8.64 U24.23
FAN_PWM_R: length 14.4
  TOP w0.254: FR3.2 8.48,16.54 8.05,16.97 8.05,17.62 8.76,18.32 v2(8.76,19.24)
  TOP w0.432: FR3.2 7.82,16.11 v1(7.54,15.83)
  BOTTOM w0.432: v1(7.54,15.83) 7.54,18.54 7.84,18.84 FD3.1 7.39,21.63 7.03,21.27 7.03,20.05 6.72,19.74 P70.2
FDO_EN#: length 92
  TOP w0.102: v1(91.69,24.72) 91,24.04 91,22.88 87.95,19.83 87.95,16.37 89.6,14.72 89.6,11.86 86.93,9.19 86.93,7.29 83.66,4.02 74.16,4.02 E4.2 ; v1(68.43,37.68) 68.52,37.68 68.57,37.63 69.14,37.63 69.39,37.87 69.39,38.71 69.22,38.88 69.22,39.22 69.4,39.4 69.4,41.42 70.06,42.08 70.54,42.08 71.69,43.24 71.69,47.19 70.27,48.61 v1(70.27,49.29)
  BOTTOM w0.102: Q7.3 80.36,29.65 80.13,29.42 79.21,29.42 78,30.64 72.79,30.64 72.28,31.15 71.61,31.15 71.32,31.45 71.32,32.17 71.65,32.5 71.65,34.12 71.14,34.63 71.14,37.33 70.69,37.78 v2(69.92,37.78) 69.48,37.78 69.33,37.63 68.57,37.63 68.52,37.68 v1(68.43,37.68) ; Q7.3 R7.2 ; Q7.3 81.4,30.64 83.66,28.38 91.56,28.38 92.09,27.85 92.09,25.13 v1(91.69,24.72) ; XU1.BC30 69.89,49.67 v1(70.27,49.29)
FDO_EN#_P: length 4.6
  TOP w0.102: v2(72.23,5.83) 72.23,5.14 71.98,4.89 R89.2 71.13,3.53 E4.1
GPIO_RCOMP: length 15.2
  TOP w0.102: SR62.1 v2(78.99,74.69) 76.28,71.98 76.28,71.02 75.79,70.52 75.79,68.84 74.72,67.78 74.72,67.32 72.85,65.45 72.85,64.64 v1(72.22,64.01)
  BOTTOM w0.102: XU1.N26 71.94,64.16 72.1,64.01 v1(72.22,64.01)
GPIO_S0_NC13: length 10.8
  BOTTOM w0.102: R60290.2 66.81,79.17 67.15,78.83 ST5.1 67.78,77.02 67.78,76.57 68.84,75.51 68.84,73.86 69.47,73.23 69.47,72.47 69.94,72 69.94,70.62 XU1.A29
GPIO_S0_NC14: length 11
  BOTTOM w0.102: XU1.C29 70.25,69.58 70.25,69.88 69.74,70.39 69.74,71.72 69.74,71.72 69.74,71.92 69.27,72.38 69.27,73.14 68.64,73.78 68.64,75.36 ST6.1
GPIO_S0_SC[56]: length 12
  TOP w0.102: R60218.1 R60219.2 82.48,42.35 82.48,44.27 81.65,45.09 81.65,46.75 81.37,47.02 v2(81.37,47.58) 80.33,47.58 79.67,48.24 79.67,49.77 79.49,49.95 v1(79.14,49.95)
  BOTTOM w0.102: XU1.BC12 78.89,49.95 v1(79.14,49.95)
GPIO_S0_SC[58]: length 2.1
  TOP w0.102: ST80.1 78.05,48.82 v1(78.05,50.01)
  BOTTOM w0.102: XU1.BC14 77.97,50.01 v1(78.05,50.01)
GPIO_S0_SC[063]: length 13.4
  TOP w0.102: v1(70.34,50.84) 70.34,49.82 70.78,49.38 70.78,48.6 71.14,48.24 71.35,48.24 v2(71.54,48.04) 71.54,47.63 71.89,47.28 71.89,43.15 70.62,41.88 70.16,41.88 69.82,41.54 R60220.1 R60221.2
  BOTTOM w0.102: XU1.BA30 70.05,50.58 70.08,50.58 v1(70.34,50.84)
GPIO_S5[03]: length 10.1
  BOTTOM w0.102: XU1.A17 76.44,70.53 76.44,71.4 76.87,71.83 77.73,71.83 78.55,72.65 v2(78.55,73.72) 78.55,74.54 78.79,74.77 78.79,76.36 78.83,76.41 78.83,77.47 78.81,77.49 78.81,78.08 SR55.2
GPIO_S5[34]: length 10
  BOTTOM w0.102: XU1.K2 83.94,65.51 84.27,65.51 84.44,65.34 84.98,65.34
  BOTTOM w0.127: 84.98,65.34 85.59,65.34 86.86,66.61 SR47.1 SR49.2 90.53,67.93 91.79,67.93 v2(91.91,68.06)
GPIO_S5[35]: length 8.9
  TOP w0.102: v1(88.77,65.93) 88.23,65.4 ST20.1
  BOTTOM w0.102: SR167.1 89.25,65.72 89.04,65.93 v1(88.77,65.93) 88.51,65.93 88.26,65.68 86.39,65.68 85.66,64.95 83.95,64.95 83.66,65.24 83.66,65.35 83.3,65.71 XU1.K3
GPIO_S5[36]: length 7.2
  TOP w0.102: ST81.1 v1(89.45,64.83)
  BOTTOM w0.102: SR170.1 v1(89.45,64.83) 87.64,64.83 87.55,64.74 XU1.M2
GPIO_S5[37]: length 7.2
  BOTTOM w0.102: SR171.1 89.2,63.94 ST30.1 89.07,64.07 85.41,64.07 85,63.66 84.62,63.66 84.35,63.92 83.99,63.92 83.85,64.06 83.56,64.06 XU1.N3
GPIO_S5[41]: length 7.4
  BOTTOM w0.102: SR183.1 88.98,63.05 88.72,63.31 ST22.1 84.53,63.31 84.38,63.45 84.27,63.56 83.95,63.56 83.87,63.48 83.61,63.48 83.32,63.77 XU1.P3
GPIO_S5[42]: length 7.7
  BOTTOM w0.102: XU1.H3 83.23,66.77 85.35,66.77 85.81,67.23 85.81,67.33 86.35,67.87 88.3,67.87 ST23.1 89.16,68.39 SR184.1
GPIO_S5[43]: length 10.3
  TOP w0.102: v1(80.3,74.58) 80.3,74.58 80.54,74.81 80.54,78.41 80.43,78.51 SR185.1
  BOTTOM w0.102: XU1.B12 78.59,71.19 ST24.1 80.69,74.19 v1(80.3,74.58)
GPIO_V1P0_S3: length 16
  TOP w0.254: SL10.1 73.12,42.5 73.91,43.29 73.91,44.61 v2(73.4,45.12) 73.09,45.43 73.09,46.14 73.42,46.48 73.42,48.08 73.74,48.4 73.74,49.75 73.72,49.78 73.72,50.92 74.36,51.57 74.36,52.79 74.06,53.1 74.06,53.24 C47.1 73.61,53.68 v1(72.49,53.68)
  BOTTOM w0.254: XU1.AN25 v1(72.49,53.68)
HD_LED#: length 86.7
  TOP w0.102: R184.1 99.03,17.38 v1(98.9,17.51) ; v1(80.03,51.56) 79.64,51.17 79.64,50.17 80.63,49.18 81.48,49.18 81.91,48.76 81.91,45.2 83.46,43.65 83.46,41.32 SR74.1
  IN2 w0.102: v1(80.03,51.56) 80.45,51.98 82.26,51.98 82.29,52 83.69,52 87.95,47.73 87.95,44.48 92.75,39.68 92.75,27.75 93.66,26.84 93.66,23.41 94.37,22.69 108.36,22.69 109.72,21.33 111.23,21.33 v1(111.3,21.27)
  BOTTOM w0.102: v1(98.9,17.51) 100.25,16.16 106.52,16.16 108.65,18.3 108.65,20.01 109.88,21.24 v2(110.58,21.24) 110.67,21.33 111.23,21.33 v1(111.3,21.27) ; v1(80.03,51.56) 80.03,51.57 80,51.54 79.07,51.54 XU1.AY12
HDA_LPE_RCOMP: length 2.4
  TOP w0.102: v1(74.24,48.62) 74.34,48.73 v2(74.94,48.73) 74.94,48.34 74.86,48.26 SR90.1
  BOTTOM w0.102: XU1.BF20 74.35,48.62 v1(74.24,48.62)
HDMI_CLKN: length 59.7
  IN2 w0.114: v1(82.42,105.06) 82.42,104.69 82.34,104.61 81.97,104.61 81.88,104.52 81.88,104.32 81.16,103.6 81.16,90.92 81.87,90.21 81.87,87.58 84.79,84.66 84.79,79.58 85.09,79.28 85.09,75.77 86.5,74.35 86.5,73.32 87.37,72.46 87.37,67.24 86.92,66.79 86.92,63.34 87.47,62.78 87.47,61.63 86.81,60.97 86.81,60.46 v1(86.96,60.31)
  BOTTOM w0.114: M1C8.1 82.92,105.72 83,105.8 83,106.31 83.06,106.37 84.05,106.37 84.19,106.23 84.19,105.17 ; XU1.AC1 84.39,59.4 84.45,59.46 84.87,59.46 85.29,59.88 86.53,59.88 v1(86.96,60.31) ; v2(83.91,105.17) 84.19,105.17 ; 84.19,105.17 84.19,104.63 83.86,104.3 81.99,104.3 81.88,104.42 81.88,104.7 81.96,104.78 82.14,104.78 v1(82.42,105.06)
HDMI_CLKP: length 59.6
  IN2 w0.114: v1(81.64,105.06) 81.64,104.42 80.92,103.7 80.92,90.82 81.63,90.11 81.63,87.48 84.55,84.56 84.55,79.48 84.85,79.18 84.85,75.67 86.26,74.25 86.26,73.22 87.13,72.36 87.13,67.34 86.68,66.89 86.68,63.24 87.23,62.68 87.23,61.73 86.57,61.07 86.57,60.6 v1(86.3,60.33)
  BOTTOM w0.114: v1(86.3,60.33) 86.09,60.12 85.19,60.12 84.77,59.7 83.97,59.7 83.84,59.57 83.54,59.57 XU1.AC3 ; 83.58,106.61 M1C7.1 ; 83.58,106.61 84.15,106.61 84.43,106.33 84.43,104.53 83.96,104.06 81.89,104.06 81.64,104.32 v1(81.64,105.06) ; 83.58,106.61 v2(83.58,106.89)
HDMI_DDC_CLK_LS: length 25.5
  TOP w0.254: J137.15 72.15,105.56 72.15,103.11 75.43,99.83 MD3.1 75.94,98.04 76.04,98.14 M1C10.1 76.8,98.14 77.18,97.76 77.18,96.24 MR19.2 v2(75.79,95.86) 75.51,95.58 75.51,94.21 75.04,93.74 75.04,93.27 75.37,92.94 78.36,92.94 78.94,93.51 78.94,94.01 79.44,94.51 80.78,94.51 81.01,94.28 MQ37.3
HDMI_DDC_DATA_LS: length 16.9
  TOP w0.102: MQ37.6 79.71,96.32 79.57,96.45 78.96,96.45 78.36,95.86 MR18.2 77.46,96.34 77.46,97.56 MD2.1 78.4,98.04 78.5,98.14 M1C9.1 79.09,98.59 v2(79.65,99.15) 79.65,100.57 75.74,104.48 75.19,104.48 J137.16
HDMI_DDC_SCL: length 46
  TOP w0.102: v1(70.38,66.81) 70.22,66.81 68.99,68.04 68.99,70.61 68.86,70.74 68.86,71.53 68.09,72.3 68.09,83.07 67.65,83.51 67.65,84.39 68.14,84.89 68.14,86.91 68.42,87.19 68.42,87.65 69.38,88.6 70.47,88.6 72.35,90.48 v2(74.24,90.48) 74.39,90.33 80.41,90.33 82.17,92.1 82.17,93.78 81.83,94.12 81.83,96.47 MR14.2 80.99,96.65 81.01,96.63 MQ37.4
  BOTTOM w0.102: v1(70.38,66.81) 70.22,66.81 XU1.G30
HDMI_DDC_SDA: length 46.1
  TOP w0.254: v1(75.02,91.75) 75.6,91.18 78.62,91.18 78.94,91.5 78.94,91.9 MR15.2 79.8,93.13 79.71,93.22 MQ37.1
  IN2 w0.254: v1(68.42,63.97) 68.22,63.97 67.78,64.4 67.78,64.91 68.42,65.54 68.42,69.48 67.81,70.09 67.81,75.88 65.32,78.37 65.32,86.6 68.17,89.44 72.71,89.44 v1(75.02,91.75)
  BOTTOM w0.102: v2(74.11,91.32) 74.59,91.32 v1(75.02,91.75)
  BOTTOM w0.203: XU1.P30 69.51,63.97 69.02,63.97 69.01,63.98 68.71,63.98 68.7,63.97 v1(68.42,63.97)
HDMI_HPD#: length 42
  TOP w0.102: v1(73.14,92.08) 72.59,91.53 72.59,91.1 70.29,88.81 69.29,88.81 68.22,87.73 68.22,87.27 67.94,87 67.94,84.97 67.44,84.48 67.44,83.43 67.81,83.06 67.81,72.29 68.66,71.44 68.66,70.66 68.79,70.53 68.79,67.96 69.82,66.93 69.82,65.83 v1(70.36,65.29)
  BOTTOM w0.102: XU1.K30 70.32,65.29 v1(70.36,65.29) ; v1(73.14,92.08) 74.36,93.3 74.36,94.37 74.73,94.74 SR3.2 73.35,95.18 72.9,95.63 72.34,95.63 72.14,95.44 MQ1.3 69.61,95.44 v2(68.72,94.55)
HDMI_HPDET: length 11.8
  BOTTOM w0.102: v2(70.45,97.7) 70.45,96.66 71.26,95.84 71.97,95.84 MQ1.1 72.51,96.95 SR4.1 73.03,98.08 73.06,98.1 MD1.1 73.06,99.21 72.66,99.6 72.66,102.39 72.92,102.65 72.92,103.52 J137.19
HDMI_POWER: length 7.3
  BOTTOM w0.102: VF1.1 74.9,100.61 MCB1.1 74.06,100.9 73.7,100.54 v2(73.22,100.54) 73.22,101.28 73.92,101.98 J137.18
HDMI_RT: length 26.8
  TOP w0.102: v1(79.44,114.87) v1(79.44,117.28) v1(79.44,118.93) ; v1(79.44,109.15) v1(79.44,106.87) 80.07,106.24 v1(80.07,104.78)
  BOTTOM w0.102: MR11.2 MR6.2 v1(79.44,117.28) ; v1(80.07,104.78) MR13.2 79.52,105.47 79.37,105.32 v2(79.37,102.52) MQ36.3 ; MR9.2 MR12.2 v1(79.44,106.87) ; v1(79.44,114.87) MR10.2 80.07,113.86 80.81,113.12 80.81,110.24 80.07,109.5 MR8.2 v1(79.44,109.15) ; MR7.2 79.81,118.93 v1(79.44,118.93)
HDMI_TMDS_CLK_N: length 15.1
  BOTTOM w0.114: 76.67,111.26 77.32,111.26 77.6,110.98 77.6,107.59 79.22,105.97 80.77,105.97 80.9,105.84 MR13.1 81.16,105.72 M1C8.2 ; 76.67,111.26 76.15,111.26 75.77,110.88 75.77,109.18 75.25,108.66 74.52,108.66 J137.12 ; 76.67,111.26 v2(76.67,110.98)
HDMI_TMDS_CLK_P: length 15.1
  BOTTOM w0.114: 77.84,109.97 77.84,107.69 79.32,106.21 80.71,106.21 80.9,106.4 MR12.1 81.16,106.61 M1C7.2 ; 77.84,109.97 v2(78.12,109.97) ; 77.84,109.97 77.84,111.08 77.42,111.5 76.05,111.5 75.53,110.98 75.53,109.28 75.15,108.9 74.24,108.9 J137.10
HDMI_TMDS_DATA0_N: length 25.6
  BOTTOM w0.114: 78.88,118.14 80.76,118.14 80.9,118.28 MR7.1 81.16,118.42 M1C2.2 ; 78.88,118.14 78.45,118.14 77.54,119.06 71.08,119.06 68.83,116.81 68.83,110.72 69.76,109.79 J137.9 ; 78.88,118.14 v2(78.88,118.42)
HDMI_TMDS_DATA0_P: length 25.5
  BOTTOM w0.114: 69.39,117.03 69.07,116.71 69.07,110.82 69.86,110.04 72.15,110.04 72.36,110.25 72.36,110.73 72.58,110.95 J137.7 ; 69.39,117.03 71.18,118.82 77.44,118.82 78.35,117.9 80.75,117.9 80.9,117.74 MR6.1 81.16,117.53 M1C1.2 ; 69.39,117.03 v2(69.59,116.82)
HDMI_TMDS_DATA1_N: length 14.8
  BOTTOM w0.114: 79.41,112.45 79.93,111.94 79.93,110.87 78.57,109.51 78.57,108.8 79.08,108.28 80.69,108.28 80.9,108.07 MR9.1 81.16,108.01 M1C4.2 ; 79.41,112.45 v2(79.21,112.25) ; 79.41,112.45 79.05,112.81 76.23,112.81 75.48,112.06 74.45,112.06 J137.6
HDMI_TMDS_DATA1_P: length 14.8
  BOTTOM w0.114: J137.4 74.3,112.3 75.38,112.3 76.13,113.05 79.15,113.05 80.17,112.04 80.17,110.77 79.77,110.37 ; 79.77,110.37 78.81,109.41 78.81,108.9 79.18,108.52 80.74,108.52 80.9,108.69 MR8.1 81.16,108.9 M1C3.2 ; 79.77,110.37 v2(79.98,110.17)
HDMI_TMDS_DATA2_N: length 18.9
  BOTTOM w0.114: 71.18,117.67 71.7,118.18 76.87,118.18 79.32,115.73 80.76,115.73 80.9,115.87 MR11.1 81.16,116.01 M1C6.2 ; 71.18,117.67 v2(70.99,117.87) ; 71.18,117.67 70.43,116.92 70.43,114.76 71.93,113.26 J137.3
HDMI_TMDS_DATA2_P: length 18.9
  BOTTOM w0.114: J137.1 72.62,114.41 72.41,114.21 72.41,113.67 72.24,113.5 72.03,113.5 70.67,114.86 70.67,116.82 71.8,117.94 73.5,117.94 ; 73.5,117.94 v2(73.5,117.66) ; 73.5,117.94 76.77,117.94 79.22,115.49 80.75,115.49 80.9,115.33 MR10.1 81.16,115.12 M1C5.2
HDMI_TXN0: length 70.9
  IN2 w0.114: v1(83.46,118.27) 83.06,117.87 83.06,117.46 83.19,117.32 83.24,117.28 83.24,116.92 81.88,115.56 81.88,110.95 82.92,109.9 82.92,107.36 83.57,106.72 83.57,105.01 81.65,103.09 81.65,92.44 82.52,91.57 82.52,87.63 85.29,84.86 85.29,79.8 86.29,78.8 86.29,75.35 87.03,74.61 87.03,74 87.39,73.64 87.39,73.31 87.93,72.77 87.93,67.05 87.42,66.54 87.42,64.11 88.45,63.07 88.45,61.89 87.46,60.89 87.46,59.56 86.67,58.77 86.25,58.77 86.12,58.9 86.12,59.22 v1(86.3,59.4)
  BOTTOM w0.114: v1(83.46,118.27) 83.27,118.08 82.89,118.08 82.89,118.09 M1C2.1 ; v1(86.3,59.4) 85.78,58.87 83.77,58.87 XU1.AD2
HDMI_TXN1: length 63
  IN2 w0.114: v1(88.16,58.48) 88.16,58.77 88.8,59.4 88.8,59.75 89.46,60.41 89.46,63.76 89.03,64.2 89.03,65.21 89.46,65.64 89.46,72.69 88.37,73.79 88.37,74.05 88.04,74.37 88.04,75.51 87.38,76.17 87.38,79.14 86.26,80.26 86.26,85.27 83.5,88.03 83.5,91.97 82.63,92.84 82.63,102.66 84.65,104.68 84.65,107.17 84.28,107.54 84.28,108.79 v1(84.57,109.08)
  BOTTOM w0.102: 85.99,58.48 85.61,58.1 84.1,58.1 83.94,57.94 XU1.AF2
  BOTTOM w0.114: 85.99,58.48 86.42,58.91 87.73,58.91 v1(88.16,58.48) ; v1(84.57,109.08) 84.3,108.8 84.3,108.59 84.04,108.33 82.88,108.33 M1C4.1
HDMI_TXN2: length 71.8
  IN2 w0.114: v1(83.66,115.88) 83.23,115.46 83.23,115.11 82.86,114.74 82.86,111.65 85.29,109.23 85.29,104.54 83.13,102.38 83.13,94.26 84,93.39 84,88.24 87.34,84.89 87.34,79.91 89.96,77.3 89.96,58.41 88.69,57.15 87.16,57.15 87.03,57.28 87.03,57.41 87.22,57.59 87.22,57.64 87.35,57.77 v1(87.43,57.77)
  BOTTOM w0.102: 86.62,58.19 86.13,57.7 84.53,57.7 84.29,57.45 XU1.AG1
  BOTTOM w0.114: v1(83.66,115.88) 83.58,115.81 82.76,115.81 M1C6.1 ; v1(87.43,57.77) 87.01,58.19 86.62,58.19
HDMI_TXP0: length 70.9
  IN2 w0.114: v1(85.65,59.38) 85.88,59.15 85.88,58.8 86.15,58.53 86.77,58.53 87.7,59.46 87.7,60.79 88.7,61.79 88.7,63.17 87.66,64.21 87.66,66.44 88.17,66.95 88.17,72.87 87.63,73.41 87.63,73.74 87.27,74.1 87.27,74.71 86.53,75.45 86.53,78.9 85.53,79.9 85.53,84.96 82.77,87.73 82.77,91.67 81.89,92.54 81.89,102.99 83.81,104.91 83.81,106.82 83.16,107.46 83.16,110 82.12,111.05 82.12,115.46 83.48,116.82 v1(83.48,117.64)
  BOTTOM w0.114: M1C1.1 82.86,117.84 83.28,117.84 v1(83.48,117.64) ; XU1.AD3 83.07,58.96 83.36,58.96 83.57,59.18 83.64,59.21 83.85,59.21 83.95,59.11 85.39,59.11 v1(85.65,59.38)
HDMI_TXP1: length 63
  IN2 w0.114: v1(87.53,58.48) 88.56,59.5 88.56,59.85 89.22,60.51 89.22,63.66 88.78,64.1 88.78,65.31 89.22,65.74 89.22,72.59 88.12,73.69 88.12,73.95 87.8,74.27 87.8,75.41 87.14,76.07 87.14,79.04 86.02,80.16 86.02,85.17 83.26,87.93 83.26,91.87 82.39,92.74 82.39,102.76 84.41,104.78 84.41,107.07 84.04,107.44 84.04,108.82 v1(83.79,109.08)
  BOTTOM w0.102: 86.33,58.48 85.75,57.9 84.19,57.9 84.02,57.74 83.96,57.74 83.81,57.59 83.65,57.59 83.29,57.95 XU1.AF3
  BOTTOM w0.114: 86.33,58.48 86.52,58.67 87.33,58.67 v1(87.53,58.48) ; v1(83.79,109.08) 84.06,108.8 84.06,108.69 83.94,108.58 82.88,108.58 M1C3.1
HDMI_TXP2: length 71.8
  IN2 w0.114: v1(86.79,57.77) 86.79,57.18 87.06,56.91 88.79,56.91 90.2,58.31 90.2,77.4 87.58,80.01 87.58,84.99 84.24,88.34 84.24,93.49 83.37,94.36 83.37,102.28 85.53,104.44 85.53,109.33 83.1,111.75 83.1,114.64 v1(83.66,115.2)
  BOTTOM w0.102: XU1.AG3 83.51,57.31 83.82,57.31 83.95,57.17 84.29,57.17 84.61,57.49 86.21,57.49 86.49,57.77 v1(86.79,57.77)
  BOTTOM w0.114: v1(83.66,115.2) 83.29,115.57 83,115.57 M1C5.1
HOLD#: length 2.8
  TOP w0.102: v2(82.11,77.02) 82.11,76.54 82.17,76.48 F3R3.2 F3U1.7
HPOUT1_JD: length 23.1
  TOP w0.254: v1(9.34,107.45) 10.03,106.77 AR3.2
  BOTTOM w0.254: J27.4 22.1,114.85 17.54,110.29 v2(17.54,108.95) 17.09,108.95 16.45,109.58 11.68,109.58 11.35,109.25 9.97,109.25 9.34,108.62 v1(9.34,107.45)
HPOUT1_L: length 8.9
  TOP w0.229: AU1.26 13.58,103.45 13.82,103.69 14.94,103.69 15.54,104.29 15.54,105.5 15.18,105.85 15.18,106.42 15.54,106.77 15.54,107.52 15.45,107.61 15.45,108.48 v2(14.98,108.95) 14.31,108.95 HR1.1
HPOUT1_R: length 6.7
  TOP w0.229: AU1.27 13.18,103.52 13.68,104.02 14.8,104.02 15.21,104.43 15.21,105.32 14.85,105.67 14.85,106.56 14.98,106.68 v2(14.98,107.1) 14.52,107.1 14.42,106.99 HR2.1
HUB_RESET: length 3.9
  BOTTOM w0.254: 65.88,84.35 v2(65.88,84.39) ; 65.88,84.35 65.87,84.36 UU3.17 ; 65.88,84.35 DEC4.1 R21.2 R18.1
ICLK_DRAM_TERMN1: length 37.1
  IN1 w0.102: v1(64.03,57.54) 64.55,57.03 64.55,56.16 62.5,54.11 62.5,50.96 61.82,50.28 61.82,48.45 59.89,46.52 59.89,43.22 56.61,39.94 56.61,38.72 55.88,38 53.73,38 v1(52.65,39.07)
  BOTTOM w0.102: SR7.1 46.19,34.12 46.35,34.27 v2(46.68,34.27) 47.52,34.27 52.32,39.07 v1(52.65,39.07)
  BOTTOM w0.254: XU1.AF42 64.03,57.6 v1(64.03,57.54)
ICLK_DRAM_TERMN2: length 36
  IN1 w0.203: v1(52.65,39.71) 52.7,39.66 52.8,39.66 53.88,38.58 54.97,38.58 55.25,38.85 55.25,38.94 59.59,43.28 59.59,44.66 59.59,48.76 60.48,49.65 60.48,52.6 62.7,54.83 62.7,55.87 v1(63.3,56.46)
  BOTTOM w0.254: XU1.AH42 63.68,56.84 v1(63.3,56.46) ; v1(52.65,39.71) 52.6,39.66 52.46,39.66 47.66,34.86 45.64,34.86 v2(44.92,34.15) 44.92,33.79 45.18,33.54 SR8.1
ICLK_ICOMP: length 15.6
  TOP w0.127: v1(88.13,59.8) 88.74,59.8 v2(88.97,60.03)
  IN1 w0.127: v1(88.13,59.8) 88.07,59.85 85.5,59.85 84.44,58.79 77.61,58.79 v1(77.1,59.3)
  BOTTOM w0.127: v1(88.13,59.8) 88.67,59.8 89.35,59.11 89.72,59.11 SR32.2 ; v1(77.1,59.3) 77.1,59.29 XU1.AD14
ICLK_OSCIN: length 14.8
  TOP w0.127: v1(79.24,56.45) 79.24,56.47 79.83,57.06 81.22,57.06 v2(81.58,57.41) 81.93,57.06 83.55,57.06 84.36,57.87 86.08,57.87 86.79,57.16 88.82,57.16 89.49,56.49 SR30.2 90.14,56.91 90.1,56.94 SR31.1 SC3.1
  BOTTOM w0.127: v1(79.24,56.45) 79.24,56.66 XU1.AH12
ICLK_OSCOUT: length 16.6
  TOP w0.127: v1(79.96,56.47) 80.57,55.86 83.08,55.86 84.57,57.36 v2(85.29,57.36) 85.87,57.36 86.58,56.65 88.61,56.65 89.28,55.98 89.81,55.98 SR30.1 SC1.1 91.96,54.84 Y12.3
  BOTTOM w0.127: XU1.AH10 79.96,56.65 v1(79.96,56.47)
ICLK_RCOMP: length 15.1
  TOP w0.127: v1(88.12,60.43) 87.34,59.65 v2(87.24,59.65)
  IN1 w0.127: v1(77.86,59.3) 77.86,59.33 78.45,59.93 84.85,59.93 85.69,60.77 87.12,60.77 87.22,60.66 87.9,60.66 v1(88.12,60.43)
  BOTTOM w0.127: XU1.AD13 78.21,58.95 v1(77.86,59.3) ; v1(88.12,60.43) 88.75,60.43 89.56,59.62 SR33.2
ICLK_SATA_TERMN: length 9.5
  TOP w0.102: v1(79.16,49.3) 79.47,48.99 79.47,48.16 80.54,47.09 v2(80.54,45.98) 80.54,45.45 81.3,44.69 81.3,42.36 SR79.2
  BOTTOM w0.102: v1(79.16,49.3) 79.25,49.3 XU1.BC10
ICLK_SATA_TERMP: length 9.8
  TOP w0.102: v1(80.06,50.51) 80.5,50.07 82.29,50.07 82.54,49.82 82.93,49.82 83.18,49.58 83.18,46.64 v2(83.43,46.39) 83.74,46.08 84.59,46.08 SR80.2
  BOTTOM w0.102: v1(80.06,50.51) 79.86,50.51 XU1.BB10
ICLK_USB_TERMN1: length 5.7
  TOP w0.114: SR96.1 82.14,71.09 81.45,71.09 ; 81.45,71.09 v2(81.45,71.36) ; 81.45,71.09 80.79,71.09 80.34,70.64 80.34,68.7 v1(80.15,68.51)
  BOTTOM w0.114: v1(80.15,68.51) 79.88,68.23 79.7,68.23 79.61,68.32 XU1.D10
ICLK_USB_TERMN2: length 5.8
  TOP w0.114: SR97.1 81.92,70.85 80.89,70.85 80.58,70.54 80.58,69.74 ; v1(80.15,67.85) 80.58,68.28 80.58,69.74 ; 80.58,69.74 v2(80.85,69.74)
  BOTTOM w0.114: v1(80.15,67.85) 80.12,67.88 XU1.F10
ICLK_V1P35_S3: length 8
  TOP w0.457: v1(76.23,56.85) 76.6,56.85 77.49,57.74 v2(77.49,58.45) 77.06,58.45 76.42,59.09 C63.1 C62.1 75.27,59.31 74.79,59.78 SL14.1
  BOTTOM w0.305: XU1.AJ19 75.48,56.85 75.48,56.88 XU1.AG18 75.85,57.23 v1(76.23,56.85)
ILIM: length 5.9
  TOP w0.102: PU2.3 v1(97.5,105.34) 97.12,105.72 PR22.1 97.54,106.61 97.54,107.71 97.29,107.96 96.68,107.96 PR17.2
  BOTTOM w0.102: v1(97.5,105.34) 97.93,104.91 v2(98.11,104.91)
INTRUDER#: length 151.6
  TOP w0.102: v1(75.63,75.54) 75.37,75.54 75.02,75.88 R250.1 ; v1(111.77,21.69) 110.09,21.69 108.04,19.64 v1(108.04,19.34) ; E69.1 61.51,3.51 63.39,5.39 C149.1 66.1,6.22 66.47,6.59 67.96,6.59 68.37,6.18 69.77,6.18 69.87,6.08 69.87,5.86 69.96,5.76 71.46,5.76 72.03,6.33 v2(74.16,6.33) 74.36,6.54 v1(74.36,7.55)
  IN2 w0.102: v1(108.04,19.34) 107.79,19.08 107.79,18.44 102.49,13.14 96.79,13.14 95.46,11.81 93.99,11.81 93.42,12.38 91.43,12.38 90.63,13.18 85.2,13.18 82.38,10.36 79.33,7.31 74.64,7.31 74.4,7.55 v1(74.36,7.55) ; v1(75.63,75.54) 76.06,75.11 76.06,73.65 77.89,71.81 77.89,70.5 77.56,70.17 77.56,65.21 77.94,64.83 78.83,64.83 79.1,64.57 79.1,64.08 78.75,63.73 77.76,63.73 76.79,62.76 76.06,62.76 75.61,62.31 75.61,61.83 75.05,61.28 75.05,60.59 78.67,56.98 80.04,56.98 80.38,56.65 80.38,55.67 80,55.29 80,53.8 79.65,53.44 79.65,52.46 79.92,52.18 82.18,52.18 82.2,52.2 83.77,52.2 88.16,47.82 88.16,44.56 92.95,39.77 92.95,27.83 93.86,26.92 93.86,23.49 94.46,22.89 108.5,22.89 109.71,21.69 v1(111.77,21.69)
INTRUDER#_S: length 16.9
  TOP w0.102: SR196.2 v1(75.02,77.83) R250.2 ; v2(73.5,65.31) 73.5,65.41 v1(74.24,66.14)
  IN1 w0.102: v1(74.24,66.14) 74.54,66.45 74.54,67.14 75.19,67.79 75.19,70.2 75.83,70.85 75.83,72.98 76.05,73.2 76.05,76.81 v1(75.02,77.83)
  BOTTOM w0.102: XU1.J24 73.07,66.14 v1(74.24,66.14)
JDREF: length 2.8
  TOP w0.229: AU1.35 9.98,104.17 v2(9.82,104.33)
  TOP w0.254: AR38.1 9.82,104.62 v2(9.82,104.33)
KSI0: length 9.9
  BOTTOM w0.102: J134.8 58.69,19.83 59.12,20.26 59.12,21.17 60.19,22.23 61.5,22.23 62.27,21.47 62.82,21.47 62.86,21.51 v2(63.29,21.51) 63.56,21.51 64.07,21.01 U24.58
KSI1: length 10.2
  BOTTOM w0.102: J134.7 57.98,20.33 60.57,22.92 v2(61.64,22.92) 62.15,22.41 62.15,21.92 62.39,21.67 62.74,21.67 63.22,22.16 63.62,22.16 64.37,21.4 U24.59
KSI2: length 11
  TOP w0.102: v1(62.96,22.59) 63.24,22.87 v2(63.24,23.8)
  BOTTOM w0.102: J134.6 57.97,20.83 60.47,23.33 61.13,23.33 61.25,23.45 62.1,23.45 v1(62.96,22.59) 63.57,22.59 64.35,21.8 U24.60
KSI3: length 9.7
  BOTTOM w0.102: J134.5 58.12,21.33 60.32,23.53 60.85,23.53 61.23,23.91 62.79,23.91 v2(63.4,23.3) 63.7,23.01 63.7,22.82 64.31,22.2 U24.61
KSI4: length 11.2
  BOTTOM w0.102: J134.4 58.21,21.83 60.11,23.73 60.72,23.73 61.13,24.14 62.15,24.14 63.06,25.05 v2(63.61,25.05) 63.61,23.97 63.9,23.68 63.9,23.05 64.34,22.6 U24.62
KSI5: length 12.1
  BOTTOM w0.102: J134.3 58.35,22.33 59.99,23.96 60.57,23.96 60.95,24.34 61.36,24.34 61.61,24.6 v2(61.61,25.16) 62.43,25.16 63.11,25.84 63.68,25.84 64.1,25.42 64.1,23.25 64.35,23.01 U24.63
KSI6: length 12.9
  BOTTOM w0.102: U24.64 64.38,23.4 64.31,23.48 64.31,25.51 63.51,26.3 62.59,26.3 v2(61.95,26.94) 61.12,26.1 61.12,24.86 60.55,24.29 60.53,24.29 60.45,24.22 59.87,24.22 58.48,22.83 J134.2
KSI7: length 14.7
  BOTTOM w0.102: J134.1 58.57,23.33 59.66,24.42 60.37,24.42 60.91,24.96 60.91,26.6 61.86,27.54 63.34,27.54 63.58,27.3 63.58,26.99 v2(63.79,26.78) 64.37,26.2 64.37,25.73 65.3,24.8 65.78,24.8 66.28,24.3 66.75,24.3 66.92,24.47 U24.65
KSO0: length 11.4
  TOP w0.102: v2(59.45,12.53) 60.39,12.53 61.01,11.91 v1(61.13,11.91)
  BOTTOM w0.102: U24.36 64.38,12.2 64.23,12.06 63.41,12.06 63.12,12.35 63.12,12.52 62.92,12.72 62.44,12.72 62.09,12.37 61.58,12.37 v1(61.13,11.91) 60.64,12.4 59.66,12.4 58.3,11.05 58.14,11.05 57.91,10.83 J134.26
KSO1: length 8.7
  BOTTOM w0.102: J134.25 58.12,11.33 59.4,12.61 62.04,12.61 62.36,12.93 63.25,12.93 v2(63.62,12.55) 64.18,12.55 64.23,12.61 U24.37
KSO2: length 13.7
  BOTTOM w0.102: v2(53.54,14.49) 53.54,14.06 54.07,13.52 55.26,13.52 56.96,11.83 J134.24 58.26,11.83 59.25,12.81 61.96,12.81 62.27,13.13 63.75,13.13 63.87,13.01 U24.38
KSO3: length 11.4
  BOTTOM w0.102: U24.39 62.26,13.4 61.87,13.01 58.97,13.01 58.29,12.33 J134.23 56.74,12.33 55.29,13.78 v2(55.29,14.13)
KSO4: length 12.8
  BOTTOM w0.102: U24.40 64.25,13.8 64.05,13.61 62.18,13.61 61.84,13.27 58.77,13.27 58.33,12.83 J134.22 56.53,12.83 55.8,13.56 55.8,14.92 v2(54.88,15.83)
KSO5: length 8.2
  BOTTOM w0.102: U24.41 63.09,14.2 v2(63.08,14.21) 62.49,14.21 61.77,13.5 58.59,13.5 58.42,13.33 J134.21
KSO6: length 10.4
  TOP w0.102: v1(62.88,15.14) 61.26,15.14 v2(61.13,15.27)
  BOTTOM w0.102: J134.20 60.92,13.83 61.46,14.37 62.11,14.37 v1(62.88,15.14) 63.12,14.91 63.12,14.87 63.38,14.61 U24.42
KSO7: length 8.6
  BOTTOM w0.102: U24.43 64.55,15.01 64.08,15.48 63.16,15.48 63.05,15.59 62.11,15.59 v2(61.38,14.86) 60.84,14.33 J134.19
KSO8: length 9.1
  BOTTOM w0.102: U24.44 64.45,15.4 64.18,15.68 63.25,15.68 62.33,16.6 v2(61.36,16.6) 59.59,14.83 J134.18
KSO9: length 9.4
  BOTTOM w0.102: U24.45 64.44,15.8 64.05,16.19 v2(63.6,16.19) 62.48,17.31 62.08,17.31 61.92,17.14 61.57,17.14 61.4,17.31 60.95,17.31 58.97,15.33 J134.17
KSO10: length 9.5
  BOTTOM w0.102: J134.16 59.12,15.83 61.29,18 62.45,18 v2(62.7,17.75) 63.76,16.7 63.97,16.7 64.47,16.2 U24.46
KSO11: length 10.3
  TOP w0.102: v2(60.42,18.17) 60.01,17.76 59.99,17.76 v1(59.71,17.48)
  BOTTOM w0.102: U24.51 63.2,18.2 62.78,18.63 62.04,18.63 61.61,18.2 61.04,18.2 60.32,17.48 v1(59.71,17.48) 59.71,16.87 59.16,16.33 J134.15
KSO12: length 8.8
  BOTTOM w0.102: U24.52 63.49,18.6 63.21,18.88 v2(61.38,18.88) 60.85,18.35 59.81,18.35 58.29,16.83 J134.14
KSO13: length 9.1
  BOTTOM w0.102: J134.13 58.38,17.33 59.78,18.73 60.31,18.73 61.3,19.72 62.44,19.72 62.62,19.54 63.31,19.54 v2(63.6,19.25) 63.85,19.01 U24.53
KSO14: length 8.9
  BOTTOM w0.102: J134.12 58.6,17.83 59.7,18.93 60.22,18.93 61.21,19.92 62.53,19.92 62.7,19.74 63.89,19.74 64.23,19.4 U24.54
KSO15: length 10
  TOP w0.102: v2(61.46,20.1) 62.1,20.1 v1(62.37,20.38)
  BOTTOM w0.102: J134.11 58.7,18.33 59.5,19.14 60.14,19.14 61.16,20.15 62.15,20.15 v1(62.37,20.38) 62.79,19.96 64.12,19.96 64.28,19.8 U24.55
KSO16: length 8.9
  BOTTOM w0.102: J134.10 58.44,18.83 60,20.39 61.1,20.39 v2(61.36,20.65) 61.5,20.8 63.38,20.8 63.97,20.2 U24.56
KSO17: length 10.5
  TOP w0.102: v1(60.39,21.57) 60.62,21.8 v2(60.62,22.31)
  BOTTOM w0.102: U24.57 64.03,20.6 63.62,21.01 63.08,21.01 62.95,21.15 60.81,21.15 v1(60.39,21.57) 59.9,21.57 59.45,21.12 59.45,20.3 58.48,19.33 J134.9
LAD0: length 55.6
  TOP w0.127: v1(84.67,27.27) 85.35,27.94 88.17,27.94 88.59,27.52 88.59,26.96 89.58,25.97 89.58,25.54 89.04,25 89.04,21.67 v2(88.41,21.03) 86.95,21.03 86.66,20.73 86.66,19.64 85.15,18.14 85.15,16.5 83.47,14.82 83.47,10.06 81.77,8.35 P12.2 80.27,8.35 79.93,8.7 76.57,8.7 76.09,8.21 v1(75.79,8.21)
  IN2 w0.127: v1(75.23,38.97) 75.38,38.82 78.54,38.82 83.9,33.45 83.9,28.8 84.67,28.03 v1(84.67,27.27)
  BOTTOM w0.127: v1(75.79,8.21) 75.72,8.28 U24.10 ; SR100.2 75.66,39.5 75.23,39.07 v1(75.23,38.97) ; TPU1.26 84.42,27.01 v1(84.67,27.27)
LAD1: length 56.3
  TOP w0.127: v1(76.09,10.88) 77.62,9.35 P12.4 81.8,9.35 83.09,10.64 83.09,14.79 84.9,16.6 84.9,18.29 86.4,19.8 86.4,20.84 86.85,21.29 87.61,21.29 88.79,22.46 88.79,26.02 v2(88.51,26.3) 88.33,26.48 88.33,27.42 88.07,27.68 85.7,27.68 v1(85.31,27.29)
  IN2 w0.127: v1(73.96,38.98) 74.39,38.54 74.4,38.54 74.65,38.29 78.35,38.29 82.58,34.06 82.58,27.81 83.71,26.68 84.7,26.68 v1(85.31,27.29)
  BOTTOM w0.127: SR101.2 73.88,39.05 v1(73.96,38.98) ; v1(85.31,27.29) 85.59,27.01 85.97,27.01 86.05,27.01 86.37,26.69 TPU1.23 ; U24.9 76.12,10.85 v1(76.09,10.88)
LAD2: length 46.7
  TOP w0.127: v1(76.72,10.88) 77.42,10.18 79.96,10.18 80.12,10.35 P12.6 81.86,10.35 82.83,11.32 82.83,14.9 84.64,16.71 84.64,18.92 v2(85.07,19.35) 85.68,19.96 85.68,20.47 86.74,21.54 87.03,21.54 87.75,22.26 87.75,24.22 88.32,24.78 v1(88.32,24.82)
  IN2 w0.127: v1(81.09,39.48) 81.09,37.7 86.79,32 86.79,28.33 87.44,27.67 87.44,25.7 v1(88.32,24.82)
  BOTTOM w0.127: SR103.2 79.88,41.39 79.65,41.16 79.66,41.14 79.66,40.26 79.81,40.1 80.47,40.1 v1(81.09,39.48) ; TPU1.20 v1(88.32,24.82) ; v1(76.72,10.88) 76.52,10.67 U24.8
LAD3: length 49.8
  TOP w0.127: v1(87.9,27.24) 87.5,26.83 87.5,25.1 v2(87.11,24.72) 87.11,23.96 87.5,23.58 87.5,22.36 86.93,21.79 86.64,21.79 84.39,19.54 84.39,16.81 82.58,15 82.58,11.68 82.25,11.35 P12.8 80.77,11.35 79.85,10.44 77.83,10.44 v1(77.41,10.85)
  IN2 w0.127: v1(87.9,27.24) 87.9,27.57 87.05,28.43 87.05,32.11 83.15,36 83.15,37.54 v1(82.52,38.18)
  BOTTOM w0.127: v1(77.41,10.85) 76.92,10.36 U24.7 ; TPU1.17 90.27,26.98 90.09,27.16 90.09,27.8 89.74,28.14 88.05,28.14 87.9,27.99 v1(87.9,27.24) ; SR102.2 78.42,39.17 79.03,38.56 79.41,38.18 v1(82.52,38.18)
LAN_ACT#_R: length 15.8
  BOTTOM w0.102: J8.11 30.29,116.68 30.29,112.63 27.73,110.07 v2(27.73,107.63) 28.44,107.63 28.77,107.3 28.77,106.04 LANC1.1 LR62.1
LAN_ACTLED3#: length 42.3
  TOP w0.508: v1(28.97,103.91) 31.02,101.86 34.27,101.86 37.13,99.01 41.4,99.01 v2(42.07,98.34) 46.4,94.01 46.4,91.68 46.19,91.48 46.19,89.85 46.88,89.16 54.6,89.16 55.85,90.41 v1(55.85,91.5)
  BOTTOM w0.229: LU1.25 54.33,94.16 54.44,94.04 54.68,94.04
  BOTTOM w0.457: LR62.2 v1(28.97,103.91)
  BOTTOM w0.508: 54.68,94.04 55.97,92.74 55.97,91.63 v1(55.85,91.5)
LAN_CLKREQ: length 4.2
  BOTTOM w0.102: v2(54.55,101.99) 54.31,101.99 R93.1 52.8,100.48 52.8,99.22 52.73,99.15 LU1.12
LAN_HSON: length 3.8
  BOTTOM w0.114: C162.1 57.07,99.39 56.91,99.39 56.3,98.78 56.3,98.27 55.87,97.83 LU1.18
LAN_HSOP: length 3.7
  BOTTOM w0.114: LU1.17 55.12,98.23 55.28,98.08 55.77,98.08 56.06,98.37 56.06,98.88 56.81,99.63 57.21,99.63 C161.1
LAN_ISOLATEB: length 8.1
  BOTTOM w0.102: v2(60.52,99.25) 60.52,98.45 60.08,98 60.08,97.85 59.62,97.39 R95.1 59.2,97.38 57.88,97.38 R97.2 57.18,97.24 56.95,97.24 56.81,97.1 55.33,97.1 55.26,97.03 LU1.20
LAN_LED0_C: length 23
  TOP w0.102: LANC4.1 44.67,101.66 45.05,102.04 45.05,106.03 42.12,108.96 42.12,115.09 J8.13 ; LANC4.1 LR85.2 ; LANC4.1 43.85,99.54 v2(43.58,99.81)
LAN_LED1_C: length 22.2
  TOP w0.102: v2(48.25,100.54) 48.25,100.45 LANC3.1 LR87.2 46.45,104.92 42.32,109.04 42.32,114.6 43.62,115.9 J8.14
LAN_LINKLED0#: length 21
  TOP w0.457: LR85.1 45.56,97.55
  TOP w0.508: v1(54.32,90.69) 54.32,90.68 53.46,89.82 48.51,89.82 47.01,91.32 47.01,94.32 45.56,95.77 45.56,97.55
  BOTTOM w0.229: v2(53.84,93) 53.84,93.53 53.53,93.85 LU1.27
  BOTTOM w0.508: v2(53.84,93) 54.04,92.8 54.04,91.7 54.42,91.32 54.42,90.79 v1(54.32,90.69)
LAN_LINKLED1#: length 21.3
  TOP w0.457: LR87.1 46.45,95.79
  TOP w0.508: v1(55.08,90.93) 54.71,91.31 54.07,91.31 53.7,90.94 53.7,90.92 53.21,90.43 48.92,90.43 47.62,91.73 47.62,94.62 46.45,95.79
  BOTTOM w0.229: LU1.26 53.93,93.93 54.65,93.2
  BOTTOM w0.508: 54.65,93.2 54.65,91.98 55.08,91.55 v1(55.08,90.93) 55.41,90.61 v2(55.77,90.61)
LAN_MDI0_N: length 10.9
  BOTTOM w0.102: LL10.4 43.19,97.81 43.4,97.6 43.4,97.44 43.17,97.21 42.89,97.21 42.7,97.02 42.7,96.8 43.07,96.43 43.68,96.43 44.72,95.39 50.18,95.39 50.63,95.83 LU1.2
LAN_MDI0_N_C: length 15.9
  BOTTOM w0.102: J8.2 33.81,105.08 33.57,105.32 33.09,105.32 32.9,105.12 32.9,103.12 35.48,100.54 40.97,100.54 41.42,101 42.13,101 43.19,99.94 LL10.3
LAN_MDI0_P: length 10.9
  BOTTOM w0.102: LL10.1 42.34,96.65 42.92,96.07 43.53,96.07 44.57,95.03 50.33,95.03 50.73,95.43 LU1.1
LAN_MDI0_P_C: length 15.9
  BOTTOM w0.102: LL10.2 42.34,100.29 41.98,100.64 41.57,100.64 41.11,100.19 35.33,100.19 32.54,102.98 J8.1
LAN_MDI1_N: length 8.1
  BOTTOM w0.102: LU1.5 50.56,97.03 50.53,97.01 49.48,97.01 49.07,96.61 45.23,96.61 44.98,96.85 44.98,97.16 45.08,97.27 45.56,97.27 45.61,97.32 45.61,97.61 45.48,97.75 LL11.4
LAN_MDI1_N_C: length 15.4
  BOTTOM w0.102: LL11.3 45.48,99.91 45.23,100.16 45.23,100.52 44.9,100.85 43.57,100.85 42.43,101.99 37.2,101.99 35.25,103.94 35.25,105.17 35.47,105.39 36.01,105.39 36.35,105.05 J8.4
LAN_MDI1_P: length 8.1
  BOTTOM w0.102: LL11.1 44.63,96.7 45.08,96.25 49.22,96.25 49.62,96.66 50.53,96.66 50.56,96.63 LU1.4
LAN_MDI1_P_C: length 15.4
  BOTTOM w0.102: LL11.2 44.63,99.94 44.87,100.19 44.87,100.37 44.75,100.49 43.43,100.49 42.28,101.64 37.06,101.64 34.89,103.8 34.89,105.32 35.08,105.51 J8.3
LAN_MDI2_N: length 5.7
  BOTTOM w0.102: LU1.7 49.94,97.83 49.8,97.97 49.8,98.74 50.72,99.66 50.72,100.31 50.36,100.67 50.08,100.67 49.81,100.94 LL12.4
LAN_MDI2_N_C: length 12.5
  BOTTOM w0.102: LL12.3 47.05,100.94 46.8,100.69 46.6,100.69 45.31,101.99 43.7,101.99 42.63,103.06 41.24,103.06 40.3,104 40.3,105.42 40.51,105.62 41.25,105.62 41.43,105.44 J8.8
LAN_MDI2_P: length 5.7
  BOTTOM w0.102: LL12.1 49.76,100.09 49.98,100.31 50.21,100.31 50.37,100.16 50.37,99.81 49.45,98.89 49.45,97.82 49.79,97.48 50.51,97.48 50.56,97.43 LU1.6
LAN_MDI2_P_C: length 12.5
  BOTTOM w0.102: LL12.2 47.05,100.09 46.8,100.34 46.45,100.34 45.16,101.63 43.55,101.63 42.49,102.7 41.09,102.7 39.95,103.85 39.95,105.57 40.16,105.78 J8.7
LAN_MDI3_N: length 6.9
  BOTTOM w0.102: LL13.4 51.1,103.43 51.58,102.95 51.58,99.88 51.93,99.54 LU1.10
LAN_MDI3_N_C: length 8.7
  BOTTOM w0.102: LL13.3 47,103.43 46.75,103.18 43.93,103.18 42.84,104.28 42.84,105.34 43.2,105.7 43.73,105.7 43.97,105.46 J8.10
LAN_MDI3_P: length 6.9
  BOTTOM w0.102: LL13.1 49.52,102.58 49.7,102.4 49.88,102.4 49.95,102.47 49.95,102.9 50.13,103.08 50.95,103.08 51.22,102.8 51.22,99.73 51.57,99.38 51.57,99.2 51.53,99.15 LU1.9
LAN_MDI3_P_C: length 8.7
  BOTTOM w0.102: J8.9 42.7,105.7 42.49,105.49 42.49,104.13 43.79,102.83 46.75,102.83 47,102.58 LL13.2
LAN_REGOUT:
  vias: v2(56.23,94.37)
LAN_REGOUT_R: length 5.2
  BOTTOM w0.222: LU1.22 55.2,96.23 55.6,96.63 56.48,96.63 v1(56.66,96.45) ; v1(50.82,99.11) 50.82,98.44 LU1.8 ; LU1.3 v1(50.39,96.23) ; v1(51.76,93.76) 52.33,94.32 LU1.30
  vias: v1(59.15,94.71) v1(59.45,95.27) v2(58.41,92.57)
LAN_RXN3: length 70.8
  IN2 w0.114: v1(59.23,98.66) 59.92,99.36 71.34,99.36 71.91,98.8 75.98,98.8 78.56,96.22 78.56,92.7 79.08,92.18 79.08,90.56 80.14,89.49 80.14,86.86 83.06,83.94 83.06,78.82 83.36,78.52 83.36,75.06 84.75,73.66 84.75,72.56 85.6,71.71 85.6,68.78 84.85,68.03 84.85,66.91 84.24,66.3 84.24,55.5 82.82,54.08 81.8,54.08 v1(81.4,53.68)
  BOTTOM w0.114: XU1.AP7 81.05,54.03 v1(81.4,53.68) ; C162.2 58.63,99.32 58.86,99.32 59.23,98.96 v1(59.23,98.66)
LAN_RXP3: length 70.8
  IN2 w0.114: v1(59.86,98.66) 59.86,98.96 60.02,99.12 71.24,99.12 71.81,98.55 75.88,98.55 78.32,96.12 78.32,92.6 78.83,92.08 78.83,90.46 79.9,89.39 79.9,86.76 82.82,83.84 82.82,78.72 83.12,78.42 83.12,74.96 84.51,73.56 84.51,72.46 85.36,71.61 85.36,68.88 84.61,68.13 84.61,67.01 84,66.4 84,55.6 82.72,54.32 81.33,54.32 v1(80.66,53.65)
  BOTTOM w0.114: v1(80.66,53.65) 80.34,53.98 XU1.AP9 ; C161.2 58.62,99.56 58.96,99.56 v1(59.86,98.66)
LAN_TXN3: length 78.6
  TOP w0.114: C8.2 86.52,54.11 87.06,54.11 87.25,54.3 87.25,55.16 87.24,55.17 v1(87.24,55.28)
  IN2 w0.114: v1(53.87,100.64) 54.63,100.64 54.9,100.91 57.54,100.91 57.8,100.64 75.55,100.64 77.29,98.9 78.6,98.9 80.29,97.2 80.29,90.56 81.01,89.85 81.01,87.22 83.93,84.3 83.93,79.2 84.23,78.9 84.23,75.41 85.62,74.02 85.62,72.92 86.47,72.07 86.47,67.93 86.05,67.52 86.05,63.56 85.72,63.22 85.72,62.1 86.05,61.76 86.05,61.01 85.59,60.55 85.59,60.18 85.18,59.78 85.18,58.31 86.83,56.66 86.83,55.95 87,55.78 87,55.52 v1(87.24,55.28)
  BOTTOM w0.114: v1(53.87,100.64) 53.87,99.64 53.53,99.3 LU1.14
LAN_TXP3: length 78.6
  TOP w0.114: C9.2 86.5,54.35 86.96,54.35 87.01,54.4 87.01,54.85 v1(86.58,55.28)
  IN2 w0.114: v1(86.58,55.28) 86.76,55.46 86.76,55.68 86.59,55.85 86.59,56.56 84.94,58.21 84.94,58.43 84.94,59.88 85.35,60.28 85.35,60.65 85.81,61.11 85.81,61.66 85.48,62 85.48,63.32 85.81,63.66 85.81,67.62 86.23,68.03 86.23,71.97 85.37,72.82 85.37,73.92 83.98,75.31 83.98,78.8 83.69,79.1 83.69,84.2 80.76,87.12 80.76,89.75 80.05,90.46 80.05,97.1 78.5,98.66 77.19,98.66 75.45,100.4 57.7,100.4 57.44,100.67 55,100.67 54.73,100.4 54.31,100.4 54.04,100.14 v1(53.23,100.14)
  BOTTOM w0.114: LU1.13 53.13,99.24 53.62,99.74 53.62,100.06 53.55,100.14 v1(53.23,100.14)
LANWAKE: length 10.6
  BOTTOM w0.102: LU1.21 55.16,96.63 55.43,96.9 56.81,96.9 57.16,96.54 57.7,96.54 R96.1 58.3,96.36 58.46,96.53 59.86,96.53 60.64,95.75 LQ3.1 62.55,96.15 61.94,96.76 v2(61.94,97.01)
LDO-CAP: length 4.2
  TOP w0.229: AU1.40 7.84,101.26 v1(7.76,101.18)
  BOTTOM w0.457: AC60.1 AC61.1 7.57,101.18 v1(7.76,101.18)
  BOTTOM w0.508: AC60.1 7.09,102.75 v2(8.12,102.75)
LFRAME#: length 49.7
  TOP w0.127: v1(86.43,27.25) 86.54,27.14 v2(86.54,26.53) 86.54,24.01 87.24,23.31 87.24,22.47 86.82,22.05 86.53,22.05 84.13,19.65 84.13,18.19 82.32,16.38 82.32,12.49 82.19,12.35 P12.10 80.91,12.35 80.28,11.72 80.28,11.23 79.92,10.87 v1(78.05,10.87)
  IN2 w0.127: v1(73.32,38.94) 74.23,38.03 78.25,38.03 82.33,33.95 82.33,27.68 83.58,26.43 85.6,26.43 v1(86.43,27.25)
  BOTTOM w0.127: U24.6 77.32,10.14 v1(78.05,10.87) ; v1(73.32,38.94) 72.99,39.27 SR104.2 ; TPU1.22 87.02,27.08 86.85,27.25 v1(86.43,27.25)
LPC_AD0_R: length 6.4
  BOTTOM w0.102: 76.39,44.89 76.47,44.96 76.47,46.19 76.64,46.37 76.64,46.99 XU1.BH16
  BOTTOM w0.127: 76.39,44.89 75.76,44.26 v2(75.76,43.75) 75.76,43.14 75.66,43.04 SR100.1
LPC_AD1_R: length 9.3
  TOP w0.127: v2(74.72,43.95) 74.72,43.65 73.75,42.69 v1(73.75,41.74)
  BOTTOM w0.102: XU1.BJ17 76.06,46.51 76.06,45.42 75.53,44.89
  BOTTOM w0.127: 75.53,44.89 73.75,43.11 v1(73.75,41.74) 73.88,41.61 SR101.1
LPC_AD2_R: length 5.1
  BOTTOM w0.102: 78.16,44.89 78.16,46.25 78.1,46.31 XU1.BJ13
  BOTTOM w0.127: 78.16,44.89 78.16,44.85 79.04,43.98 79.55,43.98 79.88,43.65 SR103.1
LPC_AD3_R: length 7.4
  BOTTOM w0.102: 77.09,44.89 77.09,45.28 77.51,45.7 77.51,46.05 77.41,46.15 77.41,46.77 77.32,46.86 77.32,47.13 77.48,47.28 77.48,47.56 XU1.BG14
  BOTTOM w0.127: 77.09,44.89 77.09,44.77 76.91,44.59 76.91,42.24 77.44,41.71 SR102.1
LPC_CLK1: length 31.3
  TOP w0.127: R30.1 83.02,19.95 v2(83.28,20.2) 84.7,21.62 85.34,21.62 86.37,22.65 v1(86.71,22.65)
  IN2 w0.127: v1(83.02,38.69) 84.8,36.91 84.8,35.07 87.55,32.32 87.55,28.64 88.41,27.78 88.41,25.65 88.83,25.23 88.83,24.61 86.86,22.65 v1(86.71,22.65)
  BOTTOM w0.127: v1(83.02,38.69) 79.79,38.69 SR188.2 ; TPR3.2 v1(86.71,22.65)
LPC_CLK_EC: length 3.9
  BOTTOM w0.127: U24.13 74.52,8.46 74.77,8.21 74.77,7.79 75.15,7.42 SR659.1 74.3,6.83 v2(74.11,6.64)
LPC_CLK_TPM: length 5
  TOP w0.127: v2(85.34,24.19) 85.51,24.19 v1(86.1,24.77)
  BOTTOM w0.127: TPU1.21 87.67,25.18 87.55,25.05 CB2.1 TPR3.1 86.71,24.49 86.43,24.77 v1(86.1,24.77)
LPC_FRAME#_R: length 7.9
  BOTTOM w0.102: XU1.BG17 75.96,47.16 75.96,46.88 75.86,46.77 75.86,45.65 75.1,44.89
  BOTTOM w0.127: SR104.1 72.99,42.17 72.86,42.3 v2(72.86,42.78) 73.12,43.04 73.25,43.04 75.1,44.89
LPC_RCOMP: length 8.1
  TOP w0.127: SR105.1 v2(76.8,41.97) 76.8,44.26 75.86,45.2 75.86,47.6 v1(76.18,47.91)
  BOTTOM w0.127: v1(76.18,47.91) 76.07,47.91 XU1.BF18
LPC_V1P8V3P3_S3: length 7.6
  TOP w0.254: SL4.2 71.1,50.6 71.23,50.72 71.68,50.72 71.87,50.91 C70.1 72.41,51.22 v2(72.84,51.64) 73.23,52.04 v1(73.23,52.23)
  BOTTOM w0.229: XU1.AM27 71.7,54.49 72.22,54.49 72.22,54.49 72.44,54.49 XU1.AN24
  BOTTOM w0.254: XU1.AN24 73.23,53.69 v1(73.23,52.23)
LPCCLK0: length 56.3
  TOP w0.127: v1(74.69,5.42) 75.59,4.52 83.46,4.52 86.42,7.47 86.42,9.37 89.11,12.06 89.11,14.47 88.26,15.33 v2(87.15,15.33) 87.15,17.28 87.41,17.54 87.41,20.28 v1(87.17,20.52)
  IN2 w0.127: v1(76.52,39.33) 77.03,39.84 78.24,39.84 86.28,31.79 86.28,28.11 86.94,27.46 86.94,23.86 86.2,23.12 86.2,21.49 v1(87.17,20.52)
  BOTTOM w0.127: v1(74.69,5.42) 74.69,5.53 SR659.2 ; v1(76.52,39.33) 76.55,39.35 SR106.2
LPCCLK0_R: length 6.8
  BOTTOM w0.102: XU1.BG15 77.07,47.29 77.07,47.06 76.94,46.93 76.94,46.88 76.85,46.78 76.85,46.28 76.84,46.28 76.67,46.11 76.67,44.89
  BOTTOM w0.127: 76.67,44.89 76.67,44.81 76.4,44.53 76.4,43.56 76.29,43.46 v2(76.29,42.05) 76.55,41.79 SR106.1
LPCCLK1_R: length 6.6
  BOTTOM w0.102: XU1.BH14 77.62,46.23 77.72,46.12 77.72,45.59 77.42,45.29 77.42,44.89
  BOTTOM w0.127: SR188.1 77.94,41.37 77.94,41.92 77.56,42.3 v2(77.56,43.54) 77.56,44.08 77.42,44.23 77.42,44.89
M_CHA_BA0: length 41.4
  TOP w0.203: v2(35.93,59.98) v1(36.66,59.98)
  IN2 w0.102: v1(61.09,66.2) 60.55,66.2 59.03,67.71 56.72,67.71 56.46,67.98 55.72,67.98
  IN2 w0.216: v1(36.66,59.98) 33.2,59.98 33,60.18 33,60.79 33.11,60.91 35.63,60.91 35.98,61.25 36.34,61.25 36.68,60.91 37.12,60.91 37.51,61.3 38.55,61.3 38.88,61.63 42.37,61.63 42.93,62.19 47.06,62.19 51,66.13 52.56,66.13 54.41,67.98 55.72,67.98
  BOTTOM w0.203: XU1.K47 61.54,65.74 v1(61.09,66.2) ; v1(36.66,59.98) 37.86,58.78 XMM1.109
M_CHA_BA1: length 41.7
  TOP w0.203: v2(34.97,57.92) v1(34.26,57.92)
  IN2 w0.102: 56.84,65.49 58.49,65.49 58.8,65.8 60.86,65.8 60.88,65.78 62.99,65.78 63.36,65.41 v1(63.36,65.17)
  IN2 w0.216: 56.84,65.49 56.43,65.08 55.03,65.08 53.38,63.43 52.8,63.43 49.87,60.51 48.9,60.51 46.02,57.62 35.15,57.62 34.94,57.83 34.94,59.14 34.73,59.36 33.84,59.36 33.62,59.14 33.62,58.76 34.26,58.12 v1(34.26,57.92)
  BOTTOM w0.203: v1(34.26,57.92) 34.26,58.76 34.06,58.95 32.79,58.95 32.67,59.08 XMM1.108 ; XU1.K44 62.97,65.56 v1(63.36,65.17)
M_CHA_BA2: length 37.5
  IN1 w0.216: v1(37.57,68.98) 38.05,68.5 38.69,68.5 38.82,68.63 38.82,69.02 38.94,69.15 39.44,69.15 39.57,69.02 39.57,68.49 39.69,68.37 40.15,68.37 40.28,68.49 40.28,69.02 40.4,69.15 40.86,69.15 40.99,69.02 40.99,68.49 41.11,68.37 41.57,68.37 41.7,68.49 41.7,69.02 41.83,69.15 42.21,69.15 42.33,69.02 42.33,68.49 42.46,68.37 42.92,68.37 43.05,68.49 43.05,69.02 43.17,69.15 43.63,69.15 43.75,69.02 43.75,67.49 45.28,65.97 47.32,65.97 48.89,67.54 48.89,68.94 49.09,69.15 v1(50.45,69.15)
  BOTTOM w0.102: XU1.D52 58.84,68.84 58.33,68.84 58.09,69.08 58.09,69.4 57.71,69.78 56.2,69.78 55.64,70.34
  BOTTOM w0.203: v1(37.57,68.98) 37.57,68.47 38.26,67.78 XMM1.79 ; 55.64,70.34 55.57,70.42 55.57,71 54.68,71.89 51.15,71.89 50.45,71.19 v2(50.45,70.88) v1(50.45,69.15)
M_CHA_CAS#: length 37.3
  TOP w0.203: v2(38.02,55.71) 37.65,56.08 v1(37.65,56.38)
  IN2 w0.102: 56.66,64.14 57.02,64.5 58.57,64.5 58.68,64.61 61.63,64.61 61.82,64.8 62.25,64.8 v1(62.6,65.16)
  IN2 w0.216: 56.66,64.14 55.85,64.14 53.9,62.19 53.31,62.19 50.09,58.96 49.24,58.96 46.66,56.38 42.56,56.38 41.9,55.72 41.55,55.72 41.42,55.85 41.42,56.25 41.3,56.38 38.94,56.38 38.82,56.25 38.82,55.85 38.69,55.72 36.29,55.72 36.16,55.85 36.16,56.25 36.29,56.38 v1(37.65,56.38)
  BOTTOM w0.203: v1(62.6,65.16) 62.6,65.12 XU1.M44 ; v1(37.65,56.38) 37.65,56.79 37.84,56.98 XMM1.115
M_CHA_CKE0: length 35.3
  TOP w0.203: v1(36.3,68.98) v2(36.3,69.71)
  IN2 w0.216: v1(36.3,68.98) 36.3,69.24 36.52,69.45 38.78,69.45 39,69.67 39,70.01 39.22,70.23 39.65,70.23 39.86,70.01 39.86,69.67 40.08,69.45 41.21,69.45 44.51,72.75 48.66,72.75 49.44,71.97 59.04,71.97 59.87,71.13 59.87,71.12 61.08,69.91 61.21,69.91 61.71,69.41 v1(61.71,68.62)
  BOTTOM w0.203: XMM1.73 36.9,69.58 v1(36.3,68.98) ; XU1.C47 61.75,68.66 v1(61.71,68.62)
M_CHA_CKE1: length 37
  TOP w0.203: v1(34.3,69.28) v2(34.3,70.01)
  IN2 w0.102: 61.33,71.03 61.33,70.53 62.36,69.5 62.36,69.03 62.39,69 v1(62.39,68.69)
  IN2 w0.216: v1(34.3,69.28) 35.87,70.85 41.73,70.85 44.25,73.37 48.92,73.37 49.7,72.59 59.78,72.59 61.33,71.03
  BOTTOM w0.203: v1(34.3,69.28) XMM1.74 ; v1(62.39,68.69) 62.39,68.48 XU1.F44
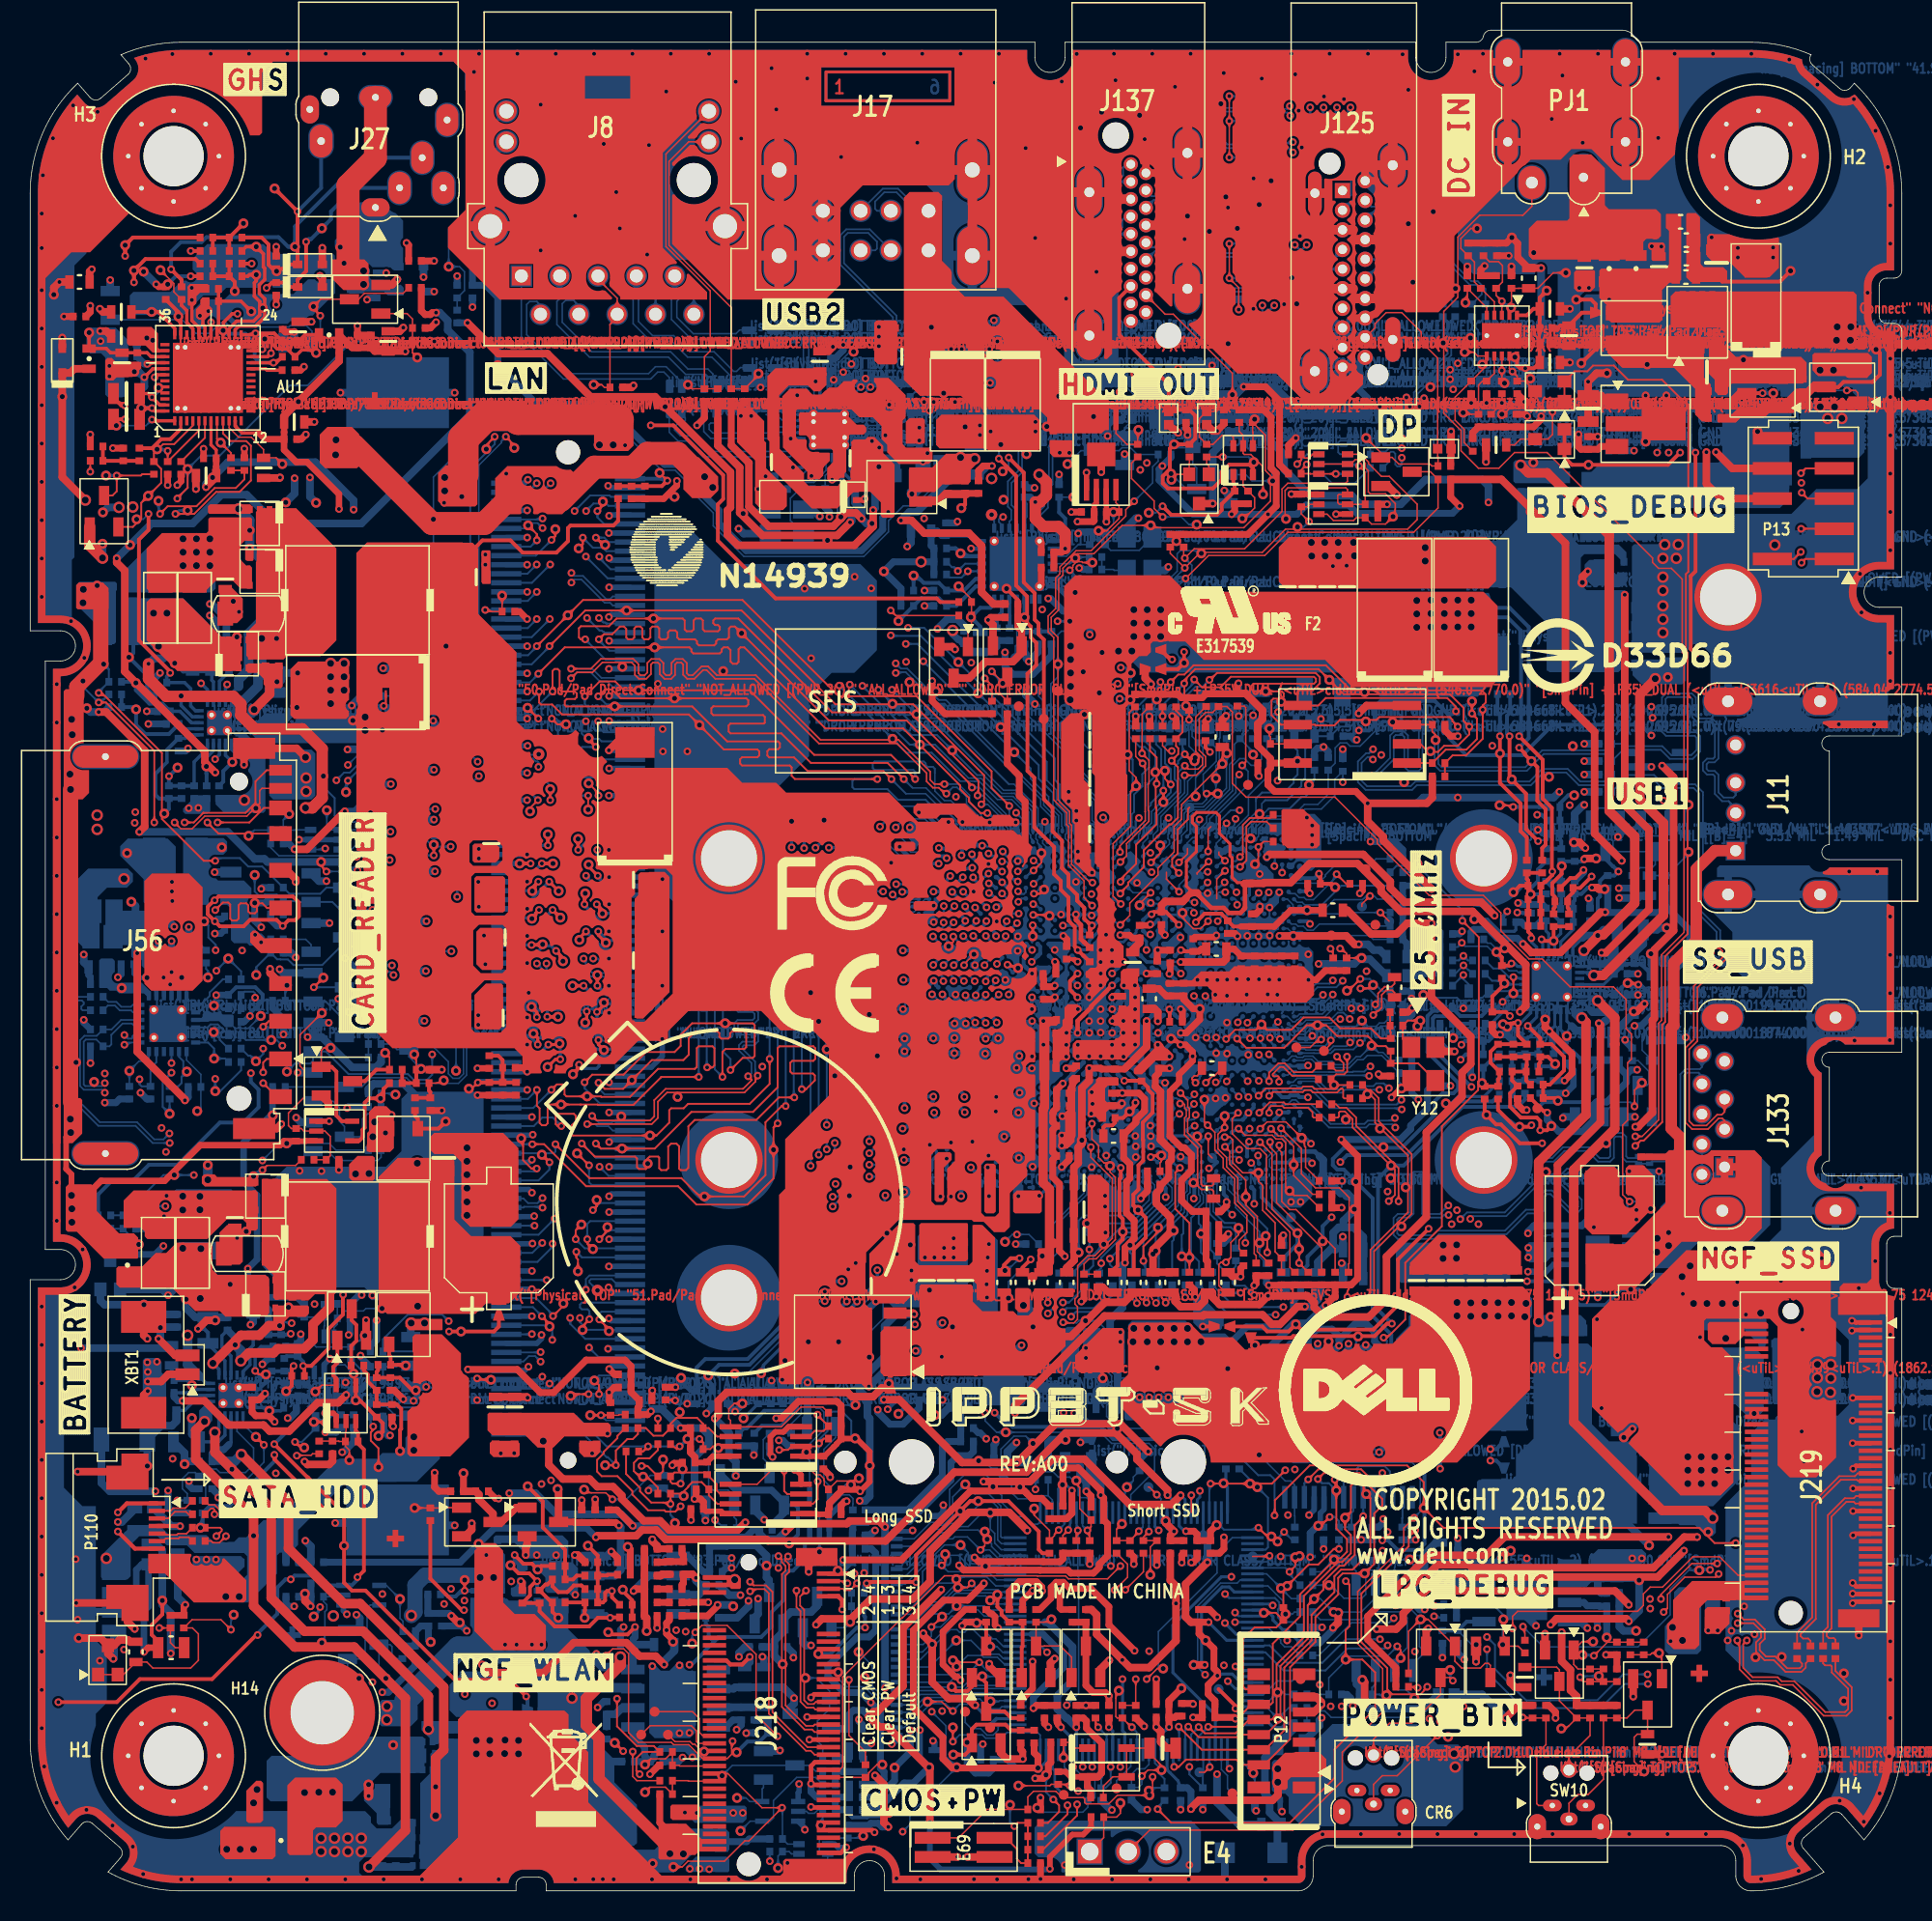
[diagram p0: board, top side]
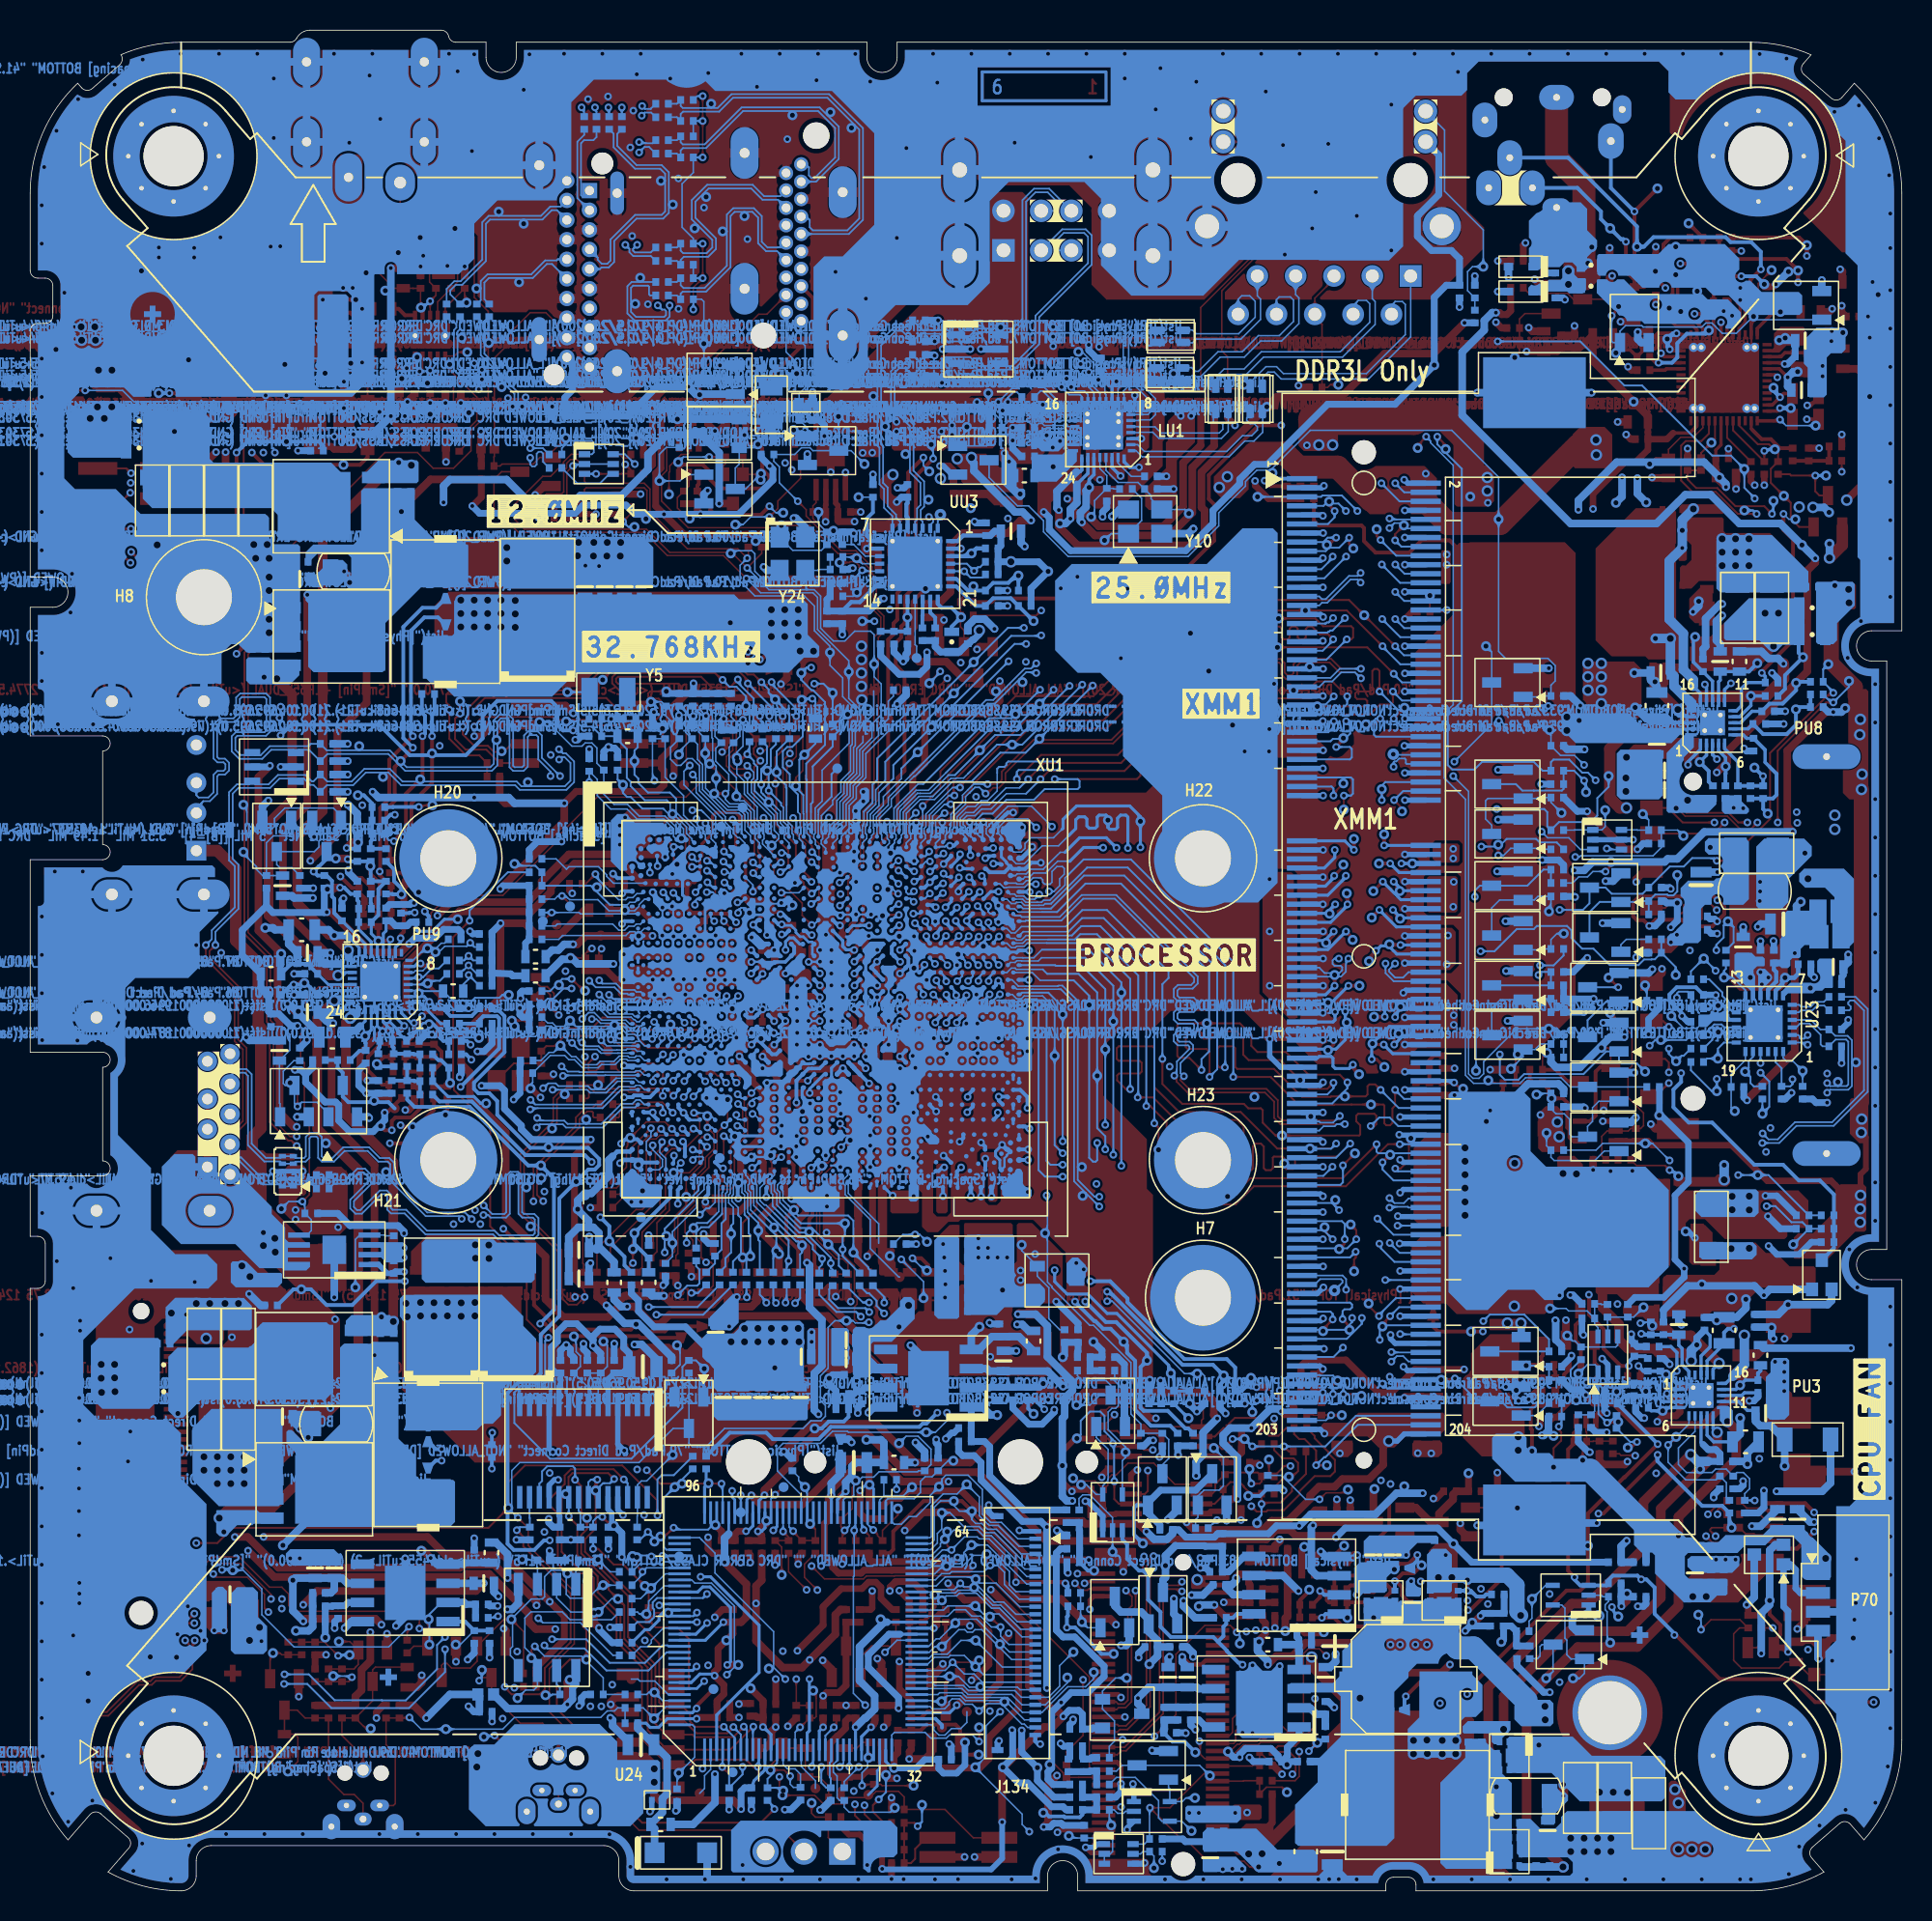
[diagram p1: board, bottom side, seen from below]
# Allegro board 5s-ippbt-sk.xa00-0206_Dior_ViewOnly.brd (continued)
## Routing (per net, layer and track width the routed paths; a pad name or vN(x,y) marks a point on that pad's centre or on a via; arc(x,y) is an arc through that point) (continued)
M_CHA_CLK0: length 38.6
  IN1 w0.114: v1(37.3,61.78) 37.08,61.99 37.08,62.31 37.2,62.43 38.33,62.43 39.04,61.72 39.04,61.28 39.48,60.84 40.12,60.84 40.4,61.12 40.4,61.36 40.59,61.55 41.06,61.55 41.17,61.44 41.17,60.96 41.43,60.7 41.97,60.7 42.23,60.96 42.23,61.44 42.34,61.55 43.17,61.55 43.28,61.44 43.28,60.53 43.54,60.27 44.2,60.27 44.56,60.63 44.56,61.4 44.71,61.55 51.64,61.55 54.01,63.93 56.34,63.93 56.74,64.32 58.66,64.32 59.3,64.96 59.3,65.62 59.12,65.8 59.12,66.13 59.64,66.65 60.02,66.65 60.3,66.36 60.3,66.04 60.79,65.55 60.79,65.34 60.71,65.26 60.53,65.26 v1(60.53,65.26)
  BOTTOM w0.114: XU1.M50 60.39,64.75 60.53,64.89 v1(60.53,65.26) ; XMM1.101 38.6,61.18 38.24,60.82 37.26,60.82 37.08,61.01 37.08,61.2 37.18,61.3 37.58,61.3 37.71,61.43 37.71,61.65 37.59,61.78 v1(37.3,61.78)
M_CHA_CLK0#: length 38.6
  IN1 w0.114: v1(36.66,61.78) 36.84,61.96 36.84,62.41 37.1,62.67 38.43,62.67 39.29,61.82 39.29,61.38 39.58,61.08 40.02,61.08 40.16,61.22 40.16,61.46 40.49,61.79 41.16,61.79 41.42,61.54 41.42,61.06 41.53,60.94 41.87,60.94 41.99,61.06 41.99,61.54 42.24,61.79 43.27,61.79 43.52,61.54 43.52,60.63 43.64,60.51 44.1,60.51 44.32,60.73 44.32,61.5 44.61,61.79 51.54,61.79 53.91,64.17 56.24,64.17 56.64,64.56 58.56,64.56 59.06,65.06 59.06,65.52 58.88,65.7 58.88,66.23 59.54,66.89 60.12,66.89 60.55,66.46 60.55,66.14 61.03,65.65 61.03,65.46 v1(61.23,65.26)
  BOTTOM w0.114: XU1.M48 60.84,64.86 v1(61.23,65.26) ; XMM1.103 37.16,60.58 36.84,60.91 36.84,61.61 v1(36.66,61.78)
M_CHA_CLK1: length 37.8
  IN1 w0.102: v1(60.52,64.17) 60.52,64.43 60.41,64.54 60.11,64.54 60.03,64.61 59.57,64.61 58.61,63.66 57.62,63.66 57.61,63.65 57.51,63.65
  IN1 w0.114: v1(33.57,61.45) 33.97,61.05 33.97,59.6 34.38,59.19 35,59.19 35.25,59.45 35.25,60.26 35.38,60.38 35.7,60.38 35.82,60.26 35.82,59.45 36.08,59.19 38.98,59.19 39.5,59.71 41.04,59.71 41.56,59.19 44.75,59.19 45.65,60.09 51.61,60.09 54.46,62.94 54.61,62.94 55.04,63.37 56.9,63.37 57.18,63.65 57.51,63.65
  BOTTOM w0.114: XMM1.102 32.68,60.88 33.04,60.52 33.57,60.52 33.96,60.92 33.96,61.06 v1(33.57,61.45) ; XU1.P50 60.37,63.76 60.52,63.91 v1(60.52,64.17)
M_CHA_CLK1#: length 37.8
  IN1 w0.102: v1(61.18,64.18) 60.62,64.74 60.19,64.74 60.12,64.82 59.48,64.82 58.53,63.86 57.6,63.86 57.56,63.86 57.53,63.89 57.51,63.89
  IN1 w0.114: v1(34.21,61.45) 34.21,61.45 34.21,59.7 34.48,59.43 34.9,59.43 35.01,59.55 35.01,60.36 35.28,60.63 35.8,60.63 36.06,60.36 36.06,59.55 36.18,59.43 38.88,59.43 39.4,59.95 41.14,59.95 41.66,59.43 44.65,59.43 45.55,60.33 51.51,60.33 54.36,63.18 54.51,63.18 54.94,63.61 56.8,63.61 57.08,63.89 57.51,63.89
  BOTTOM w0.114: XMM1.104 33.67,60.28 34.21,60.82 v1(34.21,61.45) ; XU1.P48 60.84,63.84 v1(61.18,64.18)
M_CHA_CS#0: length 40.8
  TOP w0.203: v1(35.12,55.1) 34.79,55.1 v2(34.28,54.59)
  IN2 w0.102: 54.07,60.8 54.27,60.8 57.03,63.56 58.82,63.56 59.58,62.8 62.73,62.8 62.9,62.97 62.9,63.82 v1(63.35,64.27)
  IN2 w0.216: 54.07,60.8 53.81,60.8 50.3,57.3 49.37,57.3 47.21,55.14 44.67,55.14 43.62,54.09 36.14,54.09 v1(35.12,55.1)
  BOTTOM w0.203: XU1.P44 63.35,64.14 v1(63.35,64.27) ; v1(35.12,55.1) 35.12,56.11 33.95,57.28 XMM1.114
M_CHA_CS#1: length 40
  TOP w0.203: v2(35.96,54.11) 36.37,54.52 v1(36.37,54.75)
  IN2 w0.102: 59.61,63.71 59.62,63.72 62.46,63.72 62.68,63.94 v1(62.68,64.28)
  IN2 w0.216: v1(36.37,54.75) 36.72,55.1 38.85,55.1 38.98,54.97 38.98,54.85 39.11,54.72 39.62,54.72 39.74,54.85 39.74,55.63 39.87,55.76 40.28,55.76 40.4,55.63 40.4,54.85 40.53,54.72 42.21,54.72 42.41,54.92 42.41,55.35 42.81,55.76 43.1,55.76 43.22,55.64 43.22,55.18 43.35,55.05 43.71,55.05 43.83,55.18 43.83,55.58 44.01,55.76 46.95,55.76 49.11,57.92 49.92,57.92 53.57,61.57 54.15,61.57 56.17,63.59 56.56,63.59 57.14,64.17 59.07,64.17 59.53,63.71 59.61,63.71
  BOTTOM w0.203: XMM1.121 38.73,55.18 38.61,55.3 37.81,55.3 37.69,55.17 37.69,54.64 37.53,54.49 36.62,54.49 v1(36.37,54.75) ; v1(62.68,64.28) 62.68,64.18 XU1.P45
M_CHA_DM0: length 57.6
  TOP w0.127: v2(37.94,92.06) 37.94,91.8 v1(37.58,91.44)
  IN2 w0.127: v1(37.58,91.44) 37.75,91.61 40.42,91.61 48.3,83.74 48.3,78.98 48.42,78.86 48.73,78.86 48.86,78.98 48.86,82.23 48.99,82.36 49.29,82.36 49.42,82.23 49.42,79 49.55,78.88 49.87,78.88 50,78.75 50,77.59 50.13,77.46 61.98,77.46 64.54,74.89 64.54,73.33 65.75,72.12 65.75,69.63 66.92,68.46 66.92,67.18 v1(66.48,66.73)
  BOTTOM w0.127: v1(37.58,91.44) 37.58,91.02 38.02,90.58 XMM1.11 ; XU1.G36 66.49,66.73 v1(66.48,66.73)
M_CHA_DM1: length 49.6
  IN1 w0.127: v1(57.09,79.59) 56.56,80.13 55.61,80.13 53.36,82.38 51.3,82.38 51.17,82.51 51.17,82.79 51.3,82.91 52.27,82.91 52.39,83.04 52.39,83.35 52.26,83.47 50.23,83.47 50.11,83.6 50.11,83.91 50.23,84.03 51.2,84.03 51.33,84.16 51.33,84.41 51.17,84.57 48.12,84.57 47.99,84.7 47.99,85.82 47.87,85.95 36.17,85.95 36.17,85.94 35.54,85.94 35.54,85.95 33.7,85.95 v1(33.56,86.08)
  BOTTOM w0.102: 64.84,73.34 65.18,73.34 66.69,71.83 66.69,71.81 66.77,71.73 66.77,70.68 66.93,70.52 XU1.B36
  BOTTOM w0.127: 64.84,73.34 60.47,77.71 58.98,77.71 v2(58.72,77.97) v1(57.09,79.59) ; v1(33.56,86.08) 32.96,85.48 XMM1.28
M_CHA_DM2: length 44.2
  TOP w0.127: v1(37.47,75.8) 37,76.27 v2(37,76.39)
  IN1 w0.102: 63.51,71.92 64.08,71.36 64.08,70.53 65.35,69.26 65.35,68.87 65.01,68.54 65.01,67.98 v1(65.43,67.56)
  IN1 w0.127: 63.51,71.92 63.51,72.6 61.02,75.09 55.36,75.09 55.24,75.22 55.24,76.31 55.11,76.44 54.81,76.44 54.68,76.31 54.68,75.22 54.55,75.09 54.27,75.09 54.15,75.22 54.15,76.31 54.02,76.44 53.74,76.44 53.61,76.31 53.61,76.18 53.44,76.01 52.67,76.01 52.54,76.14 52.54,76.31 52.41,76.44 52.03,76.44 51.9,76.31 51.9,76.14 51.78,76.01 37.68,76.01 v1(37.47,75.8)
  BOTTOM w0.127: XMM1.63 36.57,74.98 36.44,75.11 36.44,75.67 36.57,75.8 v1(37.47,75.8) ; v1(65.43,67.56) 65.63,67.56 XU1.F38
M_CHA_DM3: length 41.9
  TOP w0.127: v1(63.42,71.42) 62.97,71.42 62.2,72.19 62.2,72.43 61.61,73.01 61.61,73.25 57.84,77.03 52.69,77.03 47.31,82.4 47.06,82.4 46.93,82.27 46.93,81.44 46.8,81.31 46.55,81.31 46.4,81.47 46.4,82.22 46.22,82.4 45.94,82.4 45.81,82.27 45.81,82.13 45.69,82 43.93,82 43.81,82.13 43.81,82.27 43.68,82.4 v2(41.37,82.4) 35.41,82.4 v1(33.67,80.65)
  BOTTOM w0.102: v1(63.42,71.42) 63.54,71.42 64.01,70.95 XU1.B42
  BOTTOM w0.127: XMM1.46 33.12,80.08 33.67,80.63 v1(33.67,80.65)
M_CHA_DM4: length 44
  TOP w0.127: v1(48.99,55.13) 48.99,53.47 47.67,52.15 43.59,52.15 43.29,51.86 42.47,51.86 42.34,51.73 42.34,50.9 41.49,50.05 v2(41.06,50.05) 35.95,50.05 35.88,50.12 35.88,50.73 36.14,50.99 36.14,51.37 36.02,51.49 34.94,51.49 34.82,51.37 34.82,50.81 34.94,50.68 v1(35.19,50.68)
  BOTTOM w0.102: 55.21,64.07 55.39,63.9 58.33,63.9 58.75,63.48 59,63.48 59.3,63.77 XU1.P51
  BOTTOM w0.127: v1(35.19,50.68) 34.63,51.24 33.93,51.24 33.36,50.68 XMM1.136 ; 55.21,64.07 54.29,64.99 52.66,64.99 48.58,60.92 48.58,60.49 48.99,60.08 v1(48.99,55.13)
M_CHA_DM5: length 43.5
  TOP w0.127: v1(37.28,45.11) 37.53,45.36 v2(37.53,45.78)
  IN1 w0.102: 57.92,59.84 58.56,60.48 58.56,60.88 59.47,61.79 62.78,61.79 v1(63.23,61.34)
  IN1 w0.127: 57.92,59.84 52.1,54.01 51.58,54.01 51.12,53.55 50.46,53.55 50,54.01 49.62,54.01 49.27,53.66 49.27,53.37 49.83,52.82 49.83,52.39 49.26,51.83 48.74,51.83 48.61,51.95 48.61,52.61 48.48,52.74 48.23,52.74 48.1,52.61 48.1,51.95 47.97,51.83 47.72,51.83 47.59,51.95 47.59,52.61 47.47,52.74 47.21,52.74 47.09,52.61 47.09,51.95 46.96,51.83 44.96,51.83 43.42,50.28 43.42,49.19 38.77,44.55 37.84,44.55 v1(37.28,45.11)
  BOTTOM w0.127: XMM1.153 37.75,45.58 v1(37.28,45.11) ; v1(63.23,61.34) 63.23,61.39 XU1.V42
M_CHA_DM6: length 45.1
  IN2 w0.127: v1(60.5,60.28) 60.07,59.86 59.51,59.86 58.26,58.61 58.26,57.68 53.48,52.9 53.48,52.34 51.74,50.6 51.74,49.76 50.54,48.57 50.54,46.76 48.04,44.26 43.38,44.26 43.04,43.92 43.04,42.65 38.8,38.41 35.45,38.41 35.25,38.62 35.25,38.85 35.4,39 35.91,39 36.06,39.15 36.06,40.09 35.67,40.48 v1(34.23,40.48)
  BOTTOM w0.127: v1(34.23,40.48) XMM1.170 ; v1(60.5,60.28) 60.5,60.53 XU1.Y50
M_CHA_DM7: length 44.6
  IN1 w0.127: v1(37.03,36) 37.39,36.36 38.89,36.36 42.57,40.04 42.57,40.4 44.89,42.73 48.61,42.73 53.31,47.42 v1(53.31,49.56)
  BOTTOM w0.102: 55.26,60.33 57.09,60.33 57.61,60.86 XU1.Y52
  BOTTOM w0.127: v1(53.31,49.56) 53.31,48.42 53.41,48.32 53.59,48.32 53.84,48.57 v2(53.84,58.71) 53.84,59.31 54.86,60.33 55.26,60.33 ; XMM1.187 37.65,35.38 v1(37.03,36)
M_CHA_DQ0: length 60.1
  IN2 w0.127: v1(36.07,91.44) 36.07,91.88 35.94,92.01 35.55,92.01 35.43,92.13 35.43,92.55 35.55,92.68 40.87,92.68 50.67,82.87 50.67,81.09 50.8,80.96 51.48,80.96 51.61,80.83 51.61,80.04 51.73,79.92 52.04,79.92 52.16,79.79 52.16,78.65 52.29,78.53 62.42,78.53 65.61,75.33 65.61,73.18 66.34,72.45 66.34,69.81 67.51,68.64 67.51,66.44 v1(66.45,65.39)
  BOTTOM w0.127: XU1.M36 66.59,65.39 v1(66.45,65.39) ; v1(36.07,91.44) 37.1,92.47 38.39,92.47 38.47,92.38 XMM1.5 v2(42.69,92.38)
M_CHA_DQ1: length 57.6
  TOP w0.127: v2(67.18,66.35) 66.9,66.08 v1(66.5,66.08)
  IN2 w0.127: v1(36.83,91.44) 36.83,92.02 36.96,92.14 40.64,92.14 49.99,82.8 49.99,80.53 50.09,80.43 50.94,80.43 51.07,80.3 51.07,80.02 50.94,79.89 50.13,79.89 49.99,79.75 49.99,79.48 50.12,79.35 50.41,79.35 50.53,79.22 50.53,78.12 50.66,77.99 50.97,77.99 51.1,78.12 51.1,79.26 51.22,79.38 51.5,79.38 51.63,79.26 51.63,78.12 51.76,77.99 62.2,77.99 65.08,75.11 65.08,73.25 66.06,72.27 66.06,69.68 67.15,68.59 67.15,66.73 v1(66.5,66.08)
  BOTTOM w0.127: XU1.J36 66.55,66.08 v1(66.5,66.08) ; XMM1.7 38.32,91.78 38.16,91.93 37.32,91.93 36.83,91.44 v1(36.83,91.44)
M_CHA_DQ2: length 57.4
  TOP w0.127: v2(36.34,88.96) 36.61,89.23 v1(36.61,89.67)
  IN2 w0.102: v1(65.38,64.13) 65.38,64.24 64.81,64.81 64.81,68.65 64.86,68.69 64.86,69.05 64.73,69.18 63.99,69.92 63.99,70.98 63.84,71.13 63.84,71.6 63.45,71.98 63.45,72.7
  IN2 w0.127: v1(36.61,89.67) 37.43,88.85 39.95,88.85 44.75,84.05 44.75,76.77 44.87,76.64 45.26,76.64 45.38,76.77 45.38,79 45.51,79.13 45.88,79.13 46.01,79 46.01,76.25 47.09,75.17 60.98,75.17 62.7,73.44 63.45,72.7
  BOTTOM w0.127: XMM1.17 38.17,88.78 37.95,89 37.28,89 v1(36.61,89.67) ; v1(65.38,64.13) 65.36,64.13 XU1.P40
M_CHA_DQ3: length 57.3
  TOP w0.127: v2(38.09,89.19) 37.96,89.19 v1(37.48,89.67)
  IN2 w0.102: 63.57,73.04 63.7,72.91 63.7,72.02 64.04,71.68 64.04,71.21 64.32,70.94 64.32,69.91 65.06,69.16 65.06,68.61 65.01,68.56 65.01,65.24 v1(65.49,64.76)
  IN2 w0.127: 63.57,73.04 62.69,73.92 62.69,74.24 61.23,75.7 47.31,75.7 46.54,76.47 46.54,83.01 46.39,83.16 46.07,83.16 45.94,83.04 45.94,79.79 45.81,79.66 45.41,79.66 45.28,79.79 45.28,84.27 40.17,89.39 37.76,89.39 v1(37.48,89.67)
  BOTTOM w0.127: XMM1.15 38.33,89.38 38.03,89.67 v1(37.48,89.67) ; XU1.M40 65.09,64.76 v1(65.49,64.76)
M_CHA_DQ4: length 57.7
  TOP w0.127: v2(66.42,63.26) v1(66.42,63.99)
  IN2 w0.127: v1(66.42,63.99) 67.99,65.55 67.99,68.94 66.79,70.14 66.79,75.66 62.71,79.74 57.96,79.74 57.67,80.03 56.04,80.03 55.71,80.36 54.69,80.36 40.98,94.07 34.36,94.07 v1(33.56,93.28)
  BOTTOM w0.127: v1(33.56,93.28) 33.56,93.28 32.97,92.68 XMM1.4 ; XU1.P36 66.57,63.99 v1(66.42,63.99)
M_CHA_DQ5: length 57.6
  TOP w0.127: v2(67.53,64.61) 67.47,64.67 v1(66.45,64.67)
  IN2 w0.127: v1(66.45,64.67) 67.76,65.99 67.76,68.84 66.57,70.04 66.57,72.64 66.15,73.06 66.15,75.55 62.64,79.06 53.34,79.06 53.17,79.23 53.17,81.13 40.76,93.54 34.74,93.54 v1(34.48,93.28)
  BOTTOM w0.127: v1(34.48,93.28) 33.28,92.08 XMM1.6 ; XU1.N36 66.6,64.67 v1(66.45,64.67)
M_CHA_DQ6: length 57.5
  TOP w0.127: v1(34.54,89.52) 34.79,89.77 v2(34.79,90.23)
  IN2 w0.127: v1(64.39,66.09) 63.95,66.53 63.95,69.43 62.82,70.56 62.82,71.12 62.29,71.65 62.29,72.59 62.07,72.81 61.6,73.28 61.6,73.69 60.65,74.63 46.13,74.63 44.21,76.55 44.21,83.83 44.06,83.98 43.78,83.98 43.6,83.8 43.6,81.37 43.48,81.24 43.1,81.24 42.97,81.37 42.97,85.08 40.15,87.89 36.74,87.89 35.11,89.52 v1(34.54,89.52)
  BOTTOM w0.127: v1(64.39,66.09) 64.73,65.76 XU1.K40 ; v1(34.54,89.52) 33.5,88.48 XMM1.18
M_CHA_DQ7: length 58
  TOP w0.127: v1(33.57,89.49) 33.57,89.9 v2(32.99,90.48)
  IN2 w0.127: v1(63.52,66.12) 63,66.65 63,68.7 62.58,69.12 62.58,71.02 62.05,71.55 62.05,72.48 60.43,74.1 45.91,74.1 43.68,76.33 43.68,80.58 43.55,80.7 43.2,80.7 43.07,80.58 43.07,77.43 42.94,77.3 42.56,77.3 42.44,77.43 42.44,84.85 39.93,87.36 36.51,87.36 35.11,88.76 34.31,88.76 v1(33.57,89.49)
  BOTTOM w0.127: v1(63.52,66.12) 63.62,66.12 XU1.K42 ; XMM1.16 33.16,89.08 v1(33.57,89.49)
M_CHA_DQ8: length 49.6
  IN1 w0.127: v1(58.16,83.7) 57.67,84.18 56.56,84.18 50.92,89.82 39.59,89.82 39,90.41 38.02,90.41 37.83,90.22 35.89,90.22 v1(33.56,87.89)
  BOTTOM w0.102: 68.77,71.51 68.77,70.69 68.87,70.59 68.87,70.16 68.87,70.16 XU1.B32
  BOTTOM w0.127: v1(33.56,87.89) 32.94,87.28 XMM1.22 ; 68.77,71.51 68.19,72.09 68.19,73.31 67.89,73.62 67.89,75.03 v2(61.49,81.43) 59.22,83.7 v1(58.16,83.7)
M_CHA_DQ9: length 49.2
  IN1 w0.127: v1(34.45,87.89) 35.6,89.04 37.57,89.04 37.82,89.29 50.7,89.29 56.79,83.19 v1(57.02,83.19)
  BOTTOM w0.102: 67.35,73.6 67.98,72.97 67.98,72 68.54,71.43 68.54,70.63 68.66,70.51 68.66,70.08 68.58,69.99 68.58,69.73 68.72,69.59 68.87,69.44 XU1.C32
  BOTTOM w0.127: XMM1.24 33.24,86.68 v1(34.45,87.89) ; v1(57.02,83.19) 57.05,83.16 59,83.16 v2(62.81,79.36) 67.35,74.82 67.35,73.6
M_CHA_DQ10: length 49.7
  IN1 w0.127: v1(36.89,84.35) 36.89,83.65 37.1,83.45 40.05,83.45 40.82,82.68 44.65,82.68 44.77,82.56 44.77,82.2 44.65,82.08 41.09,82.08 40.96,81.95 40.96,81.58 41.09,81.45 44.84,81.45 47.06,79.23 55.83,79.23 v1(56.2,79.59)
  BOTTOM w0.102: 63.35,74.08 64.49,72.93 65.3,72.93 66.49,71.74 66.49,71.73 66.57,71.65 66.57,70.59 66.72,70.44 66.72,70.06 66.63,69.98 66.63,69.72 66.73,69.62 66.73,69.45 66.93,69.26 XU1.C36
  BOTTOM w0.127: 63.35,74.08 60.3,77.12 58.67,77.12 v2(57.13,78.66) v1(56.2,79.59) ; XMM1.35 38.06,83.38 37.99,83.45 37.94,83.45 37.87,83.52 37.72,83.52 v1(36.89,84.35)
M_CHA_DQ11: length 50.8
  IN1 w0.127: v1(33.56,84.28) 33.56,85.22 33.76,85.41 35.32,85.41 35.32,85.41 36.39,85.41 36.39,85.41 47.33,85.41 47.46,85.29 47.46,84.17 47.59,84.04 49.45,84.04 49.57,83.91 49.57,83.4 49.45,83.27 48.79,83.27 48.66,83.14 48.66,82.84 48.79,82.71 50.46,82.71 50.59,82.58 50.59,82.18 50.46,82.05 48.68,82.05 48.56,81.92 48.56,81.42 48.75,81.23 53.76,81.23 v1(55.14,79.85)
  BOTTOM w0.102: XU1.A37 66.36,70.32 66.36,71.56 66.29,71.64 66.29,71.66 65.22,72.73 65.2,72.73 65.03,72.73 65.03,72.73 64.37,72.73 63.16,73.94
  BOTTOM w0.127: 63.16,73.94 62.73,73.94 v2(61.08,75.58) 60.08,76.59 58.39,76.59 v1(55.14,79.85) ; XMM1.34 32.96,83.68 v1(33.56,84.28)
M_CHA_DQ12: length 49.5
  IN1 w0.127: v1(36.82,88.42) 36.82,87.97 36.9,87.89 37.48,87.89 50.59,87.89 56.38,82.1 56.83,82.1 56.83,82.1 58.29,82.1 58.56,81.82 58.56,79.29 58.69,79.16 59.05,79.16 59.17,79.29 v1(59.17,81.48)
  BOTTOM w0.102: 66.28,74.08 66.28,73.7 67.48,72.5 67.48,71.91 68.14,71.25 68.14,70.43 68.1,70.4 68.1,70.08 68.25,69.93 68.25,69.8 68.38,69.66 XU1.C33
  BOTTOM w0.127: v1(36.82,88.42) 38.26,86.98 XMM1.23 ; v1(59.17,81.48) v2(65.2,75.46) 66.28,74.38 66.28,74.08
M_CHA_DQ13: length 49.5
  IN1 w0.127: v1(58.01,82.63) 59.58,82.63 59.71,82.5 59.71,81.72 59.83,81.59 60.06,81.59 60.19,81.72 60.19,82.99 60.06,83.12 57.68,83.12 57.55,82.99 57.55,82.76 57.42,82.63 56.6,82.63 50.48,88.75 38.04,88.75 v1(37.71,88.42)
  BOTTOM w0.102: 67.53,72.99 67.76,72.75 67.76,71.91 68.34,71.34 68.34,70.54 68.38,70.5 XU1.A33
  BOTTOM w0.127: XMM1.21 38.45,87.58 37.71,88.32 v1(37.71,88.42) ; 67.53,72.99 66.81,73.7 66.81,74.6 v2(64.29,77.12) 58.78,82.63 v1(58.01,82.63)
M_CHA_DQ14: length 49.5
  IN1 w0.127: v1(54.3,79.93) 53.77,80.46 48.72,80.46 47.95,81.23 47.95,83.38 47.82,83.51 47.05,83.51 46.93,83.63 46.93,84.75 46.8,84.88 36.62,84.88 36.61,84.88 36.11,84.88 35.96,84.72 35.96,82.69 35.83,82.56 35.35,82.56 35.22,82.69 35.22,84.75 35.1,84.88 34.56,84.88 34.43,84.75 v1(34.43,84.28)
  BOTTOM w0.102: XU1.C37 66.44,69.62 66.28,69.78 66.28,69.96 66.16,70.08 66.16,71.48 65.12,72.52 64.37,72.52 64.2,72.52 63,73.72 62.66,73.72 62.65,73.74 62.16,73.74 61.86,74.04
  BOTTOM w0.127: v1(54.3,79.93) 58.27,75.96 v2(58.95,75.96) 59.94,75.96 61.86,74.04 ; XMM1.36 33.23,83.08 v1(34.43,84.28)
M_CHA_DQ15: length 48.8
  IN1 w0.127: v1(53.6,79.87) 48.37,79.87 45.03,83.22 41.04,83.22 40.91,83.34 40.91,83.68 41.04,83.8 46.12,83.8 46.24,83.93 46.24,84.22 46.12,84.35 39.31,84.35 39.18,84.22 39.18,84.11 39.06,83.98 38.04,83.98 v1(37.68,84.35)
  BOTTOM w0.102: XU1.B38 65.95,71.4 65.03,72.32 64.08,72.32 62.88,73.52 62.58,73.52 62.57,73.53 61.61,73.53 61.57,73.58
  BOTTOM w0.127: v1(53.6,79.87) v2(57.13,76.34) 58.05,75.42 59.72,75.42 61.57,73.58 ; v1(37.68,84.35) 37.97,84.05 38.09,84.05 38.16,83.98 38.21,83.98 38.21,83.98 XMM1.33
M_CHA_DQ16: length 44
  TOP w0.127: v2(32.95,78.39) v1(33.67,77.68)
  IN1 w0.102: 65.3,73.47 65.3,72.72 65.78,72.24 65.78,69.8 66.34,69.23 66.34,68.4 v1(66.47,68.27)
  IN1 w0.127: v1(33.67,77.68) 34.56,78.58 60.56,78.58 65.3,73.84 65.3,73.47
  BOTTOM w0.127: v1(66.47,68.27) 66.5,68.24 66.58,68.24 XU1.F36 ; v1(33.67,77.68) 33.67,77.66 33.09,77.08 XMM1.56
M_CHA_DQ17: length 46.1
  TOP w0.127: v1(66.47,67.61) 67,68.14 v2(67,68.77)
  IN1 w0.102: 64.29,71.87 64.56,71.61 64.56,70.62 66.05,69.13 66.05,68.5 66.05,68.03 v1(66.47,67.61)
  IN1 w0.127: 64.29,71.87 64.29,73.33 60.11,77.51 59.96,77.51 59.83,77.38 59.83,76.29 59.71,76.16 59.48,76.16 59.35,76.29 59.35,77.38 59.23,77.51 58.97,77.51 58.84,77.38 58.84,76.29 58.72,76.16 58.46,76.16 58.34,76.29 58.34,77.38 58.21,77.51 57.93,77.51 57.8,77.38 57.8,76.89 57.68,76.77 57.4,76.77 57.27,76.89 57.27,77.38 57.14,77.51 39.18,77.51 38.75,77.08 38.06,77.08 v1(37.63,77.51)
  BOTTOM w0.127: XMM1.57 37.99,76.78 37.63,77.14 v1(37.63,77.51) ; v1(66.47,67.61) 66.4,67.61 XU1.G38
M_CHA_DQ18: length 45.8
  TOP w0.127: v2(36.97,71.65) v1(36.97,72.58)
  IN1 w0.102: 62.74,70.1 63.02,70.1 63.24,69.89 63.32,69.89 63.91,69.3 63.91,68.02 v1(64.39,67.54)
  IN1 w0.127: v1(36.97,72.58) 36.97,73.82 37.09,73.95 38.68,73.95 38.78,74.05 44.82,74.05 44.95,73.92 44.95,73.86 45.08,73.73 45.33,73.73 45.46,73.86 45.46,73.92 45.58,74.05 45.84,74.05 45.96,73.92 45.96,73.86 46.09,73.73 46.35,73.73 46.47,73.86 46.47,73.92 46.6,74.05 46.85,74.05 46.98,73.92 46.98,73.86 47.11,73.73 47.36,73.73 47.49,73.86 47.49,73.92 47.62,74.05 52.84,74.05 52.96,73.92 52.96,73.74 52.84,73.62 52.34,73.62 52.29,73.57 52.29,73.35 52.48,73.16 53.43,73.16 53.61,73.34 53.81,73.34 53.94,73.21 53.94,72.75 54.07,72.62 54.4,72.62 54.53,72.75 54.53,73.21 54.65,73.34 54.93,73.34 55.06,73.21 55.06,72.75 55.19,72.62 55.49,72.62 55.62,72.75 55.62,73.11 55.75,73.24 56.02,73.24 56.15,73.11 56.15,72.75 56.28,72.62 56.56,72.62 56.69,72.75 56.69,73.11 56.81,73.24 57.09,73.24 57.22,73.11 57.22,72.75 57.35,72.62 57.63,72.62 57.76,72.75 57.76,73.11 57.89,73.24 59.56,73.24 60.93,71.87 61.36,71.87 62.2,71.03 62.2,70.42 62.51,70.1 62.74,70.1
  BOTTOM w0.127: v1(64.39,67.54) 64.33,67.54 XU1.F42 ; XMM1.67 36.49,73.78 36.37,73.65 36.37,72.71 36.49,72.58 v1(36.97,72.58)
M_CHA_DQ19: length 45.4
  TOP w0.127: v2(33.11,71.54) 33.11,71.75 v1(33.64,72.28)
  IN1 w0.102: v1(63.51,66.76) 62.85,67.42 62.85,67.95 62.59,68.21 62.24,68.21 62.19,68.16 61.55,68.16
  IN1 w0.127: 61.55,68.16 61.27,68.44 61.27,68.52 60.7,69.09 60.7,69.35 60.29,69.76 59.6,69.76 58.34,71.02 48.95,71.02 48.82,71.15 48.82,72.01 48.69,72.13 44.33,72.13 43.71,71.51 32,71.51 31.87,71.64 31.87,73.52 32,73.65 32.33,73.65 32.45,73.52 32.45,73 32.58,72.87 32.89,72.87 33.01,73 33.01,73.52 33.14,73.65 33.51,73.65 33.64,73.52 v1(33.64,72.28)
  BOTTOM w0.127: XU1.J42 63.69,66.76 v1(63.51,66.76) ; v1(33.64,72.28) 33.63,72.28 33.03,72.88 XMM1.70
M_CHA_DQ20: length 45.1
  IN1 w0.102: 63.88,71.94 64.33,71.49 64.33,70.56 65.85,69.04 65.85,67.31 v1(65.43,66.89)
  IN1 w0.127: v1(36.82,77.51) 37.78,76.54 47.32,76.54 47.75,76.98 55.64,76.98 55.77,76.85 55.77,75.75 55.9,75.62 56.13,75.62 56.25,75.75 56.25,76.87 56.36,76.98 56.61,76.98 56.74,76.85 56.74,75.75 56.87,75.62 57.17,75.62 57.29,75.75 57.29,76.06 57.37,76.13 57.75,76.13 57.88,76.01 57.88,75.75 58.01,75.62 61.24,75.62 62.88,73.99 63.88,72.99 63.88,71.94
  BOTTOM w0.127: v1(65.43,66.89) 65.26,66.89 XU1.G40 ; XMM1.59 37.85,76.18 37.7,76.33 36.9,76.33 36.54,76.69 36.54,77.24 v1(36.82,77.51)
M_CHA_DQ21: length 44.7
  TOP w0.127: v2(35.5,77.3) 34.93,77.3 v1(34.56,77.68)
  IN1 w0.127: v1(65.32,71.44) 65.32,71.44 65.32,72.16 64.71,72.77 64.71,73.67 60.34,78.04 36.39,78.04 36.26,77.92 36.26,77.28 36.14,77.15 35.83,77.15 35.7,77.28 35.7,77.92 35.58,78.04 34.92,78.04 v1(34.56,77.68)
  BOTTOM w0.102: v1(65.32,71.44) 65.75,71.01 65.75,70.08 65.66,69.99 65.66,69.73 65.95,69.44 XU1.C38
  BOTTOM w0.127: v1(34.56,77.68) 34.84,77.68 34.97,77.55 34.97,76.61 34.84,76.48 XMM1.58
M_CHA_DQ22: length 45.1
  TOP w0.127: v1(34.45,72.28) v2(34.45,73.01)
  IN1 w0.102: v1(63.49,67.41) 63.49,67.38 63.06,67.81 63.06,68.62 62.36,69.31
  IN1 w0.127: 62.36,69.31 61.78,69.31 60.95,70.14 60.06,70.14 59.35,70.85 59.35,71.64 59.11,71.89 58.69,71.89 58.36,71.55 49.48,71.55 49.35,71.68 49.35,71.99 49.48,72.12 51.64,72.12 51.77,72.25 51.77,72.36 51.46,72.67 44.11,72.67 43.49,72.04 36.47,72.04 36.34,72.17 36.34,72.55 36.21,72.68 35.93,72.68 35.81,72.55 35.81,72.17 35.68,72.04 35.35,72.04 35.22,72.17 35.22,72.45 34.82,72.86 34.58,72.86 34.45,72.73 v1(34.45,72.28)
  BOTTOM w0.127: v1(63.49,67.41) 63.27,67.19 XU1.G44 ; XMM1.68 34.21,73.48 34.45,73.24 v1(34.45,72.28)
M_CHA_DQ23: length 45.5
  TOP w0.127: v2(37,73.39) 37.65,72.74 v1(37.65,72.58)
  IN1 w0.102: 61.35,71.02 61.35,70.38 62.04,69.68 63.24,69.68 63.49,69.43 v1(63.49,68.74)
  IN1 w0.127: v1(37.65,72.58) 37.5,72.73 37.5,73.29 37.63,73.41 38.12,73.41 38.93,72.6 43.29,72.6 43.42,72.73 43.42,72.94 43.29,73.07 39.16,73.07 39.03,73.2 39.03,73.39 39.16,73.51 43.73,73.51 44.05,73.2 51.69,73.2 52.36,72.53 52.36,72.21 52.49,72.09 52.75,72.09 52.88,72.21 52.88,72.55 52.95,72.63 53.38,72.63 53.43,72.58 53.43,72.21 53.56,72.09 58.14,72.09 58.26,72.21 58.26,72.58 58.39,72.7 59.2,72.7 60.09,71.81 60.09,71.43 60.22,71.31 61.05,71.31 61.35,71.02
  BOTTOM w0.127: v1(37.65,72.58) 37.65,73.05 37.78,73.18 XMM1.69 ; v1(63.49,68.74) 63.67,68.56 XU1.D42
M_CHA_DQ24: length 43.6
  TOP w0.127: v1(36.77,82.93) 36.48,82.93 36.35,83.06 36.35,83.67 36.48,83.8 38.34,83.8 38.85,84.31 v2(41.29,84.31) 43.24,84.31 43.36,84.18 43.36,83.59 43.49,83.47 43.83,83.47 43.96,83.59 43.96,84.18 44.09,84.31 44.44,84.31 44.57,84.18 44.57,83.59 44.7,83.47 45.57,83.47 45.69,83.59 45.69,83.76 45.57,83.88 45.38,83.88 45.26,84.01 45.26,84.19 45.38,84.31 46.91,84.31 53.13,78.1 58.28,78.1 62.83,73.55 62.83,72.64 v1(62.77,72.59)
  BOTTOM w0.102: XU1.A41 64.42,70.31 64.42,71.3 63.13,72.59 v1(62.77,72.59)
  BOTTOM w0.127: v1(36.77,82.93) 38.13,81.58 XMM1.41
M_CHA_DQ25: length 43
  TOP w0.127: v1(63.02,72) 63.02,72.02 63.2,72.2 63.2,73.93 58.5,78.63 53.35,78.63 47.13,84.85 v2(39.51,84.85) 36.77,84.85 v1(34.4,82.48)
  BOTTOM w0.102: v1(63.02,72) 63.43,72 64.21,71.22 64.21,70.07 64.34,69.94 64.34,69.65 XU1.C41
  BOTTOM w0.127: v1(34.4,82.48) 34.4,82.46 33.22,81.28 XMM1.42
M_CHA_DQ26: length 42.7
  TOP w0.127: v1(36.75,79.16) 37.73,80.14 38.76,80.14 39.34,79.55 v2(40.3,79.55) 47.67,79.55 51.95,75.28 57.03,75.28 v1(58.63,73.67)
  BOTTOM w0.102: XU1.A45 62.55,70.45 62.59,70.49 62.59,71.17 61.91,71.85 61.39,71.85 60.99,72.25 60.57,72.25 59.94,72.88 59.94,74.08
  BOTTOM w0.127: XMM1.53 38.42,77.98 38.31,78.09 37.89,78.09 37.71,78.27 37.13,78.27 36.75,78.65 v1(36.75,79.16) ; v1(58.63,73.67) 58.63,74.15 58.51,74.28 55.95,74.28 55.82,74.41 55.82,74.71 55.95,74.84 59.2,74.84 59.33,74.71 59.33,74.61 59.45,74.48 59.81,74.48 59.94,74.35 59.94,74.08
M_CHA_DQ27: length 42.9
  TOP w0.127: v1(37.64,79.16) 38.09,79.61 38.53,79.61 39.12,79.02 v2(42.69,79.02) 47.45,79.02 47.57,78.89 47.57,78.62 47.45,78.5 45.26,78.5 45.13,78.37 45.13,78.04 45.26,77.91 48.56,77.91 48.67,77.8 48.67,77.42 48.61,77.35 46.4,77.35 46.27,77.23 46.27,76.83 46.4,76.7 49.76,76.7 51.72,74.74 56.81,74.74 v1(57.88,73.67)
  BOTTOM w0.102: 58.43,73.12 58.46,73.08 59.35,73.08 60.47,71.97 60.99,71.97 61.5,71.46 61.5,71.45 62.02,71.45 62.39,71.09 62.39,70.57 62.26,70.44 62.26,70.06 62.04,69.85 XU1.B46
  BOTTOM w0.127: v1(37.64,79.16) 38.17,78.62 38.5,78.62 38.54,78.58 XMM1.51 ; v1(57.88,73.67) 58.43,73.12
M_CHA_DQ28: length 42.9
  TOP w0.127: v1(62.39,73.11) 62.39,73.23 58.06,77.56 52.91,77.56 v2(47.13,83.34) 46.69,83.78 46.42,83.78 46.3,83.65 46.3,83.06 46.17,82.93 45.57,82.93 45.45,82.81 45.45,82.66 45.32,82.53 44.3,82.53 44.18,82.66 44.18,82.81 44.05,82.93 42.99,82.93 42.87,83.06 42.87,83.4 42.74,83.52 42.38,83.52 42.26,83.4 42.26,83.06 42.13,82.93 41.8,82.93 41.67,83.06 41.67,83.65 41.55,83.78 41.22,83.78 41.09,83.65 41.09,83.06 40.96,82.93 40.68,82.93 40.56,83.06 40.56,83.65 40.43,83.78 40.15,83.78 40.02,83.65 40.02,83.06 39.9,82.93 39.62,82.93 39.49,83.06 39.49,83.63 39.34,83.78 39.07,83.78 38.56,83.27 38.01,83.27 v1(37.67,82.93)
  BOTTOM w0.102: XU1.C40 64.98,69.44 64.69,69.73 64.69,69.98 64.78,70.06 64.78,70.08 64.78,70.4 64.66,70.52 64.66,71.35 62.9,73.11 v1(62.39,73.11)
  BOTTOM w0.127: v1(37.67,82.93) 37.67,82.87 38.37,82.18 XMM1.39
M_CHA_DQ29: length 43.3
  TOP w0.127: v1(64.87,71.89) 64.87,71.91 64.48,72.29 63.7,73.08 63.7,74.19 58.72,79.16 53.57,79.16 47.19,85.54 36.63,85.54 v2(35.62,84.53) v1(33.56,82.48)
  BOTTOM w0.102: XU1.B40 64.98,70.48 64.87,70.6 v1(64.87,71.89)
  BOTTOM w0.127: XMM1.40 32.99,81.88 33.56,82.46 v1(33.56,82.48)
M_CHA_DQ30: length 42.3
  TOP w0.127: v1(56.13,73.67) 56.12,73.68 50.67,73.68 50.45,73.89 50.45,74.45 50.32,74.57 47.16,74.57 47.03,74.7 47.03,74.99 47.16,75.12 48.18,75.12 48.3,75.24 48.3,75.51 48.18,75.64 45.96,75.64 v2(44.34,77.25) 43.64,77.95 35.24,77.95 34.58,78.62 33.84,78.62 33.72,78.74 v1(33.72,79.48)
  BOTTOM w0.102: 61.33,70.88 61.34,70.87 61.34,70.1 61.13,69.9 61.1,69.9 XU1.B48
  BOTTOM w0.127: 61.33,70.88 61.33,70.95 60.9,71.38 60.24,71.38 59.33,72.3 57.5,72.3 56.79,73.01 54.6,73.01 54.48,73.14 54.48,73.54 54.6,73.67 v1(56.13,73.67) ; XMM1.50 33.11,78.88 33.71,79.48 v1(33.72,79.48)
M_CHA_DQ31: length 43
  TOP w0.127: v1(34.61,79.48) 34.61,80.84 34.73,80.97 34.95,80.97 35.08,80.84 35.08,79.61 35.2,79.48 36.09,79.48 36.21,79.35 36.21,79.1 36.09,78.98 35.55,78.98 35.42,78.85 35.42,78.58 35.51,78.49 v2(38.73,78.49) 43.86,78.49 46.18,76.17 49.54,76.17 49.67,76.04 49.67,75.78 49.54,75.65 48.96,75.65 48.84,75.52 48.84,75.23 48.96,75.11 50.61,75.11 51.5,74.21 56.52,74.21 v1(57.06,73.67)
  BOTTOM w0.102: XU1.B47 61.7,69.91 61.82,69.91 62.05,70.15 62.05,70.52 62.18,70.66 62.18,71 61.94,71.25 61.4,71.25 60.96,71.69 60.34,71.69 59.33,72.7 58.03,72.7 58.02,72.71
  BOTTOM w0.127: v1(34.61,79.48) 34.6,79.48 33.4,78.28 XMM1.52 ; v1(57.06,73.67) 58.02,72.71
M_CHA_DQ32: length 43.8
  TOP w0.127: v1(33.57,53.08) 33.57,52.03 33.75,51.85 33.75,50.89 33.9,50.73 34.16,50.73 34.28,50.86 34.28,52.04 34.35,52.11 v2(35.17,52.11) 36.47,52.11 36.47,52.11 37.59,52.11 37.62,52.08 39.96,52.08 40.59,52.71 41.81,53.93 v1(44.3,53.93)
  BOTTOM w0.102: XU1.K52 58.24,65.71 58.04,65.51 57.28,65.51 57.28,65.51 56.99,65.51 56.86,65.64 56.45,65.64 55.44,66.65 55.44,67.12 55.21,67.34
  BOTTOM w0.127: v1(33.57,53.08) 32.97,52.48 XMM1.130 ; v1(44.3,53.93) 44.29,53.94 44.29,61.57 51.07,68.34 54.21,68.34 55.21,67.34
M_CHA_DQ33: length 44.4
  TOP w0.127: v1(34.53,53.08) 34.89,53.44 35.27,53.44 35.4,53.31 35.4,52.77 35.53,52.65 v2(36.9,52.65) 37.81,52.65 37.84,52.61 39.74,52.61 41.59,54.47 44.04,54.47 44.16,54.59 44.16,55.84 44.29,55.97 45.2,55.97 45.33,55.84 45.33,54.7 45.2,54.57 v1(44.85,54.57)
  BOTTOM w0.102: XU1.K51 59.28,65.71 58.99,65.42 58.73,65.42 58.65,65.51 58.33,65.51 58.12,65.3 57.18,65.3 57.17,65.31 56.87,65.31 56.76,65.41
  BOTTOM w0.127: v1(34.53,53.08) 33.33,51.88 XMM1.132 ; v1(44.85,54.57) 44.82,54.59 44.82,61.35 51.29,67.81 53.97,67.81 56.37,65.41 56.76,65.41
M_CHA_DQ34: length 44.7
  TOP w0.127: v1(36.54,49.52) 37.41,48.66 40.07,48.66 40.2,48.53 40.2,47.96 40.33,47.84 40.78,47.84 40.91,47.96 v2(40.91,48.19) 40.91,48.52 41.04,48.66 41.6,48.66 41.67,48.58 41.67,47.89 41.8,47.76 42.14,47.76 42.27,47.89 42.27,49.32 42.46,49.51 42.82,49.51 42.99,49.34 42.99,47.86 43.1,47.76 43.45,47.76 43.6,47.91 43.6,50.66 44.03,51.08 48.11,51.08 49.6,52.58 v1(50.63,52.58)
  BOTTOM w0.102: 56.57,63.04 58,63.04 58.24,62.8 XU1.T52
  BOTTOM w0.127: 56.57,63.04 54.79,63.04 54.44,63.39 53.32,63.39 50.59,60.66 50.59,52.61 v1(50.63,52.58) ; XMM1.143 37.48,48.58 v1(36.54,49.52)
M_CHA_DQ35: length 44.7
  TOP w0.127: v1(51.12,53.12) 51.4,53.12 51.99,53.71 51.99,54.03 51.86,54.16 50.49,54.16 50.36,54.29 50.36,54.87 50.49,55 51.88,55 52.01,55.13 52.01,55.84 51.88,55.97 49.65,55.97 49.52,55.84 49.52,53.25 47.89,51.62 43.81,51.62 41.38,49.19 v2(39.21,49.19) 37.81,49.19 v1(37.48,49.52)
  BOTTOM w0.102: 56.65,62.81 57.93,62.81 58.14,62.6 58.64,62.6 58.73,62.51 58.99,62.51 59.28,62.8 XU1.T51
  BOTTOM w0.127: 56.65,62.81 54.44,62.81 54.39,62.86 53.54,62.86 51.12,60.44 v1(51.12,53.12) ; v1(37.48,49.52) 37.82,49.18 XMM1.141
M_CHA_DQ36: length 44.6
  TOP w0.127: v1(46.4,54.39) 47.2,55.2 47.87,55.2 48,55.32 48,57.36 47.87,57.49 v2(46.04,57.49) 43.86,57.49 43.1,56.73 43.1,55.99 42.69,55.58 40.81,55.58 39.31,54.09 37.24,54.09 v1(36.73,53.58)
  BOTTOM w0.102: 56.95,64.86 58.56,64.86 58.78,65.08 59.08,65.08 XU1.L51
  BOTTOM w0.127: 56.95,64.86 55.96,64.86 54.08,66.74 51.73,66.74 45.89,60.9 45.89,55.62 46.4,55.12 v1(46.4,54.39) ; XMM1.131 37.73,52.18 36.73,53.18 v1(36.73,53.58)
M_CHA_DQ37: length 43.8
  TOP w0.127: v1(37.65,53.55) 38.06,53.15 39.29,53.15 v2(39.86,53.72) 41.19,55.05 43.27,55.05 43.63,55.41 43.63,56.51 44.08,56.96 45.53,56.96 45.66,56.83 45.66,56.6 45.79,56.47 46.25,56.47 46.37,56.6 46.37,56.83 46.5,56.96 47.31,56.96 47.44,56.83 47.44,55.91 47.31,55.79 46.07,55.79 45.86,55.58 v1(45.86,53.93)
  BOTTOM w0.102: 57.07,65.09 58.22,65.09 58.35,65.23 XU1.L53
  BOTTOM w0.127: XMM1.129 38.06,52.78 37.65,53.18 v1(37.65,53.55) ; 57.07,65.09 56.37,65.09 54.18,67.28 51.51,67.28 45.36,61.12 45.36,54.44 v1(45.86,53.93)
M_CHA_DQ38: length 44.8
  TOP w0.127: v1(34.8,49.48) 37.05,47.23 43.14,47.23 44.36,46.01 v2(44.67,46.01) 47.3,46.01 48.71,47.43 48.71,50.93 49.79,52 v1(50.05,52)
  BOTTOM w0.102: 55.21,63.31 58.02,63.31 58.33,63.01 58.65,63.01 58.76,63.12 59.06,63.12 XU1.R51
  BOTTOM w0.127: 55.21,63.31 54.98,63.31 54.36,63.93 53.1,63.93 ; v1(50.05,52) 50.06,52.01 50.06,60.88 53.1,63.93 ; v1(34.8,49.48) 34.8,48.99 34.69,48.88 XMM1.142 ; 53.1,63.93 53.1,63.92 53.1,63.93
M_CHA_DQ39: length 44.9
  TOP w0.127: v1(49.52,50.86) 49.25,50.58 v2(49.25,49.11) 49.25,47.2 47.52,45.48 44.14,45.48 42.92,46.69 36.83,46.69 34.05,49.48 33.27,49.48 v1(33.27,49.47)
  BOTTOM w0.102: 55.21,63.56 58.21,63.56 XU1.R53
  BOTTOM w0.127: XMM1.140 33.27,49.48 v1(33.27,49.47) ; v1(49.52,50.86) 49.52,51.78 49.52,51.78 49.52,52.23 49.52,52.23 49.52,61.1 52.88,64.46 54.31,64.46 55.21,63.56
M_CHA_DQ40: length 43.2
  TOP w0.102: v1(61.16,63.24) 61.16,62.9 v2(60.85,62.59)
  IN1 w0.102: 57.56,62.81 60.73,62.81 v1(61.16,63.24)
  IN1 w0.127: v1(37.72,47.98) 37.72,48.66 37.03,49.36 37.03,49.95 37.4,50.32 39.11,50.32 39.24,50.45 39.24,50.94 39.11,51.06 37.81,51.06 37.69,51.19 37.69,52.39 37.81,52.51 39.77,52.51 39.9,52.39 39.9,50.45 40.02,50.32 40.34,50.32 40.6,50.58 40.6,51.7 46.91,58.02 52.11,58.02 56.39,62.29 57.04,62.29 57.56,62.81
  BOTTOM w0.127: v1(61.16,63.24) 61.55,62.85 XU1.T47 ; v1(37.72,47.98) 38.32,47.38 XMM1.147
M_CHA_DQ41: length 43
  TOP w0.127: v1(37.03,48.08) v2(36.23,48.87)
  IN1 w0.102: 58.13,61.83 58.9,62.6 61.16,62.6 v1(61.82,63.26)
  IN1 w0.127: 58.13,61.83 56.68,61.83 52.34,57.48 47.15,57.48 41.13,51.46 41.13,50.14 40.46,49.47 40.28,49.47 39.97,49.79 39.79,49.79 39.61,49.61 39.61,49.43 39.92,49.11 39.92,48.93 39.74,48.75 39.56,48.75 39.25,49.07 39.07,49.07 38.89,48.89 38.89,48.71 39.2,48.39 39.2,48.21 38.44,47.45 35.89,47.45 35.77,47.57 35.77,47.86 35.98,48.08 v1(37.03,48.08)
  BOTTOM w0.127: v1(61.82,63.26) 62.26,62.83 XU1.T45 ; v1(37.03,48.08) 37.03,46.95 37.2,46.78 XMM1.149
M_CHA_DQ42: length 42.4
  TOP w0.102: 64.97,61.25 64.84,61.37 v1(64.75,61.37)
  TOP w0.127: 64.97,61.25 65.35,61.25 v2(65.45,61.15)
  IN1 w0.102: 58.21,59.42 58.21,59.75 59.4,60.94 60.12,60.94 60.13,60.92 64.3,60.92 v1(64.75,61.37)
  IN1 w0.127: 58.21,59.42 57.4,58.6 57.4,58.56 50.13,51.29 45.75,51.29 43.95,49.49 43.95,48.97 38.99,44.01 33.48,44.01 v1(33.41,44.08)
  BOTTOM w0.127: v1(64.75,61.37) 64.75,61.22 XU1.Y40 ; XMM1.158 v1(33.41,44.08)
M_CHA_DQ43: length 42.2
  IN1 w0.102: v1(64.05,61.43) 63.48,62 59.39,62 58.18,60.79 57.68,60.79 57.43,60.54
  IN1 w0.127: 57.43,60.54 57.12,60.23 57.12,59.79 51.88,54.55 49.4,54.55 48.25,53.4 46.6,53.4 46.4,53.2 46.4,52.67 46.19,52.46 44.84,52.46 42.88,50.5 42.88,49.41 39.02,45.55 37.59,45.55 37.5,45.64 36.84,45.64 35.74,44.55 v1(34.74,44.55)
  BOTTOM w0.127: XU1.V41 64.39,61.77 v1(64.05,61.43) ; v1(34.74,44.55) 33.68,43.48 XMM1.160
M_CHA_DQ44: length 45
  TOP w0.127: v1(33.56,47.86) 33.21,47.86 32.66,48.42 32.66,49.74 v2(32.53,49.87)
  IN1 w0.102: v1(60.51,63.23) 60.07,63.66 59.51,63.66 59.45,63.61
  IN1 w0.127: v1(33.56,47.86) 33.69,47.99 33.69,48.56 34.28,49.16 34.28,49.92 34.41,50.05 35.5,50.05 35.63,50.17 35.63,51.27 35.5,51.39 34.21,51.39 34.08,51.52 34.08,54.01 34.21,54.13 41.42,54.13 46.58,59.29 51.88,59.29 55.61,63.02 57.01,63.02 57.35,63.36 59.2,63.36 59.45,63.61
  BOTTOM w0.127: v1(33.56,47.86) 33.38,47.68 XMM1.146 ; XU1.T48 60.84,62.9 v1(60.51,63.23)
M_CHA_DQ45: length 43.1
  TOP w0.127: v2(33.9,48.78) v1(34.4,48.28)
  IN1 w0.102: 57.07,62.72 57.42,63.08 59.65,63.08 v1(59.81,63.24)
  IN1 w0.127: v1(34.4,48.28) 34.71,47.97 34.71,47.35 34.59,47.23 33.69,47.23 33.56,47.1 33.56,46.85 33.69,46.73 35.11,46.73 35.23,46.85 35.23,48.82 36.3,49.89 36.3,52.07 37.28,53.05 41.19,53.05 46.75,58.61 51.95,58.61 56.06,62.72 57.07,62.72
  BOTTOM w0.127: XU1.T50 60.16,62.89 v1(59.81,63.24) ; v1(34.4,48.28) 34.4,47.81 33.68,47.08 XMM1.148
M_CHA_DQ46: length 43.9
  TOP w0.127: v2(38.24,43.98) 38.24,43.72 v1(37.71,43.18)
  IN1 w0.102: v1(63.31,60.27) 62.86,60.72 60.05,60.72 60.03,60.74 59.58,60.74 58.79,59.95
  IN1 w0.127: 58.79,59.95 58.79,58.78 58.01,57.99 57.59,57.99 50.02,50.43 48.43,50.43 48.28,50.28 48.28,49.89 48.73,49.44 48.73,47.45 47.3,46.01 43.39,46.01 42.98,45.61 42.8,45.61 42.47,45.94 42.29,45.94 42.02,45.67 42.02,45.49 42.35,45.16 42.35,44.98 42.08,44.71 41.9,44.71 41.57,45.04 41.39,45.04 41.12,44.77 41.12,44.59 41.45,44.26 41.45,44.08 41.19,43.81 41.01,43.81 40.67,44.14 40.49,44.14 40.22,43.87 40.22,43.69 40.56,43.36 40.56,43.18 40.12,42.75 38.14,42.75 v1(37.71,43.18)
  BOTTOM w0.127: v1(37.71,43.18) 38.3,43.78 XMM1.159 ; XU1.Y42 63.31,60.49 v1(63.31,60.27)
M_CHA_DQ47: length 43.6
  TOP w0.127: v1(36.91,43.18) 36.91,42.9 v2(37.28,42.53)
  IN1 w0.102: v1(64.83,59.39) 64.39,58.96 64,58.96 63.75,59.22 63.75,59.55 63.46,59.83 59.58,59.83 59.33,59.58 59.33,58.56
  IN1 w0.127: v1(36.91,43.18) 37.87,42.21 40.34,42.21 43.61,45.48 47.52,45.48 49.27,47.23 49.27,49.44 49.73,49.89 50.24,49.89 57.81,57.46 58.23,57.46 59.33,58.56
  BOTTOM w0.127: v1(64.83,59.39) 64.83,59.6 XU1.AB40 ; XMM1.157 37.1,44.38 36.91,44.19 v1(36.91,43.18)
M_CHA_DQ48: length 44.4
  TOP w0.102: v1(61.87,61.34) 61.87,61.41 v2(62.53,62.06)
  IN2 w0.102: 57.04,61.88 58.2,61.88 58.5,62.19 61.03,62.19 v1(61.87,61.34)
  IN2 w0.127: v1(33.93,42.94) 33.93,43.39 34.26,43.72 34.74,43.72 35.7,44.69 35.7,45.14 35.83,45.27 36.31,45.27 36.44,45.14 36.44,44.87 36.63,44.68 37.68,44.68 37.86,44.87 37.86,45.28 37.99,45.41 38.75,45.41 38.88,45.28 38.88,44.8 39.01,44.68 39.56,44.68 39.69,44.8 39.69,46.73 44.86,51.91 47.65,51.91 56.09,60.35 56.09,60.93 57.04,61.88
  BOTTOM w0.127: v1(33.93,42.94) 33.27,42.28 XMM1.164 ; v1(61.87,61.34) 62.06,61.53 62.06,61.64 XU1.V45
M_CHA_DQ49: length 45.6
  IN2 w0.102: v1(61.19,61.34) 60.55,61.98 58.66,61.98 58.29,61.6 57.29,61.6 57.23,61.54
  IN2 w0.127: 57.23,61.54 56.61,60.92 56.61,60.1 47.88,51.37 45.08,51.37 42.23,48.53 42.23,47.28 42.03,47.08 41.07,47.08 40.22,46.23 40.22,44.33 40.03,44.14 35.91,44.14 35.52,43.75 35.52,41.18 35.4,41.06 34.64,41.06 34.51,41.18 34.51,42.78 v1(34.61,42.88)
  BOTTOM w0.127: v1(34.61,42.88) 34.51,42.78 34.51,42.58 33.61,41.68 XMM1.166 ; XU1.V47 61.55,61.7 v1(61.19,61.34)
M_CHA_DQ50: length 46.1
  TOP w0.127: v1(37.05,37.88) 36.59,37.42 v2(36.59,37.17)
  IN2 w0.127: v1(37.05,37.88) 37.05,37.63 36.95,37.52 36.25,37.52 36.12,37.4 36.12,37.09 36.25,36.97 38.86,36.97 45.09,43.19 48.59,43.19 51.61,46.22 51.61,47.26 53.74,49.39 53.74,50.05 55.6,51.92 55.6,52.1 55.01,52.69 55.01,52.87 55.19,53.05 55.37,53.05 55.96,52.45 56.14,52.45 58.89,55.21 58.89,56.57 59.33,57.01 59.33,57.68 60.44,58.79 v1(60.44,59.41)
  BOTTOM w0.127: v1(37.05,37.88) 37.05,38.41 36.93,38.53 36.55,38.53 36.42,38.66 36.42,38.85 36.55,38.98 XMM1.175 ; v1(60.44,59.41) 60.44,59.41 60.89,58.95 XU1.AD48
M_CHA_DQ51: length 46.1
  TOP w0.127: v2(38.35,37.09) 38.35,37.22 v1(37.71,37.86)
  IN2 w0.127: v1(37.71,37.86) 37.71,37.66 37.86,37.5 38.64,37.5 43.57,42.43 43.57,43.6 43.7,43.73 48.26,43.73 51.08,46.54 51.08,48.28 53.21,50.4 53.21,51.31 53.74,51.85 54.15,51.85 54.22,51.78 54.48,51.78 54.72,52.01 54.72,52.19 54.31,52.6 54.31,52.98 57.07,55.74 57.24,55.74 57.47,55.51 57.47,55.33 55.85,53.7 55.85,53.5 56.02,53.32 56.25,53.32 58.36,55.43 58.36,56.79 58.79,57.23 58.79,57.9 59.75,58.86 v1(59.75,59.41)
  BOTTOM w0.127: v1(59.75,59.41) 59.78,59.41 XU1.AD50 ; v1(37.71,37.86) 37.71,38.24 37.85,38.38 XMM1.177
M_CHA_DQ52: length 44.6
  TOP w0.127: v2(36.52,44.15) 36.14,43.78 v1(36.14,43.18)
  IN2 w0.102: v1(60.51,61.34) 60.07,61.78 59.17,61.78 58.49,61.1 57.68,61.1
  IN2 w0.127: v1(36.14,43.18) 36.57,43.61 40.37,43.61 40.75,44 40.75,45.72 41.58,46.55 42.61,46.55 42.77,46.7 42.77,48.29 42.89,48.42 43.17,48.42 43.3,48.29 43.3,46.67 43.42,46.55 43.76,46.55 43.89,46.68 43.89,49.43 45.3,50.84 48.18,50.84 54.91,57.57 54.91,57.65 55.64,58.38 55.72,58.38 56.99,59.65 56.99,60.76 57.33,61.1 57.68,61.1
  BOTTOM w0.127: v1(36.14,43.18) 36.74,42.58 XMM1.163 ; XU1.V48 60.84,61.67 v1(60.51,61.34)
M_CHA_DQ53: length 46.6
  TOP w0.127: v2(36.29,41.06) 36.29,41.84 36.18,41.95 v1(36.18,42.35)
  IN2 w0.102: v1(59.83,61.36) 59.26,61.36 58.69,60.79 58.05,60.79
  IN2 w0.127: 58.05,60.79 58.03,60.8 57.67,60.8 57.42,60.55 57.42,59.62 56.63,58.84 56.63,58.62 55.45,57.43 55.45,57.35 51.66,53.56 51.66,53 49.99,51.33 49.99,50.54 48.76,49.31 48.76,47.47 47.3,46.01 41.8,46.01 41.29,45.5 41.29,43.4 40.9,43.01 38.8,43.01 37.91,42.12 37.91,40.72 37.78,40.59 37.46,40.59 37.33,40.72 37.33,41.8 37.2,41.93 36.9,41.93 36.77,41.8 36.77,40.72 36.64,40.59 36.31,40.59 36.18,40.72 v1(36.18,42.35)
  BOTTOM w0.127: v1(59.83,61.36) 60.16,61.69 XU1.V50 ; XMM1.165 36.55,41.98 v1(36.18,42.35)
M_CHA_DQ54: length 46.5
  TOP w0.127: v1(33.9,38.08) 34.41,37.57 v2(34.41,37.4)
  IN2 w0.127: v1(33.9,38.08) 33.9,37.81 36.22,35.49 38.89,35.49 45.39,41.99 48.89,41.99 52.74,45.83 52.74,46.84 54.81,48.91 54.81,49.61 60.8,55.61 60.8,57.65 61.23,58.07 61.87,58.07 62.64,58.85 v1(62.64,59.34)
  BOTTOM w0.127: v1(62.64,59.34) 62.64,59.55 XU1.AB44 ; XMM1.176 33.31,38.68 33.9,38.08 v1(33.9,38.08)
M_CHA_DQ55: length 47
  TOP w0.127: v1(34.64,38.08) 35.32,38.77 v2(35.32,38.92)
  IN2 w0.102: 60.88,58.99 60.88,59.57 61.12,59.81 62.11,59.81 v1(62.58,60.28)
  IN2 w0.127: 60.88,58.99 60.88,58.48 60.27,57.87 60.27,56.32 59.45,55.51 59.45,55.02 54.27,49.83 54.27,49.13 52.14,47 52.14,46 48.81,42.66 45.31,42.66 39.08,36.43 36.03,36.43 34.64,37.82 v1(34.64,38.08)
  BOTTOM w0.127: XU1.Y45 62.26,60.61 v1(62.58,60.28) ; v1(34.64,38.08) 34.64,38.16 33.52,39.28 XMM1.174
M_CHA_DQ56: length 45.9
  IN1 w0.127: v1(33.24,36.9) 33.77,37.43 38.45,37.43 39.9,38.88 39.9,39.24 44.48,43.83 48.2,43.83 51.71,47.33 v1(51.71,48.04)
  BOTTOM w0.102: 56.97,62.37 57.51,61.83 58.23,61.83 58.24,61.84 58.74,61.84 58.74,61.83 XU1.V52
  BOTTOM w0.127: XMM1.182 33.06,36.88 33.08,36.9 v1(33.24,36.9) ; 56.97,62.37 53.88,62.37 51.71,60.2 v2(51.71,59.52) v1(51.71,48.04)
M_CHA_DQ57: length 45.5
  IN1 w0.127: v1(52.24,48.78) 52.24,49.54 52.09,49.69 51.62,49.69 51.17,49.24 51.17,47.55 47.98,44.36 44.26,44.36 38.27,38.36 36.82,38.36 v1(36.42,37.96)
  BOTTOM w0.102: 55.21,61.83 57,61.83 57.21,61.62 58.31,61.62 58.32,61.63 58.63,61.63 58.74,61.52 59.05,61.52 XU1.W51
  BOTTOM w0.127: XMM1.181 36.93,37.18 36.42,37.68 v1(36.42,37.96) ; 55.21,61.83 54.1,61.83 52.24,59.98 v2(52.24,57.62) v1(52.24,48.78)
M_CHA_DQ58: length 45.5
  IN1 w0.127: v1(33.93,34.07) 34,34.15 39.17,34.15 41.92,36.89 47.3,36.89 48.91,38.5 48.91,39.58 48.91,40.02 51.28,42.39 51.28,42.39 52.99,44.1 52.99,44.1 53.99,45.1 53.99,48.07 v1(55.59,49.67)
  BOTTOM w0.127: v1(55.59,49.67) v2(55.59,58.07) 55.59,58.57 56.54,59.52 58.29,59.52 58.41,59.4 XU1.AC53 ; XMM1.192 33.73,33.88 v1(33.93,34.07)
M_CHA_DQ59: length 46.6
  IN1 w0.127: v1(55.59,48.88) 54.53,47.81 54.53,44.88 53.21,43.57 53.21,43.57 51.81,42.17 51.81,42.17 49.45,39.8 49.45,38.28 47.52,36.36 42.14,36.36 39.39,33.61 v1(34.41,33.61)
  BOTTOM w0.102: 56.61,58.99 56.92,59.3 58.14,59.3 58.33,59.12 58.65,59.12 58.77,59.24 58.93,59.4 XU1.AC51
  BOTTOM w0.127: v1(34.41,33.61) 34.07,33.28 XMM1.194 ; 56.61,58.99 56.13,58.51 v2(56.13,55.33) 56.13,49.41 v1(55.59,48.88)
M_CHA_DQ60: length 46.2
  IN1 w0.127: v1(35.77,37.96) 35.37,37.96 35.27,38.07 35.27,38.85 35.4,38.97 38.12,38.97 44.04,44.89 47.76,44.89 49.85,46.98 49.85,47.52 49.98,47.65 50.39,47.65 50.51,47.77 50.51,48.24 50.39,48.37 49.98,48.37 49.85,48.5 49.85,49.18 49.98,49.31 50.49,49.31 51.93,50.76 v1(52.77,50.76)
  BOTTOM w0.127: XU1.W53 56.09,61.34 56.05,61.3 54.32,61.3 52.77,59.76 v2(52.77,55.76) v1(52.77,50.76) ; v1(35.77,37.96) 35.77,37.57 36.77,36.58 XMM1.183
M_CHA_DQ61: length 46
  IN1 w0.127: v1(34.59,36.51) 34.61,36.53 36.8,36.53 37.17,36.9 38.67,36.9 40.43,38.66 40.43,39.02 44.71,43.29 48.43,43.29 52.77,47.64 v1(52.77,49.13)
  BOTTOM w0.102: 56.91,61.06 58.66,61.06 58.74,61.13 58.75,61.15 58.99,61.15 59.28,60.86 XU1.Y51
  BOTTOM w0.127: v1(52.77,49.13) 52.77,50 53.31,50.54 v2(53.31,54.01) 53.31,59.53 54.54,60.77 56.62,60.77 56.91,61.06 ; v1(34.59,36.51) 34.59,37.22 34.33,37.48 XMM1.180
M_CHA_DQ62: length 46.1
  TOP w0.127: v2(37.38,33.82) 37.69,33.51 v1(37.69,32.91)
  IN1 w0.127: v1(55.59,48.12) 55.06,47.58 55.06,44.66 53.43,43.04 53.43,43.04 52.35,41.95 52.35,41.95 51,40.6 51,40.16 51,39.14 50.79,38.94 50.63,38.94 50.51,39.05 50.51,39.45 50.39,39.58 50.11,39.58 49.98,39.45 49.98,38.06 47.74,35.82 42.36,35.82 39.08,32.55 38.05,32.55 v1(37.69,32.91)
  BOTTOM w0.102: 56.94,58.73 57.31,59.1 58.06,59.1 58.24,58.91 XU1.AD52
  BOTTOM w0.127: 56.94,58.73 56.66,58.45 56.66,48.37 56.41,48.12 v1(55.59,48.12) ; v1(37.69,32.91) 37.69,33.38 37.88,33.58 XMM1.193
M_CHA_DQ63: length 48.1
  TOP w0.127: v1(37,32.91) 35.92,32.91 v2(35.81,32.8)
  IN1 w0.127: v1(55.59,47.33) 55.59,44.44 53.66,42.5 53.65,42.5 52.88,41.73 52.88,41.73 51.53,40.38 51.53,38.86 47.96,35.29 42.58,35.29 39.3,32.01 37.83,32.01 37,32.85 v1(37,32.91)
  BOTTOM w0.102: XU1.AD51 59.3,58.91 59.01,58.62 58.73,58.62 58.64,58.71 58.16,58.71 57.97,58.9 57.56,58.9 57.19,58.53 57.19,58.4
  BOTTOM w0.127: 57.19,58.4 57.19,47.76 56.76,47.33 v1(55.59,47.33) ; XMM1.191 38.55,34.18 38.52,34.15 37.69,34.15 37,33.46 v1(37,32.91)
M_CHA_DQS0: length 55.9
  IN2 w0.102: 64,73 64,72.98 64,72.97 64,72.91 64.01,72.91 64.01,72.11 64.24,71.87 64.24,71.37 64.53,71.08 64.53,70.18 65.85,68.86 65.85,68.08 65.85,66.33 65.76,66.24 v1(65.45,66.24)
  IN2 w0.114: 64,73 64,73.25 63.54,73.7 63.54,74.48 61.56,76.46 49.42,76.46 49,76.88 49,77.73 48.87,77.86 48.57,77.86 48.44,77.73 48.44,76.79 48.11,76.46 47.62,76.46 47.3,76.78 47.3,83.32 40.18,90.44 35.56,90.44 35.3,90.7 34.34,90.7 34.26,90.62 34.26,90.41 34.16,90.31 v1(33.95,90.31)
  BOTTOM w0.114: XU1.J38 65.96,66.18 65.84,66.05 65.58,66.05 65.45,66.18 v1(65.45,66.24) ; v1(33.95,90.31) 33.62,90.64 32.92,90.64 32.86,90.58 32.86,90.41 32.73,90.28 XMM1.12
M_CHA_DQS0#: length 55.9
  IN2 w0.102: 64.21,73 64.21,72.19 64.45,71.96 64.45,71.45 64.73,71.16 64.73,70.27 64.96,70.04 66.05,68.95 66.05,66.13 v1(65.47,65.54)
  IN2 w0.114: 64.21,73 64.21,73.34 63.78,73.77 63.78,74.58 61.66,76.7 49.52,76.7 49.24,76.98 49.24,77.83 48.97,78.1 48.47,78.1 48.2,77.83 48.2,76.89 48.01,76.7 47.72,76.7 47.54,76.88 47.54,83.42 40.28,90.68 35.66,90.68 35.4,90.94 v1(33.95,90.94)
  BOTTOM w0.114: XMM1.10 33.88,90.88 v1(33.95,90.94) ; v1(65.47,65.54) 65.68,65.76 XU1.K38
M_CHA_DQS1: length 49.1
  IN1 w0.114: v1(35.86,86.7) 36.05,86.89 37.07,86.89 37.07,86.89 38.34,86.89 50.18,86.89 50.31,86.76 50.31,86.45 50.18,86.32 49.02,86.32 48.75,86.05 48.75,85.6 49.02,85.33 51.52,85.33 55.96,80.88 57.17,80.88 v1(57.35,80.7)
  BOTTOM w0.102: 65.17,74.08 65.38,73.87 65.42,73.87 65.43,73.87 66.95,72.35 66.95,71.86 67.73,71.08 67.73,70.62 67.7,70.58 67.7,70.58 67.7,70.08 67.58,69.97 67.58,69.67 XU1.C35
  BOTTOM w0.114: XMM1.29 38.6,85.18 38.42,85.36 38.06,85.36 36.52,86.9 36.05,86.9 v1(35.86,86.7) ; 58.46,80.3 58.01,80.76 57.4,80.76 v1(57.35,80.7) ; 58.46,80.3 v2(58.26,80.1) ; 58.46,80.3 60.09,78.67 60.57,78.67 62.07,77.18 65.1,74.15 65.17,74.08
M_CHA_DQS1#: length 49.1
  IN1 w0.114: v1(35.86,87.33) 36.06,87.13 37.17,87.13 37.17,87.13 38.24,87.13 38.24,87.13 50.28,87.13 50.55,86.86 50.55,86.35 50.28,86.08 49.12,86.08 48.99,85.95 48.99,85.7 49.12,85.57 51.62,85.57 56.06,81.12 57.13,81.12 v1(57.35,81.34)
  BOTTOM w0.102: XU1.B34 67.9,70.48 67.9,70.49 67.9,70.5 67.93,70.53 67.93,71.16 67.15,71.95 67.15,72.44 65.51,74.08
  BOTTOM w0.114: v1(35.86,87.33) 36.05,87.14 36.62,87.14 38.16,85.6 38.42,85.6 38.6,85.78 XMM1.27 ; v1(57.35,81.34) 57.69,81 58.11,81 59.81,79.29 ; 59.81,79.29 v2(60.01,79.49) ; 59.81,79.29 60.19,78.91 60.67,78.91 62.7,76.88 64.83,74.76 65.27,74.32 65.27,74.32 65.51,74.08
M_CHA_DQS2: length 43.9
  IN1 w0.114: v1(33.67,74.48) 33.67,74.61 34.14,75.08 34.28,75.08 34.6,75.4 34.6,76.46 34.73,76.59 34.98,76.59 35.11,76.46 35.11,73.7 35.38,73.43 35.77,73.43 36.03,73.7 36.03,74.68 36.16,74.8 53.15,74.8 53.86,74.09 60.42,74.09 61.43,73.08 62.05,72.46 62.05,71.78 62.7,71.13 62.9,70.94 62.9,70.52 63.29,70.13 63.83,70.13 64.82,69.14 64.82,68.99 64.71,68.88 v1(64.44,68.88)
  BOTTOM w0.114: v1(33.67,74.48) 33.67,74.79 33.62,74.84 33.49,74.84 33.3,75.04 32.93,75.04 32.86,74.96 32.86,74.74 32.8,74.68 XMM1.64 ; XU1.D40 64.69,68.56 64.44,68.81 v1(64.44,68.88)
M_CHA_DQS2#: length 43.9
  IN1 w0.114: v1(64.39,68.22) 65.06,68.89 65.06,69.24 63.93,70.37 63.39,70.37 63.14,70.62 63.14,71.04 62.7,71.47 62.3,71.88 62.3,72.56 62.07,72.79 61.43,73.42 60.69,74.17 60.52,74.34 53.96,74.34 53.25,75.05 36.06,75.05 35.79,74.78 35.79,73.8 35.67,73.67 35.48,73.67 35.35,73.8 35.35,76.56 35.08,76.83 34.63,76.83 34.36,76.56 34.36,75.5 34.18,75.32 v4(33.69,75.32)
  BOTTOM w0.114: v1(64.39,68.22) 64.65,68.22 XU1.F40 ; XMM1.62 33.65,75.28 v4(33.69,75.32)
M_CHA_DQS3: length 43
  TOP w0.114: v1(60.7,72.71) 60.59,72.71 60.2,73.1 59.81,73.1 59.39,73.52 59.39,74.07 57.42,76.03 52.26,76.03 47.97,80.32 45.39,80.32 44.81,80.9 44.58,80.9 44,80.32 43.53,80.32 43.26,80.59 43.26,81.26 43.13,81.39 42.85,81.39 42.73,81.26 42.73,80.58 42.46,80.31 42.03,80.31 41.71,80.63 41.71,81.26 41.58,81.39 41.25,81.39 41.13,81.26 41.13,80.63 40.81,80.32 40.33,80.32 40.06,80.59 40.06,81.19 39.84,81.4 39.24,81.4 ; v1(35.83,80.35) 36.23,80.74 37.25,80.74 37.91,81.4 39.24,81.4 ; 39.24,81.4 v2(39.24,81.11)
  BOTTOM w0.102: XU1.B44 63.04,70 62.9,70.14 62.9,70.34 62.79,70.44 62.79,71.24 62.79,71.26 62.03,72.02 62.03,72.51 61.77,72.77 61.76,72.77 61.74,72.78
  BOTTOM w0.114: v1(60.7,72.71) 61.12,73.12 61.4,73.12 61.74,72.78 ; v1(35.83,80.35) 36.23,80.74 37.14,80.74 37.75,80.14 38.24,80.14 38.6,79.78 XMM1.47
M_CHA_DQS3#: length 43
  TOP w0.114: v2(45.92,80.83) 45.92,80.56 ; 45.92,80.56 45.49,80.56 44.91,81.14 44.48,81.14 43.9,80.56 43.63,80.56 43.5,80.69 43.5,81.36 43.23,81.63 42.75,81.63 42.49,81.36 42.49,80.68 42.36,80.55 42.13,80.55 41.95,80.73 41.95,81.36 41.68,81.63 41.15,81.63 40.89,81.36 40.89,80.73 40.71,80.56 40.43,80.56 40.3,80.69 40.3,81.29 39.95,81.64 37.81,81.64 37.15,80.98 v1(35.83,80.98) ; 45.92,80.56 48.07,80.56 52.36,76.27 57.52,76.27 59.63,74.17 59.63,73.62 59.91,73.34 v1(60.57,73.34)
  BOTTOM w0.102: 63.37,69.95 63.1,70.23 63.1,70.42 63,70.52 63,71.32 63,71.32 63,71.34 62.23,72.1 62.23,72.6 61.9,72.94
  BOTTOM w0.114: 63.37,69.95 63.37,69.65 XU1.C43 ; v1(35.83,80.98) 37.24,80.98 37.85,80.38 XMM1.45 ; 61.9,72.94 61.49,73.34 v1(60.57,73.34)
M_CHA_DQS4: length 44.4
  TOP w0.114: v1(48.2,54.02) 48.05,53.87 48.05,53.63 47.33,52.9 42.89,52.9 ; v1(36.9,50.81) 41.18,50.81 41.58,51.22 41.58,52.3 42.19,52.9 42.89,52.9 ; v2(42.89,52.61) 42.89,52.9
  BOTTOM w0.114: XU1.N53 58.07,64.26 58.03,64.3 55.69,64.3 54.23,65.75 52.14,65.75 46.89,60.49 46.89,60.23 47.08,60.03 47.97,60.03 48.23,59.76 48.23,59.22 47.97,58.95 47.01,58.95 46.89,58.82 46.89,58.61 47.01,58.48 47.97,58.48 48.23,58.21 48.23,57.73 47.97,57.46 46.96,57.46 46.89,57.39 46.89,57.13 47.03,56.98 47.97,56.98 48.23,56.71 48.23,56.3 47.97,56.03 47.29,56.03 47.2,55.94 47.2,55.79 48.03,54.95 48.03,54.19 v1(48.2,54.02) ; v1(36.9,50.81) 37.43,50.81 37.57,50.67 38.31,50.67 38.6,50.38 XMM1.137
M_CHA_DQS4#: length 44.4
  TOP w0.114: v1(47.56,53.98) 47.81,53.74 47.81,53.73 47.23,53.15 42.09,53.15 41.34,52.4 41.34,51.32 41.08,51.05 39.16,51.05 ; 39.16,51.05 37.53,51.05 v1(37.23,51.35) ; 39.16,51.05 v2(39.16,51.32)
  BOTTOM w0.114: XU1.M52 58.75,64.62 58.4,64.62 58.31,64.54 55.79,64.54 55.21,65.11 54.33,65.99 52.04,65.99 46.65,60.59 46.65,60.13 46.98,59.79 47.87,59.79 47.99,59.66 47.99,59.32 47.87,59.19 46.91,59.19 46.65,58.92 46.65,58.51 46.91,58.24 47.87,58.24 47.99,58.11 47.99,57.83 47.87,57.71 46.86,57.71 46.65,57.49 46.65,57.03 46.93,56.74 47.87,56.74 47.99,56.61 47.99,56.4 47.87,56.27 47.19,56.27 46.96,56.04 46.96,55.69 47.79,54.85 47.79,54.17 47.6,53.98 47.6,53.98 v1(47.56,53.98) ; v1(37.23,51.35) 37.67,50.91 38.53,50.91 38.6,50.98 XMM1.135
M_CHA_DQS5: length 41.7
  IN1 w0.102: v1(63.32,63.28) 62.96,62.92 62.96,62.62 62.54,62.2 59.3,62.2 58.32,61.21 58.19,61.21
  IN1 w0.114: 58.19,61.21 57.47,61.21 51.56,55.3 50.46,55.3 49.27,56.49 48.48,56.49 47.29,55.3 46.61,55.3 42.13,50.81 42.13,49.73 38.85,46.45 36.24,46.45 35.17,45.37 34.05,45.37 v1(33.95,45.27)
  BOTTOM w0.114: XMM1.154 32.68,45.28 32.73,45.33 33.89,45.33 v1(33.95,45.27) ; XU1.T42 63.68,62.92 v1(63.32,63.28)
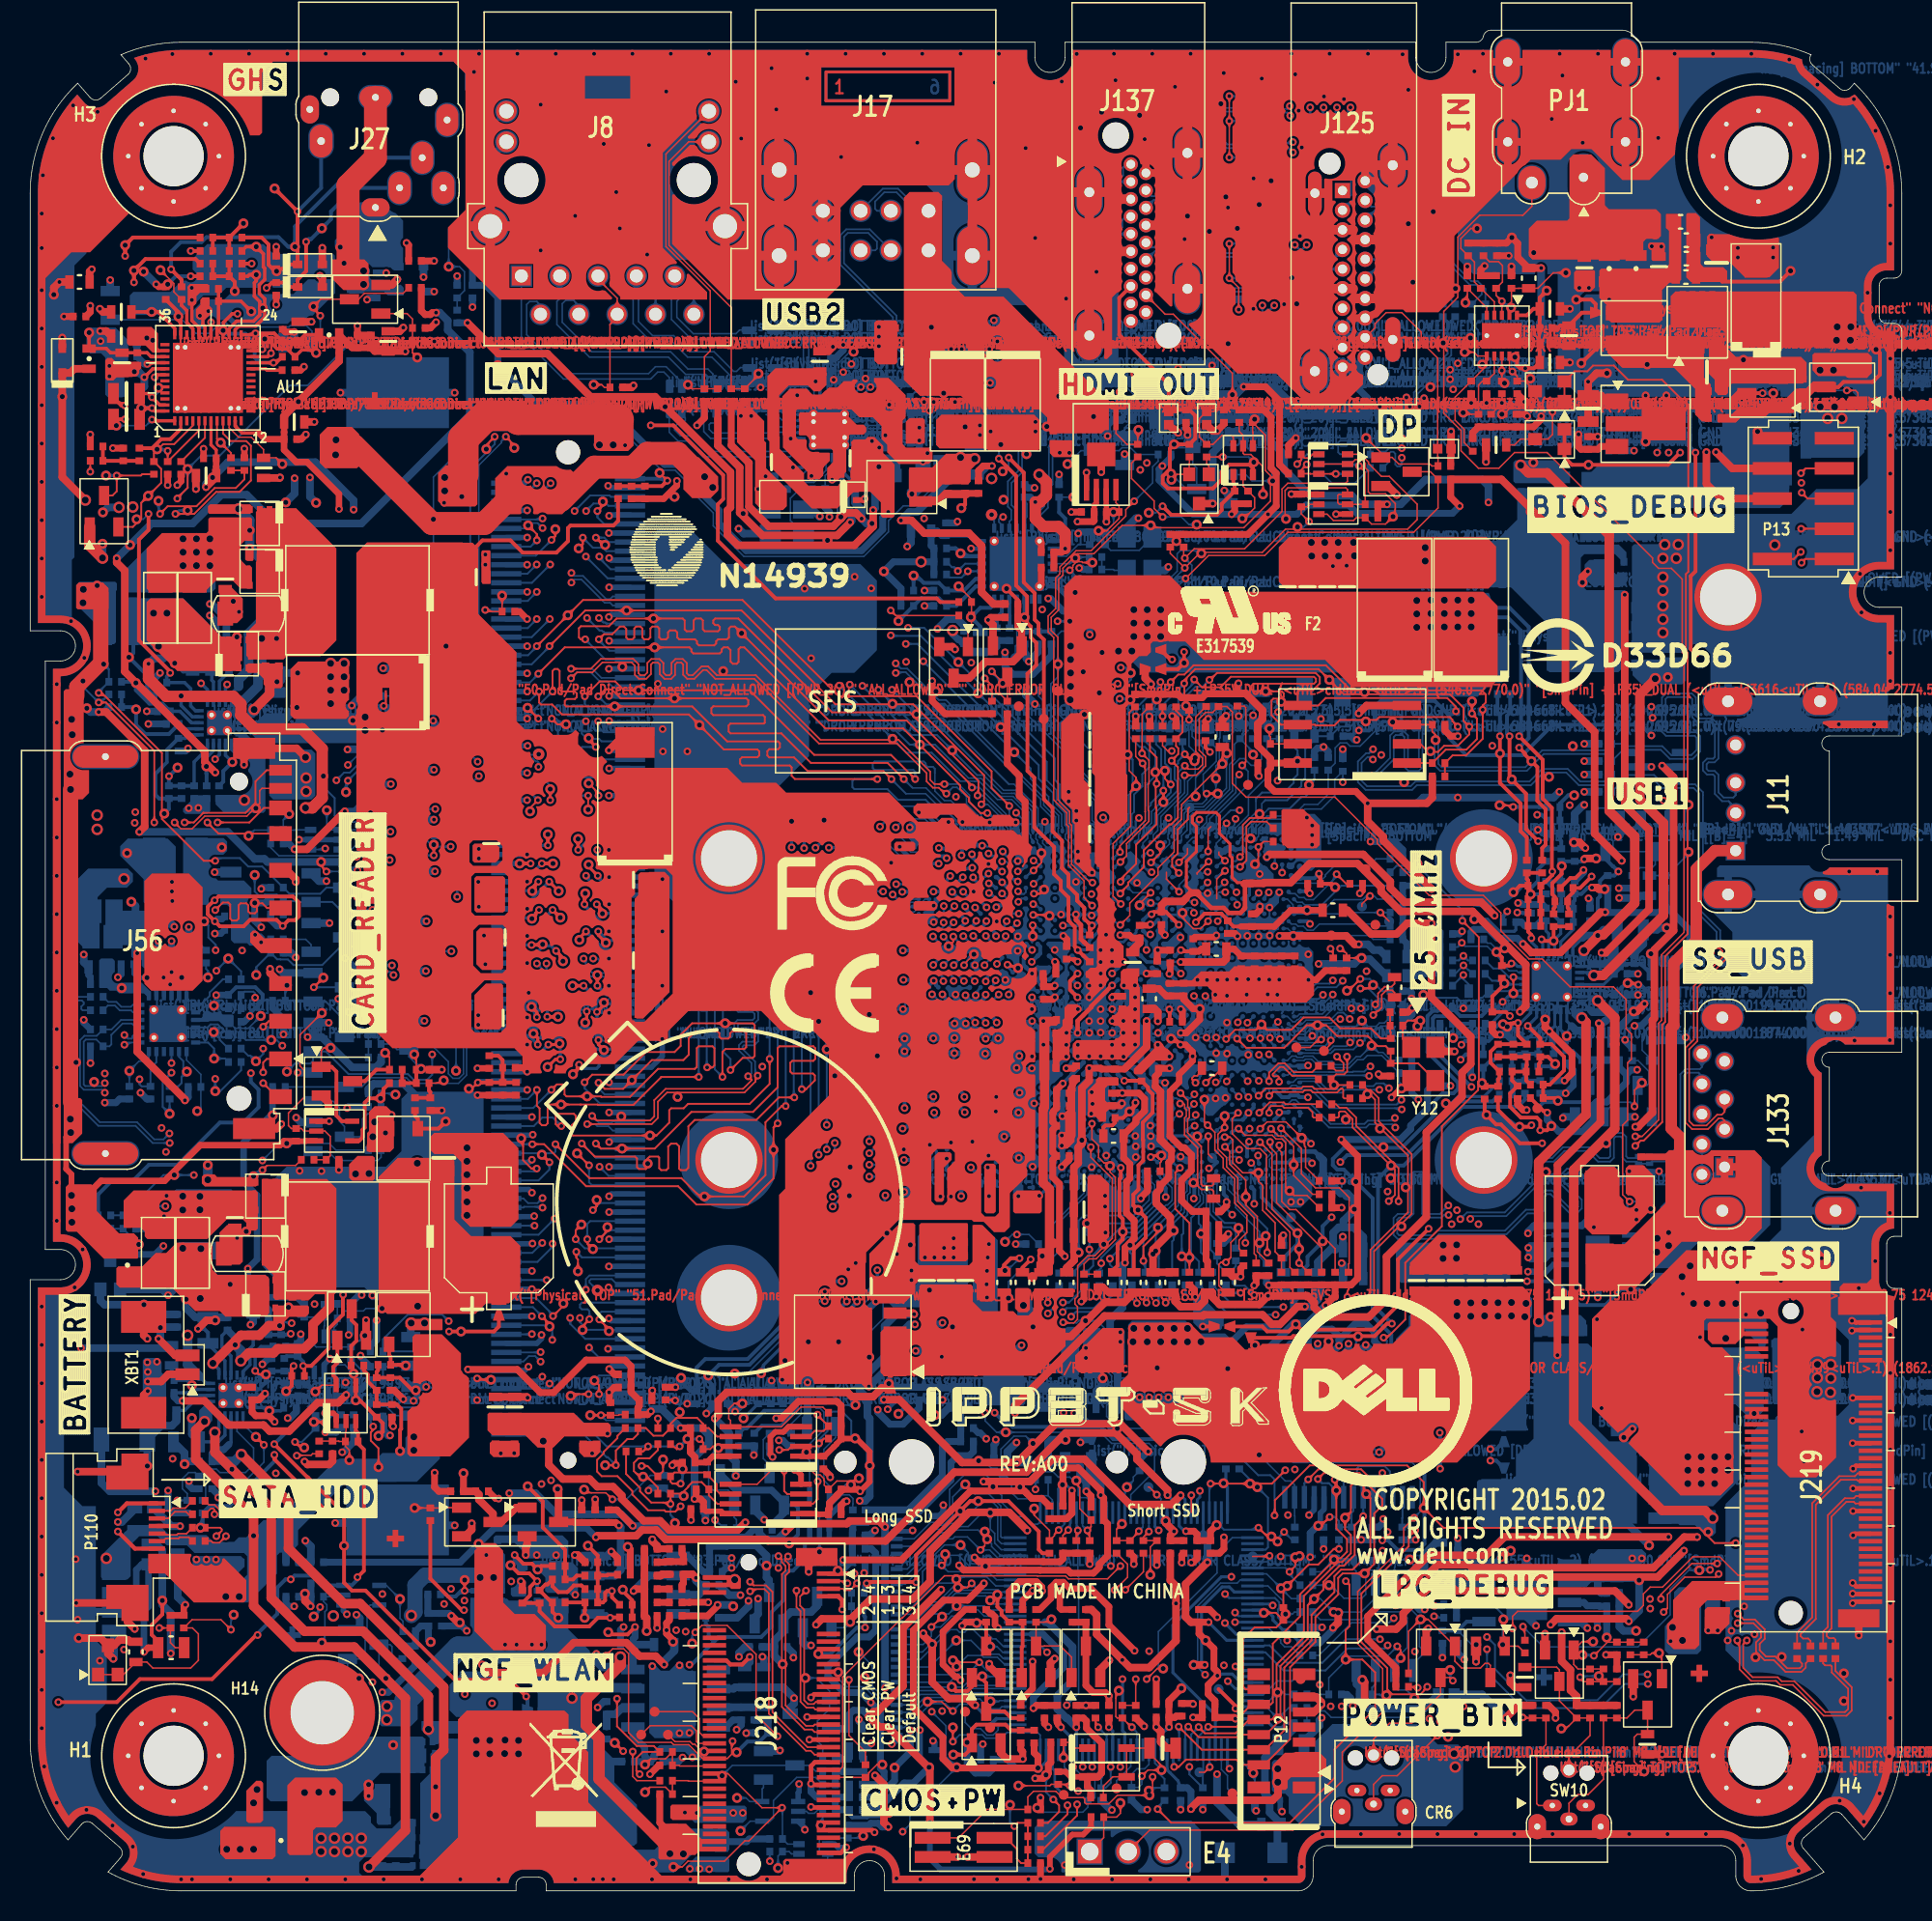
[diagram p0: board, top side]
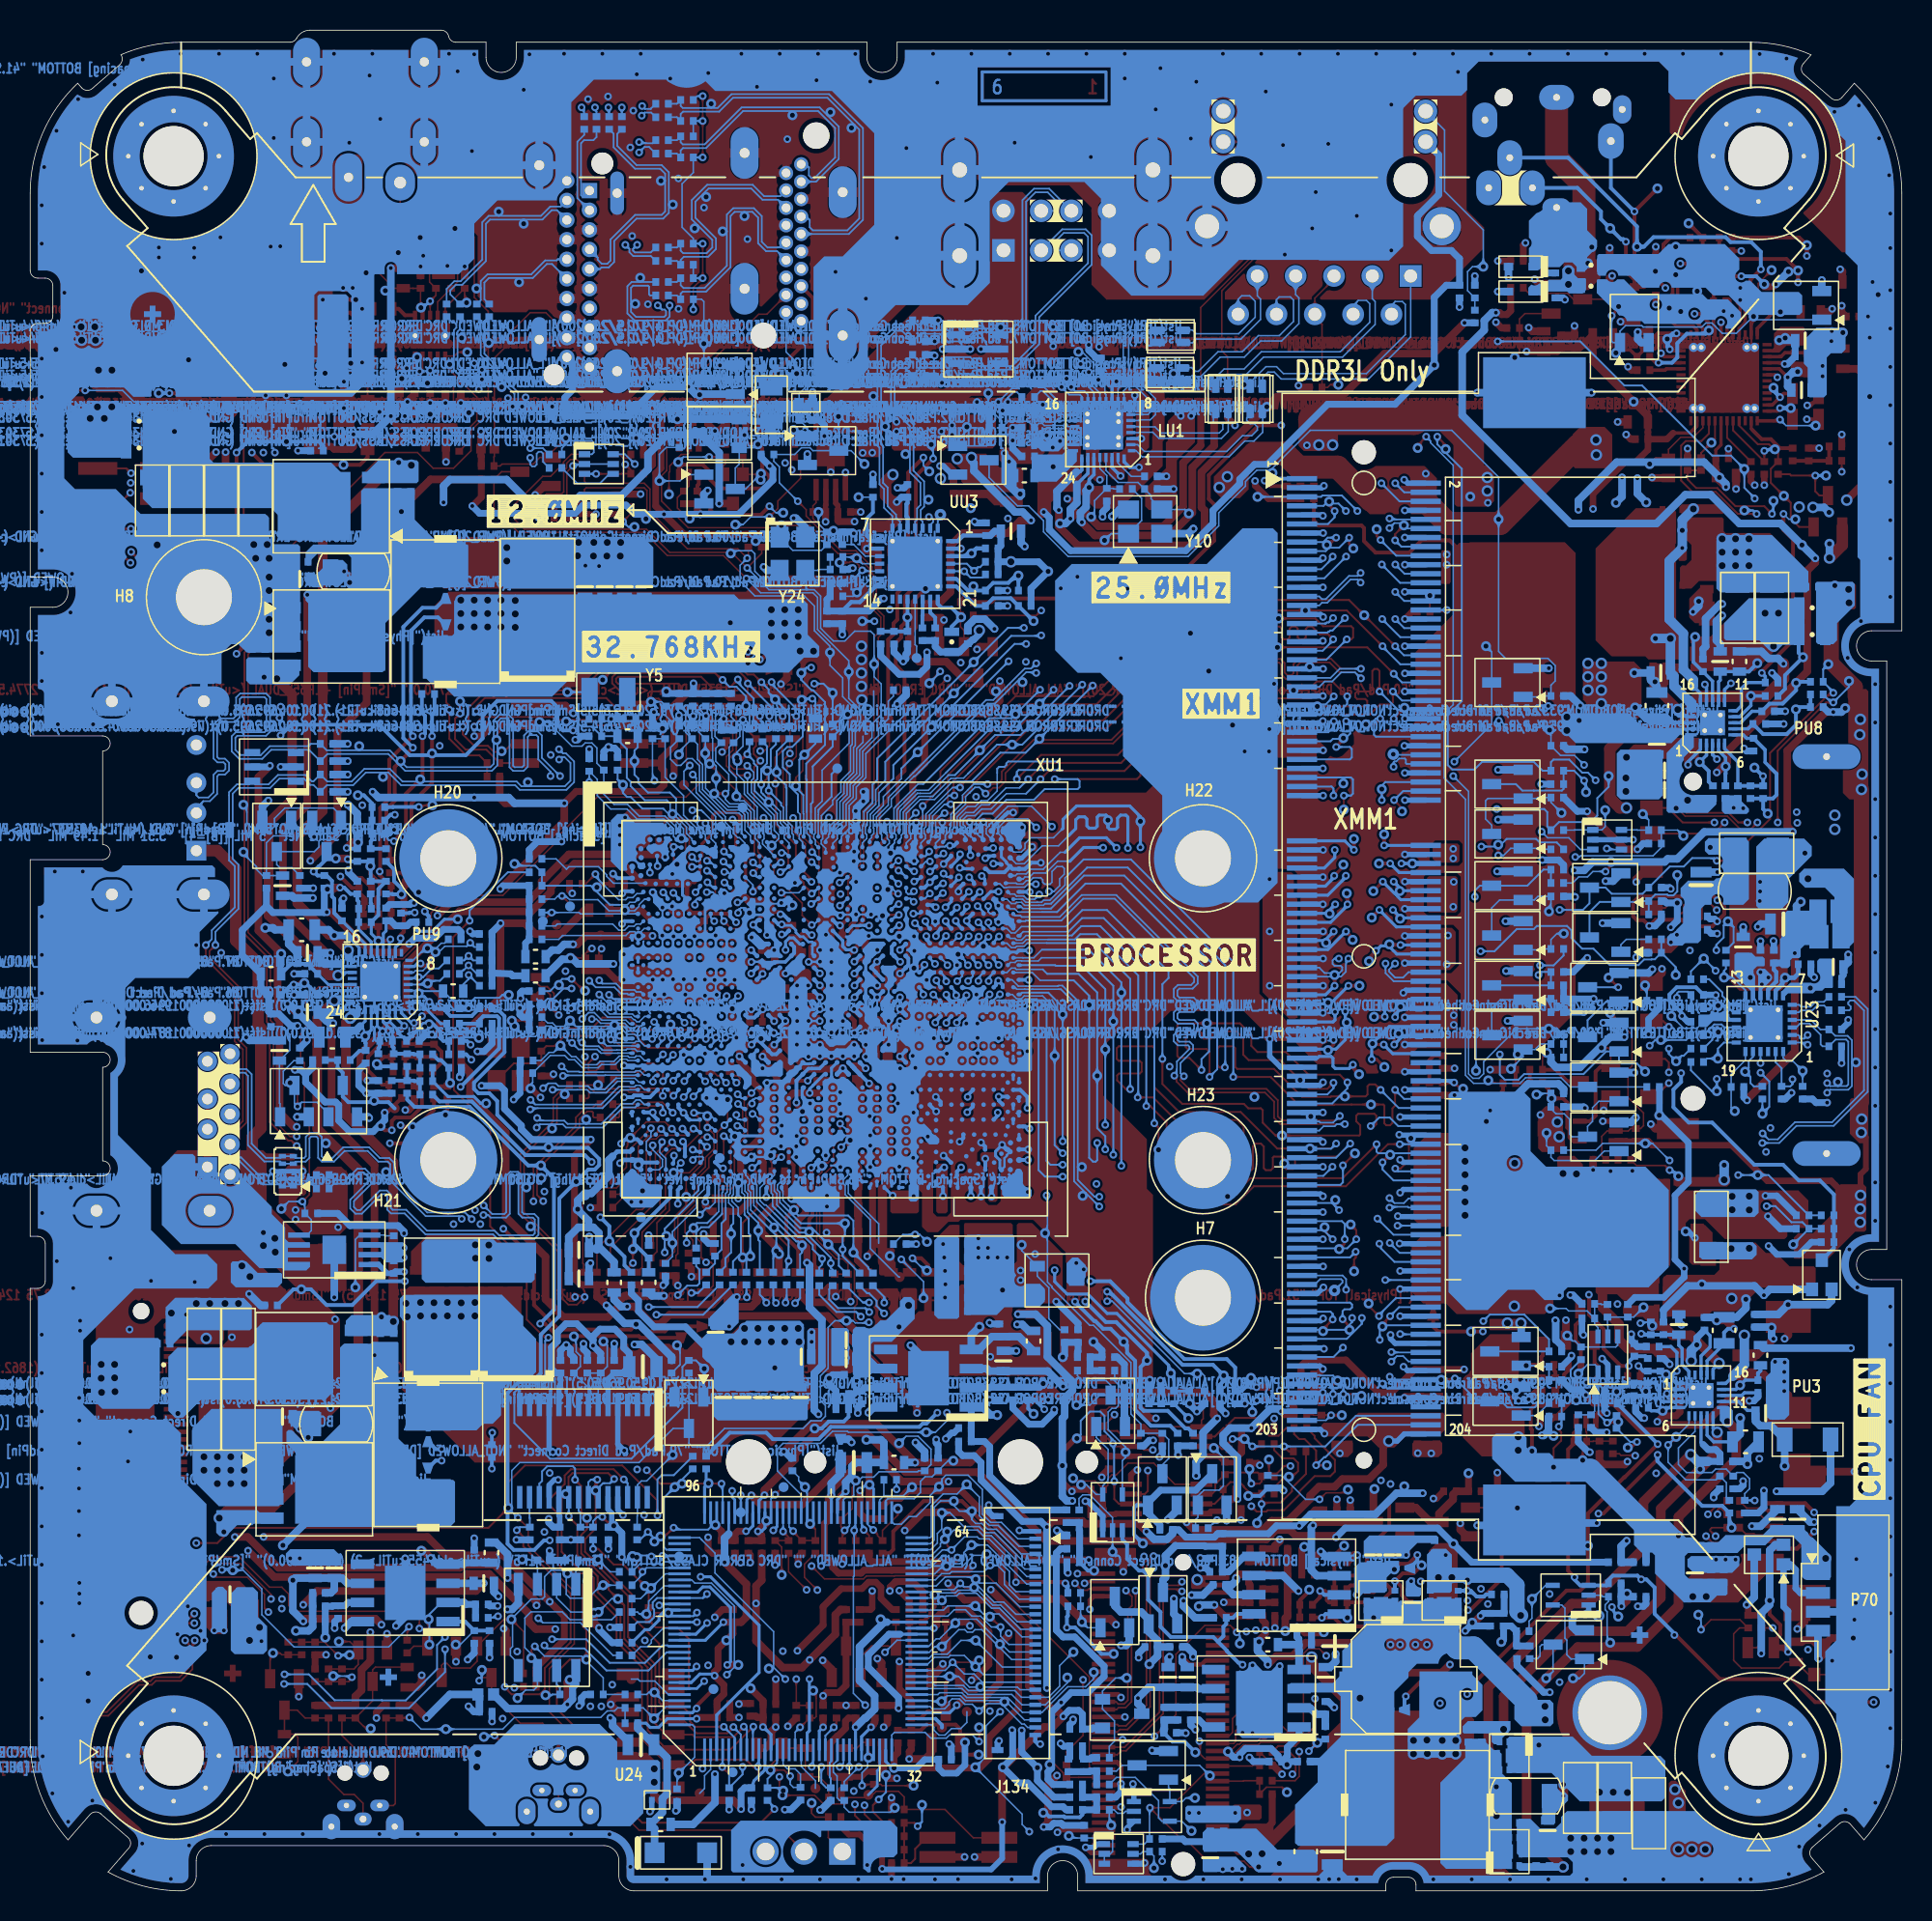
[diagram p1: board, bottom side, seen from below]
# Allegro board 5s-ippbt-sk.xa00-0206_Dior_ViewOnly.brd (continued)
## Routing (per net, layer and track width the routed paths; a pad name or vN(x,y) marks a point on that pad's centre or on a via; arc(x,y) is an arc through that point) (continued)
M_CHA_DQS5#: length 41.7
  IN1 w0.102: v1(62.48,63.28) 62.76,63 62.76,62.7 62.45,62.4 59.22,62.4 58.27,61.45 58.19,61.45
  IN1 w0.114: v1(33.95,45.91) 34.24,45.61 35.06,45.61 36.14,46.69 38.75,46.69 41.89,49.83 41.89,50.91 46.51,55.54 47.19,55.54 48.38,56.73 49.37,56.73 50.56,55.54 51.46,55.54 57.37,61.45 58.19,61.45
  BOTTOM w0.114: XU1.T44 62.97,62.79 v1(62.48,63.28) ; v1(33.95,45.91) 33.61,45.57 32.99,45.57 32.68,45.88 XMM1.152
M_CHA_DQS6: length 44.5
  IN2 w0.102: v1(61.86,60.29) 61.44,60.72 61.26,60.72 61.05,60.92 60.14,60.92 60.12,60.94 59.25,60.94 58.62,60.3 58.61,60.3 58.59,60.28
  IN2 w0.114: v4(37.58,39.79) 37.48,39.68 37.48,39.53 37.6,39.41 38.39,39.41 38.93,39.96 38.93,40.59 38.78,40.74 38.78,41.92 39.11,42.26 39.7,42.26 39.91,42.04 39.91,41.28 39.97,41.22 40.19,41.22 42.04,43.07 42.04,44.95 42.34,45.26 47.63,45.26 49.55,47.18 49.55,49.02 50.74,50.21 50.74,51.01 52.48,52.75 52.48,53.32 57.13,57.96 57.13,58.05 57.13,58.82 58.59,60.28
  BOTTOM w0.114: XU1.Y47 61.55,60.61 v1(61.86,60.29) ; v4(37.58,39.79) 37.06,40.31 37.06,40.44 37.15,40.54 38.53,40.54 38.89,40.18 XMM1.171
M_CHA_DQS6#: length 44.5
  IN2 w0.102: v1(61.18,60.3) 61.18,60.51 60.97,60.72 60.05,60.72 60.03,60.74 59.34,60.74 58.8,60.2 58.76,60.15 58.76,60.14 58.74,60.13
  IN2 w0.114: 58.74,60.13 57.37,58.76 57.37,57.95 57.37,57.95 57.37,57.86 52.72,53.22 52.72,52.65 50.98,50.91 50.98,50.11 49.79,48.92 49.79,47.08 47.73,45.02 42.44,45.02 42.28,44.85 42.28,42.97 40.29,40.98 39.87,40.98 39.67,41.18 39.67,41.94 39.6,42.02 39.21,42.02 39.02,41.82 39.02,40.84 39.17,40.69 39.17,39.86 38.49,39.17 37.48,39.17 v1(36.82,39.84)
  BOTTOM w0.114: XU1.Y48 61.18,60.52 v1(61.18,60.3) ; XMM1.169 37.05,40.78 36.82,40.54 v1(36.82,39.84)
M_CHA_DQS7: length 45.7
  IN1 w0.114: v1(33.82,35.07) 34.21,35.46 35.63,35.46 36.09,35 38.96,35 43.57,39.61 43.57,39.99 45.3,41.73 49.02,41.73 52.64,45.35 v1(53.17,45.35)
  BOTTOM w0.102: 55.85,59.75 57.59,59.75 57.6,59.75 58.11,59.75 58.11,59.75 58.62,59.75 58.76,59.88 XU1.AB52
  BOTTOM w0.114: v2(54.27,46.06) 54.08,46.26 ; 54.08,46.26 v1(53.17,45.35) ; 54.08,46.26 54.84,47.02 54.84,58.88 55.36,59.41 55.38,59.41 55.72,59.75 55.85,59.75 ; v1(33.82,35.07) 33.45,35.44 33.04,35.44 32.68,35.08 XMM1.188
M_CHA_DQS7#: length 45.8
  IN1 w0.114: v1(33.82,35.7) 35.73,35.7 36.19,35.25 38.86,35.25 43.32,39.71 43.32,40.09 45.2,41.97 48.92,41.97 52.54,45.59 52.76,45.59 v1(53.17,46)
  BOTTOM w0.102: XU1.AA51 59.04,60.37 58.94,60.37 58.53,59.95 58.03,59.95 58.03,59.95 57.68,59.95 57.68,59.95 55.94,59.95 55.94,59.96 55.89,59.96 55.86,59.99 55.62,59.99 55.61,59.98
  BOTTOM w0.114: 55.61,59.98 55.28,59.65 55.26,59.65 54.6,58.98 54.6,47.96 ; v1(33.82,35.7) 33.79,35.68 XMM1.186 ; 54.6,47.96 v2(54.32,47.96) ; 54.6,47.96 54.6,47.12 53.48,46 v1(53.17,46)
M_CHA_MAA0: length 36.8
  TOP w0.203: v1(34.84,62.29) 35.3,61.83 v2(35.3,61.6)
  IN2 w0.102: 55.72,68.6 57.21,68.6 57.48,68.33 58.8,68.33 60.5,66.63 61.39,66.63 v1(61.81,66.21)
  IN2 w0.216: 55.72,68.6 54.15,68.6 52.3,66.75 50.74,66.75 46.8,62.81 42.67,62.81 42.11,62.25 36.1,62.25 35.37,61.53 34.99,61.53 34.84,61.68 v1(34.84,62.29)
  BOTTOM w0.203: XMM1.98 33.46,62.08 34,62.62 34.51,62.62 v1(34.84,62.29) ; XU1.K45 61.81,66.19 v1(61.81,66.21)
M_CHA_MAA1: length 38.6
  TOP w0.203: v2(36.38,63.02) 36.38,63.14 v1(36.82,63.58)
  IN1 w0.102: v1(61.79,67.17) 61.49,67.17 61.15,66.83 60.78,66.83 60.53,67.08 60.53,67.08 60.17,67.45 59.34,67.45 58.31,66.41 58.31,66.02 57.85,65.57 56.89,65.57 56.84,65.62 56.1,65.62
  IN1 w0.216: v1(36.82,63.58) 34.31,63.58 34.18,63.71 34.18,64.25 34.31,64.37 37,64.37 37.3,64.68 43.05,64.68 44.25,63.48 51.21,63.48 53.35,65.62 56.1,65.62
  BOTTOM w0.203: XMM1.97 38.02,62.38 v1(36.82,63.58) ; v1(61.79,67.17) 61.46,66.84 XU1.H47
M_CHA_MAA2: length 38.4
  TOP w0.203: v2(33.95,62.72) 33.91,62.68 v1(33.22,62.68)
  IN2 w0.102: 55.8,69.22 56.94,69.22 57.55,68.61 58.97,68.61 60.75,66.83 61.5,66.83 61.6,66.73 62.59,66.73 62.92,66.39 62.92,66.13 63.41,65.65 63.54,65.65 v1(64.01,65.18)
  IN2 w0.216: 55.8,69.22 53.89,69.22 52.04,67.38 50.49,67.38 46.54,63.43 42.41,63.43 41.9,62.92 33.46,62.92 v1(33.22,62.68)
  BOTTOM w0.203: v1(64.01,65.18) 64.17,65.34 XU1.L41 ; v1(33.22,62.68) XMM1.96
M_CHA_MAA3: length 38.1
  TOP w0.203: v2(38.14,62.82) 37.64,63.33 v1(37.64,63.58)
  IN1 w0.102: v1(62.47,67.16) 62.47,66.78 62.32,66.63 60.7,66.63 60.23,67.1 59.46,67.1 58.54,66.18 58.54,65.95 57.83,65.24 56.84,65.24 56.6,65 56.19,65
  IN1 w0.216: 56.19,65 53.6,65 51.31,62.7 43.46,62.7 43.12,63.03 43.12,63.73 42.79,64.05 42.52,64.05 42.36,63.89 42.36,62.72 42.23,62.59 41.14,62.59 41.01,62.72 41.01,63.93 40.89,64.05 40.38,64.05 40.25,63.93 40.25,62.72 40.12,62.59 39.64,62.59 39.51,62.72 39.51,63.93 39.39,64.05 37.76,64.05 37.64,63.93 v1(37.64,63.58)
  BOTTOM w0.203: v1(37.64,63.58) 38.24,62.98 XMM1.95 ; v1(62.47,67.16) 62.47,67.12 XU1.H44
M_CHA_MAA4: length 37.4
  TOP w0.203: v2(35.12,64.49) v1(34.61,65)
  IN1 w0.216: v1(34.61,65) 35.68,65 36.53,65.85 42.76,65.85 44.51,64.1 50.95,64.1 51.08,64.23 51.08,64.59 50.95,64.71 49.34,64.71 49.19,64.86 49.19,65.2 49.53,65.54 52.39,65.54 52.51,65.66 52.51,66.58 52.64,66.71 53.28,66.71 53.41,66.58 53.41,66.37 53.54,66.24 54.22,66.24 54.35,66.37 54.35,66.58 54.48,66.71 v1(57.37,66.71)
  BOTTOM w0.102: v1(57.37,66.71) 57.9,66.71 58.1,66.51 59.14,66.51 59.31,66.49 59.48,66.47 59.75,66.73 XU1.H50
  BOTTOM w0.203: v1(34.61,65) 33.49,63.88 XMM1.92
M_CHA_MAA5: length 40.1
  TOP w0.203: v2(36.77,66.1) 36.73,66.05 v1(36.73,65.37)
  IN2 w0.216: v1(36.73,65.37) 34.98,65.37 34.74,65.62 32.12,65.62 31.84,65.34 31.84,64.42 32.21,64.05 46.28,64.05 50.23,68 51.78,68 v1(52.91,69.13)
  BOTTOM w0.102: XU1.G53 58.23,67.05 58.09,67.19 57.78,67.19 57.52,67.45 56.71,67.45 55.92,68.23 55.21,68.23
  BOTTOM w0.203: v1(36.73,65.37) 36.73,65.3 37.85,64.18 XMM1.91 ; v1(52.91,69.13) 52.92,69.14 54.21,69.14 55.11,68.23 55.21,68.23
M_CHA_MAA6: length 40.6
  TOP w0.203: v2(33.24,64.42) 33.5,64.69 33.5,64.79 v1(33.71,65)
  IN1 w0.102: v1(60.95,67.25) 60.56,67.65 56.91,67.65
  IN1 w0.216: v1(33.71,65) 34.34,65.63 35.43,65.63 35.43,65.63 36.36,66.57 42.92,66.57 44.77,64.72 47.83,64.72 49.37,66.26 51.76,66.26 51.89,66.38 51.89,66.79 51.76,66.91 50.54,66.91 50.41,67.04 50.41,67.3 50.76,67.65 51.53,67.65 51.71,67.83 51.71,68.52 51.83,68.65 52.29,68.65 52.42,68.52 52.42,67.67 52.54,67.55 53.03,67.55 53.15,67.67 53.15,68.49 53.28,68.61 53.69,68.61 53.81,68.49 53.81,67.8 53.97,67.65 56.91,67.65
  BOTTOM w0.203: v1(33.71,65) 33.19,64.48 XMM1.90 ; XU1.H49 60.75,67.05 v1(60.95,67.25)
M_CHA_MAA7: length 37.6
  TOP w0.203: v2(35.01,66.25) v1(34.39,66.88)
  IN1 w0.216: v1(34.39,66.88) 34.39,68.26 33.42,69.23 33.42,70.06 33.75,70.39 43.48,70.39 44.59,71.51 47.58,71.51 48.69,70.39 53.67,70.39 54.4,69.66 57.81,69.66 58.78,68.69 59.72,68.69 59.86,68.55 60.39,68.55 60.5,68.43 v1(60.72,68.43)
  BOTTOM w0.203: XMM1.86 33.19,65.68 v1(34.39,66.88) ; XU1.D50 60.56,68.59 v1(60.72,68.43)
M_CHA_MAA8: length 40.2
  TOP w0.203: v1(37.54,65.37) 37.91,65 v2(37.91,64.75)
  IN2 w0.216: v1(52.03,69.12) 51.53,68.62 50.28,68.62 49.73,69.17 49.19,69.17 48.96,68.94 48.96,67.61 46.03,64.68 45.54,64.68 45.31,64.91 45.31,66.11 45.18,66.24 40.59,66.24 40.43,66.07 40.43,65.67 40.61,65.49 44.29,65.49 44.42,65.36 44.42,64.8 44.29,64.68 37.76,64.68 37.54,64.9 v1(37.54,65.37)
  BOTTOM w0.102: XU1.G52 58.72,67.28 58.61,67.39 58.02,67.39 57.71,67.7 56.88,67.7 55.76,68.82 55.43,68.82
  BOTTOM w0.203: 55.43,68.82 54.47,69.78 52.71,69.78 52.05,69.12 v1(52.03,69.12) ; XMM1.89 38.13,64.78 v1(37.54,65.37)
M_CHA_MAA9: length 38.8
  IN1 w0.216: v1(36.83,67.27) 36.54,67.56 36.54,67.75 36.66,67.87 36.95,67.87 37.17,68.08 37.59,68.08 37.79,67.88 38.78,67.88 38.96,67.69 38.96,67.32 39.09,67.19 39.57,67.19 39.69,67.32 39.69,67.62 39.82,67.74 40.49,67.74 40.63,67.6 40.63,67.32 40.76,67.19 41.24,67.19 41.37,67.32 41.37,67.62 41.5,67.74 43.03,67.74 43.13,67.64 43.13,67.24 45.02,65.35 47.58,65.35 49.55,67.32 49.55,68.16 49.67,68.28 50.92,68.28 51.08,68.45 51.08,68.91 v1(51.27,69.1)
  BOTTOM w0.102: 55.21,69.91 55.87,69.25 56.95,69.25 58.14,68.06 58.68,68.06 XU1.E52
  BOTTOM w0.203: v1(51.27,69.1) 51.27,71.15 51.4,71.28 51.76,71.28 51.96,71.08 51.96,70.47 52.09,70.34 52.47,70.34 52.6,70.47 v2(52.6,70.95) 52.6,71.15 52.72,71.28 53.18,71.28 53.31,71.15 53.31,70.54 53.43,70.42 53.84,70.42 53.99,70.57 53.99,71.03 54.14,71.17 54.53,71.17 54.73,70.98 54.73,70.39 55.21,69.91 ; XMM1.85 38.03,65.98 36.83,67.18 v1(36.83,67.27)
M_CHA_MAA10: length 41
  TOP w0.203: v1(37.58,59.98) v2(37.58,60.69)
  IN2 w0.216: v1(59.84,66.22) 59.84,66.21 58.51,66.21 58.39,66.34 58.39,66.66 58.51,66.79 58.82,66.79 58.95,66.91 58.95,67.23 58.82,67.36 54.66,67.36 52.82,65.51 51.26,65.51 47.32,61.57 44.65,61.57 44.52,61.44 44.52,60.03 44.39,59.9 43.96,59.9 43.83,60.03 43.83,61.44 43.71,61.57 43.25,61.57 43.12,61.44 43.12,60.03 42.99,59.9 42.48,59.9 42.36,60.03 42.36,60.88 42.23,61.01 41.5,61.01 41.37,60.88 41.37,60.03 41.24,59.9 40.89,59.9 40.76,60.03 40.76,60.88 40.63,61.01 40.25,61.01 40.12,60.88 40.12,60.03 40,59.9 39.62,59.9 39.49,60.03 39.49,60.82 39.3,61.01 39.14,61.01 38.81,60.68 37.77,60.68 37.58,60.49 v1(37.58,59.98)
  BOTTOM w0.203: XU1.K48 60.37,66.21 59.85,66.21 v1(59.84,66.22) ; v1(37.58,59.98) 38.18,59.38 XMM1.107
M_CHA_MAA11: length 39
  TOP w0.203: v1(33.67,66.88) 33.27,66.48 v2(33.27,66.25)
  IN1 w0.216: v1(60.19,68.07) 57.88,68.07 57.73,68.21 57.63,68.21 57.18,68.67 54.52,68.67 53.41,69.77 48.43,69.77 47.32,70.88 44.89,70.88 43.78,69.77 36.95,69.77 36.82,69.64 36.82,68.61 36.7,68.49 35.91,68.49 35.78,68.61 35.78,69.64 35.65,69.77 34.9,69.77 34.79,69.66 34.79,68.74 35.01,68.52 35.01,67.68 35.6,67.09 35.6,66.69 35.17,66.26 33.79,66.26 33.67,66.38 v1(33.67,66.88)
  BOTTOM w0.203: v1(33.67,66.88) 33.07,66.28 XMM1.84 ; v1(60.19,68.07) 59.72,68.07 XU1.E51
M_CHA_MAA12: length 36.5
  TOP w0.203: v2(37,68) 37,67.87 v1(37.6,67.27)
  IN2 w0.102: 60.77,68.97 61.14,68.6 61.14,68.59 61.93,67.79 v1(62.41,67.79)
  IN2 w0.216: v1(37.6,67.27) 37.6,67.8 37.81,68 39.64,68 40.4,68.76 42.23,68.76 42.6,69.13 42.6,69.96 44.77,72.13 48.4,72.13 49.35,71.18 58.48,71.18 58.75,70.9 58.75,69.34 58.95,69.15 59.33,69.15 59.53,69.35 59.53,70.24 59.66,70.37 59.96,70.37 60.32,70.01 60.32,69.81 60.77,69.36 60.77,68.97
  BOTTOM w0.203: XU1.F47 62.35,67.73 v1(62.41,67.79) ; XMM1.83 38.19,66.58 37.6,67.17 v1(37.6,67.27)
M_CHA_MAA13: length 39.5
  TOP w0.203: v2(36.77,57.54) 36.87,57.64 v1(36.87,58.28)
  IN2 w0.216: v1(57.14,66.02) 56.98,66.18 56.98,66.42 56.67,66.73 56.3,66.73 55.95,66.38 55.59,66.38 55.16,66.81 54.83,66.81 54.7,66.68 54.7,66.11 54.5,65.9 54.09,65.9 52.94,64.75 51.38,64.75 47.57,60.94 46.53,60.94 46.4,60.82 46.4,59.78 46.27,59.65 45.92,59.65 45.79,59.78 45.79,60.82 45.66,60.94 45.27,60.94 45.14,60.82 45.14,59.4 45.01,59.28 39.36,59.28 39.11,59.52 38.6,59.52 38.36,59.28 35.68,59.28 35.57,59.17 35.57,58.42 35.7,58.28 v1(36.87,58.28)
  BOTTOM w0.102: v1(57.14,66.02) 57.46,65.71 57.95,65.71 58.16,65.91 58.17,65.91 58.17,65.92 58.65,65.92 58.65,65.92 58.65,65.92 58.79,66.06 59.08,66.06 XU1.J51
  BOTTOM w0.203: XMM1.119 37.49,55.78 36.87,56.4 v1(36.87,58.28)
M_CHA_MAA14: length 38.4
  TOP w0.203: v2(34.64,68.08) v1(33.9,68.08)
  IN2 w0.216: v1(33.9,68.08) 33.9,67.63 34.1,67.42 34.69,67.42 35.08,67.04 35.48,67.04 35.6,67.17 35.6,68.06 35.73,68.18 36.16,68.18 36.29,68.06 36.29,66.91 36.56,66.65 39.16,66.65 40.65,68.14 42.9,68.14 43.22,68.46 43.22,69.7 45.02,71.51 48.15,71.51 49.13,70.52 v1(56.3,70.52)
  BOTTOM w0.102: XU1.B49 60.66,70.05 60.66,70.39 60.45,70.6 60.45,70.65 59.51,71.59 59.22,71.88 57.66,71.88 v1(56.3,70.52)
  BOTTOM w0.203: XMM1.80 33.3,67.48 v1(33.9,68.08)
M_CHA_MAA15: length 37.2
  TOP w0.203: v2(32.43,68.08) v1(33.16,68.08)
  IN2 w0.216: v1(57.35,70.47) 57.35,70.09 57.12,69.86 48.91,69.86 47.89,70.88 45.28,70.88 43.84,69.44 43.84,67.75 43.61,67.52 40.91,67.52 39.42,66.02 35.21,66.02 34.85,66.38 32.56,66.38 32.38,66.56 32.38,67.3 v1(33.16,68.08)
  BOTTOM w0.102: XU1.B50 59.67,69.88 59.89,70.1 59.89,70.42 59.28,71.03 57.91,71.03 v1(57.35,70.47)
  BOTTOM w0.203: XMM1.78 v1(33.16,68.08)
M_CHA_ODT0: length 42
  TOP w0.203: v1(33.63,56.08) 33.63,56.52 v2(33.34,56.8)
  IN2 w0.102: v1(64.63,63.27) 64.21,62.85 63.85,62.85 63.39,62.39 59.12,62.39 58.78,62.73 57.25,62.73 55.69,61.17 55.69,60.84 54.39,59.54
  IN2 w0.216: v1(33.63,56.08) 33.63,54.71 35.91,52.43 38.78,52.43 39.18,52.83 47.69,52.83 54.39,59.54
  BOTTOM w0.203: XU1.T41 64.63,63.02 v1(64.63,63.27) ; v1(33.63,56.08) 33.03,56.68 XMM1.116
M_CHA_ODT1: length 40.6
  TOP w0.203: v2(35.07,56.14) 35.01,56.08 v1(34.33,56.08)
  IN2 w0.102: 55.34,61.45 56.96,63.08 58.72,63.08 59.2,62.59 63.27,62.59 63.94,63.27 v1(63.99,63.27)
  IN2 w0.216: 55.34,61.45 50.56,56.67 49.63,56.67 47.47,54.51 47.26,54.51 46.2,53.46 38.92,53.46 38.52,53.05 36.28,53.05 34.33,55.01 v1(34.33,56.08)
  BOTTOM w0.203: v1(63.99,63.27) 63.99,63.45 XU1.P42 ; v1(34.33,56.08) 33.73,55.48 XMM1.120
M_CHA_RAS#: length 36.5
  TOP w0.203: v2(33.22,58.58) 33.57,58.23 v1(33.57,57.9)
  IN2 w0.102: v1(61.94,65.24) 61.52,64.82 59.69,64.82 59.68,64.82 58.6,64.82 58.44,64.98 57.09,64.98 56.74,64.63 55.72,64.63
  IN2 w0.216: 55.72,64.63 55.45,64.63 53.64,62.81 53.05,62.81 50.13,59.88 49.22,59.88 46.34,57 33.9,57 33.57,57.33 v1(33.57,57.9)
  BOTTOM w0.203: v1(61.94,65.24) 61.9,65.2 61.9,65.11 XU1.M45 ; v1(33.57,57.9) 33.57,58.1 33.2,58.47 32.59,58.47 32.58,58.48 XMM1.110
M_CHA_WE#: length 38.3
  TOP w0.203: v1(37.55,58.25) 38.02,58.71 v2(38.02,58.86)
  IN2 w0.216: v1(37.55,58.25) 37.55,58.53 37.68,58.65 38.78,58.65 38.91,58.53 38.91,58.37 39.03,58.25 39.46,58.25 39.59,58.37 39.59,58.53 39.72,58.65 40.1,58.65 40.23,58.53 40.23,58.37 40.35,58.25 40.71,58.25 40.84,58.37 40.84,58.53 40.96,58.65 41.37,58.65 41.5,58.53 41.5,58.37 41.62,58.25 42.08,58.25 42.21,58.37 42.21,58.53 42.33,58.65 42.77,58.65 42.89,58.53 42.89,58.37 43.02,58.25 43.48,58.25 43.6,58.37 43.6,58.53 43.73,58.65 44.37,58.65 44.49,58.53 44.49,58.37 44.62,58.25 45.39,58.25 45.52,58.37 45.52,58.9 45.64,59.03 46.54,59.03 47.02,59.51 47.02,60.12 47.22,60.32 47.83,60.32 49.24,61.73 49.55,61.73 49.73,61.55 50.03,61.55 50.34,61.86 50.34,62.16 50.16,62.34 50.16,62.65 50.46,62.95 50.77,62.95 50.95,62.77 51.25,62.77 51.56,63.08 51.56,63.38 51.38,63.56 51.38,63.87 51.6,64.09 53.16,64.09 54.63,65.57 55.85,65.57 v1(56.51,66.23)
  BOTTOM w0.102: v1(56.51,66.23) 56.18,66.23 55.8,66.61 55.8,67.07 55.49,67.37 55.49,67.75 55.62,67.88 55.97,67.88 56.3,67.55 56.3,66.84 56.43,66.71 56.79,66.71 56.91,66.84 56.91,67 57.04,67.13 57.55,67.13 57.74,66.94 58,66.94 58.23,66.72 58.62,66.72 58.68,66.78 XU1.H51
  BOTTOM w0.203: v1(37.55,58.25) 37.55,57.71 37.69,57.58 XMM1.113
ME_DISABLE#: length 63.6
  TOP w0.127: v1(89.67,36.66) 89.9,36.66 91.1,37.86 91.1,41.62 93.53,44.04 93.53,50.67 95.93,53.07 95.93,53.61 95.98,53.66 95.98,63.19 v1(94.89,64.28)
  BOTTOM w0.127: v1(94.89,64.28) 94.89,64.97 92.36,67.5 SR49.1 ; Q7.1 79.41,34.08 79.34,34.15 v2(79.34,34.6) 79.89,35.15 R7.1 80.79,34.72 80.79,34.01 80.79,34.01 80.79,32.02 84.17,28.63 89.55,28.63 91.92,31 91.92,33.03 91.49,33.46 90.6,33.46 89.88,34.18 89.88,36.45 v1(89.67,36.66)
MIC2-L: length 2.8
  TOP w0.229: AC1.1 7.83,99.22 v1(8.07,98.98) 8.58,98.46 AU1.47
  BOTTOM w0.254: v1(8.07,98.98) 8.5,99.41 v2(8.5,99.6)
MIC2-R: length 2.9
  TOP w0.229: AU1.48 8.26,98.06 v1(8.07,98.26) 7.71,98.26 7.25,97.79 AC2.1
  BOTTOM w0.254: v2(7.36,98.26) v1(8.07,98.26)
MIC2-VREFOL: length 16.9
  TOP w0.229: AU1.1 8.15,97.41 v1(8.07,97.49)
  TOP w0.254: HR4.2 v1(10.63,108.67)
  IN1 w0.254: v1(8.07,97.49) 8.74,98.17 8.74,105.63 9.92,106.82 9.92,107.96 v1(10.63,108.67)
  BOTTOM w0.102: v1(8.07,97.49) 7.67,97.1 v2(5.71,97.1)
MIC2-VREFOR: length 7.1
  TOP w0.229: v1(11.98,103.95) 11.98,103.94 11.98,103.94 AU1.30
  TOP w0.254: HR3.2 v1(10.63,106.99)
  IN1 w0.254: v1(11.98,103.95) 12.34,104.3 12.34,105.29 v1(10.63,106.99)
  BOTTOM w0.254: v1(10.63,106.99) 9.64,106.99 v2(9.11,106.46)
MIC-CAP: length 3.7
  TOP w0.229: AU1.36 9.58,103.53 8.48,104.63 v2(8.04,104.63) AC42.1
MMC1_RCOMP: length 18.2
  TOP w0.102: SR627.1 79.2,39.65 78.76,40.09 78.76,41.51 78.9,41.65 v1(79.22,41.65) 79.55,41.97 79.55,42.96 80.05,43.47 v2(80.05,43.93)
  IN1 w0.102: v1(76.14,51.48) 76.7,50.93 76.7,50.42 79.85,47.27 79.85,45.88 80.48,45.25 80.48,43.6 79.85,42.96 79.85,42.28 v1(79.22,41.65)
  BOTTOM w0.102: v1(76.14,51.48) 76.05,51.48 XU1.AY18
MQ5_B: length 4.4
  TOP w0.102: v2(26.74,69.33) v1(26.74,68.61)
  BOTTOM w0.102: SR662.2 24.16,69.02 24.22,69.09 MQ5.1 25.91,69.09 26.38,68.61 v1(26.74,68.61)
MQ5_C: length 8.1
  BOTTOM w0.102: v2(22.55,71.43) 23.25,72.13 SR28.2 24.12,72.45 24.18,72.39 Q9414.1 27.42,72.39 27.58,72.24 27.58,71.03 27.17,70.62 MQ5.3
MQ7_B: length 4.3
  BOTTOM w0.102: MQ7.1 24.2,31.49 R60297.2 22.84,32.85 21.92,32.85 v2(21.57,32.5)
MQ9_B: length 2.5
  BOTTOM w0.102: R60298.2 18.25,63.05 18.61,62.7 MQ9.1
MQ9_G: length 6.4
  BOTTOM w0.102: MQ34.1 80.54,93.85 80.95,93.43 v2(82.31,93.43) 82.31,95.2 81.86,95.65 MR1.2
MQ10_G: length 6.6
  BOTTOM w0.102: v2(75.58,93.91) 76.6,92.9 MQ34.3 77.29,94.29 77.02,94.55 MQ33.1 76.01,95.63 MR2.2
MQ23_B: length 3.6
  BOTTOM w0.102: v2(25.9,54.47) 25.09,55.28 MQ23.1 24.3,55.75 23.93,56.12 R60304.2
MQ25_G: length 7.1
  BOTTOM w0.102: Q9.3 27.17,65.14 26.65,65.66 MQ25.1 24.35,65.66 24.11,65.9 R8.2 23.25,65.03 v2(23.38,64.9)
MQ31_G: length 9.8
  BOTTOM w0.102: v2(24.2,52.77) 24.13,52.84 SC65.1 SR670.2 23.25,51.83 22.92,51.49 22.37,51.49 22.01,51.14 22.01,50.15 21.84,49.97 MQ32.3 20.82,50.66 20.49,50.99 20.49,51.9 20.07,52.32 MQ31.1
MQ32_B: length 6.6
  BOTTOM w0.102: v2(23.54,50.22) 23.54,49.37 R60306.2 23.25,48.61 23.03,48.4 20.34,48.4 19.71,49.02 MQ32.1
Net_71: length 0.3
  BOTTOM w0.203: 84.11,50.65 84.11,50.37
Net_72: length 0.3
  BOTTOM w0.203: 83.73,51.14 83.73,50.83
Net_77: length 0.3
  BOTTOM w0.203: 58.49,51.62 58.49,51.34
Net_92: length 0.3
  BOTTOM w0.203: 63.04,47 63.04,46.69
Net_93: length 0.3
  BOTTOM w0.203: 68.38,46.61 68.27,46.87
Net_96: length 0.3
  BOTTOM w0.203: 66.44,46.61 66.16,46.61
Net_97: length 0.3
  BOTTOM w0.203: 58.87,54.05 58.87,53.76
Net_101: length 0.3
  BOTTOM w0.203: 65.95,47 66.25,47
Net_107: length 0.3
  BOTTOM w0.203: 62.55,46.61 62.55,46.89
Net_109: length 0.3
  BOTTOM w0.203: 58.49,49.81 58.49,50.14
Net_111: length 0.3
  BOTTOM w0.203: 58.87,57.94 58.87,57.65
Net_115: length 0.3
  BOTTOM w0.203: 58.87,52.11 58.87,51.8
Net_127: length 0.3
  BOTTOM w0.203: 58.87,56 58.87,55.7
Net_136: length 0.3
  BOTTOM w0.203: 66.93,47 66.93,46.69
Net_140: length 0.3
  BOTTOM w0.203: 64.01,47 64.01,46.69
Net_145: length 0.3
  BOTTOM w0.203: 67.9,47 67.9,46.7
Net_152: length 0.3
  BOTTOM w0.203: 58.49,52.59 58.49,52.32
Net_157: length 0.3
  BOTTOM w0.203: 58.87,55.02 58.87,55.32
Net_166: length 0.3
  BOTTOM w0.203: 64.5,46.61 64.38,46.87
Net_173: length 0.3
  BOTTOM w0.203: 68.87,47 68.58,47
Net_178: length 0.3
  BOTTOM w0.203: 64.98,47 64.69,47
Net_181: length 0.3
  BOTTOM w0.203: 58.87,56.97 58.87,57.26
Net_186: length 0.3
  BOTTOM w0.203: 58.49,53.57 58.49,53.85
Net_187: length 0.3
  BOTTOM w0.203: 58.87,51.14 58.87,50.83
Net_200: length 0.3
  BOTTOM w0.203: 84.11,51.62 84.11,51.34
Net_1249: length 0.4
  BOTTOM w0.203: 84.11,67.87 84.11,67.52
Net_1258: length 0.3
  BOTTOM w0.203: 70.81,47 70.81,47.3
Net_1263: length 0.3
  BOTTOM w0.203: 71.79,47 71.79,47.3
Net_1265: length 0.3
  BOTTOM w0.203: 72.27,46.61 72.27,46.89
Net_1267: length 0.3
  BOTTOM w0.203: 72.76,47 72.76,47.3
Net_1307: length 0.3
  BOTTOM w0.203: 80.05,46.61 80.05,46.89
Net_1313: length 0.3
  BOTTOM w0.203: 78.1,70.24 78.1,69.96
Net_1357: length 0.3
  BOTTOM w0.203: 75.67,47 75.67,47.29
Net_1362: length 0.3
  BOTTOM w0.203: 83.73,60.86 83.73,61.16
Net_1372: length 0.3
  BOTTOM w0.203: 83.73,61.83 83.73,61.52
Net_1381: length 0.3
  BOTTOM w0.203: 83.73,62.8 83.73,63.09
Net_1388: length 0.3
  BOTTOM w0.203: 84.11,63.28 84.11,63.01
Net_1407: length 0.3
  BOTTOM w0.203: 69.84,69.85 69.84,69.55
NGFF_WIFI_RST#_R: length 5.9
  TOP w0.102: v2(40.73,8.37) 41.11,8.75 42.09,8.75 WR36.1 WC14.1 42.99,8.31 43.04,8.27 J218.52
PCBEEP: length 3.8
  TOP w0.203: AU1.2 9.98,96.89 9.91,96.82
  TOP w0.254: C174.2 8.08,95.6 8.68,96.2 9.29,96.2 9.91,96.82
PCBEEP_C: length 3.4
  TOP w0.254: SR134.2 R109.2 AC63.2 C174.1
PCH_WIFI_RF_KILL#: length 56.1
  TOP w0.102: v1(39.92,9.23) 39.92,7.58 40.2,7.3 WR35.2 ; v1(73.97,14.03) 74.67,14.73 v2(75.06,14.73)
  IN1 w0.102: v1(73.97,14.03) 73.55,14.45 73.07,14.45 72.83,14.2 72.83,13.9 72.72,13.79 72.72,13.79 72.54,13.61 70.87,13.61 70.6,13.88 69.29,13.88 68.96,13.55 68.17,13.55 67.95,13.33 65.95,13.33 65.62,13 61.79,13 61.64,13.14 59.24,13.14 56.72,10.63 52.95,10.63 51.93,9.6 50.75,9.6 49.68,10.66 47.93,10.66 47.5,11.1 45.54,11.1 45.36,10.92 41.61,10.92 v1(39.92,9.23)
  BOTTOM w0.102: v1(73.97,14.03) 74.74,14.8 74.74,17.18 78.63,21.07 78.63,22.38 79.51,23.26 79.51,23.26 79.65,23.4 U24.97
PCIE_CLKREQ0: length 12.8
  TOP w0.102: SR653.2 ST69.1 83.86,45.14 83.45,45.14 82.92,45.67 82.92,48.93 82.76,49.1 v1(82.76,49.4)
  BOTTOM w0.102: v1(82.76,49.4) 82.76,49.12 82.11,48.47 82.11,48 82.33,47.78 XU1.BG3
PCIE_CLKREQ2: length 12.1
  TOP w0.102: v1(82.14,49.63) 82.14,49.28 82.58,48.84 82.58,45.59 ST70.1 85.56,42.6 SR655.2
  BOTTOM w0.102: XU1.BG5 81.88,48.53 82.29,48.94 82.29,49.49 v1(82.14,49.63)
PCIE_CLKREQ3: length 14.3
  TOP w0.102: SR656.2 87.34,41.54 87.39,41.58 87.39,45.94 ST71.1 86.75,46.58 85.15,46.58 84.22,47.51 84.22,49.19 v1(82.87,50.53)
  BOTTOM w0.102: XU1.BE3 83.18,49.08 83.18,49.67 82.87,49.97 82.87,50.25 82.87,50.25 v1(82.87,50.53)
PCIE_RCOMP_N: length 2.1
  TOP w0.114: v1(77.89,53.55) 78.35,54.01 78.46,54.01 SR84.2
  BOTTOM w0.114: XU1.AP13 78.21,53.87 v1(77.89,53.55)
PCIE_RCOMP_P: length 2.1
  TOP w0.114: v1(77.21,53.55) 76.98,53.78 76.98,53.87 77.12,54.01 77.31,54.01 77.63,54.33 SR84.1
  BOTTOM w0.114: v1(77.21,53.55) 77.5,53.84 XU1.AP14
PCIE_RST#: length 108.5
  TOP w0.127: v1(30.78,96.36) 30.22,95.81 v2(30.22,95.54)
  IN1 w0.127: v1(56.91,98.48) 56.91,100.52 56.36,101.07 55.37,101.07 54.83,101.61 54.59,101.61 54.59,101.61 54.23,101.61 54.22,101.61 54.05,101.61 53.51,101.07 51.35,101.07 51.06,100.78 35.29,100.78 30.87,96.36 v1(30.78,96.36) ; v1(6.96,71.48) 6.49,71.01 6.49,69.35 7.23,68.61 7.23,64.17 6.32,63.26 6.32,58 7.24,57.07 v1(7.24,53.78)
  IN2 w0.127: v1(20.29,73.59) 19.32,74.56 17.7,74.56 16.58,75.68 11.97,75.68 7.77,71.48 v1(6.96,71.48)
  BOTTOM w0.127: LU1.19 55.98,97.43 56.07,97.34 56.71,97.34 57,97.63 57.11,97.63 C163.1 57.46,97.99 57.02,98.43 56.96,98.43 v1(56.91,98.48) ; v1(20.29,73.59) 20.79,74.1 21.18,74.1 22.04,74.96 23.08,74.96 23.25,74.8 SR35.2 23.8,74.23 24.38,74.81 27.81,74.81 28.31,74.3 29.79,74.3 30.08,74.6 30.08,77.9 29.16,78.83 29.16,94.24 30.78,95.86 v1(30.78,96.36) ; v1(7.24,53.78) 7.24,53.45 7.38,53.31 C302.2 7.97,54.52 8.36,54.91 U23.23
PCIE_TXN1_WLAN: length 5
  TOP w0.114: v1(82.08,51.56) 82.08,51.87 82.22,52.01 82.96,52.01 83.08,51.89 84.66,51.89 84.96,51.6 84.96,51.32 85.03,51.24 C6.2
  BOTTOM w0.114: v1(82.08,51.56) 82.08,51.98 82.2,52.1 XU1.AV4
PCIE_TXN2_CR: length 7
  TOP w0.114: v1(82.09,52.68) 82.34,52.93 84.32,52.93 84.44,53.06 84.83,53.06 84.98,52.9 86.58,52.9 86.83,53.16 86.92,53.16 86.99,53.1 86.99,52.59 87.06,52.51 SC9.2
  BOTTOM w0.114: XU1.AT6 81.84,53.17 81.98,53.17 82.09,53.07 v1(82.09,52.68)
PCIE_TXN3_LAN: length 5
  TOP w0.114: C8.1 85.12,54.01 83.61,54.01 83.02,54.59 82.79,54.59 82.32,54.12 82.32,54.05 82.38,53.98 82.67,53.98 82.74,53.91 v1(82.74,53.62)
  BOTTOM w0.114: XU1.AP4 82.59,54.04 82.74,53.89 v1(82.74,53.62)
PCIE_TXP1_WLAN: length 5
  TOP w0.114: v1(81.43,51.56) 82.12,52.25 83.06,52.25 83.18,52.13 C7.2
  BOTTOM w0.114: v1(81.43,51.56) 81.76,51.89 XU1.AV6
PCIE_TXP3_CR: length 7
  TOP w0.114: v1(81.38,52.69) 81.87,53.18 84.22,53.18 84.34,53.3 84.93,53.3 85.08,53.15 86.48,53.15 86.73,53.4 SC10.2
  BOTTOM w0.114: v1(81.38,52.69) 81.05,53.02 XU1.AT7
PCIE_TXP3_LAN: length 5.1
  TOP w0.114: C9.1 84.93,54.25 83.71,54.25 83.12,54.84 82.69,54.84 82.08,54.22 82.08,53.65 v1(82.08,53.65)
  BOTTOM w0.114: v1(82.08,53.65) 81.76,53.97 XU1.AP6
PCIE_V1P0_S3: length 17.4
  TOP w0.457: v1(75.48,54.5) C44.1 74.77,54.19 74.54,53.96 74.54,53.3 ; 75.61,49.06 75.61,49.05 75.61,48.45 75.43,48.27 75.43,47.28 74.95,46.8 C66.1 74.86,46.5 74.62,46.26 74.62,46.11
  TOP w0.508: 74.62,46.11 74.61,46.1 74.61,45.56 75.53,44.64 75.53,43.63 74.39,42.49 v2(74.39,42.2) SL15.2 SL9.1 ; 74.54,53.3 74.88,52.96 74.88,49.78 75.61,49.06
PCIE_WAKE#: length 62.6
  BOTTOM w0.102: Q9416.1 24.08,79.12 24.02,79.18 R60302.1 23.25,79.89 22.97,80.17 22.97,81.19 23.44,81.67 26.25,81.67 26.71,82.13 v2(26.71,90.89) 26.71,93.68 29.81,96.78 39.18,96.78 41.83,94.14 42.73,94.14 43.48,93.39 43.48,93.09 45.26,91.32 45.26,90.45 47.28,88.43 55.23,88.43 56.86,90.06 56.86,90.79 57.85,91.78 58.59,91.78 60.47,93.66 LQ3.3
PCIE_WAKE#_WLAN: length 99.7
  TOP w0.102: v1(54.25,13.99) 54.25,13.99 54.25,10.3 55.34,9.2 WR84.1
  IN2 w0.102: v1(54.25,13.99) 54.04,14.2 47.43,14.2 46.31,13.08 41.75,13.08 40.36,14.46 37.8,14.46 37.42,14.84 37.03,15.24 33.11,19.15 33.11,20.89 32.22,21.78 30.1,21.78 29.8,22.08 29.8,27.54 28.58,28.76 28.58,35.33 29.19,35.94 29.19,38.7 28.39,39.5 28.39,48.37 28,48.76 28,57.57 25.19,60.38 25.19,60.7 23.76,62.12 23.06,62.12 19.12,66.07 19.12,68.64 v1(19.55,69.07) 21.56,71.08 21.56,74.1 v1(21.05,74.61)
  BOTTOM w0.102: v1(21.05,74.61) 21.68,75.24 22.61,75.24 R60309.1 23.25,76.58 23.33,76.67 v2(23.33,76.92) ; Q3.4 19.48,69.01 v1(19.55,69.07)
PCU_SMB_ALERT#: length 7
  BOTTOM w0.102: XU1.BG11 79.07,47.07 79.07,47.05 79.34,46.78 79.35,46.77 79.35,46.48 79.86,45.97 79.86,45.27 81.45,43.68 v2(81.45,42.94) 81.45,42.03 SR640.2
PCU_SMB_CLK: length 53.5
  TOP w0.127: v1(52.16,31.56) 52.16,31.52 SR110.2 52.57,30.48 51.97,30.48 51.6,30.1 U3.3 ; v1(81.96,42.3) 81.96,43.29 v2(81.86,43.39) ; v1(49.96,27.85) 49.96,26.49 50.15,26.29 U4.3
  IN1 w0.127: v1(81.96,42.3) 81.94,42.3 81.55,41.91 81.55,39.28 80.82,38.54 80.82,37.54 78.2,34.93 72.65,34.93 71.82,34.1 54.71,34.1 52.52,31.9 52.51,31.9 v1(52.16,31.56)
  IN2 w0.127: v1(52.16,31.56) 52.16,30.82 49.96,28.61 v1(49.96,27.85)
  BOTTOM w0.127: v1(81.96,42.3) 81.96,43.87 80.08,45.75 80.08,46.06 79.72,46.42 79.72,46.7 79.57,46.86 79.56,46.87 XU1.BH10
PCU_SMB_DATA: length 59.9
  TOP w0.127: U4.2 51.86,25.64 52.18,25.96 v1(52.18,27.13) ; SR111.2 52.58,29.97 v1(52.27,29.65) 52.07,29.45 U3.2 50.44,29.45 50.21,29.22 49.63,29.22 v1(49.62,29.22)
  IN1 w0.127: v1(80.51,42.94) 80.51,41.01 80.66,40.86 80.66,39.31 80.31,38.96 80.31,37.75 77.99,35.44 72.42,35.44 71.59,34.6 54.5,34.6 52.3,32.41 52.3,32.41 50.23,30.34 50.23,29.82 v1(49.62,29.22)
  BOTTOM w0.102: 78.5,44.89 78.38,45.01 78.38,46.77 78.36,46.8 78.36,46.82 78.3,46.88 78.3,47.12 78.5,47.32 78.5,47.61 XU1.BG12
  BOTTOM w0.127: v1(80.51,42.94) 80.51,43.57 79.82,44.26 79.14,44.26 78.5,44.89 ; v1(52.18,27.13) 52.19,27.13 52.19,29.57 v1(52.27,29.65) 52.27,29.9 52.82,30.46 52.82,31.48 53.1,31.76 53.79,31.76 54.4,31.15 54.4,30.24 v2(54.65,29.98)
PDA_TEST1: length 4.9
  BOTTOM w0.102: ST72.1 67.78,44.21 69.8,46.22 69.8,46.96 XU1.BH30
PDA_TEST2: length 8.7
  BOTTOM w0.102: XU1.BG30 69.84,47.41 70.13,47.12 70.13,46.88 70,46.75 70,46.14 68.34,44.48 68.34,42.56 66.45,40.67 ST73.1
PLT_THERMAL_EC: length 28.7
  TOP w0.102: v1(68.78,23.91) 68.42,23.55 O2R243.1
  IN2 w0.102: v1(68.78,23.91) 69.89,25.03 70.33,25.03 71.35,26.05 71.35,27.36 66.9,31.81 66.9,33.71 65.07,35.54 65.07,42.03 65.71,42.68 65.71,43.15 v1(65.37,43.49)
  BOTTOM w0.102: v2(64.58,43.01) 65.07,43.49 v1(65.37,43.49) 66.17,43.49 PRT4.1 ; v1(68.78,23.91) 68.8,23.91 68.92,24.03 U24.70
PLTRST#: length 170.1
  TOP w0.127: v1(92.56,13.52) 92.36,13.32 92.36,13.28 92.11,13.03 90.24,13.03 89.91,13.36 89.91,14.76 88.19,16.47 88.19,19.69 91.33,22.83 91.33,23.47 v1(91.76,23.9) ; v1(40.38,7.73) 40.16,7.95 40.16,8.78 40.58,9.2 WR36.2 41.32,9.6 40.19,9.6 38.88,10.91 v1(38.88,12.73)
  IN1 w0.127: v1(40.38,7.73) 40.4,7.73 40.83,8.16 48,8.16 48.33,7.83 52.29,7.83 52.86,8.4 63.71,8.4 64.56,9.25 70.55,9.25 v1(71.59,8.21)
  IN2 w0.127: v1(92.56,13.52) 91.98,14.11 84.92,14.11 81.53,10.71 79.98,9.17 76.84,9.17 76.57,8.9 72.27,8.9 v1(71.59,8.21) ; v1(21.05,73.57) 21.05,72.48 18.88,70.3 18.88,65.88 20.62,64.14 20.62,63.16 25.69,58.1 25.69,57.47 26.19,56.97 26.19,49.1 27.39,47.9 27.39,39.08 28.19,38.29 28.19,36.51 27.58,35.9 27.58,27.16 27.44,27.03 27.44,19.6 28.31,18.73 28.31,18.42 28.95,17.79 33.63,17.79 37.41,14 37.55,13.86 38.46,13.86 38.88,13.45 v1(38.88,12.73)
  BOTTOM w0.127: v2(20.92,72.81) 20.92,73.44 v1(21.05,73.57) 21.71,74.23 SR35.1 SR29.2 22.41,73.02 22.52,72.91 24.38,72.91 24.38,72.91 25.14,72.91 25.57,73.34 Q9414.3 ; v1(91.76,23.9) 91.75,23.9 91.55,24.1 CB3.1 90.9,24.7 90.92,24.72 TPU1.16 ; U24.22 70.92,8.6 71.03,8.49 71.03,7.52 70.96,7.45 SC24.1 71.25,6.83 71.59,7.16 v1(71.59,8.21)
PM_CLKRUN#: length 25.2
  TOP w0.127: v1(83.15,27.87) 82.26,26.98 v2(80.82,26.98) v1(78.2,26.98)
  IN2 w0.127: v1(74.59,38.96) 75.01,38.54 78.46,38.54 83.15,33.84 v1(83.15,27.87)
  BOTTOM w0.127: SR108.2 74.77,39.14 v1(74.59,38.96) ; U24.93 78.12,26.9 v1(78.2,26.98)
PM_PWRBTN#: length 99.8
  IN1 w0.127: v1(71.59,21.52) 71.29,21.22 68.88,21.22 68.78,21.32 61.91,21.32 61.49,20.9 59.76,20.9 58.87,20.02 58.01,20.02 57.21,19.21 54.6,19.21 54.48,19.34 53.2,19.34 52.72,18.86 48.97,18.86 48.9,18.79 47.25,18.79 44.62,21.42 42.85,21.42 42.38,20.95 31.7,20.95 30.95,20.2 29.48,20.2 29.37,20.32 28.19,20.32 v1(27.88,20.01)
  IN2 w0.127: v1(27.88,20.01) 27.69,20.2 27.69,26.92 27.83,27.06 27.83,35.64 28.44,36.25 28.44,38.39 27.64,39.19 27.64,48.01 26.59,49.06 26.59,55.38 v1(26.63,55.42)
  BOTTOM w0.127: v1(26.63,55.42) 26.63,54.08 26.3,53.75 25.4,53.75 25.03,54.12 21.09,54.12 19.59,55.62 Q2.1 18.74,55 18.56,54.82 17.54,54.82 v2(17.01,54.29) ; U24.76 71.32,21.8 v1(71.59,21.52)
PM_PWRBTN#_1P8VSB: length 126.2
  TOP w0.127: v2(19.42,60.51) v1(18.79,59.88) ; v1(72.22,66.08) 72.22,66.13 72.74,66.65 72.74,66.82 73.78,67.85 73.78,68.96 75.49,70.67 75.59,70.67 76.04,71.12 76.04,74.47 v1(75.62,74.89) 76.07,75.33 76.07,75.72 75.91,75.87 C941163.1 76.34,76.78 76.34,77.78 75.91,78.21 SR37.2
  IN1 w0.127: v1(75.62,74.89) 75.62,74.94 75.2,75.36 75.2,75.52 73.49,77.24 73.05,77.24 70.91,79.38 70.91,80.38 71.39,80.87 71.39,83.74 70.01,85.12 68.57,85.12 67.63,86.07 67.27,86.07 66.61,85.42 64.67,85.42 64.17,85.92 62.93,85.92 62.37,86.47 61.49,86.47 59.33,88.63 57.68,88.63 56.42,89.89 56.42,91.73 55.31,92.85 48.91,92.85 48.43,93.33 45.86,93.33 44.92,94.27 39.94,94.27 39.4,94.81 37.58,94.81 36.94,94.16 34.92,94.16 34.12,94.96 22.67,94.96 20.11,92.4 17.9,92.4 16.86,91.36 16.86,81.87 18.56,80.17 18.56,76.7 19.52,75.74 19.52,70.19 20.54,69.17 20.54,66.07 19.4,64.93 19.4,60.49 v1(18.79,59.88)
  BOTTOM w0.127: v1(18.79,59.88) Q1.3 ; XU1.J26 72.16,66.08 v1(72.22,66.08)
PM_PWRBTN#_G: length 6.6
  BOTTOM w0.127: v2(17.01,60) 16.9,59.89 R4.1 17.58,58.99 17.65,58.93 Q1.1 19.59,58.93 20.82,57.69 Q2.3
PMC_ACPRESENT: length 11
  TOP w0.102: SR641.2 v1(76.78,77.61)
  BOTTOM w0.102: XU1.D20 74.96,68.84 74.96,68.86 75.48,69.38 75.48,69.62 75.38,69.72 75.38,69.98 75.47,70.07 75.47,70.57 75.84,70.93 75.84,71.83 76.69,72.68 76.69,73.53 77.18,74.03 v2(77.18,75.09) 77.18,75.45 76.78,75.85 v1(76.78,77.61)
PMC_BAT_LOW#: length 14.9
  TOP w0.102: SR642.2 72.81,78.08 72.81,74.23 73.27,73.77 v2(73.27,73.21) 72.9,72.84 72.9,70.56 71.74,69.39 71.74,65.92 v1(72.26,65.4)
  BOTTOM w0.102: v1(72.26,65.4) 72.13,65.4 XU1.K26
PMC_CORE_PWROK: length 86
  TOP w0.102: v2(90.8,15.43) 90.8,15.96 90.57,16.19 v1(90.57,16.2)
  IN1 w0.102: v1(86.96,73.47) 86.96,70.77 93.83,63.9 93.83,60.93 95.72,59.03 95.72,58.35 96.97,57.11 96.97,55.52 99.92,52.58 99.92,51.45 100.79,50.58 100.79,46.96 98.14,44.3 98.14,42.35 95.42,39.63 94.4,39.63 93.96,39.19 93.96,23.88 90.87,20.79 90.87,16.51 v1(90.57,16.2)
  BOTTOM w0.102: SR152.2 SC23.1 86.03,14.12 87.47,15.55 89.92,15.55 90.57,16.2 v1(90.57,16.2) ; v1(86.96,73.47) SR41.1 86.43,73.66 86.43,72.58 85.54,71.69 84.46,71.69 83.79,71.02 82.02,71.02 81.38,70.37 81.38,69.88 XU1.B7
PMC_CORE_PWROK_EC: length 3.1
  BOTTOM w0.102: SR152.1 83.15,13.01 83.01,13.15 v2(82.64,13.15) 82.1,12.61 U24.124
PMC_PLTRST#_1P8V: length 94.9
  TOP w0.127: v2(74.87,69.27) 74.87,68.76 v1(74.25,68.15)
  IN1 w0.127: v1(74.25,68.15) 74.69,68.58 74.69,71.87 73.94,72.62 73.94,73.98 74.39,74.43 74.39,75.62 73.92,76.08 73.48,76.08 70.4,79.16 70.4,80.65 70.88,81.13 70.88,83.53 69.85,84.57 67.78,84.57 67.36,84.15 64.14,84.15 63.64,84.65 62.37,84.65 61.82,85.2 60.9,85.2 59.5,86.6 57.82,86.6 56.02,88.4 55.86,88.56 55.48,88.56 53.53,90.51 53.53,91.09 53.04,91.58 47.63,91.58 47.57,91.64 40.78,91.64 38.87,93.54 38.11,93.54 37.38,92.81 35.41,92.81 35.18,92.58 32.7,92.58 31.53,91.4 31.53,78.87 28.71,76.05 28.71,70.05 v1(27.86,69.2)
  BOTTOM w0.127: v1(27.86,69.2) 26.69,69.2 26.18,69.71 24.22,69.71 23.99,69.48 22.86,69.48 SR662.1 ; v1(74.25,68.15) 74.46,68.15 XU1.F20
PMC_RSMRST#: length 86.3
  IN1 w0.102: v1(82.64,73.57) 82.96,73.25 83.14,73.25 87.01,69.38 88.07,69.38 91.39,66.05 91.39,64.77 93.63,62.53 93.63,60.84 95.52,58.95 95.52,58.27 96.77,57.02 96.77,55.44 99.71,52.49 99.71,51.37 100.59,50.49 100.59,47.04 97.93,44.39 97.93,42.43 95.33,39.83 94.32,39.83 93.76,39.28 93.76,33.79 92.96,32.99 92.96,23.2 90.04,20.28 90.04,18.37 v1(90.34,18.07)
  BOTTOM w0.102: XU1.B10 79.56,70.13 80.71,71.28 80.71,72.58 81.93,73.8 SR46.1 C941162.1 82.77,73.69 v1(82.64,73.57) ; v1(90.34,18.07) 90.04,17.76 87.55,17.76 85.39,15.6 R212.2
PMC_RSMRST#_EC: length 4
  BOTTOM w0.102: U24.112 82.06,17.4 82.85,16.62 82.85,16.43 83.11,16.18 83.56,16.18 R212.1
PMC_SUS_STAT#: length 5.6
  TOP w0.127: ST29.1 76.71,71.69 76.71,71.01 76.03,70.33 76.03,68.74 75.66,68.37 75.66,67.9 v1(76.1,67.45)
  BOTTOM w0.127: v1(76.1,67.45) 75.83,67.18 XU1.G18
PMC_SUSCLK: length 108.9
  TOP w0.127: v1(72.24,66.86) 72.24,67.03 73.27,68.06 73.27,69.33 74.62,70.68 74.62,71.76 74.57,71.81 74.57,73.12 74.62,73.17 74.62,73.35 v1(74.63,73.36) 74.63,75.11 74.19,75.55 SC27.1
  IN1 w0.127: v1(26.84,71.69) 27.95,72.79 27.95,76.37 30.76,79.18 30.76,91.91 32.79,93.94 34.43,93.94 34.71,93.66 37.15,93.66 37.79,94.3 39.19,94.3 41.09,92.4 47.89,92.4 47.95,92.34 54.32,92.34 55.82,90.83 55.82,89.7 58.16,87.36 59.86,87.36 61.26,85.96 62.15,85.96 62.7,85.41 63.96,85.41 64.46,84.91 v1(67.05,84.91)
  IN2 w0.127: v1(67.05,84.91) 67.7,84.91 68.9,86.1 75.29,86.1 76.02,85.37 76.02,81.89 76.09,81.82 76.09,80.25 76.02,80.19 76.02,78.09 76.12,78 76.12,77.69 75.05,76.63 75.05,73.78 v1(74.63,73.36)
  BOTTOM w0.127: v2(19.42,73.87) 19.42,73.16 20.17,72.41 20.17,71.26 20.6,70.82 22.71,70.82 R2.1 23.49,70.53 23.49,71.48 23.69,71.69 v1(26.84,71.69) ; v1(72.24,66.86) 72.43,66.86 XU1.G24
PMC_WAKE_PCIE#: length 100.2
  TOP w0.102: v1(72.23,68.18) 72.64,68.58 72.64,69.4 74.12,70.88 74.12,71.55 74.07,71.6 74.07,73.32 74.12,73.37 74.12,74.91 v1(73.67,75.37) 73.67,77.99 SR36.2
  IN1 w0.102: v1(29.65,74.83) 30.04,75.22 30.04,76.05 32.28,78.29 32.28,90.15 33.82,91.7 35.36,91.7 35.72,92.06 39.3,92.06 40.47,90.89 47.26,90.89 47.38,90.77 51.32,90.77 54.28,87.81 55.55,87.81 58.91,84.45 61.51,84.45 62.73,83.23 69.45,83.23 69.91,82.78 69.91,78.96 73.49,75.37 v1(73.67,75.37)
  IN2 w0.102: v1(23.87,70.19) 28.5,74.83 v1(29.65,74.83)
  BOTTOM w0.102: Q3.3 21.29,69.01 22.06,69.78 23.46,69.78 v1(23.87,70.19) ; v2(27.55,82.48) 27.17,82.1 Q9416.3 27.17,77.3 v1(29.65,74.83) ; v1(72.23,68.18) 72.17,68.18 XU1.F26
PMU_SLP_S0IX#_1P8V: length 1.7
  TOP w0.102: v1(76.11,68.15) 76.67,68.72 ST78.1
  BOTTOM w0.102: XU1.F18 75.85,67.89 v1(76.11,68.15)
PMU_SLP_S3: length 12
  TOP w0.127: v1(29.61,33.96) 29.7,33.87 v2(30.52,33.87)
  BOTTOM w0.127: v1(29.61,33.96) 28.1,32.44 MQ7.3 26.54,32.44 26.13,32.04 24.33,32.04 23.94,32.42 23.94,33.27 SR65.2 SC7.1 24.26,34.73 24.33,34.8 MQ6.1
PMU_SLP_S3#_1P8V: length 138.6
  TOP w0.127: v1(22.73,30.77) 22.73,30.54 22.57,30.38 22.57,29.83 23.07,29.33 v2(23.07,28.08)
  IN1 w0.127: v1(74.21,68.78) 74.21,69.38 74.44,69.6 74.44,71.74 73.69,72.49 73.69,74.09 74.13,74.53 74.13,75.51 73.82,75.83 73.38,75.83 70.15,79.06 70.15,80.76 70.63,81.24 70.63,83.42 70.38,83.68 69.69,83.68 69.49,83.47 62.83,83.47 61.61,84.69 59.01,84.69 55.65,88.05 54.38,88.05 51.42,91.01 47.48,91.01 47.36,91.13 40.57,91.13 39.4,92.3 35.62,92.3 35.39,92.07 32.91,92.07 32.03,91.19 32.03,78.66 29.22,75.84 29.22,54.96 23.03,48.78 18.31,48.78 16.87,47.34 16.87,39.74 17.1,39.51 18.22,39.51 v1(18.84,38.88)
  IN2 w0.127: v1(22.73,30.77) 22.8,30.84 22.8,35.75 19.67,38.88 v1(18.84,38.88)
  BOTTOM w0.127: v1(74.21,68.78) 73.96,68.78 XU1.D22 ; R60297.1 SR665.2 22.53,30.86 22.62,30.77 v1(22.73,30.77)
PMU_SLP_S4: length 10.1
  BOTTOM w0.127: MQ9.3 20.69,64.86 20.02,65.53 MQ8.1 17.62,65.53 17.56,65.59 SR71.2 ; v2(14.88,67.32) 14.88,66.22 15.13,65.97 15.49,65.97 15.54,66.02 16.34,66.02 SR71.2 ; SC8.1 SR71.2
PMU_SLP_S4#_1P8V: length 113.6
  IN1 w0.127: v1(74.3,67.51) 74.95,68.15 74.95,71.97 74.2,72.72 74.2,73.88 74.64,74.32 74.64,75.72 74.03,76.34 73.59,76.34 70.66,79.27 70.66,80.49 71.14,80.97 71.14,83.63 69.95,84.82 67.68,84.82 67.26,84.4 64.25,84.4 63.75,84.9 62.48,84.9 61.92,85.45 61.03,85.45 59.63,86.85 57.93,86.85 55.96,88.82 55.58,88.82 53.79,90.6 53.79,91.18 53.14,91.83 47.74,91.83 47.68,91.89 40.88,91.89 38.98,93.79 38,93.79 37.27,93.06 35.31,93.06 35.08,92.83 32.6,92.83 31.27,91.51 31.27,78.97 28.45,76.15 28.45,70.41 27.42,69.38 27.42,62.75 v1(27.91,62.26)
  BOTTOM w0.127: v1(74.3,67.51) 74.12,67.51 XU1.F22 ; SR664.2 16.36,61.73 16.57,61.73 16.58,61.72 17.07,61.72 17.44,61.35 19.34,61.35 20.43,62.43 21.18,62.43 21.89,63.14 21.89,63.64 22.18,63.94 24.17,63.94 24.38,63.74 25.51,63.74 26.98,62.26 v1(27.91,62.26) ; SR664.2 R60298.1 ; SR664.2 14.98,61.21 v2(14.98,60.69)
PQ15_G: length 6.9
  BOTTOM w0.102: v2(51.35,14.11) 52.09,14.11 52.96,13.24 PQ17.1 52.96,12.05 52.16,11.26 52.16,9.92 52.51,9.57 52.51,8.82
PQ16_2: length 2.9
  BOTTOM w0.102: v2(52.38,4.34) 52.51,4.47 PR95.2 52.19,5.37 51.96,5.14 51.56,5.14 51.43,5.27 PQ18.2
PQ16_4: length 7.8
  BOTTOM w0.102: v2(47.06,3.97) 47.7,4.62 PQ18.4 49.02,4.62 49.24,4.84 49.24,5.98 50.78,7.51 52.04,7.51 PR93.1
PQ17_D: length 7.1
  BOTTOM w0.102: v2(45.84,7.63) 46.53,8.31 PQ19.3 51.66,8.31 52.04,7.93 PR94.2
PQ17_G: length 3.3
  BOTTOM w0.102: v2(46.83,6.16) 47.43,6.16 47.67,5.92 PQ18.5 48.5,6.76 48.58,6.84 PQ19.1
PQ28_G: length 3.1
  TOP w0.102: v1(28.79,19.89) v2(28.79,20.6)
  BOTTOM w0.254: PQ14.3 v1(28.79,19.89) 28.56,19.89 28.17,19.5 27.69,19.5 27.68,19.52 27.68,19.52 27.55,19.64 PR81.2
PQ31_G: length 2.4
  TOP w0.254: v2(24.88,34.81) 24.83,34.86 PR67.2 23.88,35.39 23.78,35.49 PQ8.1
PQ32_2: length 4.5
  TOP w0.102: PR76.2 20.88,29.46 21.14,29.2 v2(21.14,28.54) ; PR76.2 20.46,29.78 20.44,29.8 PC67.1 PR80.2 ; PR76.2 20.88,30.38 20.92,30.42 PQ11.2
PQ32_4: length 4.2
  TOP w0.254: v2(23.08,30.15) 23.36,30.43 23.36,30.98 PR72.1 21.57,32.77 PQ11.4
PQ33_D: length 4
  TOP w0.254: PQ13.3 21.3,37.8 21.61,37.5 21.61,36.45 21.26,36.1 PR75.2
PQ33_G: length 4.7
  TOP w0.102: PQ11.5 19.32,33.51 v2(18.89,33.08)
  TOP w0.254: PQ11.5 20.27,33.97 20.08,34.16 20.08,34.72 20.35,34.99 PQ13.1
PQ34_2: length 14.1
  TOP w0.102: v2(19.32,58.18) 17.87,56.73 17.87,54.66 18.14,54.4 18.14,52.57 17.11,51.55 17.11,50.71 17.3,50.52 PR74.2 17.96,50.52 18.13,50.35 PQ10.2 19.52,50.35 19.88,50 19.88,48.71 PC66.1 PR77.2
PQ34_4: length 5.6
  TOP w0.254: PQ10.4 21.8,49.7 22.01,49.92 22.01,50.43 22.17,50.58 22.17,52.23 22.45,52.51 v2(23.21,52.51) 23.41,52.71 23.41,53.15 23.42,53.15 PR71.1
PQ35_D: length 4
  TOP w0.102: PR73.2 23.8,55.24 v2(23.51,55.53)
  TOP w0.254: PQ12.3 22.17,53.65 22.93,54.42 PR73.2
PQ35_G: length 7
  TOP w0.102: PQ12.1 19.28,55.69 19.46,55.86 v2(19.91,55.86)
  TOP w0.254: PQ12.1 19.97,54.6 20.29,54.29 20.29,51.37 20.65,51 PQ10.5
PQ36_G: length 7
  BOTTOM w0.102: PR100.2 55.78,37.18 56.51,37.91 56.51,39.96 57.28,40.73 PQ20.1 58.31,42.43 v2(58.31,42.81)
PQ37_2: length 6
  BOTTOM w0.102: PR104.2 54.5,25.63 54.51,25.64 54.51,26 54.27,26.24 53.79,26.24 52.29,24.74 PQ21.2 v2(52.29,22.46)
PQ37_4: length 9.3
  BOTTOM w0.102: PQ21.4 51.64,28.51 51.43,28.72 v2(51.43,29.07) 51.43,29.41 52.58,30.56 52.58,31.73 52.34,31.98 52.08,31.98 51.91,32.15 51.91,33.55 52.15,33.8 PR102.1
PQ38_D: length 6
  BOTTOM w0.102: v2(54.68,32.19) 53.79,32.19 53.13,32.85 PQ22.3 52.42,33.51 52.72,33.82 54.3,33.82 54.62,34.13 PR103.2
PQ38_G: length 6.7
  BOTTOM w0.102: PQ22.1 53.37,30.04 52.58,29.26 52.58,27.28 52.61,27.26 52.61,27.17 52.94,26.84 PQ21.5 53.38,26.27 54.02,26.91 v2(54.37,26.91)
PQ79_G: length 3.3
  TOP w0.254: PR69.2 25.49,51.34 25.68,51.15 PQ9.1 27.05,50.51 v2(27.53,50.99)
PQ710_G: length 7.2
  BOTTOM w0.102: PR186.2 107.32,57.27 106.8,56.75 106.8,55.7 PC136.1 107.49,52.2 107.44,52.16 PQ41.1
PQ711_G: length 8.9
  TOP w0.102: v2(106.78,53.55) 106.29,53.06 v1(106.29,51.98)
  BOTTOM w0.102: PR182.2 106.53,55.01 107.23,54.31 107.23,53.5 107.1,53.37 PQ41.3 106.49,52.18 v1(106.29,51.98) 106.01,52.26 105,52.26 104.24,51.51 PQ32.1
PQ9546_G: length 3.4
  BOTTOM w0.102: PQ28.1 53.94,17.43 v2(54.32,17.81) 54.41,17.9 PR141.2 PR139.2
PQ9550_G: length 17.8
  BOTTOM w0.102: v2(109.87,71.97) 109.64,71.74 109.64,70.77 109.02,70.15 108.2,70.15 107.82,70.54 107.82,71.06 107.12,71.75 103.91,71.75 103.41,71.26 PQ43.1 103.41,70.05 103.79,69.67 104.77,69.67 104.87,69.57 104.87,69.17 105.17,68.87 PQ44.3 107.66,68 107.46,67.8 106.66,67.8 PR196.2
PQ9551_G: length 8.4
  BOTTOM w0.102: v2(109.87,68.84) 109.87,68.73 109.01,67.87 109.01,67.68 108.61,67.28 PR201.2 ; PR201.2 108.35,69.45 107.89,69.91 106.82,69.91 106.71,70.02 PQ44.1 ; PR201.2 107.87,67.28 107.87,67.28 PC141.1
PQ9552_D: length 4.7
  BOTTOM w0.102: v2(23.56,14.08) 23.11,14.54 PQ16.3 23.84,16.32 23.97,16.19 23.97,15.55 24.14,15.39 PR84.2
PQ9552_G: length 7.2
  BOTTOM w0.102: v2(21.79,14.08) 21.35,14.08 21.02,14.41 PQ16.1 21.91,15.37 22.19,15.65 22.19,16.61 22.32,16.74 22.32,18.73 22.53,18.94 PQ15.5
PQ9553_2: length 4.6
  BOTTOM w0.102: PQ15.2 19.91,19.59 19.8,19.49 PR86.2 19.44,19.17 19.65,18.96 19.65,18.63 19.52,18.5 19.52,16.65 v2(19.32,16.44)
PQ9553_4: length 4
  BOTTOM w0.102: PQ15.4 23.6,20.24 v2(24.5,19.34) 24.5,18.06 24.69,17.87 PR83.1
PQ9557_G: length 3.1
  TOP w0.102: v2(25.47,25.37) PR131.2 27.27,25.37 27.29,25.39 PQ25.1
PROCHOT#: length 239.4
  TOP w0.127: PD3.1 PD3.2 102.32,100.69 103.17,100.69 103.55,101.08 104.92,101.08 105.86,100.14 108.11,100.14 109.86,98.39 109.86,87.41 109.69,87.25 109.69,82.16 109.81,82.05 109.81,63.41 108.32,61.92 108.32,57.59 108.13,57.39 108.13,50.94 106.9,49.72 106.7,49.72 v1(106.34,49.36) ; v1(113,23.05) 111.6,23.05 110.59,24.05 93.64,24.05 v2(92.33,25.37) 92.33,27.08 91.22,28.19 84.77,28.19 82.47,25.88 82.47,24.9 v1(82.44,24.88)
  IN1 w0.127: v1(113,23.05) 114.84,24.89 114.84,31.49 109.06,37.27 109.06,40.06 107.21,41.92 107.21,43.65 107.46,43.9 107.46,47.63 106.34,48.75 v1(106.34,49.36) ; v1(82.44,24.88) 82.44,24.52 78.63,20.71 68.67,20.71 68.57,20.81 62.12,20.81 61.7,20.39 59.97,20.39 59.08,19.51 58.22,19.51 57.42,18.7 54.81,18.7 54.33,18.22 53.54,18.22 53.45,18.31 49.15,18.31 49.12,18.28 46.82,18.28 44.8,20.3 34.82,20.3 33.76,19.24 v1(28.77,19.24)
  IN2 w0.127: v1(23.97,61.32) 23.64,61 23.64,60.51 26.07,58.08 26.3,58.08 27.06,57.32 27.06,55.25 26.84,55.02 26.84,49.17 27.9,48.11 27.9,39.3 28.69,38.5 28.69,36.14 28.08,35.54 28.08,25.23 28.56,24.76 28.56,23.92 29.23,23.25 29.23,19.69 v1(28.77,19.24)
  BOTTOM w0.127: v1(23.97,61.32) 23.07,61.32 22.41,61.99 R60299.1 ; R214.2 81.36,27.54 82.16,27.54 82.44,27.26 v1(82.44,24.88)
PROCHOT#_EC: length 7.1
  BOTTOM w0.127: U24.99 81.85,22.6 82.01,22.77 82.01,26.04 v2(81.3,26.76) 80.94,27.11 80.94,27.12 R214.1
PROCHOT#_VR: length 142.9
  TOP w0.102: v2(19.27,68.18) 19.27,67.9 v1(19.63,67.55)
  IN1 w0.102: v1(96.87,75.88) 96.47,75.49 93.68,75.49 86.18,82.98 77.78,82.98 75.28,85.48 68.56,85.48 67.12,86.92 63.67,86.92 62.67,87.92 60.39,87.92 58.79,89.52 57.62,89.52 57.27,89.87 57.27,91.56 55.74,93.09 50.06,93.09 48.99,94.15 45.37,94.15 45.02,94.51 40.04,94.51 39.5,95.05 37.61,95.05 36.19,96.48 36.18,96.48 33.58,96.48 33.57,96.48 32.63,95.54 22.9,95.54 20.01,92.64 17.8,92.64 16.62,91.46 16.62,81.77 18.32,80.07 18.32,76.6 19.28,75.64 19.28,70.02 20.29,69.02 20.29,68.21 v1(19.63,67.55)
  IN2 w0.102: v1(96.87,75.88) 96.87,72.2 98.7,70.36 98.7,67.21 96.41,64.92 96.41,64.39 v1(94.85,62.82)
  BOTTOM w0.102: v1(19.63,67.55) 20.46,67.55 20.82,67.19 21.4,67.19 21.81,66.79 R60226.1 ; PR192.2 94.57,62.54 v1(94.85,62.82) 95.08,62.59 96.53,62.59 97.72,61.4 97.72,61.24 97.99,60.97 98.48,60.97 98.6,60.86 PU9.6
PROCHOT_CPU#: length 102
  IN1 w0.127: v1(28.29,65.87) 28.29,68.77 28.96,69.44 28.96,75.94 31.78,78.76 31.78,91.3 32.81,92.32 35.29,92.32 35.52,92.55 39.5,92.55 40.67,91.38 47.47,91.38 47.58,91.27 51.31,91.27 51.52,91.27 54.48,88.31 55.75,88.31 58.48,85.58 59.79,85.58 60.42,84.95 61.71,84.95 62.93,83.73 67.61,83.73 68.01,84.13 v1(68.06,84.13)
  IN2 w0.127: v1(68.06,84.13) 69.52,85.59 75.08,85.59 75.51,85.16 75.51,82.41 74.88,81.78 v1(74.88,80.11)
  BOTTOM w0.102: 73.13,71.48 72.99,71.34 72.99,70.81 72.99,70.42 72.96,70.4 72.96,70.06 73.05,69.98 73.05,69.72 72.84,69.51 72.84,69.24 XU1.C24
  BOTTOM w0.127: v1(74.88,80.11) 74.88,79.98 73.2,78.29 73.09,78.29 72.81,78.01 72.81,76.5 73.52,75.8 73.84,75.8 74.13,75.51 74.13,74.46 73.68,74 73.68,73.19 73.13,72.65 73.13,71.48 ; v2(68.88,84.13) v1(68.06,84.13) ; v1(28.29,65.87) 28.29,66.28 27.96,66.61 MQ25.3 24.81,66.61 23.74,67.67 R9.2 R60226.2
PROHOT_R#: length 7.5
  TOP w0.102: PU2.9 98,100.88 v1(98.2,100.68) 98.52,100.36 PC13.1 99.03,100.05 PD3.3 99.71,98.63 99.32,98.24 98.02,98.24 PR15.2
  BOTTOM w0.102: v2(98.37,101.63) 98.37,100.85 v1(98.2,100.68)
PU12_ALERT#: length 2.9
  BOTTOM w0.127: PR200.2 96.86,60.31 97.49,60.31 v2(97.67,60.13) 97.74,60.06 PU9.4
PU12_ISEN2: length 3.2
  BOTTOM w0.102: PR233.1 96.55,62.8 96.77,62.8 97.11,62.46 v2(97.68,62.46) 97.85,62.46 98.64,61.66 PU9.8
PU12_SCLK: length 7.1
  BOTTOM w0.127: PU9.3 98,59.66 97.96,59.62 PR198.2 96.2,59.18 96.11,59.18 95.92,58.99 94.72,58.99 94.53,59.18 92.91,59.18 92.72,59.37 v2(92.3,59.37)
PU12_SDA: length 4.1
  TOP w0.127: v1(98.26,60.55) v2(98.26,59.47)
  BOTTOM w0.127: PU9.5 98.36,60.46 v1(98.26,60.55) 97.97,60.55 97.39,61.12 96.93,61.12 PR202.2
PWR_LED: length 42.5
  TOP w0.102: R330.2 R370.2 R368.2 104.5,16.48 v1(103.6,15.58)
  IN2 w0.102: v1(103.6,15.58) 103.1,15.08 97.5,15.08 96.99,14.56 84.75,14.56 81.08,10.89 79.8,9.61 71.13,9.61 v1(69.73,8.21)
  BOTTOM w0.102: v2(102.84,15.63) 103.55,15.63 v1(103.6,15.58) ; v1(69.73,8.21) 69.72,8.23 U24.25
PWR_LED#: length 40.4
  TOP w0.102: R357.2 R371.2 R332.2 102.89,13.86 102.68,14.07 v1(102.68,14.16)
  IN2 w0.102: v1(102.68,14.16) 102.14,14.7 97.41,14.7 97.07,14.36 84.83,14.36 81.28,10.81 79.88,9.41 76.65,9.41 76.38,9.14 71.38,9.14 70.45,8.21 v1(70.37,8.21)
  BOTTOM w0.102: U24.24 70.12,8.46 v1(70.37,8.21) ; v1(102.68,14.16) 102.76,14.23 v2(103.93,14.23)
PWR_LED+: length 16.3
  TOP w0.102: SW10.L1 101.95,5.8 102.53,6.38 103.22,6.38 104.23,7.4 R160.2 R159.2 105.78,11.45 106.3,11.97 Q30.3 CB10.1 106.47,10.38 106.27,10.18 106.27,8.57 v2(106.93,7.91)
PWR_LED-: length 12.2
  TOP w0.102: CB12.1 101.13,14.83 101.31,14.64 Q31.3 101.31,12.59 R170.2 ; SW10.L2 101.95,8.9 103.34,10.3 R169.2 R170.2 ; R170.2 101.76,10.75 v2(101.44,10.75)
PWR_SW#: length 3.4
  BOTTOM w0.102: U24.125 81.88,12.2 v2(82.67,11.41) 83.38,12.12 R216.2
PWRBTN#: length 24.8
  TOP w0.102: SW10.1 99.93,5.66 99.81,5.77 99.81,9.08 100.42,9.69 O2C53.1 O2R132.2 99.1,11.45 99.07,11.49 v1(98.87,11.49)
  BOTTOM w0.102: v1(98.87,11.49) 98.1,10.72 v2(96.46,10.72) 92.69,10.72 91.91,11.49 86.2,11.49 85.77,11.92 85.29,11.92 85.08,12.12 R216.1 R215.2
Q7_E: length 3.8
  BOTTOM w0.102: Q7.2 81.31,33.59 81.5,33.78 SR81.2 81.01,34.81 80.94,34.87 80.94,35.95 v2(81.15,36.15)
Q9_B: length 3.5
  BOTTOM w0.102: v2(22.4,63.43) 22.85,63.43 23.25,63.04 R60299.2 23.94,62.42 24.01,62.36 Q9.1
Q32_B: length 11.4
  TOP w0.102: Q33.3 96.74,14.94 96.61,15.07 96.39,15.07 96.08,14.77 94.84,14.77 94.39,15.21 Q32.1 92.61,17.99 v2(92.12,17.99) 91.32,17.19 R182.2
Q32_C: length 9.5
  TOP w0.102: v1(94.25,13.93) 94.05,14.13 Q32.3 93.44,13.02 91.53,11.11 90.06,11.11 89,10.05 CR6.L2
  BOTTOM w0.102: v2(94.07,14.64) 94.07,14.11 v1(94.25,13.93)
Q33_B: length 3.3
  TOP w0.102: v2(97.6,17.99) 97.6,16.91 97.69,16.82 Q33.1 98.58,16.21 R184.2
Q39G: length 4.4
  TOP w0.102: v2(61.51,86.45) 62.36,85.59 R60208.2 R60209.2 62.36,83.76 62.13,83.52 Q39.1
Q41_B: length 6.9
  BOTTOM w0.102: SR663.2 46.79,24.6 46.64,24.75 Q41.1 46.64,26.15 46.24,26.55 45.23,26.55 44.95,26.83 44.95,28.71 v2(45.59,29.35)
Q41_C: length 10.8
  BOTTOM w0.254: Q9415.1 50.69,25.56 50.87,25.38 50.87,23.61 v2(50.28,23.02)
  BOTTOM w0.457: Q41.3 46.78,26.55 49.12,26.55 49.94,25.73 Q9415.1 49.94,25.04 49.15,24.25 R252.2
R_HPOUT_L: length 16.4
  TOP w0.254: AR6.2 15.33,109.56 15.79,109.1 15.79,107.76 16.06,107.49 AC3.1 16.74,107.49 17.04,107.78 AD1.1 v1(17.71,111.29) v2(16.19,112.81)
  BOTTOM w0.254: v1(17.71,111.29) 19.27,112.85 J27.2
R_HPOUT_R: length 16.2
  TOP w0.254: AR7.2 v1(14.67,107.83) ; v1(15.66,106.22) 16.02,106.57 AC4.1 16.78,106.57 17.07,106.28 AD2.1 17.71,106.76 18.28,107.32 v1(18.28,109.28)
  IN1 w0.254: v1(15.66,106.22) 14.67,107.21 v1(14.67,107.83)
  BOTTOM w0.254: J27.3 21.49,112.85 19.93,111.29 19.93,110.78 v2(19.32,110.17) 18.61,109.46 18.46,109.46 v1(18.28,109.28)
REAR_USB_OC#: length 3.6
  TOP w0.102: v2(73.42,96.81) 73.37,96.76 R244.1 72.66,95.86 71.94,96.58 U18.5
REGREF: length 5.3
  TOP w0.102: AU1.10 13.18,96.96 13.81,96.33 14.65,96.33 15.46,95.51 AC46.1 16.29,94.96 v2(16.71,94.55)
RESET: length 32.3
  TOP w0.102: v1(100.86,98) 100.86,96.5 100.55,96.2 PD2.3 98.72,96.2 98.34,95.82 PC14.1 ; PQ3.1 121.09,99.27 120.93,99.43 v1(120.36,99.43) ; PR21.1 v1(97.5,98.6) 97.15,98.24 97.15,98.21 PR16.2
  IN1 w0.102: v1(100.86,98) 100.6,98.26 97.85,98.26 v1(97.5,98.6)
  BOTTOM w0.102: v1(100.86,98) 101.53,98.67 117.13,98.67 117.88,99.43 v1(120.36,99.43) ; v2(97.5,97.85) v1(97.5,98.6)
REVISION_ID_0: length 11.2
  BOTTOM w0.102: SR156.1 79.65,78.05 79.65,77.62 79.72,77.55 79.72,76.81 SR159.1 79.27,75.4 v2(79.28,75.39) 79.28,74.75 79.25,74.73 79.25,73.06 77.81,71.62 76.96,71.62 76.65,71.31 76.65,70.29 76.28,69.92 76.28,69.61 XU1.C17
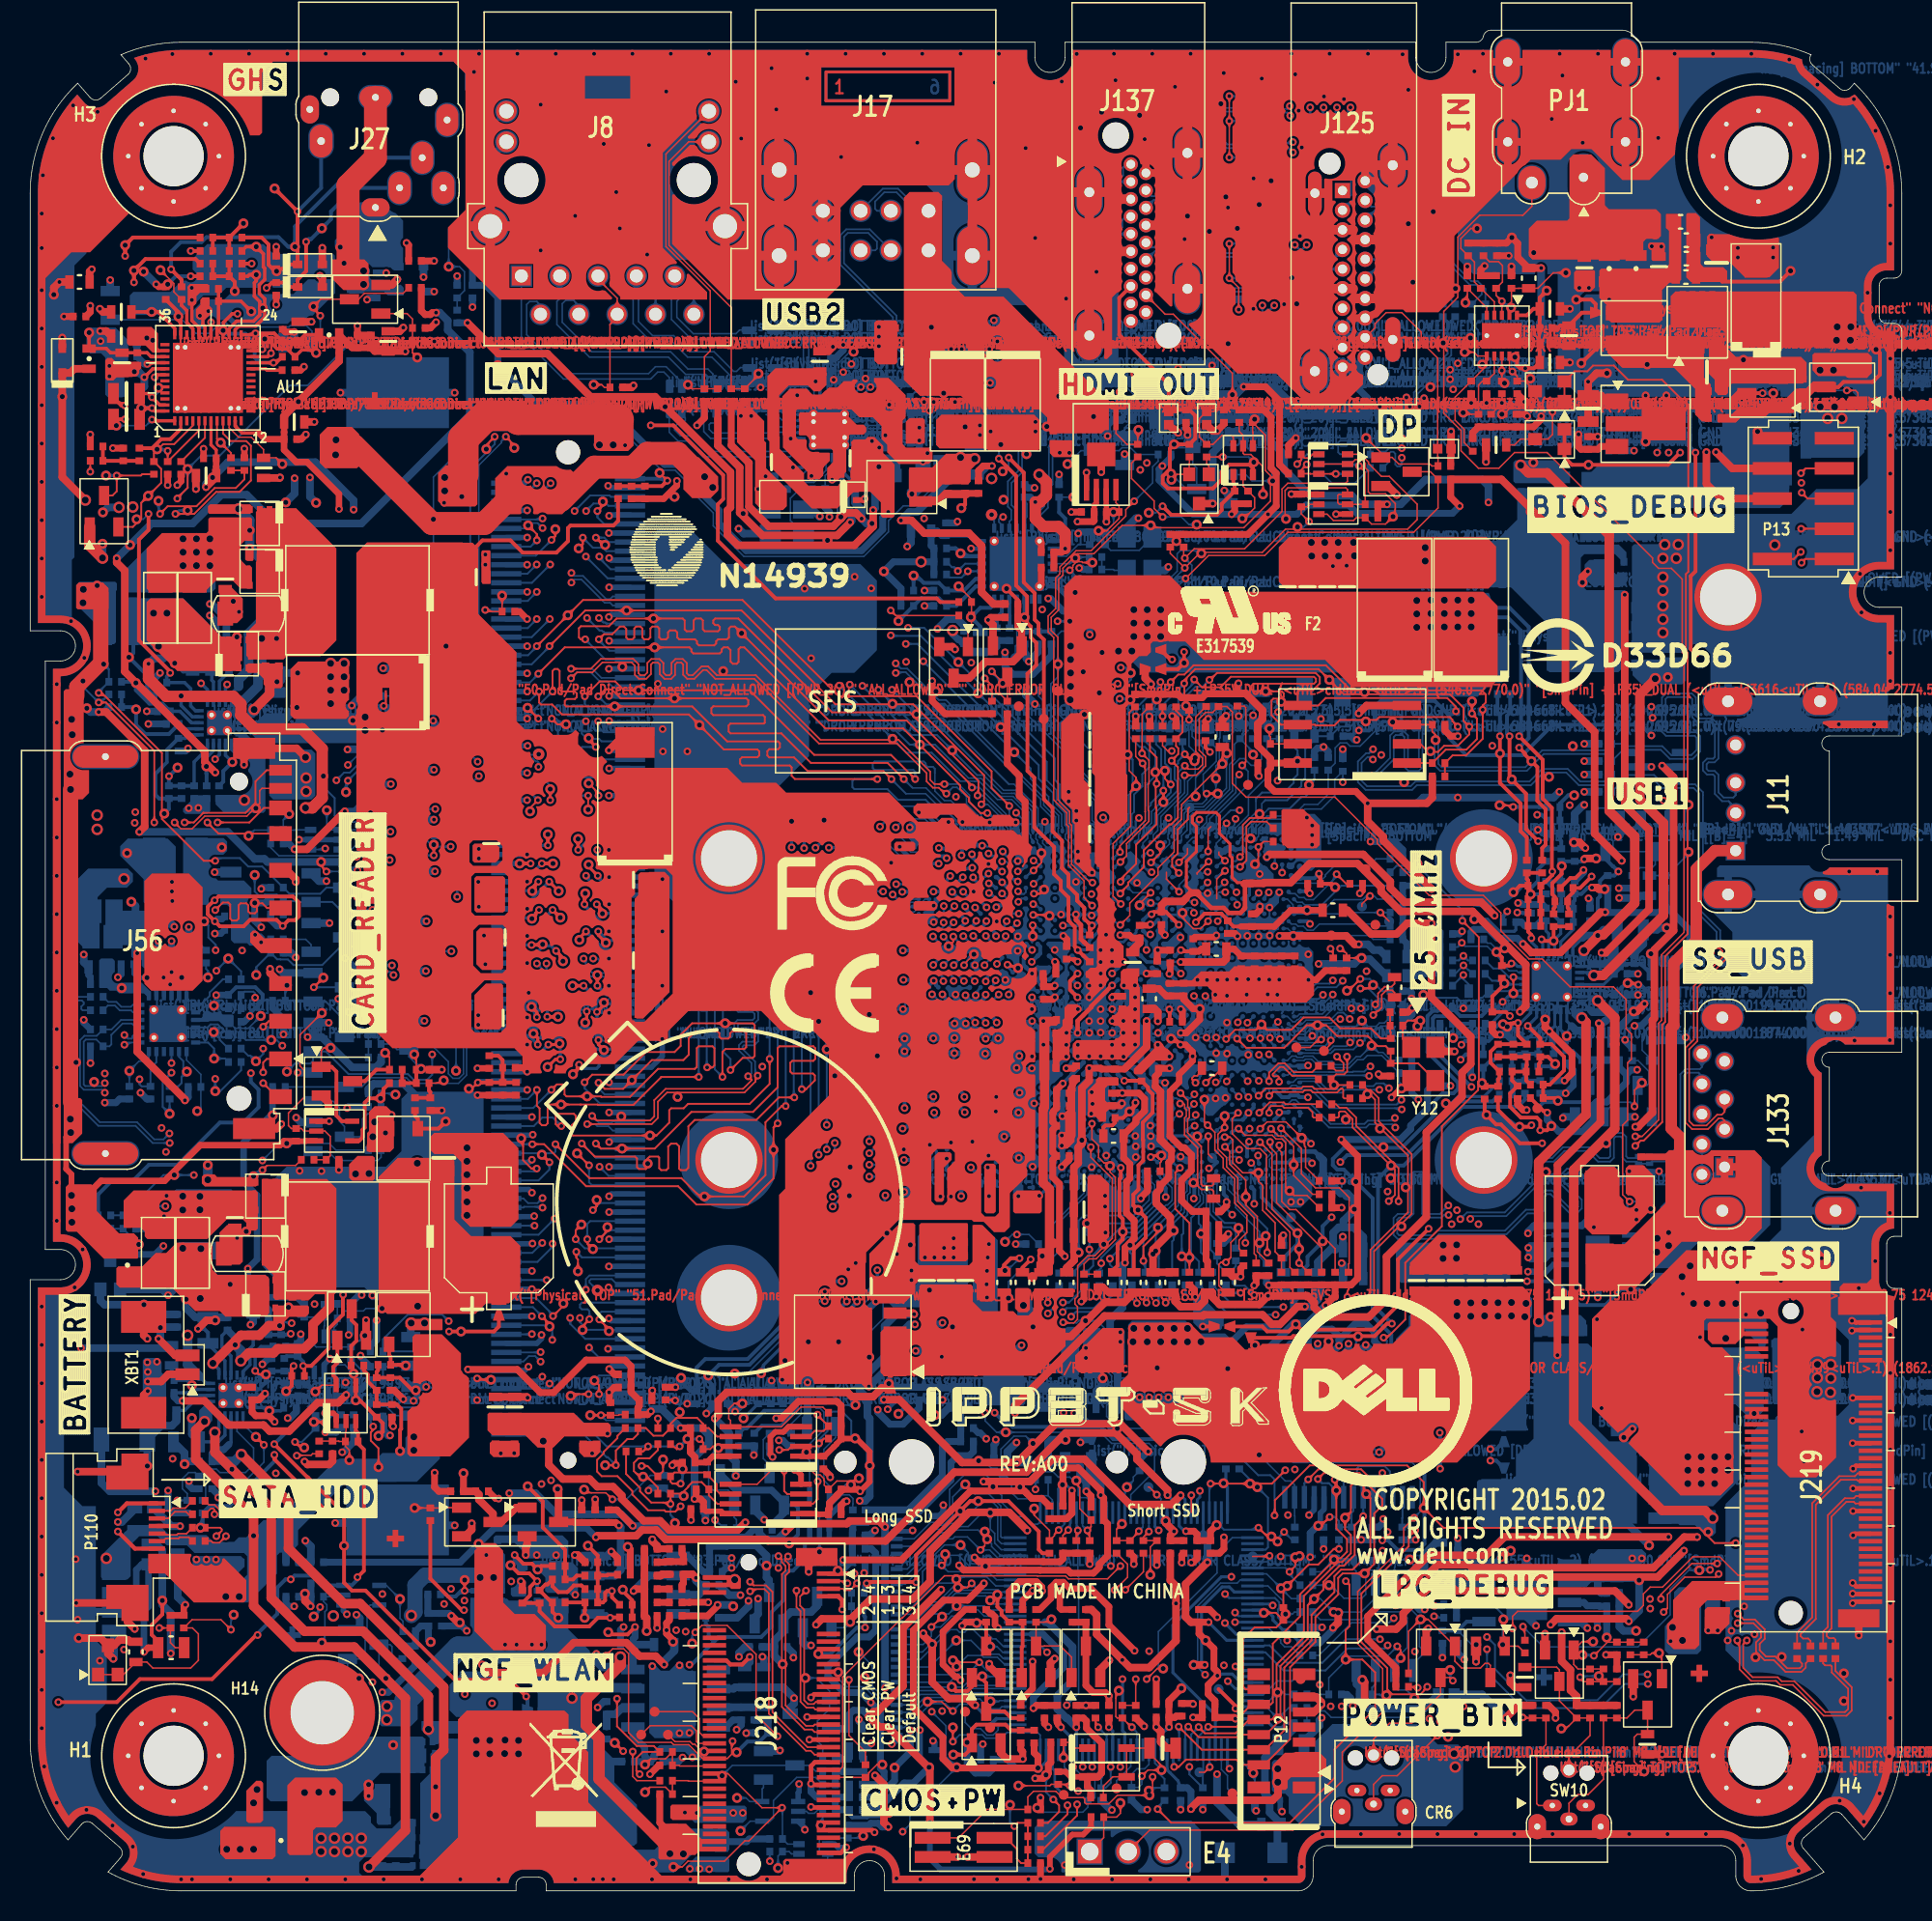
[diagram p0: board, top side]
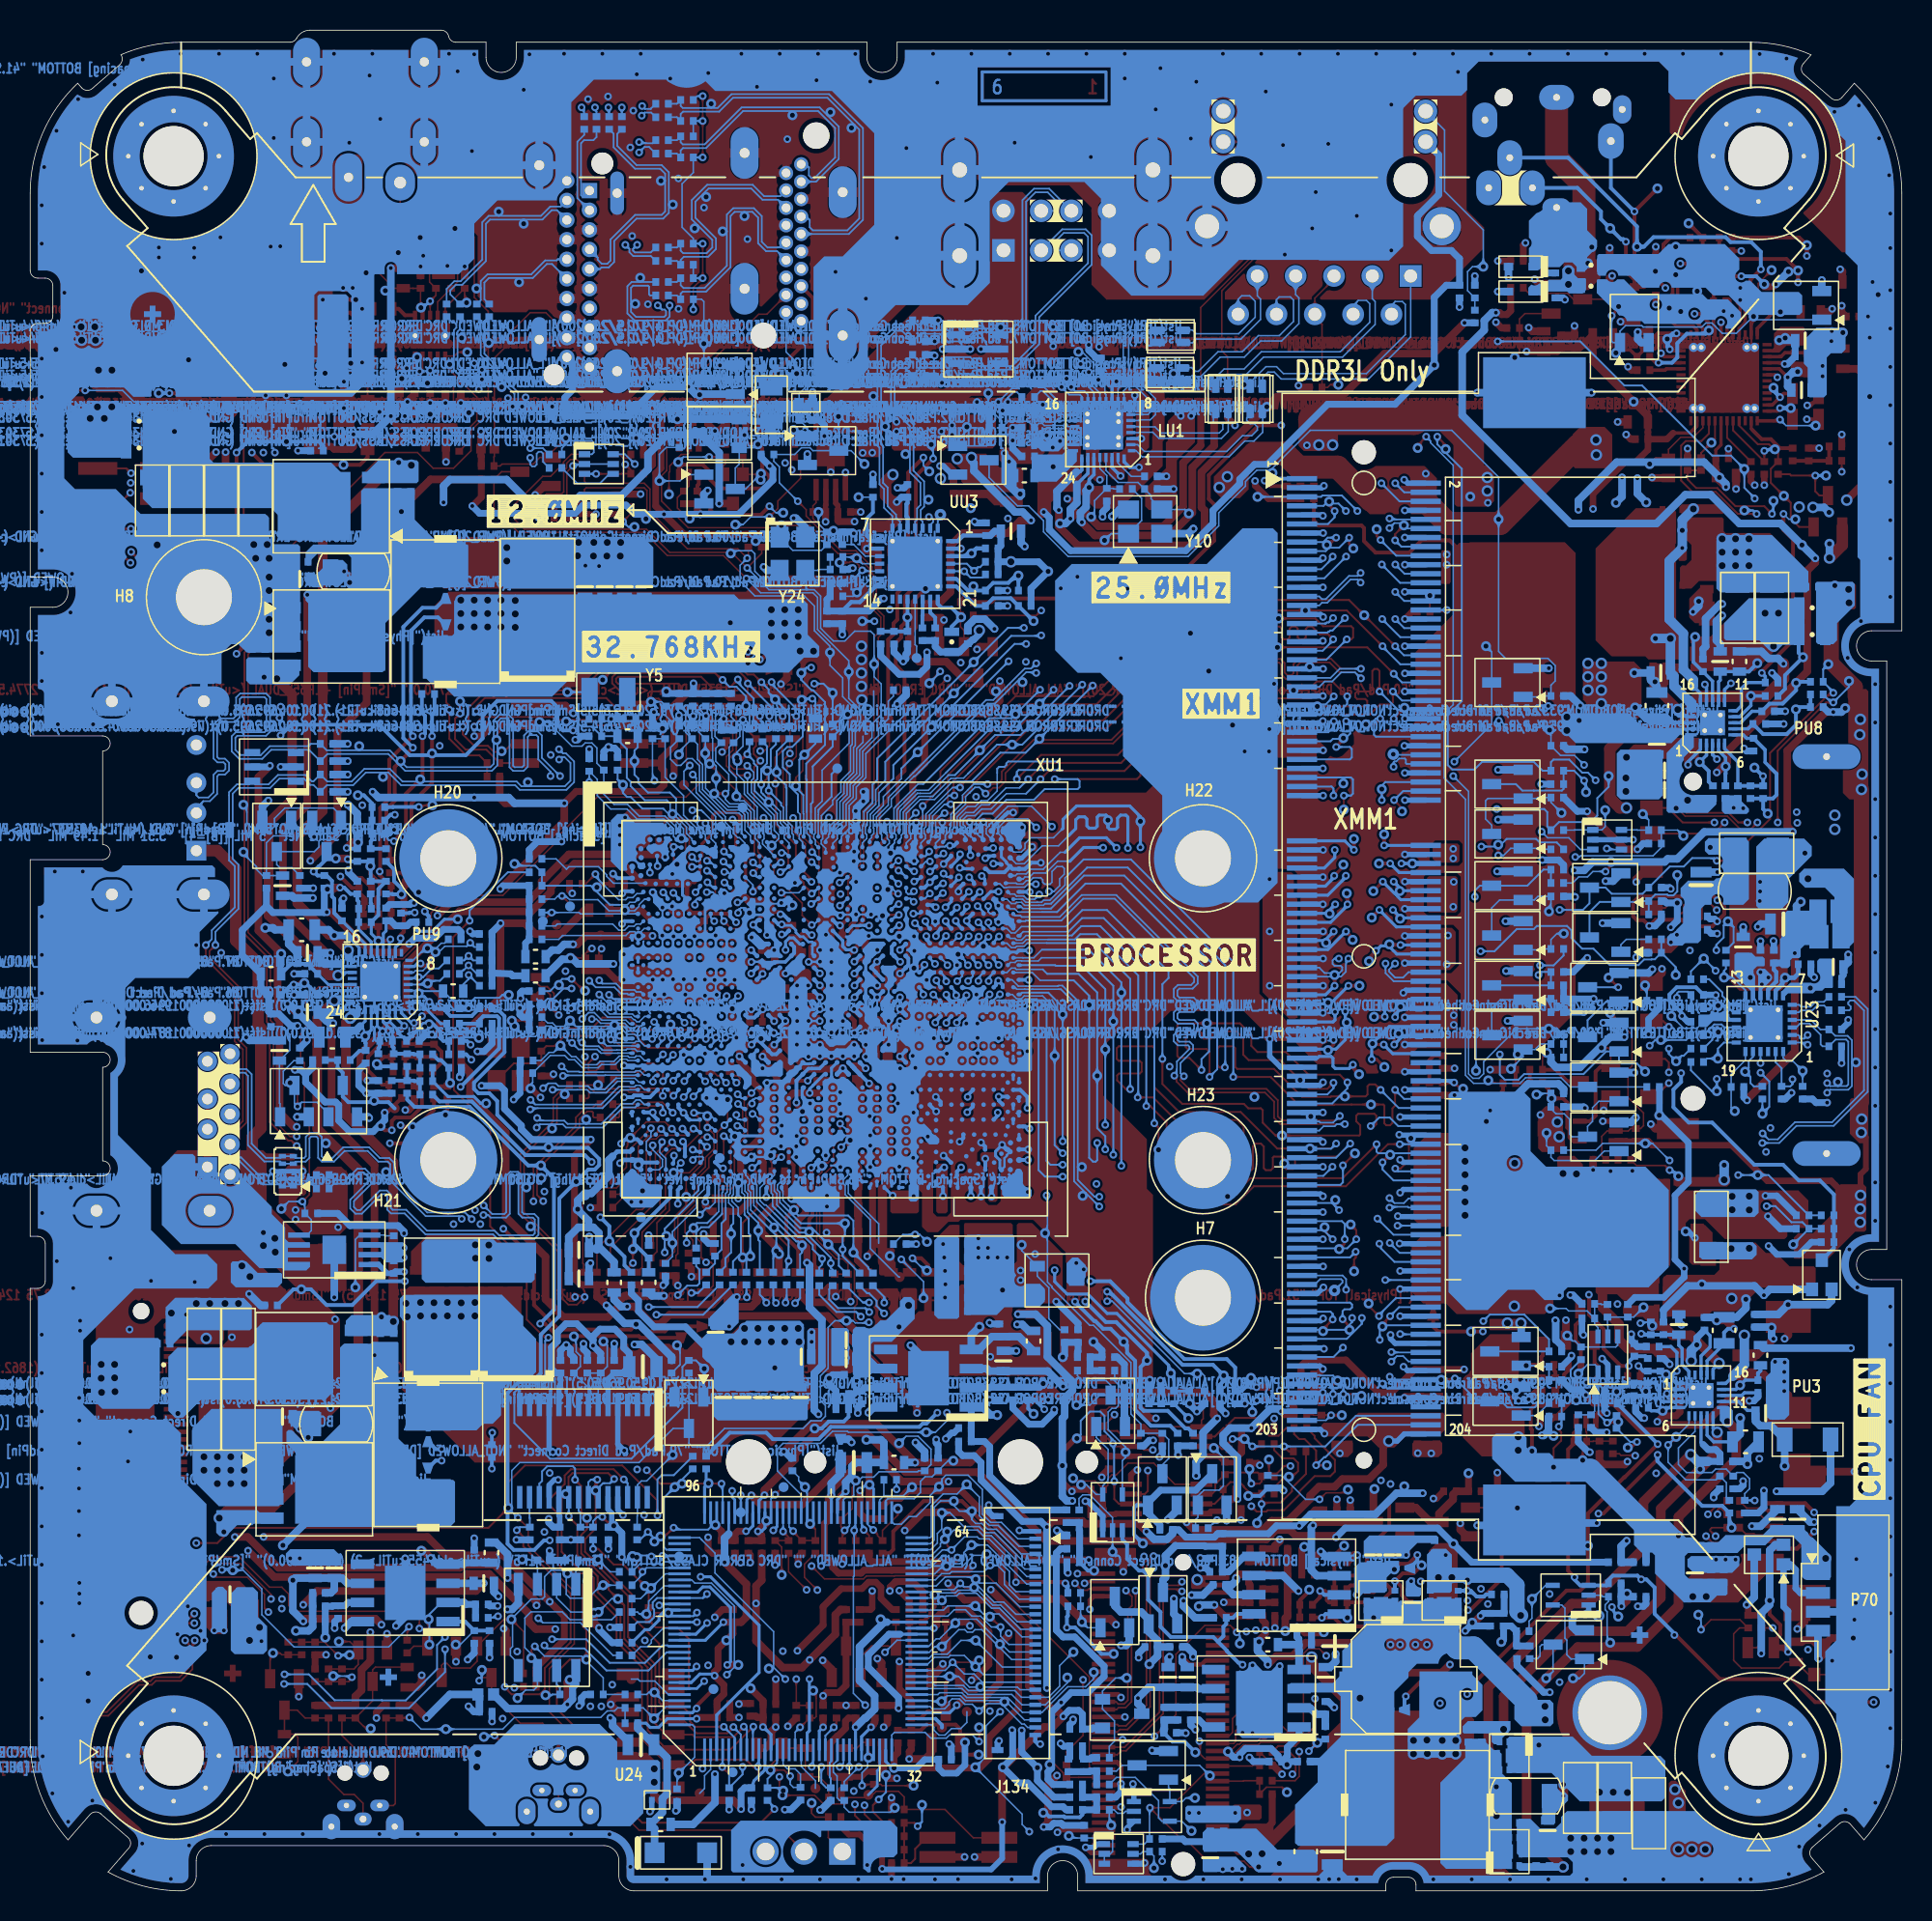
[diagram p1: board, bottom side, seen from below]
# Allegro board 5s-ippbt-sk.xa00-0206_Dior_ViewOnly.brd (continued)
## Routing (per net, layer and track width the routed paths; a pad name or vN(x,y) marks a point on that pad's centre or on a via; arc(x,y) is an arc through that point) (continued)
REVISION_ID_1: length 14.4
  BOTTOM w0.102: XU1.C16 76.64,69.42 77.01,69.79 77.1,69.79 77.12,69.79 77.41,70.08 77.41,70.27 77.94,70.81 77.94,71.18 79.66,72.89 79.66,74.56 80.13,75.03 80.45,75.03 80.89,74.58 81.17,74.58 81.58,74.99 81.58,75.76 SR158.1 81.51,76.87 81.51,77.48 81.88,77.85 SR157.1 82.17,78.8 v2(82.88,78.8)
RING2: length 1.2
  TOP w0.229: 11.44,104.24 11.44,103.81 11.58,103.67 AU1.31
  vias: v1(11.24,104.38) v1(11.8,104.68) v2(15.41,104.89)
RING2_B: length 12.3
  TOP w1.524: 21.06,107.27 21.06,113.01 22.87,114.83 J27.6
  vias: v2(20.79,107.86) v3(22.09,107.35) v3(22.09,106.45)
RREF: length 3.1
  BOTTOM w0.279: 8.15,59.87 8.36,59.66 U23.8
  BOTTOM w0.305: R200.2 6.86,60.78 7.13,60.51 v2(7.74,60.51) 7.93,60.32 7.93,60.09 8.15,59.87
RSET: length 2.5
  BOTTOM w0.102: LU1.31 51.93,94.61 51.05,93.74 LR2.1
RST_KB#: length 2
  TOP w0.102: ST25.1 77.81,7.86 v1(78.15,8.2)
  BOTTOM w0.102: v1(78.15,8.2) 78.12,8.23 U24.4
RTC_EXTPAD: length 7.4
  BOTTOM w0.102: XU1.B8 80.72,69.81 80.72,70.38 82.01,71.67
  BOTTOM w0.127: 82.01,71.67 82.06,71.72 83.45,71.72 84.22,72.49 84.46,72.49 84.73,72.75 v2(84.73,73.29) 85.08,73.64 SC4.1
RTCRST#: length 201.5
  TOP w0.127: SR674.2 67.09,2.73 69.36,5 v1(69.36,5.73)
  IN1 w0.127: v1(79.86,71.04) 81.74,71.04 84.64,68.13 87.89,68.13 90.39,65.63 90.39,64.35 92.63,62.12 92.63,60.43 94,59.06 94,58.1 95.04,57.06 95.16,57.06 95.76,56.46 95.76,55.02 98.11,52.67 98.11,50.76 99.22,49.65 99.22,47.09 96.93,44.8 96.93,42.85 94.92,40.84 93.9,40.84 92.76,39.69 92.76,34.21 91.94,33.39 91.94,26.95 91.06,26.07 88.95,26.07 87.75,24.87 87.75,22.13 86.73,21.12 86.73,18.42 86.75,18.41 86.75,13.26 86.16,12.68 v1(86.16,12.22)
  IN2 w0.127: v1(10.84,47.43) 10.69,47.27 10.69,44.61 11.88,43.42 11.88,42.22 12.51,41.59 12.51,37.12 11.32,35.92 11.32,32.27 13.17,30.41 13.17,28.86 16.12,25.92 16.12,19.41 18.41,17.12 22.27,17.12 27.81,11.58 34.9,11.58 36.13,10.35 41.1,10.35 41.99,9.46 45.3,9.46 46.04,8.72 51.15,8.72 52.62,10.19 55.61,10.19 55.61,10.2 59.46,10.2 59.63,10.37 63.82,10.37 64.36,9.84 65.99,9.84 67.9,7.92 67.9,7.26 69.36,5.81 v1(69.36,5.73) 70.31,5.73 70.96,6.38 80.24,6.38 81.5,7.65 81.5,8.01 85.39,11.9 85.83,11.9 v1(86.16,12.22)
  BOTTOM w0.102: XU1.C11 79.27,69.69 79.27,69.98 79.35,70.06 79.35,70.21 79.8,70.66 79.8,70.98 v1(79.86,71.04)
  BOTTOM w0.127: v1(10.84,47.43) v2(9.54,47.43) 8.83,47.43 6.16,44.76 C240.1 R188.2
S4_DAUL_PWRGD: length 3.1
  BOTTOM w0.203: U24.96 79.32,26.75 v2(79.06,27.01) 79.21,27.16 R213.1
SATA_GP[0]: length 11.6
  TOP w0.102: v2(79.14,51.34) 79.14,50.59 v1(79.14,50.58) 78.69,50.14 78.69,49.17 79.27,48.6 79.27,47.98 80,47.25 80,45.68 81.09,44.59 81.09,42.22 81.22,42.1 SR77.2
  BOTTOM w0.102: XU1.BA12 78.81,50.58 v1(79.14,50.58)
SATA_GP[1]: length 12.2
  TOP w0.102: v2(77.79,52.43) 77.79,50.95 v1(78.01,50.74) 78.49,50.26 78.49,49.08 79.04,48.54 79.04,47.92 79.8,47.16 79.8,45.58 80.61,44.76 80.61,43.63 80.09,43.11 80.09,42.55 SR78.2
  BOTTOM w0.102: v1(78.01,50.74) 77.99,50.74 XU1.AY14
SATA_RCOMP_N: length 9
  TOP w0.102: v1(76.21,52.87) 76.69,52.39 76.69,51.95 76.8,51.84 76.8,51.25 76.68,51.13 76.68,50.24 76.82,50.1
  TOP w0.114: 77.13,49.79 77.58,49.33 77.58,46.83 77.69,46.72 78.3,46.72 78.4,46.82 SR76.1 ; 77.13,49.79 76.82,50.1 ; 77.13,49.79 v2(77.32,50)
  BOTTOM w0.114: XU1.AT18 75.85,53.23 v1(76.21,52.87)
SATA_RCOMP_P: length 8.9
  TOP w0.102: 76.48,50.1 76.48,51.22 76.6,51.33 76.6,51.76 76.49,51.87 76.49,52.1 76.42,52.17 v1(76.18,52.17)
  TOP w0.114: 77.34,46.92 77.34,49.23 76.48,50.1 ; 77.34,46.92 77.34,46.73 77.59,46.48 78.28,46.48 78.33,46.43 78.4,46.36 SR76.2 ; 77.34,46.92 v2(77.07,46.92)
  BOTTOM w0.114: v1(76.18,52.17) 76.18,52.38 76.12,52.44 76.04,52.44 75.96,52.52 XU1.AU18
SATA_RXN0: length 101.5
  TOP w0.114: v1(12.34,23.5) 12.69,23.86 12.69,23.96 12.59,24.06 T1C15.1
  IN1 w0.102: 83.61,50.22 83.61,50.56 83.2,50.96 82.53,50.96 82.49,50.93 79.6,50.93 79.31,51.22 78.38,51.22 77.5,52.09 77.48,52.09 77.43,52.15 v1(77.11,52.15)
  IN1 w0.114: 83.61,50.22 83.61,47.05 84.68,45.98 84.68,40.41 83.7,39.43 83.7,38.15 78.98,33.44 73.27,33.44 72.19,32.36 60.87,32.36 60.62,32.11 57.71,32.11 56.9,31.3 54.7,31.3 50.76,27.36 47.21,27.36 46.77,26.91 43.76,26.91 43.31,26.46 41.93,26.46 41.46,25.99 40.43,25.99 39.74,26.68 38.24,26.68 37.89,26.32 37.89,25.73 37.52,25.36 36.24,25.36 35.53,24.65 30.33,24.65 29.92,25.06 21.55,25.06 20.44,23.95 12.78,23.95 v1(12.34,23.5)
  BOTTOM w0.114: XU1.AV16 76.77,51.81 v1(77.11,52.15)
SATA_RXN0_C: length 14.6
  TOP w0.114: J219.43 121.1,27.17 121.03,27.24 119.96,27.24 118.31,25.59 118.31,18.02 117.3,17.01 117.3,16.87 117.45,16.72 117.8,16.72 117.95,16.57 SSC22.2
SATA_RXN1: length 70.1
  TOP w0.114: v1(113.12,17.74) 114.17,17.74 114.67,17.23 114.67,16.8 114.34,16.47 114.34,15.85 114.52,15.68 ; 114.52,15.68 114.9,15.29 115.52,15.29 116.3,14.51 117.35,14.51 117.63,14.79 117.63,15.07 SSC22.1 ; 114.52,15.68 v2(114.31,15.48)
  IN2 w0.102: v1(77.15,50.7) 77.42,50.96 77.64,50.96 77.83,51.16 78.2,51.16 78.49,50.87 78.49,48.8 78.67,48.62 78.67,47.73 79.37,47.03 79.37,46.98 79.6,46.76
  IN2 w0.114: v1(113.12,17.74) 110.78,17.74 108.27,20.25 95.05,20.25 94.43,20.86 92.98,20.86 91.01,22.84 91.01,38.13 86.39,42.74 82.72,42.74 80.18,45.29 80.18,46.18 79.6,46.76
  BOTTOM w0.114: XU1.BA16 76.95,50.7 v1(77.15,50.7)
SATA_RXN1_C: length 2.6
  TOP w0.114: P110.5 8.91,23.68 9,23.59 9.72,23.59 9.8,23.67 10.36,23.67 T1C15.2
SATA_RXP0: length 101.5
  TOP w0.114: T1C14.1 11.99,23.19 12.11,23.07 12.54,23.07 v1(12.97,23.5)
  IN1 w0.102: v1(77.13,52.79) 77.64,52.28 77.64,52.24 78.46,51.42 79.39,51.42 79.68,51.13 82.41,51.13 82.44,51.16 83.29,51.16 83.81,50.64 83.81,50.32 83.85,50.28 83.85,50.22
  IN1 w0.114: v1(12.97,23.5) 13.17,23.71 20.54,23.71 21.65,24.82 29.82,24.82 30.23,24.41 35.63,24.41 36.34,25.12 37.62,25.12 38.13,25.63 38.13,26.22 38.34,26.44 39.64,26.44 40.33,25.75 41.56,25.75 42.03,26.22 43.41,26.22 43.86,26.67 46.87,26.67 47.31,27.12 50.86,27.12 54.8,31.06 57,31.06 57.81,31.87 60.72,31.87 60.97,32.12 72.29,32.12 73.37,33.19 79.08,33.19 83.94,38.05 83.94,39.33 84.92,40.31 84.92,46.08 83.85,47.15 83.85,50.22
  BOTTOM w0.114: XU1.AU16 76.86,52.52 v1(77.13,52.79)
SATA_RXP0_C: length 14.6
  TOP w0.114: SSC21.2 117.06,17.11 118.06,18.12 118.06,25.69 119.86,27.48 120.9,27.48 121.08,27.66 J219.41
SATA_RXP1: length 70.1
  TOP w0.114: v1(113.12,18.37) 113.52,17.98 114.27,17.98 114.91,17.33 114.91,16.7 114.58,16.37 114.58,15.95 115,15.53 115.62,15.53 115.85,15.31 ; v2(116.04,15.5) 115.85,15.31 ; 115.85,15.31 116.4,14.75 117.25,14.75 117.39,14.89 117.39,15.06 SSC21.1
  IN2 w0.102: v1(77.22,51.42) 77.47,51.16 77.56,51.16 77.75,51.36 78.28,51.36 78.69,50.95 78.69,48.88 78.88,48.7 78.88,47.82 79.59,47.1
  IN2 w0.114: v1(113.12,18.37) 112.73,17.98 110.88,17.98 108.37,20.49 95.15,20.49 94.53,21.1 93.08,21.1 91.25,22.94 91.25,38.23 86.49,42.99 82.82,42.99 80.42,45.39 80.42,46.28 79.59,47.1
  BOTTOM w0.114: v1(77.22,51.42) 77.22,51.23 77.12,51.12 76.98,51.12 76.95,51.1 XU1.AY16
SATA_RXP1_C: length 2.6
  TOP w0.114: P110.6 8.81,23.18 8.98,23.35 9.82,23.35 9.9,23.43 10.51,23.43 T1C14.2
SATA_TXN0: length 89.7
  TOP w0.114: v1(12.21,24.95) 12.21,25.25 12.12,25.33 11.97,25.33 T1C1.1
  IN1 w0.114: v1(80.89,48.24) 81.45,48.24 82.11,47.57 82.11,43.38 82.83,42.66 82.83,39.53 81.69,38.38 81.69,37.36 78.63,34.3 72.91,34.3 71.84,33.22 56.13,33.22 55.73,32.83 54.37,32.83 50.13,28.58 49.66,28.58 49.3,28.22 46.29,28.22 45.84,27.78 42.18,27.78 41.73,27.33 40.5,27.33 40.05,27.78 37.3,27.78 35.05,25.52 30.68,25.52 30.28,25.92 13.48,25.92 12.96,25.4 12.66,25.4 v1(12.21,24.95)
  BOTTOM w0.114: v1(80.89,48.24) 81.12,48.01 81.12,47.82 81.02,47.72 XU1.BG7
SATA_TXN0_C: length 12.1
  TOP w0.114: J219.47 120.97,26.17 120.82,26.02 120.22,26.02 119.1,24.89 119.1,17.49 118.79,17.18 SSC19.2
SATA_TXN1: length 76.3
  TOP w0.114: SSC19.1 118.79,15.07 118.92,14.94 119.28,14.94 119.36,14.87 119.36,14.47 120.44,13.39 120.44,12.58 ; 120.44,12.58 120.44,12.05 120.24,11.85 118.93,11.85 116.88,13.89 116.04,13.89 115.77,14.16 114.11,14.16 113.49,14.78 113.49,16.35 v1(113.73,16.6) ; 120.44,12.58 v2(120.16,12.58)
  IN2 w0.114: v1(113.73,16.6) 113.56,16.77 113.56,16.95 114.23,17.62 114.23,19.24 113.61,19.86 110.22,19.86 108.73,21.35 95.5,21.35 94.89,21.97 93.77,21.97 92.45,23.28 92.45,27.17 92.13,27.49 92.13,39.43 87.4,44.15 86.83,44.15 86.62,43.94 83.98,43.94 80.55,47.37 80,47.91 79.77,47.91 79.44,48.24 79.44,48.57 79.61,48.74 79.79,48.74 v1(80.1,48.43)
  BOTTOM w0.114: v1(80.1,48.43) 79.88,48.65 79.47,48.65 79.42,48.6 79.42,48.45 XU1.BF10
SATA_TXN1_C: length 2.6
  TOP w0.114: P110.3 9.14,24.68 9.58,25.12 10.33,25.12 10.5,24.95 T1C1.2
SATA_TXP0: length 89.7
  TOP w0.114: T1C13.1 11.85,25.57 12.22,25.57 v1(12.84,24.95)
  IN1 w0.114: v1(81.35,48.73) 82.35,47.72 82.35,43.48 83.08,42.76 83.08,39.43 81.93,38.28 81.93,37.26 78.73,34.06 73.01,34.06 71.94,32.98 56.23,32.98 55.83,32.58 54.47,32.58 50.23,28.34 49.76,28.34 49.4,27.98 46.39,27.98 45.94,27.54 42.28,27.54 41.83,27.09 40.4,27.09 39.95,27.54 37.4,27.54 35.15,25.28 30.58,25.28 30.18,25.68 13.58,25.68 12.85,24.95 v1(12.84,24.95)
  BOTTOM w0.114: v1(81.35,48.73) 81.35,48.25 XU1.BF6
SATA_TXP0_C: length 12.2
  TOP w0.114: J219.49 120.93,25.66 120.82,25.78 120.32,25.78 119.34,24.79 119.34,17.39 119.03,17.08 119.03,16.89 119.17,16.75 119.5,16.75 119.6,16.65 SSC20.2
SATA_TXP1: length 76.3
  TOP w0.114: v1(113.1,16.6) 113.25,16.44 113.25,14.68 114.01,13.92 115.67,13.92 115.94,13.65 116.78,13.65 118.83,11.6 120.34,11.6 120.68,11.95 120.68,13.5 119.96,14.21 ; 119.96,14.21 v2(120.16,14.41) ; 119.96,14.21 119.6,14.57 SSC20.1
  IN2 w0.114: v1(113.1,16.6) 113.31,16.81 113.31,17.05 113.99,17.72 113.99,19.14 113.5,19.62 110.12,19.62 108.63,21.11 95.4,21.11 94.79,21.73 93.67,21.73 92.21,23.18 92.21,27.07 91.89,27.39 91.89,39.33 87.3,43.91 86.94,43.91 86.72,43.7 83.88,43.7 80.38,47.2 79.9,47.67 79.67,47.67 79.43,47.92 79.43,47.96 79.23,48.15 79.23,48.66 79.54,48.98 79.97,48.98 v1(80.11,49.12)
  BOTTOM w0.114: XU1.BD10 79.96,48.97 v1(80.11,49.12)
SATA_TXP1_C: length 2.6
  TOP w0.114: P110.2 9.3,25.18 9.48,25.36 10.27,25.36 T1C13.2
SCE#: length 4.7
  BOTTOM w0.102: R221.1 85.56,21.14 v2(86.38,21.95) 86.89,21.95 86.94,21.9 R227.2 87.69,21.35 87.85,21.18 U25.1
SCE#_EC: length 4.5
  BOTTOM w0.102: v2(84.1,22.19) 84.13,22.15 R221.2 83.6,21.67 82.12,21.67 81.99,21.8 U24.101
SCK: length 13.4
  BOTTOM w0.102: v2(91.71,12.77) 91.18,13.31 90.63,13.31 90.39,13.55 U25.6 90.39,15.28 91.23,16.12 91.23,18.08 90.82,18.49 88.75,18.49 88.23,17.97 85.48,17.97 R222.1
SCK_EC: length 4.4
  BOTTOM w0.102: R222.2 83.76,18.47 83.63,18.34 v2(83.17,18.34) 83.02,18.49 83.02,19.19 83,19.22 82.01,20.2 U24.105
SD3_RCOMP: length 8
  TOP w0.254: v1(72.26,47.91) 72.26,47.26 72.17,47.17 72.17,44.73 72.39,44.52 v2(72.39,43.67) 72.39,43.18 72.04,42.83 72.04,41.42 71.85,41.23 SR626.1
  BOTTOM w0.254: v1(72.26,47.91) 72.2,47.91 71.92,48.2 71.92,48.27 XU1.BF26
SD_CD#: length 27
  TOP w0.102: J56.CD 15.36,73.06 15.21,72.91 15.21,72.07 14.36,71.22 11.56,71.22 10.72,70.38 9.99,70.38 v1(9.57,70.8)
  IN2 w0.102: v1(9.36,54.85) 10.61,56.1 10.61,60.54 8.95,62.2 8.95,70.18 v1(9.57,70.8)
  BOTTOM w0.102: U23.21 v1(9.36,54.85)
SDATA_IN_R: length 2.8
  TOP w0.127: AU1.8 12.38,96.21 v2(12.62,95.97) 13.3,95.28 AR1.2
SENSE_B: length 5.2
  TOP w0.102: AR3.1 9.52,105.97 9.52,106.51 v2(8.63,107.4)
  TOP w0.229: AU1.33 10.78,103.52 10.38,103.92 10.38,104.71 10.03,105.06 AR3.1
SERIRQ: length 110.8
  IN1 w0.127: v1(83.08,23.78) 83.51,23.35 83.51,21.8 83.86,21.45 83.86,17.18 v1(83.28,16.6) ; v1(76.8,8.22) 76.8,8.82 77.26,9.28 79.57,9.28 81.07,10.78 81.07,14.64 80.34,15.36 79.51,15.36 v1(79.09,14.94)
  IN2 w0.127: v1(83.28,16.6) 82.06,15.38 79.52,15.38 v1(79.09,14.94) ; v1(20.9,33.69) 21.36,33.22 21.36,31.82 21.25,31.71 21.25,29.97 22.55,28.67 22.55,19.44 22.88,19.11 22.88,17.64 28.2,12.32 29.53,12.32 29.62,12.4 29.63,12.4 30.14,12.91 31.65,12.91 32.45,12.11 35.08,12.11 36.34,10.85 41.31,10.85 42.18,9.99 45.48,9.99 46.25,9.23 48.35,9.23 48.91,9.79 49.95,9.79 50.87,10.7 55.4,10.7 55.4,10.71 55.74,10.71 56.12,11.08 59.12,11.08 59.33,10.88 64.03,10.88 64.57,10.35 66.35,10.35 68.92,7.78 72.4,7.78 73.27,8.65 76.37,8.65 v1(76.8,8.22)
  BOTTOM w0.127: v1(20.9,33.69) 21.56,33.69 21.94,34.06 21.94,34.52 R60217.2 ; TPR4.1 83.6,23.26 v1(83.08,23.78) 82.64,23.35 v2(82.64,23.15) ; U24.5 77.72,7.98 77.69,7.96 HC14.1 76.8,7.72 v1(76.8,8.22)
SERIRQ_A3: length 6.2
  TOP w0.127: v2(18.79,31.07) 19.47,31.07 v1(19.52,31.02)
  BOTTOM w0.127: U1.3 18.82,33.76 18.94,33.64 19.92,33.64 20.1,33.46 20.1,31.59 v1(19.52,31.02) 19.37,31.02 R60216.2
SERIRQ_B3: length 4.3
  BOTTOM w0.102: v2(22.17,36.79) 21.81,36.43 21.65,36.43 R60217.1 18.95,36.04 18.84,36.15 18.82,36.15 U1.4
SERIRQ_PCH: length 73.8
  TOP w0.127: v2(18.15,29.37) 17.92,29.37 v1(17.54,29.75)
  IN1 w0.127: v1(17.54,29.75) 24.27,29.75 25.16,30.64 26.36,30.64 28.47,28.53 34.1,28.53 35.02,27.62 36.16,27.62 37.1,28.56 37.41,28.56 37.48,28.63 44.88,28.63 45.89,29.65 47.4,29.65 48.32,30.57 50.1,30.57 54.39,34.86 71.48,34.86 72.31,35.69 77.68,35.69 79.85,37.85 79.85,39.28 v1(80.19,39.62)
  BOTTOM w0.127: v1(17.54,29.75) 18,29.75 R60216.1 ; v1(80.19,39.62) 79.75,39.62 SR107.2
SERIRQ_R: length 7.1
  BOTTOM w0.102: XU1.BG13 78,47.25 78,46.96 77.82,46.79 77.82,46.31 77.92,46.21 77.92,45.27
  BOTTOM w0.127: SR107.1 78.63,41.58 HC13.1 78.2,42.49 78.2,44.24 77.92,44.51 77.92,45.27
SERIRQ_TPM: length 6
  BOTTOM w0.102: v2(81.42,28.89) 83.15,27.16 83.51,27.16 83.77,26.9 TPU1.27 83.77,24.85 83.79,24.83 TPR4.2
SI: length 14.8
  BOTTOM w0.102: R224.1 v2(86.05,20.25) 86.17,20.25 87.04,19.39 88.22,19.39 88.49,19.65 88.49,20.98 88.75,21.24 89.49,21.24 89.92,20.82 89.92,19.49 90.07,19.34 90.8,19.34 92.04,18.09 92.04,16.19 92.18,16.05 92.18,15.59 91.66,15.07 U25.5
SI_EC: length 4.9
  TOP w0.102: v1(83.43,21.14) 83.81,21.52 v2(83.81,22.11)
  BOTTOM w0.102: R224.2 83.43,20.95 v1(83.43,21.14) 83.17,21.4 U24.102
SIO_LED1_B: length 3.7
  TOP w0.102: Q30.1 108.1,15.57 v2(107.92,15.76) 107.45,15.76 107.33,15.64 R330.1 R370.1
SIO_LED2_B: length 4.6
  TOP w0.102: R371.1 R332.1 102.54,14.7 102.43,14.82 102.43,14.83 102.26,15 Q31.1 102.82,16.52 v2(103.55,16.52)
SLEEVE: length 2.5
  TOP w0.229: v1(10.71,105.42) 10.71,104.06 11.18,103.59 AU1.32
  vias: v1(10.7,106.22) v2(16.32,107.32)
SLEEVE_B:
  vias: v2(20.54,108.92)
SLP_S0IX#: length 2.3
  TOP w0.102: v1(82.11,22.2) 82.06,22.16 ST79.1
  BOTTOM w0.102: U24.100 v1(82.11,22.2)
SLP_S3#: length 156.5
  TOP w0.127: v1(8.22,70.8) 8.22,75.55 5.02,78.75 v1(4.54,78.75)
  IN1 w0.127: v1(79.16,19.67) 78.45,20.38 68.64,20.38 68.46,20.56 64.12,20.56 63.51,19.95 60.97,19.95 60.53,19.52 59.45,19.52 59.19,19.25 58.33,19.25 57.52,18.45 54.92,18.45 54.38,17.91 52.98,17.91 52.27,17.19 51.51,17.19 51.31,17.39 45.11,17.39 44.61,17.9 43.75,18.75 30.22,18.75 29.64,18.17 28.57,18.17 28.31,18.42 28.31,18.43 27.73,19.01 v1(27.42,19.01)
  IN2 w0.127: v1(27.42,19.01) 27.18,19.25 27.18,27.13 27.32,27.27 27.32,37.35 v1(27.73,37.75) 27.13,38.35 27.13,47.8 25.94,48.99 25.94,56.86 25.43,57.37 25.43,57.86 20.71,62.58 18.62,64.67 18.62,71.24 18.84,71.46 18.84,73.98 18.51,74.3 17.57,74.3 16.45,75.42 12.07,75.42 8.22,71.57 v1(8.22,70.8)
  BOTTOM w0.127: PR151.1 4.68,78.75 v1(4.54,78.75) 3.5,79.79 v2(3.5,80.17) ; v1(79.16,19.67) 79.43,19.4 U24.107 82.47,19.4 82.75,19.12 82.75,18.74 82.66,18.65 82.66,18.13 82.78,18.01 82.78,18.01 82.96,17.83 82.96,17.83 82.98,17.81 83.77,17.81 HC11.1 ; v1(27.73,37.75) 27.3,38.19 25.01,38.19 23.37,36.55 SR66.2 MQ6.3
SLP_S4#: length 125.4
  TOP w0.127: v1(4.54,79.38) 4.75,79.38 8.73,75.4 8.73,71.03 11.5,68.26 v1(12.26,68.26) ; v1(70.76,10.84) 70.58,11.02 HC12.1
  IN2 w0.127: v1(22.67,65.01) 23.68,65.01 30.19,58.5 30.19,51.75 30.74,51.19 30.74,31.84 33.2,29.38 33.2,26.35 37.08,22.48 37.08,15.53 37.27,15.34 37.9,14.7 40.46,14.7 41.85,13.32 46.21,13.32 47.33,14.44 54.98,14.44 56.42,13 60.74,13 62.07,11.67 64.36,11.67 64.99,11.03 66.64,11.03 67.27,10.4 67.64,10.4 67.64,10.4 69.48,10.4 69.92,10.84 v1(70.76,10.84)
  BOTTOM w0.127: v1(70.76,10.84) 71.32,10.28 U24.21 ; v1(12.26,68.26) 12.44,68.44 13.89,68.44 14.44,67.88 15.37,67.88 SR72.2 17.18,66.07 19.22,66.07 19.63,66.48 MQ8.3 20.69,65.44 21.13,65.01 v1(22.67,65.01) ; v1(4.54,79.38) 4.54,79.45 PR154.1 5.21,80.95 v2(4.87,81.29)
SMB_CLK_M: length 20
  TOP w0.127: U3.6 45.51,30.1 44.95,30.67 SR112.2 44.58,30.95 44.19,31.34 42.82,31.34 42.42,30.95 SR116.1 41.92,30.16 41.29,30.16 40.78,30.67 SR118.1 40.26,30.27 39.93,29.94 39.56,29.94 38.8,29.18 v1(38.8,28.2) v2(38.09,28.2)
  BOTTOM w0.127: v1(38.8,28.2) 38.27,28.74 38.18,28.74 36.04,30.88 XMM1.202
SMB_CLK_WLAN: length 6.9
  TOP w0.127: v1(40.51,28.15) 40.9,28.15 SR122.2 41.93,27.81 v2(41.93,28.58) ; SR116.2 v1(41.58,31.3)
  IN2 w0.127: v1(40.51,28.15) 40.51,30.22 v1(41.58,31.3)
SMB_DATA_M: length 18.1
  TOP w0.127: v1(43.03,29.45) 42.85,29.27 SR115.1 ; U3.7 45.23,29.45 45.05,29.27 SR114.2 44.58,29.7 v1(44.34,29.94) ; SR117.1 40.6,29.12 v1(40.94,29.45)
  BOTTOM w0.127: XMM1.200 36.16,31.48 38.19,29.45 v1(40.94,29.45) v1(43.03,29.45) 43.05,29.45 v2(43.55,29.94) v1(44.34,29.94)
SMB_DATA_WLAN: length 5.3
  TOP w0.127: SR115.2 41.58,29.21 41.04,28.66 40.29,28.66 40,28.36 40,27.81 40.37,27.44 v2(40.61,27.44) 40.87,27.44 41.58,26.73 SR121.2
SML0_CLK_EC: length 67.4
  TOP w0.127: U4.6 45.72,26.29 45.48,26.53 45.48,26.95 SR120.2 44.71,27.72 42.68,27.72 SR122.1 42.42,27.11 42.55,26.98 v1(43.1,26.98) ; v1(43.1,25.49) 42.74,25.13 42.11,25.13 42.02,25.22 40.94,25.22 39.9,26.26 39.9,26.49 38.91,27.48 37.86,27.48 37.56,27.78 37.56,28.56 38,29 38,29.1 38.91,30 38.91,30.15 SR118.2
  IN1 w0.127: v1(79.82,18.44) 79.6,18.44 79.48,18.56 61.41,18.56 61.03,18.18 59.95,18.18 59.72,17.96 58.86,17.96 58.06,17.15 56.08,17.15 55.8,16.87 53.29,16.87 52.25,15.83 51.54,15.83 50.92,16.45 44.13,16.45 43.88,16.7 43.43,17.15 v1(43.43,17.18)
  IN2 w0.127: v1(43.1,26.98) v1(43.1,25.49) 43.1,25.02 42.59,24.51 42.59,18.65 43.34,17.9 43.34,17.27 v1(43.43,17.18)
  BOTTOM w0.127: v1(43.1,26.98) 43.22,27.11 v2(43.22,27.95) ; U24.110 80.06,18.2 v1(79.82,18.44)
SML0_CLK_USB: length 178.9
  IN1 w0.127: v1(73.98,94.62) 77.82,90.79 82.79,90.79 84.31,92.31 87.81,92.31 89.53,90.59 91.03,90.59 94.05,93.61 104.03,93.61 106.93,90.72 106.93,78.95 v1(107.41,78.47)
  IN2 w0.127: v1(96.51,16.82) 96.39,16.95 92.35,16.95 92.16,17.14 90.02,17.14 89.56,16.68 89.43,16.68 v1(89.43,16.67) ; v1(107.15,14.35) 107.92,14.35 109.36,15.78 114.04,15.78 114.88,16.62 114.88,19.11 116.17,20.41 116.17,29.52 107.51,38.19 107.51,40.85 106.7,41.67 106.7,43.96 106.88,44.14 106.88,48.58 107.04,48.75 107.04,54.85 106.84,55.05 106.84,57.79 107.5,58.44 107.5,68.62 106.47,69.65 106.47,77.53 v1(107.41,78.47) ; v1(73.98,94.62) 73.93,94.67 71.65,94.67 71.37,94.95 69.31,94.95 69.16,94.8 67.71,94.8 67.38,95.13 66.2,95.13 62.02,90.95 62.02,90.43 61.13,89.54 61.13,88.32 61.46,87.99 v1(61.46,87.46)
  BOTTOM w0.127: v1(107.15,14.35) 105.54,14.35 103.83,12.63 100.7,12.63 100.69,12.62 99.11,12.62 97.05,14.69 97.05,16.29 v1(96.51,16.82) ; v1(89.43,16.67) 87.17,16.67 85.6,15.11 83.27,15.11 82.11,16.27 81.78,16.27 81.72,16.2 U24.115 ; UU3.25 61.94,87.94 v1(61.46,87.46) 61.21,87.72 61.07,87.72 R6.1
SML0_DATA_EC: length 62.1
  TOP w0.127: SR117.2 39.48,27.63 40.4,26.7 40.4,26.47 41.15,25.73 42.23,25.73 42.32,25.64 v1(42.42,25.64) SR121.1 43.15,26.32 43.6,26.77 43.6,26.82 43.87,27.09 44.48,27.09 SR119.2 44.96,26.21 45.53,25.64 U4.7
  IN1 w0.127: v1(42.8,17.27) 42.8,17.06 43.67,16.19 43.92,15.94 50.71,15.94 51.33,15.33 52.46,15.33 53.5,16.37 56.01,16.37 56.28,16.64 60.21,16.64 61.59,18.02 77.12,18.02 77.82,17.32 79.33,17.32 v1(79.82,17.8)
  IN2 w0.127: v1(42.8,17.27) 42.8,17.73 42.08,18.44 42.08,24.72 42.42,25.07 v1(42.42,25.64)
  BOTTOM w0.127: v2(42.72,24.37) 42.72,24.62 42.42,24.91 v1(42.42,25.64) ; U24.111 v1(79.82,17.8)
SML0_DATA_USB: length 178.4
  IN1 w0.127: v1(73.55,94.16) 73.61,94.16 77.69,90.08 83,90.08 84.73,91.8 87.6,91.8 89.32,90.08 91.25,90.08 94.23,93.05 103.8,93.05 106.37,90.48 106.37,78.14 106.77,77.73 v1(107.49,77.73)
  IN2 w0.127: v1(73.55,94.16) 71.42,94.16 71.14,94.45 69.54,94.45 69.39,94.29 67.48,94.29 67.18,94.6 66.39,94.6 62.58,90.79 62.58,90.18 61.64,89.24 61.64,88.53 62.12,88.05 v1(62.12,87.44) ; v1(107.49,77.73) 106.98,77.23 106.98,69.86 108.01,68.83 108.01,58.21 107.35,57.56 107.35,55.26 107.55,55.06 107.55,48.54 107.38,48.37 107.38,43.9 107.21,43.72 107.21,41.89 108.02,41.08 108.02,38.41 116.69,29.74 116.69,20.19 115.38,18.88 115.38,16.39 114.27,15.27 109.57,15.27 108.01,13.71 v1(107.18,13.71) ; v1(89.93,16.27) 89.93,16.28 90.29,16.63 91.95,16.63 92.14,16.44 96.08,16.44 v1(96.51,16.01)
  BOTTOM w0.127: R60310.1 60.91,87.03 61.71,87.03 v1(62.12,87.44) UU3.24 ; v1(107.18,13.71) 105.64,13.71 104.04,12.11 98.9,12.11 96.51,14.5 v1(96.51,16.01) ; v1(89.93,16.27) 89.73,16.06 87.27,16.06 85.81,14.6 83.04,14.6 81.83,15.8 U24.116
SO: length 5.8
  BOTTOM w0.102: R243.1 85.46,19.36 v2(86.35,18.47) 88.18,18.47 89.12,19.41 U25.2
SO_EC: length 3.8
  BOTTOM w0.102: U24.103 81.92,21.01 v2(82.87,20.05) 83.56,19.36 R243.2
SOC_RTCX1: length 15
  BOTTOM w0.102: XU1.C9 80.15,69.61 80.15,69.71 80.51,70.07 80.51,70.49 81.6,71.58 81.6,72.04 81.75,72.2
  BOTTOM w0.127: SC6.1 SR63.1 85.09,76.29 84.47,75.67 84.47,73.75 84.22,73.5 84.22,73.21 83.28,72.27 81.83,72.27 81.75,72.2 ; SC6.1 SR64.1 ; SC6.1 86.77,77.15 87.47,77.15 87.81,77.49 v2(88.49,77.49)
SOC_RTCX2: length 12
  BOTTOM w0.102: 81.21,72.2 81.21,71.48 80.14,70.4 XU1.A9
  BOTTOM w0.127: 81.21,72.2 81.21,72.37 81.62,72.78 83.07,72.78 83.71,73.42 83.71,73.71 83.96,73.96 v2(83.96,74.86) 83.96,75.56 83.75,75.78 SR63.2 83.75,77.05 83.88,77.17 SC5.1 83.88,77.7 84.44,78.27 Y5.1
SOC_THERMAL: length 5.9
  TOP w0.102: v2(69.31,27.19) 69.31,26.93 69.54,26.7 69.54,25.32 PRT5.1 70.29,24.13 v1(70.05,23.89) 70.2,23.73 O2R244.1
  BOTTOM w0.102: U24.72 69.72,24.19 70.02,23.89 v1(70.05,23.89)
SP1: length 30.6
  TOP w0.127: J56.P8 15.48,71.76 14.52,70.8 v1(12.41,70.8)
  IN2 w0.127: v1(12.41,70.8) 13.4,70.8 13.53,70.67 13.53,70.14 13.4,70.01 11.68,70.01 11.55,69.88 11.55,69.46 11.68,69.33 13.22,69.33 13.35,69.2 13.35,67.58 13.22,67.45 12.87,67.45 12.74,67.58 12.74,68.56 12.61,68.69 11.58,68.69 11.45,68.56 11.45,66.94 11.58,66.81 13.27,66.81 13.4,66.68 13.4,66.31 13.27,66.18 11.55,66.18 11.42,66.05 11.42,62.46 11.55,62.33 v1(12.29,62.33)
  BOTTOM w0.127: v1(12.29,62.33) 12.29,62.7 11.8,63.18 11.8,63.97 v2(11.52,64.25) 11.14,63.86 11.14,62.84 R199.1
SP1_L: length 3.2
  BOTTOM w0.127: U23.12 10.36,59.68 11.2,60.52 v2(11.78,60.52) 11.78,60.97 11.65,61.1 R199.2
SP2: length 29.3
  TOP w0.127: v1(11.74,70.8) 12.48,70.06 J56.P7
  IN2 w0.127: v1(12.34,60.97) 12.34,61.47 12.21,61.6 11.07,61.6 10.94,61.73 10.94,64.32 10.81,64.45 10.58,64.45 10.46,64.58 10.46,64.96 10.58,65.09 10.81,65.09 10.94,65.21 10.94,65.59 10.81,65.72 10.58,65.72 10.46,65.85 10.46,66.23 10.58,66.36 10.81,66.36 10.94,66.48 10.94,66.86 10.81,66.99 10.58,66.99 10.46,67.12 10.46,67.5 10.58,67.63 10.81,67.63 10.94,67.75 10.94,68.13 10.81,68.26 10.58,68.26 10.46,68.39 10.46,68.77 10.58,68.9 10.81,68.9 10.94,69.02 10.94,69.4 10.81,69.53 10.58,69.53 10.46,69.66 10.46,70.04 10.58,70.17 10.84,70.17 10.97,70.3 10.97,71.1 10.84,71.23 10.05,71.23 9.92,71.36 9.92,72.19 10.05,72.32 10.96,72.32 11.09,72.45 11.09,72.9 11.22,73.03 11.62,73.03 11.75,72.9 11.75,71.75 11.74,71.74 v1(11.74,70.8)
  BOTTOM w0.127: v1(12.34,60.97) 12.34,60.99 v2(13.12,61.78) 13.98,60.93 SR151.1
SP2_L: length 3
  BOTTOM w0.127: SR151.2 12.77,60.41 11.89,59.54 11.89,59.31 11.3,58.71 U23.13
SP3: length 31.5
  TOP w0.127: v1(12.26,64.99) 12.76,65.49 13.12,65.49 13.25,65.36 13.25,64.43 13.38,64.3 13.68,64.3 13.81,64.43 13.81,65.31 13.94,65.44 14.31,65.44 14.44,65.31 14.44,64.91 14.58,64.78 14.89,64.78 15.02,64.91 15.02,65.33 15.13,65.44 15.38,65.44 15.69,65.13 J56.P5
  IN2 w0.127: v1(14.9,59.19) 15.43,59.19 15.56,59.06 15.56,58.58 15.43,58.45 13.38,58.45 13.25,58.58 13.25,59.77 13.38,59.9 13.71,59.9 13.84,59.77 13.84,59.19 13.97,59.06 14.26,59.06 14.39,59.19 14.39,59.77 14.52,59.9 15.31,59.9 15.44,60.03 15.44,61.07 15.31,61.2 14.98,61.2 14.85,61.07 14.85,60.59 14.72,60.46 13.43,60.46 13.3,60.59 13.3,60.97 13.43,61.1 14.14,61.1 14.27,61.23 14.27,61.58 14.14,61.71 13.43,61.71 13.3,61.84 13.3,62.87 13.17,63 12.82,63 12.69,63.13 12.69,63.38 12.82,63.51 13.17,63.51 13.3,63.64 13.3,63.96 13.17,64.09 12.82,64.09 12.69,64.22 12.69,64.47 12.82,64.6 13.22,64.6 13.35,64.73 13.35,65.08 13.17,65.26 12.53,65.26 v1(12.26,64.99)
  BOTTOM w0.127: SR150.1 C248.1 14.19,59.58 14.78,59.58 14.9,59.47 v1(14.9,59.19)
SP3_L: length 2.4
  BOTTOM w0.127: U23.14 11.18,58.21 11.63,58.66 v2(12.17,58.66) 12.59,58.66 12.77,58.48 SR150.2
SP4: length 29.1
  TOP w0.127: J56.P2 15.8,57.63 v1(15.44,57.26)
  IN2 w0.127: v1(16.71,56.01) 17.08,56.01 17.21,56.14 17.21,57 16.88,57.33 16.88,59.62 16.75,59.75 16.45,59.75 16.32,59.62 16.32,56.73 16.19,56.6 11.37,56.6 11.24,56.73 11.24,60.86 11.37,60.99 11.75,60.99 11.88,60.86 11.88,57.62 12.01,57.49 15.21,57.49 v1(15.44,57.26)
  BOTTOM w0.127: v1(16.71,56.01) 16.33,56.38 v2(15.97,56.38) 14.29,56.38 SR149.1
SP4_L: length 2.6
  BOTTOM w0.127: SR149.2 12.43,57.41 11.95,57.41 11.75,57.21 U23.16
SP5: length 28.8
  TOP w0.127: J56.P1 15.68,55.13 15.44,54.89 v1(15.44,54.24)
  IN2 w0.127: v1(15.44,55.81) 15.74,55.51 17.21,55.51 17.34,55.38 17.34,54.88 17.21,54.75 16.73,54.75 16.6,54.62 16.6,54.14 16.73,54.01 17.26,54.01 17.39,53.88 17.39,53.43 17.26,53.3 16.02,53.3 15.89,53.43 15.89,54.72 15.76,54.85 14.93,54.85 14.8,54.98 14.8,55.99 14.67,56.12 11.43,56.12 11.3,55.99 11.3,54.47 11.43,54.34 11.9,54.34 12.03,54.47 12.03,55.2 12.16,55.33 13.88,55.33 14.01,55.2 14.01,54.75 13.88,54.62 12.87,54.62 12.74,54.49 12.74,53.91 12.92,53.73 14.93,53.73 v1(15.44,54.24)
  BOTTOM w0.127: v1(15.44,55.81) 15.44,55.46 v2(14.95,54.97) 14.59,55.34 14.45,55.34 SR147.1
SP5_L: length 2.8
  BOTTOM w0.127: U23.17 11.45,56.71 11.64,56.91 v2(12.16,56.91) 12.56,56.51 12.56,56.39 SR147.2
SP6: length 29.9
  TOP w0.127: v1(15.44,53.53) 16.33,52.63 J56.P9
  IN2 w0.127: v1(12.26,53.81) 12.62,53.45 12.62,51.85 13.33,51.14 13.83,51.14 13.96,51.01 13.96,50.41 13.83,50.28 12.95,50.28 12.82,50.15 12.82,49.8 12.95,49.67 13.78,49.67 13.91,49.54 13.91,48.27 14.04,48.14 14.67,48.14 14.8,48.27 14.8,51.75 14.93,51.88 16.14,51.88 16.27,51.75 16.27,51.17 16.14,51.04 15.69,51.04 15.56,50.91 15.56,49.24 15.69,49.11 16.12,49.11 16.25,49.24 16.25,50.2 16.38,50.33 16.96,50.33 17.09,50.46 17.09,52.51 16.83,52.76 15.69,52.76 15.44,53.02 v1(15.44,53.53)
  BOTTOM w0.127: SR148.1 13.98,54.38 12.59,52.99 v2(12.26,52.99) v1(12.26,53.81)
SP6_L: length 3.1
  BOTTOM w0.127: U23.18 11.78,56.21 12.18,55.81 v2(12.18,55.15) 12.91,55.15 SR148.2
SP7: length 30.4
  TOP w0.127: J56.WP 15.67,74.26 14.93,73.52 14.93,72.1 14.27,71.43 11.47,71.43 11.47,71.43 10.84,70.8 v1(10.23,70.8)
  IN2 w0.127: v1(9.36,54.22) 10.89,55.74 10.89,60.69 10.03,61.55 10.03,70.6 v1(10.23,70.8)
  BOTTOM w0.127: v1(9.36,54.22) 8.78,53.64 8.78,51.95 v2(9.24,51.49) R197.1
SP7_L: length 3.3
  BOTTOM w0.127: U23.20 9.86,55.27 10.15,54.98 10.15,54.52 v2(10.38,54.29) 10.03,53.93 10.03,53.53 9.81,53.31 R197.2
SPI_CLK: length 79.1
  TOP w0.127: P13.7 117.63,94.26 v1(117.32,93.95) ; v1(77.12,80.27) 77.64,79.75 78.85,79.75 79.55,80.45 85.06,80.45 85.18,80.32 85.18,80.12 85.06,79.99 81.04,79.99 80.92,79.87 80.92,79.61 81.04,79.49 v2(81.86,79.49) 82.92,79.49 83.05,79.36 83.05,79.13 82.92,79 82.36,79 82.24,78.88 82.24,77.91 82.87,77.28 F3U1.6 85.11,77.28 85.16,77.23 86.4,77.23 86.77,77.59 89.2,77.59 89.39,77.78 94.05,77.78 94.23,77.61 94.23,77.5 v1(94.58,77.15)
  IN2 w0.127: v1(117.32,93.95) 115.32,95.94 114.52,95.94 114.4,95.82 114.4,95.09 114.27,94.96 113.89,94.96 113.76,95.09 113.76,95.82 113.63,95.94 113.25,95.94 113.13,95.82 113.13,95.09 113,94.96 112.62,94.96 112.49,95.09 112.49,95.82 112.36,95.94 107.66,95.94 105.69,93.98 105.69,87.03 105.19,86.52 105.19,82.08 100.05,76.95 95.9,76.95 95.6,76.64 95.09,76.64 v1(94.58,77.15)
  BOTTOM w0.127: v1(77.12,80.27) 77.12,80.06 76.07,79.01 76.07,78.05 76.09,78.03 76.09,77.59 SR54.2
SPI_CLK_R: length 9.2
  TOP w0.127: v2(75.18,74.23) 75.18,73.7 v1(75.57,73.31)
  BOTTOM w0.102: 74.72,71.94 74.3,71.52 74.3,70.76 73.94,70.4 73.94,70.06 73.95,70.05 74.04,69.95 74.04,69.76 73.73,69.44 XU1.C22
  BOTTOM w0.127: 74.72,71.94 75.18,72.4 75.18,72.4 75.43,72.65 75.43,72.65 75.57,72.79 v1(75.57,73.31) 75.57,74.33 75.19,74.71 75.19,75.85 SR54.1
SPI_CS#: length 81.1
  TOP w0.127: v1(75.56,80.1) 76.06,80.6 76.47,80.6 77.08,81.21 85.84,81.21 87.51,79.55 87.51,79.55 96.17,79.55 96.44,79.28 96.44,78.75 96.23,78.55 v1(96.23,78.27) 96.23,76.35 95.13,75.24 94.24,75.24 R153.1 F3R1.2 ; P13.1 117.61,88.26 v1(117.36,88.01)
  IN2 w0.127: v1(96.23,78.27) 99.93,78.27 103.75,82.09 103.75,88.27 103.51,88.51 103.51,94.47 106.09,97.05 115.94,97.05 118.84,94.15 118.84,89.49 v1(117.36,88.01)
  BOTTOM w0.127: SR48.2 73.7,78.01 v2(74.64,78.95) 75.07,79.38 75.07,79.61 v1(75.56,80.1)
SPI_CS#_HEADER: length 55.5
  TOP w0.127: v1(117.31,88.73) 116.84,88.26 P13.2 ; F3U1.1 R153.2 93.78,75.62 95.15,75.62 95.85,76.33 95.85,77.68 v1(95.52,78.01) v2(95.52,78.83)
  IN2 w0.127: v1(95.52,78.01) 95.7,77.83 99.86,77.83 104.01,81.98 104.01,88.38 103.76,88.62 103.76,94.36 106.2,96.8 115.84,96.8 118.5,94.13 118.5,89.92 v1(117.31,88.73)
SPI_CS#_R: length 7.7
  BOTTOM w0.102: XU1.C23 73.43,69.69 73.43,69.99 73.53,70.08 73.53,70.57 73.89,70.93 73.89,71.94
  BOTTOM w0.127: SR48.1 74.54,75.51 v2(74.54,74.13) 74.54,73.89 73.93,73.28 73.93,73.13 73.89,73.09 73.89,71.94
SPI_HOLD#: length 2.7
  BOTTOM w0.127: U25.7 89.12,13.69 88.91,13.47 R230.2 89.4,13.01 89.45,12.96 v2(89.86,12.96)
SPI_MISO: length 78.8
  TOP w0.127: v1(76.46,80.01) 76.47,80.01 76.47,80.24 77.19,80.96 85.36,80.96 v2(86.07,80.25) 87.03,79.3 94.06,79.3 94.96,78.39 94.96,77.53 v1(95.34,77.15) 95.34,76.64 94.58,75.88 93.68,75.88 93.27,75.47 92.63,75.47 92.09,76.01 F3U1.2 ; v1(117.37,92.65) 117.76,92.26 P13.5
  IN2 w0.127: v1(117.37,92.65) 117.83,93.11 117.83,94.04 115.68,96.2 106.37,96.2 104.93,94.76 104.93,94.43 105.02,94.34 105.28,94.34 105.39,94.23 105.39,93.94 105.27,93.83 104.4,93.83 104.27,93.7 104.27,93.45 104.4,93.32 105.25,93.32 105.38,93.2 105.38,92.94 105.25,92.81 104.4,92.81 104.27,92.69 104.27,92.43 104.4,92.31 105.2,92.31 105.33,92.18 105.33,91.93 105.2,91.8 104.4,91.8 104.27,91.67 104.27,91.42 104.4,91.29 104.98,91.29 105.1,91.17 105.1,90.75 104.93,90.59 104.93,82.19 99.94,77.2 95.39,77.2 v1(95.34,77.15)
  BOTTOM w0.127: v1(76.46,80.01) 74.59,78.15 SR50.2
SPI_MISO_R: length 8
  TOP w0.127: v2(75.07,72.15) v1(75.07,72.91)
  BOTTOM w0.102: XU1.B22 73.73,70.48 74.09,70.85 74.09,71.79 74.25,71.94
  BOTTOM w0.127: 74.25,71.94 74.25,72.08 v1(75.07,72.91) 75.07,74.38 74.93,74.52 74.93,75.64 74.59,75.98 SR50.1
SPI_MOSI: length 75.5
  TOP w0.127: v1(117.33,90.26) 117.33,90.26 P13.3 ; v1(78.13,80.25) 78.17,80.25 78.63,80.7 85.16,80.7 85.44,80.43 85.44,80.02 84.98,79.56 84.1,79.56 83.98,79.43 F3U1.5 85.34,78.55 85.83,79.04 93.88,79.04 94.45,78.47 v1(94.45,78.16)
  IN2 w0.127: v1(94.45,78.16) 95.04,77.58 99.96,77.58 104.68,82.3 104.68,88.63 104.55,88.76 104.15,88.76 104.02,88.88 104.02,89.14 104.15,89.26 104.55,89.26 104.68,89.39 104.68,89.64 104.55,89.77 104.15,89.77 104.02,89.9 104.02,90.15 104.15,90.28 104.55,90.28 104.68,90.41 104.68,90.66 104.55,90.79 104.15,90.79 104.02,90.91 104.02,94.23 106.33,96.54 115.72,96.54 118.16,94.11 118.16,91.09 v1(117.33,90.26)
  BOTTOM w0.127: SR52.2 76.34,78.29 v2(76.57,78.52) 76.57,79.16 77.21,79.79 77.67,79.79 v1(78.13,80.25)
SPI_MOSI_R: length 7.9
  TOP w0.127: v1(76.5,75.32) 76.95,74.87 v2(77.14,74.87)
  BOTTOM w0.102: 75.05,71.94 74.5,71.39 74.5,70.68 74.21,70.39 XU1.A21
  BOTTOM w0.127: 75.05,71.94 76,72.89 76,73.49 75.82,73.67 75.82,74.48 76.05,74.71 76.05,74.87 v1(76.5,75.32) 76.34,75.47 SR52.1
SPI_WP#: length 2.8
  TOP w0.127: F3U1.3 F3R2.2 92.89,76.82 93.11,76.6 v2(93.11,76.26)
SPKR_C: length 220.1
  TOP w0.102: v1(3.98,94.04) R109.1
  IN1 w0.102: v1(9.44,28.63) 10.56,29.75 10.56,30.11 10.58,30.13 10.58,35.77 12.97,38.16 12.97,47.81 7.76,53.02 7.76,53.96 7.56,54.16 7.56,57.26 6.65,58.18 6.65,62.92 7.56,63.84 7.56,68.73 6.76,69.53 6.76,70.61 v1(6.93,70.77) ; v1(92.7,11.41) 88.79,15.33 88.79,19.64 90.01,20.86 90.01,23.71 v1(89.93,23.78) ; v1(22.67,13.83) 22.7,13.8 29.2,13.8 29.84,13.17 29.84,12.28 30.57,11.54 35.6,11.54 39.83,7.31 41.69,7.31 41.97,7.59 52.39,7.59 52.96,8.16 65.17,8.16 66.52,6.82 68.12,6.82 68.38,6.55 69.37,6.55 v1(69.44,6.61)
  IN2 w0.102: v1(22.67,13.83) 22.06,14.44 15.57,14.44 9.33,20.69 9.33,26.04 9.56,26.27 9.56,28.52 v1(9.44,28.63) ; v1(89.93,23.78) 90.19,24.04 90.19,35.07 84.18,41.08 82.58,41.08 81.12,42.54 81.12,43.32 v1(79.64,44.8) ; v1(69.44,6.61) 69.72,6.89 79.49,6.89 84.19,11.6 85.37,12.77 90.45,12.77 91.81,11.41 v1(92.7,11.41) ; v1(3.98,94.04) 3.1,93.16 3.1,91.52 6.15,88.47 6.15,81.28 8.73,78.7 8.73,73.97 6.55,71.79 6.55,71.15 v1(6.93,70.77)
  BOTTOM w0.102: 78.96,45.28 78.62,45.62 78.62,46.96 XU1.BH12
  BOTTOM w0.127: v1(79.64,44.8) 79.22,45.22 79.02,45.22 78.96,45.28
SRTCRST#: length 201.6
  TOP w0.127: SR673.2 67.26,3.62 68.72,5.08 v1(68.72,5.67)
  IN1 w0.127: v1(86.89,12.23) 86.89,12.68 87.34,13.14 87.34,19.9 88.89,21.45 88.89,24.51 89.95,25.56 91.27,25.56 92.45,26.74 92.45,33.18 93.26,33.99 93.26,39.48 94.11,40.33 95.13,40.33 97.44,42.64 97.44,44.59 99.73,46.88 99.73,49.86 98.62,50.97 98.62,52.88 96.27,55.23 96.27,56.67 95.37,57.57 95.25,57.57 94.51,58.31 94.51,59.27 93.13,60.64 93.13,62.33 90.9,64.56 90.9,65.84 88.1,68.64 84.85,68.64 81.88,71.61 v1(80.13,71.61)
  IN2 w0.127: v1(8.96,45.37) 9.48,44.85 9.48,44.12 10.71,42.88 10.71,42.2 11.97,40.94 11.97,37.31 11.27,36.61 11.27,36.59 10.81,36.14 10.81,30.46 15.61,25.66 15.61,19.18 18.18,16.61 22.06,16.61 27.6,11.07 34.68,11.07 35.92,9.84 40.89,9.84 42.54,8.19 51.33,8.19 52.44,9.29 65.82,9.29 67.28,7.83 67.28,7.17 68.72,5.72 v1(68.72,5.67) 68.78,5.67 68.85,5.6 68.85,5.52 69.15,5.23 70.67,5.23 71.32,5.88 80.79,5.88 81.35,6.44 82.69,6.44 83.86,7.6 83.86,9.15 86.05,11.34 86.05,11.39 v1(86.89,12.23)
  BOTTOM w0.102: v1(80.13,71.61) 79.98,71.61 ; 79.38,71.46 78.79,70.87 78.79,70.08 78.88,69.99 78.88,69.72 78.78,69.62 78.59,69.42 XU1.C12
  BOTTOM w0.127: v2(7.19,42.83) C1.1 ; C1.1 6.58,44.31 7.31,44.31 8.37,45.37 v1(8.96,45.37) ; C1.1 R60214.2 ; 79.98,71.61 79.54,71.61 79.38,71.46
SUS_PWRGD: length 129.3
  TOP w0.102: v2(38.73,9.81) v1(39.29,9.25)
  IN1 w0.102: v1(39.29,9.25) 41.15,11.12 45.28,11.12 45.46,11.3 47.59,11.3 48.02,10.87 49.77,10.87 50.14,10.49 52.11,10.49 52.44,10.83 56.63,10.83 59.15,13.35 61.73,13.35 61.87,13.2 65.54,13.2 65.87,13.53 67.87,13.53 68.09,13.75 68.87,13.75 69.2,14.08 71.83,14.08 72.66,14.92 73.17,14.92 v1(74.13,15.88)
  IN2 w0.102: v1(9.75,25.87) 10.41,25.21 10.41,21.28 14.25,17.43 14.25,16.61 15.62,15.25 22.73,15.25 27.4,10.58 34.48,10.58 35.71,9.34 39.2,9.34 v1(39.29,9.25) ; v1(66.6,26.6) 65.64,25.64 65.64,22.16 67.5,20.3 68.98,20.3 69.69,19.59 69.69,18.73 72.94,15.48 73.73,15.48 v1(74.13,15.88) 74.97,16.72 80.38,16.72 81.54,17.88 89.84,17.88 90.07,17.65 90.51,17.65 91.06,18.2 v1(93.01,18.2)
  BOTTOM w0.102: PR61.2 93.11,18.09 v1(93.01,18.2) ; PR52.2 38.49,10.05 v1(39.29,9.25) ; R207.2 v1(66.6,26.6) ; PU3.7 13.7,30.44 14.8,29.35 14.8,28.25 14.27,27.72 12.57,27.72 12.34,27.95 11.64,27.95 PC32.1 10.93,27.72 10.5,27.72 10.09,27.31 10.09,26.64 10.41,26.32 PR34.2 9.76,25.88 v1(9.75,25.87)
SUS_PWRGD_EC_C: length 4.4
  BOTTOM w0.102: 67.44,26.18 R207.1 ; 67.44,26.18 67.72,25.91 U24.67 ; 67.44,26.18 66.15,26.18 v2(65.58,26.76)
SUSB#_PWR: length 72.3
  TOP w0.102: v1(17.66,28.84) 17.69,28.86 18.61,28.86 18.71,28.97 PR80.1 ; O2R249.2 73.75,21.14 v1(72.56,19.95)
  IN1 w0.102: v1(19.21,18.81) 19.31,18.91 26.04,18.91 27.34,17.6 28.55,17.6 28.61,17.65 29.75,17.65 30.41,18.31 37.37,18.31 38,17.67 38.6,17.67 38.83,17.91 43.95,17.91 44.41,17.45 44.91,16.95 51.12,16.95 51.32,16.75 52.46,16.75 53.18,17.46 54.56,17.46 55.1,18.01 57.71,18.01 58.51,18.81 59.37,18.81 59.62,19.06 60.71,19.06 61.1,19.45 72.06,19.45 v1(72.56,19.95)
  IN2 w0.102: v1(19.21,18.81) 19.21,23.03 17.66,24.58 v1(17.66,28.84)
  BOTTOM w0.102: v2(18.78,18.18) 19.21,18.6 v1(19.21,18.81)
SUSB_EC#: length 5.3
  TOP w0.102: v2(74.21,20.94) 74.21,22.78 R233.1 O2R249.1 73.75,23.44 v1(74.12,23.81)
  BOTTOM w0.102: U24.83 v1(74.12,23.81)
SUSC#_PWR: length 91
  TOP w0.102: O2R250.2 72.7,21.65 72.7,20.78 v1(71.85,19.93) ; v1(15.38,47.76) 15.69,48.07 17.58,48.07 PR77.1
  IN1 w0.102: v1(23.33,19.67) 25.56,19.67 27.43,17.8 28.47,17.8 28.52,17.85 29.66,17.85 30.32,18.51 43.65,18.51 44.51,17.65 45.01,17.15 51.21,17.15 51.41,16.95 52.38,16.95 53.09,17.67 54.48,17.67 55.02,18.21 57.62,18.21 58.43,19.01 59.29,19.01 59.55,19.28 60.63,19.28 61.01,19.66 63.56,19.66 64.22,20.32 68.36,20.32 68.75,19.93 v1(71.85,19.93)
  IN2 w0.102: v1(15.38,47.76) 15.38,39.51 16.66,38.24 17.81,38.24 18.2,37.86 18.62,37.86 20.79,35.68 20.79,35.07 21.95,33.91 21.95,31.7 21.7,31.44 21.7,30.2 23.04,28.85 23.04,19.96 v1(23.33,19.67)
  BOTTOM w0.102: v1(15.38,47.76) 15.21,47.76 v2(14.8,47.35)
SUSC_EC#: length 4.3
  TOP w0.102: v2(72.33,24.32) 71.98,23.96 O2R250.1 R234.1 73.45,23.8 v1(73.45,23.83)
  BOTTOM w0.102: U24.82 73.72,24.1 v1(73.45,23.83)
SUSCLK: length 160.9
  TOP w0.102: v1(98.21,17.38) 98.21,18.2 98.54,18.53 106.49,18.53 106.88,18.91 106.88,19.67 107.33,20.13 108.15,20.13 110.15,22.13 111.93,22.13 113.15,20.91 J219.68 ; v1(46.54,9.92) 46.47,9.86 46.47,9.05 46.19,8.77 J218.50 44.55,8.77 43.63,9.69 42.63,9.69 42.48,9.84 40.29,9.84 39.64,10.48 39.64,15.72 39.33,16.04 38.59,16.04 v1(38.13,15.58)
  IN2 w0.102: v1(46.54,9.92) 48.18,9.92 50.23,11.98 58.86,11.98 59.41,11.43 64.23,11.43 64.86,10.79 66.54,10.79 67.51,9.81 79.71,9.81 80.88,10.98 80.88,10.98 84.66,14.77 95.97,14.77 97.13,15.93 97.13,16.3 v1(98.21,17.38) ; v1(38.13,15.58) 38.13,16.76 37.51,17.38 37.51,22.61 33.44,26.67 33.44,29.48 30.98,31.94 30.98,51.34 30.43,51.89 30.43,58.6 23.46,65.57 23.15,65.57 21.27,67.45 21.27,68.15 v1(21.63,68.51)
  BOTTOM w0.102: v2(14.47,69.91) 14.85,70.29 R3.2 SR15.2 15.93,69.14 16.48,68.59 21.28,68.59 21.35,68.51 v1(21.63,68.51)
SUSPWRDNACK: length 108.5
  TOP w0.127: v1(81.37,24.06) 81.96,23.48 v2(82.24,23.48)
  IN1 w0.127: v1(31.87,20.51) 32.29,20.09 33.84,20.09 34.31,20.56 42.36,20.56 42.97,21.17 44.51,21.17 47.15,18.53 49.01,18.53 49.08,18.6 53,18.6 53.48,19.08 54.37,19.08 54.5,18.96 57.31,18.96 58.11,19.76 58.98,19.76 59.86,20.65 61.6,20.65 62.02,21.07 68.68,21.07 68.78,20.96 78.28,20.96 v1(81.37,24.06)
  IN2 w0.127: v1(31.87,20.51) 30.84,21.54 30,21.54 29.56,21.98 29.56,23.28 28.81,24.02 28.81,24.86 28.34,25.33 28.34,35.43 28.95,36.04 28.95,38.6 28.15,39.4 28.15,48.22 27.75,48.62 27.75,57.01 v1(24.07,60.69)
  BOTTOM w0.127: MQ22.3 SC67.1 SR624.2 23.87,60.89 v1(24.07,60.69) ; U24.95 78.92,24.1 79.09,23.94 81.25,23.94 v1(81.37,24.06)
SUSPWRDNACK_1P8V: length 107.9
  TOP w0.102: v1(72.2,68.84) 72.2,69.25 73.88,70.92 73.88,71.51 73.87,71.52 73.87,73.41 73.88,73.41 73.88,74.54 v1(73.7,74.71) 73.25,75.17 SC33.1
  IN1 w0.102: v1(73.7,74.71) 69.7,78.71 69.7,82.69 69.36,83.03 62.64,83.03 61.42,84.25 58.82,84.25 55.46,87.61 54.19,87.61 51.23,90.57 47.29,90.57 47.18,90.68 40.38,90.68 39.21,91.85 35.81,91.85 35.45,91.49 33.91,91.49 32.48,90.07 32.48,77.53 30.42,75.47 30.42,74.57 v1(29.72,73.87)
  BOTTOM w0.102: v1(29.72,73.87) 28.71,72.86 28.71,54.13 28.42,53.84 28.01,53.84 27.7,54.15 27.7,54.95 25.52,57.13 v2(23.39,57.13) 22.83,57.13 22.41,56.71 R60304.1 SR34.2
  BOTTOM w0.127: XU1.D26 72.18,68.84 v1(72.2,68.84)
SUSPWRDNACK_MOS: length 10.2
  BOTTOM w0.102: v2(28.21,54.34) 28.21,56.55 28.06,56.7 MQ23.3 27.17,58.48 26.6,59.05 MQ22.1 24.08,59.05 24.02,59.11 SC36.1 SR625.2
SVID_V1P0_S3: length 27.4
  TOP w0.254: SL2.1 64.52,41.47 64.97,41.92 v1(65.55,41.92) ; C14.1 69.23,61.74 v1(69.4,61.57)
  IN1 w0.254: v1(69.4,61.57) 68.56,60.74 68.56,59.06 67.73,58.23 67.73,55.18 66.54,53.98 65.44,53.98 64.62,53.17 64.62,50.87 65.26,50.24 65.26,49.56 65.99,48.82 65.99,48.37 65.92,48.29 65.92,46.77 65.96,46.73 65.96,42.36 65.55,41.94 v1(65.55,41.92)
  BOTTOM w0.102: v2(64.58,41.11) 64.74,41.11 v1(65.55,41.92)
  BOTTOM w0.254: XU1.V32 69.4,61.58 v1(69.4,61.57)
U1_OE: length 4
  BOTTOM w0.102: U1.5 19.47,37.42 19.5,37.45 SR67.2 SR68.2 17.76,38.02 v2(17.11,38.67)
U1_VCCA: length 5.8
  BOTTOM w0.102: R60307.2 C2.1 20.35,31.78 20.35,33.55 20.12,33.78 U1.1 20.12,34.67 20.31,34.86 20.85,34.86 v2(21.43,34.27)
U1_VCCB: length 6.4
  BOTTOM w0.102: C3.1 R60308.2 19.94,38.9 19.91,38.86 SR67.1 ; C3.1 20.85,38.43 22.08,38.43 22.24,38.59 v2(23.31,38.59) ; C3.1 20.35,37.55 20.12,37.32 U1.6
U2HUB_OVCUR3: length 2
  BOTTOM w0.254: UU3.20 64.37,84.71 64.04,84.38 R10.1
U2HUB_OVCUR4: length 1.9
  BOTTOM w0.254: R11.1 64.89,84.51 64.87,84.53 UU3.19
U2HUB_PSELF: length 6.9
  BOTTOM w0.254: v2(57.52,84.15) R16.1 59.03,85.66 60.2,85.66 R19.2 61.36,85.15 62.65,86.44 UU3.22
U2HUB_RREF: length 4.7
  BOTTOM w0.102: R22.1 v2(69.12,92.35)
  BOTTOM w0.254: R22.1 68.17,91.35 68.57,90.94 68.57,89.8 68.22,89.44 UU3.8
U3_EN: length 9.5
  TOP w0.102: v2(47.19,32.29) 46.64,32.29 46.28,31.93 46.28,31.29 46.4,31.17 U3.5 49.76,30.75 51.06,32.06 52.51,32.06 SR113.2
U4_EN: length 10.4
  TOP w0.102: U4.5 48.16,26.94 49.56,28.34 51.26,28.34 52.04,27.57 52.33,27.57 52.58,27.32 52.58,27.23 52.61,27.2 52.61,26.88 SR109.2 53.45,27.16 54.73,27.16 v2(54.91,27.34)
U14_EN: length 5.9
  BOTTOM w0.102: v2(102.46,39.99) 102.46,43.16 102.17,43.45 U14.4 100.5,43.45 100.45,43.41 UR3.2
U18_EN: length 3.7
  TOP w0.102: U18.4 71.94,91.99 72.14,91.78 UR7.2 72.14,90.94 71.33,90.13 v2(70.78,90.13)
UNCORE_V1P0_S0IX: length 26.4
  TOP w0.457: v1(70.16,54.51) 70.93,54.51 70.99,54.45 C37.1 72.5,54.45 72.6,54.56 ; C38.1 73.97,60.78 v1(73.96,60.79)
  TOP w0.508: 72.6,54.56 73.97,55.92 v1(73.97,57.64) ; v1(70.16,54.51) 70.16,53.68 69.67,53.2 v2(69.67,49.74) 69.67,49.5 69.44,49.26 69.44,48.23 69.15,47.94 C41.1 C40.1 C39.1 69.15,42.33 69.17,42.3 69.17,41.79 68.67,41.29 SL7.1
  IN1 w0.508: v1(73.97,57.64) 73.97,60.78 v1(73.96,60.79)
  BOTTOM w0.254: XU1.AF21 74.33,58 v1(73.97,57.64) 73.97,57.61 XU1.AG21
  BOTTOM w0.305: XU1.AN30 69.78,54.13 v1(70.16,54.51) 70.54,54.13 XU1.AN29
UNCORE_V1P0_S3: length 29.3
  TOP w0.254: v1(75.47,58.41) 75.49,58.39 C42.1 ; v1(85.39,67.4) 85.48,67.31 C43.1 86.23,66.73 v2(86.45,66.51)
  IN1 w0.381: v1(75.47,58.41) 75.47,58.77 76.23,59.54 v1(76.23,60.79)
  IN1 w0.508: v1(85.36,61.43) 77.03,61.43 76.39,60.79 v1(76.23,60.79)
  IN2 w0.254: v1(85.39,67.4) 85.29,67.3 85.29,63.76 85.19,63.67 85.19,61.6 v1(85.36,61.43)
  BOTTOM w0.254: XU1.G1 85.09,67.1 v1(85.39,67.4) ; XU1.Y18 v1(76.23,60.79) ; v1(75.47,58.41) XU1.AF18 76.01,57.87 76.44,57.87 XU1.AF16
  BOTTOM w0.508: v1(85.36,61.43) 87.72,61.43 88.03,61.73 88.76,61.73 SL8.1
UNCORE_V1P8_G3: length 22.2
  TOP w0.432: v1(75.47,60.77) 75.53,60.82 C30.1
  TOP w0.508: v1(88.03,62.72) 87.75,62.72 87.19,63.28 v2(83.69,63.28) v1(82.77,63.28)
  IN1 w0.381: v1(73.95,62.35) 73.95,62.29 v1(75.47,60.77)
  IN2 w0.381: v1(75.47,60.77) 75.47,60.76 76,60.23 76.47,60.23 76.79,60.55 76.79,60.62 77.18,61 80.98,61 82.77,62.8 v1(82.77,63.28)
  BOTTOM w0.203: XU1.U24 73.01,62.74 73.42,63.15 73.71,63.15 73.95,62.9 v1(73.95,62.35)
  BOTTOM w0.254: XU1.AA18 75.85,60.39 v1(75.47,60.77)
  BOTTOM w0.508: SL6.2 89.42,62.34 89,62.34 88.62,62.72 v1(88.03,62.72)
USB3_REXT[0]: length 11.5
  TOP w0.102: v2(88.21,61.82) SR91.1 87.22,62.11 86.88,62.44 v1(86.79,62.44)
  IN1 w0.102: v1(78.68,64.26) 79.55,63.39 79.55,63.11 79.82,62.83 83.48,62.83 83.5,62.85 86.38,62.85 v1(86.79,62.44)
  BOTTOM w0.102: v1(78.68,64.26) 78.92,64.5 XU1.M12
USB3_RXN0: length 69.4
  IN1 w0.114: v1(82.94,67.47) 83.2,67.47 84.09,66.58 86.39,66.58 91.38,61.6 91.38,59.91 91.99,59.3 91.99,58.57 92.24,58.31 92.6,58.31 92.72,58.2 92.72,57.86 92.6,57.74 92.24,57.74 91.99,57.49 91.99,56.59 92.24,56.33 93.57,56.33 93.69,56.21 93.69,55.89 93.57,55.76 92.24,55.76 91.99,55.51 91.99,54.84 92.25,54.58 94.1,54.58 94.24,54.44 94.24,54.14 94.13,54.02 93.55,54.02 93.35,53.82 93.35,53.12 94.11,52.36 96.5,52.36 96.63,52.23 96.63,51.6 96.45,51.42 94.63,51.42 94.35,51.14 94.35,50.48 93.62,49.74 93.62,46.73 94.98,45.38 94.98,44.74 v1(94.75,44.51)
  BOTTOM w0.114: v2(104.41,49.54) 104.68,49.54 ; 104.68,49.54 104.68,48.68 104.57,48.56 103.98,48.56 103.26,49.27 101.54,49.27 100.83,48.56 100.21,48.56 99.9,48.26 99.9,47.16 97.69,44.95 95.19,44.95 v1(94.75,44.51) ; 104.68,49.54 104.68,49.97 104.94,50.22 105.48,50.22 105.74,49.97 105.74,48.68 105.85,48.56 106.44,48.56 UU1.5 UU1.6 107.4,48.57 108.39,48.57 109.33,49.51 109.33,54.11 109.67,54.45 110.62,54.45 110.76,54.59 J133.5 ; XU1.E3 v1(82.94,67.47)
USB3_RXP0: length 69.5
  IN1 w0.114: v1(82.43,67.9) 83.11,67.9 84.19,66.82 86.49,66.82 91.62,61.7 91.62,60.01 92.23,59.4 92.23,58.67 92.34,58.55 92.7,58.55 92.96,58.3 92.96,57.76 92.7,57.5 92.34,57.5 92.23,57.39 92.23,56.69 92.34,56.57 93.67,56.57 93.93,56.31 93.93,55.79 93.67,55.52 92.34,55.52 92.23,55.41 92.23,54.94 92.35,54.82 94.2,54.82 94.48,54.54 94.48,54.03 94.23,53.78 93.65,53.78 93.59,53.72 93.59,53.22 94.21,52.6 96.6,52.6 96.87,52.33 96.87,51.49 96.55,51.18 94.73,51.18 94.59,51.04 94.59,50.38 93.86,49.64 93.86,46.83 95.22,45.48 95.22,44.72 v1(95.41,44.53)
  BOTTOM w0.114: XU1.D4 82.46,67.93 v1(82.43,67.9) ; v2(100.42,47.63) 100.14,47.63 ; 100.14,47.63 100.14,48.16 100.31,48.32 100.93,48.32 101.64,49.03 103.16,49.03 103.88,48.32 104.67,48.32 104.93,48.58 104.93,49.87 105.04,49.98 105.38,49.98 105.5,49.87 105.5,48.58 105.75,48.32 106.43,48.32 UU1.4 UU1.7 107.44,48.33 108.49,48.33 109.57,49.41 109.57,54.01 109.77,54.21 110.53,54.21 110.76,53.99 J133.6 ; 100.14,47.63 100.14,47.06 97.79,44.71 95.59,44.71 v1(95.41,44.53)
USB3_SS_TXN0_C: length 7.4
  BOTTOM w0.114: J133.8 110.76,48.72 110.64,48.61 110.03,48.61 108.48,47.05 107.42,47.05 UU1.9 UU1.2 106.43,47.05 105.42,47.05 UC2.2
USB3_SS_TXP0_C: length 7.4
  BOTTOM w0.114: UC1.2 105.3,46.81 106.44,46.81 UU1.1 UU1.10 107.41,46.81 108.58,46.81 110.13,48.37 110.67,48.37 110.76,48.28 J133.9
USB3_TXN0: length 69.8
  IN1 w0.114: v1(93.97,44.79) 93.58,45.18 92.69,45.18 92.31,45.56 92.31,46.41 92.58,46.68 92.77,46.68 92.88,46.8 92.88,47.14 92.77,47.25 92.09,47.25 91.83,47.52 91.83,48.04 92.09,48.31 92.77,48.31 92.88,48.42 92.88,48.77 92.77,48.88 92.09,48.88 91.83,49.15 91.83,49.67 92.09,49.93 92.77,49.93 92.88,50.05 92.88,50.39 92.77,50.51 92.58,50.51 92.31,50.77 92.31,51.29 92.58,51.56 93.31,51.56 93.44,51.69 93.44,51.99 93.3,52.13 92.67,52.13 92.41,52.39 92.41,53.08 90.64,54.85 90.64,55.28 90.89,55.53 91.13,55.53 91.24,55.65 91.24,55.99 91.13,56.1 90.89,56.1 90.64,56.36 90.64,56.9 90.89,57.16 91.13,57.16 91.24,57.27 91.24,57.62 91.13,57.73 90.89,57.73 90.64,57.98 90.64,61.29 87.59,64.35 86.79,64.35 86.53,64.6 86.53,65.39 86.4,65.52 86.09,65.52 85.96,65.39 85.96,64.6 85.7,64.35 85.16,64.35 84.7,64.8 83.09,64.8 82.15,65.74 81.79,65.74 v1(81.39,66.14)
  BOTTOM w0.114: v1(93.97,44.79) 93.66,44.79 93.49,44.61 92.48,44.61 92.22,44.87 92.22,47.28 92.1,47.41 91.78,47.41 91.65,47.28 91.65,44.87 91.4,44.61 90.7,44.61 90.57,44.48 90.57,44.03 ; XU1.K7 81.05,65.8 v1(81.39,66.14) ; v2(90.85,44.03) 90.57,44.03 ; 90.57,44.03 90.57,43.57 90.7,43.44 92.93,43.44 93.24,43.75 97.71,43.75 99.09,45.13 99.99,45.13 100.11,45.25 100.11,46.15 100.37,46.41 100.83,46.41 101.04,46.2 102.13,45.11 102.35,45.11 102.55,45.32 102.55,45.7 101.27,46.98 101.27,47.31 101.81,47.85 102.32,47.85 103.07,47.1 103.87,47.1 UC2.1
USB3_TXP0: length 69.8
  IN1 w0.114: v1(82.06,66.17) 83.19,65.05 84.8,65.05 85.26,64.59 85.6,64.59 85.72,64.7 85.72,65.49 85.99,65.76 86.5,65.76 86.77,65.49 86.77,64.7 86.89,64.59 87.69,64.59 90.88,61.39 90.88,58.08 90.99,57.97 91.23,57.97 91.48,57.72 91.48,57.17 91.23,56.92 90.99,56.92 90.88,56.8 90.88,56.46 90.99,56.35 91.23,56.35 91.48,56.09 91.48,55.55 91.23,55.29 90.99,55.29 90.88,55.18 90.88,54.95 92.65,53.18 92.65,52.49 92.77,52.37 93.4,52.37 93.68,52.09 93.68,51.59 93.41,51.32 92.68,51.32 92.55,51.19 92.55,50.87 92.68,50.75 92.87,50.75 93.12,50.49 93.12,49.95 92.87,49.69 92.19,49.69 92.07,49.57 92.07,49.25 92.19,49.12 92.87,49.12 93.12,48.87 93.12,48.32 92.87,48.07 92.19,48.07 92.07,47.94 92.07,47.62 92.19,47.5 92.87,47.5 93.12,47.24 93.12,46.7 92.87,46.44 92.68,46.44 92.55,46.31 92.55,45.66 92.79,45.42 v1(93.96,45.42)
  BOTTOM w0.114: v1(82.06,66.17) 81.76,65.87 XU1.K6 ; 91.41,46.62 91.41,44.97 91.29,44.85 90.6,44.85 90.33,44.58 90.33,43.47 90.6,43.2 93.03,43.2 93.34,43.51 97.81,43.51 99.19,44.89 100.09,44.89 100.35,45.14 100.35,46.05 100.47,46.17 100.73,46.17 102.03,44.87 102.45,44.87 102.79,45.22 102.79,45.8 101.52,47.08 101.52,47.21 101.91,47.61 102.22,47.61 102.97,46.86 103.88,46.86 UC1.1 ; 91.41,46.62 v2(91.13,46.62) ; 91.41,46.62 91.41,47.38 91.68,47.65 92.2,47.65 92.46,47.38 92.46,44.97 92.58,44.85 93.39,44.85 v1(93.96,45.42)
USB_HSIC_RCOMP: length 14
  BOTTOM w0.102: XU1.A7 81.05,70.33 81.94,71.22 83.65,71.22 84.42,71.99 85.31,71.99 86,72.68 SR172.1 86.45,74.72 86.45,75.74 86.79,76.07 87.23,76.07 87.44,75.86 88.11,75.86 89.71,77.45 v2(90.26,77.45)
USB_HSIC_V1P2_G3: length 2.3
  TOP w0.254: v1(76.23,62.34) 76.32,62.25 C941137.1
  TOP w0.432: SL16.2 77.59,62.42 77.42,62.25 C941137.1
  BOTTOM w0.254: XU1.V18 v1(76.23,62.34)
USB_OC0#: length 38.2
  TOP w0.102: v1(76.5,74.56) 76.72,74.34 77.38,74.34 77.67,74.63 77.67,75.06 77.22,75.51 77.22,77.8 SR95.2 ; R244.2 72.97,94.61 72.97,93.6 74.47,92.1 74.47,91.61 v1(75.03,91.04)
  IN2 w0.102: v1(75.03,91.04) 75.03,88.23 74.99,88.18 74.99,87.1 76.87,85.22 76.87,81.12 77.54,80.45 77.54,80.1 77.01,79.57 77.01,77.97 77.26,77.72 77.26,77.5 76.69,76.93 76.69,75.96 77.03,75.62 77.03,75.21 76.5,74.67 v1(76.5,74.56)
  BOTTOM w0.102: v1(75.03,91.04) 76.27,91.04 76.78,90.53 v2(77.28,90.53) ; XU1.C20 74.7,69.42 74.41,69.72 74.41,69.98 74.7,70.27 74.7,71.27 76.22,72.78 76.22,73.58 76.06,73.73 76.06,74.12 v1(76.5,74.56)
USB_OC1#: length 68.7
  TOP w0.102: v1(76.48,73.92) 77.25,73.92 77.87,74.54 77.87,75.17 77.45,75.59 77.45,77.67 77.87,78.09 78.34,78.09 SR94.2 79.29,78.48 79.65,78.12 79.65,73.39 80.56,72.48 86.44,72.48 89.25,69.67 89.25,69.4 92.68,65.97 96.27,65.97 97.44,64.8 97.44,63.61 99.3,61.76 100.17,61.76 102.02,59.9 104.89,59.9 105.73,59.06 105.73,57.13 106.09,56.78 106.09,55.13 105.83,54.87 105.83,51.06 105.5,50.73 105.5,46.14 v1(105.96,45.68)
  BOTTOM w0.102: U14.5 105.67,43.45 105.38,43.75 105.38,44.47 UR1.2 105.8,45.51 v1(105.96,45.68) 106.88,45.68 v2(107.36,45.2) ; v1(76.48,73.92) 76.48,72.76 74.91,71.19 74.91,70.06 XU1.B20
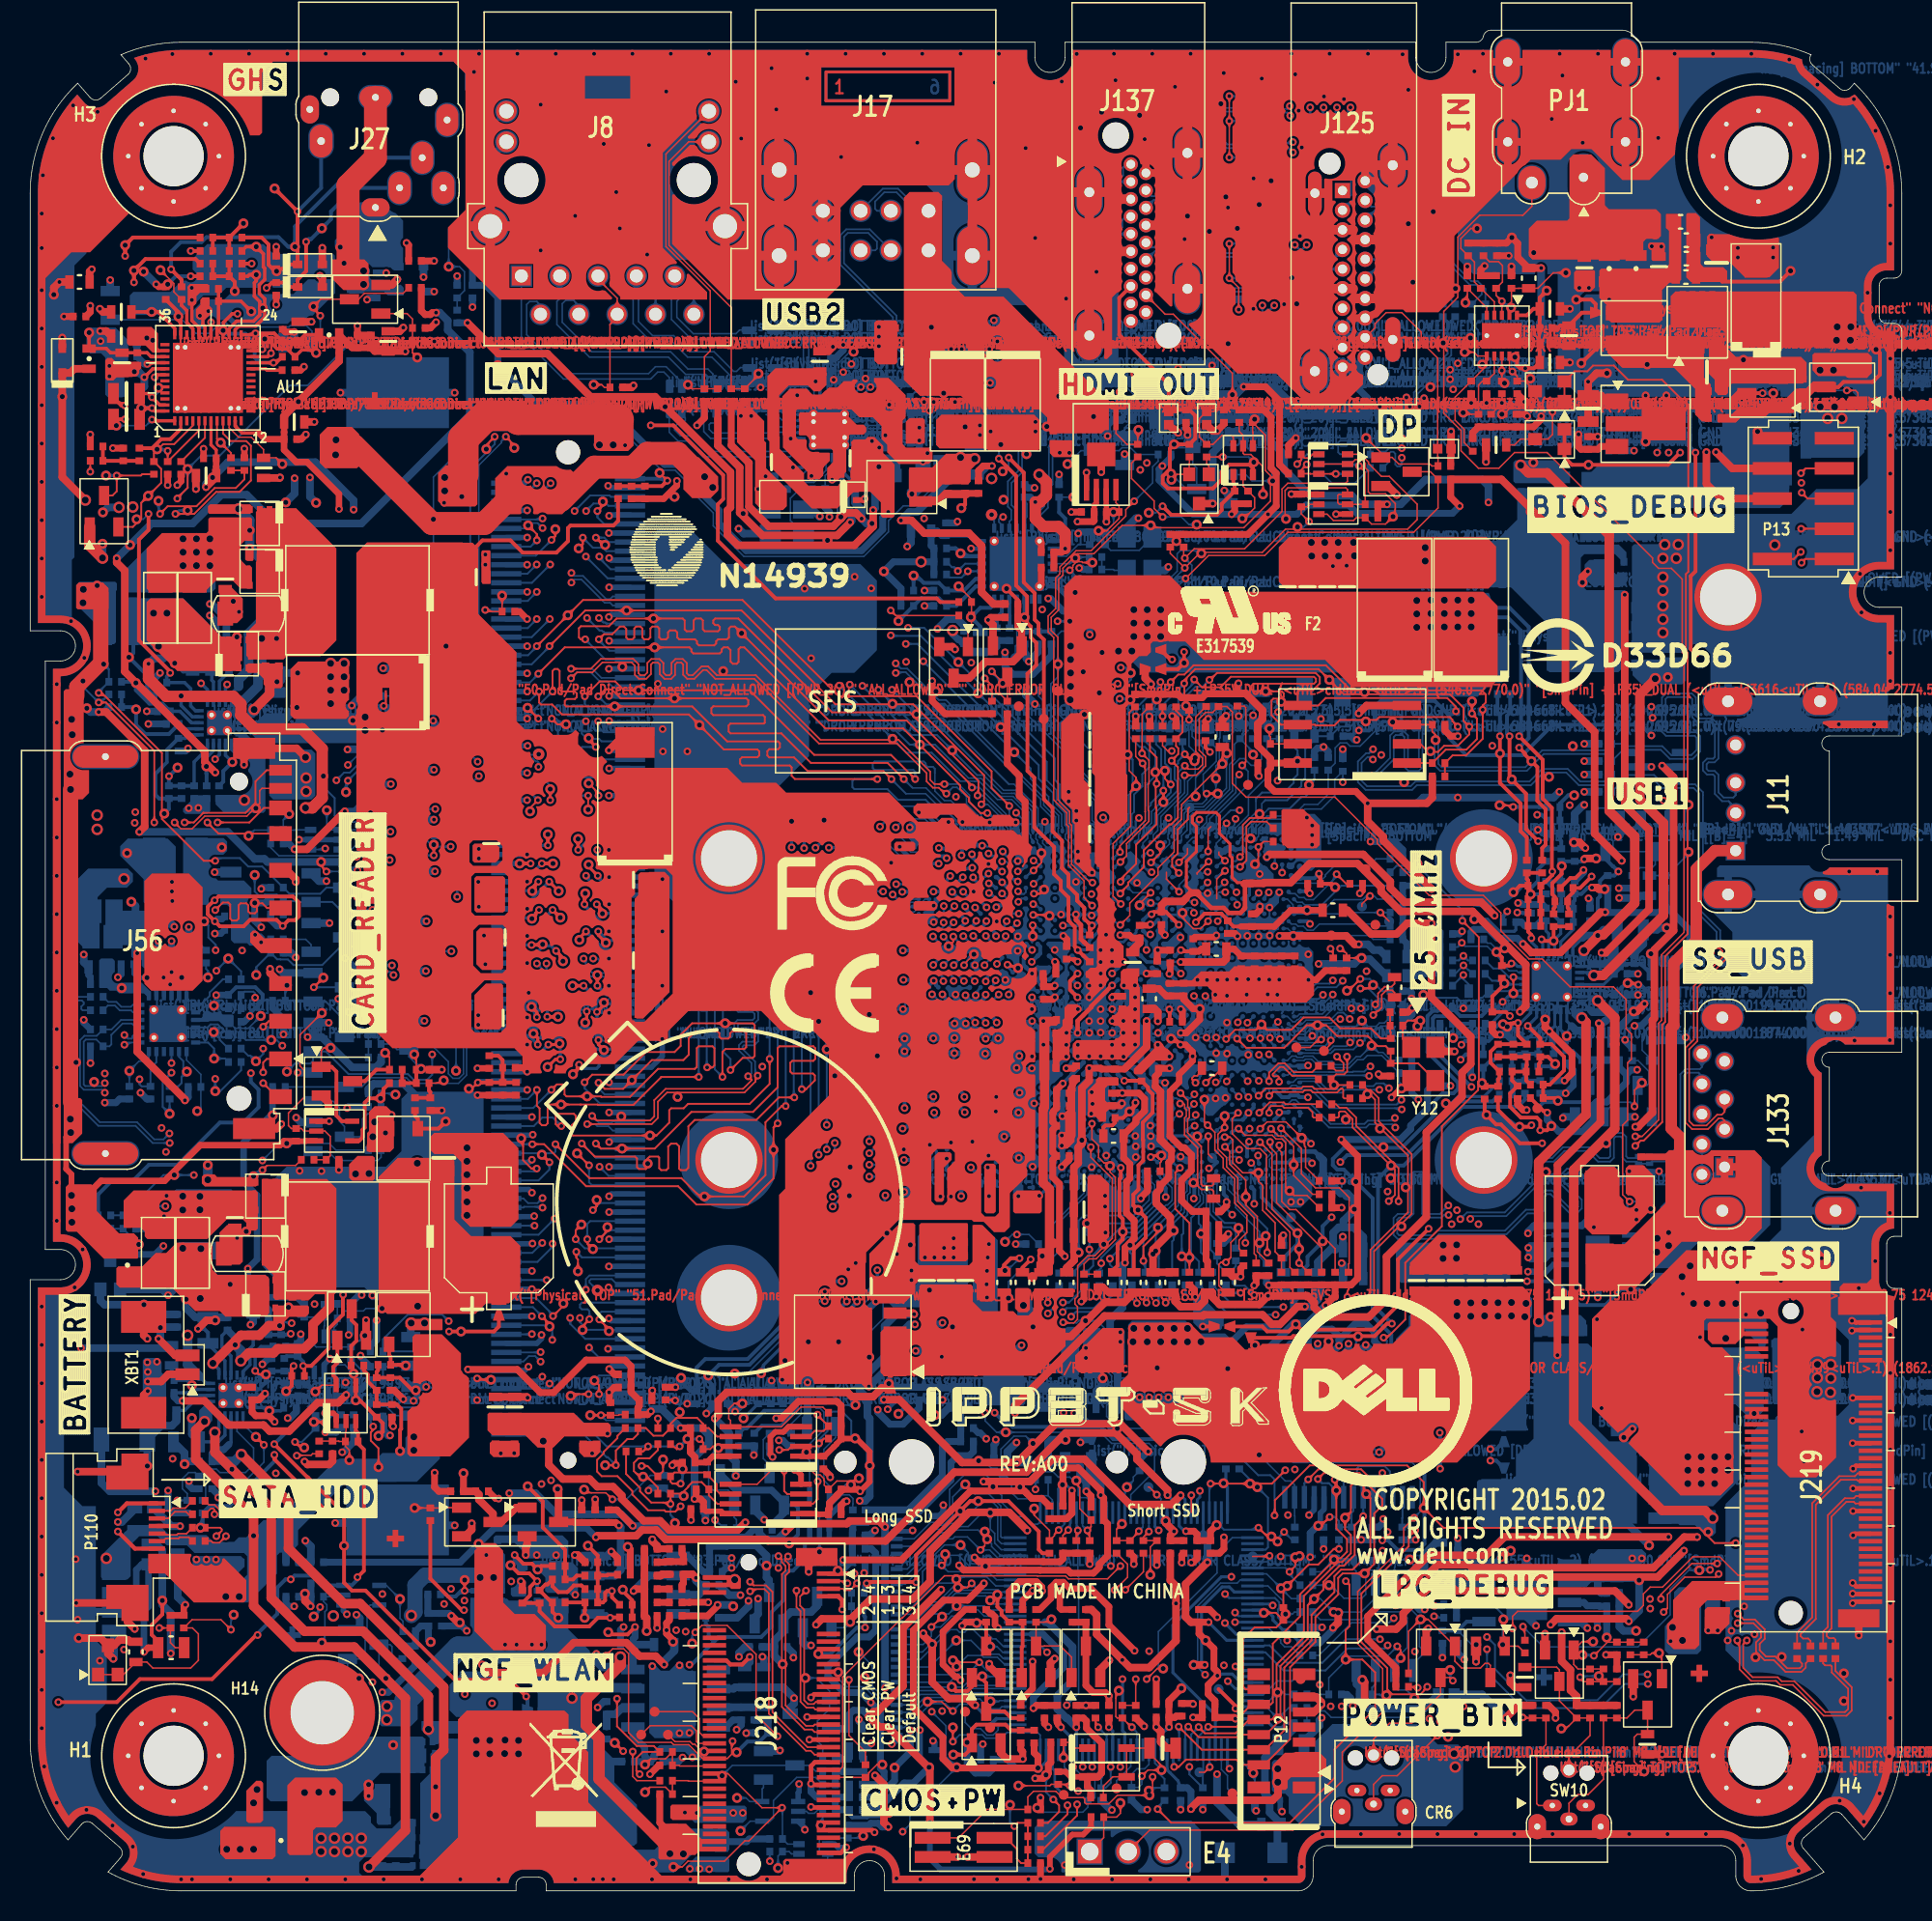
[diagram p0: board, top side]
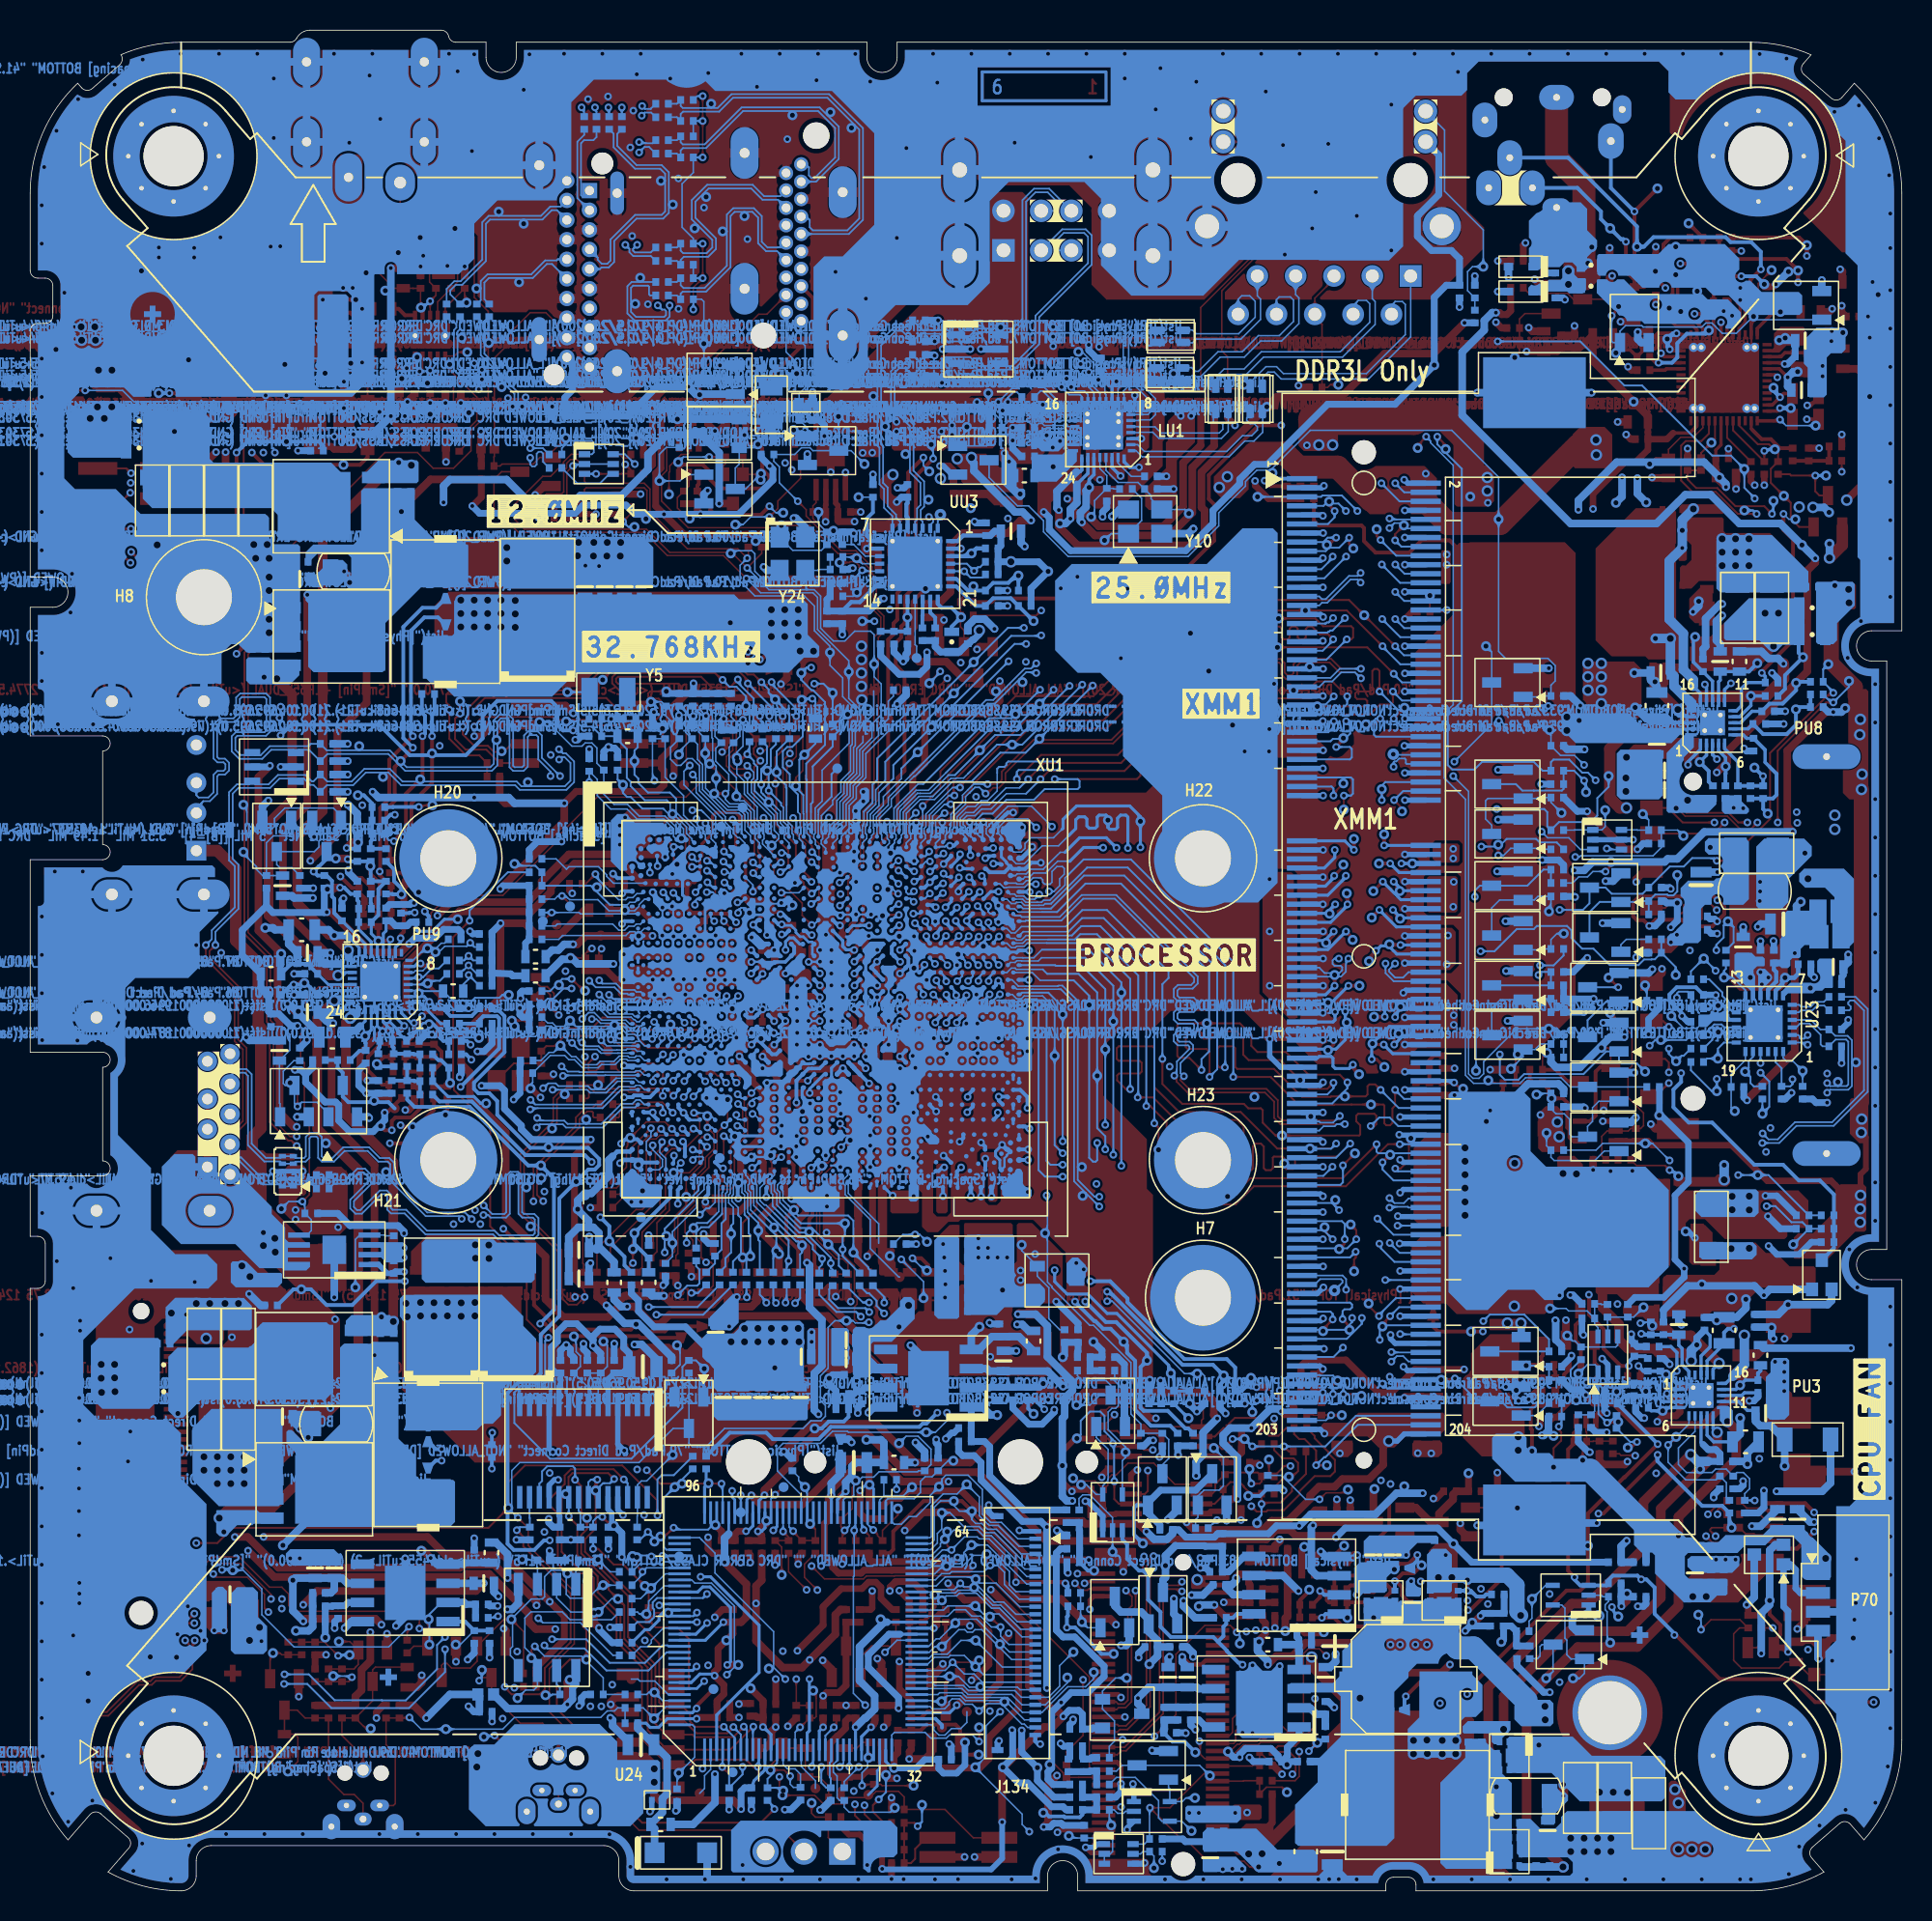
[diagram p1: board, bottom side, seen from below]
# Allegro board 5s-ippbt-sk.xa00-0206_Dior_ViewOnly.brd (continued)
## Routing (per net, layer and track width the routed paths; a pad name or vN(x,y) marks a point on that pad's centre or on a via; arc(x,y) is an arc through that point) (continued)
USB_PLL_MON: length 12.7
  TOP w0.102: v1(78.04,64.26) 77.55,63.76 77.06,63.76 76.34,64.48 v2(76.34,64.8) ; v1(86.15,62.43) 86.33,62.25 SR193.1
  IN1 w0.102: v1(78.04,64.26) 78.05,64.26 78.47,63.84 78.66,63.84 79.34,63.15 79.34,63.02 79.87,62.49 86.09,62.49 v1(86.15,62.43)
  BOTTOM w0.102: v1(78.04,64.26) 78.04,64.27 78.21,64.43 XU1.M13
USB_RCOMP: length 3.4
  TOP w0.102: v2(81.15,68.03) 81.37,68.26 v1(81.37,69.18) 81.37,69.19 81.72,69.53 SR98.1
  BOTTOM w0.102: XU1.C7 80.9,69.18 v1(81.37,69.18) 81.41,69.14 XU1.D6
USB_V1P0_S3: length 11.8
  TOP w0.254: 80.23,63.9 79.72,63.9 C45.1 79.34,64.33 78.91,64.75 77.8,64.75 v1(77.23,64.18)
  TOP w0.432: SL11.1 v2(84.6,64.98) 83.51,64.98 82.43,63.9 C46.1 80.23,63.9
  IN2 w0.254: v1(77.23,64.18) 77.23,64.18 77.2,64.18 v1(76.21,63.18)
  BOTTOM w0.254: v1(77.23,64.18) 77.23,64.19 77.63,64.59 XU1.M14
USBN0: length 82.3
  TOP w0.114: J133.2 112.26,51.04 112.11,51.19 111.87,51.19 111.15,50.48 110.1,50.48 109.67,50.91 109.67,55.86 110.22,56.41 110.22,59.95 112.12,61.86 112.12,62.28 v1(111.73,62.67)
  IN1 w0.114: v1(77.14,65.5) 77.34,65.7 77.34,69.47 77.92,70.05 77.92,72.02 79.02,73.12 79.02,76.06 79.39,76.43 80.84,76.43 81.1,76.17 81.1,75.25 81.21,75.14 81.56,75.14 81.67,75.25 81.67,76.17 81.93,76.43 82.47,76.43 82.73,76.17 82.73,75.25 82.84,75.14 83.18,75.14 83.3,75.25 83.3,76.17 83.55,76.43 84.32,76.43 85.61,75.14 88,75.14 88.32,75.46 88.78,75.46 v1(88.97,75.65)
  BOTTOM w0.114: 100.63,74.11 100.27,74.11 99.43,73.27 91.87,73.27 91.56,72.96 88.47,72.96 87.97,73.47 87.97,74.84 88.51,75.38 88.7,75.38 v1(88.97,75.65) ; 100.63,74.11 101.76,74.11 102.6,73.27 104.34,73.27 UC13.1 105.23,73.28 105.44,73.28 105.86,73.7 106.22,73.7 UU2.1 106.56,73.7 107.49,73.7 108.1,73.08 110.2,73.08 110.58,72.7 110.58,68.39 110.2,68 110.2,65.07 111.73,63.55 v1(111.73,62.67) ; 100.63,74.11 v2(100.63,73.82) ; v1(77.14,65.5) 76.89,65.5 XU1.K16
USBN1: length 73
  IN1 w0.114: v1(89.53,73.87) 89.1,74.3 85.93,74.3 85.77,74.14 85.77,72.43 85.66,72.32 85.31,72.32 85.2,72.43 85.2,74.14 84.94,74.4 82.42,74.4 81.89,73.87 81.89,73.54 81.59,73.24 80.25,73.24 78.59,71.59 78.59,69.32 78.5,69.22 78.5,67.65 78.37,67.53 v1(78.01,67.53)
  BOTTOM w0.114: 93.05,75.52 93.05,74.59 93.41,74.22 99.16,74.22 100.28,75.34 104.3,75.34 UC15.1 105.53,75.61 106.21,75.61 UU2.3 106.57,75.61 108.03,75.61 108.63,75.02 110.15,75.02 110.65,75.51 110.65,76.51 110.38,76.78 108.48,76.78 108.35,76.91 108.35,78.98 108.48,79.1 109.99,79.1 110.11,78.98 110.11,77.77 110.43,77.45 111.33,77.45 111.61,77.17 111.61,75.14 111.5,75.03 111.09,75.03 110.83,74.76 110.83,74.24 111.09,73.97 111.5,73.97 111.61,73.86 111.61,72.69 112.1,72.21 112.53,72.21 112.99,71.75 J11.2 ; 93.05,75.52 93.05,77.47 92.82,77.7 92.4,77.7 92.25,77.54 92.25,74.46 92.01,74.22 91.31,74.22 91.04,74.49 91.04,76.46 90.91,76.59 90.47,76.59 90.34,76.46 90.34,74.98 89.53,74.17 v1(89.53,73.87) ; 93.05,75.52 v2(92.77,75.52) ; XU1.G14 77.63,67.37 77.78,67.53 v1(78.01,67.53)
USBN3_HUB: length 80.6
  IN2 w0.114: v1(79.92,66.17) 79.8,66.17 79.33,65.71 78.97,65.71 78.69,65.99 78.69,66.97 78.74,67.02 78.74,71.86 78.96,72.08 80.31,72.08 80.64,71.75 80.64,69.99 80.91,69.72 81.68,69.72 81.95,69.99 81.95,72.72 81.18,73.48 77.33,73.48 77.2,73.61 77.2,74.16 77.56,74.52 79.38,74.52 79.65,74.79 79.65,75.29 79.77,75.42 80.38,75.42 80.57,75.61 80.57,76.69 80.31,76.96 79.52,76.96 78.86,76.3 77.54,76.3 77.42,76.41 77.42,76.63 77.66,76.86 78.4,76.86 78.8,77.26 78.8,78.05 78.51,78.34 77.86,78.34 77.74,78.46 77.74,79.02 77.86,79.14 78.36,79.14 78.95,78.56 80.32,78.56 80.57,78.81 80.57,79.3 80.31,79.56 79.91,79.56 79.55,79.92 78.95,79.92 78.8,80.07 78.8,80.43 79.05,80.68 80.31,80.68 80.57,80.95 80.57,82.89 80,83.46 79.27,83.46 79,83.19 79,82.08 78.83,81.91 78.1,81.91 77.65,82.35 77.65,83.03 78.63,84.01 78.63,84.85 77.65,85.83 77.65,88.24 76.07,89.82 76.07,92.39 75.12,93.34 72.62,93.34 72.36,93.08 72.36,92.24 72.25,92.12 71.91,92.12 71.79,92.24 71.79,93.08 71.54,93.34 70.99,93.34 70.74,93.08 70.74,92.24 70.62,92.12 70.28,92.12 70.17,92.24 70.17,93.08 69.91,93.34 69.39,93.34 67.14,91.08 65.73,91.08 65.07,91.74 64.34,91.74 63.8,91.2 v4(63.7,91.2)
  BOTTOM w0.114: UU3.1 63.87,91.02 v4(63.7,91.2) ; v1(79.92,66.17) 79.61,66.49 XU1.H10
USBN_HUB1: length 35.7
  BOTTOM w0.114: UU3.3 64.87,90.74 65,90.87 65,91.5 64.78,91.73 64.78,92.19 ; v2(64.48,92.19) 64.78,92.19 ; 64.78,92.19 64.78,93.4 65.47,94.1 65.47,97.15 66.73,98.41 66.73,100.59 66.42,100.9 66.05,100.9 UC6.1 64.99,100.94 63.69,100.94 63.24,101.39 62.81,101.39 U19.3 62.46,101.39 61.82,101.39 61.23,100.81 58.84,100.81 57.16,102.49 57.16,104.28 53.68,107.76 53.68,109.71 54.07,110.11 55.62,110.11 J17.2
USBN_HUB2: length 36.4
  BOTTOM w0.114: 67.63,97.04 67.63,102.42 66.67,103.37 66.24,103.37 UC9.1 65.03,103.18 63.74,103.18 63.24,102.68 61.79,102.68 61.18,103.29 59.9,103.29 U19.6 59.56,103.29 58.79,103.29 58.02,104.07 58.02,111.93 57.4,112.56 56.59,112.56 55.97,111.94 55.97,111.46 56.11,111.33 J17.6 ; 67.63,97.04 v2(67.35,97.04) ; 67.63,97.04 67.63,95.87 67.49,95.73 67.49,93.3 67.19,93 67.19,91.75 66.63,91.2 66.63,91 66.37,90.74 UU3.6
USBP0: length 82.3
  TOP w0.114: v1(112.36,62.67) 112.36,61.76 110.46,59.85 110.46,56.31 109.91,55.76 109.91,51.01 110.2,50.72 111.05,50.72 111.77,51.43 112.07,51.43 112.26,51.62 J133.3
  IN1 w0.114: v1(88.96,74.97) 88.71,75.22 88.42,75.22 88.1,74.89 85.51,74.89 84.22,76.18 83.65,76.18 83.54,76.07 83.54,75.15 83.28,74.89 82.74,74.89 82.48,75.15 82.48,76.07 82.37,76.18 82.03,76.18 81.91,76.07 81.91,75.15 81.66,74.89 81.11,74.89 80.86,75.15 80.86,76.07 80.74,76.18 79.49,76.18 79.27,75.96 79.27,73.02 78.16,71.92 78.16,69.95 77.58,69.37 77.58,65.29 v1(77.1,64.81)
  BOTTOM w0.114: v1(88.96,74.97) 88.78,75.14 88.61,75.14 88.21,74.74 88.21,73.57 88.57,73.2 91.03,73.2 ; 91.03,73.2 91.46,73.2 91.77,73.51 99.33,73.51 100.17,74.35 101.86,74.35 102.7,73.51 104.32,73.51 UC12.1 105.22,73.53 105.34,73.53 105.76,73.94 107.59,73.94 108.2,73.33 109.09,73.33 UU2.6 109.5,73.33 110.1,73.33 110.1,73.33 110.3,73.33 110.83,72.8 110.83,72.6 110.83,68.29 110.44,67.9 110.44,65.17 111.97,63.65 111.97,63.06 v1(112.36,62.67) ; 91.03,73.2 v2(91.03,73.47) ; XU1.M16 76.73,65.13 76.9,65.13 76.96,65.08 77.01,65.08 77.1,64.99 v1(77.1,64.81)
USBP1: length 73
  IN1 w0.114: v1(88.89,73.87) 88.7,74.06 86.03,74.06 86.01,74.04 86.01,72.33 85.76,72.07 85.21,72.07 84.96,72.33 84.96,74.04 84.84,74.16 82.52,74.16 82.14,73.77 82.14,73.44 81.69,73 80.35,73 78.84,71.49 78.84,69.22 78.74,69.12 78.74,67.55 v1(78.01,66.82)
  BOTTOM w0.114: v1(88.89,73.87) 90.1,75.08 90.1,76.56 90.37,76.83 91.01,76.83 91.28,76.56 91.28,74.59 91.41,74.46 91.91,74.46 92,74.56 92,77.64 92.3,77.94 92.92,77.94 93.29,77.57 93.29,74.69 93.51,74.46 99.06,74.46 100.18,75.58 102.2,75.58 ; v1(78.01,66.82) 77.98,66.82 XU1.J14 ; J11.3 112.99,72.6 112.84,72.45 112.2,72.45 111.85,72.79 111.85,73.96 111.6,74.21 111.19,74.21 111.07,74.34 111.07,74.66 111.19,74.78 111.6,74.78 111.85,75.04 111.85,77.27 111.43,77.7 110.53,77.7 110.36,77.87 110.36,79.08 110.09,79.35 108.38,79.35 108.11,79.08 108.11,76.81 108.38,76.54 110.28,76.54 110.41,76.41 110.41,75.61 110.06,75.27 109.45,75.27 UU2.4 109.12,75.26 108.73,75.26 108.13,75.85 105.55,75.85 105.4,76.01 UC14.1 104.35,75.58 102.2,75.58 ; 102.2,75.58 v2(102.2,75.85)
USBP3_HUB: length 80.5
  IN2 w0.114: v1(64.46,91.04) 64.36,91.14 64.36,91.41 64.44,91.5 64.97,91.5 65.63,90.84 67.24,90.84 69.49,93.09 69.81,93.09 69.92,92.98 69.92,92.14 70.18,91.88 70.72,91.88 70.98,92.14 70.98,92.98 71.09,93.09 71.44,93.09 71.55,92.98 71.55,92.14 71.81,91.88 72.35,91.88 72.6,92.14 72.6,92.98 72.72,93.09 75.02,93.09 75.82,92.29 75.82,89.72 77.41,88.14 77.41,85.73 78.39,84.75 78.39,84.11 77.41,83.13 77.41,82.25 78,81.67 78.93,81.67 79.24,81.98 79.24,83.09 79.37,83.22 79.9,83.22 80.33,82.79 80.33,81.05 80.21,80.92 78.95,80.92 78.55,80.53 78.55,79.97 78.85,79.68 79.45,79.68 79.81,79.32 80.21,79.32 80.33,79.2 80.33,78.91 80.22,78.8 79.05,78.8 78.46,79.38 77.76,79.38 77.49,79.12 77.49,78.36 77.76,78.1 78.41,78.1 78.55,77.95 78.55,77.36 78.3,77.11 77.56,77.11 77.18,76.73 77.18,76.31 77.44,76.06 78.96,76.06 79.62,76.72 80.21,76.72 80.33,76.59 80.33,75.71 80.28,75.66 79.67,75.66 79.41,75.39 79.41,74.89 79.28,74.76 77.46,74.76 76.96,74.26 76.96,73.51 77.23,73.24 81.08,73.24 81.7,72.62 81.7,70.09 81.58,69.96 81.01,69.96 80.88,70.09 80.88,71.85 80.41,72.32 78.86,72.32 78.5,71.96 78.5,67.12 78.45,67.07 78.45,65.89 78.87,65.46 79.43,65.46 79.68,65.72 79.85,65.72 79.96,65.61 v1(79.96,65.34)
  BOTTOM w0.114: v1(79.96,65.34) 79.96,65.59 79.81,65.74 XU1.K10 ; UU3.2 64.37,90.52 64.18,90.71 64.18,90.89 64.33,91.04 v1(64.46,91.04)
USBP_HUB1: length 35.7
  BOTTOM w0.114: 65.71,95.21 65.71,97.05 66.97,98.31 66.97,100.69 66.52,101.15 66.18,101.15 UC7.1 64.93,101.18 63.79,101.18 63.34,101.63 61.72,101.63 61.13,101.05 59.9,101.05 U19.4 59.56,101.05 58.94,101.05 57.4,102.59 57.4,104.38 53.92,107.86 53.92,109.61 54.17,109.86 55.52,109.86 56.1,109.29 56.1,108.82 55.99,108.71 J17.3 ; 65.71,95.21 v2(66.01,95.21) ; 65.71,95.21 65.71,94 65.02,93.3 65.02,91.83 65.24,91.6 65.24,90.87 65.37,90.74 UU3.4
USBP_HUB2: length 36.4
  BOTTOM w0.114: v2(68.14,99.04) 67.87,99.04 ; 67.87,99.04 67.87,95.77 67.73,95.63 67.73,93.2 67.43,92.9 67.43,91.65 66.87,91.1 UU3.7 ; 67.87,99.04 67.87,102.52 66.77,103.62 65.99,103.62 UC8.1 64.88,103.42 63.64,103.42 63.14,102.92 62.83,102.92 U19.1 62.43,102.92 61.89,102.92 61.28,103.53 58.89,103.53 58.26,104.17 58.26,112.03 57.5,112.8 56.49,112.8 J17.7
VGA_V1P0_S3: length 7
  BOTTOM w0.254: XU1.BJ6 81.59,45.95 v2(83.96,43.58) 83.96,42.87 C15.1 SL1.1
VGA_V1P35_S3_F1: length 15.9
  BOTTOM w0.305: XU1.BD1 84.25,48.99 85.1,48.99 85.42,48.68
  BOTTOM w0.508: SL13.1 85.31,41.67 86.33,42.68 86.33,43.6 86.69,43.97 87.01,43.97 ; 85.42,48.68 85.67,48.43 85.67,47.37 86.82,46.22 87.26,46.22 87.72,45.75 v2(87.72,45.17) 87.72,45.12 87.01,44.4 87.01,43.97 ; 87.01,43.97 87.68,43.97 88.32,43.33 C64.1 C65.1
VNN_PWRGD: length 7.1
  BOTTOM w0.254: PR183.2 PR184.1 103.64,54.56 103.29,54.21 PQ32.3 103.29,52.64 102.92,52.26 100.27,52.26 ST4.1
VNN_PWRGDG: length 4.2
  BOTTOM w0.197: v2(101.8,56.64) 101.4,57.04 PU9.27
  BOTTOM w0.254: PR184.2 102.19,55.66 101.8,55.66 PR190.1 101.77,56.17 101.8,56.2 v2(101.8,56.64)
VR_SVID_ALERT#: length 45.2
  IN1 w0.127: v1(72.18,79) 71.54,79.64 71.54,80.12 72.05,80.63 72.99,80.63 74.2,79.42 77.91,79.42 78.86,80.37 78.86,80.51 79.56,81.21 85.45,81.21 91.14,75.52 91.14,69.45 95.75,64.84 95.75,62.12 v1(94.96,61.32)
  BOTTOM w0.127: PR200.1 95.31,61.02 95.27,61.02 94.96,61.32 ; 94.96,61.32 94.45,60.82 PR194.2 ; 94.96,61.32 v1(94.96,61.32) ; SR43.2 71.98,78.8 v1(72.18,79) 72.81,79 v2(72.89,78.93)
VR_SVID_ALERT#_R: length 7.1
  BOTTOM w0.102: 72.78,71.48 72.78,71.39 72.76,71.37 XU1.B24
  BOTTOM w0.127: SR43.1 71.98,76.02 v2(72.71,75.29) 73.04,74.96 73.04,72.88 72.78,72.62 72.78,71.48
VR_SVID_CLK: length 55.3
  IN1 w0.127: v1(72.26,81.06) 74.03,81.06 74.39,80.7 77.01,80.7 77.94,81.64 85.63,81.64 91.57,75.7 91.57,69.67 96.18,65.06 96.18,61.92 v1(94.95,60.69)
  BOTTOM w0.102: XU1.C25 72.34,69.57 72.34,69.87 72.55,70.08 72.55,71.48
  BOTTOM w0.127: PR198.1 95.31,60.06 94.95,60.42 v1(94.95,60.69) PR195.2 ; v1(72.26,81.06) 72.56,81.06 v2(72.92,80.7) 72.92,80.25 72.23,79.56 72.13,79.56 71.34,78.78 71.34,75.94 72.59,74.69 72.59,73.67 72.55,73.63 72.55,71.48
VR_SVID_DATA: length 47.8
  IN1 w0.127: v1(72.05,79.99) 73.01,79.99 73.25,79.76 73.25,79.59 73.14,79.49 72.84,79.49 72.76,79.41 72.76,79.08 72.85,78.99 78.09,78.99 79.29,80.19 79.29,80.33 79.74,80.78 84.65,80.78 84.93,80.5 84.93,80.1 84.47,79.64 84.47,79.35 84.74,79.08 84.92,79.08 85.54,79.71 85.72,79.71 85.99,79.44 85.99,79.26 85.37,78.63 85.37,78.45 85.64,78.18 85.82,78.18 86.44,78.81 86.62,78.81 87.84,77.59 88.45,77.59 90.71,75.33 90.71,69.27 95.32,64.66 95.32,62.32 v1(94.95,61.96)
  BOTTOM w0.127: v1(72.05,79.99) 71.44,79.99 v2(70.83,79.38) SR44.2 ; PR193.2 94.65,61.65 v1(94.95,61.96) 95.26,61.65 PR202.1
VR_SVID_DATA_RR: length 8.7
  BOTTOM w0.102: 72.27,71.48 XU1.A25
  BOTTOM w0.127: 72.27,71.48 72.27,72.03 72.15,72.15 72.15,74.51 70.83,75.84 SR44.1 70.38,76.93 70.38,77.43 v2(69.84,77.96)
VREF: length 3.4
  TOP w0.229: v1(7.56,100.3) 8.13,100.86 AU1.41
  BOTTOM w0.508: v2(6.9,100.67) 7.19,100.67 v1(7.56,100.3) 7.56,99.69 AC59.1
VRM_PWRGD: length 139.4
  TOP w0.254: v1(55.42,20.38) 55.5,20.47 58.67,20.47 v1(58.69,20.45) 58.69,22.25 62.27,25.83 v2(62.81,25.83) 64.81,25.83 66.82,23.82 66.82,22.62 67.06,22.37 O2R242.2
  IN1 w0.254: v1(91.74,15.86) 92.91,14.69 97.46,14.69 97.94,15.17 102.29,15.17 104.36,17.24 104.36,18.88 106.62,21.14 108.87,21.14 113.11,25.38 113.11,30.81 107.57,36.34 107.57,38.6 104.75,41.43 104.75,56.46 105,56.71 105,65.21 104.75,65.45 104.75,67.08 v1(105.22,67.55)
  IN2 w0.254: v1(91.74,15.86) 91.58,15.71 84.35,15.71 81.43,12.79 77.33,12.79 77.25,12.87 72.24,12.87 71.8,12.43 70.92,12.43 70.28,13.07 64.16,13.07 60.25,16.98 60.25,18.89 v1(58.69,20.45)
  BOTTOM w0.203: PR189.1 101.8,62.74 PU9.15
  BOTTOM w0.254: PR139.1 55.25,20.21 v1(55.42,20.38) ; PQ43.3 104.36,68.39 104.86,67.89 104.88,67.89 v1(105.22,67.55) 104.96,67.28 PR187.2 104.36,67.28 104.01,66.93 104.01,65.9 103.85,65.74 103.85,64.79 PR189.1
VRM_PWRGD_R: length 4.8
  TOP w0.102: v2(66.51,25.33) 66.51,24.9 67.53,23.89 O2R242.1 67.86,23.54 67.86,23.63 v1(68.14,23.91)
  BOTTOM w0.102: v1(68.14,23.91) 68.52,24.29 U24.69
VRM_VCCP: length 6.2
  TOP w0.102: v2(105.83,60.16) 106.44,60.16 v1(106.55,60.05)
  BOTTOM w0.197: PC123.1 104.46,59.37 104.17,59.66 PU9.22
  BOTTOM w0.254: PR165.2 106.69,60.05 v1(106.55,60.05) 105.64,60.05 PC123.1
VRM_VDD: length 6.9
  BOTTOM w0.197: PC125.1 104.25,60.06 PU9.21
  BOTTOM w0.254: v2(107.37,62.1) PR181.2 106.71,61.43 105.62,61.43 PC125.1
VRP:
  vias: v2(7.73,102.9)
VSUS_ON#: length 80.1
  IN1 w0.102: v1(72.22,8.21) 70.88,9.56 64.38,9.56 63.47,8.65 52.76,8.65 52.19,8.07 48.43,8.07 48.1,8.4 39.2,8.4 35.34,12.26 30.76,12.26 v1(30.6,12.43)
  IN2 w0.102: v1(30.6,12.43) 30.24,12.07 28.06,12.07 22.57,17.56 22.57,18.75 20.87,20.45 20.87,24.75 21.44,25.32 21.44,29.39 21,29.83 21,32.2 20.27,32.93 20.27,35.44 18.31,37.4 17.54,37.4 v1(17.32,37.62)
  BOTTOM w0.102: PR44.1 17.25,37.69 v1(17.32,37.62) ; U24.19 72.12,8.32 v1(72.22,8.21)
WIFI_RF_KILL#_R: length 5.8
  TOP w0.102: J218.56 43.63,7.27 43.6,7.3 WR35.1 WR34.2 42.09,6.87 41.06,6.87 v2(40.73,6.54)
WLAN_PE1_RXN1: length 89
  TOP w0.114: J218.43 51.97,10.52 51.8,10.69 51.3,10.69 49.8,12.19 49.8,20.99 50.04,21.23 50.04,21.54 49.8,21.78 49.8,21.95 v1(49.57,22.18)
  IN1 w0.114: v1(80.71,52.6) 80.37,52.94 80.37,53.25 80.24,53.38 80.24,55.54 80.53,55.83 81.87,55.83 81.9,55.86 82.45,55.86 84.52,53.78 86.49,53.78 88.33,51.93 88.33,40.13 88.54,39.93 88.54,38 87.77,37.23 87.77,35.91 77.4,25.54 66.51,25.54 65.59,26.46 62.17,26.46 60.53,24.82 58.71,24.82 58.71,24.82 57.98,24.82 56.62,23.46 50.43,23.46 49.97,22.99 49.97,22.58 v1(49.57,22.18)
  BOTTOM w0.114: XU1.AT9 80.34,52.97 v1(80.71,52.6)
WLAN_PE1_RXP1: length 89
  TOP w0.114: J218.41 51.97,11.02 51.88,10.93 51.4,10.93 50.04,12.29 50.04,20.89 50.28,21.13 50.28,21.64 50.04,21.88 50.04,21.97 50.14,22.07 50.14,22.09 v1(50.21,22.16)
  IN1 w0.114: v1(80.06,52.63) 80.13,52.7 80.13,53.15 80,53.28 80,55.64 80.43,56.07 81.77,56.07 81.8,56.1 82.55,56.1 84.62,54.02 86.59,54.02 88.57,52.03 88.57,40.23 88.78,40.03 88.78,37.9 88.02,37.13 88.02,35.81 77.5,25.29 66.41,25.29 65.49,26.22 62.27,26.22 60.63,24.58 58.61,24.58 58.08,24.58 56.72,23.22 50.53,23.22 50.21,22.89 v1(50.21,22.16)
  BOTTOM w0.114: v1(80.06,52.63) 79.63,53.07 XU1.AT10
WLAN_PE1_TXN1: length 76
  TOP w0.114: 90.42,47.23 90.42,46.11 v1(90.01,45.7) ; 90.42,47.23 90.42,47.79 87.61,50.59 87.61,51.14 87.1,51.65 86.78,51.65 86.71,51.57 86.71,51.32 86.63,51.24 C6.1 ; 90.42,47.23 v2(90.14,47.23) ; v1(50.77,19.9) 50.77,18.8 51.03,18.53 51.03,12.53 51.43,12.14 51.9,12.14 52.02,12.02 J218.37
  IN1 w0.114: v1(90.01,45.7) 90.09,45.63 90.09,41.34 90.64,40.79 90.64,36.33 77.62,23.31 65.98,23.31 64.93,24.37 62.52,24.37 61.25,23.1 59.53,23.1 58.97,22.54 58.26,22.54 57.45,21.73 54.37,21.73 54.14,21.5 52.57,21.5 51.79,20.72 51,20.72 50.77,20.48 v1(50.77,19.9)
WLAN_PE1_TXP1: length 76.1
  TOP w0.114: v1(90.66,45.69) 90.66,47.89 89.46,49.09 ; v1(51.4,19.9) 51.01,19.5 51.01,18.9 51.27,18.63 51.27,12.63 51.53,12.38 51.91,12.38 52.05,12.52 J218.35 ; v2(89.65,49.29) 89.46,49.09 ; 89.46,49.09 87.85,50.69 87.85,51.24 87.2,51.89 86.75,51.89 86.5,52.13 C7.1
  IN1 w0.114: v1(51.4,19.9) 51.01,20.29 51.01,20.38 51.1,20.48 51.89,20.48 52.67,21.26 54.24,21.26 54.47,21.49 57.55,21.49 58.36,22.3 59.07,22.3 59.63,22.86 61.35,22.86 62.62,24.13 64.83,24.13 65.88,23.07 77.73,23.07 90.88,36.23 90.88,40.89 90.33,41.44 90.33,45.36 v1(90.66,45.69)
WLAN_WAKE#_R: length 4
  TOP w0.102: J218.55 54.52,7.52 54.53,7.51 WR84.2 55.55,7.73 55.55,7.82 55.57,7.83 55.57,7.83 56.1,8.37 v2(56.46,8.37)
WWAN_WLAN_COEX1_R: length 3.5
  TOP w0.102: WT14.1 42.72,9.89 43.71,9.89 43.89,9.71 44.04,9.71 44.48,9.27 J218.48
WWAN_WLAN_COEX2_R: length 6
  TOP w0.102: WT13.1 41.08,10.94 43.79,10.94 44.14,10.6 44.14,9.9 44.27,9.77 J218.46
WWAN_WLAN_COEX3_R: length 5.2
  TOP w0.102: WT12.1 43.88,11.87 44.34,11.41 44.34,10.5 44.57,10.27 J218.44
X1: length 5.7
  BOTTOM w0.102: v2(71.77,91.37) 71.77,90.6 R26.1 70.73,89.55 70.53,89.55 C4.1 69.44,89.21 68.67,88.44 UU3.10
X1_1: length 5.4
  BOTTOM w0.102: v2(52.82,89.49) 52.38,89.94 Y10.1 50.37,90.8 50.37,92.28 LR1.2
XMM1_SA0: length 4.6
  TOP w0.102: SR123.1 42.6,32.53 42.64,32.5 v1(42.73,32.5)
  BOTTOM w0.102: XMM1.197 42.62,32.38 v1(42.73,32.5) 43.03,32.2 v2(43.03,31.72)
XMM1_SA1: length 4.4
  TOP w0.102: SR163.1 39.02,31.56 38.98,31.52 SR124.1 v1(37.81,31.52) v2(37.1,31.52)
  BOTTOM w0.102: XMM1.201 38.15,31.18 v1(37.81,31.52)
XTAL1: length 5.4
  BOTTOM w0.102: LC1.1 52.25,92.94 52.21,92.9 LR1.1 ; LC1.1 52.67,93.79 53.13,94.24 LU1.28 ; LC1.1 53.48,92.12 53.48,91.27 v2(53.71,91.05)
XTAL2: length 7.7
  BOTTOM w0.102: v2(47.24,91.27) 47.5,91.54 Y10.3 49.74,92.25 49.74,92.47 LC2.1 50.6,93.33 51.92,93.33 52.73,94.13 LU1.29
Y5_R: length 3.3
  BOTTOM w0.127: SR64.2 86.97,78.09 86.94,78.12 Y5.2 v2(88.41,79.43)
Y17_1: length 3
  TOP w0.127: v2(92.09,57.67) 91.27,57.67 SR31.2 90.94,56.46 Y12.1
N17661737: length 2
  TOP w0.254: R90.2 61.94,91.88 v2(61.69,91.63)
  TOP w0.457: R90.2 R91.1
N24358231:
  vias: v2(113.5,101.46)
N24358368: length 5.7
  TOP w0.254: PQ3.3 119.79,99.64 120.14,99.99 122.06,99.99 122.55,100.47 122.55,101.89 v2(122.29,102.14)
N27493538: length 3.8
  TOP w0.102: PR78.1 25.58,55.29 v2(25.44,55.43)
  TOP w0.254: PR78.1 PR70.1 PR71.2 PR73.1
N27848589: length 3.2
  BOTTOM w0.102: R3008.2 73.09,27.42 73.09,27.18 v2(72.66,26.76) 72.52,26.61 U24.79
N31476480: length 4.7
  TOP w0.254: v2(102.76,101.23) 103.71,102.18 PJP3.2 102.9,102.55 102.74,102.39 PC6.2 101.48,102.39 101.31,102.55 PR13.2
N31476482: length 5.3
  TOP w0.254: v2(102.43,105.44) 103.42,105.44 103.71,105.15 PJP2.2 102.8,104.58 PC6.1 101.37,103.73 101.21,103.56 PR12.2
N31476922: length 1.8
  TOP w0.254: PQ2.3 v1(114.77,99.25)
  BOTTOM w0.254: v2(115.49,99.25) v1(114.77,99.25)
N31477919: length 7.4
  TOP w0.102: v2(95.86,110.16) 95.45,110.16 94.79,109.5 94.79,108.84 PR23.2 95.69,107.93 95.69,106.61 PC17.2 97,105.3 PU2.4
N31477921: length 3.3
  TOP w0.102: PU2.5 96.5,104.91 PR26.2 95.22,105.37 v2(95.09,105.24)
N31477928: length 5.9
  TOP w0.102: v2(101.74,107.22) 100.91,107.22 99.88,106.2 PR18.2 98.62,106.2 98.62,106.19 PC12.2 98.14,105.3 98,105.17 PU2.2
N31477936: length 9.2
  TOP w0.102: PR19.2 95,95.97 95,96.85 94.4,97.45 94.4,98.98 PR24.1 96.5,101.08 PU2.6 95.9,101.71 95.64,101.96 v2(95.04,101.96)
N31477938: length 5.5
  TOP w0.102: PU2.7 97,100.56 PR25.1 96.22,100.05 95.95,99.78 PR20.2 95.04,97.85 v2(94.94,97.95)
N31477967: length 2.6
  TOP w0.102: PR21.2 v1(97.5,100.75) PU2.8
  BOTTOM w0.102: v2(97.68,99.91) 97.68,100.57 v1(97.5,100.75)
N31484130: length 4.9
  BOTTOM w0.457: v2(56.89,33.61) 57.13,33.37 PR247.2 PR110.2 PC78.1 60.41,33.37 60.44,33.33 PU6.2
N31491325: length 19.3
  TOP w0.508: v1(5.5,15.38) 5.15,15.73 FD4.3 ; v2(3.22,16.75) 4.67,16.75 FD4.3 ; FD4.3 5.55,16.27 5.91,16.62 6.49,16.62 6.61,16.5 FR4.1
  IN1 w0.508: v1(9.31,15.73) 8.79,15.21 5.67,15.21 v1(5.5,15.38)
  BOTTOM w0.508: FD3.2 8.38,22.93 8.76,22.56 8.76,18.96 9.31,18.4 v1(9.31,15.73) ; v1(5.5,15.38) 5.55,15.43 P70.4
N31515196: length 5.3
  BOTTOM w0.102: v2(87.98,36.74) 87.83,36.59 87.83,35.73 87.55,35.45 87.55,34.74 TPR5.1 87.02,33.35 TPU1.7
N31515268: length 5.4
  BOTTOM w0.102: TPR1.2 86.2,33.76 86.37,33.59 TPU1.6 ; TPR1.2 85.77,34.74 85.77,36.15 v2(86.02,36.41) ; TPR1.2 TPR2.1
N31541018: length 9.3
  TOP w0.102: J8.5 37.62,106.81 38.89,105.54 J8.6 38.89,104.27 38.41,103.79 LC16.1 38.04,99.63 37.86,99.81 v2(37.33,99.81)
N31550216: length 7.9
  TOP w0.229: v1(15.37,102.15) 15.29,102.06 AU1.23 ; AU1.25 14.83,103.11 v1(14.93,103.21)
  TOP w0.254: L2.2 18.21,103.11 AC56.1 17.12,102.64 17.11,102.64 AC57.1 16.16,103.21 v1(14.93,103.21)
  BOTTOM w0.254: v1(14.93,103.21) 15.17,103.21 v2(15.54,102.84) 15.54,102.84 15.54,102.31 v1(15.37,102.15)
N31550234: length 6.3
  TOP w0.229: AU1.39 8.1,101.66 8.01,101.66 7.74,101.93 AC49.1 AC48.1 5.32,101.93 5.05,102.2 L1.2 v2(3.9,103.26)
N31550341: length 5.5
  TOP w0.229: AR36.1 12.48,103.75 12.38,103.65 AU1.29 ; AR36.1 AR5.1 ; AR36.1 13.96,105.34 v2(14.65,104.66)
N31550370: length 10.5
  TOP w0.127: AU1.4 10.78,97.1 9.54,95.87 8.81,95.87 8.2,95.26 R5.2 8.68,94.23 8.68,93.3 v2(7.82,92.44) 7.36,91.98 7.36,90.94 6.8,90.38 D1.2
N31552500: length 3.9
  TOP w0.254: AR7.1 HR2.2 ; HR2.2 13.56,106.63 v2(13.56,106) ; HR2.2 HR3.1 R15.2
N31552502: length 15.7
  TOP w0.254: v1(6.88,106.59) v2(6.88,107.37) 7.64,108.14 10.95,108.14 R15.1 ; v1(6.29,97.52) 6.29,97.51 AC2.2
  IN1 w0.254: v1(6.29,97.52) 6.88,98.1 v1(6.88,106.59)
N31552504: length 4.2
  TOP w0.254: v2(14.13,110.5) AR6.1 ; AR6.1 HR1.2 ; AR6.1 R14.2 HR4.1
N31552506: length 17
  TOP w0.254: v1(6.27,98.43) 6.04,98.43 5.52,98.95 AC1.2 ; R14.1 6.8,109.56 v2(6.29,109.05) v1(6.29,108.34)
  IN1 w0.254: v1(6.29,108.34) 6.29,98.46 v1(6.27,98.43)
N31552857: length 25
  TOP w0.102: v1(19.22,104.38) 18.76,104.83 v2(18.76,104.99) 19.25,105.47 AQ3.3 21.76,105.47 21.76,105.48 22.15,105.86 24.71,105.86 AR8.2
  BOTTOM w0.102: AQ1.1 10.06,104.11 10.97,103.21 11.89,103.21 12.58,103.89 12.99,103.89 13.25,103.63 17.14,103.63 17.23,103.72 18.3,103.72 18.67,103.35 AQ2.1 19.14,102.6 19.22,102.68 v1(19.22,104.38)
N31596067: length 9
  TOP w0.127: v2(81.73,18.42) 82.53,18.42 R30.2 82.56,17.46 81.12,17.46 80.36,16.7 80.36,13.52 80.53,13.35 P12.12
N31886144: length 3.9
  BOTTOM w0.102: v2(19.65,71.61) 19.65,70.52 19.87,70.31 Q3.1 21.67,70.31 21.68,70.29 R2.2
N31886219: length 3
  BOTTOM w0.102: Q3.6 17.53,70.31 17.52,70.29 R3.1 16.77,70.96 v2(17.16,71.36)
N31906684: length 3.5
  BOTTOM w0.254: HUBL1.2 62.95,83.78 v2(62.32,84.4) 62.95,85.02 63.62,85.02 63.87,85.28 UU3.21
N31906694: length 3.9
  BOTTOM w0.102: SM_TP1.1 65.27,82.48 65.37,82.58 UU3.18
N31906900: length 2.5
  BOTTOM w0.279: UU3.26 61.82,88.44 v2(61.64,88.63) 61.31,88.96 R13.1
N31906916: length 6.2
  BOTTOM w0.254: R17.1 v2(58.53,87.16) 58.72,87.16 59.2,86.67 60.2,86.67 R20.2 61.87,86.17 62.64,86.94 UU3.23
N31906975: length 10
  BOTTOM w0.102: R25.2 C5.1 71.76,87.56 71.82,87.5 Y24.3 72.65,86.79 73.02,86.42 74.97,86.42 75.99,87.44 75.99,88.6 76.19,88.81 77.41,88.81 v2(77.59,88.63)
N31906994: length 5.3
  BOTTOM w0.102: v2(75.94,89.44) 75.68,89.7 Y24.1 73.48,88.83 71.58,88.83 R26.2
N31907009: length 2.6
  BOTTOM w0.102: R25.1 69.31,88.39 v2(69.24,88.32) 68.87,87.94 UU3.11
N31907112: length 4.6
  TOP w0.102: v1(68.88,87.51) 69.08,87.72 69.08,87.83 69.33,88.07 69.67,88.07 69.73,88.02 v2(70.38,88.02)
  BOTTOM w0.102: UU3.12 68.81,87.44 v1(68.88,87.51) 69.72,86.67 R24.1
N31907116: length 2.9
  BOTTOM w0.102: UU3.13 68.33,86.94 v2(69.23,86.04) 69.49,85.78 R23.1
N32036872: length 4.4
  BOTTOM w0.102: U23.19 10.36,55.05 11.31,54.1 OP1R2.2 11.31,51.91 v2(11.07,51.67)
N32037100: length 3.1
  BOTTOM w0.102: U23.24 7.86,55.2 7.64,54.97 7.21,54.97 v2(6.57,54.34) OP1R3.2
N32037272: length 6.8
  BOTTOM w0.102: v2(62.84,28.5) 63.18,28.5 O2R251.1 64.24,27.44 64.71,27.44 65.02,27.14 65.02,26.4 65.44,25.98 67.18,25.98 67.32,25.84 U24.66
N32037461: length 11.7
  BOTTOM w0.102: U24.73 70.12,25.92 69.98,26.06 69.6,26.06 69.44,26.22 69.44,26.86 68.88,27.42 68.12,27.42 67.76,27.77 65.21,27.77 65.14,27.83 O2R252.1 64.32,28.25 64.32,29.27 65.17,30.13 65.96,30.13 v2(66.44,29.65)
N32381924: length 2.3
  TOP w0.102: v1(78.04,68.88) 78.04,70.34 ST85.1
  BOTTOM w0.102: XU1.D14 77.73,68.56 v1(78.04,68.88)
N32381935: length 2.8
  TOP w0.102: ST86.1 78.62,67.05 v1(79.16,67.6)
  BOTTOM w0.102: XU1.G12 79.04,67.6 v1(79.16,67.6)
N32381953: length 1.7
  TOP w0.102: ST87.1 77.31,67.45 v1(78.07,68.21)
  BOTTOM w0.102: XU1.F14 77.75,67.89 v1(78.07,68.21)
N32381971: length 1.5
  TOP w0.102: v1(79.16,68.26) 78.76,68.67 ST88.1
  BOTTOM w0.102: v1(79.16,68.26) 78.99,68.26 XU1.F12
N32381989: length 2.8
  TOP w0.102: ST89.1 75.28,67.04 v1(76.12,66.21)
  BOTTOM w0.102: XU1.G16 76.12,66.66 v1(76.12,66.21)
N32517551: length 5.7
  TOP w0.102: MR16.2 80.1,96.71 80.36,96.45 MQ37.5 80.36,95.26 80.43,95.18 80.87,95.18 81.63,94.42 81.63,94.04 81.68,93.99 v2(81.68,92.54)
N32517556: length 3.6
  TOP w0.102: v2(80.31,90.94) 80.43,90.94 81.12,91.63 81.12,92.33 MR17.2 80.36,93.09 MQ37.2
N33528355: length 4.5
  TOP w0.102: v1(79.01,95.02) MR18.1 77.94,94.57 78.09,94.43 FD5.1
  BOTTOM w0.102: v2(81.07,94.67) 80.73,95.02 v1(79.01,95.02)
N33528358: length 2.5
  TOP w0.102: MR19.1 76.8,94.57 76.79,94.56 FD5.2 75.97,93.87 v2(75.61,93.51)

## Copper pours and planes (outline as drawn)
+3V_WLAN on TOP (solid shape): 44.47,3.44 46.07,3.44 46.09,3.41 46.09,3.13 46.07,3.11 44.54,3.11 44.52,3.08 44.52,2.96 44.57,2.9 46.07,2.9 46.09,2.88 46.09,2.63 46.07,2.6 44.29,2.6 44.06,2.37 43.7,2.37 43.4,2.07 41.72,2.07 41.62,2.17 41.62,4.3 41.78,4.45 43.45,4.45
+3V_WLAN on TOP (solid shape): 47.08,20.71 47.08,20.08 47.01,20 46.45,20 46.32,20.13 44.59,20.13 44.54,20.18 44.54,20.33 44.62,20.41 46.09,20.41 46.14,20.46 46.14,20.58 46.12,20.61 44.62,20.61 44.57,20.66 44.57,20.86 44.62,20.91 46.47,20.91 46.53,20.96 46.83,20.96
+3V_WLAN on BOTTOM (solid shape): 46.32,3.87 46.32,2.73 46.19,2.6 44.04,2.6 42.65,1.22 38.82,1.22 38.7,1.33 38.7,2.47 38.96,2.73 41.37,2.73 42.77,4.12 46.07,4.12
+3VS_CR on BOTTOM (solid shape): 7.97,64.58 7.97,63.18 8.07,63.08 8.07,62.71 8.07,62.71 8.07,61.95 8.07,61.95 8.07,61.25 7.97,61.15 7.54,61.15 7.38,61.3 7.38,61.67 7.24,61.81 6.8,61.81 6.7,61.91 6.7,62.42 6.44,62.67 5.25,62.67 5.17,62.75 5.17,64.7 5.43,64.96 7.59,64.96
+3VSB_VIN on TOP (solid shape): 20.7,7.06 20.7,4.64 20.26,4.2 18.94,4.2 18.74,4 18.74,2.52 18.59,2.37 17.19,2.37 17.04,2.52 17.04,7 17.54,7.51 20.25,7.51
+3VSB_VIN on BOTTOM (solid shape): 26.13,10.09 26.13,7.93 26,7.81 23.21,7.81 21.33,5.93 15.92,5.93 15.66,6.18 15.66,8.62 15.99,8.95 20.54,8.95 21.81,10.22 26,10.22
+3VSUS on TOP (solid shape): 52.76,100.61 52.76,99.79 52.33,99.36 51.91,99.36 51.52,99.75 50.26,99.75 49.62,99.12 49.62,97.88 49.64,97.86 49.64,96.39 49.66,96.36 49.66,95.55 51.27,93.94 51.27,93.4 51.58,93.1 53.11,93.1 53.54,93.1 53.92,93.48 54.3,93.48 54.37,93.56 54.37,95.62 54.38,95.63 54.41,95.8 54.38,95.96 54.37,95.99 54.55,96.17 55.31,96.17 55.49,96.35 55.92,96.35 56.52,95.75 56.52,95.27 57.27,94.52 57.27,91.12 57.14,90.99 56.48,90.99 56.35,91.12 56.35,92.01 55.66,92.71 54.56,92.71 53.46,91.6 51.78,91.6 48.97,94.42 48.97,96.05 48.84,96.18 48.84,100.36 49.37,100.9 52.47,100.9
+3VSUS on BOTTOM (solid shape): 56.27,96.34 56.64,96.05 57.04,96.3 57.52,96.3 57.68,96.15 57.68,95.72 57.57,95.61 57.22,95.61 56.99,95.39 55.87,95.39 55.51,95.75 54.57,95.75 54.5,95.82 54.5,95.89 54.55,95.94 55.28,95.94 55.71,96.37 56.23,96.37
+5V on TOP (solid shape): 28.54,35.62 28.54,34.5 28.61,34.43 28.71,34.27 28.88,34.16 29.08,33.97 29.08,30.03 27.83,28.79 25.16,28.79 24.99,28.97 24.99,31.76 25.3,32.07 25.73,32.24 25.73,32.69 25.72,32.72 25.91,32.85 26.01,33.05 26.62,33.52 25.85,33.54 25.62,33.65 25.37,33.62 25.37,36.76 25.49,36.89 27.27,36.89
+5V on TOP (solid shape): 10.59,22.34 10.68,22.28 10.68,22.18 10.75,21.65 11.28,21.65 11.35,21.67 11.41,21.65 11.69,21.55 11.96,21.66 11.99,21.68 12.03,21.66 12.46,21.58 12.72,21.94 12.78,22.03 12.89,22.01 14.32,20.58 14.32,19.26 14.17,19.11 10.84,19.11 9.04,20.91 9.01,20.94 8.88,21.07 7.94,21.07 7.82,21.19 7.82,22.31 7.84,22.34
+5V on BOTTOM (solid shape): 27.14,30.03 27.14,28.63 25.62,27.11 23.21,27.11 23.08,27.24 23.08,28.76 23.33,29.02 24.48,29.02 24.86,29.4 24.86,30.03 25.11,30.29 26.89,30.29
+5V on BOTTOM (solid shape): 17.75,24.32 17.75,22.92 17.24,22.41 16.54,22.41 16.36,22.23 16.36,21.02 14.44,19.11 13.95,19.11 13.94,19.12 12.68,19.12 12.24,19.57 11.65,19.57 11.55,19.67 11.55,20.58 11.65,20.68 14.11,20.68 14.37,20.94 14.37,22.18 14.16,22.39 10.89,22.39 10.38,22.89 9.05,22.89 8.45,23.49 7.23,23.49 6.66,22.93 6.66,20.85 6.44,20.63 4.84,20.63 4.69,20.79 4.69,22.21 5.89,23.41 5.91,23.41 6.1,23.52 6.2,23.71 6.21,23.73 6.29,23.81 6.32,23.81 6.44,23.94 6.44,24.19 6.49,24.24 8.55,24.24 9.21,23.58 11.68,23.58 12.13,23.12 12.19,23.12 12.2,23.12 12.34,23.1 12.47,23.12 12.48,23.12 12.83,23.12 12.84,23.12 12.97,23.1 13.11,23.12 13.12,23.12 13.51,23.12 13.81,23.43 14.32,23.43 15.46,24.57 17.49,24.57
+5V_DUAL on TOP (solid shape): 29.63,93.99 29.63,91.88 29.48,91.73 27.37,91.73 27.02,92.08 27.02,93.96 27.53,94.47 29.15,94.47
+5V_DUAL on TOP (solid shape): 39.97,97.37 39.97,95.77 39.62,95.41 37.76,95.41 37.36,95.82 37.36,97.34 37.86,97.85 39.49,97.85
+5V_DUAL on TOP (solid shape): 24.1,51.49 24.1,49.21 23.84,48.95 22.45,48.95 22.32,49.08 22.32,50.22 22.45,50.35 22.45,51.62 22.83,52 23.59,52
+5V_DUAL on BOTTOM (solid shape): 102.23,42.94 102.23,42.66 102.2,42.63 100.83,42.63 100.75,42.55 100.75,42.38 100.8,42.33 102.23,42.33 102.25,42.3 102.25,42.02 102.2,41.97 100.75,41.97 100.42,41.64 99.33,41.64 99.1,41.87 99.1,42.78 99.31,42.99 102.18,42.99
+5V_DUAL on IN1 (solid shape): 24.25,52.21 24.25,50.3 23.59,49.64 22.22,49.64 21.86,50 21.86,52.1 22.19,52.43 24.02,52.43
+5V_DUAL on IN1 (solid shape): 29.11,93.82 29.11,91.1 28.97,90.97 27.21,90.97 27.01,91.16 27.01,93.76 27.37,94.11 28.82,94.11
+5V_DUAL on IN1 (solid shape): 104.11,42.86 104.11,40.95 103.85,40.7 100.68,40.7 99.94,41.44 99.2,41.44 98.95,41.69 98.95,42.66 99.53,43.24 103.73,43.24
+5V_DUAL on IN1 (solid shape): outline of 450 points within 99.89,54.62 104.13,65.08
+5V_DUAL on IN1 (solid shape): outline of 1579 points within 36.47,87.64 74.01,100.49
+5VSB on TOP (solid shape): 28.11,48.37 28.11,44.48 29.2,43.39 31.82,43.39 32.48,42.73 32.48,39.68 31.72,38.92 30.19,38.92 29.49,38.22 23.65,38.22 23.08,38.79 23.08,47.3 24.35,48.57 27.91,48.57
+5VSB_HG_D on TOP (solid shape): 18.46,38.72 18.46,38.24 18.25,38.03 17.16,38.03 16.85,37.72 16.85,37.23 16.76,37.14 16.5,37.14 16.1,37.55 16.1,38.79 18.38,38.79
+5VSB_LG_D on TOP (solid shape): 12.39,47.3 14.95,47.3 15.08,47.18 15.08,46.8 14.95,46.67 11.57,46.67 11.37,46.87 11.37,47.33 11.52,47.48 12.21,47.48
+5VSB_PHASE_D on TOP (solid shape): 20.29,46.54 20.29,39.66 20.16,39.53 18.86,39.53 18.51,39.18 16.22,39.18 16.1,39.3 16.1,40.83 15.33,41.59 15.33,47.18 19.65,47.18
+5VSB_SN_D on TOP (solid shape): 13.94,44 13.94,43.75 14.09,43.6 14.09,41.69 13.89,41.49 13.33,41.49 13.3,41.46 12.67,41.46 12.54,41.59 12.54,43.62 13.05,44.13 13.81,44.13
+5VSB_VIN on TOP (solid shape): 12.08,42.83 12.08,41.16 12.41,40.83 15.59,40.83 15.84,40.57 15.84,38.29 15.6,38.05 12.93,38.05 12.57,38.41 10.94,38.41 9.39,39.96 5.94,39.96 5.71,40.19 5.71,41.26 5.83,41.39 7.43,41.39 8.32,42.27 9.01,42.27 9.7,42.96 11.96,42.96
+5VSB_VIN on BOTTOM (solid shape): 13.4,42.78 13.4,42.02 13.23,41.84 9.92,41.84 9.62,42.15 9.62,42.73 9.87,42.99 13.2,42.99
+19V_DCIN on TOP (solid shape): 104.34,114.15 104.34,111.69 104.59,111.44 107.71,111.44 108.04,111.11 108.04,109.66 107.85,109.47 107.07,109.47 106.88,109.28 106.88,108.34 106.63,108.1 99.52,108.1 99.28,108.34 99.28,110.14 99.81,110.68 101.82,110.68 101.97,110.83 101.97,114.8 102.24,115.07 103.41,115.07
+19VA on TOP (solid shape): 110.89,102.8 110.89,100.29 111.35,99.83 111.35,97.52 111.19,97.37 110.76,97.37 110.3,97.82 110.3,99.53 108.91,100.92 105.48,100.92 104.49,101.91 104.49,102.85 104.67,103.03 110.66,103.03
+19VA_IN on TOP (solid shape): 109.39,111.08 109.39,106.77 109.19,106.56 108.6,106.56 108.12,106.08 108.12,104.1 107.94,103.92 104.74,103.92 104.46,104.2 104.46,105.06 103.95,105.57 103.95,107.37 104.08,107.5 108.3,107.5 108.58,107.78 108.58,109.99 108.37,110.19 108.37,111.11 108.4,111.13 109.34,111.13
+19VA_IN on BOTTOM (solid shape): 104.97,105.67 104.97,99.93 104.77,99.73 103.12,99.73 102.91,99.93 102.91,105.62 103.09,105.8 104.84,105.8
+19VA_SN_A on TOP (solid shape): 110.63,110.91 110.63,107.83 110.86,107.6 112.16,107.6 112.41,107.35 112.41,106.69 112.34,106.61 110.03,106.61 109.72,106.92 109.72,111.11 109.8,111.18 110.36,111.18
+19VSB on TOP (solid shape): 3.45,52.41 3.45,50.17 2.81,49.54 2.25,49.54 2.22,49.58 2.22,52.45 2.3,52.54 3.32,52.54
+19VSB on TOP (solid shape): 5.2,86.32 5.2,84.97 5.15,84.92 3.14,84.92 3.04,85.02 3.04,86.52 3.22,86.7 4.82,86.7
+19VSB on TOP (solid shape): 16.26,4.05 16.26,2.31 16.05,2.09 12.95,2.09 12.59,2.45 12.59,3.97 12.87,4.25 16.06,4.25
+19VSB on TOP (solid shape): 120.42,105.98 120.79,105.98 121,105.77 121,102.47 120.82,102.29 113.23,102.29 111.94,103.58 108.92,103.58 108.68,103.82 108.68,105.67 109,105.99 120.41,105.99
+19VSB on TOP (solid shape): 4.41,46.47 4.41,45.04 5.89,43.57 6.88,43.57 7.16,43.29 7.16,41.94 7.1,41.89 4.87,41.89 3.09,43.67 2.48,43.67 2.35,43.8 2.35,46.64 2.53,46.82 4.06,46.82
+19VSB on TOP (solid shape): 3.55,79.56 3.55,76.05 2.66,75.16 3.55,74.27 3.9,74.27 3.9,72.75 3.47,72.32 2.33,72.32 2.22,72.44 2.22,75.92 2.22,79.5 2.35,79.64 3.47,79.64
+19VSB on BOTTOM (solid shape): 5.68,86.7 5.68,82.74 5.55,82.61 4.54,82.61 4.28,82.86 4.28,84.01 3.12,85.18 3.12,86.6 3.27,86.75 5.63,86.75
+19VSB on BOTTOM (solid shape): 119.98,36.13 119.98,32.7 119.22,31.94 116.1,31.94 115.41,32.62 115.41,36.51 115.54,36.64 119.47,36.64
+19VSB on BOTTOM (solid shape): 120.2,98.24 121.07,98.24 121.52,97.8 121.52,95.33 121.16,94.97 117.72,94.97 117.34,95.35 117.34,97.6 117.35,97.61 117.35,97.89 118.17,98.71 119.74,98.71
+19VSB on BOTTOM (solid shape): outline of 180 points within 66.54,1.22 77.56,4.65
+19VSB on IN1 (solid shape): 119.98,36.25 119.98,31.3 119.6,30.92 118.2,30.92 117.7,31.43 117.7,36.25 118.08,36.64 119.6,36.64
+19VSB on IN1 (solid shape): 16.4,4.38 16.4,2.73 16.05,2.37 12.64,2.37 12.46,2.55 12.46,3.9 13.1,4.53 16.25,4.53
+19VSB on IN1 (solid shape): 121.2,101.58 120.95,101.33 120.06,101.33 118.84,102.55 118.84,103.82 119.22,104.2 121.2,104.2
+19VSB on IN1 (solid shape): 120.23,98.34 122.17,98.34 122.4,98.11 122.4,95.44 122.14,95.19 118.71,95.19 118.21,95.7 118.21,98.49 118.46,98.75 119.82,98.75
+19VSB on IN1 (solid shape): 3.19,51.49 3.19,49.67 2.68,48.68 3.55,47.97 4.51,47.97 4.51,43.82 4.36,43.67 2.71,43.67 2.22,44.17 2.22,51.64 2.33,51.75 2.94,51.75
+19VSB on IN1 (solid shape): 3.5,77.83 3.5,76.05 2.66,75.16 3.5,74.27 3.5,72.7 3.32,72.53 2.45,72.53 2.22,72.75 2.22,77.85 2.47,78.1 3.23,78.1
+19VSB on IN1 (solid shape): outline of 219 points within 66.54,1.22 79.14,4.65
+19VSB on IN2 (solid shape): 119.98,36.25 119.98,31.3 119.6,30.92 118.2,30.92 117.7,31.43 117.7,36.25 118.08,36.64 119.6,36.64
+19VSB on IN2 (solid shape): 121.2,101.2 120.9,100.9 120.49,100.9 118.84,102.55 118.84,103.82 119.22,104.2 121.2,104.2
+19VSB on IN2 (solid shape): 16.4,4.38 16.4,2.73 16.05,2.37 12.74,2.37 12.57,2.55 12.57,3.9 13.2,4.53 16.25,4.53
+19VSB on IN2 (solid shape): 120.23,98.34 122.17,98.34 122.4,98.11 122.4,95.44 122.14,95.19 118.71,95.19 118.21,95.7 118.21,98.49 118.46,98.75 119.82,98.75
+19VSB on IN2 (solid shape): 3.19,51.49 3.19,49.67 2.68,48.68 3.55,47.97 4.51,47.97 4.51,43.82 4.36,43.67 2.71,43.67 2.22,44.17 2.22,51.64 2.33,51.75 2.94,51.75
+19VSB on IN2 (solid shape): 3.5,77.83 3.5,76.05 2.66,75.16 3.5,74.27 3.5,73.14 2.89,72.53 2.45,72.53 2.22,72.75 2.22,77.85 2.47,78.1 3.23,78.1
+19VSB on IN2 (solid shape): outline of 219 points within 66.54,1.22 79.14,4.65
+AV12 on BOTTOM (solid shape): 5.61,61.63 5.61,60.89 5.46,60.34 6.01,60.18 7.38,60.18 7.99,59.57 7.99,59.11 7.92,59.04 7.79,59.04 7.74,59.09 7.74,59.27 7.54,59.47 5.89,59.47 5.71,59.65 5.28,59.65 5.1,59.83 4.62,59.83 4.56,59.88 4.56,61.65 4.69,61.78 5.45,61.78
+VCC_USB3 on TOP (solid shape): outline of 182 points within 103.22,39.81 114.72,49.08
+VCC_USB3 on BOTTOM (solid shape): outline of 150 points within 105.48,41.11 115.28,48.83
+VCC_USB12 on TOP (solid shape): outline of 306 points within 57.88,96.58 71.44,112.58
AGND on TOP (solid shape): 5.66,101.33 7.21,101.33 7.33,101.2 7.33,100.87 6.77,100.31 5.73,100.31 5.5,100.08 5.11,100.08 4.97,100.22 4.97,101.43 5.12,101.58 5.4,101.58
AGND on BOTTOM (solid shape): 6.49,102.75 6.49,101.2 6.24,100.95 6.24,99.09 6.11,98.97 5.15,98.97 4.97,99.15 4.97,101.61 4.69,101.89 3.98,101.89 3.73,102.14 3.73,103.36 3.95,103.59 5.66,103.59
AGND on VCC (solid shape): outline of 237 points within 3.52,96.66 28.29,120.71
AGND on IN2 (solid shape): outline of 1961 points within 3.52,96.67 28.31,120.63
AGND on GND (solid shape): outline of 237 points within 3.52,96.66 28.29,120.71
DV12_S on BOTTOM (solid shape): 11.09,62.04 11.09,60.72 10.14,59.77 10,59.62 10,59.06 9.95,59.01 9.8,59.01 9.72,59.09 9.72,59.62 9.72,60.57 9.82,60.67 9.82,61.04 9.54,61.31 9.1,61.31 9.09,61.32 9.09,61.78 9.21,61.91 9.7,61.91 9.95,62.16 10.97,62.16
DV33_18 on BOTTOM (solid shape): 11.82,58.33 12.17,58.18 12.52,58.33 12.61,58.33 12.68,58.26 12.68,58.15 12.76,58.07 13.4,58.07 13.48,58 13.48,57.36 13.35,57.24 12.91,57.24 12.52,57.63 11.86,57.63 11.82,57.59 10.74,57.59 10.66,57.67 10.66,57.77 10.74,57.84 11.34,57.84 11.42,57.92 11.42,58.1 11.65,58.33
GND on TOP (solid shape): 2.01,72.1 2.01,72.1 2.01,50.45 2.01,50.45 2.01,49.52 1.51,49.52 1.51,74.3 2.01,74.3
GND on TOP (solid shape): 15.44,7.15 15.44,4.68 15.26,4.5 14.44,4.5 14.32,4.63 14.32,6.64 14.98,7.3 15.28,7.3
GND on TOP (solid shape): 27.32,37.86 27.32,37.19 27.27,37.14 25.11,37.14 24.86,37.4 24.86,37.78 24.99,37.91 27.27,37.91
GND on TOP (solid shape): 30.5,88.78 30.5,86.67 30.45,86.62 29.99,86.62 29.89,86.72 29.89,88.76 29.96,88.83 30.45,88.83
GND on TOP (solid shape): 31.08,69.15 31.08,68.39 30.83,68.13 29.43,68.13 29.3,68.26 29.3,69.27 29.43,69.4 30.83,69.4
GND on TOP (solid shape): 31.34,63.69 31.34,61.15 31.21,61.02 29.94,61.02 29.56,61.4 29.56,63.56 29.81,63.81 31.21,63.81
GND on TOP (solid shape): 31.34,60 31.34,57.34 31.08,57.08 29.56,57.08 29.43,57.21 29.43,59.37 30.19,60.13 31.21,60.13
GND on TOP (solid shape): 31.46,67.12 31.46,64.96 31.34,64.83 29.56,64.83 29.43,64.96 29.43,67.12 29.56,67.24 31.34,67.24
GND on TOP (solid shape): 32.43,29.65 32.43,28.86 32.3,28.74 30.7,28.74 30.45,28.99 30.45,29.68 30.6,29.83 32.25,29.83
GND on TOP (solid shape): 37.79,29.68 37.79,29.09 37.43,28.74 36.7,28.74 36.37,29.07 36.37,29.68 36.49,29.8 37.66,29.8
GND on TOP (solid shape): 44.41,5.53 44.41,4.93 44.17,4.69 42.56,4.69 42.41,4.84 42.41,5.61 42.52,5.72 44.22,5.72
GND on TOP (solid shape): 63.97,48.07 63.97,45.02 63.85,44.89 63.34,44.89 63.21,45.02 63.21,48.07 63.34,48.19 63.85,48.19
GND on TOP (solid shape): 67.02,46.29 67.02,45.02 66.9,44.89 65.24,44.89 65.12,45.02 65.12,46.16 65.37,46.41 66.9,46.41
GND on TOP (solid shape): 69.13,96.02 69.13,95.16 68.98,95.01 67.81,95.01 67.56,95.26 67.56,96.02 67.66,96.12 69.03,96.12
GND on TOP (solid shape): 71.49,46.85 71.49,43.32 71.09,42.92 70.16,42.92 70.05,43.04 70.05,47.3 70.2,47.46 70.88,47.46
GND on TOP (solid shape): 85.44,70.6 85.44,69.3 85.22,69.09 83.29,69.09 82.9,69.48 82.9,71.59 83,71.69 84.35,71.69
GND on TOP (solid shape): 97.12,89.09 97.12,86.8 96.61,86.29 83.18,86.29 82.72,86.75 82.72,89.04 83.41,89.72 96.49,89.72
GND on TOP (solid shape): 98.77,42.38 98.77,41.11 98.52,40.85 91.56,40.85 91.41,41 91.41,41.61 93.26,43.47 97.68,43.47
GND on TOP (solid shape): 59.28,97.47 59.28,95.97 59.2,95.89 58.06,95.89 58.01,95.94 58.01,97.34 58.26,97.6 59.15,97.6
GND on TOP (solid shape): 22.83,48.57 22.83,47.18 22.7,47.05 21.33,47.05 21.13,47.25 21.13,48.14 21.68,48.7 22.7,48.7
GND on TOP (solid shape): 57.45,103.97 57.45,101.28 57.32,101.15 56.18,101.15 55.92,101.41 55.92,103.92 56.08,104.07 57.35,104.07
GND on TOP (solid shape): 103.68,107.32 103.68,106.26 103.37,105.95 102.51,105.95 102.28,106.18 102.28,107.25 102.43,107.4 103.6,107.4
GND on TOP (solid shape): 122.01,101.66 122.01,100.58 121.71,100.28 120.37,100.28 120.27,100.38 118.47,100.38 118.08,100.77 118.08,101.79 118.2,101.91 121.76,101.91
GND on TOP (solid shape): 66.92,97.42 66.92,95.59 66.77,95.44 63.49,95.44 63.35,95.58 60.25,95.58 60.01,95.82 60.01,97.47 60.37,97.82 66.51,97.82
GND on TOP (solid shape): 72.46,37.19 72.46,34.48 72.33,34.35 69.49,34.35 69.23,34.6 69.23,35.49 71.04,37.3 72.36,37.3
GND on TOP (solid shape): 112.59,18.73 112.59,17.71 111.9,17.03 111.09,17.03 110.93,17.19 110.93,18.13 110.94,18.14 110.94,18.63 111.12,18.81 112.51,18.81
GND on TOP (solid shape): 42.36,67.19 42.36,59.55 40.61,57.79 40.18,57.79 40.05,57.92 40.05,65.74 40.28,65.97 40.28,67.34 40.43,67.5 40.99,67.5 41.01,67.52 42.03,67.52
GND on TOP (solid shape): 61.05,48.83 61.05,48.45 60.55,47.94 60.55,45.78 60.42,45.65 60.04,45.65 59.91,45.78 59.91,48.7 60.16,48.95 60.93,48.95
GND on TOP (solid shape): 108.3,109.13 108.3,108.06 108.25,108.01 107.51,108.01 107.41,108.11 107.41,108.77 107.21,108.98 107.21,109.13 107.31,109.23 108.2,109.23
GND on TOP (solid shape): 32.35,49.21 32.35,44.51 31.84,44 29.15,44 28.57,44.59 28.57,48.29 28.03,48.83 26.76,48.83 26.51,49.08 26.51,49.97 26.76,50.22 31.34,50.22
GND on TOP (solid shape): 48.63,97.39 48.63,96.1 48.76,95.97 48.76,94.27 50.13,92.9 50.13,91.75 49.88,91.5 48.48,91.5 48.02,91.96 48.02,94.79 46.83,95.99 46.83,98.21 46.93,98.31 47.72,98.31
GND on TOP (solid shape): 69.82,73.62 70.21,73.23 70.21,67.96 70.58,67.6 70.58,67.29 70.52,67.23 70.11,67.23 69.19,68.14 69.19,70.7 69.07,70.82 69.07,71.61 68.29,72.39 68.29,77.34 68.29,77.4 68.93,78.04 69.82,78.04
GND on TOP (solid shape): 85.06,60.57 85.06,59.37 84.55,58.86 78.4,58.86 78.29,58.97 78.29,59.63 78,59.93 75.58,59.93 75.56,59.9 75.3,59.9 75.2,60 75.2,60.26 75.28,60.34 76.97,60.34 77.56,60.93 79.43,60.93 79.77,61.27 84.36,61.27
GND on TOP (solid shape): 75.06,56.1 75.18,55.9 75.37,55.79 75.73,55.43 75.73,55.26 75.48,55.02 74.57,55.02 73.66,54.1 73.2,54.1 73.12,54.19 73.12,54.47 74.45,55.81 74.45,56.13 74.63,56.3 74.85,56.3
GND on TOP (solid shape): 54.75,97.16 55.21,97.16 55.39,96.99 55.39,96.68 55.21,96.5 54.32,96.5 54.07,96.25 54.07,94.04 53.43,93.4 52.93,93.4 52.8,93.53 52.8,94.29 53.18,94.67 53.18,95.44 53.05,95.56 51.91,95.56 51.66,95.82 51.66,96.2 51.4,96.45 51.02,96.45 50.94,96.53 50.94,97.93 51,97.98 53.94,97.98
GND on TOP (solid shape): 21.16,81.33 21.13,81.29 21.13,78.91 20.9,78.55 21.13,78.18 21.13,77.86 20.92,77.66 17.49,77.66 17.24,77.91 17.24,80.96 17.75,81.47 21.02,81.47
GND on TOP (solid shape): 69.61,58.53 69.61,58.33 69.08,57.79 69.08,57.18 68.94,57.05 68.94,56.28 68.87,56.21 68.87,55.23 68.86,55.22 68.86,55.15 68.75,55.05 68.31,55.05 68.19,54.92 68.19,54.29 68.17,54.26 67.81,54.26 67.74,54.33 67.74,56.77 68.08,57.11 68.19,57.11 68.39,57.31 68.39,57.7 68.52,57.84 68.52,58.53 68.75,58.76 69.39,58.76
GND on TOP (solid shape): 14.7,90.92 14.7,89.49 14.67,89.47 14.22,89.47 13.94,89.19 13.94,88.2 14.32,87.82 14.57,87.82 14.7,87.69 14.7,86.42 14.57,86.29 13.94,86.29 13.43,86.8 12.29,86.8 11.52,86.04 7.97,86.04 7.71,86.29 7.71,88.96 8.73,89.98 11.68,89.98 11.8,90.1 11.8,90.92 11.9,91.02 14.6,91.02
GND on TOP (solid shape): 112.54,109.78 113.5,109.52 114.5,109.43 115.13,109.46 115.74,109.57 115.83,109.55 115.87,109.47 115.87,107.55 115.23,106.92 113.61,106.92 112.59,107.93 111.47,107.93 111.09,108.31 111.09,109.64 111.24,109.79 112.53,109.79
GND on TOP (solid shape): 72.11,53.84 72.08,53.68 72.11,53.52 72.12,53.45 72.07,53.39 72.01,53.36 71.4,53.36 71.21,53.17 71.21,52.38 71.34,52.26 72.03,52.26 72.2,52.43 72.41,52.43 72.59,52.26 72.59,52.08 72.31,51.8 71.49,51.8 71.29,51.6 71.29,51.14 71.19,51.04 70.84,51.04 70.58,51.3 70.1,51.3 70.08,51.32 70.08,53.03 70.61,53.56 70.61,53.75 70.78,53.93 72.02,53.93
GND on TOP (solid shape): 69.5,53.86 69.5,53.62 69.39,53.51 69.3,53.38 69.27,53.22 69.27,52.99 69.24,52.96 69.24,51.62 69.27,51.59 69.27,50 69.2,49.83 69.2,49.65 68.73,49.18 68.27,49.18 68.13,49.32 68.13,50.14 68.27,50.29 68.57,50.29 68.57,51.1 68.26,51.1 68.17,51.2 68.17,51.5 68.23,51.55 68.53,51.55 68.71,51.74 68.71,53.22 68.72,53.24 68.81,53.41 68.81,53.61 68.81,53.85 69.03,54.07 69.29,54.07
GND on TOP (solid shape): 62.7,71.31 62.77,71.31 62.88,71.21 63.07,71.21 63.45,71.02 63.8,71.27 63.81,71.31 64.93,71.31 64.95,71.28 65.12,71.08 65.38,71.04 65.46,71.01 65.5,70.94 65.5,70.67 65.37,70.54 61.69,70.54 61.43,70.8 61.43,71.05 61.18,71.31 60.29,71.31 60.04,71.05 58.89,71.05 58.51,71.43 58.51,71.81 58.77,72.07 61.94,72.07
GND on TOP (solid shape): 107.54,47.43 107.54,45.27 105.76,43.49 103.47,43.49 102.96,44 102.96,47.56 103.4,47.99 104.97,47.99 105.3,47.66 105.3,46.05 105.57,45.78 105.56,45.76 106.25,45.39 105.88,46.08 105.86,46.07 105.71,46.22 105.71,47.89 105.91,48.09 106.88,48.09
GND on TOP (solid shape): 15.08,46.29 15.08,43.87 14.95,43.75 14.44,43.75 14.32,43.87 14.32,44.26 14.06,44.51 13.05,44.51 11.73,43.19 7.76,43.19 7.59,43.37 7.59,43.7 7.35,43.94 6.38,43.94 6.19,44.13 6.19,45.37 8.55,45.37 8.55,45.32 8.57,45.26 8.59,45.21 8.61,45.16 8.65,45.11 8.69,45.07 8.73,45.04 8.78,45.01 8.83,44.99 8.89,44.97 8.94,44.97 9,44.97 9.06,44.98 9.11,45 9.16,45.02 9.21,45.05 9.25,45.09 9.29,45.13 9.32,45.18 9.34,45.23 9.36,45.29 9.37,45.35 9.37,45.4 9.36,45.46 9.34,45.51 9.32,45.56 9.29,45.61 9.25,45.66 9.21,45.69 9.16,45.73 9.11,45.75 9.06,45.77 9,45.78 8.94,45.78 8.89,45.78 8.83,45.76 8.78,45.74 8.73,45.71 8.69,45.68 8.65,45.64 8.61,45.59 8.59,45.54 8.57,45.49 8.55,45.43 8.55,45.37 6.19,45.37 6.19,45.75 6.85,46.41 14.95,46.41
GND on TOP (solid shape): 58.64,44.13 58.64,41.72 58.89,41.46 62.2,41.46 62.43,41.69 62.43,44.1 62.45,44.13 63.09,44.13 63.92,43.29 63.92,39.25 63.72,39.05 62.96,39.05 62.7,39.3 62.7,40.19 62.45,40.45 58.89,40.45 58.64,40.19 58.64,39.68 57.88,38.92 55.97,38.92 55.59,39.3 55.59,41.15 55.72,41.15 55.72,41.09 55.73,41.03 55.75,40.98 55.77,40.93 55.81,40.88 55.84,40.84 55.89,40.8 55.93,40.77 55.99,40.75 56.04,40.73 56.1,40.73 56.15,40.73 56.21,40.73 56.27,40.75 56.32,40.77 56.37,40.8 56.41,40.84 56.45,40.88 56.48,40.93 56.5,40.98 56.52,41.03 56.53,41.09 56.53,41.15 56.53,41.2 56.51,41.26 56.49,41.31 56.46,41.36 56.43,41.4 56.39,41.44 56.34,41.48 56.29,41.5 56.24,41.52 56.18,41.54 56.13,41.54 56.07,41.54 56.01,41.52 55.96,41.5 55.91,41.48 55.86,41.44 55.82,41.4 55.79,41.36 55.76,41.31 55.74,41.26 55.72,41.2 55.72,41.15 55.59,41.15 55.59,42.22 57.62,44.26 58.51,44.26
GND on TOP (solid shape): outline of 248 points within 5.5,4.95 13.5,12.95
GND on TOP (solid shape): outline of 248 points within 5.5,110.95 13.5,118.95
GND on TOP (solid shape): outline of 248 points within 110.5,110.95 118.5,118.95
GND on TOP (solid shape): outline of 248 points within 110.5,4.95 118.5,12.95
GND on TOP (solid shape): outline of 246 points within 103.47,26.2 119.65,42.45
GND on TOP (solid shape): outline of 5955 points within 0.51,0.51 123.49,121.99
GND on BOTTOM (solid shape): 14.17,21.98 14.17,21.45 13.78,21.07 11.24,21.07 10.76,21.55 10.76,22.13 10.81,22.18 13.96,22.18
GND on BOTTOM (solid shape): 47.46,5.52 47.46,4.76 47.21,4.5 44.04,4.5 43.78,4.76 43.78,5.52 43.91,5.65 47.34,5.65
GND on BOTTOM (solid shape): 64.1,43.11 64.1,38.16 63.85,37.91 62.58,37.91 62.45,38.03 62.45,43.24 62.58,43.37 63.85,43.37
GND on BOTTOM (solid shape): 72.52,37.1 72.52,34.96 72.49,34.93 72.02,34.93 71.98,34.96 71.98,37.14 72.1,37.27 72.36,37.27
GND on BOTTOM (solid shape): 78.71,32.7 78.71,31.43 78.45,31.17 72.61,31.17 72.48,31.3 72.48,32.7 72.61,32.83 78.58,32.83
GND on BOTTOM (solid shape): 78.96,38.03 78.96,37.27 78.83,37.14 77.56,37.14 77.06,37.65 77.06,39.43 77.18,39.56 77.44,39.56
GND on BOTTOM (solid shape): 13.68,46.14 13.68,45.06 13.28,44.65 9.77,44.65 9.48,44.94 9.48,46.3 9.67,46.49 13.33,46.49
GND on BOTTOM (solid shape): 92.83,89.47 92.83,86.6 92.52,86.29 83.18,86.29 82.72,86.75 82.72,89.04 83.41,89.72 92.58,89.72
GND on BOTTOM (solid shape): 111.97,19.76 111.97,17.47 111.98,17.46 111.98,17.13 110.96,17.13 110.96,19.87 111.24,20.15 111.57,20.15
GND on BOTTOM (solid shape): 8.7,35.04 8.7,34.35 9.01,34.05 9.01,31.48 8.76,31.23 7.76,31.23 7.46,31.53 7.46,35.16 7.61,35.32 8.43,35.32
GND on BOTTOM (solid shape): 11.93,72.45 11.93,71.56 11.73,71.36 10.28,71.36 10.13,71.51 10.13,71.71 10.61,72.2 10.61,72.48 10.74,72.6 11.78,72.6
GND on BOTTOM (solid shape): 46.32,2.09 46.32,1.33 46.25,1.25 43.5,1.25 43.43,1.33 43.43,1.58 44.11,2.27 46.14,2.27
GND on BOTTOM (solid shape): 107.07,22.35 107.07,21.99 106.62,21.55 103.45,21.55 103.4,21.6 103.4,22.16 103.88,22.64 106.77,22.64
GND on BOTTOM (solid shape): 98.06,42.94 98.06,40.55 97.81,40.29 90.8,40.29 90.57,40.52 90.57,42.78 90.73,42.94 93.07,42.94 93.29,43.16 97.83,43.16
GND on BOTTOM (solid shape): 12.29,89.47 12.29,86.29 12.03,86.04 6.32,86.04 6.19,86.17 6.19,87.44 8.6,89.85 11.9,89.85
GND on BOTTOM (solid shape): 35.65,23.17 35.65,22.16 35.53,22.03 32.86,22.03 32.61,22.28 32.61,22.54 32.1,23.05 30.83,23.05 30.7,23.17 30.7,23.43 30.83,23.55 35.27,23.55
GND on BOTTOM (solid shape): 70.93,37.25 70.93,34.91 70.81,34.78 69.89,34.78 69.75,34.92 69.75,37.16 69.89,37.3 70.88,37.3
GND on BOTTOM (solid shape): 18.89,75.37 18.89,72.58 18.64,72.32 16.1,72.32 15.84,72.58 15.84,75.5 15.97,75.62 18.64,75.62
GND on BOTTOM (solid shape): 110.71,41.59 110.71,40.32 110.38,39.99 107.61,39.99 107.31,40.29 107.31,40.88 107.38,40.95 108.93,40.95 109.69,41.72 110.58,41.72
